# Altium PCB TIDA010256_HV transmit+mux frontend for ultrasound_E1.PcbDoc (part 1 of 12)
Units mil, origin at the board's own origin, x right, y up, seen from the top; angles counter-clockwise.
Board outline 6192.49 x 6712.23 mil, 16 copper layers (Top Layer, Layer 2 - GND, Layer 3 - SIG, Layer 4 - GND, Layer 5 - SIG, Layer 6 - SIG, Layer 7 - GND, Layer 8 - HV PWR, Layer 9 - LV PWR, Layer 10 - GND, Layer 11 - SIG, Layer 12 - SIG, Layer 13 - GND, Layer 14 - SIG, Layer 15 - GND, Bottom Layer), stack 95.905 mil thick; 806 components, 539 nets, 3343 pads, 1848 vias.

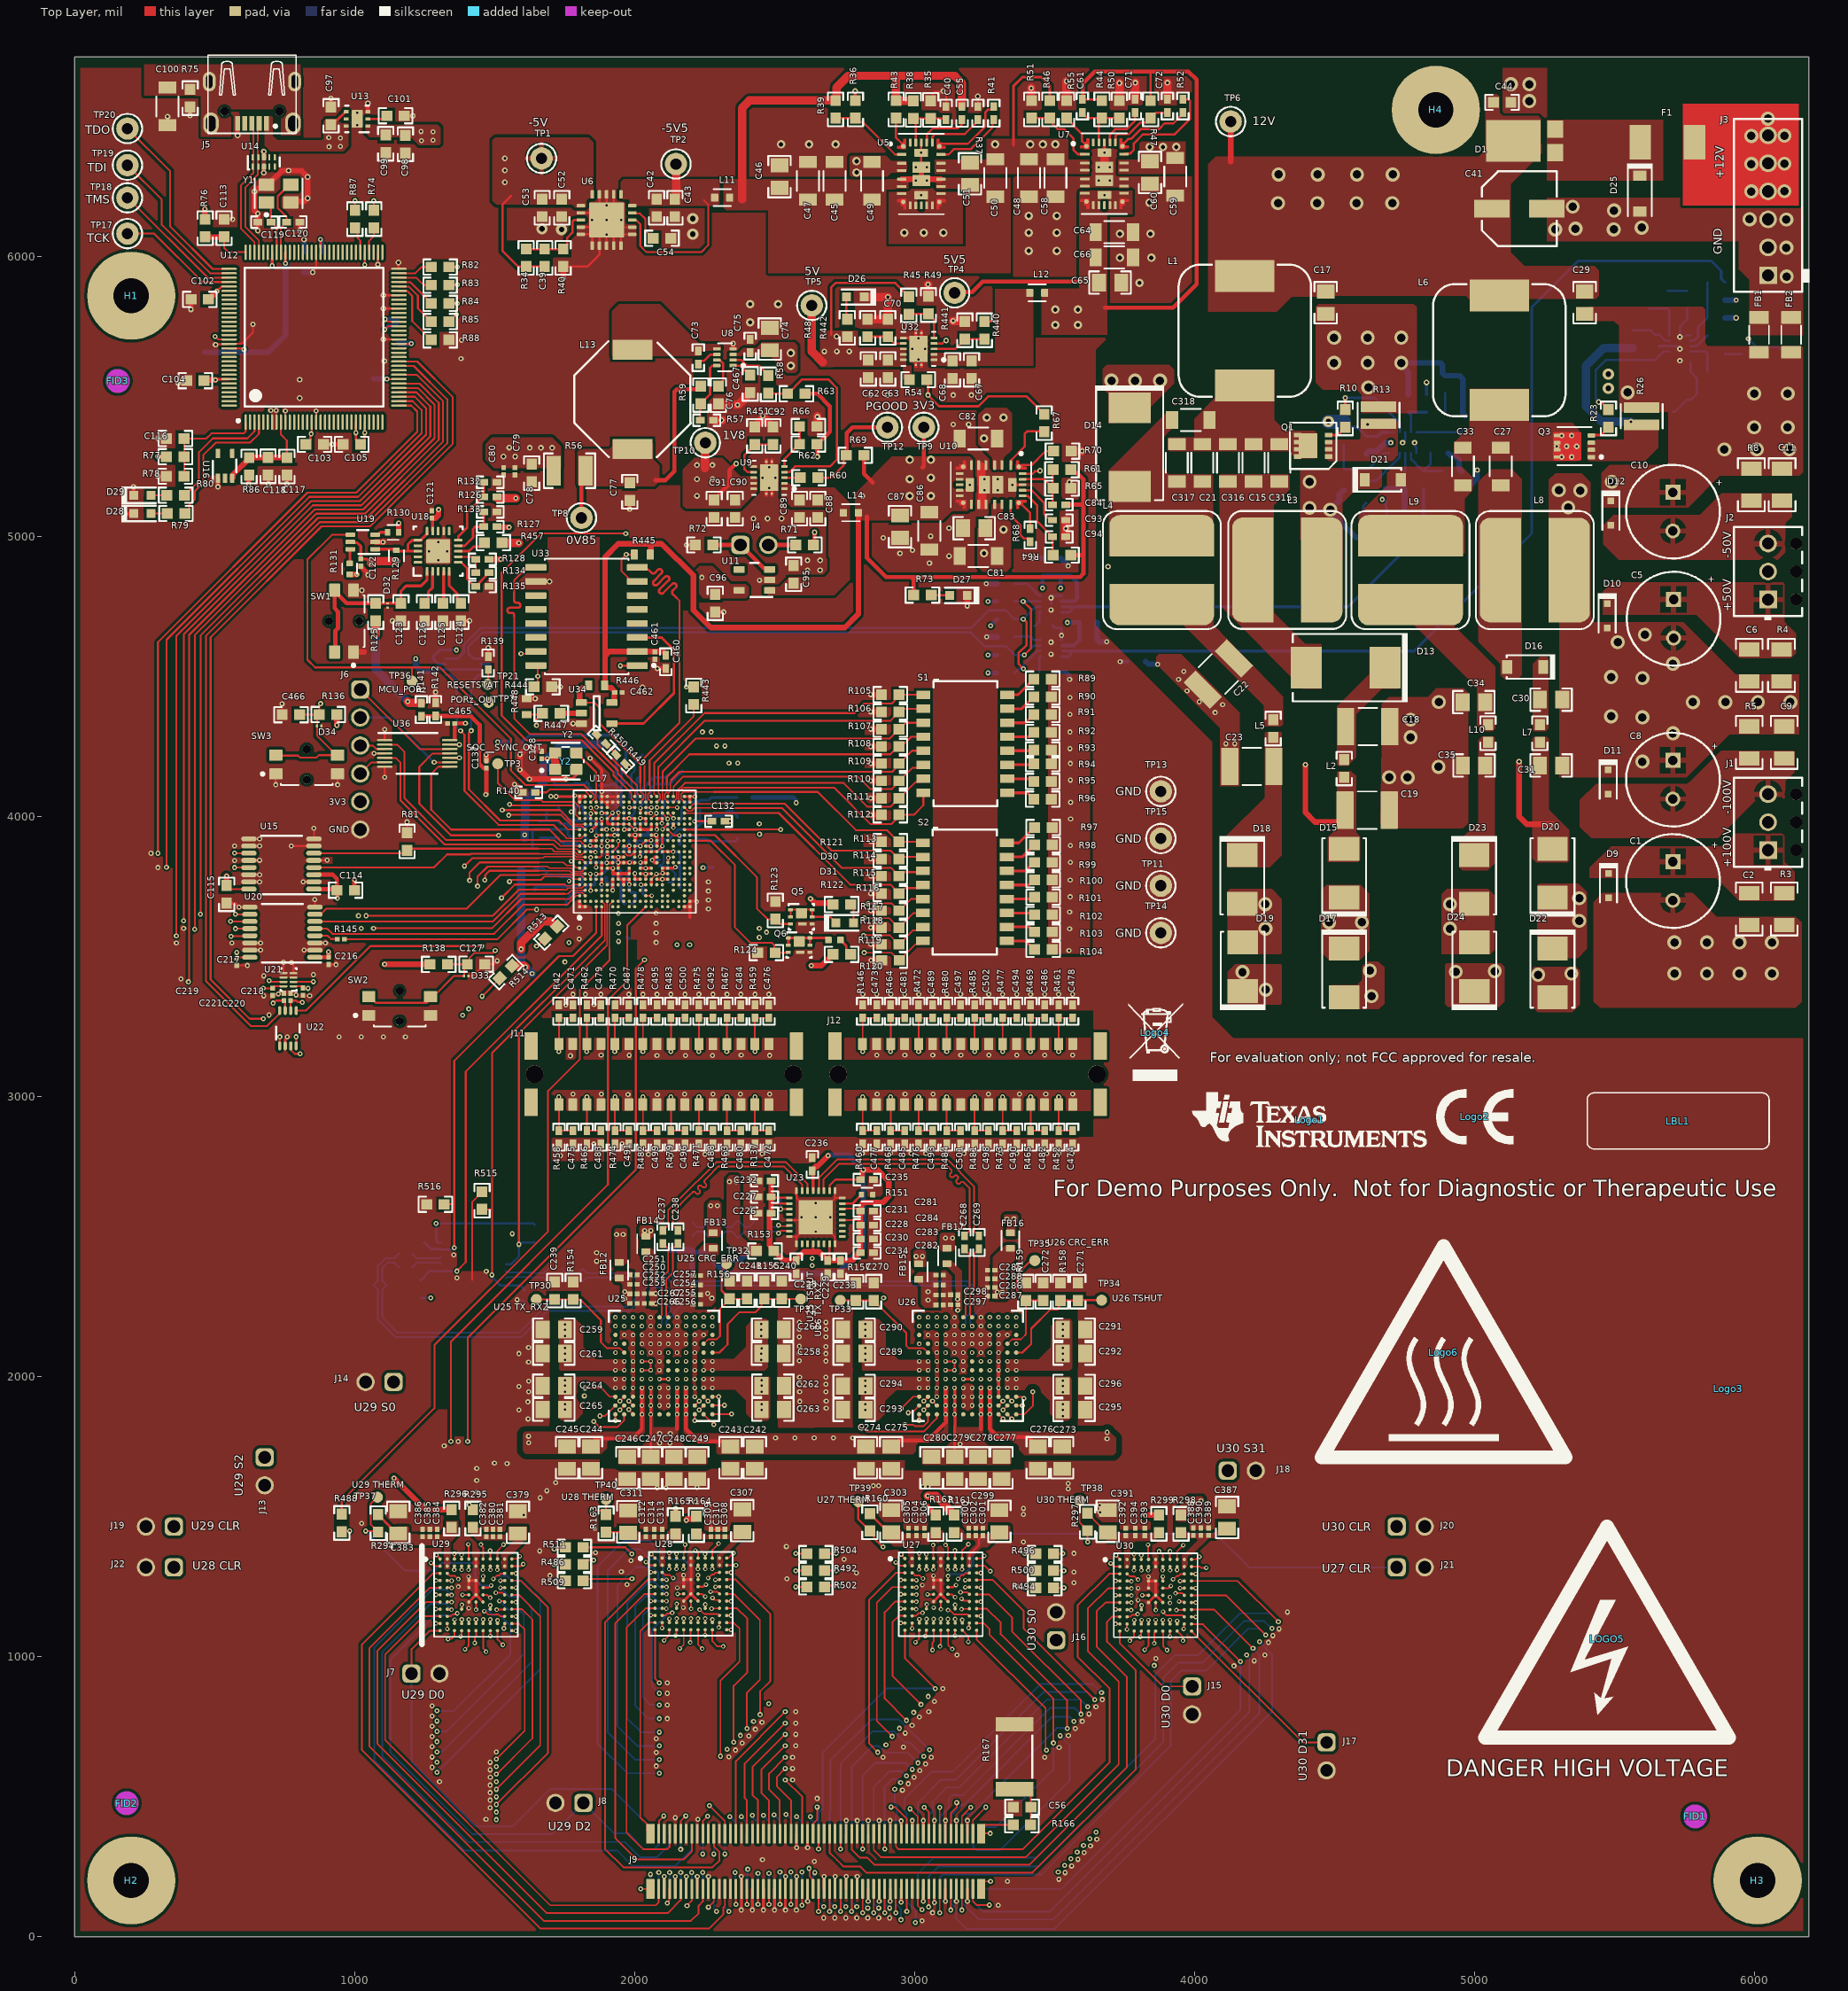
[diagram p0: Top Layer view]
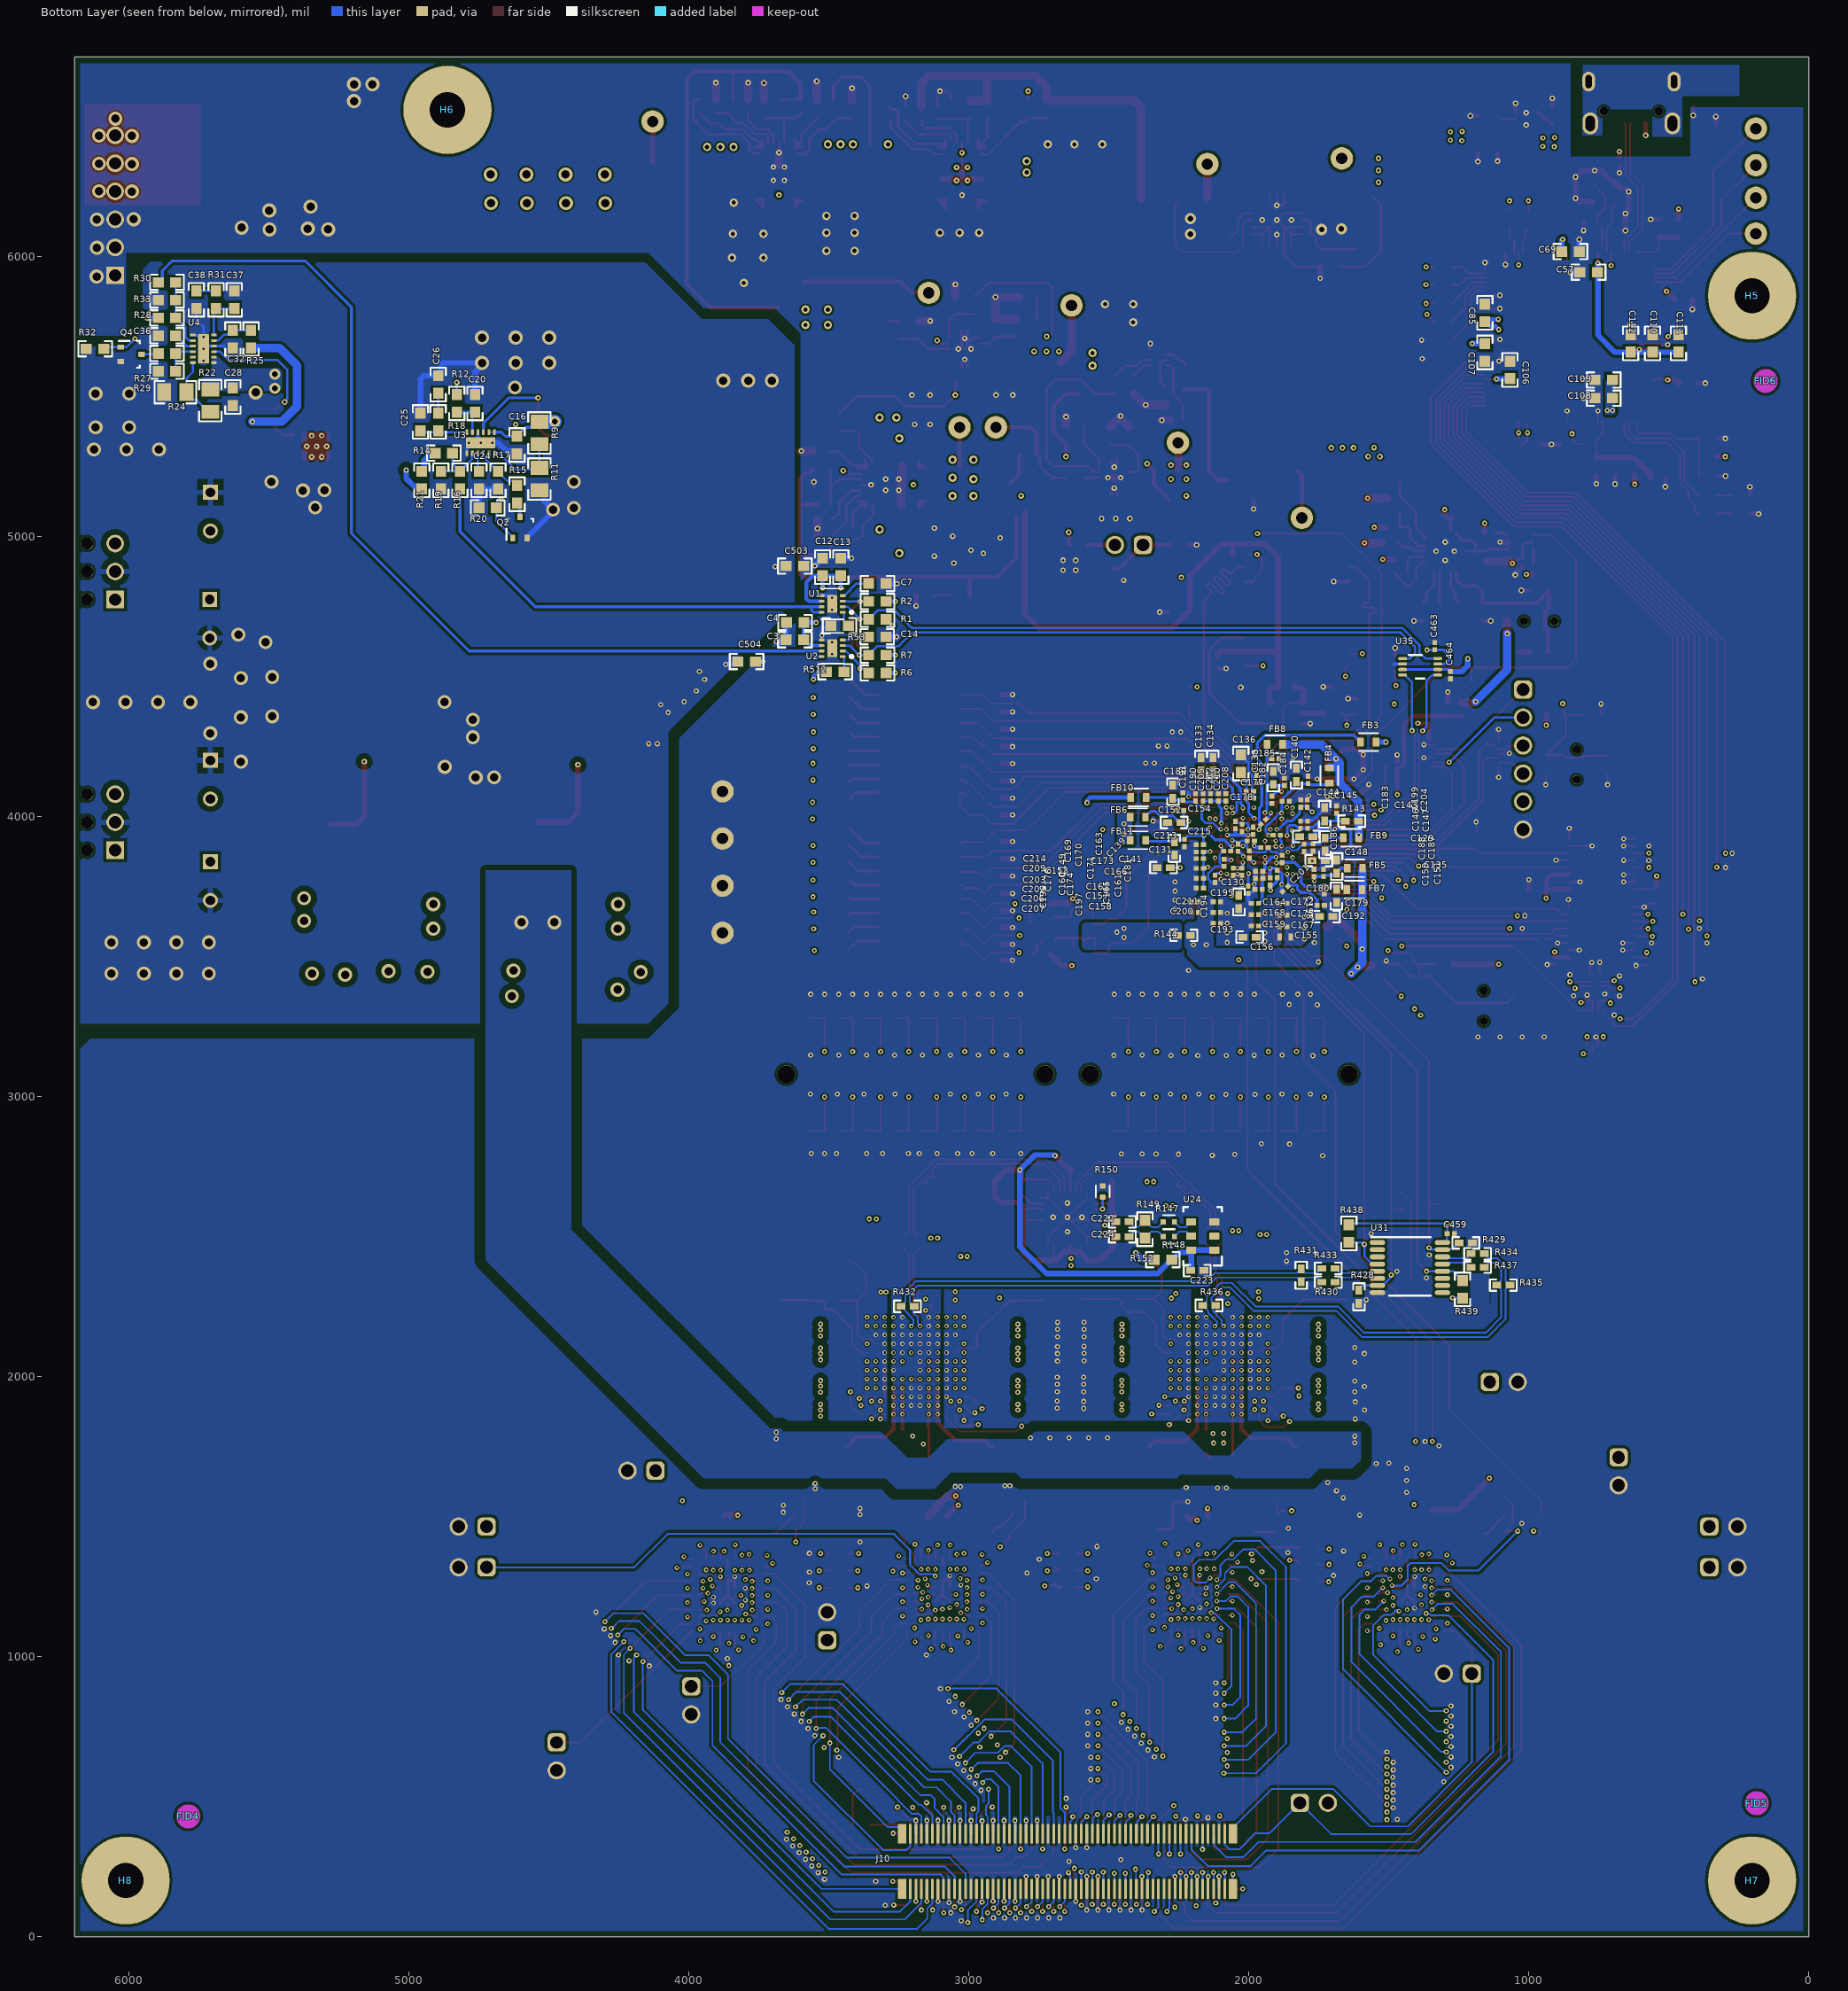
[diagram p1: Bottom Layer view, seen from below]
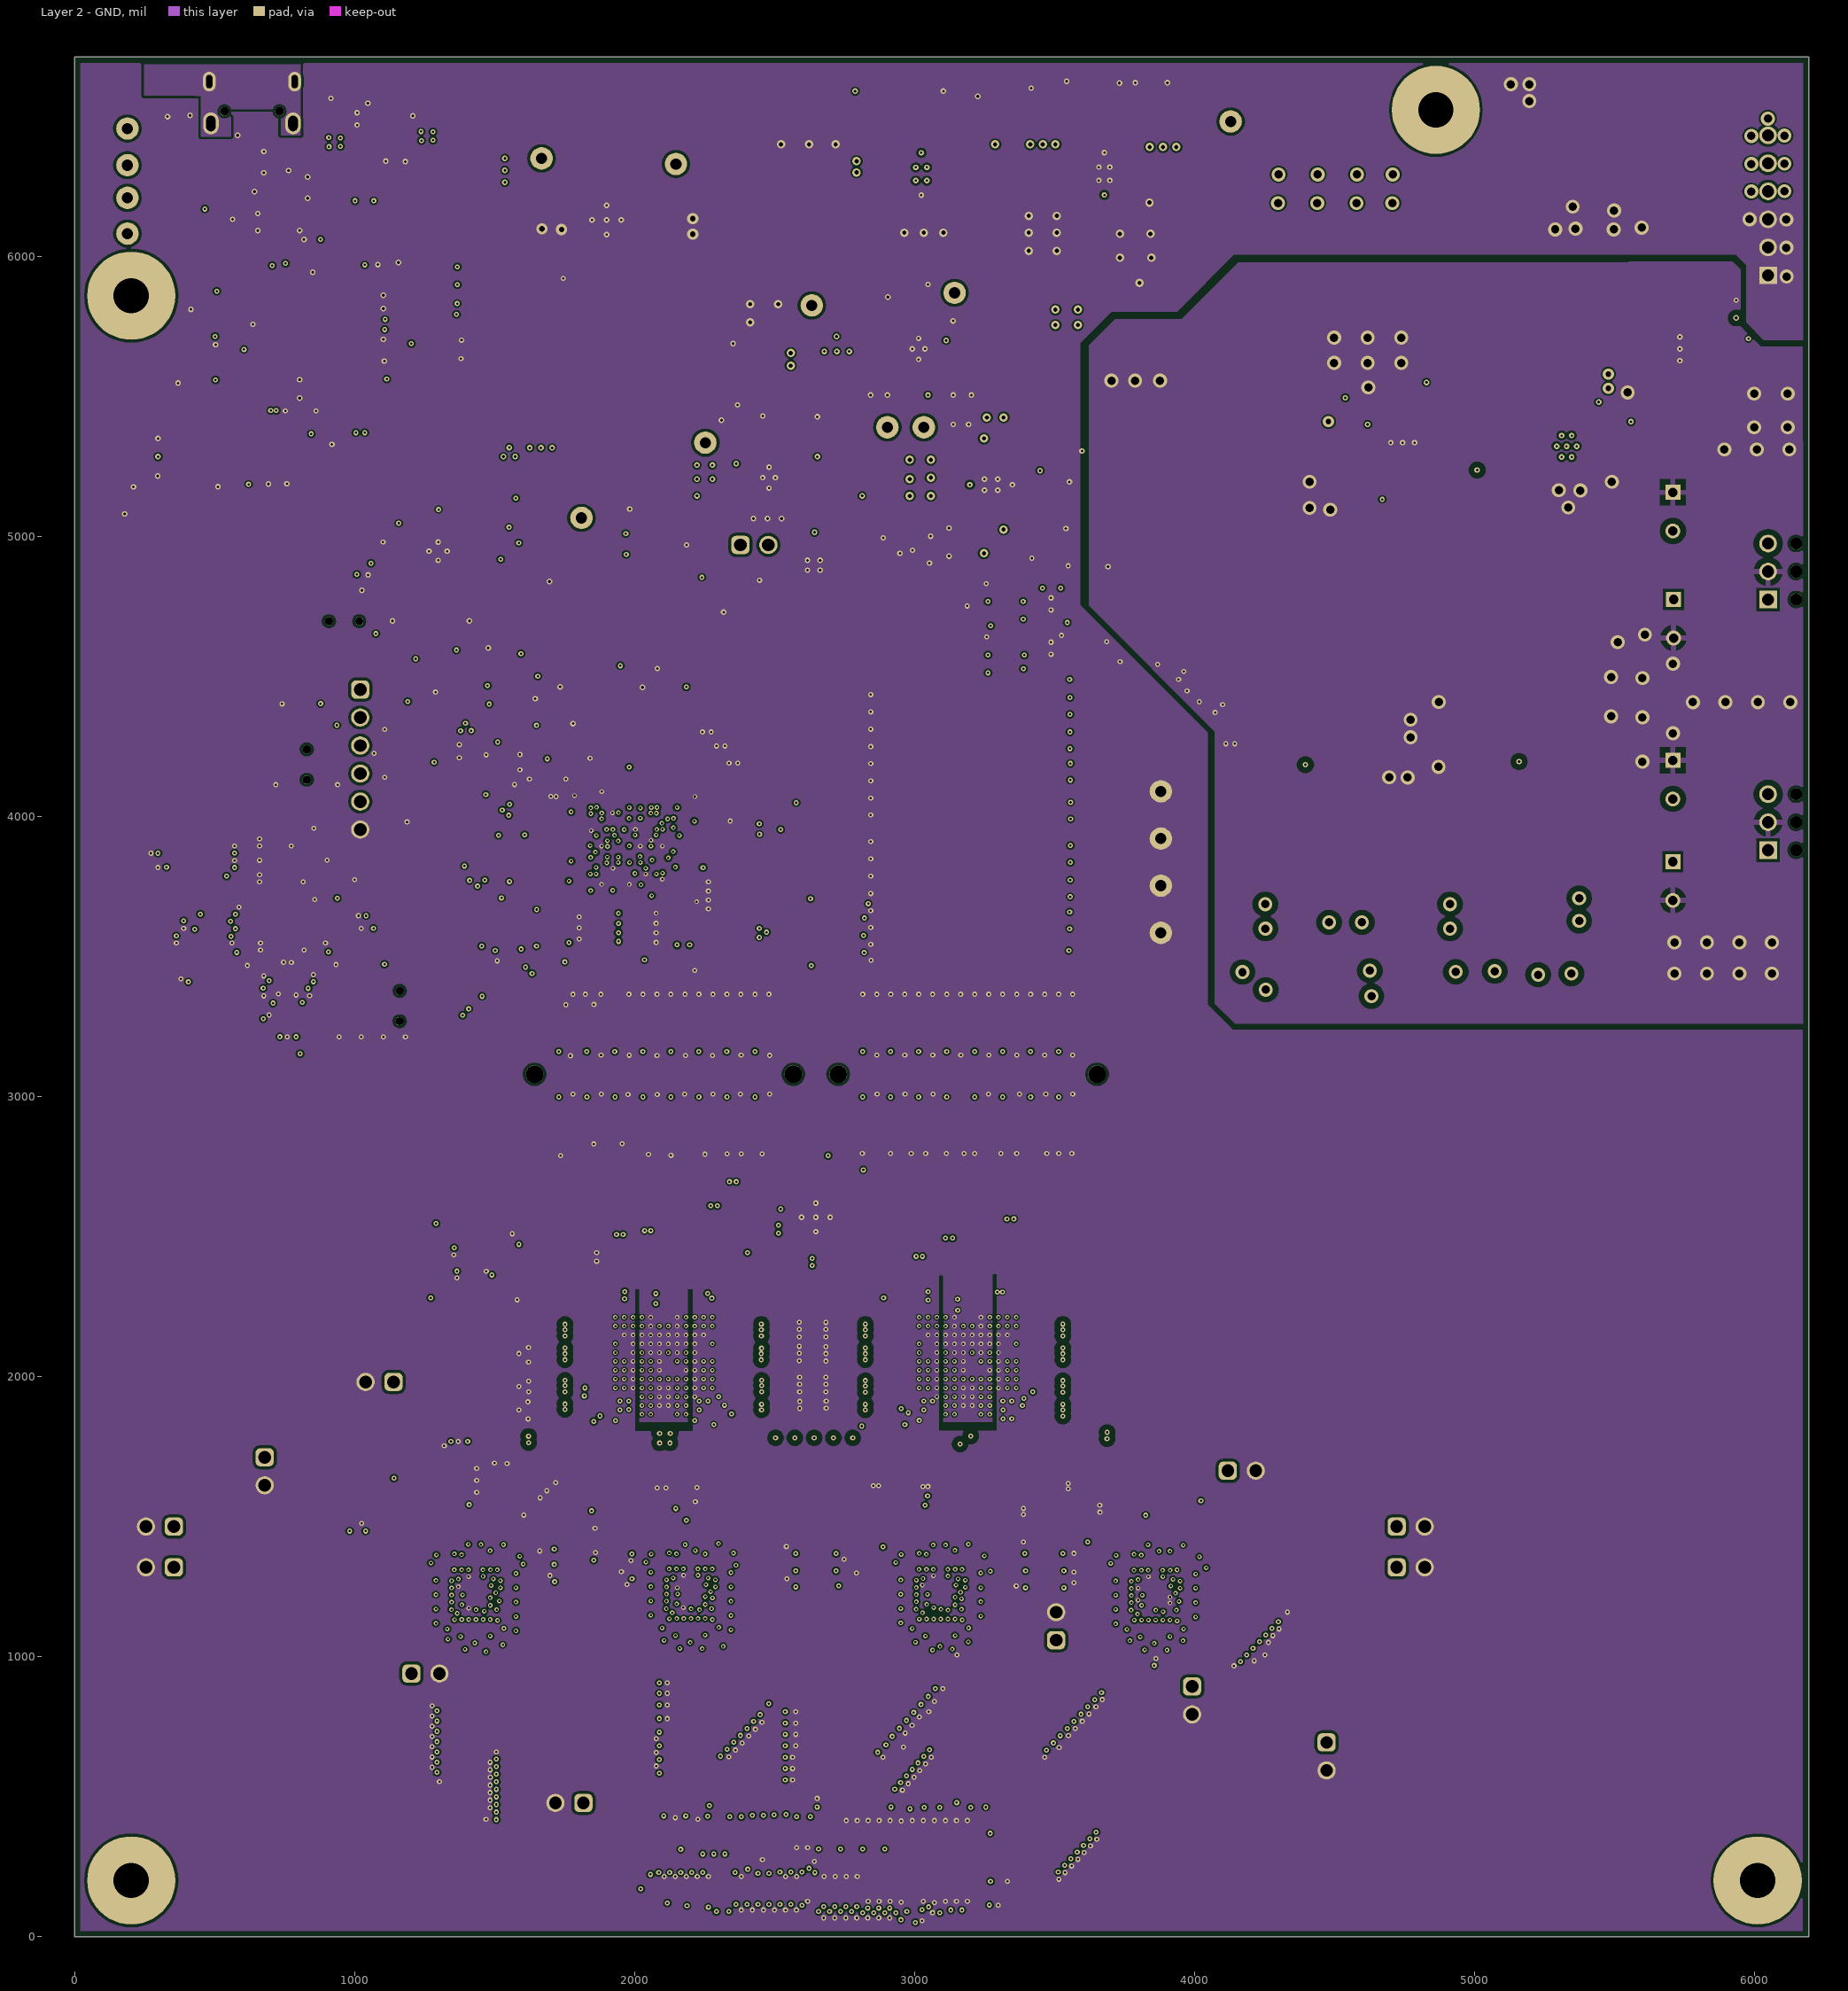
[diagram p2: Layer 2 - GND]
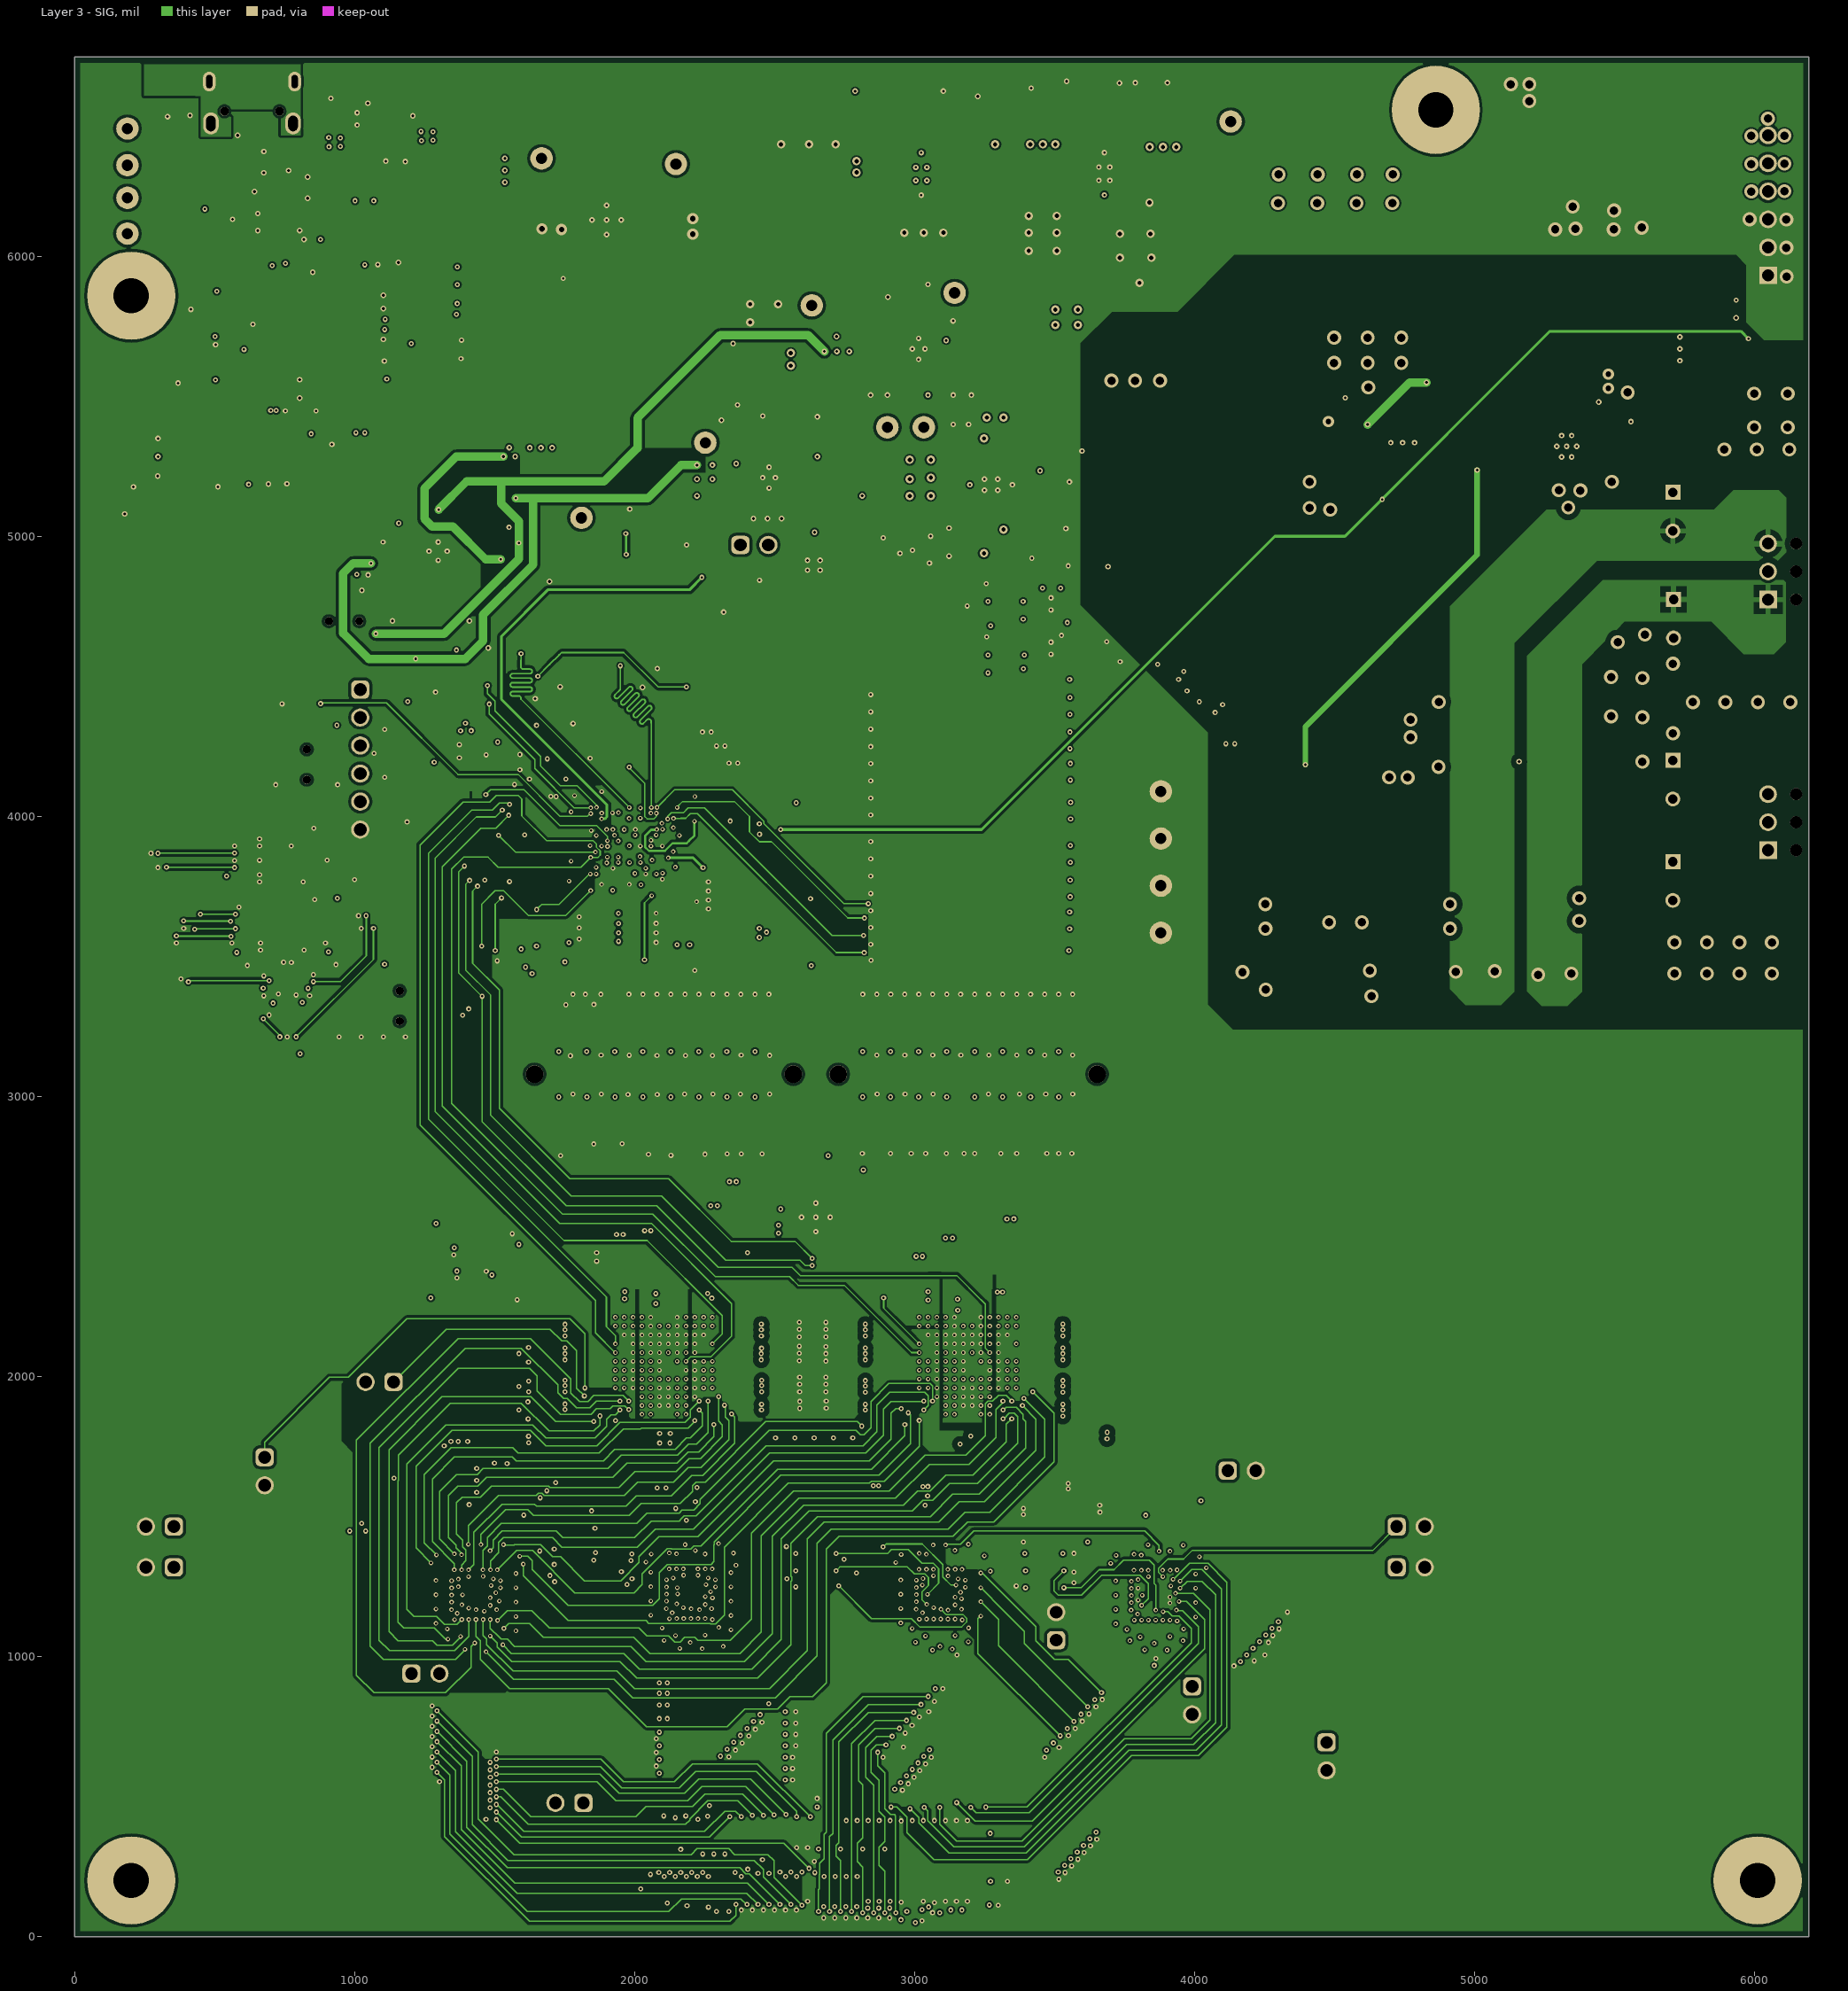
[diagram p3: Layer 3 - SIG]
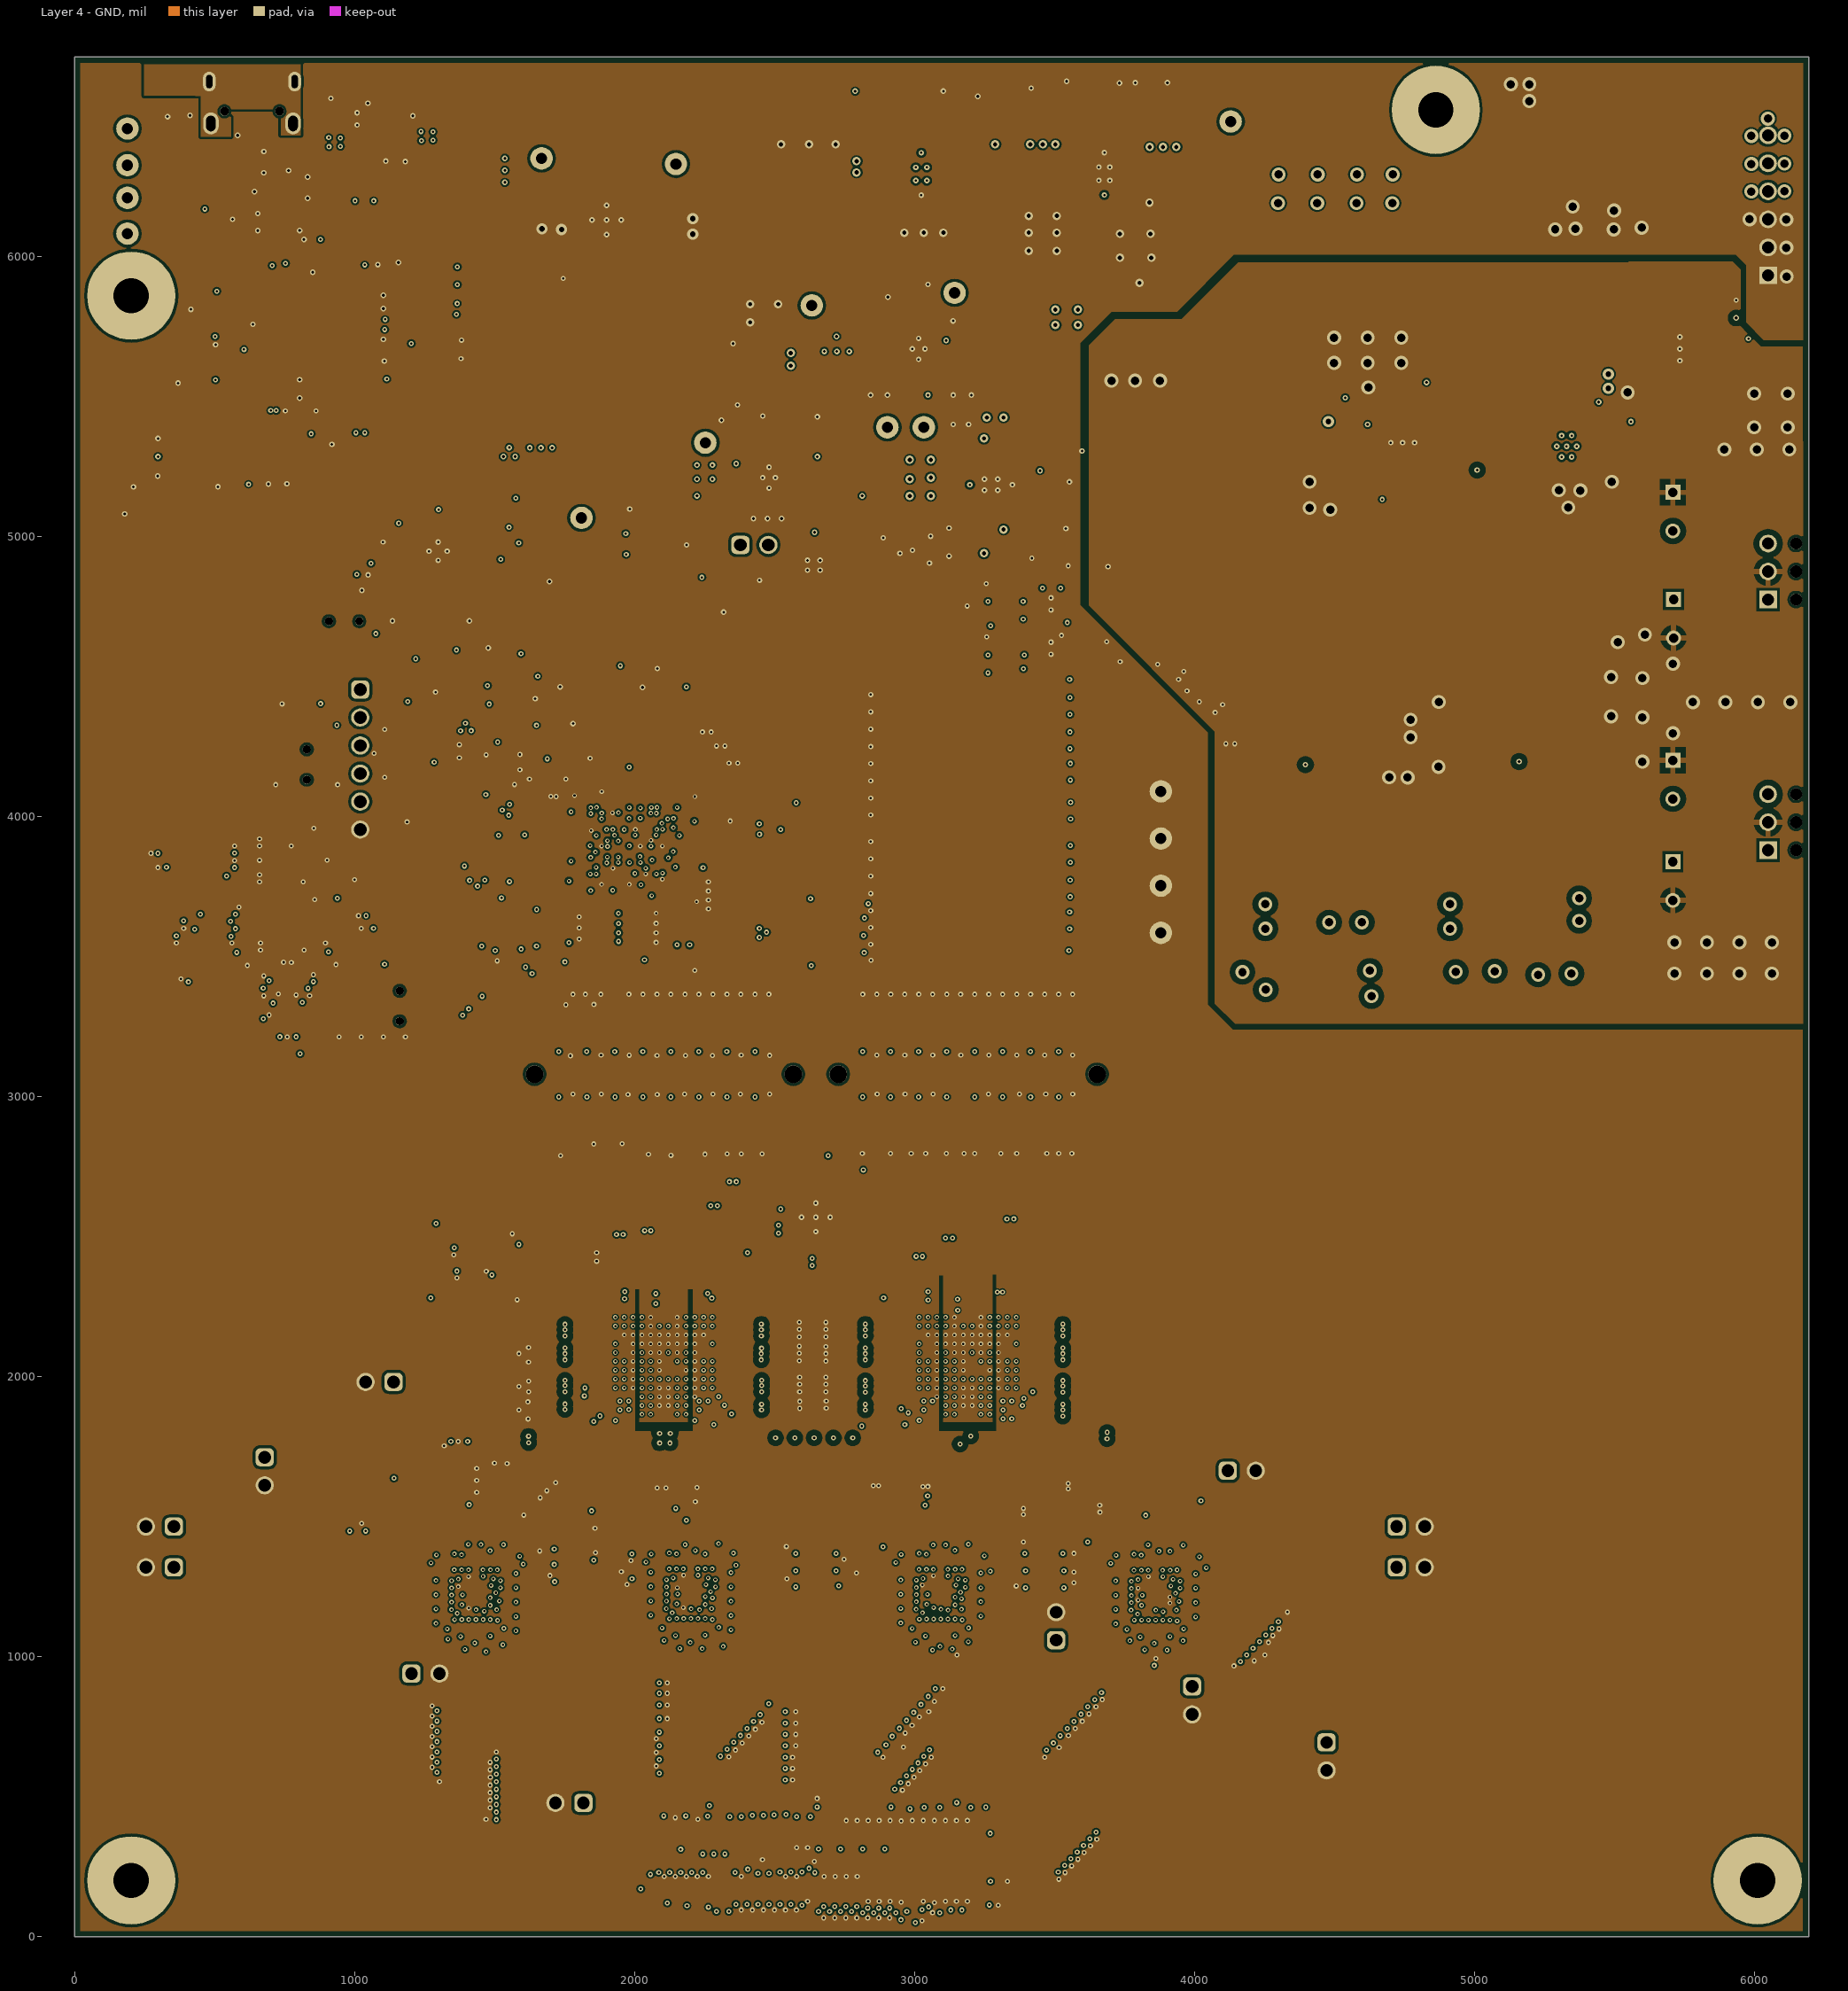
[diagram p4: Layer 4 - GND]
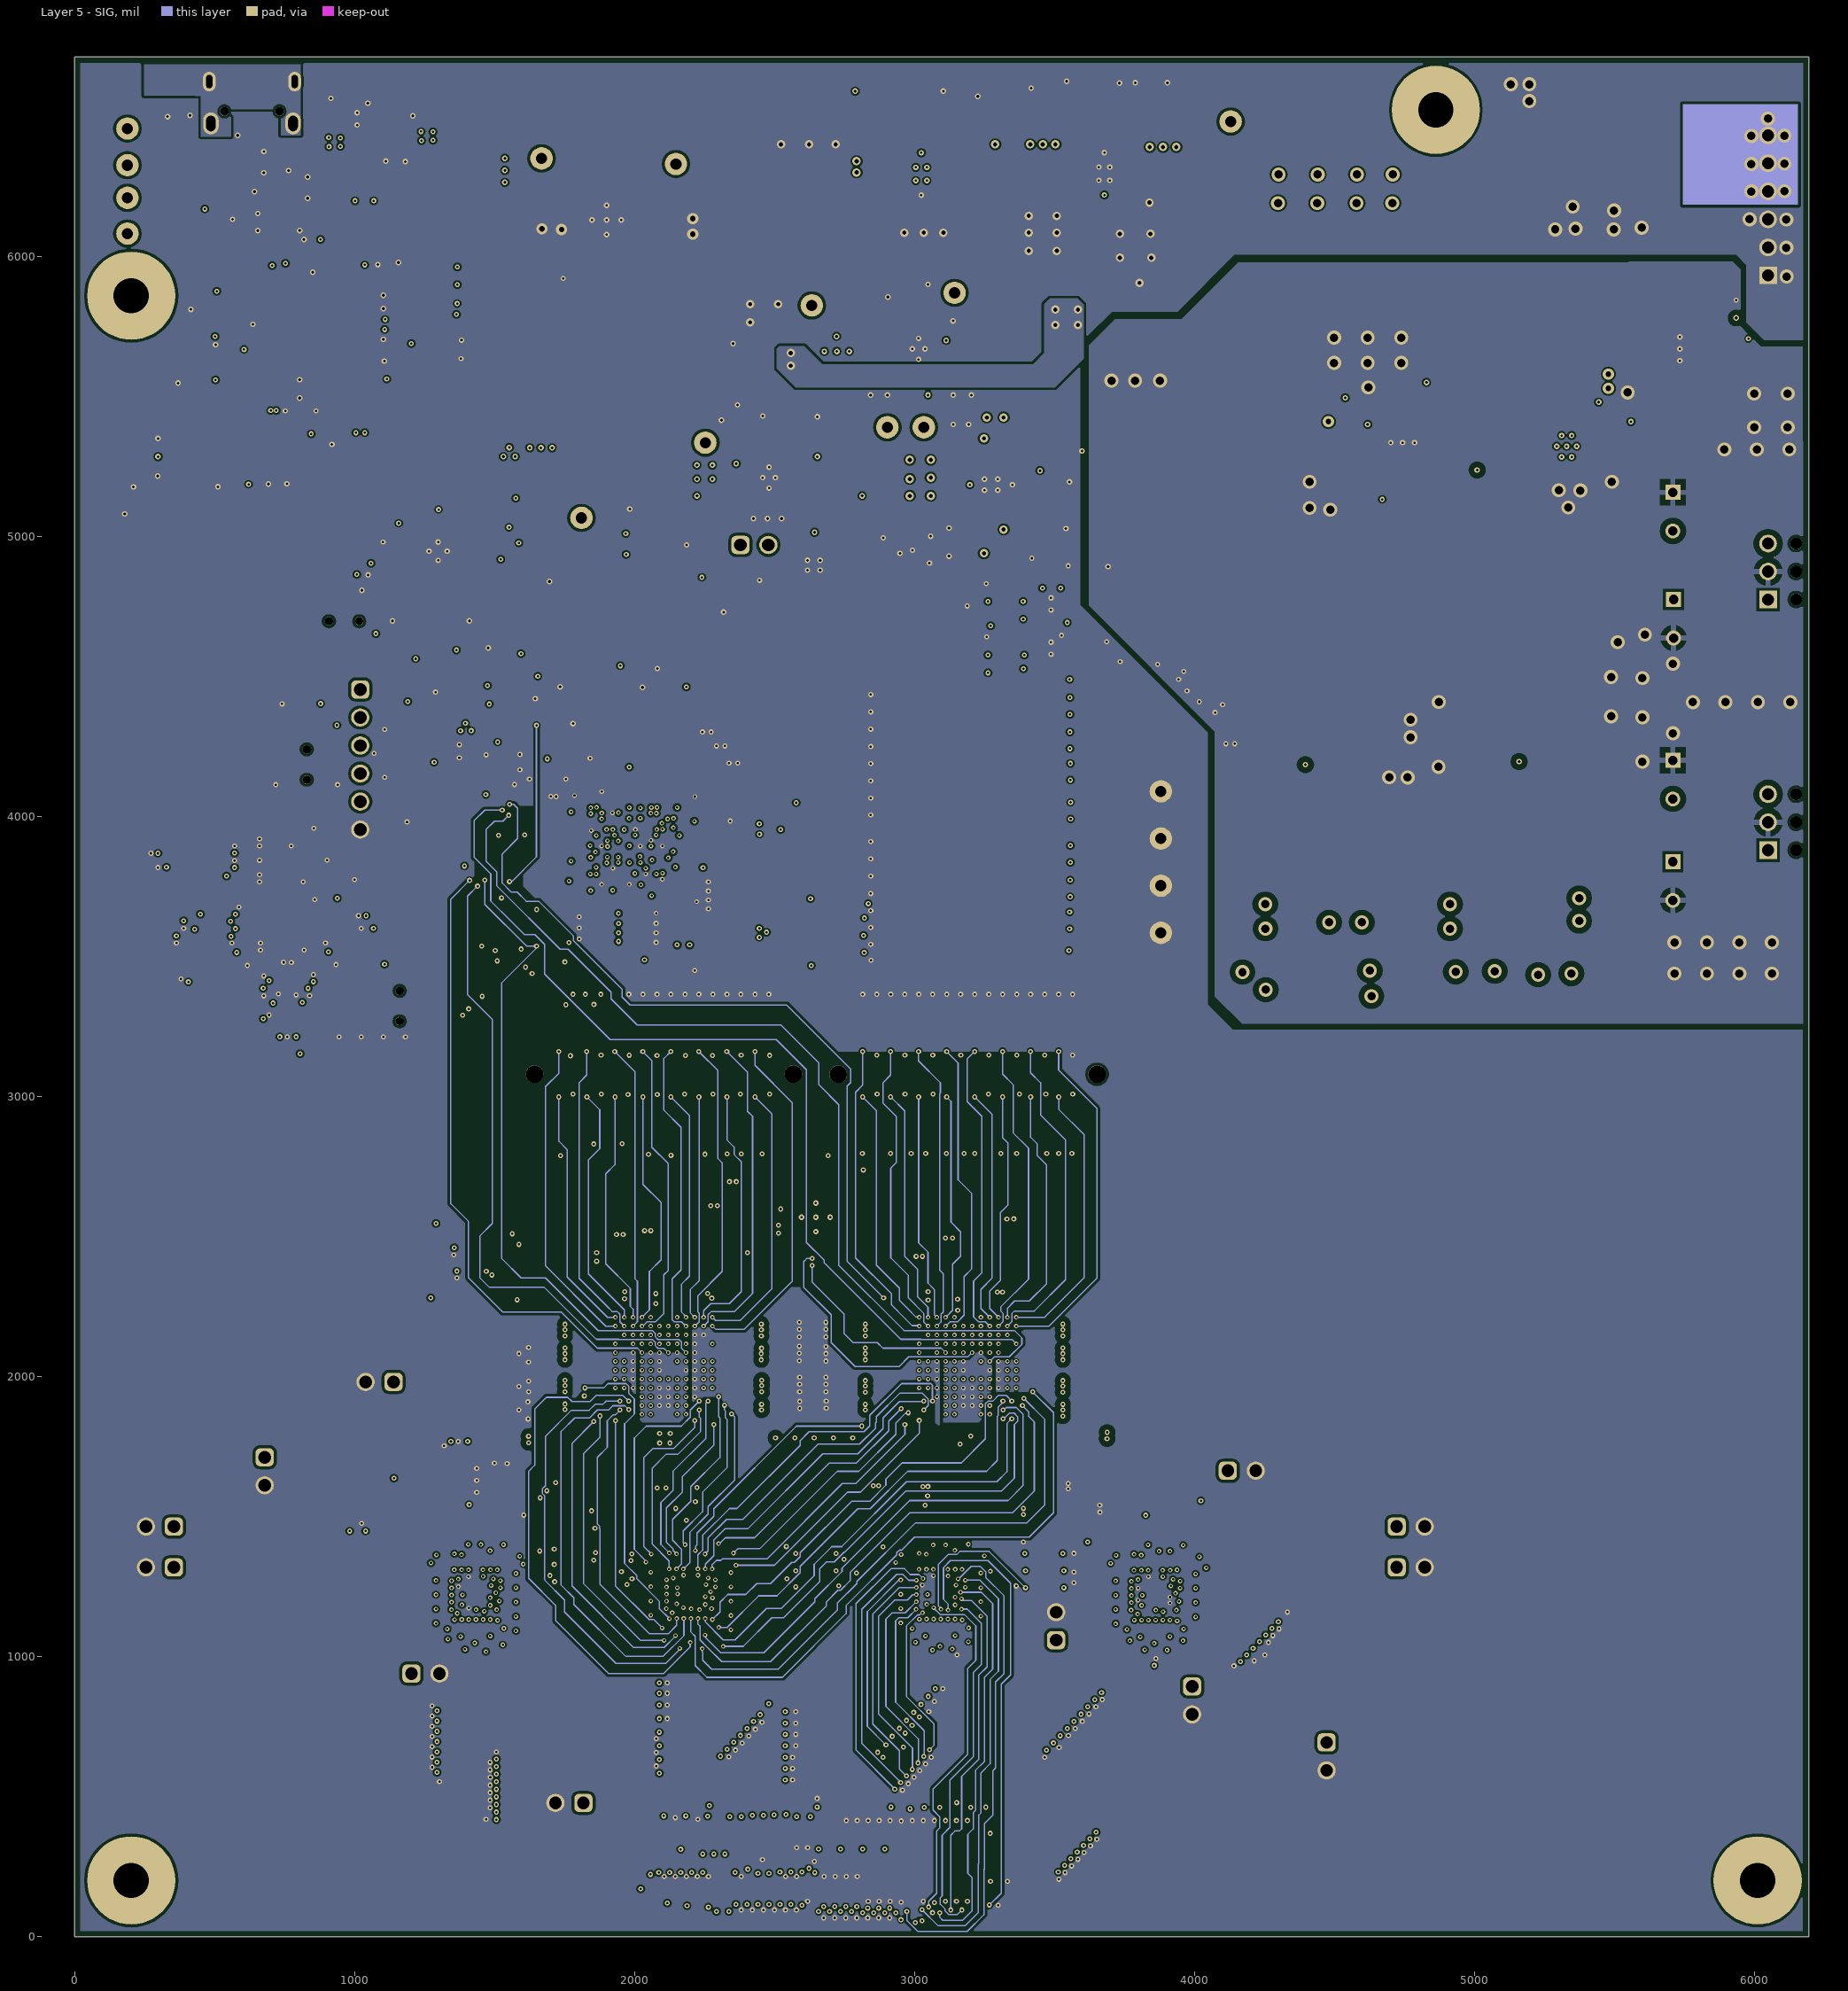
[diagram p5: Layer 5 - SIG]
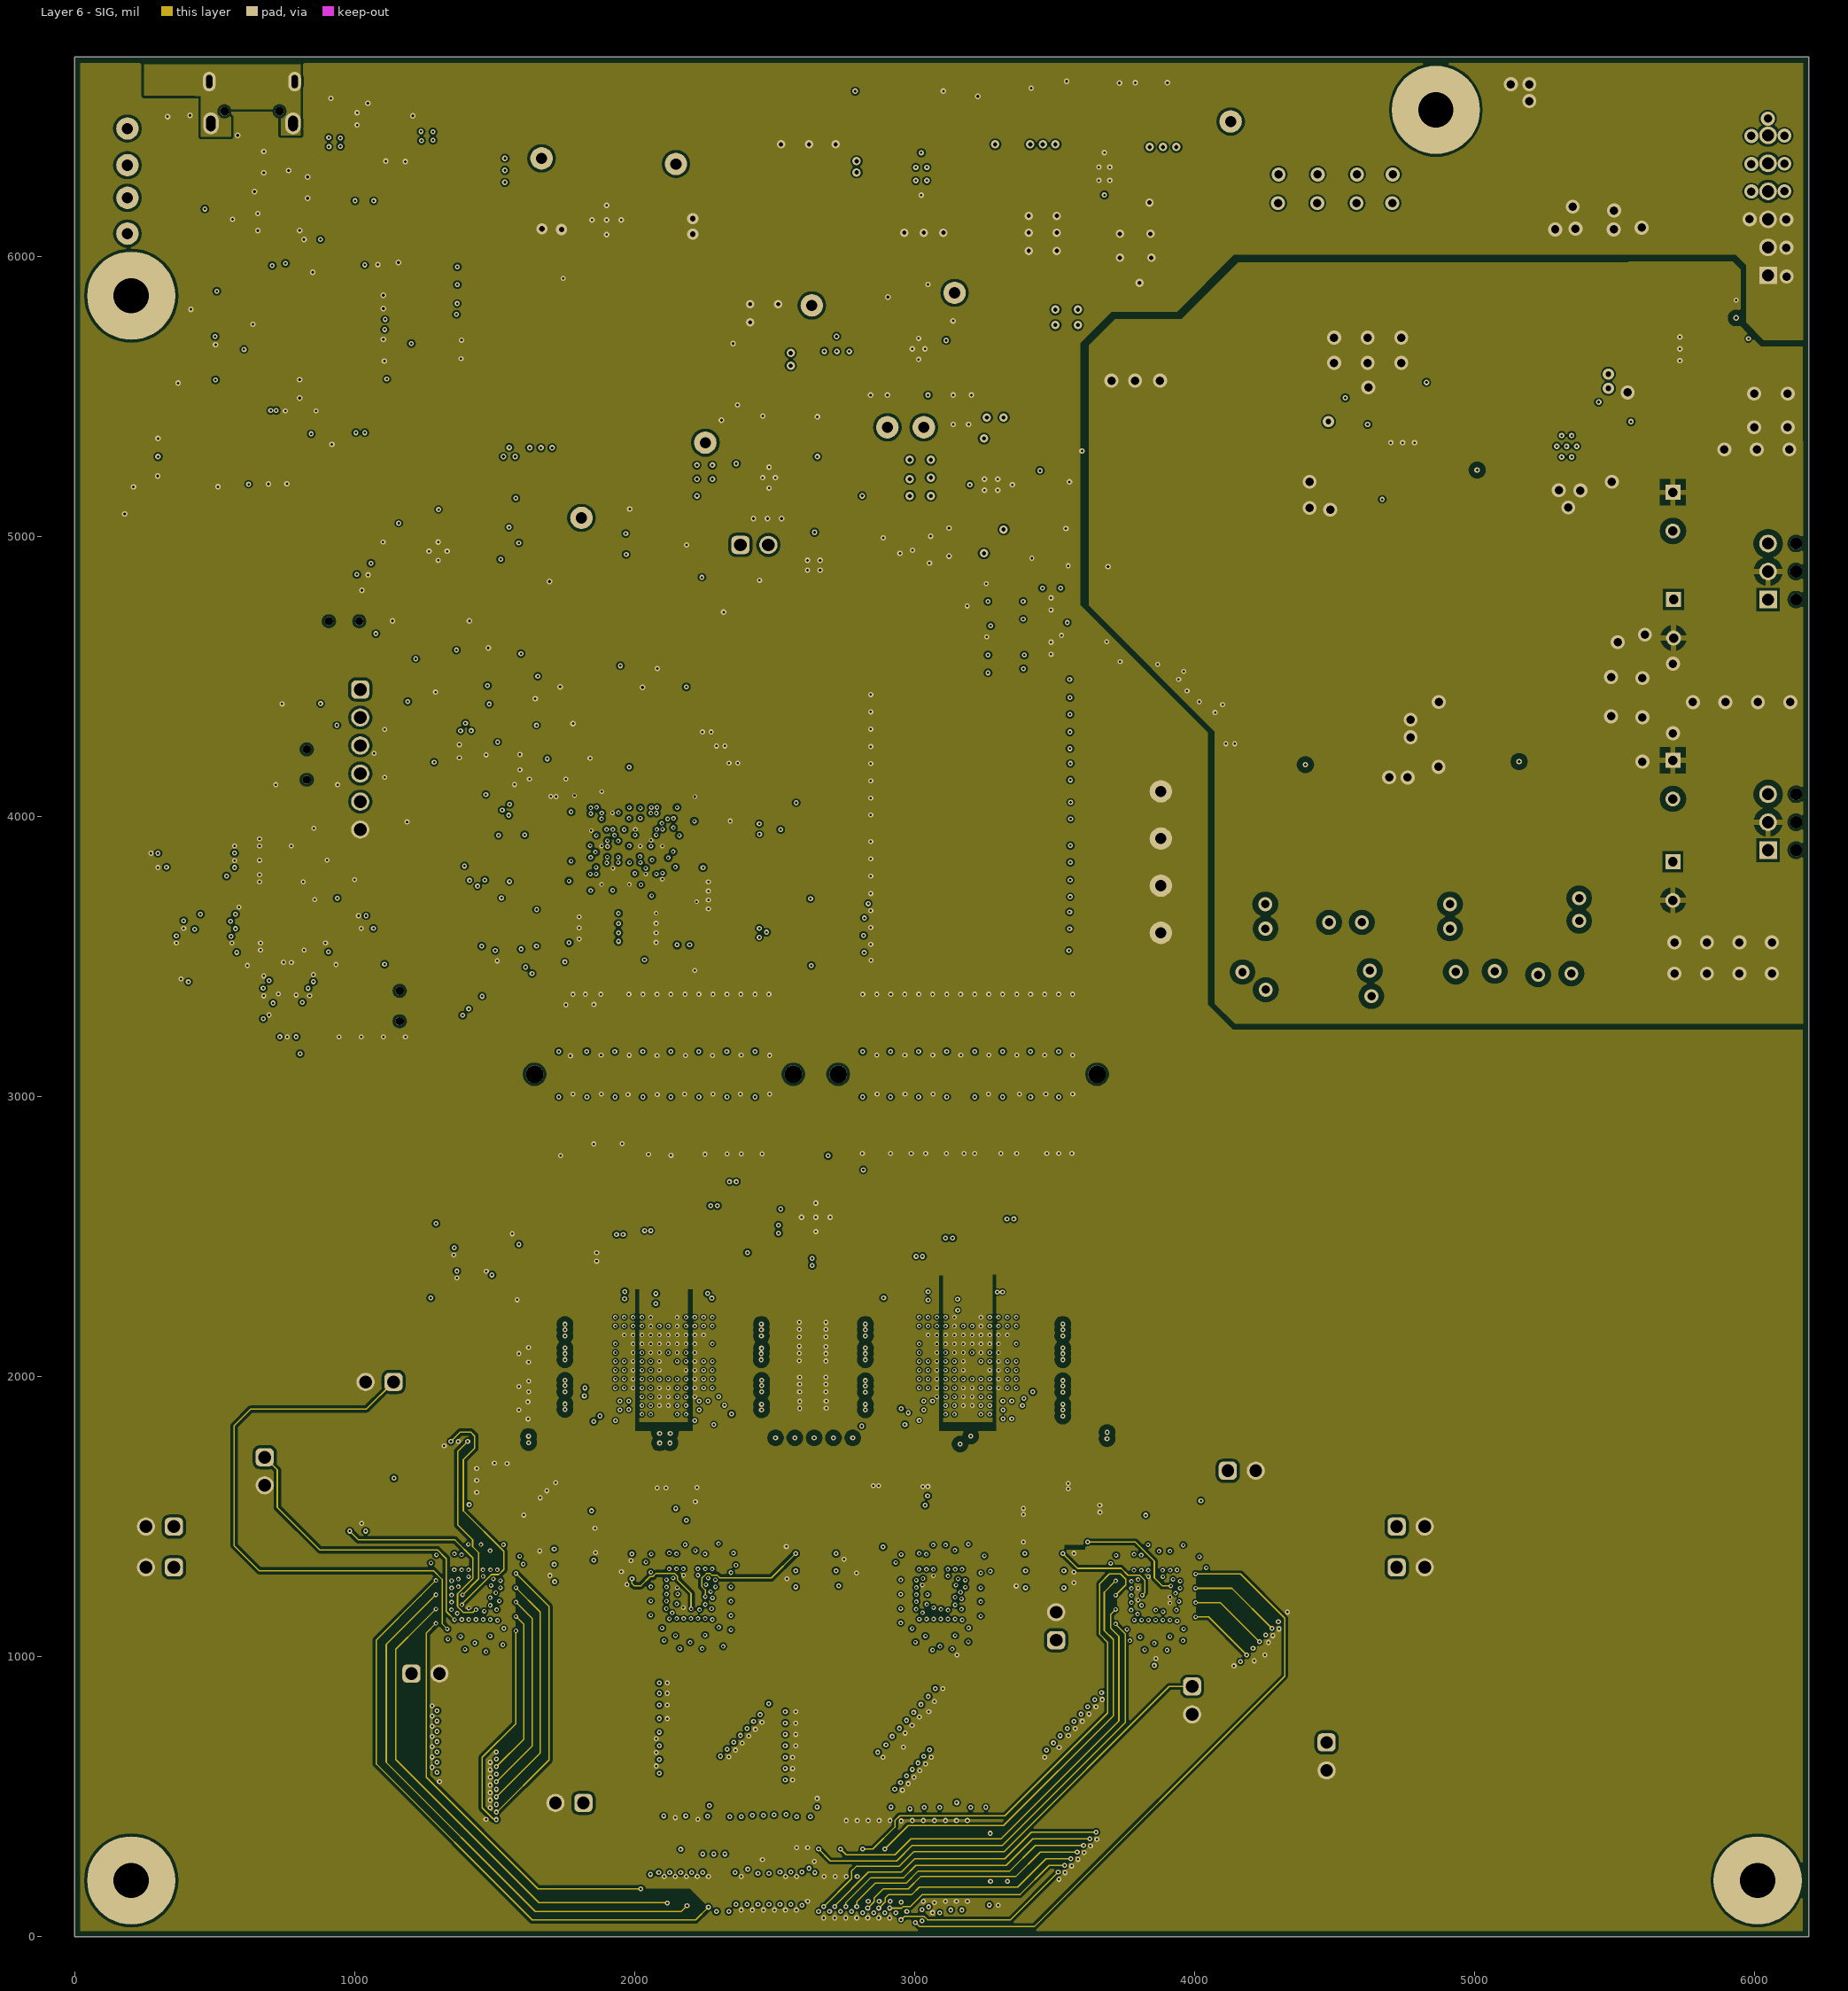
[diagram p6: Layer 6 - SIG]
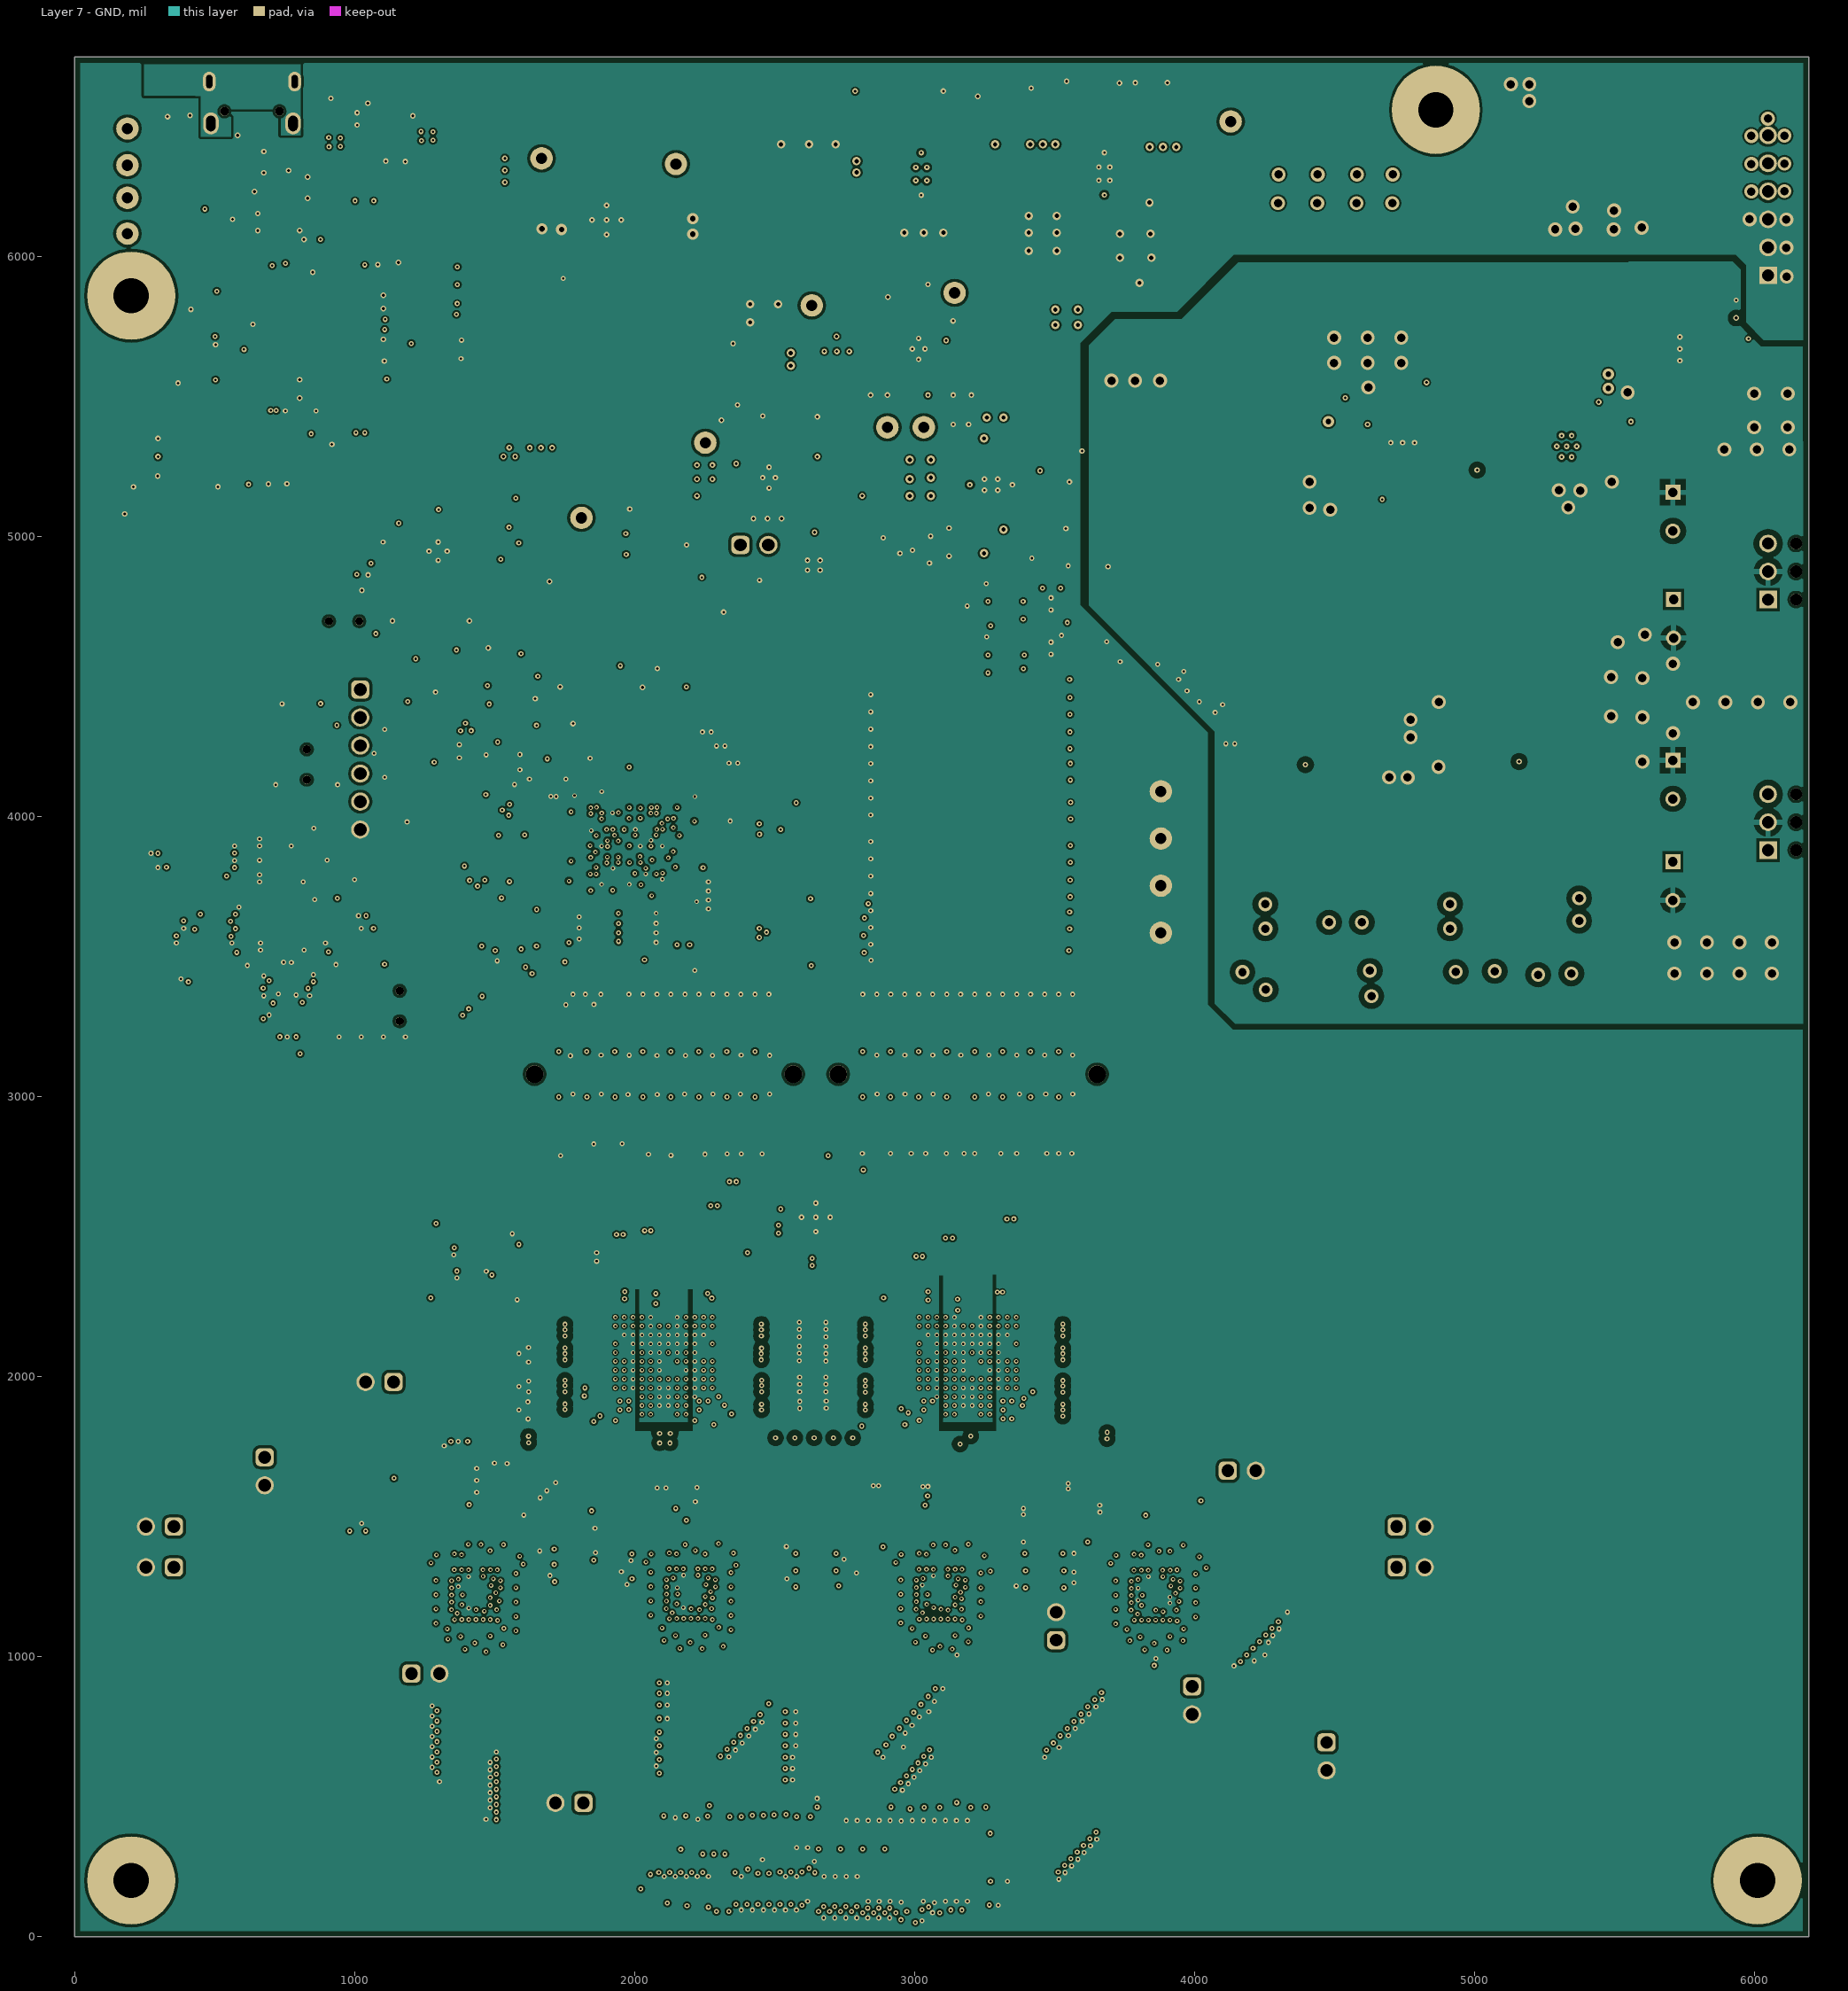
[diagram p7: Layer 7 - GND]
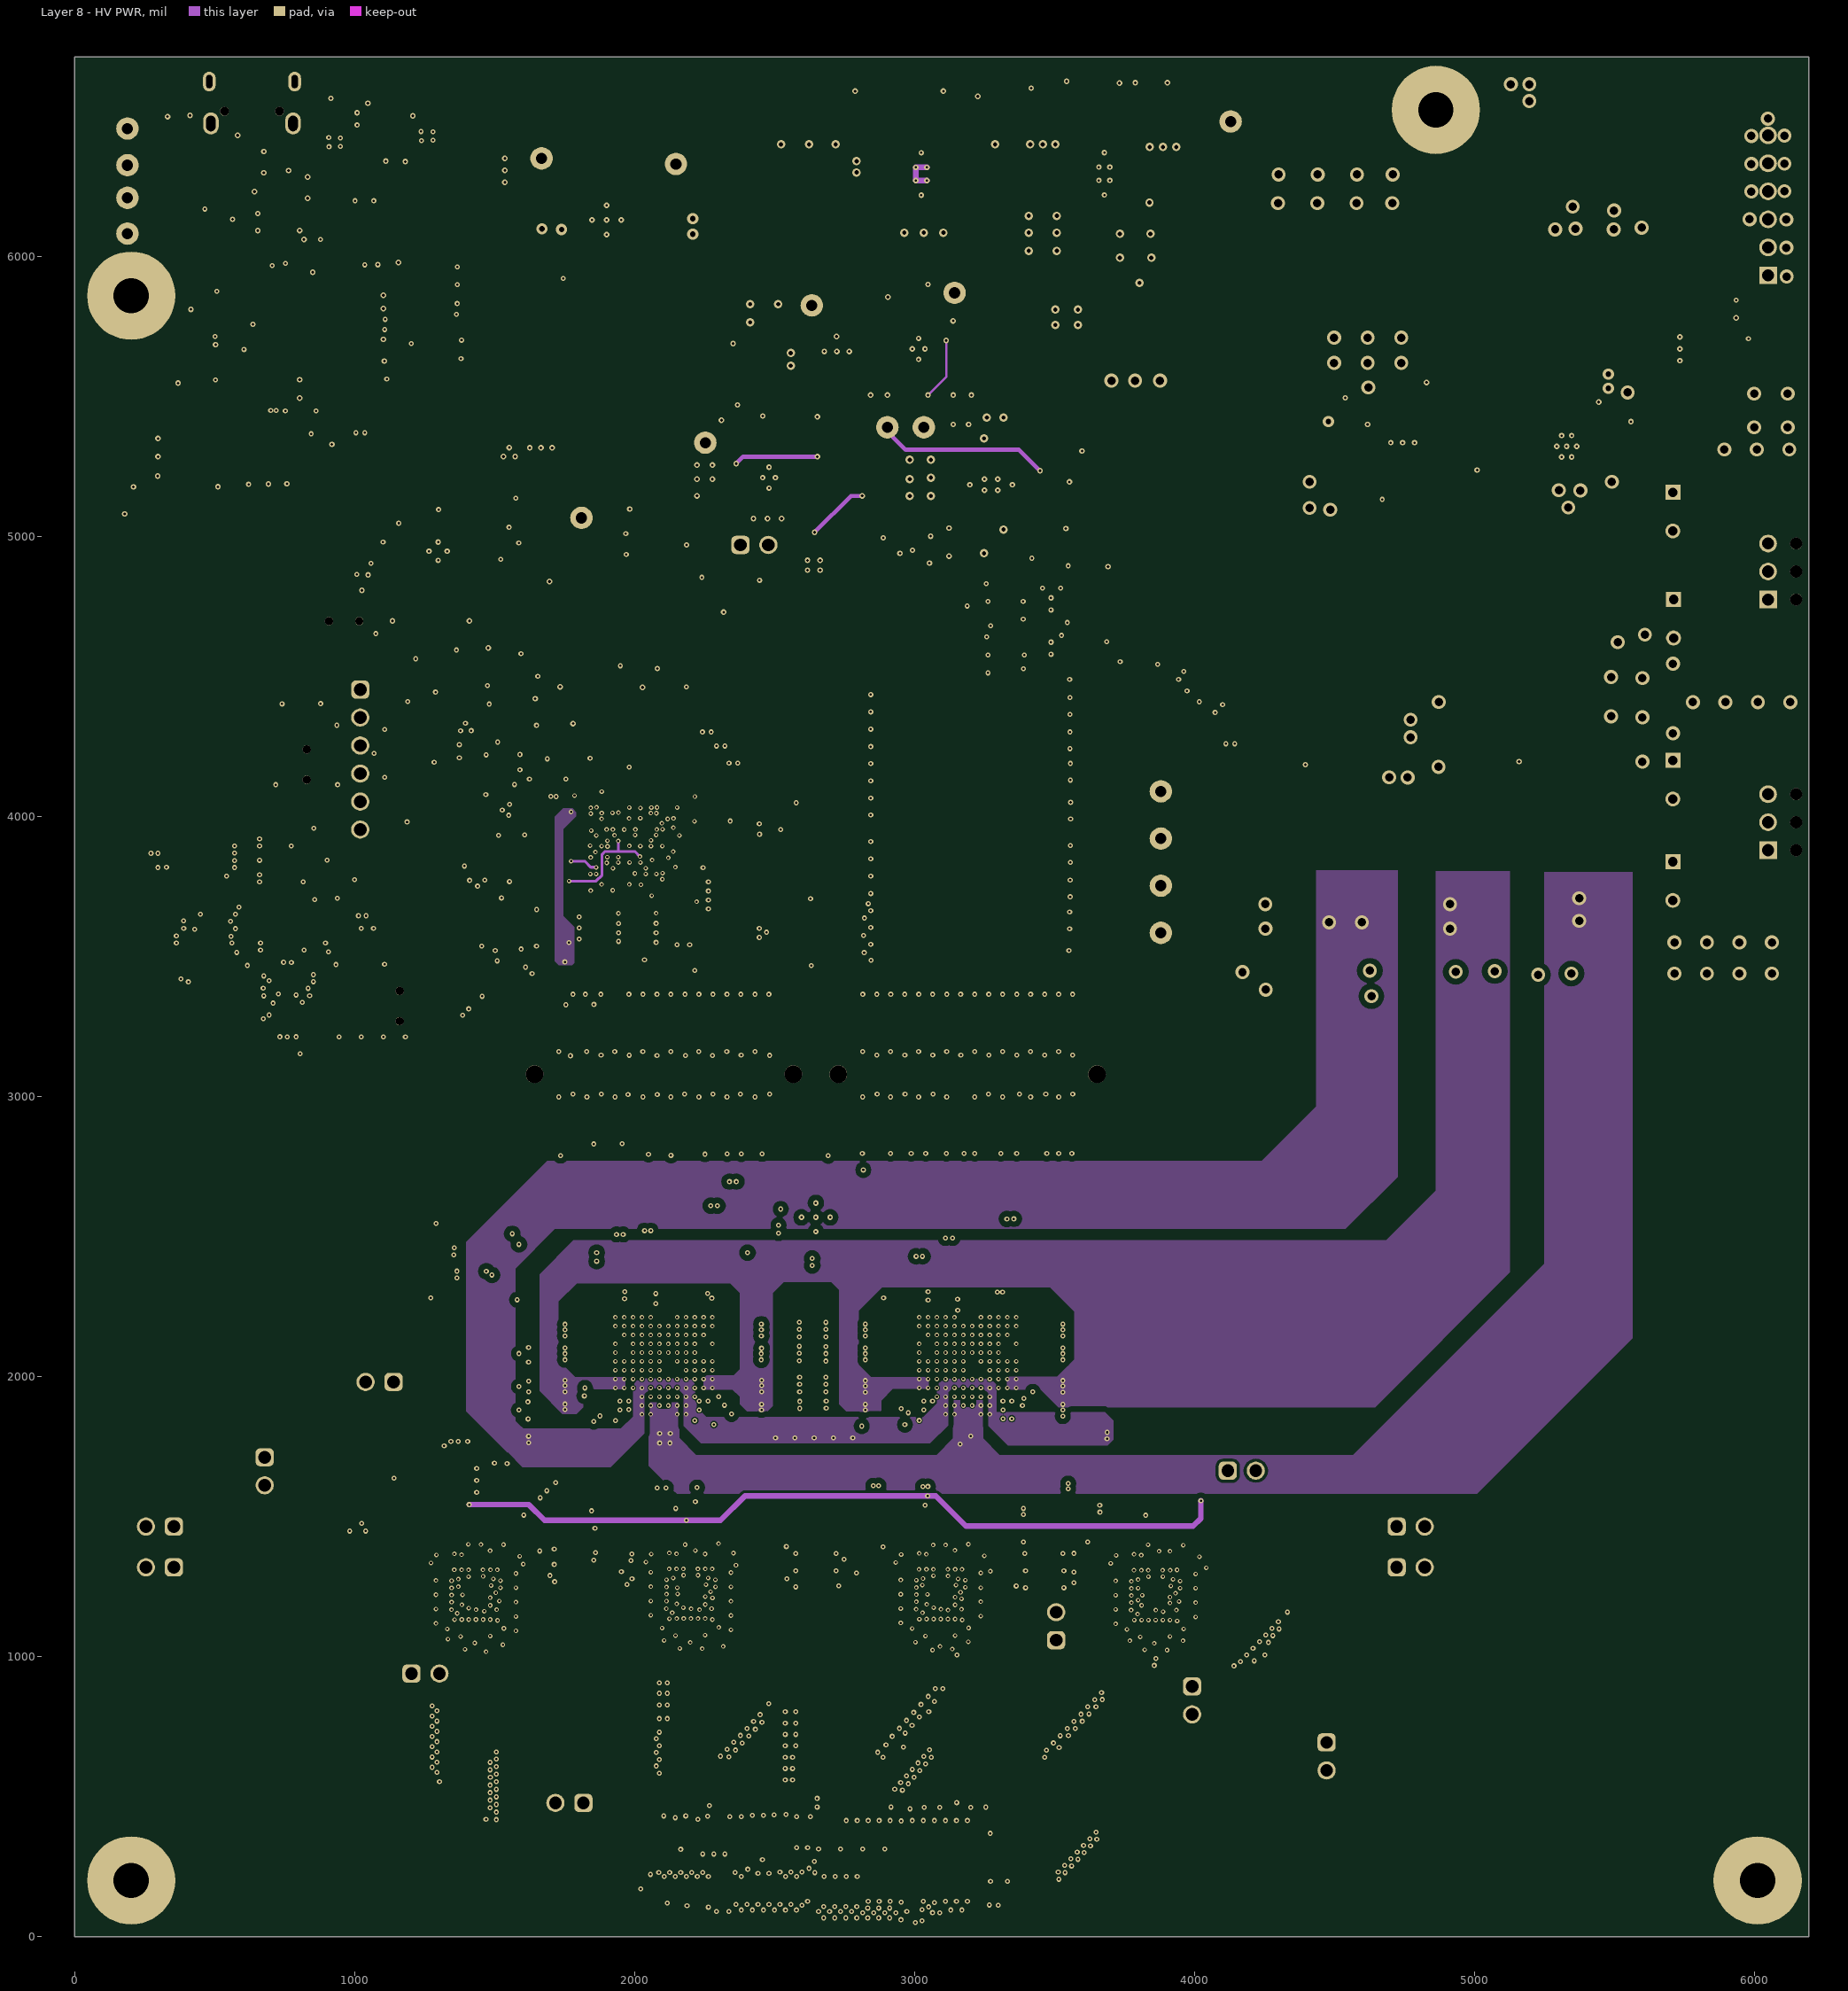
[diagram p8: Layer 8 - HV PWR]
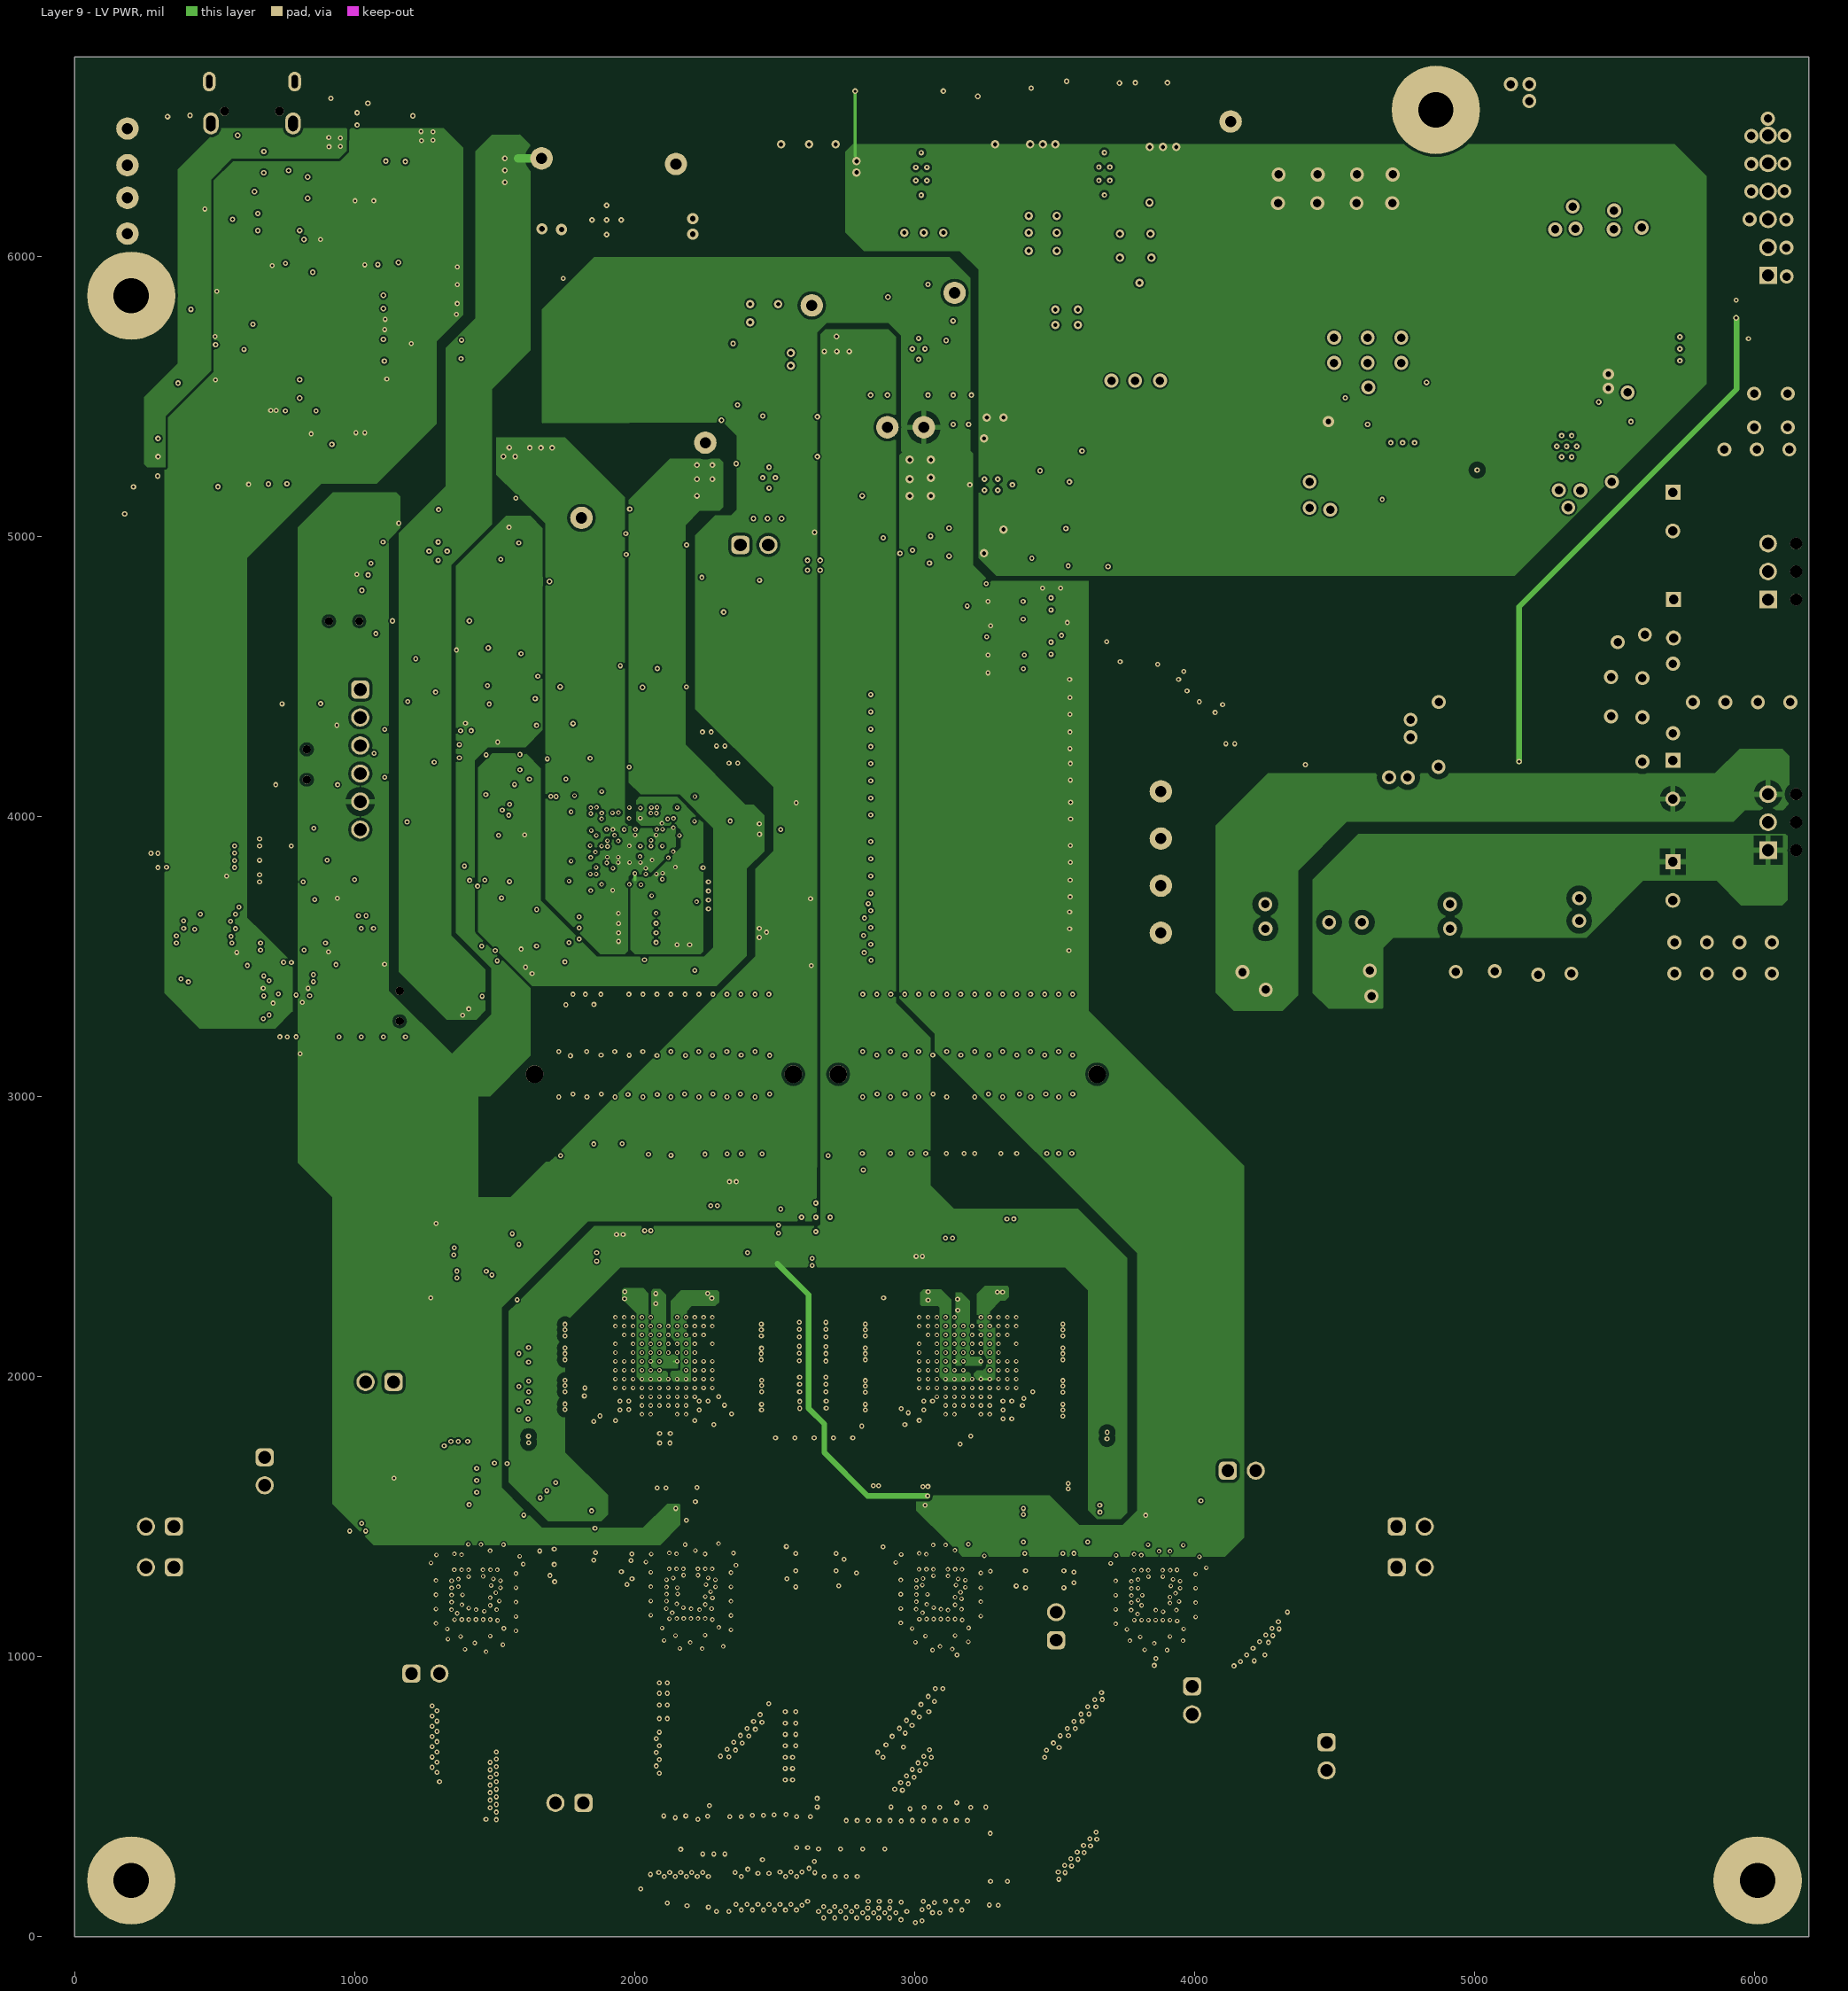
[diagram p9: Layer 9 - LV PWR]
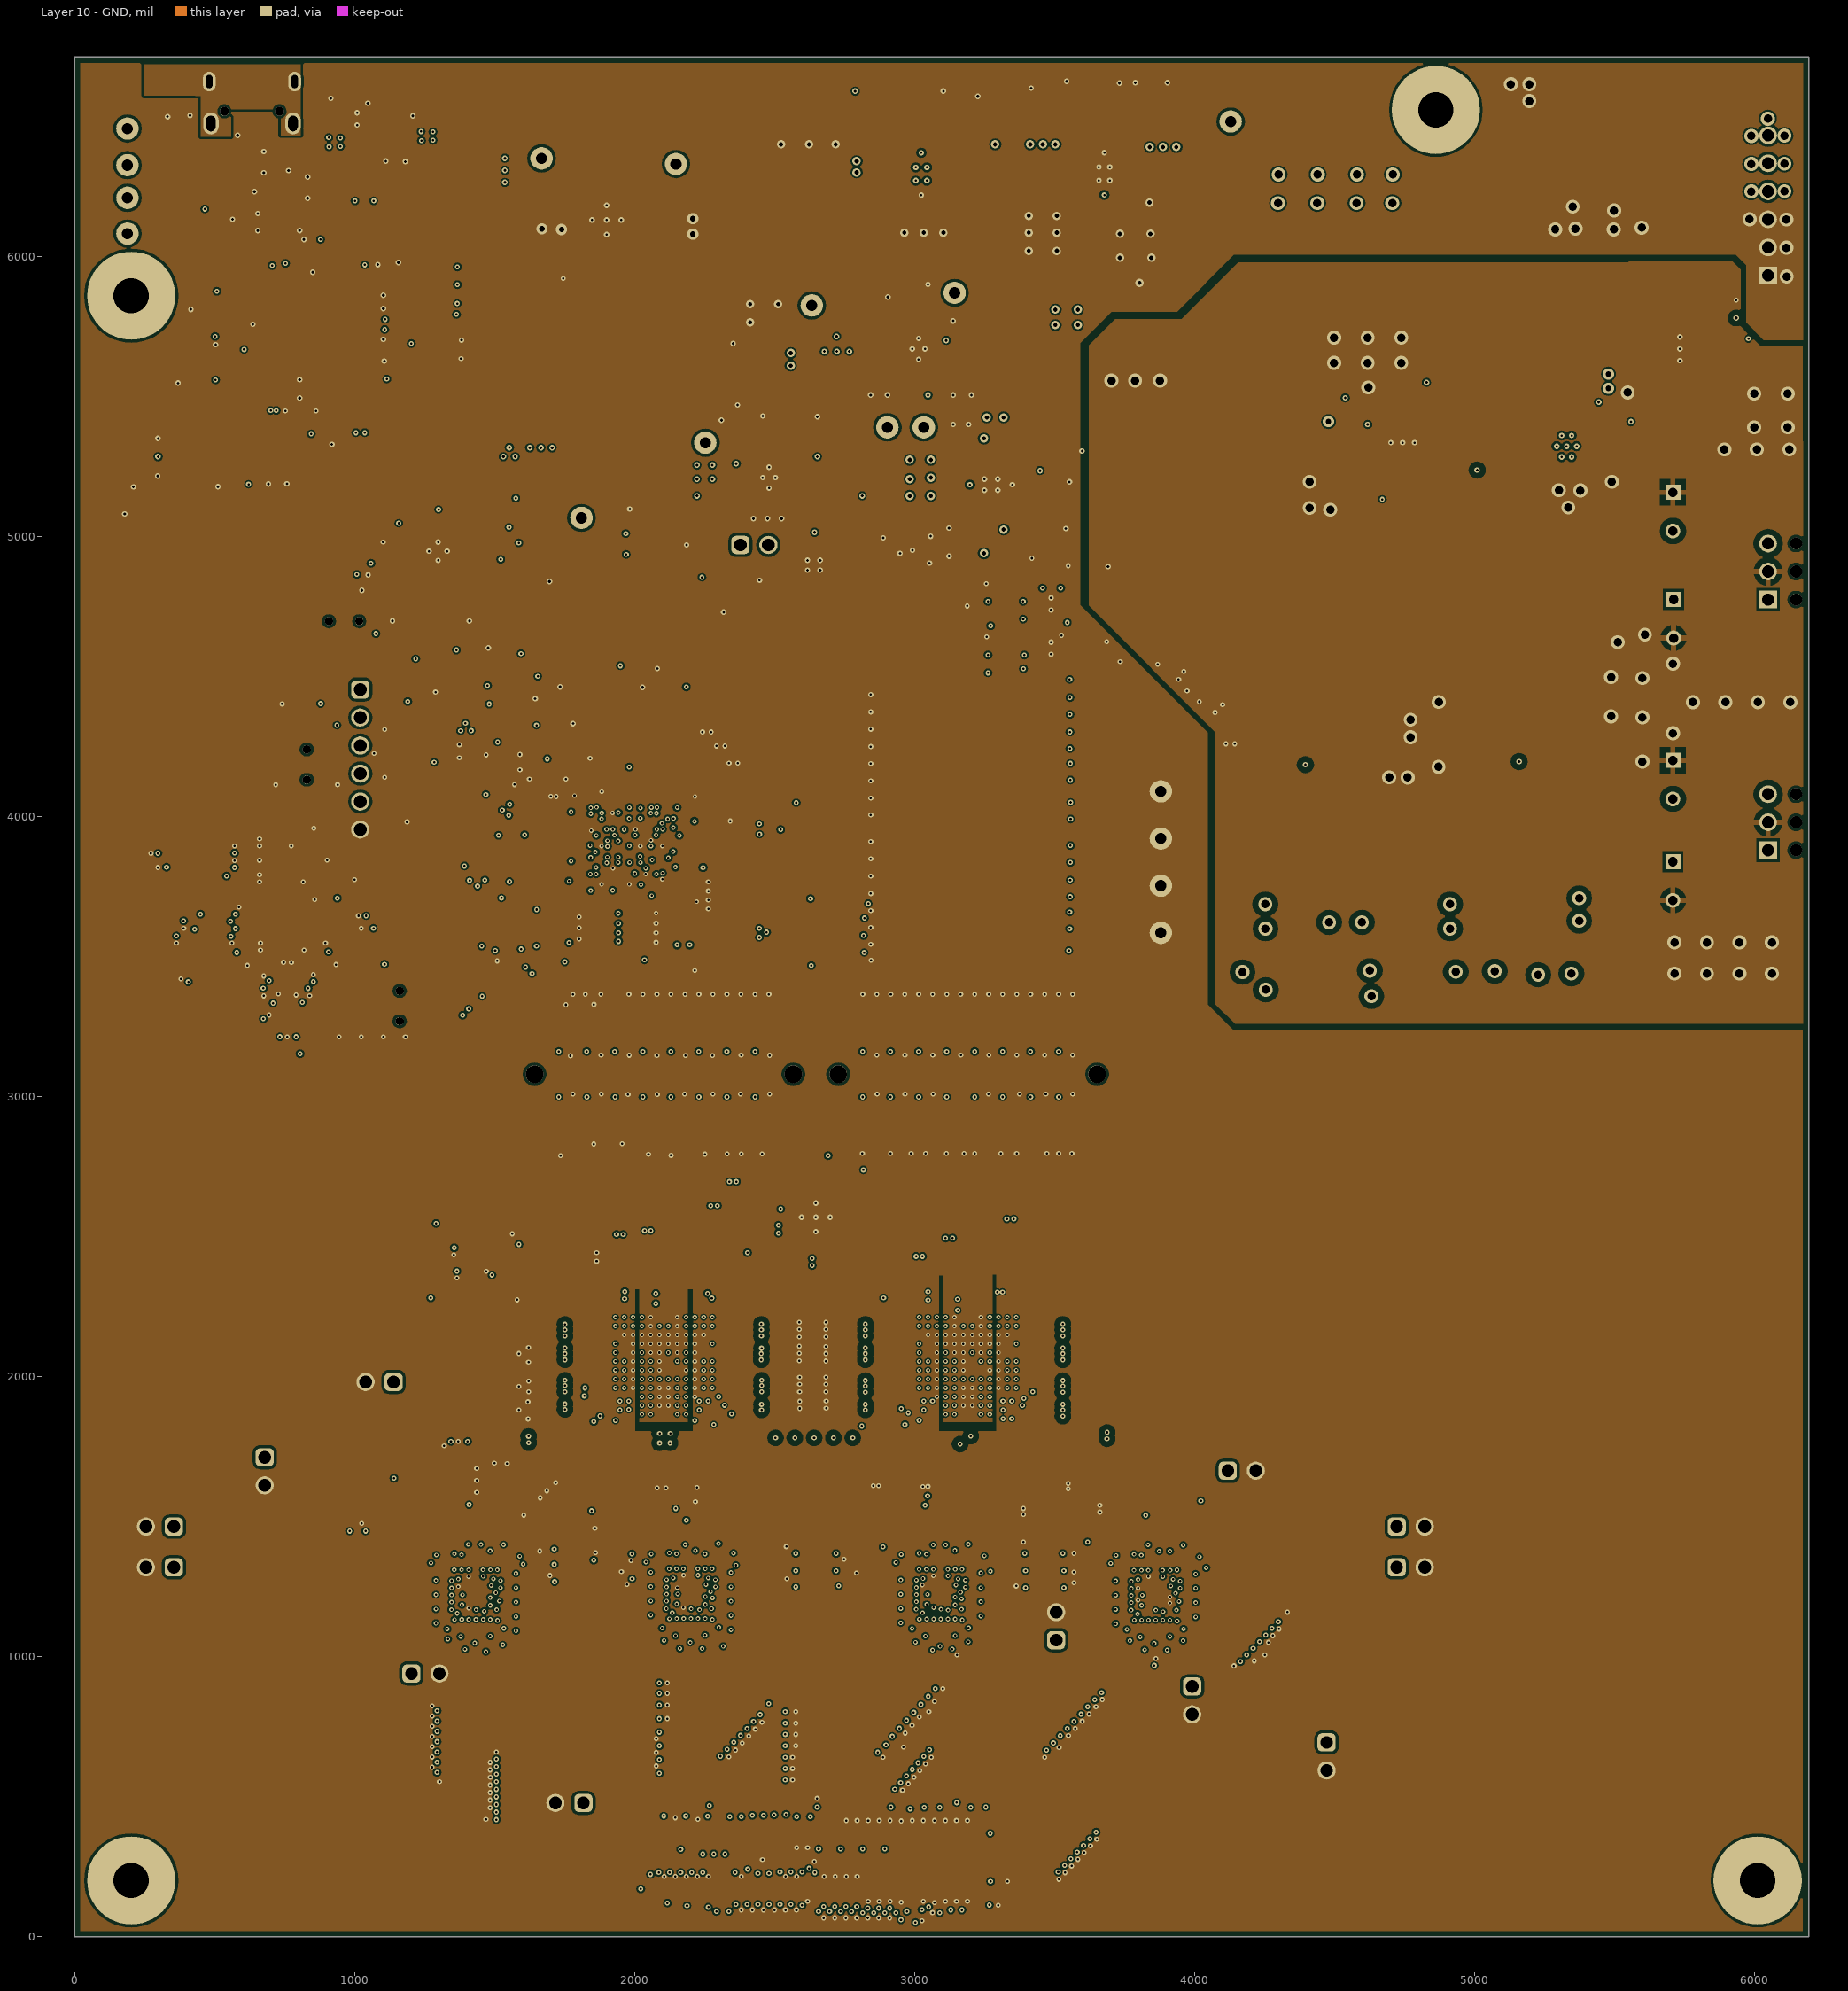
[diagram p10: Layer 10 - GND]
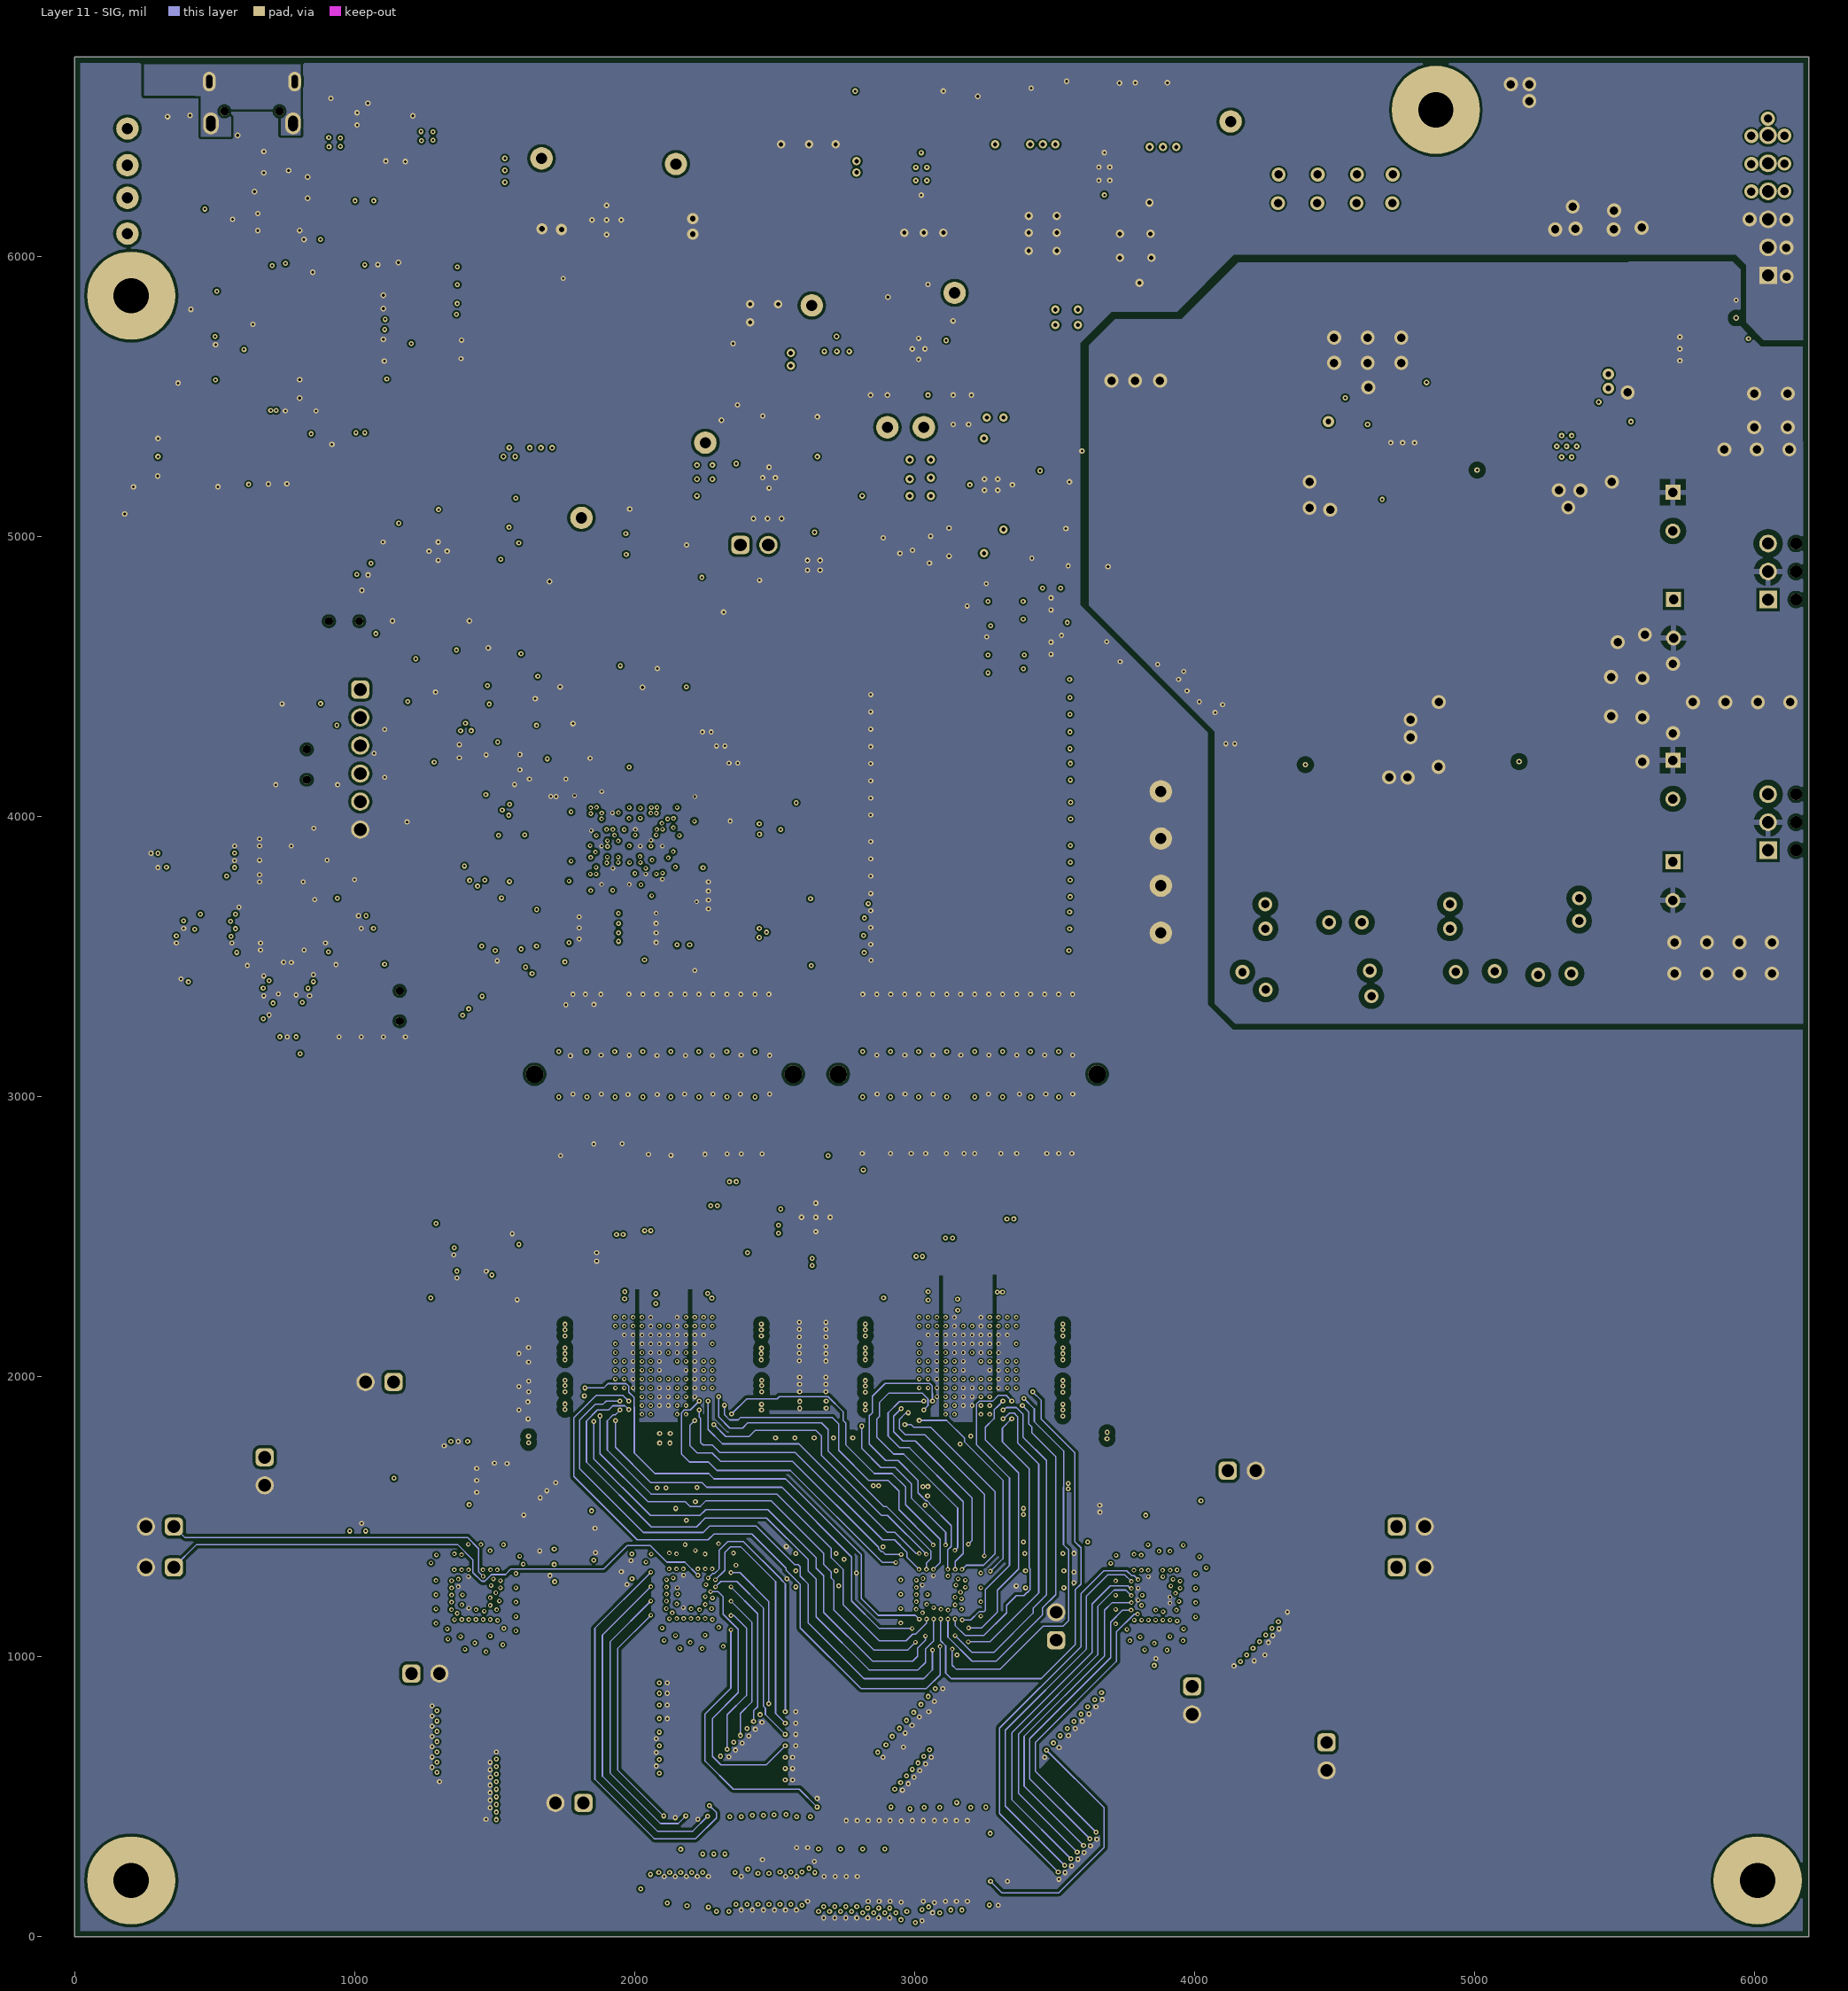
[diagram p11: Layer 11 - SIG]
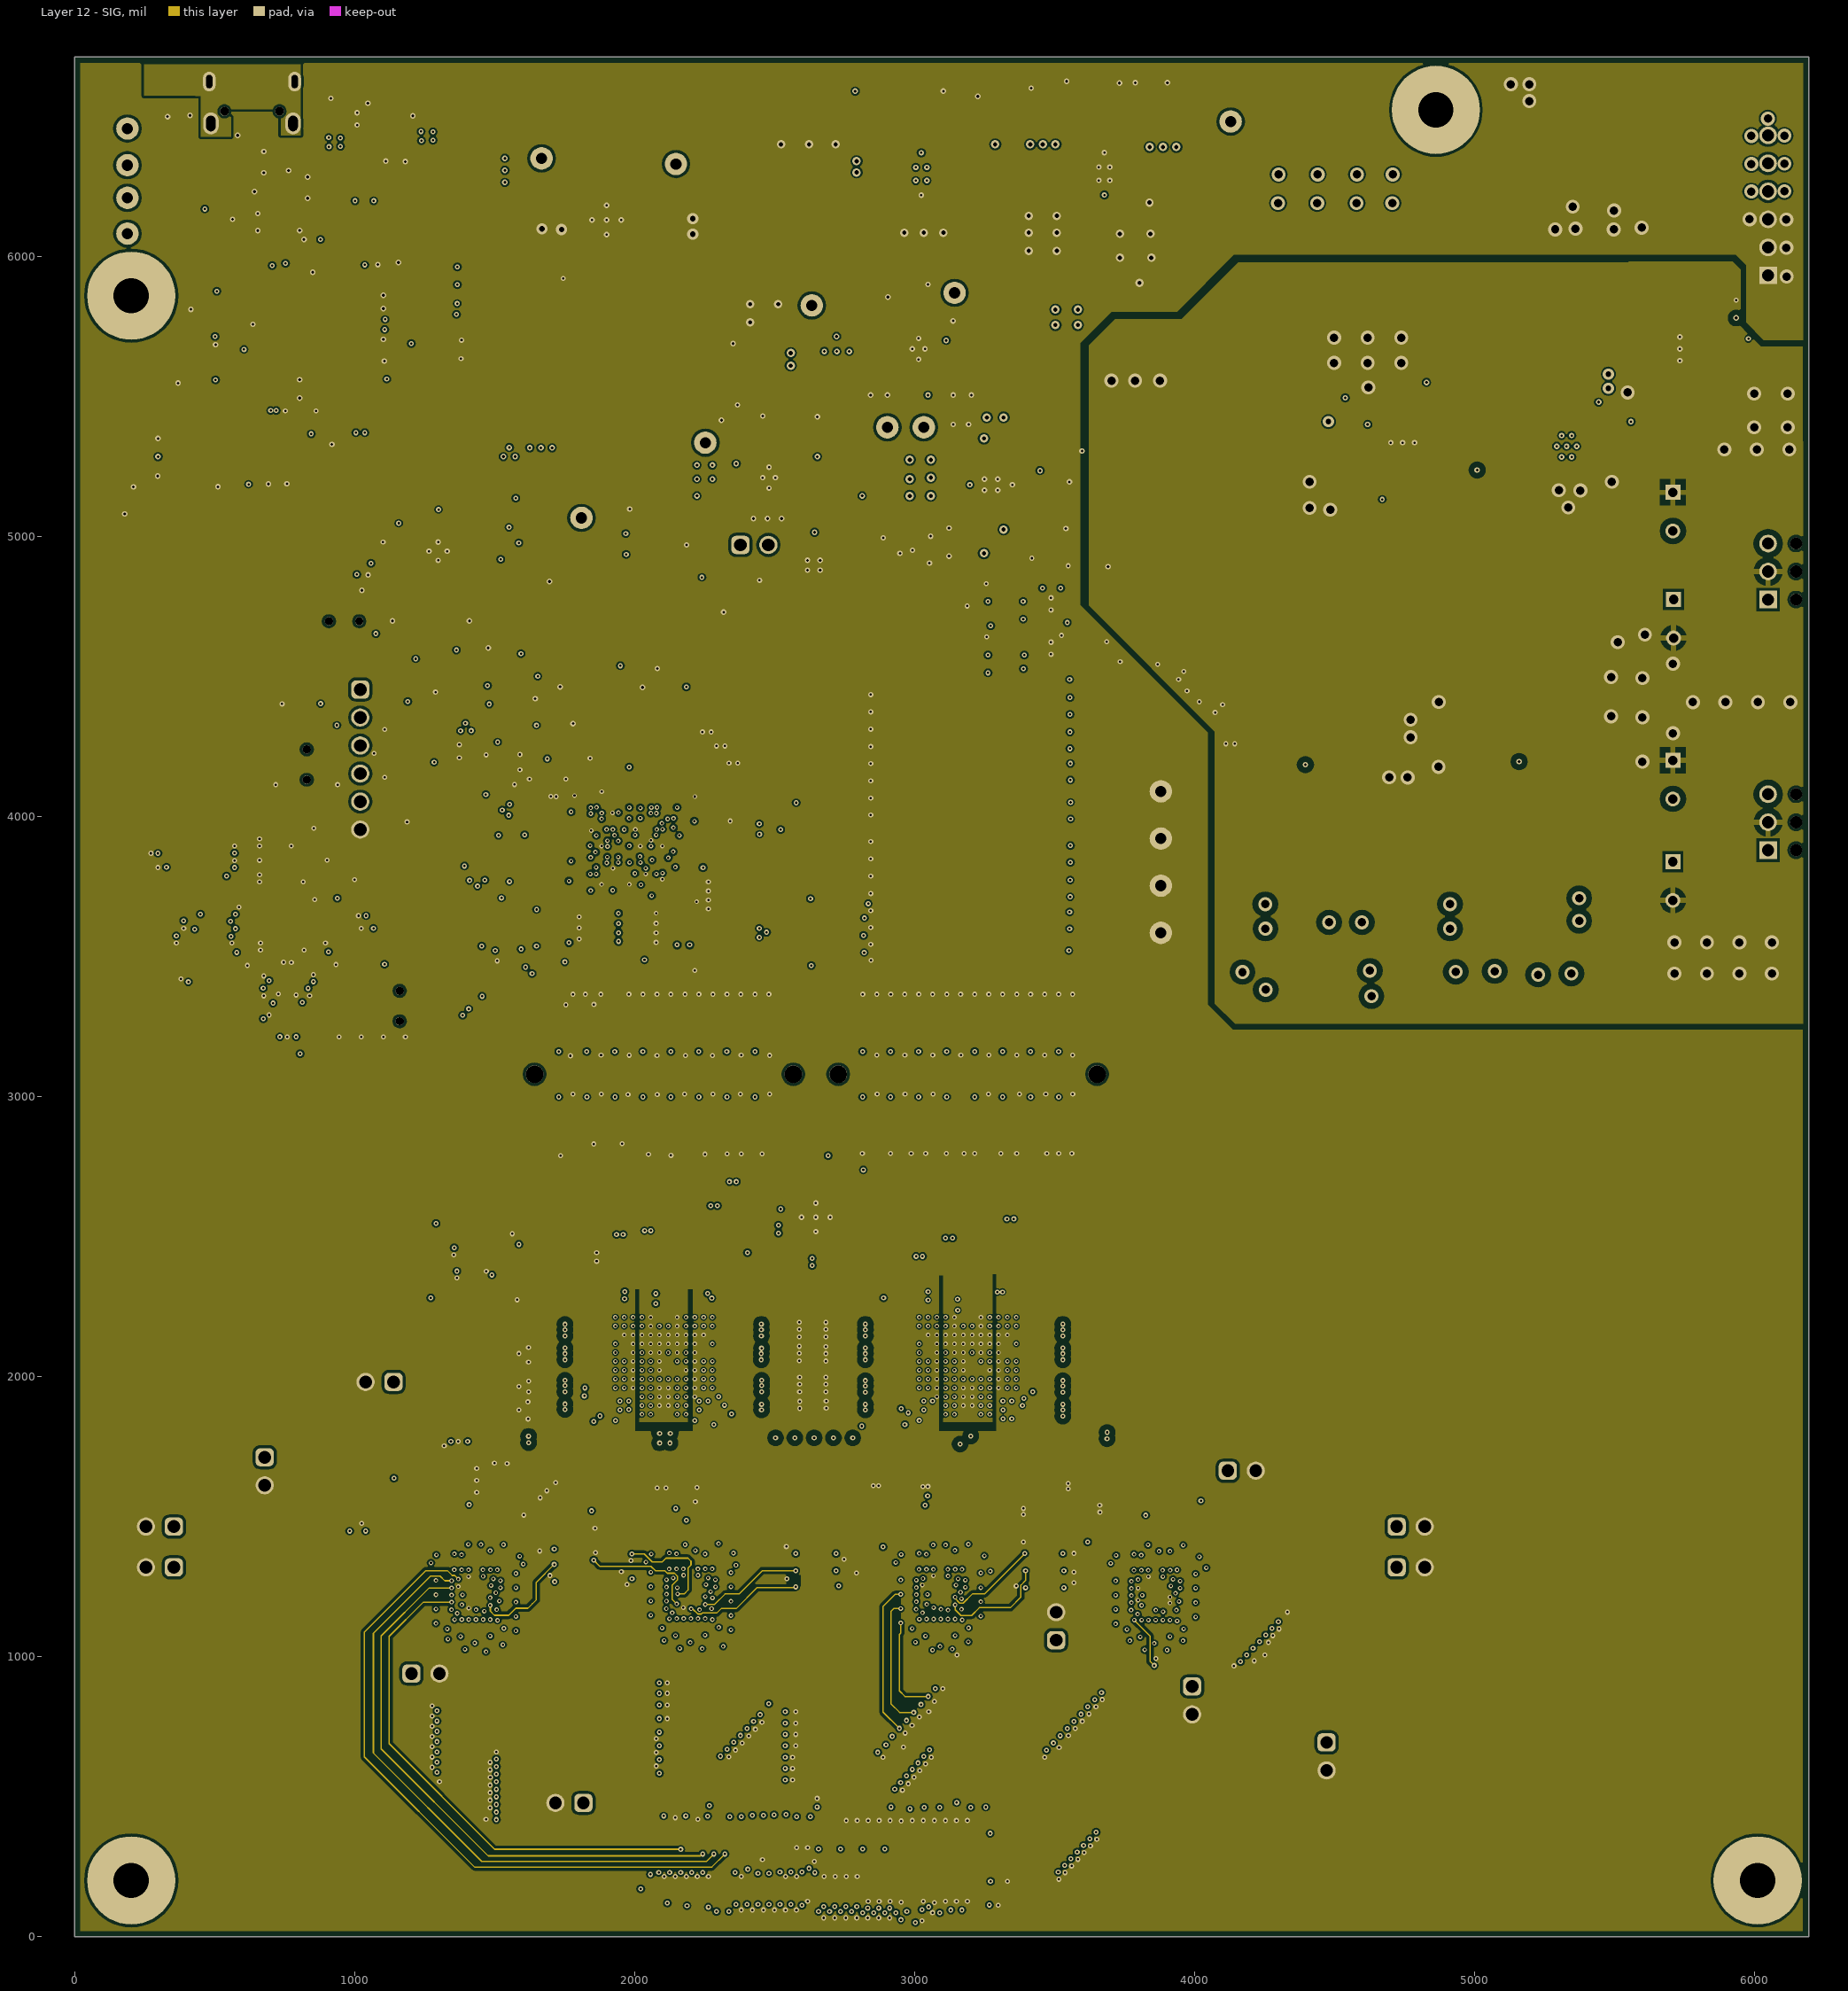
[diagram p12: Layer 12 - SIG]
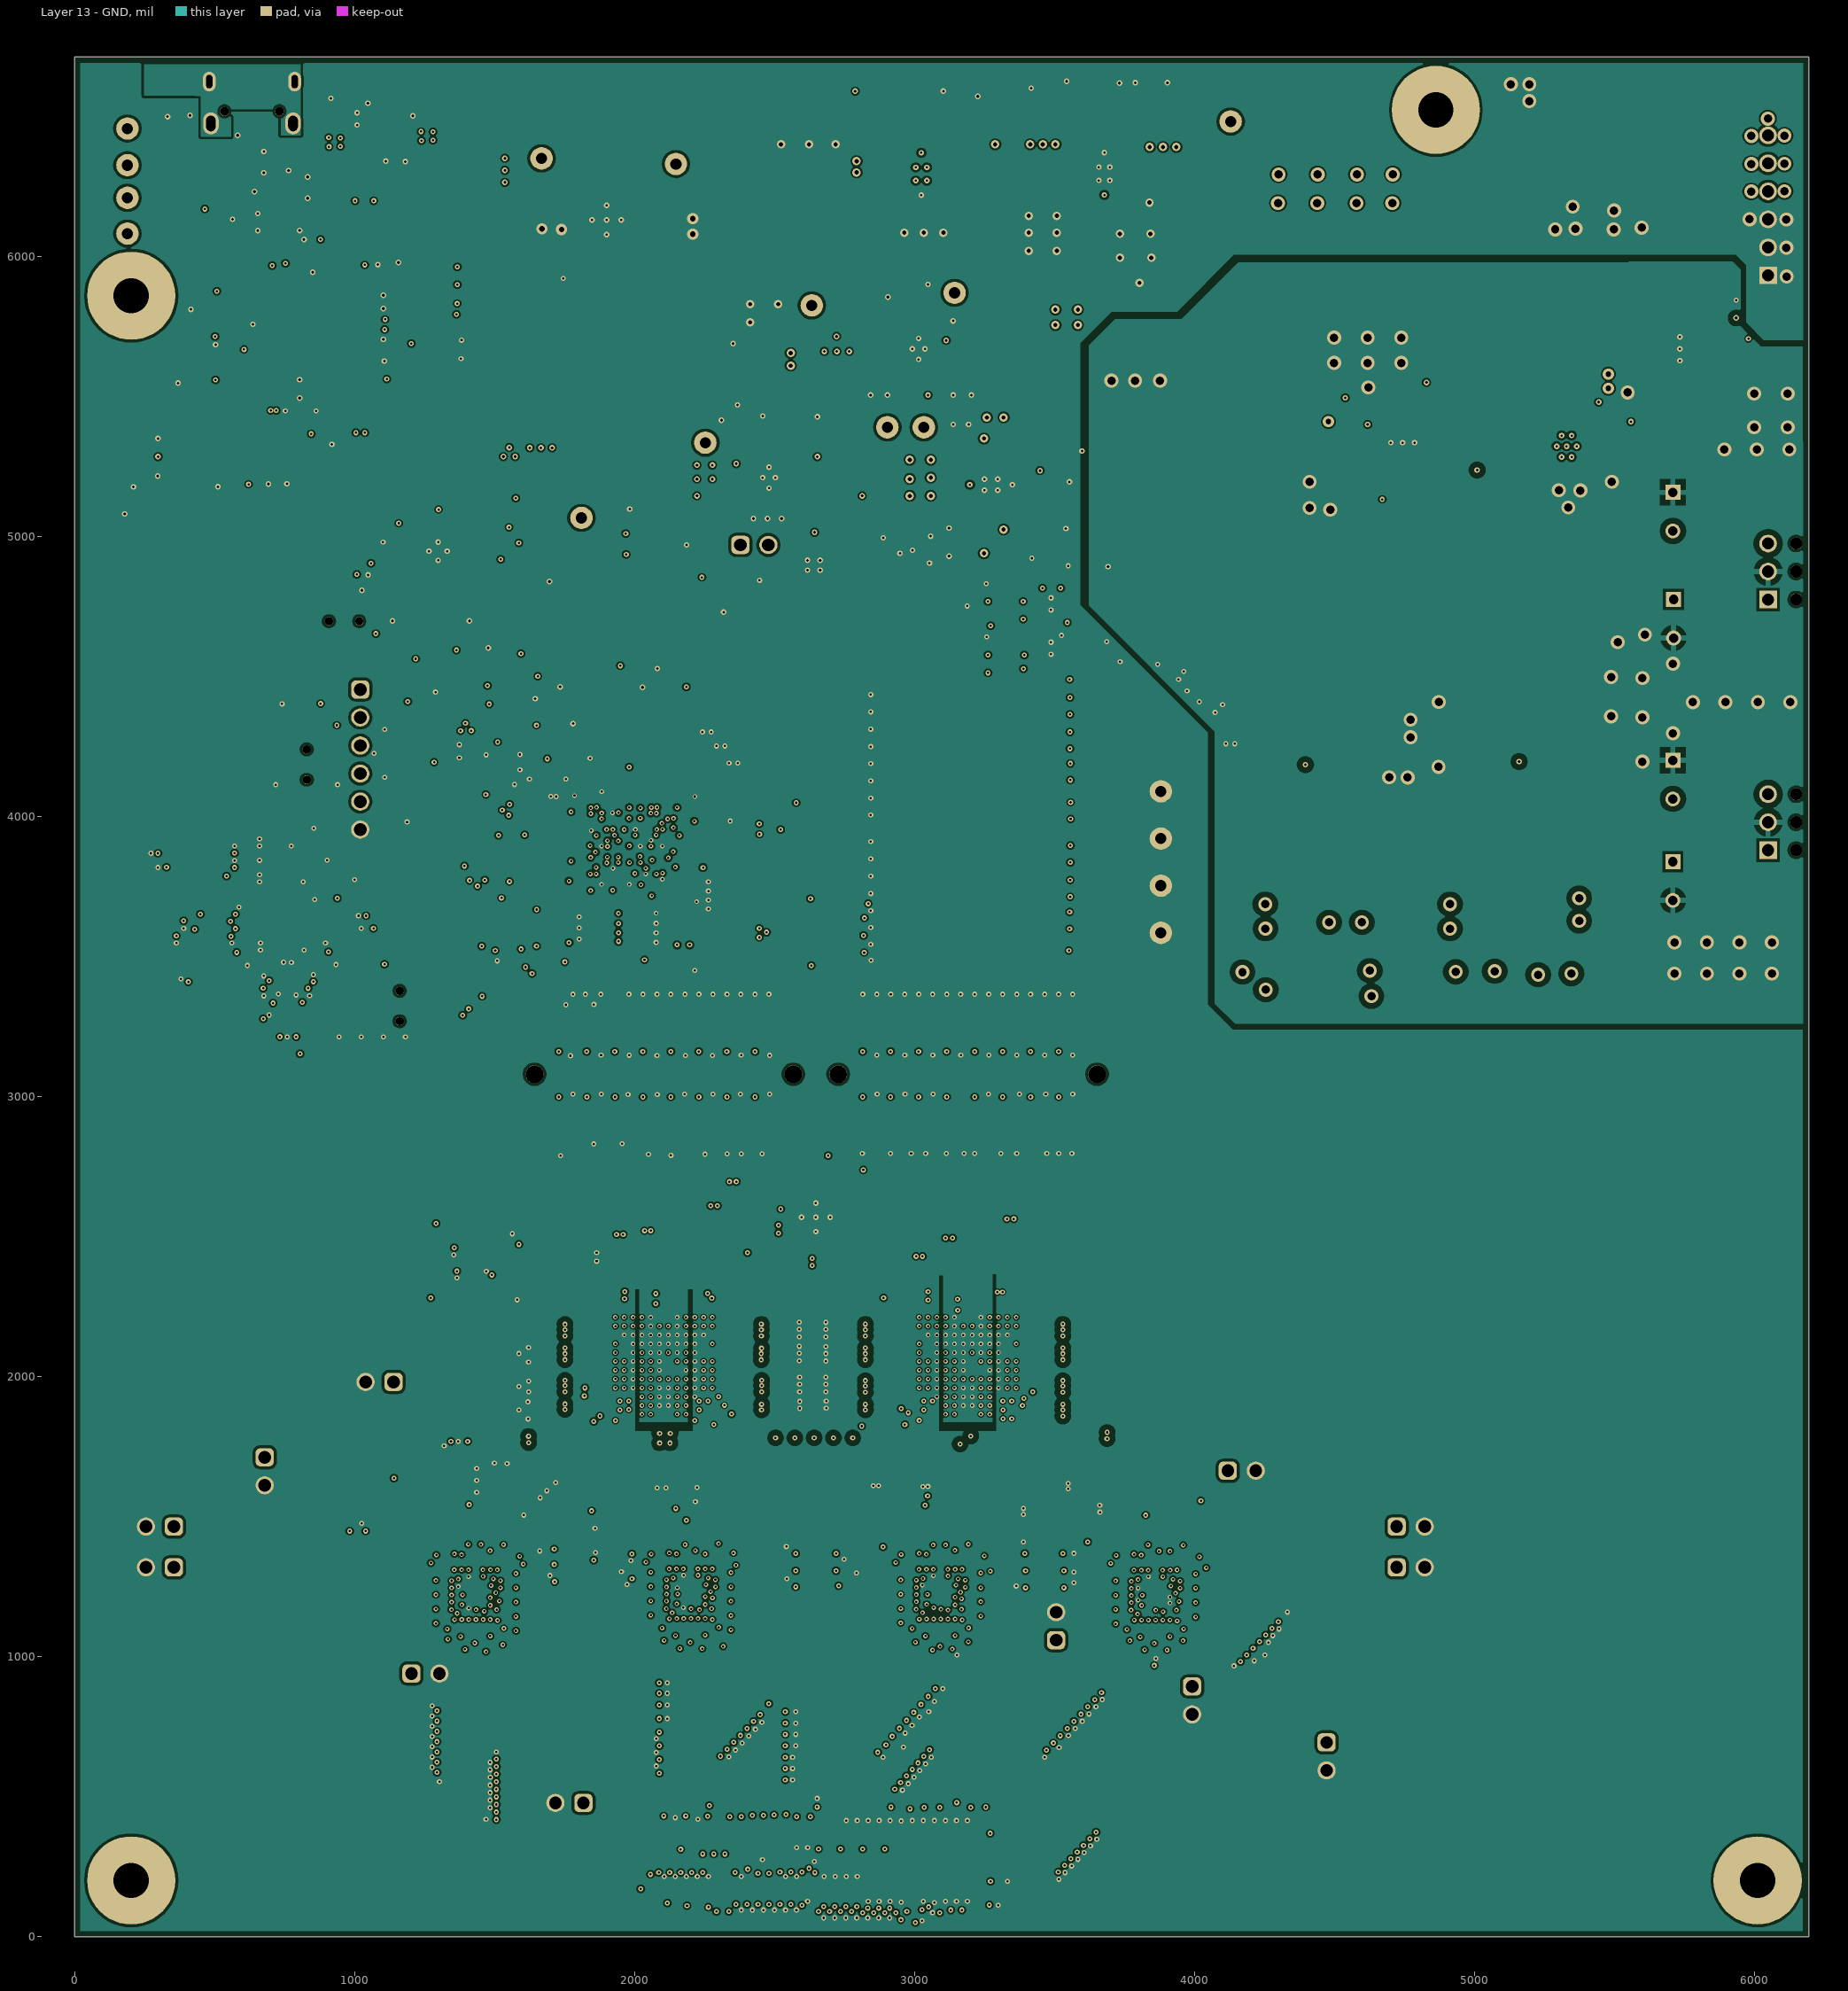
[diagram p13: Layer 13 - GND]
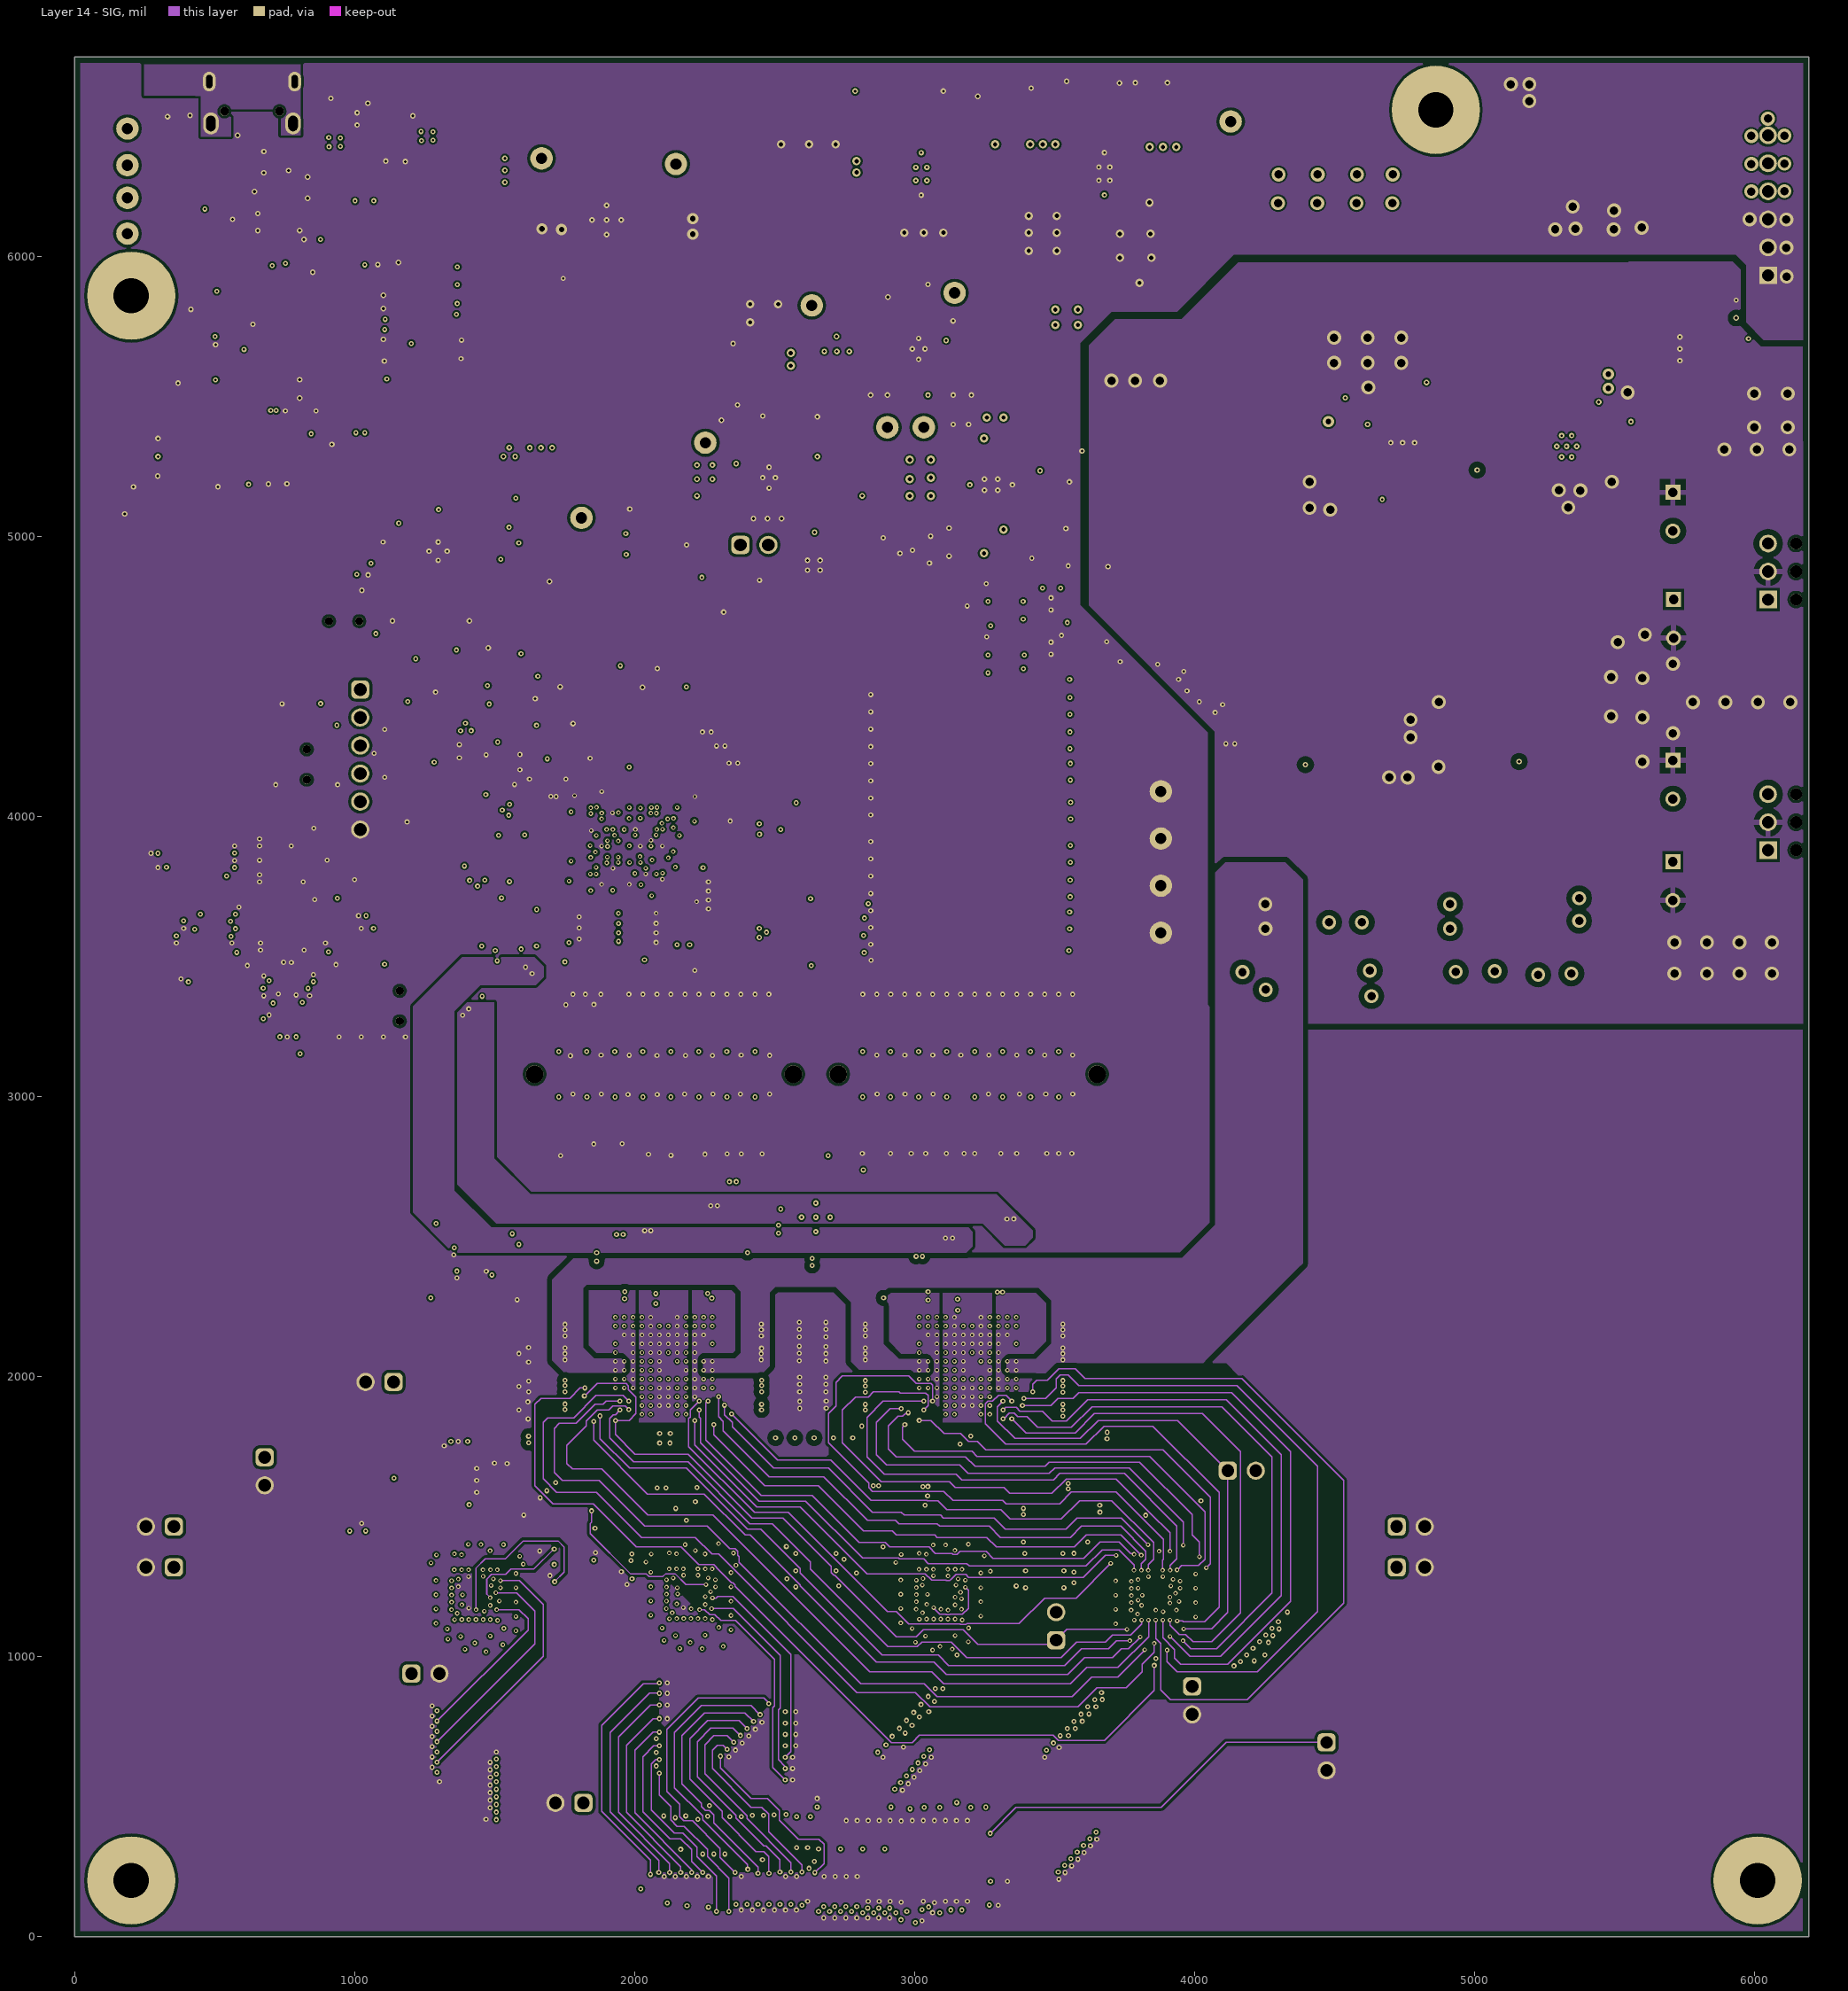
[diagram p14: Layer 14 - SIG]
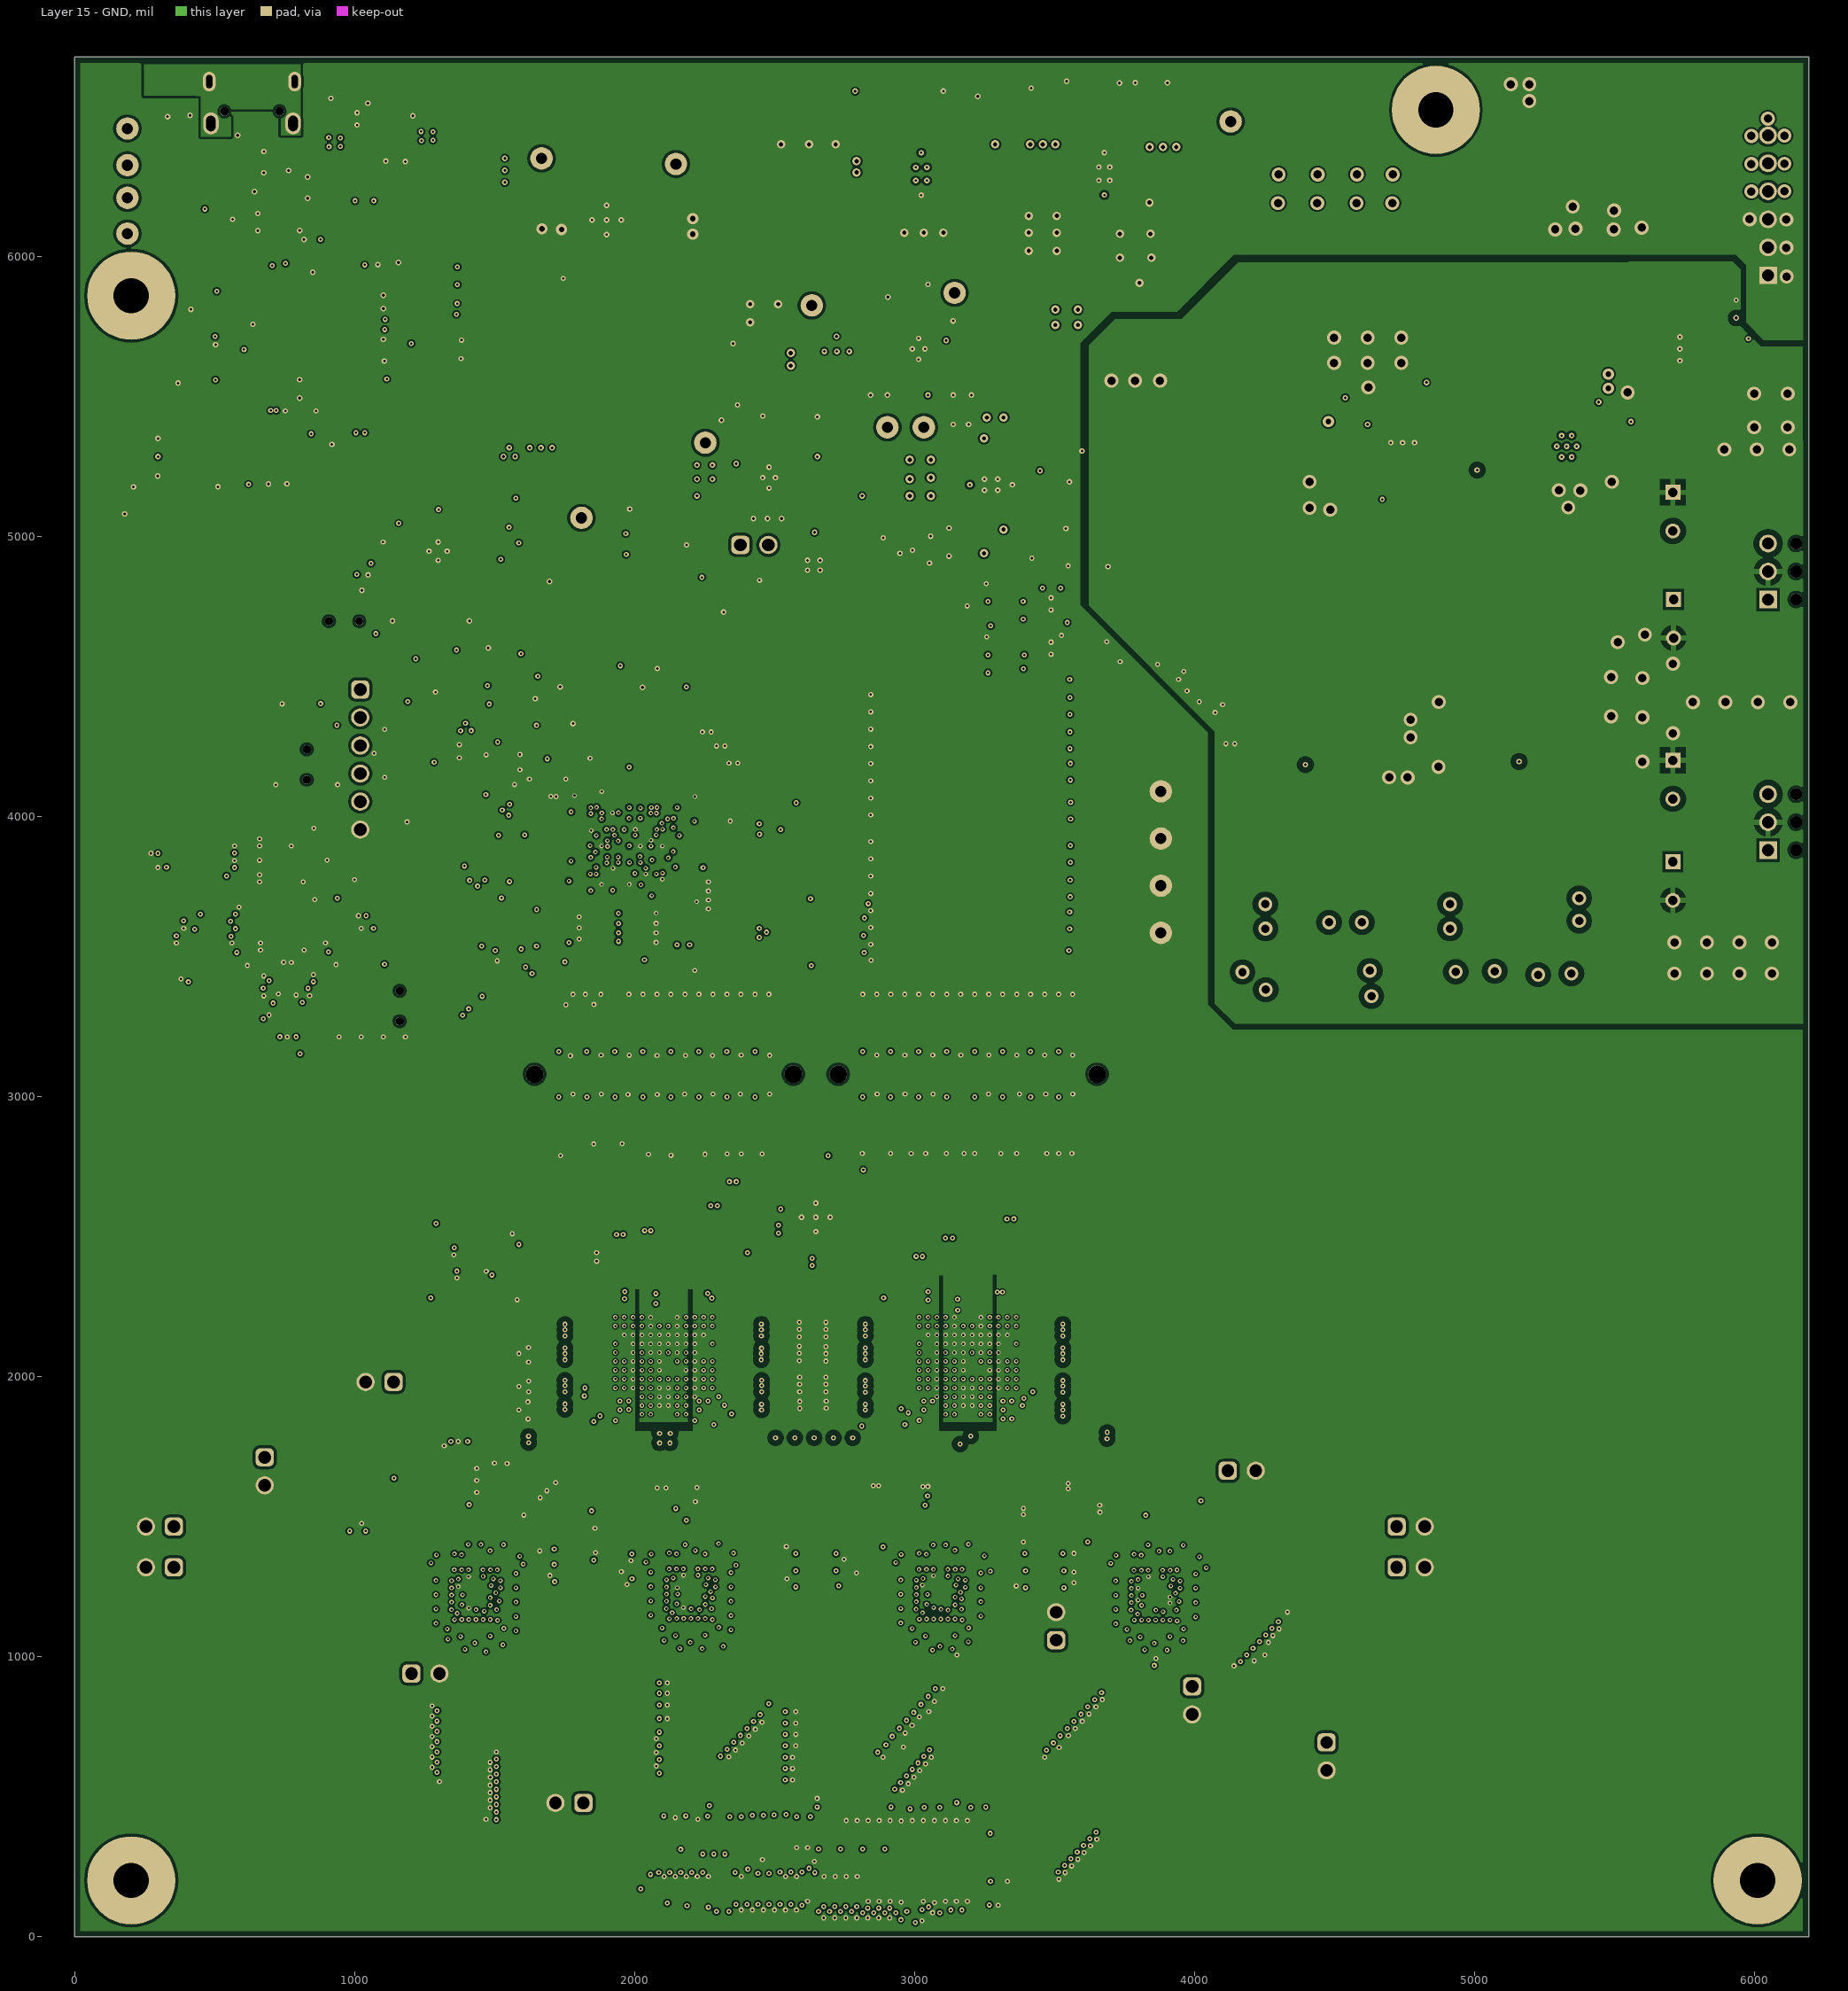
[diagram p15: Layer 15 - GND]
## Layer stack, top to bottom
Top Solder: solder mask 0.4, Solder Resist, Dk 3.5
Top Layer: signal copper 1.378
Dielectric 1: prepreg 3.504, FR-4 HIGH TG, Dk 4.1
Layer 2 - GND: signal copper 1.181
Dielectric 2: core 3.937, FR-4 HIGH TG, Dk 4.1
Layer 3 - SIG: signal copper 1.181
Dielectric 3: prepreg 7.008, FR-4 HIGH TG, Dk 4.1
Layer 4 - GND: signal copper 1.181
Dielectric 4: core 3.937, FR-4 HIGH TG, Dk 4.1
Layer 5 - SIG: signal copper 1.181
Dielectric 5: prepreg 7.008, FR-4 HIGH TG, Dk 4.1
Layer 6 - SIG: signal copper 1.181
Dielectric 6: core 3.937, FR-4 HIGH TG, Dk 4.1
Layer 7 - GND: signal copper 1.181
Dielectric 7: prepreg 7.008, FR-4 HIGH TG, Dk 4.1
Layer 8 - HV PWR: signal copper 1.181
Dielectric 8: core 3.937, FR-4 HIGH TG, Dk 4.1
Layer 9 - LV PWR: signal copper 1.181
Dielectric 9: prepreg 7.008, FR-4 HIGH TG, Dk 4.1
Layer 10 - GND: signal copper 1.181
Dielectric 10: core 3.937, FR-4 HIGH TG, Dk 4.1
Layer 11 - SIG: signal copper 1.181
Dielectric 11: prepreg 7.008, FR-4 HIGH TG, Dk 4.1
Layer 12 - SIG: signal copper 1.181
Dielectric 12: core 3.937, FR-4 HIGH TG, Dk 4.1
Layer 13 - GND: signal copper 1.181
Dielectric 13: prepreg 7.008, FR-4 HIGH TG, Dk 4.1
Layer 14 - SIG: signal copper 1.181
Dielectric 14: core 3.937, FR-4 HIGH TG, Dk 4.1
Layer 15 - GND: signal copper 1.181
Dielectric 15: prepreg 3.504, FR-4 HIGH TG, Dk 4.1
Bottom Layer: signal copper 1.378
Bottom Solder: solder mask 0.4, Solder Resist, Dk 3.5

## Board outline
0,0 0,6712.23 6192.49,6712.23 6192.49,0

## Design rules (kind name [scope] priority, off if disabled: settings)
BoardOutlineClearance "BoardOutlineClearance_Layer Text" [WithinRoom('Layer_Text')] p1: gap=10 ignorepadtopadclearanceinfootprint=FALSE except(0: Arc-SplitContinuation Track-SplitContinuation SMDPad-SplitContinuation THPad-SplitContinuation Via-SplitContinuation Fill-SplitContinuation Poly-SplitContinuation Region-SplitContinuation Text-OutlineEdge Text-CavityEdge Text-CutoutEdge Text-SplitBarrior Text-SplitContinuation; 20: Poly-OutlineEdge)
BoardOutlineClearance BoardOutlineClearance_J5 [InComponent('J5') or InComponent('J3')] p2: gap=10 ignorepadtopadclearanceinfootprint=FALSE except(0: Arc-SplitContinuation Track-OutlineEdge Track-CavityEdge Track-CutoutEdge Track-SplitBarrior Track-SplitContinuation SMDPad-SplitContinuation THPad-SplitContinuation Via-SplitContinuation Fill-OutlineEdge Fill-CavityEdge Fill-CutoutEdge Fill-SplitBarrior Fill-SplitContinuation Poly-SplitContinuation Region-SplitContinuation Text-OutlineEdge Text-CavityEdge Text-CutoutEdge Text-SplitBarrior Text-SplitContinuation; 20: Poly-OutlineEdge)
BoardOutlineClearance [All] p3: gap=10 ignorepadtopadclearanceinfootprint=FALSE except(0: Arc-SplitContinuation Track-SplitContinuation SMDPad-SplitContinuation THPad-SplitContinuation Via-SplitContinuation Fill-SplitContinuation Poly-SplitContinuation Region-SplitContinuation Text-SplitContinuation; 20: Poly-OutlineEdge)
Clearance Clearance_FID [InComponent('FID1') or InComponent('FID2') or InComponent('FID3') or InComponent('FID4') or InComponent('FID5') or InComponent('FID6') vs InComponent('FID1') or InComponent('FID2') or InComponent('FID3') or InComponent('FID4') or InComponent('FID5') or InComponent('FID6')] p1: gap=0 ignorepadtopadclearanceinfootprint=TRUE
Clearance Clearance_1 [WithinRoom('U27','U28','U29','U30')] p2: gap=10 ignorepadtopadclearanceinfootprint=FALSE except(0: Arc-Hole Track-Hole SMDPad-Hole THPad-Hole Via-Hole Fill-Hole Poly-Hole Region-Hole Text-Hole; 5: Arc-SMDPad Arc-Via Track-SMDPad Track-Via; 6: SMDPad-SMDPad SMDPad-Via Via-Via Via-Fill Via-Poly Via-Region; 8: Arc-Arc Arc-Track Track-Track)
Clearance TX7516 [WithinRoom('TX7516A')OR WithinRoom('TX7516B')] p3: gap=4 ignorepadtopadclearanceinfootprint=FALSE except(10: Arc-Fill Arc-Poly Arc-Region Track-Fill Track-Poly Track-Region SMDPad-Fill SMDPad-Poly SMDPad-Region THPad-Fill THPad-Poly THPad-Region; 15: Fill-Fill Fill-Poly Fill-Region Poly-Poly Poly-Region Region-Region)
Clearance "Small BGA" [WithinRoom('RoomDefinition_9')] p4: gap=10 ignorepadtopadclearanceinfootprint=FALSE except(0: Arc-Hole Track-Hole SMDPad-Hole THPad-Hole Via-Hole Fill-Hole Poly-Hole Region-Hole Text-Hole; 3: Arc-Arc Arc-Track Track-Track; 4: Arc-SMDPad Arc-THPad Arc-Via Track-SMDPad Track-THPad Track-Via SMDPad-SMDPad SMDPad-THPad SMDPad-Via THPad-THPad THPad-Via Via-Via; 7: Via-Fill Via-Poly Via-Region)
Clearance PHV [InNetClass('PHV')] p5: gap=10 ignorepadtopadclearanceinfootprint=FALSE except(0: Arc-Hole Track-Hole SMDPad-Hole THPad-Hole Via-Hole Fill-Hole Poly-Hole Region-Hole Text-Hole; 5: Arc-Arc Arc-Track Arc-SMDPad Track-Track Track-SMDPad; 5.5: Arc-Via Track-Via; 6: SMDPad-SMDPad SMDPad-Via Via-Via; 20: Via-Fill Via-Poly Via-Region Fill-Fill Fill-Poly Fill-Region Poly-Poly Poly-Region Region-Region)
Clearance MHV [InNetClass('MHV')] p6: gap=20 ignorepadtopadclearanceinfootprint=FALSE except(0: Arc-Hole Track-Hole SMDPad-Hole THPad-Hole Via-Hole Fill-Hole Poly-Hole Region-Hole Text-Hole; 5: Arc-Arc Arc-Track Arc-SMDPad Track-Track Track-SMDPad; 5.5: Arc-Via Track-Via; 6: SMDPad-SMDPad SMDPad-Via Via-Via; 10: Arc-THPad Arc-Text Track-THPad Track-Text SMDPad-THPad SMDPad-Text THPad-THPad THPad-Via THPad-Text Via-Text Fill-Text Poly-Text Region-Text Text-Text)
Clearance Clearance_3xwidth_INNER [(OnLayer('Layer 3 - SIG') OR OnLayer('Layer 5 - SIG') OR OnLayer('Layer 6 - SIG') OR OnLayer('Layer 11 - SIG') OR OnLayer('Layer 12 - SIG') OR OnLayer('Layer 14 - SIG'))] p7: gap=10 ignorepadtopadclearanceinfootprint=FALSE except(0: Arc-Hole Track-Hole SMDPad-Hole THPad-Hole Via-Hole Fill-Hole Poly-Hole Region-Hole Text-Hole; 5: Arc-SMDPad Arc-Via Track-SMDPad Track-Via; 6: Arc-Arc Arc-Track SMDPad-SMDPad SMDPad-Via Via-Via Via-Fill Via-Poly Via-Region; 15: Track-Track)
Clearance Clearance_3xwidth [All vs OnOutside and ( InNetClass('A_TX_OUT') and InNetClass('B_TX_OUT') and InNetClass('U27B_TX_OUT_65_96') and InNetClass('U28B_TX_OUT_33_64') and InNetClass('U29B_TX_OUT_01_32') and InNetClass('U30B_TX_OUT_97_128'))] p8: gap=10 ignorepadtopadclearanceinfootprint=FALSE except(0: Arc-Hole Track-Hole SMDPad-Hole THPad-Hole Via-Hole Fill-Hole Poly-Hole Region-Hole Text-Hole; 5: Arc-SMDPad Arc-Via Track-SMDPad Track-Via; 6: Arc-Arc Arc-Track SMDPad-SMDPad SMDPad-Via Via-Via Via-Fill Via-Poly Via-Region; 21: Track-Track)
Clearance ROOM [WithinRoom('RoomDefinition_1')OR WithinRoom('RoomDefinition_2')OR WithinRoom('RoomDefinition_3')OR WithinRoom('RoomDefinition_4')OR WithinRoom('RoomDefinition_5')OR WithinRoom('RoomDefinition_6')OR WithinRoom('RoomDefinition_7')OR WithinRoom('RoomDefinition')] p9: gap=10 ignorepadtopadclearanceinfootprint=TRUE except(0: Arc-Hole Track-Hole SMDPad-Hole THPad-Hole Via-Hole Fill-Hole Poly-Hole Region-Hole Text-Hole; 3: SMDPad-SMDPad; 5: Arc-Arc Arc-Track Arc-SMDPad Track-Track Track-SMDPad; 5.5: Track-Via; 6: Arc-Via SMDPad-Via; 8: Arc-Fill Arc-Poly Arc-Region Track-Fill Track-Poly Track-Region SMDPad-Region Via-Fill Via-Poly Via-Region)
Clearance TX_routingB [InNetClass('TX7516 B routing')] p10: gap=10 ignorepadtopadclearanceinfootprint=FALSE except(0: Arc-Hole Track-Hole SMDPad-Hole THPad-Hole Via-Hole Fill-Hole Poly-Hole Region-Hole Text-Hole; 5: Arc-SMDPad Track-SMDPad; 5.5: Arc-Via Track-Via; 6: SMDPad-SMDPad SMDPad-Via Via-Via Via-Fill Via-Poly Via-Region)
Clearance TX_routingA [InNetClass('TX7516 A routing')] p11: gap=10 ignorepadtopadclearanceinfootprint=FALSE except(0: Arc-Hole Track-Hole SMDPad-Hole THPad-Hole Via-Hole Fill-Hole Poly-Hole Region-Hole Text-Hole; 5: Arc-SMDPad Track-SMDPad; 5.5: Arc-Via Track-Via; 6: SMDPad-SMDPad SMDPad-Via Via-Via Via-Fill Via-Poly Via-Region)
Clearance PHV_OUTER [OnBottomLayer and InNet('PHV_A')] p12: gap=40 ignorepadtopadclearanceinfootprint=FALSE
Clearance +3.3V_poly [InNet('NetC3_1')] p13: gap=10 ignorepadtopadclearanceinfootprint=FALSE except(0: Arc-Hole Track-Hole SMDPad-Hole THPad-Hole Via-Hole Fill-Hole Poly-Hole Region-Hole Text-Hole; 6: SMDPad-Via; 7: Arc-Arc Arc-Track Arc-SMDPad Arc-Via Track-Track Track-SMDPad Track-Via SMDPad-SMDPad; 20: Fill-Fill Fill-Poly Fill-Region Poly-Poly Poly-Region Region-Region)
Clearance Connector [WithinRoom('RoomDefinition_8')OR WithinRoom('RoomDefinition_10') vs InNet('No Net')] p14: gap=6 ignorepadtopadclearanceinfootprint=FALSE except(10: Arc-Fill Arc-Poly Arc-Region Track-Fill Track-Poly Track-Region)
Clearance 90ohm [InDifferentialPairClass('90ohm')] p15: gap=10 ignorepadtopadclearanceinfootprint=FALSE except(0: Arc-Hole Track-Hole SMDPad-Hole THPad-Hole Via-Hole Fill-Hole Poly-Hole Region-Hole Text-Hole; 5: Arc-Arc Arc-Track Arc-SMDPad Arc-Via Track-Track Track-SMDPad Track-Via; 6: SMDPad-SMDPad SMDPad-Via Via-Via; 8: Fill-Fill Fill-Poly Fill-Region Poly-Poly Poly-Region Region-Region)
Clearance [All] p16: gap=10 ignorepadtopadclearanceinfootprint=FALSE except(0: Arc-Hole Track-Hole SMDPad-Hole THPad-Hole Via-Hole Fill-Hole Poly-Hole Region-Hole Text-Hole; 5: Arc-SMDPad Arc-Via Track-SMDPad Track-Via; 6: SMDPad-SMDPad SMDPad-Via Via-Via Via-Fill Via-Poly Via-Region; 8: Arc-Arc Arc-Track Track-Track)
ComponentClearance ComponentClearance_H [InComponent('H1') or InComponent('H2') or InComponent('H3')or InComponent('H4') vs InComponent('H5') or InComponent('H6') or InComponent('H7') or InComponent('H8')] p1: gap=0 collisioncheckmode=3 verticalgap=0 showdistances=FALSE
ComponentClearance "Probe header clearance" [InComponentClass('Probe Header') vs InComponentClass('Probe Header')] p2: gap=38 collisioncheckmode=3 verticalgap=100000 showdistances=FALSE
ComponentClearance [All] p3: gap=10 collisioncheckmode=3 verticalgap=10 showdistances=FALSE
DiffPairsRouting 90ohm_1 [InDifferentialPair('USB_90')] p1: maxlimit=40 minlimit=9.9 mostfreqgap=10 toplayer_prefgap=9.9 toplayer_minwidth=6.1 toplayer_maxwidth=6.1 toplayer_prefwidth=6.1 bottomlayer_prefgap=9.9 bottomlayer_minwidth=6.1 bottomlayer_maxwidth=6.1 bottomlayer_prefwidth=6.1 impedanceprofiledriven=TRUE impedanceprofileid={85A013A6-24DB-4B2E-BA22-DBD13952F31F} impedanceprofilevalue=100.000000 maxuncoupledlength=500
DiffPairsRouting 100ohm [InDifferentialPairClass('100OHM')] p2: maxlimit=40 minlimit=9.9 mostfreqgap=10 toplayer_prefgap=9.9 toplayer_minwidth=6.1 toplayer_maxwidth=6.1 toplayer_prefwidth=6.1 bottomlayer_prefgap=9.9 bottomlayer_minwidth=6.1 bottomlayer_maxwidth=6.1 bottomlayer_prefwidth=6.1 impedanceprofiledriven=TRUE impedanceprofileid={85A013A6-24DB-4B2E-BA22-DBD13952F31F} impedanceprofilevalue=100.000000 maxuncoupledlength=500
FanoutControl Fanout_BGA [IsBGA] p1: bgadir=Out bgaviamode=Centered fanoutstyle=UnderPads fanoutdirection=InThenOut viagrid=1 // Fanout_BGA (Default Rule)
HoleSize [All] p1: absolutevalues=TRUE maxlimit=1000 minlimit=1 maxpercent=80.000 minpercent=20.000
HoleToHoleClearance [All] p1: gap=8 allowstackedmicrovias=TRUE
MatchedLengths [InDifferentialPair ('USB_90')] p1: tolerance=1000 checknetsindiffpair=FALSE checkdiffpairvsdiffpair=TRUE checkxsignals=TRUE checkothers=TRUE
MinimumSolderMaskSliver [All] p1: minsoldermaskwidth=0
PlaneClearance PlaneClearance_PHV [InNet('PHV_A') and OnBottomLayer] p1: clearance=40
PlaneClearance PlaneClearance_1 [InNetClass('MHV')] p2: clearance=20
PlaneClearance HVGND [InNet('HV_GND')] p3: clearance=20
PlaneClearance [All] p4: clearance=8
PlaneConnect [All] p1: planeconnectstyle=Direct reliefexpansion=20 reliefentries=4 reliefconductorwidth=10 reliefairgap=10
PolygonConnect USB_SHEILD [InNet('USB_SHIELD')] p1: connectstyle=Direct reliefconductorwidth=10 reliefentries=4 polygonreliefangle="90 Angle" airgapwidth=10
PolygonConnect PADVIAL [InNetClass('padvial')] p2: connectstyle=Direct reliefconductorwidth=10 reliefentries=4 polygonreliefangle="90 Angle" airgapwidth=10
PolygonConnect GND [InNet('GND')] p3: connectstyle=Direct reliefconductorwidth=10 reliefentries=4 polygonreliefangle="90 Angle" airgapwidth=10
PolygonConnect [All] p4: thpad.connectstyle=Relief thpad.reliefconductorwidth=19.68 thpad.reliefentries=4 thpad.polygonreliefangle="90 Angle" thpad.airgapwidth=19.68 smdpad.connectstyle=Direct smdpad.reliefconductorwidth=10 smdpad.reliefentries=4 smdpad.polygonreliefangle="90 Angle" smdpad.airgapwidth=10 via.connectstyle=Direct via.reliefconductorwidth=10 via.reliefentries=4 via.polygonreliefangle="90 Angle" via.airgapwidth=10
RoomDefinition Layer_Text [False] p1: confinementstyle=ConfineIn formatcopy=TRUE lockcomponents=FALSE outline 524,-705 2183,-705 2183,-931 524,-931
RoomDefinition U30 [False] p2: confinementstyle=ConfineIn formatcopy=TRUE lockcomponents=FALSE outline 3655.96,1402.83 4036.03,1402.83 4036.03,1007.61 3655.96,1007.61
RoomDefinition U27 [False] p3: confinementstyle=ConfineIn formatcopy=TRUE lockcomponents=FALSE outline 2920.52,1384.3 3316.95,1384.3 3316.95,1013.41 2920.52,1013.41
RoomDefinition U28 [False] p4: confinementstyle=ConfineIn formatcopy=TRUE lockcomponents=FALSE outline 2038.68,1391.33 2404.67,1391.33 2404.67,1018.82 2038.68,1018.82
RoomDefinition U29 [False] p5: confinementstyle=ConfineIn formatcopy=TRUE lockcomponents=FALSE outline 1236.54,1391.22 1634.89,1391.22 1634.89,1047.99 1236.54,1047.99
RoomDefinition RoomDefinition_9 [False vs False] p6: confinementstyle=ConfineIn formatcopy=TRUE lockcomponents=FALSE outline 1657.9,4121.49 2282.9,4121.49 2282.9,3531.49 1657.9,3526.31
RoomDefinition TX7516A [False] p7: confinementstyle=ConfineIn formatcopy=TRUE lockcomponents=FALSE outline 1881.18,2250.64 2325.78,2250.64 2325.78,1820.34 1881.18,1820.34
RoomDefinition TX7516B [False] p8: confinementstyle=ConfineIn formatcopy=TRUE lockcomponents=FALSE outline 2967,2305.71 3401.9,2305.71 3401.9,1821.84 2967,1821.84
RoomDefinition [False] p9: confinementstyle=ConfineIn formatcopy=TRUE lockcomponents=FALSE outline 2375.58,5569.42 2260.58,5569.42 2260.58,5704.42 2375.58,5704.42
RoomDefinition RoomDefinition_7 [False] p10: confinementstyle=ConfineIn formatcopy=TRUE lockcomponents=FALSE outline 3131.7,5289.32 3411.7,5289.32 3411.7,5079.32 3131.7,5079.32
RoomDefinition RoomDefinition_6 [False] p11: confinementstyle=ConfineIn formatcopy=TRUE lockcomponents=FALSE outline 3575.1,6155.38 3575.1,6455.38 3785.1,6455.38 3785.1,6155.38
RoomDefinition RoomDefinition_5 [False] p12: confinementstyle=ConfineIn formatcopy=TRUE lockcomponents=FALSE outline 2901.64,6120.42 3146.64,6120.42 3146.64,6440.42 2901.64,6440.42
RoomDefinition RoomDefinition_4 [False] p13: confinementstyle=ConfineIn formatcopy=TRUE lockcomponents=FALSE outline 5272.49,5404.32 5457.49,5404.32 5457.49,5259.32 5272.49,5259.32
RoomDefinition RoomDefinition_3 [False vs False] p14: confinementstyle=ConfineIn formatcopy=TRUE lockcomponents=FALSE outline 4338.79,5407.96 4518.79,5407.96 4518.79,5257.96 4338.79,5257.96
RoomDefinition RoomDefinition_2 [False] p15: confinementstyle=ConfineIn formatcopy=TRUE lockcomponents=FALSE outline 5676.71,5730 5786.71,5730 5786.71,5600 5676.71,5600
RoomDefinition RoomDefinition_1 [False] p16: confinementstyle=ConfineIn formatcopy=TRUE lockcomponents=FALSE outline 4670,5391.82 4800,5391.82 4800,5271.82 4670,5271.82
RoutingVias [All] p1: holewidth=8 width=15.75 viastyle="Through Hole" minholewidth=4 minwidth=10 maxholewidth=30 maxwidth=50
SilkToBoardRegionClearance [Not ((IsComment or IsDesignator) And (Hide <> 'False')) and not InRegion(1000,500,4000,800)] p1:
SilkToSilkClearance [All] p1: silktosilkclearance=0
SilkToSolderMaskClearance [IsPad] p1: minsilkscreentomaskgap=0 clearancetoexposedcopper=TRUE
SolderMaskExpansion [All] p1: expansion=4 istentingtop=FALSE
ViasUnderSMD [InBGA] p1: allowed=TRUE
Width Width_1 [(InNetClass('A_RX_IN') OR InNetClass('A_TX_OUT') OR InNetClass('B_RX_IN') OR InNetClass('B_TX_OUT') OR InNetClass('U27B_TX_OUT_65_96') OR InNetClass('U29B_TX_OUT_01_32') OR InNetClass('U28B_TX_OUT_33_64') OR InNetClass('U30B_TX_OUT_97_128'))] p1: maxlimit=10 minlimit=4.5 preferedwidth=10 toplayer_minwidth=6 toplayer_maxwidth=6 toplayer_prefwidth=6 midlayer2_maxwidth=4.5 midlayer2_prefwidth=4.5 midlayer4_minwidth=5 midlayer4_maxwidth=5 midlayer4_prefwidth=5 midlayer5_minwidth=5 midlayer5_maxwidth=5 midlayer5_prefwidth=5 midlayer10_minwidth=5 midlayer10_maxwidth=5 midlayer10_prefwidth=5 midlayer11_minwidth=5 midlayer11_maxwidth=5 midlayer11_prefwidth=5 midlayer13_maxwidth=4.5 midlayer13_prefwidth=4.5 bottomlayer_minwidth=6 bottomlayer_maxwidth=6 bottomlayer_prefwidth=6 impedanceprofiledriven=TRUE impedanceprofileid={4F22306B-719A-4BD8-AA1A-60BC47F27E3B} impedanceprofilevalue=50.000000 minimp=50.000000 maximp=50.000000 favimp=50.000000
Width PWR [InNetClass('L_PWR')] p2: maxlimit=196.85 minlimit=5 preferedwidth=19.68
Width [All] p3: maxlimit=50 minlimit=4 preferedwidth=10 toplayer_maxwidth=40 toplayer_prefwidth=6.8 midlayer1_maxwidth=40 midlayer2_maxwidth=40 midlayer2_prefwidth=5 midlayer3_maxwidth=40 midlayer4_maxwidth=40 midlayer4_prefwidth=5 midlayer5_maxwidth=40 midlayer5_prefwidth=5 midlayer6_maxwidth=40 midlayer7_maxwidth=40 midlayer8_maxwidth=40 midlayer9_maxwidth=40 midlayer10_maxwidth=40 midlayer10_prefwidth=5 midlayer11_maxwidth=40 midlayer11_prefwidth=5 midlayer12_maxwidth=40 midlayer13_maxwidth=40 midlayer13_prefwidth=5 midlayer14_maxwidth=40 bottomlayer_prefwidth=6.8 minimp=50.000000 maximp=50.000000 favimp=50.000000
19 further rules are at their usual default settings.

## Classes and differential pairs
net class PHV: NetC19_2 NetC31_1 PHV_A PHV_B V_+50V_B V_+100V_A
net class MHV: MHV_A MHV_B NetC23_1 NetC35_2 V_-50V_B V_-100V_A
differential pair class 100ohm: A_SYNC A_SYNC_IC B_SYNC B_SYNC_IC CLK0_IC CLK0_R CLKIN0 TX1_CLK TX1_CLKIN TX2_CLK TX2_CLKIN
net class B_RX_IN: B_RX_IN1 B_RX_IN2 B_RX_IN3 B_RX_IN4 B_RX_IN5 B_RX_IN6 B_RX_IN7 B_RX_IN8 B_RX_IN9 B_RX_IN10 B_RX_IN11 B_RX_IN12 B_RX_IN13 B_RX_IN14 B_RX_IN15 B_RX_IN16
net class A_RX_IN: A_RX_IN1 A_RX_IN2 A_RX_IN3 A_RX_IN4 A_RX_IN5 A_RX_IN6 A_RX_IN7 A_RX_IN8 A_RX_IN9 A_RX_IN10 A_RX_IN11 A_RX_IN12 A_RX_IN13 A_RX_IN14 A_RX_IN15 A_RX_IN16
component class "Probe Header": J7 J8 J13 J14 J15 J16 J17 J18
component class Header: J4 J6 J19 J20 J21 J22
component class 25_RX_Connector: C471 C472 C473 C474 C475 C476 C477 C478 C479 C480 C481 C482 C483 C484 C485 C486 C487 C488 C489 C490 C491 C492 C493 C494 C495 C496 C497 C498 C499 C500 C501 C502 J11 J12 R42 R137 R146 R452 R458 R459 R460 R461 R462 R463 R464 R465 R466 R467 R468 R469 R470 R471 R472 R473 R474 R475 R476 R477 R478 R479 R480 R481 R482 R483 R484 R485
component class "24_TX_Connector(no load resitor)": J9 J10
component class 23_TMUX9832(65-128)_Pinout: C56 C299 C300 C301 C302 C303 C304 C305 C306 C387 C388 C389 C390 C391 C392 C393 C394 J15 J16 J17 J18 J20 J21 R160 R161 R162 R166 R167 R297 R298 R299 R494 R496 R500 R502 R504 TP38 TP39 U27 U30
component class 22_TMUX9832(0-64)_Pinout: C307 C308 C309 C310 C311 C312 C313 C314 C379 C380 C381 C382 C383 C384 C385 C386 J7 J8 J13 J14 J19 J22 R163 R164 R165 R294 R295 R296 R486 R488 R492 R509 R511 TP37 TP40 U28 U29
component class 21_TX7516_PartBPinout: C268 C269 C270 C271 C272 C273 C274 C275 C276 C277 C278 C279 C280 C281 C282 C283 C284 C285 C286 C287 C288 C289 C290 C291 C292 C293 C294 C295 C296 C297 C298 FB15 FB16 FB17 R157 R158 R159 TP33 TP34 TP35 U26
component class 20_TX7516_PartAPinout: C237 C238 C239 C240 C241 C242 C243 C244 C245 C246 C247 C248 C249 C250 C251 C252 C253 C254 C255 C256 C257 C258 C259 C260 C261 C262 C263 C264 C265 C266 C267 C459 FB12 FB13 FB14 R154 R155 R156 R430 R431 R432 R433 R434 R435 R436 R437 R438 R439 TP30 TP31 TP32 U25 U31
component class 19_Clock_Gen: C222 C223 C224 C225 C226 C227 C228 C229 C230 C231 C232 C233 C234 C235 C236 R147 R148 R149 R150 R151 R152 R153 U23 U24
component class 18_AM243x_Pinout: C216 C217 C218 C219 C220 C221 C463 C464 C465 J6 R145 R428 R429 R449 R450 R513 R514 U17 U20 U21 U22 U35 U36
component class 17_AM243x_SocPower: C129 C130 C131 C132 C133 C134 C135 C136 C137 C138 C139 C140 C141 C142 C143 C144 C145 C146 C147 C148 C149 C150 C151 C152 C153 C154 C155 C156 C157 C158 C159 C160 C161 C162 C163 C164 C165 C166 C167 C168 C169 C170 C171 C172 C173 C174 C175 C176 C177 C178 C179 C180 C181 C182 C183 C184 C185 C186 C187 C188 C189 C190 C191 C192 C193 C194 C195 C196 C197 C198 C199 C200 C201 C202 C203 C204 C205 C206 C207 C208 C209 C210 C211 C212 C213 C214 C215 FB3 FB4 FB5 FB6 FB7 FB8 FB9 FB10 FB11 R141 R142 R143 R144
component class 16_AM243x_Reset: C121 C122 C123 C124 C125 C126 C127 C128 C466 D32 D33 D34 R125 R126 R127 R128 R129 R130 R131 R132 R133 R134 R135 R136 R138 R139 R140 R448 R457 SW1 SW2 SW3 TP3 TP7 TP21 TP36 U18 U19
component class 15_AM243x_BootMode: C460 C461 C462 D30 D31 Q5 Q6 R89 R90 R91 R92 R93 R94 R95 R96 R97 R98 R99 R100 R101 R102 R103 R104 R105 R106 R107 R108 R109 R110 R111 R112 R113 R114 R115 R116 R117 R118 R119 R120 R121 R122 R123 R124 R443 R444 R445 R446 R447 S1 S2 U33 U34
component class 14_XDS110_Debugger: C97 C98 C99 C100 C101 C102 C103 C104 C105 C106 C107 C108 C109 C110 C111 C112 C113 C114 C115 C116 C117 C118 C119 C120 D28 D29 J5 R74 R75 R76 R77 R78 R79 R80 R81 R82 R83 R84 R85 R86 R87 R88 TP17 TP18 TP19 TP20 U12 U13 U14 U15 U16 Y1
component class 13_LowVoltage_PowerSupplies02: C81 C82 C83 C84 C86 C87 C88 C89 C90 C91 C92 C93 C94 C95 C96 D27 J4 L14 R60 R61 R62 R63 R64 R65 R66 R67 R68 R69 R70 R71 R72 R73 R451 TP9 TP10 TP11 TP12 TP13 TP14 TP15 U9 U10 U11
component class 12_LowVoltage_PowerSupplies01: C39 C40 C41 C42 C43 C44 C45 C46 C47 C48 C49 C50 C51 C52 C53 C54 C55 C58 C59 C60 C61 C62 C63 C64 C65 C66 C67 C68 C70 C71 C72 C73 C74 C75 C76 C77 C78 C79 C80 C467 D1 D25 D26 F1 J3 L11 L12 L13 R34 R35 R36 R37 R38 R39 R40 R41 R43 R44 R45 R46 R47 R48 R49 R50 R51 R52 R54 R55 R56 R57 R58 R59 R440 R441 R442 TP1 TP2 TP4 TP5 TP6 TP8 U5 U6 U7 U8 U32
component class 11_HighVoltage_PowerSupply: C1 C2 C3 C4 C5 C6 C7 C8 C9 C10 C11 C12 C13 C14 C15 C16 C17 C18 C19 C20 C21 C22 C23 C24 C25 C26 C27 C28 C29 C30 C31 C32 C33 C34 C35 C36 C37 C38 C503 C504 D9 D10 D11 D12 D13 D14 D15 D16 D17 D18 D19 D20 D21 D22 D23 D24 FB1 FB2 J1 J2 L1 L2 L3 L4 L5 L6 L7 L8 L9 L10 Q1 Q2 Q4 R1 R2 R3 R4 R5 R6 R7 R8 R9 R10 R11 R12 R13 R14 R15 R16 R17 R18 R19 R20 R21 R22 R23 R24 R25 R26 R27 R28 R29 R30 R31 R32 R33 R53 R512 U1 U2 U3 U4
net class U30B_TX_OUT_97_128: TX_OUT97 TX_OUT98 TX_OUT99 TX_OUT100 TX_OUT101 TX_OUT102 TX_OUT103 TX_OUT104 TX_OUT105 TX_OUT106 TX_OUT107 TX_OUT108 TX_OUT109 TX_OUT110 TX_OUT111 TX_OUT112 TX_OUT113 TX_OUT114 TX_OUT115 TX_OUT116 TX_OUT117 TX_OUT118 TX_OUT119 TX_OUT120 TX_OUT121 TX_OUT122 TX_OUT123 TX_OUT124 TX_OUT125 TX_OUT126 TX_OUT127 TX_OUT128
net class U29B_TX_OUT_01_32: TX_OUT1 TX_OUT2 TX_OUT3 TX_OUT4 TX_OUT5 TX_OUT6 TX_OUT7 TX_OUT8 TX_OUT9 TX_OUT10 TX_OUT11 TX_OUT12 TX_OUT13 TX_OUT14 TX_OUT15 TX_OUT16 TX_OUT17 TX_OUT18 TX_OUT19 TX_OUT20 TX_OUT21 TX_OUT22 TX_OUT23 TX_OUT24 TX_OUT25 TX_OUT26 TX_OUT27 TX_OUT28 TX_OUT29 TX_OUT30 TX_OUT31 TX_OUT32
net class U28B_TX_OUT_33_64: TX_OUT33 TX_OUT34 TX_OUT35 TX_OUT36 TX_OUT37 TX_OUT38 TX_OUT39 TX_OUT40 TX_OUT41 TX_OUT42 TX_OUT43 TX_OUT44 TX_OUT45 TX_OUT46 TX_OUT47 TX_OUT48 TX_OUT49 TX_OUT50 TX_OUT51 TX_OUT52 TX_OUT53 TX_OUT54 TX_OUT55 TX_OUT56 TX_OUT57 TX_OUT58 TX_OUT59 TX_OUT60 TX_OUT61 TX_OUT62 TX_OUT63 TX_OUT64
net class U27B_TX_OUT_65_96: TX_OUT65 TX_OUT66 TX_OUT67 TX_OUT68 TX_OUT69 TX_OUT70 TX_OUT71 TX_OUT72 TX_OUT73 TX_OUT74 TX_OUT75 TX_OUT76 TX_OUT77 TX_OUT78 TX_OUT79 TX_OUT80 TX_OUT81 TX_OUT82 TX_OUT83 TX_OUT84 TX_OUT85 TX_OUT86 TX_OUT87 TX_OUT88 TX_OUT89 TX_OUT90 TX_OUT91 TX_OUT92 TX_OUT93 TX_OUT94 TX_OUT95 TX_OUT96
net class B_TX_OUT: B_TX_OUT1 B_TX_OUT2 B_TX_OUT3 B_TX_OUT4 B_TX_OUT5 B_TX_OUT6 B_TX_OUT7 B_TX_OUT8 B_TX_OUT9 B_TX_OUT10 B_TX_OUT11 B_TX_OUT12 B_TX_OUT13 B_TX_OUT14 B_TX_OUT15 B_TX_OUT16
net class A_TX_OUT: A_TX_OUT1 A_TX_OUT2 A_TX_OUT3 A_TX_OUT4 A_TX_OUT5 A_TX_OUT6 A_TX_OUT7 A_TX_OUT8 A_TX_OUT9 A_TX_OUT10 A_TX_OUT11 A_TX_OUT12 A_TX_OUT13 A_TX_OUT14 A_TX_OUT15 A_TX_OUT16
component class Hardware: ZZ1 ZZ2 ZZ3 ZZ4
component class AssemblyNote: ZZ1 ZZ2 ZZ3 ZZ4
differential pair TX2_CLK: +TX2_CLK_P -TX2_CLK_N
differential pair TX2_CLKIN: +TX2_CLKIN_P -TX2_CLKIN_N
differential pair TX1_CLK: +TX1_CLK_P -TX1_CLK_N
differential pair TX1_CLKIN: +TX1_CLKIN_P -TX1_CLKIN_N
differential pair CLKIN0: +CLKIN0_P -CLKIN0_N
differential pair CLK0_R: +CLK0_R_P -CLK0_R_N
differential pair CLK0_IC: +CLK0_IC_P -CLK0_IC_N
differential pair B_SYNC: +B_SYNC_P -B_SYNC_N
differential pair B_SYNC_IC: +B_SYNC_IC_P -B_SYNC_IC_N
differential pair A_SYNC: +A_SYNC_P -A_SYNC_N
differential pair A_SYNC_IC: +A_SYNC_IC_P -A_SYNC_IC_N
differential pair USB_90: +XDS_USB_D_P -XDS_USB_D_N

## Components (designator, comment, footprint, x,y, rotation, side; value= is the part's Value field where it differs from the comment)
C1 "200LLE10MEFC8X11.5" CAPPRD350W60D800H1150 5707.49,3769.32 r270 top value=10uF
C2 "C1206C104K2RACTU" 1206 5980.09,3669.32 r270 top value=0.1uF
C3 "C0603X105J8RAC7867" 0603 3620.49,4630.32 r0 bottom value=1uF
C4 "C0603C104K8RACTU" 0603 3619.49,4692.32 r0 bottom value=0.1uF
C5 "200LLE10MEFC8X11.5" CAPPRD350W60D800H1150 5709.7,4705.82 r270 top value=10uF
C6 "C1206C104K2RACTU" 1206 5980.09,4539.32 r270 top value=0.1uF
C7 "C0603X105J8RAC7867" 0603 3325.49,4831.32 r180 bottom value=1uF
C8 "200LLE10MEFC8X11.5" CAPPRD350W60D800H1150 5707.49,4131.42 r270 top value=10uF
C9 "C1206C104K2RACTU" 1206 6104.89,4264.32 r90 top value=0.1uF
C10 "200LLE10MEFC8X11.5" CAPPRD350W60D800H1150 5707.49,5088.21 r270 top value=10uF
C11 "C1206C104K2RACTU" 1206 6097.49,5184.32 r90 top value=0.1uF
C12 "C0603X105J8RAC7867" 0603 3521.49,4890.32 r90 bottom value=1uF
C13 "C0603C104K8RACTU" 0603 3456.49,4890.32 r90 bottom value=0.1uF
C14 "C0603X105J8RAC7867" 0603 3326.49,4641.32 r180 bottom value=1uF
C15 "GRM31CR72A105KA01L" 1206_180 4210.19,5262.18 r90 top value=1uF
C16 "06033C105KAT2A" 0603 4612.49,5325.81 r270 bottom value=1uF
C17 "GRM21BZ71E106KE15L" 0805_HV 4467.49,5834.32 r270 top value=10uF
C18 "18122C105JAT2A" FP-1812Y2500105KXTWS2_1812-MFG 4617.49,4320.82 r180 top value=1µF
C19 "18122C105JAT2A" FP-1812Y2500105KXTWS2_1812-MFG 4615.76,4022.11 r180 top value=1µF
C20 "06033C101KAT2A" 0603 4762.49,5474.32 r90 bottom value=100pF
C21 "GRM31CR72A105KA01L" 1206_180 4027.29,5262.18 r90 top value=1uF
C22 "18122C105JAT2A" FP-1812Y2500105KXTWS2_1812-MFG 4084.5,4508.32 r225 top value=1µF
C23 "18122C105JAT2A" FP-1812Y2500105KXTWS2_1812-MFG 4203.8,4178.42 r180 top value=1µF
C24 "GRM188R71H224KAC4D" 0603 4748.4,5200.42 r270 bottom value=0.22uF
C25 "GRM188R72A682KA01D" 0603 4957.33,5408.41 r90 bottom value=6800pF
C26 "GRM188R72A104KA35D" 0603 4893.76,5541.91 r90 bottom value=0.1uF
C27 "GRM31CR72A105KA01L" 1206_180 5092.49,5249.32 r90 top value=1uF
C28 "06033C105KAT2A" 0603 5627.49,5497.82 r270 bottom value=1uF
C29 "GRM21BZ71E106KE15L" 0805_HV 5392.49,5834.32 r270 top value=10uF
C30 "C2012X7S2A105K125AE" 0805_HV 5272.49,4416.72 r0 top value=1uF
C31 "C2012X7S2A105K125AE" 0805_HV 5272.49,4181.72 r0 top value=1uF
C32 "06033C101KAT2A" 0603 5627.49,5704.32 r270 bottom value=100pF
C33 "GRM31CR72A105KA01L" 1206_180 4957.49,5249.32 r90 top value=1uF
C34 "C2012X7S2A105K125AE" 0805_HV 4996.9,4407.82 r0 top value=1uF
C35 "C2012X7S2A105K125AE" 0805_HV 4997.4,4182.02 r0 top value=1uF
C36 "GRM188R71H224KAC4D" 0603 5862.49,5716.32 r0 bottom value=0.22uF
C37 "885012206034" 0603 5622.49,5844.32 r90 bottom value=1000pF
C38 "885012206048" 0603 5757.49,5844.32 r270 bottom value=0.22uF
C39 "C0603C103K4RACTU" 0603 1678.61,5994.32 r90 top value=0.01uF
C40 "GRM1555C1E8R2CA01D" 0402 3112.15,6510.84 r270 top value=8.2pF
C41 "EEEFT1H470AP" Panasonic_D 5159.1,6169.42 r0 top value=47uF
C42 "CL10A226MO7JZNC" 0603 2078.51,6172.82 r270 top value=22uF
C43 "C0603C104M4RACTU" 0603 2143.51,6172.82 r270 top value=0.1uF
C44 "C1608X5R1H104K080AA" 0603 5097.49,6549.32 r0 top value=0.1uF
C45 "C3216X5R1E476M160AC" 1206_190 2713.51,6269.32 r270 top value=47uF
C46 "C0805C104M5RACTU" 0805_HV 2517.49,6284.4 r270 top value=0.1uF
C47 "C3216X5R1E476M160AC" 1206_190 2618.51,6269.32 r270 top value=47uF
C48 "UMK316BBJ106KL-T" 1206_190 3408.51,6279.32 r270 top value=10uF
C49 "C3216X7R1H475K160AC" 1206_180 2847.49,6269.32 r270 top value=4.7uF
C50 "C3216X7R1H475K160AC" 1206_180 3287.49,6279.23 r270 top value=4.7uF
C51 "C0805C104M5RACTU" 0805_HV 3197.49,6294.32 r270 top value=0.1uF
C52 "C0603C104K8RACTU" 0603 1739.66,6172.82 r270 top value=0.1uF
C53 "CL10A226MO7JZNC" 0603 1669.66,6172.82 r270 top value=22uF
C54 "GRM1885C1E102JA01D" 0603 2097.49,6064.32 r0 top value=1000pF
C55 "GRM155R61E105KA12D" 0402 3168.93,6510.84 r90 top value=1uF
C56 "Capacitor" 0603 3383.59,462.53 r0 top value=220pF
C57 "C0603C103K4RACTU" 0603 786.02,5943.04 r0 bottom value=0.01uF
C58 "C3216X7R1H475K160AC" 1206_180 3502.49,6279.32 r270 top value=4.7uF
C59 "C3216X7R1H475K160AC" 1206_180 3930.7,6283.73 r270 top value=4.7uF
C60 "C0805C104M5RACTU" 0805_HV 3840,6298.82 r270 top value=0.1uF
C61 "GRM1555C1E8R2CA01D" 0402 3598.72,6536.3 r270 top value=8.2pF
C62 "C0603C104K8RACTU" 0603 2834.06,5597.7 r270 top value=0.1uF
C63 "CL10A226MO7JZNC" 0603 2904.06,5597.7 r270 top value=22uF
C64 "C3216X5R1E476M160AC" 1206_190 3712.61,6085.89 r0 top value=47uF
C65 "C0805C104M5RACTU" 0805_HV 3697.61,5905.89 r0 top value=0.1uF
C66 "C3216X5R1E476M160AC" 1206_190 3712.61,5995.89 r0 top value=47uF
C67 "CL10A226MO7JZNC" 0603 3203.1,5594.42 r270 top value=22uF
C68 "C0603C104M4RACTU" 0603 3135,5594.42 r270 top value=0.1uF
C69 "C0603C104M4RACTU" 0603 850.6,6016.6 r180 bottom value=0.1uF
C70 "06033C105KAT2A" 0603 2904.06,5744.2 r90 top value=1uF
C71 "GRM155R61E105KA12D" 0402 3787.49,6536.3 r90 top value=1uF
C72 "GRM155R61E105KA12D" 0402 3902.49,6536.3 r90 top value=1uF
C73 "GRM155R71A104KA01D" 0402 2227.49,5637.94 r90 top value=0.1uF
C74 "C0805C106K8PACTU" 0805_HV 2482.49,5704.32 r90 top value=10uF
C75 "GRM155R71A104KA01D" 0402 2412.49,5679.32 r90 top value=0.1uF
C76 "CL10B333KO8NNNC" 0603 2299.06,5504.2 r270 top value=0.033uF
C77 "GRM188R61A106KE69D" 0603 1982.49,5159.32 r270 top value=10uF
C78 "GRM188R60J476ME15D" 0603 1632.49,5225.81 r270 top value=47uF
C79 "GRM033R61C104KE14D" 0201_033 1572.49,5232.31 r270 top value=0.1uF
C80 "GRM033R61C104KE14D" 0201_033 1532.49,5232.31 r270 top value=0.1uF
C81 "C3216X7R1H475K160AC" 1206_180 3227.41,4929.32 r180 top value=4.7uF
C82 "C3216X7R1H475K160AC" 1206_180 3227.49,5349.32 r180 top value=4.7uF
C83 "C0805C104M5RACTU" 0805_HV 3212.49,5029.32 r180 top value=0.1uF
C84 "GRM1555C1E8R2CA01D" 0402 3516.11,5112.88 r180 top value=8.2pF
C85 "C0603C104M4RACTU" 0603 1156.3,5798.02 r90 bottom value=0.1uF
C86 "C3216X5R1E476M160AC" 1206_190 3052.49,5019.32 r270 top value=47uF
C87 "C0805C104M5RACTU" 0805_HV 2947.49,5034.32 r270 top value=0.1uF
C88 "CL10A226MO7JZNC" 0603 2653.79,5098.81 r270 top value=22uF
C89 "C0603C104M4RACTU" 0603 2588.79,5098.81 r270 top value=0.1uF
C90 "C0603C104K8RACTU" 0603 2358.79,5098.81 r270 top value=0.1uF
C91 "CL10A226MO7JZNC" 0603 2283.79,5098.81 r270 top value=22uF
C92 "06033C105KAT2A" 0603 2493.79,5358.81 r90 top value=1uF
C93 "GRM155R61E105KA12D" 0402 3516.11,5057.88 r0 top value=1uF
C94 "GRM155R61E105KA12D" 0402 3516.11,4997.88 r0 top value=1uF
C95 "C1608X5R1A105K080AC" 0603 2567.49,4864.32 r90 top value=1uF
C96 "C1608X5R1A105K080AC" 0603 2287.49,4760.81 r270 top value=1uF
C97 "C1608X7R1C105K080AC" 0603 915.5,6501.61 r90 top value=1uF
C98 "C1608X7R1C105K080AC" 0603 1181.2,6399.82 r270 top value=1uF
C99 "C0603C104M4RACTU" 0603 1111.2,6401.32 r270 top value=0.1uF
C100 "202R18W102KV4E" 1206_190 331.9,6535.02 r90 top value=1000pF
C101 "C0603C103K4RACTU" 0603 1146.2,6501.32 r0 top value=0.01uF
C102 "C1608X7R1C105K080AC" 0603 447.03,5846.32 r180 top value=1uF
C103 "C0603C104M4RACTU" 0603 857.08,5328.34 r0 top value=0.1uF
C104 "C0603C104M4RACTU" 0603 431.2,5555.77 r180 top value=0.1uF
C105 "C0603C104M4RACTU" 0603 989.81,5328.34 r180 top value=0.1uF
C106 "C0603C104M4RACTU" 0603 1067,5594 r90 bottom value=0.1uF
C107 "C0603C104M4RACTU" 0603 1156.3,5656.67 r270 bottom value=0.1uF
C108 "C1608X7R1C105K080AC" 0603 731.89,5493.43 r0 bottom value=1uF
C109 "C0603C103K4RACTU" 0603 731.89,5558.43 r0 bottom value=0.01uF
C110 "C1608X7R1C105K080AC" 0603 557.53,5688.94 r90 bottom value=1uF
C111 "CC0603KRX7R7BB225" 0603 464.9,5688.94 r90 bottom value=2.2uF
C112 "C0603C103K4RACTU" 0603 635.71,5688.94 r90 bottom value=0.01uF
C113 "C0603C104M4RACTU" 0603 533.9,6100.32 r90 top value=0.1uF
C114 "C0603C104M4RACTU" 0603 968,3736.32 r0 top value=0.1uF
C115 "C0603C104M4RACTU" 0603 542.8,3721.62 r270 top value=0.1uF
C116 "C0603C104M4RACTU" 0603 359.79,5349.32 r0 top value=0.1uF
C117 "C0603C104M4RACTU" 0603 758.26,5249.43 r270 top value=0.1uF
C118 "C0603C103K4RACTU" 0603 690.56,5250.13 r270 top value=0.01uF
C119 "GRM1555C1E120JA01D" 0402 678.1,6121.72 r180 top value=12pF
C120 "GRM1555C1E120JA01D" 0402 780.2,6122.12 r0 top value=12pF
C121 "GRM033R61C104KE14D" 0201_033 1276.19,5077.73 r90 top value=0.1uF
C122 "GRM033R61C104KE14D" 0201_033 1022.1,4906.02 r270 top value=0.1uF
C123 "C0603C105K4PACTU" 0603 1165.69,4729.72 r270 top value=1uF
C124 "GRM1885C1H242JA01D" 0603 1379.69,4729.72 r270 top value=2400pF
C125 "GRM1885C1H242JA01D" 0603 1315.19,4729.72 r270 top value=2400pF
C126 "GRM1885C1H242JA01D" 0603 1249.69,4729.72 r270 top value=2400pF
C127 "C0603C105K4PACTU" 0603 1434,3472.42 r0 top value=1uF
C128 "GRM033R61C104KE14D" 0201_033 1668,4219.31 r90 top value=0.1uF
C129 "GRM155R61A105KE15D" 0402 1793.8,3928.12 r180 bottom value=1uF
C130 "GRM155R61A105KE15D" 0402 2034.9,3694.54 r270 bottom value=1uF
C131 "GRM155R61A105KE15D" 0402 2304.11,3817.32 r0 bottom value=1uF
C132 "GRM155R61A105KE15D" 0402 2299.4,3982.72 r0 top value=1uF
C133 "GRM155R61A105KE15D" 0402 2170.49,4186.32 r90 bottom value=1uF
C134 "GRM155R61A105KE15D" 0402 2127.49,4186.32 r90 bottom value=1uF
C135 "GRM155R61A105KE15D" 0402 1749.49,3842.32 r180 bottom value=1uF
C136 "C1608X7S1A335K080AC" 0603 2027.8,4188.61 r270 bottom value=3.3uF
C137 "GRM033R61C104KE84D" 0201_033 1470.1,4185.62 r90 top value=0.1uF
C138 "GRM033R61C104KE84D" 0201_033 1971.2,4133.62 r90 bottom value=0.1uF
C139 "GRM033R71E103KE14D" 0201 1947.3,3980.82 r135 bottom value=0.01uF
C140 "GRM155R61A475MEAAD" 0402 1829.49,4147.94 r90 bottom value=4.7uF
C141 "GRM033R61C104KE84D" 0201_033 1899.49,3933.32 r180 bottom value=0.1uF
C142 "GRM033R61C104KE84D" 0201_033 1787.49,4130.31 r90 bottom value=0.1uF
C143 "GRM033R71E103KE14D" 0201 1867.8,4054.52 r180 bottom value=0.01uF
C144 "GRM155R61A475MEAAD" 0402 1728.49,4007.94 r90 bottom value=4.7uF
C145 "GRM033R61C104KE84D" 0201_033 1685.99,4024.32 r90 bottom value=0.1uF
C146 "GRM033R61C104KE84D" 0201_033 1814.7,3970.41 r90 bottom value=0.1uF
C147 "GRM033R71E103KE14D" 0201 1789.3,3970.41 r90 bottom value=0.01uF
C148 "GRM155R61A475MEAAD" 0402 1685.49,3821.32 r90 bottom value=4.7uF
C149 "GRM033R61C104KE84D" 0201_033 2037.49,3888.32 r90 bottom value=0.1uF
C150 "GRM033R61C104KE84D" 0201_033 1766.49,3798.32 r90 bottom value=0.1uF
C151 "GRM033R71E103KE14D" 0201 1732.49,3798.32 r90 bottom value=0.01uF
C152 "GRM155R61A475MEAAD" 0402 2266.11,3978.32 r0 bottom value=4.7uF
C153 "GRM033R61C104KE84D" 0201_033 2076.49,3876.32 r0 bottom value=0.1uF
C154 "GRM033R71E103KE14D" 0201 2245.49,4021.32 r0 bottom value=0.01uF
C155 "GRM155R61A106ME44" 0402_070 1869.5,3569.32 r180 bottom value=10uF
C156 "GRM155R61A475MEAAD" 0402 1996.49,3569.32 r0 bottom value=4.7uF
C157 "GRM033R61C104KE84D" 0201_033 1962.49,3779.32 r0 bottom value=0.1uF
C158 "GRM033R61C104KE84D" 0201_033 1964.5,3739.32 r0 bottom value=0.1uF
C159 "GRM033R61C104KE84D" 0201_033 1977.49,3609.32 r0 bottom value=0.1uF
C160 "GRM033R61C104KE84D" 0201_033 2055.49,3802.32 r270 bottom value=0.1uF
C161 "GRM033R61C104KE84D" 0201_033 1897.49,3794.32 r90 bottom value=0.1uF
C162 "GRM033R61C104KE84D" 0201_033 1962.49,3804.32 r0 bottom value=0.1uF
C163 "GRM033R61C104KE84D" 0201_033 1984,3948.52 r90 bottom value=0.1uF
C164 "GRM033R61C104KE84D" 0201_033 1977.49,3689.32 r0 bottom value=0.1uF
C165 "GRM033R61C104KE84D" 0201_033 1923.49,3767.31 r90 bottom value=0.1uF
C166 "GRM033R61C104KE84D" 0201_033 1943.5,3889.32 r180 bottom value=0.1uF
C167 "GRM033R61C104KE84D" 0201_033 1877.05,3605.43 r180 bottom value=0.1uF
C168 "GRM033R61C104KE84D" 0201_033 1977.49,3649.32 r0 bottom value=0.1uF
C169 "GRM033R61C104KE84D" 0201_033 2047.49,3969.32 r90 bottom value=0.1uF
C170 "GRM033R61C104KE84D" 0201_033 2024,3959.11 r90 bottom value=0.1uF
C171 "GRM033R61C104KE84D" 0201_033 1997.6,3864.22 r90 bottom value=0.1uF
C172 "GRM033R61C104KE84D" 0201_033 1877.05,3689.32 r180 bottom value=0.1uF
C173 "GRM033R61C104KE84D" 0201_033 1992.5,3912.92 r0 bottom value=0.1uF
C174 "GRM033R71E103KE14D" 0201 2023.49,3802.32 r270 bottom value=0.01uF
C175 "GRM033R71E103KE14D" 0201 1877.05,3647.37 r180 bottom value=0.01uF
C176 "GRM033R71E103KE14D" 0201 2087.49,3834.32 r270 bottom value=0.01uF
C177 "GRM033R61C104KE84D" 0201_033 1995.17,4089.63 r180 bottom value=0.1uF
C178 "GRM033R61C104KE84D" 0201_033 1995,4065.02 r180 bottom value=0.1uF
C179 "GRM155R61A475MEAAD" 0402 1686.49,3715.94 r270 bottom value=4.7uF
C180 "GRM033R61C104KE84D" 0201_033 1730.49,3737.32 r270 bottom value=0.1uF
C181 "GRM033R71E103KE14D" 0201 1880.2,3848.01 r90 bottom value=0.01uF
C182 "GRM155R61A475MEAAD" 0402 1912,4138 r90 bottom value=4.7uF
C183 "GRM033R61C104KE84D" 0201_033 1916.7,4059.32 r90 bottom value=0.1uF
C184 "GRM033R61C104KE84D" 0201_033 1872.49,4123.32 r90 bottom value=0.1uF
C185 "GRM033R71E103KE14D" 0201 1904.49,4206.32 r180 bottom value=0.01uF
C186 "GRM155R61A475MEAAD" 0402 1727.49,3899.32 r270 bottom value=4.7uF
C187 "GRM033R61C104KE84D" 0201_033 1769.49,3889.31 r270 bottom value=0.1uF
C188 "GRM033R71E103KE14D" 0201 1802.49,3887.52 r270 bottom value=0.01uF
C189 "GRM155R61A475MEAAD" 0402 2270.49,4087.94 r90 bottom value=4.7uF
C190 "GRM033R61C104KE84D" 0201_033 2189.99,4067.81 r90 bottom value=0.1uF
C191 "GRM033R71E103KE14D" 0201 2234.7,4071.42 r90 bottom value=0.01uF
C192 "GRM155R61A475MEAAD" 0402 1722.87,3642.32 r180 bottom value=4.7uF
C193 "GRM033R61C104KE84D" 0201_033 2113.49,3617.32 r180 bottom value=0.1uF
C194 "GRM033R61C104KE84D" 0201_033 2113.49,3657.32 r180 bottom value=0.1uF
C195 "GRM033R61C104KE84D" 0201_033 2113.49,3695.32 r180 bottom value=0.1uF
C196 "GRM033R61C104KE84D" 0201_033 2120.49,3777.32 r270 bottom value=0.1uF
C197 "GRM033R61C104KE84D" 0201_033 2001.49,3738.32 r270 bottom value=0.1uF
C198 "GRM033R61C104KE84D" 0201_033 1742.48,3682.32 r180 bottom value=0.1uF
C199 "GRM033R61C104KE84D" 0201_033 1814.3,4046.02 r90 bottom value=0.1uF
C200 "GRM033R61C104KE84D" 0201_033 2191.49,3657.32 r0 bottom value=0.1uF
C201 "GRM033R61C104KE84D" 0201_033 1869.29,3741.32 r315 bottom value=0.1uF
C202 "GRM033R61C104KE84D" 0201_033 2174.49,3814.32 r0 bottom value=0.1uF
C203 "GRM033R61C104KE84D" 0201_033 2174.48,3849.32 r0 bottom value=0.1uF
C204 "GRM033R61C104KE84D" 0201_033 1790.69,4045.62 r90 bottom value=0.1uF
C205 "GRM033R61C104KE84D" 0201_033 2162.82,4067.81 r90 bottom value=0.1uF
C206 "GRM033R61C104KE84D" 0201_033 2174.48,3779.32 r0 bottom value=0.1uF
C207 "GRM033R61C104KE84D" 0201_033 2174.48,3744.32 r0 bottom value=0.1uF
C208 "GRM033R61C104KE84D" 0201_033 2081.32,4067.81 r90 bottom value=0.1uF
C209 "GRM033R61C104KE84D" 0201_033 2174.48,3873.32 r0 bottom value=0.1uF
C210 "GRM033R71E103KE14D" 0201 2108.49,4067.81 r90 bottom value=0.01uF
C211 "GRM033R71E103KE14D" 0201 2191.49,3695.32 r0 bottom value=0.01uF
C212 "GRM033R71E103KE14D" 0201 2135.66,4067.81 r90 bottom value=0.01uF
C213 "GRM155R61A475MEAAD" 0402 2265.4,3885.92 r270 bottom value=4.7uF
C214 "GRM033R61C104KE84D" 0201_033 2174.5,3899.32 r0 bottom value=0.1uF
C215 "GRM033R71E103KE14D" 0201 2228.9,3905.11 r270 bottom value=0.01uF
C216 "GRM033R61C104KE84D" 0201_033 907.2,3484.22 r270 top value=0.1uF
C217 "GRM033R61C104KE84D" 0201_033 578.9,3480.92 r270 top value=0.1uF
C218 "GRM033R61C104KE84D" 0201_033 815.4,3374.32 r270 top value=0.1uF
C219 "GRM033R61C104KE84D" 0201_033 707.2,3373.32 r270 top value=0.1uF
C220 "GRM033R61C104KE84D" 0201_033 771.1,3355.31 r90 top value=0.1uF
C221 "GRM033R61C104KE84D" 0201_033 747.5,3355.31 r90 top value=0.1uF
C222 "520L103KT16T" 0402_065 2450.89,2552.63 r180 bottom value=0.01uF
C223 "C0402C104K8RACTU" 0402 2183.45,2378.73 r180 bottom value=0.1uF
C224 "520L103KT16T" 0402_065 2450.89,2499.63 r180 bottom value=0.01uF
C225 "C0402C104K8RACTU" 0402 2577.05,2391.23 r270 top value=0.1uF
C226 "C0402C104K8RACTU" 0402 2463.77,2583.03 r180 top value=0.1uF
C227 "C0402C104K8RACTU" 0402 2463.77,2641.03 r180 top value=0.1uF
C228 "C0402C104K8RACTU" 0402 2829.87,2541.21 r0 top value=0.1uF
C229 "C0402C104K8RACTU" 0402 2689.15,2391.23 r270 top value=0.1uF
C230 "C0402C104K8RACTU" 0402 2829.87,2491.47 r0 top value=0.1uF
C231 "C0402C104K8RACTU" 0402 2829.87,2590.95 r0 top value=0.1uF
C232 "C0402C104K8RACTU" 0402 2463.77,2699.03 r180 top value=0.1uF
C233 "C0402C104K8RACTU" 0402 2735.05,2391.23 r270 top value=0.1uF
C234 "C0402C104K8RACTU" 0402 2829.87,2441.73 r0 top value=0.1uF
C235 "C0402C104K8RACTU" 0402 2829.87,2703.43 r0 top value=0.1uF
C236 "C0402C104K8RACTU" 0402 2634.55,2757.53 r90 top value=0.1uF
C237 "520L103KT16T" 0402_065 2101.24,2499.03 r90 top value=0.01uF
C238 "520L103KT16T" 0402_065 2154.24,2499.03 r90 top value=0.01uF
C239 "C0603C102K3GACTU" 0603 1714.24,2307.04 r90 top value=1000pF
C240 "C0603C102K3GACTU" 0603 2525.24,2309.03 r90 top value=1000pF
C241 "C0603C102K3GACTU" 0603 2401.28,2309.03 r90 top value=1000pF
C242 "C2012X7T2E104K125AA" 0805_HV 2429.25,1710.53 r270 top value=0.1uF
C243 "C2012X7T2E104K125AA" 0805_HV 2342.25,1710.53 r270 top value=0.1uF
C244 "C2012X7T2E104K125AA" 0805_HV 1843.75,1710.53 r270 top value=0.1uF
C245 "C2012X7T2E104K125AA" 0805_HV 1758.75,1710.53 r270 top value=0.1uF
C246 "C2012X7T2E104K125AA" 0805_HV 1973.75,1673.9 r270 top value=0.1uF
C247 "C2012X7T2E104K125AA" 0805_HV 2057.08,1673.9 r270 top value=0.1uF
C248 "C2012X7T2E104K125AA" 0805_HV 2140.41,1673.9 r270 top value=0.1uF
C249 "C2012X7T2E104K125AA" 0805_HV 2223.75,1673.9 r270 top value=0.1uF
C250 "C0603X6S1C104K030BC" 0201_033 1995.84,2329.64 r0 top value=0.1uF
C251 "C0603X6S1C104K030BC" 0201_033 1995.84,2363.63 r0 top value=0.1uF
C252 "C0603X6S1C104K030BC" 0201_033 1995.84,2295.63 r0 top value=0.1uF
C253 "C0603X6S1C104K030BC" 0201_033 1995.84,2261.63 r0 top value=0.1uF
C254 "C0603X6S1C104K030BC" 0201_033 2222.24,2326.7 r180 top value=0.1uF
C255 "C0603X6S1C104K030BC" 0201_033 2222.24,2292.37 r180 top value=0.1uF
C256 "C0603X6S1C104K030BC" 0201_033 2222.24,2258.03 r180 top value=0.1uF
C257 "C0603X6S1C104K030BC" 0201_033 2222.24,2361.03 r180 top value=0.1uF
C258 "C2012X7T2E104K125AA" 0805_HV 2492.34,2082.42 r0 top value=0.1uF
C259 "C2012X7T2E104K125AA" 0805_HV 1711.03,2167.42 r180 top value=0.1uF
C260 "C2012X7T2E104K125AA" 0805_HV 2492.52,2167.42 r0 top value=0.1uF
C261 "C2012X7T2E104K125AA" 0805_HV 1711.03,2082.42 r180 top value=0.1uF
C262 "C2012X7T2E104K125AA" 0805_HV 2493.12,1967.52 r0 top value=0.1uF
C263 "C2012X7T2E104K125AA" 0805_HV 2493.12,1882.52 r0 top value=0.1uF
C264 "C2012X7T2E104K125AA" 0805_HV 1711.03,1967.52 r180 top value=0.1uF
C265 "C2012X7T2E104K125AA" 0805_HV 1711.03,1882.52 r180 top value=0.1uF
C266 "C0603X6S1C104K030BC" 0201_033 2047.25,2260.93 r180 top value=0.1uF
C267 "C0603X6S1C104K030BC" 0201_033 2047.25,2296.03 r180 top value=0.1uF
C268 "520L103KT16T" 0402_065 3178.35,2478.91 r90 top value=0.01uF
C269 "520L103KT16T" 0402_065 3229.35,2478.91 r90 top value=0.01uF
C270 "C0603C102K3GACTU" 0603 2853.64,2303.34 r90 top value=1000pF
C271 "C0603C102K3GACTU" 0603 3582.88,2303.34 r90 top value=1000pF
C272 "C0603C102K3GACTU" 0603 3458.76,2303.34 r90 top value=1000pF
C273 "C2012X7T2E104K125AA" 0805_HV 3526.64,1710.53 r270 top value=0.1uF
C274 "C2012X7T2E104K125AA" 0805_HV 2825.64,1710.53 r270 top value=0.1uF
C275 "C2012X7T2E104K125AA" 0805_HV 2915.64,1710.53 r270 top value=0.1uF
C276 "C2012X7T2E104K125AA" 0805_HV 3439.64,1710.53 r270 top value=0.1uF
C277 "C2012X7T2E104K125AA" 0805_HV 3309.84,1673.9 r270 top value=0.1uF
C278 "C2012X7T2E104K125AA" 0805_HV 3226.51,1673.9 r270 top value=0.1uF
C279 "C2012X7T2E104K125AA" 0805_HV 3143.18,1673.9 r270 top value=0.1uF
C280 "C2012X7T2E104K125AA" 0805_HV 3059.84,1673.9 r270 top value=0.1uF
C281 "C0603X6S1C104K030BC" 0201_033 3088.63,2362.83 r0 top value=0.1uF
C282 "C0603X6S1C104K030BC" 0201_033 3088.63,2255.83 r0 top value=0.1uF
C283 "C0603X6S1C104K030BC" 0201_033 3088.63,2291.5 r0 top value=0.1uF
C284 "C0603X6S1C104K030BC" 0201_033 3088.63,2327.17 r0 top value=0.1uF
C285 "C0603X6S1C104K030BC" 0201_033 3273.23,2380.12 r180 top value=0.1uF
C286 "C0603X6S1C104K030BC" 0201_033 3273.23,2318.34 r180 top value=0.1uF
C287 "C0603X6S1C104K030BC" 0201_033 3273.23,2287.44 r180 top value=0.1uF
C288 "C0603X6S1C104K030BC" 0201_033 3273.23,2349.23 r180 top value=0.1uF
C289 "C2012X7T2E104K125AA" 0805_HV 2784.05,2082.42 r180 top value=0.1uF
C290 "C2012X7T2E104K125AA" 0805_HV 2784.05,2167.42 r180 top value=0.1uF
C291 "C2012X7T2E104K125AA" 0805_HV 3568.69,2167.42 r0 top value=0.1uF
C292 "C2012X7T2E104K125AA" 0805_HV 3568.69,2082.42 r0 top value=0.1uF
C293 "C2012X7T2E104K125AA" 0805_HV 2784.05,1881.26 r180 top value=0.1uF
C294 "C2012X7T2E104K125AA" 0805_HV 2784.05,1966.26 r180 top value=0.1uF
C295 "C2012X7T2E104K125AA" 0805_HV 3568.69,1881.26 r0 top value=0.1uF
C296 "C2012X7T2E104K125AA" 0805_HV 3568.69,1966.26 r0 top value=0.1uF
C297 "C0603X6S1C104K030BC" 0201_033 3141.26,2256.83 r180 top value=0.1uF
C298 "C0603X6S1C104K030BC" 0201_033 3141.26,2292.5 r180 top value=0.1uF
C299 "C0805C105K4RACAUTO" 0805_HV 3302.69,1483.7 r90 top value=1uF
C300 "C0603X6S1C104K030BC" 0201_033 3192.59,1445.77 r90 top value=0.1uF
C301 "C0603X6S1C104K030BC" 0201_033 3243.79,1445.77 r90 top value=0.1uF
C302 "C0603X6S1C104K030BC" 0201_033 3218.19,1445.77 r90 top value=0.1uF
C303 "C0805C105K4RACAUTO" 0805_HV 2916.79,1483.7 r90 top value=1uF
C304 "C0603X6S1C104K030BC" 0201_033 3006.54,1445.77 r90 top value=0.1uF
C305 "C0603X6S1C104K030BC" 0201_033 2977.89,1445.77 r90 top value=0.1uF
C306 "C0603X6S1C104K030BC" 0201_033 3035.19,1445.77 r90 top value=0.1uF
C307 "C0805C105K4RACAUTO" 0805_HV 2384.49,1485.6 r90 top value=1uF
C308 "C0603X6S1C104K030BC" 0201_033 2322.09,1441.55 r90 top value=0.1uF
C309 "C0603X6S1C104K030BC" 0201_033 2272.09,1441.55 r90 top value=0.1uF
C310 "C0603X6S1C104K030BC" 0201_033 2297.09,1441.55 r90 top value=0.1uF
C311 "C0805C105K4RACAUTO" 0805_HV 1976.89,1481.6 r90 top value=1uF
C312 "C0603X6S1C104K030BC" 0201_033 2040.29,1441.39 r90 top value=0.1uF
C313 "C0603X6S1C104K030BC" 0201_033 2098.79,1441.39 r90 top value=0.1uF
C314 "C0603X6S1C104K030BC" 0201_033 2069.54,1441.39 r90 top value=0.1uF
C315 "GRM31CR72A105KA01L" 1206_180 4301.63,5262.18 r90 top value=1uF
C316 "GRM31CR72A105KA01L" 1206_180 4118.74,5262.18 r90 top value=1uF
C317 "GRM31CR72A105KA01L" 1206_180 3935.84,5262.18 r90 top value=1uF
C318 "GRM31CR72A105KA01L" 1206_180 3985.71,5415.7 r0 top value=1uF
C379 "C0805C105K4RACAUTO" 0805_HV 1582.89,1479.6 r90 top value=1uF
C380 "C0603X6S1C104K030BC" 0201_033 1494.39,1441.67 r90 top value=0.1uF
C381 "C0603X6S1C104K030BC" 0201_033 1518.39,1441.67 r90 top value=0.1uF
C382 "C0603X6S1C104K030BC" 0201_033 1470.39,1441.67 r90 top value=0.1uF
C383 "C0805C105K4RACAUTO" 0805_HV 1156.29,1479.6 r90 top value=1uF
C384 "C0603X6S1C104K030BC" 0201_033 1295.29,1441.67 r90 top value=0.1uF
C385 "C0603X6S1C104K030BC" 0201_033 1268.8,1441.67 r90 top value=0.1uF
C386 "C0603X6S1C104K030BC" 0201_033 1242.29,1441.4 r90 top value=0.1uF
C387 "C0805C105K4RACAUTO" 0805_HV 4115.19,1496.9 r90 top value=1uF
C388 "C0603X6S1C104K030BC" 0201_033 3994.89,1446.47 r90 top value=0.1uF
C389 "C0603X6S1C104K030BC" 0201_033 4049.49,1446.47 r90 top value=0.1uF
C390 "C0603X6S1C104K030BC" 0201_033 4022.19,1446.47 r90 top value=0.1uF
C391 "C0805C105K4RACAUTO" 0805_HV 3689.59,1483.7 r90 top value=1uF
C392 "C0603X6S1C104K030BC" 0201_033 3753.69,1445.77 r90 top value=0.1uF
C393 "C0603X6S1C104K030BC" 0201_033 3821.69,1445.77 r90 top value=0.1uF
C394 "C0603X6S1C104K030BC" 0201_033 3787.69,1445.77 r90 top value=0.1uF
C459 "GRM033R61C104KE84D" 0201_033 1278.25,2510.63 r180 bottom value=0.1uF
C460 "GRM155R61A475MEAAD" 0402 2111.1,4551.8 r270 top value=4.7uF
C461 "GRM033R61C104KE14D" 0201_033 2071.99,4574.31 r270 top value=0.1uF
C462 "GRM033R61C104KE14D" 0201_033 1942.21,4442.42 r0 top value=0.1uF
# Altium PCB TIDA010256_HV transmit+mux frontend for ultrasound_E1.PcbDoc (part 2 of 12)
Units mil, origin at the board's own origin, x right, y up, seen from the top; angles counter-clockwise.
Board outline 6192.49 x 6712.23 mil, 16 copper layers (Top Layer, Layer 2 - GND, Layer 3 - SIG, Layer 4 - GND, Layer 5 - SIG, Layer 6 - SIG, Layer 7 - GND, Layer 8 - HV PWR, Layer 9 - LV PWR, Layer 10 - GND, Layer 11 - SIG, Layer 12 - SIG, Layer 13 - GND, Layer 14 - SIG, Layer 15 - GND, Bottom Layer), stack 95.905 mil thick; 806 components, 539 nets, 3343 pads, 1848 vias.

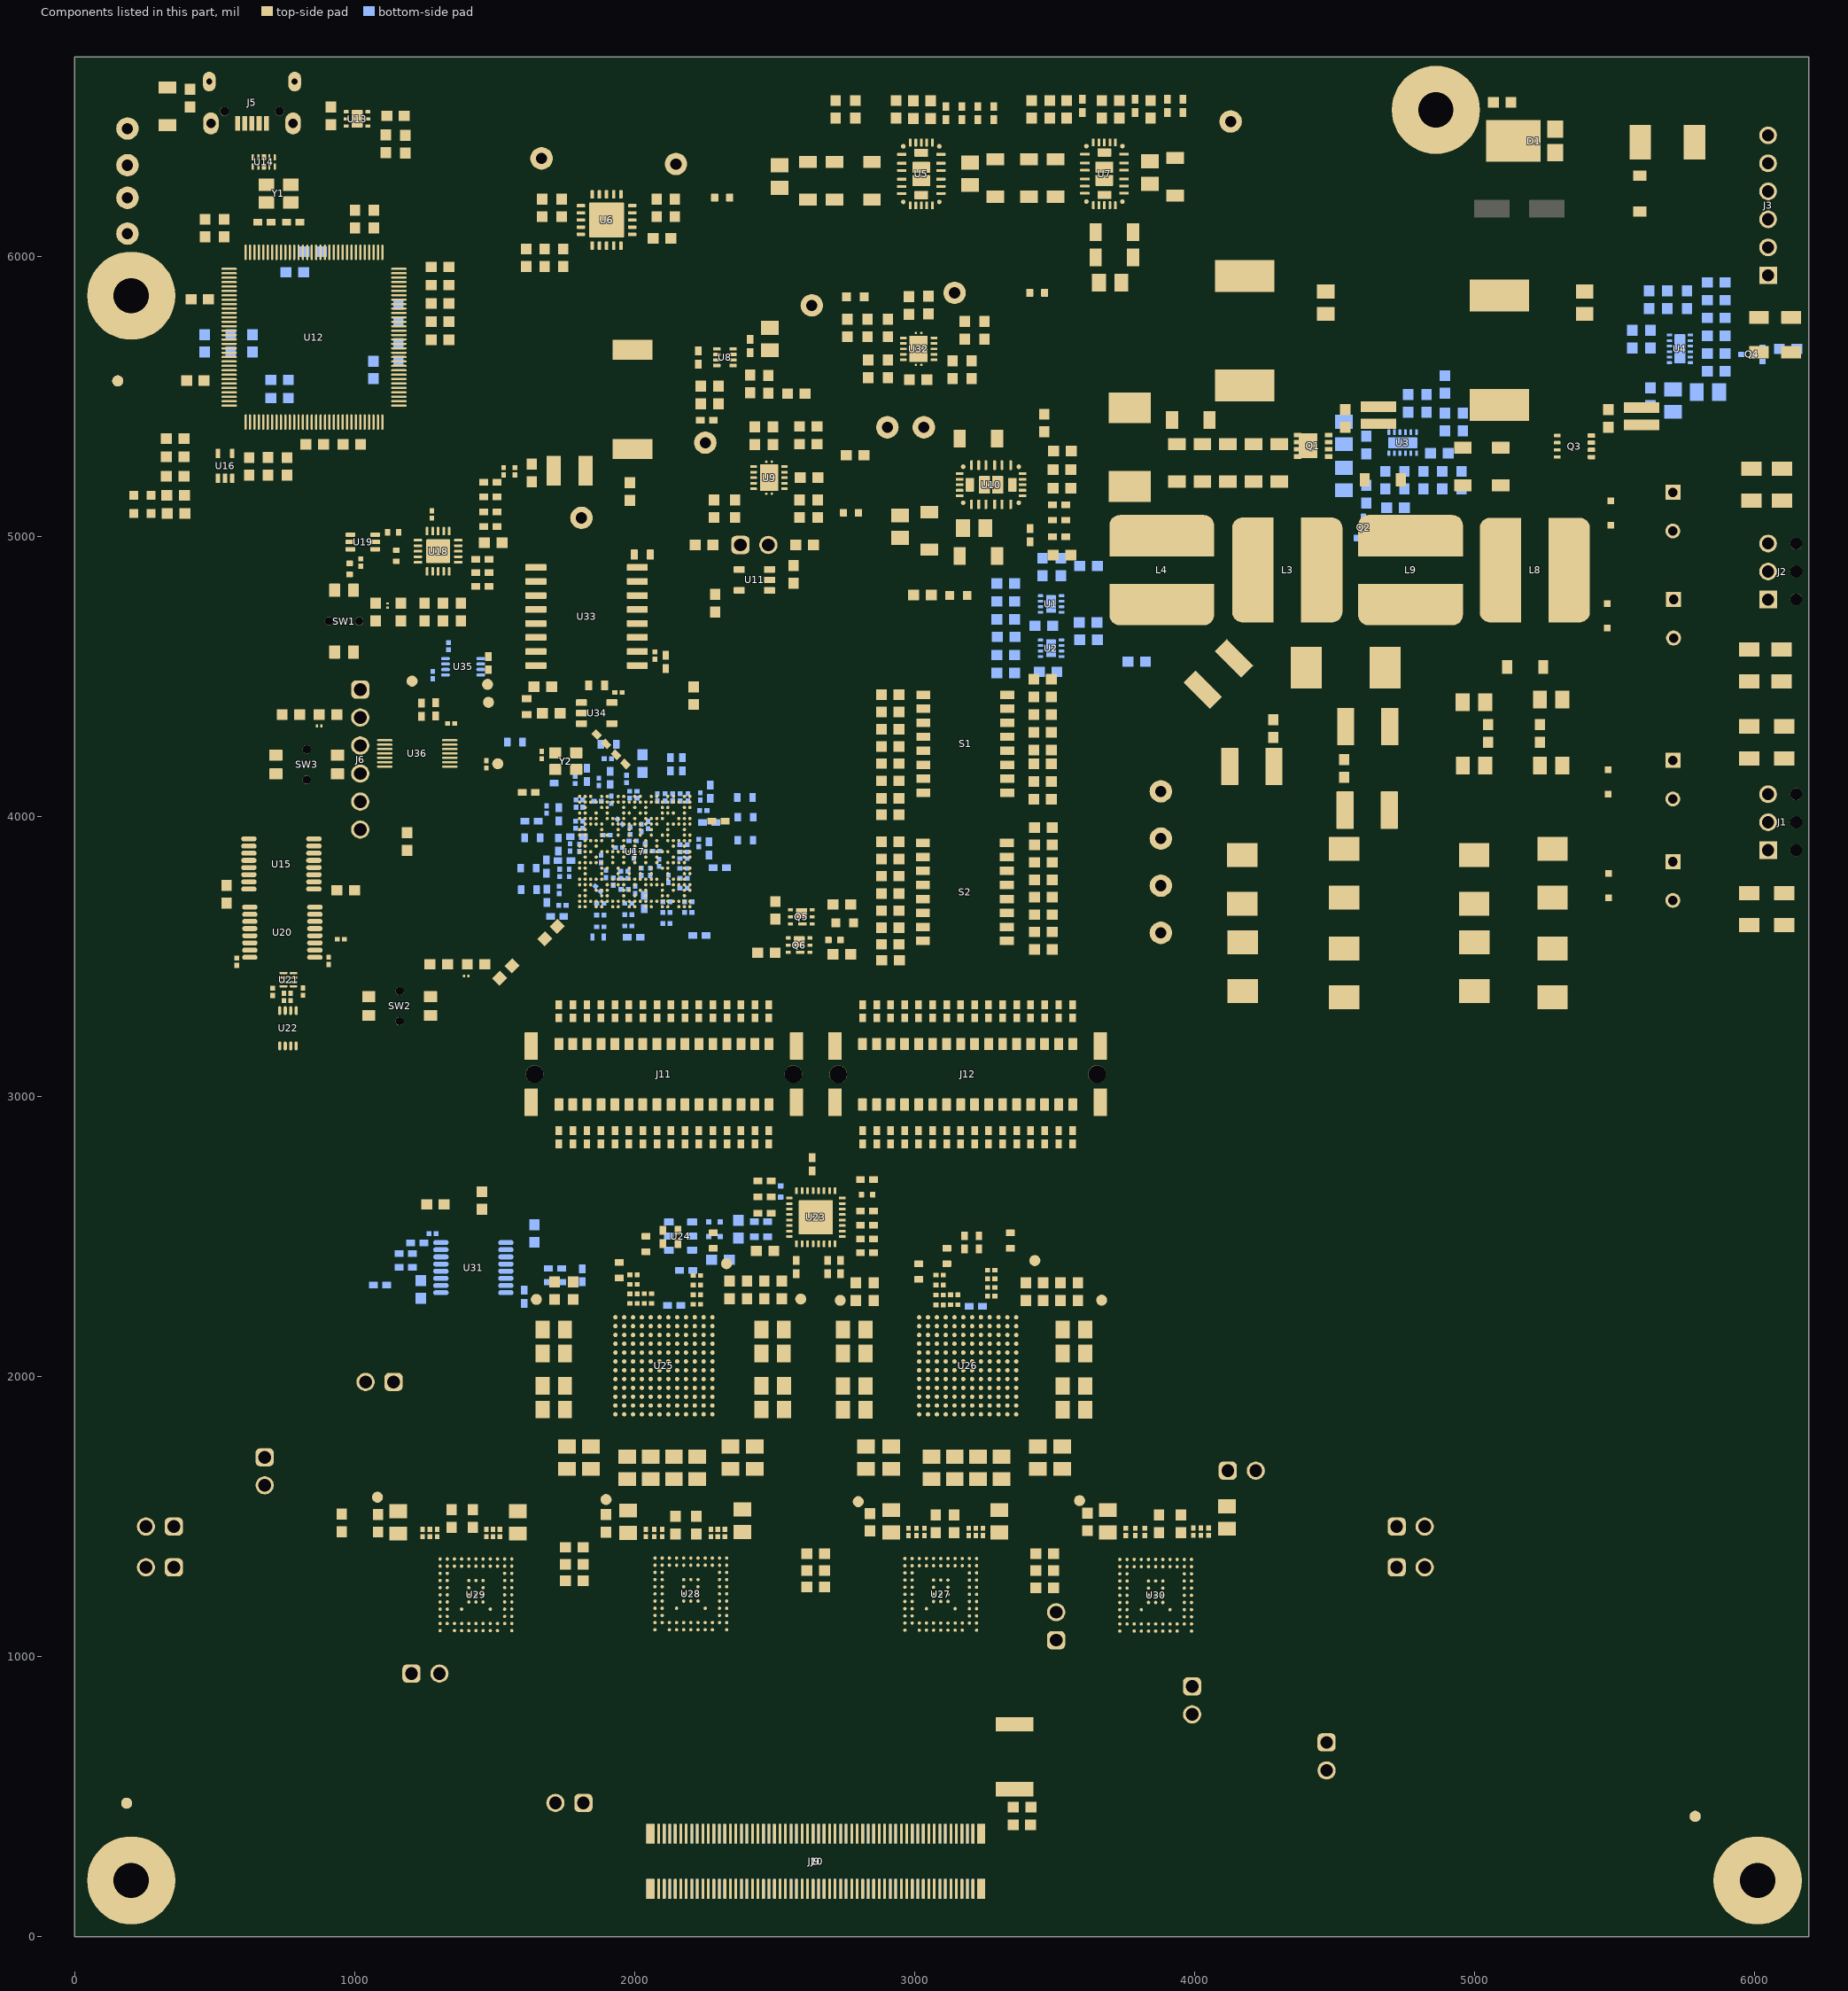
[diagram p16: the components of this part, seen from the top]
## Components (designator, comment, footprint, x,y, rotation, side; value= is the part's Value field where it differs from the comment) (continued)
C463 "GRM033R61C104KE84D" 0201_033 1335.1,4607.81 r90 bottom value=0.1uF
C464 "GRM033R61C104KE84D" 0201_033 1279.49,4504.31 r270 bottom value=0.1uF
C465 "GRM033R61C104KE84D" 0201_033 1344.7,4332.22 r180 top value=0.1uF
C466 "C0603C105K4PACTU" 0603 772.7,4363.32 r180 top value=1uF
C467 "CL10B333KO8NNNC" 0603 2412.49,5544.32 r270 top value=0.033uF
C471 "C0402C200J5GACTU" 0402 1779.5,3304.4 r90 top value=20pF
C472 "C0402C200J5GACTU" 0402 2479.5,2854.62 r270 top value=20pF
C473 "C0402C200J5GACTU" 0402 2864.03,3304.4 r90 top value=20pF
C474 "C0402C200J5GACTU" 0402 3564.03,2854.62 r270 top value=20pF
C475 "C0402C200J5GACTU" 0402 1779.5,2854.62 r270 top value=20pF
C476 "C0402C200J5GACTU" 0402 2479.5,3304.4 r90 top value=20pF
C477 "C0402C200J5GACTU" 0402 2864.03,2854.62 r270 top value=20pF
C478 "C0402C200J5GACTU" 0402 3564.03,3304.4 r90 top value=20pF
C479 "C0402C200J5GACTU" 0402 1879.5,3304.4 r90 top value=20pF
C480 "C0402C200J5GACTU" 0402 2379.5,2854.62 r270 top value=20pF
C481 "C0402C200J5GACTU" 0402 2964.03,3304.4 r90 top value=20pF
C482 "C0402C200J5GACTU" 0402 3464.03,2854.62 r270 top value=20pF
C483 "C0402C200J5GACTU" 0402 1879.5,2854.62 r270 top value=20pF
C484 "C0402C200J5GACTU" 0402 2379.5,3304.4 r90 top value=20pF
C485 "C0402C200J5GACTU" 0402 2964.03,2854.62 r270 top value=20pF
C486 "C0402C200J5GACTU" 0402 3464.03,3304.4 r90 top value=20pF
C487 "C0402C200J5GACTU" 0402 1979.5,3304.4 r90 top value=20pF
C488 "C0402C200J5GACTU" 0402 2279.5,2854.62 r270 top value=20pF
C489 "C0402C200J5GACTU" 0402 3064.03,3304.4 r90 top value=20pF
C490 "C0402C200J5GACTU" 0402 3364.03,2854.62 r270 top value=20pF
C491 "C0402C200J5GACTU" 0402 1979.5,2854.62 r270 top value=20pF
C492 "C0402C200J5GACTU" 0402 2279.49,3304.4 r90 top value=20pF
C493 "C0402C200J5GACTU" 0402 3064.03,2854.62 r270 top value=20pF
C494 "C0402C200J5GACTU" 0402 3364.03,3304.4 r90 top value=20pF
C495 "C0402C200J5GACTU" 0402 2079.5,3304.4 r90 top value=20pF
C496 "C0402C200J5GACTU" 0402 2179.5,2854.62 r270 top value=20pF
C497 "C0402C200J5GACTU" 0402 3164.03,3304.4 r90 top value=20pF
C498 "C0402C200J5GACTU" 0402 3264.03,2854.62 r270 top value=20pF
C499 "C0402C200J5GACTU" 0402 2079.5,2854.62 r270 top value=20pF
C500 "C0402C200J5GACTU" 0402 2179.5,3304.4 r90 top value=20pF
C501 "C0402C200J5GACTU" 0402 3164.03,2854.62 r270 top value=20pF
C502 "C0402C200J5GACTU" 0402 3264.03,3304.4 r90 top value=20pF
C503 "C0603C104J3RAC" 0603 3620.4,4894.1 r0 bottom value=0.1uF
C504 "C0603C104J3RAC" 0603 3792.6,4552.7 r0 bottom value=0.1uF
D1 "PMEG045V150EPDAZ" SOT1289 5177.49,6411.72 r270 top value=45V
D9 "UDZLVTE-17110" SOD-323F 5477.5,3753.22 r270 top value=110V
D10 "UDZLVTE-17110" SOD-323F 5472.49,4716.01 r270 top value=110V
D11 "UDZLVTE-17110" SOD-323F 5476.8,4122.82 r270 top value=110V
D12 "UDZLVTE-17110" SOD-323F 5485.9,5082.82 r270 top value=110V
D13 "MBRS4201T3G" SMC 4538.94,4531.23 r180 top value=200V
D14 "MBRS4201T3G" SMC 3767.48,5318.2 r270 top value=200V
D15 "MBRS1100T3G" SMB 4533.49,3796.72 r90 top value=100V
D16 "MBR2H200SFT1G" SOD-123FL 5179.9,4533.22 r180 top value=200V
D17 "MBRS1100T3G" SMB 4533.49,3441.82 r270 top value=100V
D18 "MBRS1100T3G" SMB 4169.49,3775.23 r270 top value=100V
D19 "MBRS1100T3G" SMB 4171.49,3463.32 r90 top value=100V
D20 "MBRS1100T3G" SMB 5277.49,3796.72 r90 top value=100V
D21 "MBR2H200SFT1G" SOD-123FL 4671.35,5201.72 r0 top value=200V
D22 "MBRS1100T3G" SMB 5277.49,3441.82 r270 top value=100V
D23 "MBRS1100T3G" SMB 4997.49,3775.23 r270 top value=100V
D24 "MBRS1100T3G" SMB 4998.49,3463.32 r90 top value=100V
D25 "MMSZ5243B-7-F" SOD-123 5589.5,6223.52 r270 top value=13V
D26 "150060VS75000" WL-SMCW_GREEN 2787.49,5854.32 r180 top value=Green
D27 "150060VS75000" WL-SMCW_GREEN 3155.99,4789.32 r180 top value=Green
D28 "150060VS75000" WL-SMCW_GREEN 242.19,5081.52 r0 top value=Green
D29 "150060RS75000" WL-SMCW_RED 242.19,5146.52 r0 top value=Red
D30 "150060RS75000" WL-SMCW_RED 2750.61,3620.52 r0 top value=Red
D31 "150040GS73240" WL-SMCC_0402_Green 2713.27,3558.52 r0 top value=Green
D32 "TPD1E01B04DPLR" DPL0002A 1118.19,4752.89 r90 top
D33 "TPD1E01B04DPLR" DPL0002A 1398.73,3430.42 r180 top
D34 "TPD1E01B04DPLR" DPL0002A 873.43,4323.12 r180 top
F1 "0451010.MRL" Fuse_451_453 5687.49,6406.72 r0 top
FB1 "BLM31SN500SH1L" FP-BLM31SN500SH1L_1206-MFG 6014.89,5719.32 r90 top
FB2 "BLM31SN500SH1L" FP-BLM31SN500SH1L_1206-MFG 6129.89,5719.32 r90 top
FB3 "180E" FP-MPZ1608S181ATAH0_0603-MFG 1572.46,4265.42 r0 bottom
FB4 "180E" FP-MPZ1608S181ATAH0_0603-MFG 1712.4,4146.12 r270 bottom
FB5 "180E" FP-MPZ1608S181ATAH0_0603-MFG 1620.93,3815.32 r0 bottom
FB6 "180E" FP-MPZ1608S181ATAH0_0603-MFG 2395.93,3997.32 r180 bottom
FB7 "180E" FP-MPZ1608S181ATAH0_0603-MFG 1622.49,3738.32 r0 bottom
FB8 "180E" FP-MPZ1608S181ATAH0_0603-MFG 1906.49,4257.32 r0 bottom
FB9 "180E" FP-MPZ1608S181ATAH0_0603-MFG 1634.49,3923.32 r0 bottom
FB10 "180E" FP-MPZ1608S181ATAH0_0603-MFG 2393.49,4067.32 r180 bottom
FB11 "180E" FP-MPZ1608S181ATAH0_0603-MFG 2395.1,3915.02 r180 bottom
FB12 "180E" FP-MPZ1608S181ATAH0_0603-MFG 1945.05,2379.93 r270 top
FB13 "180E" FP-MPZ1608S181ATAH0_0603-MFG 2280.75,2485.53 r270 top
FB14 "180E" FP-MPZ1608S181ATAH0_0603-MFG 2040.45,2473.63 r270 top
FB15 "180E" FP-MPZ1608S181ATAH0_0603-MFG 3014.64,2374.83 r270 top
FB16 "180E" FP-MPZ1608S181ATAH0_0603-MFG 3342.05,2485.53 r270 top
FB17 "180E" FP-MPZ1608S181ATAH0_0603-MFG 3114.75,2430.93 r270 top
FID1 "Fiducial" Fiducial10-20 5787,430 r0 top
FID2 "Fiducial" Fiducial10-20 186,477 r0 top
FID3 "Fiducial" Fiducial10-20 154.07,5554.79 r0 top
FID4 "Fiducial" Fiducial10-20 5787,430 r180 bottom
FID5 "Fiducial" Fiducial10-20 186,477 r180 bottom
FID6 "Fiducial" Fiducial10-20 154.07,5554.79 r180 bottom
H1 "NY PMS 440 0025 PH" "NY PMS 440 0025 PH"#1 202.3,5859.12 r0 top
H2 "NY PMS 440 0025 PH" "NY PMS 440 0025 PH"#2 202.3,223.45 r0 top
H3 "NY PMS 440 0025 PH" "NY PMS 440 0025 PH"#3 5965.88,201.32 r0 top
H4 "NY PMS 440 0025 PH" "NY PMS 440 0025 PH"#1 4861.1,6522.62 r0 top
H5 "1902C" Keystone_1902C 202.83,5859.12 r180 bottom
H6 "1902C" Keystone_1902C 4861.63,6522.62 r180 bottom
H7 "1902C" Keystone_1902C 202.83,201.32 r180 bottom
H8 "1902C" Keystone_1902C 6010.5,201.32 r180 bottom
J1 "1725669" Phoenix_1725669 6047.49,3979.32 r90 top locked
J2 "1725669" Phoenix_1725669 6047.49,4874.32 r90 top locked
J3 "1725698" Phoenix_1725698 6047.49,6181.72 r90 top locked
J4 "61300211121" WURTH_61300211121 2427.49,4969.32 r0 top
J5 "629105150521" FP-629105150521_CONN_USB_8MM0_6MM6-MFG 633.46,6474.01 r180 top
J6 "61300611121" WURTH_61300611121 1020.1,4203.02 r270 top
J7 "61300211121" WURTH_61300211121 1253,940 r0 top
J8 "61300211121" WURTH_61300211121 1767,478 r180 top
J9 "AXK5A2147YG" Panasonic_AXK5A2147YG 2646.89,269.51 r180 top
J10 "AXK5A2147YG" Panasonic_AXK5A2147YG 2646.89,269.51 r0 bottom
J11 "15110322601000" Harting_15110322601000 2104.49,3079.51 r90 top
J12 "15110322601000" Harting_15110322601000 3189.03,3079.51 r90 top
J13 "61300211121" WURTH_61300211121 679,1662 r270 top
J14 "61300211121" WURTH_61300211121 1089.11,1980.95 r180 top
J15 "61300211121" WURTH_61300211121 3990.55,843.96 r270 top
J16 "61300211121" WURTH_61300211121 3505,1109 r90 top
J17 "61300211121" WURTH_61300211121 4470.84,643.96 r270 top
J18 "61300211121" WURTH_61300211121 4168,1664.03 r0 top
J19 "61300211121" WURTH_61300211121 304.84,1464.6 r180 top
J20 "61300211121" WURTH_61300211121 4771,1464.6 r0 top
J21 "61300211121" WURTH_61300211121 4771,1319.03 r0 top
J22 "61300211121" WURTH_61300211121 304.84,1319.03 r180 top
L1 "7447709470" WE-PD_1210 4178.69,5733.88 r270 top value=47uH
L2 "LQM18PN2R2MFR" 0603 4533.49,4171.03 r270 top value=2.2uH
L3 "744776147" WE-PD2-XL 4330.4,4879.92 r180 top value=47uH
L4 "744776147" WE-PD2-XL 3882.49,4879.32 r90 top value=47uH
L5 "LQM18PN2R2MFR" 0603 4280.2,4313.82 r270 top value=2.2uH
L6 "7447709470" WE-PD_1210 5087.49,5664.32 r270 top value=47uH
L7 "LQM18PN2R2MFR" 0603 5232.49,4296.72 r270 top value=2.2uH
L8 "744776147" WE-PD2-XL 5214.46,4879.32 r180 top value=47uH
L9 "744776147" WE-PD2-XL 4770.47,4879.32 r90 top value=47uH
L10 "LQM18PN2R2MFR" 0603 5047.49,4296.72 r270 top value=2.2uH
L11 "BLM18SG700TN1D" FP-BLM18SG700TN1D_0603-MFG 2312.49,6209.32 r180 top
L12 "BLM18SG700TN1D" FP-BLM18SG700TN1D_0603-MFG 3437.49,5869.32 r180 top
L13 "SRU1038-2R2Y" SRU1038 1992.49,5489.32 r270 top value=2.2uH
L14 "BLM18SG700TN1D" FP-BLM18SG700TN1D_0603-MFG 2772.49,5084.32 r180 top
LBL1 "THT-14-423-10" Label_650x200 5726.28,2912.87 r0 top
Logo1 "Texas Instruments" TI_Stacked_Overlay_Small 4409.45,2917.46 r0 top
Logo2 "CE Mark" CE_Mark_5mm 5000,2927.43 r0 top
Logo3 "FCC disclaimer" FCC_disclaimer 5905.51,1957.11 r0 top
Logo4 "WEEE logo" WEEE_Minimum 3858.27,3228.35 r0 top
LOGO5 "DANGER HIGH VOLTAGE" IEC_HighVoltage_Large 5472.44,1062.99 r0 top
Logo6 "CAUTION HOT SURFACE" IEC_HotSurface_Large 4888.49,2086.61 r0 top
Q1 "FDMC86240" TRANS_Fairchild_MLP08S 4422.77,5323.33 r180 top value=150V
Q2 "2N7002W-7-F" SOT-323 4602.33,5031.91 r90 bottom value=60V
Q3 "CSD19538Q3A" DNH0008A-MFG 5355.5,5321.52 r180 top
Q4 "2N7002W-7-F" SOT-323 5990.09,5649.91 r180 bottom value=60V
Q5 "CSD16301Q2" DQK0006C 2595.29,3641.52 r0 top value=25V
Q6 "CSD16301Q2" DQK0006C 2587.29,3540.52 r0 top value=25V
R1 "RNCF0603TKY10K0" 0603 3325.49,4703.72 r180 bottom value=10.0k
R2 "RNCF0603TKY10K0" 0603 3325.49,4767.52 r180 bottom value=10.0k
R3 "TNPW1206100KBEEA" 1206 6105.09,3669.32 r90 top value=100k
R4 "TNPW1206100KBEEA" 1206 6095.09,4539.32 r90 top value=100k
R5 "TNPW1206100KBEEA" 1206 5979.89,4264.32 r270 top value=100k
R6 "RNCF0603TKY10K0" 0603 3325.49,4512.32 r180 bottom value=10.0k
R7 "RNCF0603TKY10K0" 0603 3325.49,4576.12 r180 bottom value=10.0k
R8 "TNPW1206100KBEEA" 1206 5987.49,5184.32 r270 top value=100k
R9 "CRCW0805215KFKEA" 0805_HV 4532.49,5369.32 r90 bottom value=215k
R10 "CRCW060310R0FKEA" 0603 4537.49,5420.81 r270 top value=10.0
R11 "CRCW0805215KFKEA" 0805_HV 4532.49,5204.32 r90 bottom value=215k
R12 "CRCW0603750RFKEA" 0603 4827.49,5474.32 r90 bottom value=750
R13 "ERJ-B2CFR01V" 0612 4656.59,5432.62 r270 top value=0.01
R14 "CRCW0603309KFKEA" 0603 4873.83,5296.91 r0 bottom value=309k
R15 "RG1608P-224-B-T5" 0603 4612.33,5150.42 r90 bottom value=220k
R16 "CRCW060327K0JNEA" 0603 4816.4,5200.42 r270 bottom value=27k
R17 "RT0603BRD07150KL" 0603 4680.33,5200.42 r90 bottom value=150k
R18 "CRCW06031K50JNEA" 0603 4893.83,5408.41 r270 bottom value=1.5k
R19 "CRCW060311K0JNEA" 0603 4884.33,5200.42 r90 bottom value=11k
R20 "RG1608P-912-B-T5" 0603 4717.33,5101.91 r180 bottom value=9.10k
R21 "CRCW0603309KFKEA" 0603 4952.47,5200.42 r90 bottom value=309k
R22 "CRCW0805215KFKEA" 0805_HV 5707.49,5484.32 r90 bottom value=215k
R23 "CRCW060310R0FKEA" 0603 5477.49,5420.81 r270 top value=10.0
R24 "CRCW0805215KFKEA" 0805_HV 5832.49,5514.32 r180 bottom value=215k
R25 "CRCW0603750RFKEA" 0603 5562.49,5704.32 r270 bottom value=750
R26 "ERJ-B2CFR01V" 0612 5595.7,5428.92 r270 top value=0.01
R27 "RG1608P-224-B-T5" 0603 5862.49,5652.78 r180 bottom value=220k
R28 "CRCW0603402KFKEA" 0603 5862.49,5779.78 r0 bottom value=402k
R29 "RT0603BRD07150KL" 0603 5862.49,5589.32 r180 bottom value=150k
R30 "CRCW060333K0JNEA" 0603 5862.49,5906.72 r0 bottom value=33k
R31 "RC0603FR-071KL" 0603 5687.56,5844.32 r270 bottom value=1.00k
R32 "RG1608P-912-B-T5" 0603 6118.99,5669.32 r180 bottom value=9.10k
R33 "CRCW060315K0FKEA" 0603 5862.49,5843.18 r180 bottom value=15.0k
R34 "CRCW060349K9FKEA" 0603 1612.49,5994.32 r270 top value=49.9k
R35 "CRCW060345K3FKEA" 0603 3057.14,6522.82 r90 top value=45.3k
R36 "RT0603BRD07142KL" 0603 2788.51,6524.32 r90 top value=142k
R37 "CRCW040210R0JNED" 0402 3225.71,6510.84 r270 top value=10
R38 "CRCW060349K9FKEA" 0603 2995.29,6522.82 r270 top value=49.9k
R39 "TNPW0603100KBEEA" 0603 2717.49,6524.32 r270 top value=100k
R40 "CRCW060349K9FKEA" 0603 1744.66,5994.32 r90 top value=49.9k
R41 "CRCW040210R0JNED" 0402 3282.49,6510.84 r270 top value=10
R42 "FC0402E50R0BST1" 0402 1729.5,3304.4 r270 top value=50
R43 "RT0603BRD0726K1L" 0603 2933.51,6524.32 r270 top value=26.1k
R44 "CRCW060349K9FKEA" 0603 3668.41,6524.32 r90 top value=49.9k
R45 "RC0603FR-07287KL" 0603 2979.06,5824.2 r90 top value=287k
R46 "RT0603BRD07142KL" 0603 3482.49,6524.32 r90 top value=142k
R47 "ERJ-3GEY0R00V" 0603 3842.49,6524.32 r270 top value=0
R48 "RC0603FR-071KL" 0603 2759.06,5744.2 r270 top value=1.00k
R49 "RC0603FR-0712K4L" 0603 3049.06,5825.69 r270 top value=12.4k
R50 "CRCW060349K9FKEA" 0603 3731.27,6524.32 r270 top value=49.9k
R51 "TNPW0603100KBEEA" 0603 3417.49,6524.32 r270 top value=100k
R52 "CRCW040210R0JNED" 0402 3957.49,6536.3 r90 top value=10
R53 "RNCF0603TKY10K0" 0603 3460.9,4680.62 r180 bottom value=10.0k
R54 "ERJ-3EKF4992V" 0603 3012.49,5559.32 r180 top value=49.9k
R55 "RT0603BRD0726K1L" 0603 3542.49,6524.32 r270 top value=26.1k
R56 "MCR25JZHJ000" 1210 1767.49,5234.32 r180 top value=0
R57 "CRCW040210K0FKED" 0402 2257.49,5414.32 r180 top value=10.0k
R58 "CRCW060349K9FKEA" 0603 2477.49,5542.82 r270 top value=49.9k
R59 "RC0603FR-07620RL" 0603 2236.3,5504.32 r90 top value=620
R60 "CRCW060349K9FKEA" 0603 2622.49,5209.32 r0 top value=49.9k
R61 "CRCW060349K9FKEA" 0603 3526.11,5237.88 r0 top value=49.9k
R62 "CRCW0603187KFKEA" 0603 2620.29,5329.32 r0 top value=187k
R63 "ERJ-3EKF4992V" 0603 2577.49,5509.32 r0 top value=49.9k
R64 "ERJ-3GEY0R00V" 0603 3526.11,4932.88 r180 top value=0
R65 "CRCW060349K9FKEA" 0603 3526.11,5171.7 r180 top value=49.9k
R66 "CRCW060312K4FKEA" 0603 2620.29,5392.31 r180 top value=12.4k
R67 "CRCW060349K9FKEA" 0603 3462.49,5404.32 r90 top value=49.9k
R68 "CRCW040210R0JNED" 0402 3412.49,5004.32 r270 top value=10
R69 "CRCW060349K9FKEA" 0603 2787.49,5289.32 r0 top value=49.9k
R70 "CRCW060326K1FKEA" 0603 3527.49,5304.32 r180 top value=26.1k
R71 "RC0603FR-071KL" 0603 2607.49,4969.32 r0 top value=1.00k
R72 "RC0603FR-071KL" 0603 2247.49,4969.32 r0 top value=1.00k
R73 "RC0603FR-071KL" 0603 3027.49,4790.11 r180 top value=1.00k
R74 "RCP0603W50R0GEB" 0603 1068.4,6132.82 r270 top value=50
R75 "CRCW06031M00FKEA" 0603 412.5,6564.62 r270 top value=1.00Meg
R76 "CRCW0603100RFKEA" 0603 466.3,6100.32 r90 top value=100
R77 "RC0603FR-0715KL" 0603 359.79,5284.32 r180 top value=15.0k
R78 "RC0603FR-0715KL" 0603 359.79,5214.32 r0 top value=15.0k
R79 "RC0603FR-07200RL" 0603 362.19,5081.52 r0 top value=200
R80 "RC0603FR-07200RL" 0603 360.99,5146.62 r0 top value=200
R81 "CRCW0603100KFKEA" 0603 1187.3,3910.72 r90 top value=100k
R82 "RC0603FR-071KL" 0603 1305.49,5961.72 r0 top value=1.00k
R83 "RC0603FR-071KL" 0603 1305.49,5896.72 r0 top value=1.00k
R84 "RC0603FR-071KL" 0603 1305.49,5831.72 r0 top value=1.00k
R85 "RC0603FR-071KL" 0603 1305.49,5766.72 r0 top value=1.00k
R86 "ERJ3EKF2001V" 0603 623.16,5249.42 r270 top value=2.00k
R87 "RMCF0603FT10K0" 0603 1001.2,6132.82 r90 top value=10.0k
R88 "RG1608P-4871-B-T5" 0603 1305.49,5701.12 r180 top value=4.87k
R89 "CRCW06031K00FKEA" 0603 3456.99,4490.22 r0 top value=1.00k
R90 "CRCW06031K00FKEA" 0603 3456.99,4426.88 r0 top value=1.00k
R91 "CRCW06031K00FKEA" 0603 3456.99,4363.55 r0 top value=1.00k
R92 "CRCW06031K00FKEA" 0603 3456.99,4300.22 r0 top value=1.00k
R93 "CRCW06031K00FKEA" 0603 3456.99,4237.32 r0 top value=1.00k
R94 "CRCW06031K00FKEA" 0603 3456.99,4188.38 r0 top value=1.00k
R95 "CRCW06031K00FKEA" 0603 3456.99,4125.05 r0 top value=1.00k
R96 "CRCW06031K00FKEA" 0603 3456.99,4061.72 r0 top value=1.00k
R97 "CRCW06031K00FKEA" 0603 3458.99,3960.22 r0 top value=1.00k
R98 "CRCW06031K00FKEA" 0603 3458.99,3898.07 r0 top value=1.00k
R99 "CRCW06031K00FKEA" 0603 3458.99,3835.93 r0 top value=1.00k
R100 "CRCW06031K00FKEA" 0603 3458.99,3773.79 r0 top value=1.00k
R101 "CRCW06031K00FKEA" 0603 3458.99,3711.65 r0 top value=1.00k
R102 "CRCW06031K00FKEA" 0603 3458.99,3649.5 r0 top value=1.00k
R103 "CRCW06031K00FKEA" 0603 3458.99,3587.36 r0 top value=1.00k
R104 "CRCW06031K00FKEA" 0603 3458.99,3525.22 r0 top value=1.00k
R105 "CRCW0603100KFKEA" 0603 2912.79,4434.82 r0 top value=100k
R106 "CRCW0603100KFKEA" 0603 2912.79,4373.1 r0 top value=100k
R107 "CRCW0603100KFKEA" 0603 2912.79,4311.39 r0 top value=100k
R108 "CRCW0603100KFKEA" 0603 2912.79,4249.42 r0 top value=100k
R109 "CRCW0603100KFKEA" 0603 2912.79,4188.92 r0 top value=100k
R110 "CRCW0603100KFKEA" 0603 2912.79,4127.02 r0 top value=100k
R111 "CRCW0603100KFKEA" 0603 2912.79,4065.02 r0 top value=100k
R112 "CRCW0603100KFKEA" 0603 2912.79,4005.52 r0 top value=100k
R113 "CRCW0603100KFKEA" 0603 2912.79,3909.82 r0 top value=100k
R114 "CRCW0603100KFKEA" 0603 2912.79,3848.32 r0 top value=100k
R115 "CRCW0603100KFKEA" 0603 2912.79,3786.72 r0 top value=100k
R116 "CRCW0603100KFKEA" 0603 2912.79,3724.72 r0 top value=100k
R117 "CRCW0603100KFKEA" 0603 2912.79,3663.42 r0 top value=100k
R118 "CRCW0603100KFKEA" 0603 2912.79,3603.12 r0 top value=100k
R119 "CRCW0603100KFKEA" 0603 2912.79,3543.42 r0 top value=100k
R120 "CRCW0603100KFKEA" 0603 2913.5,3486.52 r0 top value=100k
R121 "RC0603FR-07200RL" 0603 2739.29,3685.52 r180 top value=200
R122 "RC0603FR-07200RL" 0603 2739.29,3507.52 r180 top value=200
R123 "RMCF0603FT10K0" 0603 2502.29,3664.52 r270 top value=10.0k
R124 "RMCF0603FT10K0" 0603 2470.29,3513.52 r0 top value=10.0k
R125 "ERA3AEB102V" 0603 1075.19,4729.72 r90 top value=1.00k
R126 "CRCW040216K2FKED" 0402 1484.21,5140.22 r0 top value=16.2k
R127 "CRCW040216K2FKED" 0402 1484.21,5034.22 r0 top value=16.2k
R128 "CRCW040216K2FKED" 0402 1456.21,4917.72 r0 top value=16.2k
R129 "RC0402JR-0710KL" FP-RC0402JR-0710KL_0402-MFG 1149.19,4930.72 r270 top value=10k
R130 "RC0402JR-0710KL" FP-RC0402JR-0710KL_0402-MFG 1137.7,5014.22 r0 top value=10k
R131 "RC0402JR-0710KL" FP-RC0402JR-0710KL_0402-MFG 982.19,4883.72 r270 top value=10k
R132 "CRCW040216K2FKED" 0402 1484.21,5193.22 r180 top value=16.2k
R133 "CRCW040216K2FKED" 0402 1484.21,5087.22 r180 top value=16.2k
R134 "CRCW040216K2FKED" 0402 1456.69,4869.72 r180 top value=16.2k
R135 "CRCW040216K2FKED" 0402 1456.69,4820.72 r180 top value=16.2k
R136 "ERA3AEB102V" 0603 905.5,4363.72 r180 top value=1.00k
R137 "FC0402E50R0BST1" 0402 2429.5,2854.62 r90 top value=50
R138 "ERA3AEB102V" 0603 1300.41,3471.92 r0 top value=1.00k
R139 "PCF0402-12-10KBT1" 0402 1477.15,4547.57 r270 top value=10.0k
R140 "RK73Z1ETTP" 0402 1621.6,4085.82 r0 top value=0
R141 "RC0402FR-07100KL" 0402 1239,4381.02 r90 top value=100k
R142 "CRCW040211K0FKED" 0402 1288.8,4382.22 r270 top value=11.0k
R143 "RK73Z1ETTP" 0402 1631.87,3983.32 r0 bottom value=0
R144 "RK73Z1ETTP" 0402 2231.49,3575.32 r180 bottom value=0
R145 "RC0201FR-0722RL" 0201 950.8,3561.62 r180 top value=22.0
R146 "FC0402E50R0BST1" 0402 2814.03,3304.4 r270 top value=50
R147 "ERJ-2GE0R00X" FP-ERJ-2GE0R00X_0402-MFG 2284.86,2551.93 r0 bottom value=0
R148 "ERJ-2GE0R00X" FP-ERJ-2GE0R00X_0402-MFG 2284.86,2499.93 r0 bottom value=0
R149 "CRCW0603100RFKEA" 0603 2370.26,2526.13 r90 bottom value=100
R150 "ERJ-2GE0R00X" FP-ERJ-2GE0R00X_0402-MFG 2521.35,2660.93 r90 bottom value=0
R151 "ERJ-2GE0R00X" FP-ERJ-2GE0R00X_0402-MFG 2829.87,2649.69 r0 top value=0
R152 "ERJ-L03KF10CV" 0603 2306.35,2417.23 r180 bottom value=0.1
R153 "ERJ-L03KF10CV" 0603 2465.45,2448.53 r0 top value=0.1
R154 "RC0603FR-071KL" 0603 1780.24,2307.03 r270 top value=1.00k
R155 "RC0603FR-071KL" 0603 2463.19,2309.03 r270 top value=1.00k
R156 "RC0603FR-071KL" 0603 2339.24,2309.03 r270 top value=1.00k
R157 "RC0603FR-071KL" 0603 2789.64,2302.83 r270 top value=1.00k
R158 "RC0603FR-071KL" 0603 3520.75,2303.34 r270 top value=1.00k
R159 "RC0603FR-071KL" 0603 3396.64,2303.34 r270 top value=1.00k
R160 "ERJ3EKF2001V" 0603 2840.09,1479.9 r90 top value=2.00k
R161 "ERJ-L03KF10CV" 0603 3140.69,1474.4 r270 top value=0.1
R162 "ERJ-L03KF10CV" 0603 3075.39,1473.9 r270 top value=0.1
R163 "ERJ3EKF2001V" 0603 1897.97,1476.01 r270 top value=2.00k
R164 "ERJ-L03KF10CV" 0603 2220.69,1469.8 r270 top value=0.1
R165 "ERJ-L03KF10CV" 0603 2145.69,1469.68 r270 top value=0.1
R166 "ERJ-3GEY0R00V" 0603 3382.82,400 r180 top value=0
R167 "CRCW2512220RFKEG" 2512 3357.02,643.01 r270 top value=220
R294 "ERJ3EKF2001V" 0603 1083.99,1476.7 r90 top value=2.00k
R295 "ERJ-L03KF10CV" 0603 1422.29,1493.2 r270 top value=0.1
R296 "ERJ-L03KF10CV" 0603 1346.49,1493.2 r270 top value=0.1
R297 "ERJ3EKF2001V" 0603 3617.29,1481.4 r90 top value=2.00k
R298 "ERJ-L03KF10CV" 0603 3951.09,1474.4 r270 top value=0.1
R299 "ERJ-L03KF10CV" 0603 3872.19,1474.4 r270 top value=0.1
R428 "RMCF0402FT49R9" 0402 1606.35,2285.11 r90 bottom value=49.9
R429 "RMCF0402FT49R9" 0402 1224.25,2477.03 r0 bottom value=49.9
R430 "CRCW04020000Z0ED" 0402 1715.63,2337.25 r0 bottom value=0
R431 "CRCW0402169RFKED" 0402 1812.63,2361.75 r270 bottom value=169
R432 "CRCW0402100RFKED" 0402 3218.13,2250.82 r180 bottom value=100
R433 "CRCW04020000Z0ED" 0402 1715.63,2386.25 r0 bottom value=0
R434 "CRCW04020000Z0ED" 0402 1182.35,2438.55 r180 bottom value=0
R435 "CRCW0402169RFKED" 0402 1090.93,2326.63 r180 bottom value=169
R436 "CRCW0402100RFKED" 0402 2141.29,2254.2 r180 bottom value=100
R437 "CRCW04020000Z0ED" 0402 1182.35,2390.55 r180 bottom value=0
R438 "RMCF0603FT10K0" 0603 1642.25,2511.13 r270 bottom value=10.0k
R439 "RMCF0603FT10K0" 0603 1236.25,2311.53 r90 bottom value=10.0k
R440 "CRCW060330K0JNEA" 0603 3249.06,5735.69 r90 top value=30k
R441 "CRCW060310K0JNEA" 0603 3179.06,5735.69 r270 top value=10k
R442 "RC0603FR-0733K2L" 0603 2831.53,5744.2 r270 top value=33.2k
R443 "ERJ-3GEY0R00V" 0603 2210.99,4431.32 r90 top value=0
R444 "CRCW0603100KFKEA" 0603 1671.99,4462.82 r180 top value=100k
R445 "ERA3ARB103V" ERA3A 2026.9,4935.02 r0 top value=10.0k
R446 "ERA3ARB103V" ERA3A 1864.49,4467.82 r0 top value=10.0k
R447 "ERJ-3GEY0R00V" 0603 1701.99,4367.82 r0 top value=0
R448 "ERA3ARB103V" ERA3A 1614.4,4392.06 r270 top value=10.0k
R449 "RC0402JR-070RL" 0402 1950,4203.72 r135 top value=0
R450 "RC0402JR-070RL" 0402 1881.3,4275.32 r315 top value=0
R451 "CRCW060312K1FKEA" 0603 2428.79,5358.81 r270 top value=12.1k
R452 "FC0402E50R0BST1" 0402 3514.03,2854.62 r90 top value=50
R457 "RT0603DRE0710KL" 0603 1495.19,4977.42 r0 top value=10.0k
R458 "FC0402E50R0BST1" 0402 1729.5,2854.62 r90 top value=50
R459 "FC0402E50R0BST1" 0402 2429.5,3304.4 r270 top value=50
R460 "FC0402E50R0BST1" 0402 2814.03,2854.62 r90 top value=50
R461 "FC0402E50R0BST1" 0402 3514.03,3304.4 r270 top value=50
R462 "FC0402E50R0BST1" 0402 1829.5,3304.4 r270 top value=50
R463 "FC0402E50R0BST1" 0402 2329.5,2854.62 r90 top value=50
R464 "FC0402E50R0BST1" 0402 2914.03,3304.4 r270 top value=50
R465 "FC0402E50R0BST1" 0402 3414.03,2854.62 r90 top value=50
R466 "FC0402E50R0BST1" 0402 1829.5,2854.62 r90 top value=50
R467 "FC0402E50R0BST1" 0402 2329.5,3304.4 r270 top value=50
R468 "FC0402E50R0BST1" 0402 2914.03,2854.62 r90 top value=50
R469 "FC0402E50R0BST1" 0402 3414.03,3304.4 r270 top value=50
R470 "FC0402E50R0BST1" 0402 1929.5,3304.4 r270 top value=50
R471 "FC0402E50R0BST1" 0402 2229.5,2854.62 r90 top value=50
R472 "FC0402E50R0BST1" 0402 3014.03,3304.4 r270 top value=50
R473 "FC0402E50R0BST1" 0402 3314.03,2854.62 r90 top value=50
R474 "FC0402E50R0BST1" 0402 1929.5,2854.62 r90 top value=50
R475 "FC0402E50R0BST1" 0402 2229.5,3304.4 r270 top value=50
R476 "FC0402E50R0BST1" 0402 3014.03,2854.62 r90 top value=50
R477 "FC0402E50R0BST1" 0402 3314.03,3304.4 r270 top value=50
R478 "FC0402E50R0BST1" 0402 2029.5,3304.4 r270 top value=50
R479 "FC0402E50R0BST1" 0402 2129.5,2854.62 r90 top value=50
R480 "FC0402E50R0BST1" 0402 3114.03,3304.4 r270 top value=50
R481 "FC0402E50R0BST1" 0402 3214.03,2854.62 r90 top value=50
R482 "FC0402E50R0BST1" 0402 2029.5,2854.62 r90 top value=50
R483 "FC0402E50R0BST1" 0402 2129.5,3304.4 r270 top value=50
R484 "FC0402E50R0BST1" 0402 3114.03,2854.62 r90 top value=50
R485 "FC0402E50R0BST1" 0402 3214.03,3304.4 r270 top value=50
R486 "ERJ-3GEY0R00V" 0603 1784.73,1329.43 r0 top value=0
R488 "ERJ-3GEY0R00V" 0603 954,1477.74 r270 top value=0
R492 "ERJ-3GEY0R00V" 0603 2646.89,1307.07 r0 top value=0
R494 "ERJ-3GEY0R00V" 0603 3464.28,1246.14 r0 top value=0
R496 "ERJ-3GEY0R00V" 0603 3464.27,1368 r0 top value=0
R500 "ERJ-3GEY0R00V" 0603 3464.28,1307.07 r0 top value=0
R502 "ERJ-3GEY0R00V" 0603 2646.89,1249.2 r0 top value=0
R504 "ERJ-3GEY0R00V" 0603 2646.89,1368 r0 top value=0
R509 "ERJ-3GEY0R00V" 0603 1784.73,1271.56 r0 top value=0
R511 "ERJ-3GEY0R00V" 0603 1784.73,1390.36 r0 top value=0
R512 "RNCF0603TKY10K0" 0603 3476.2,4516.32 r0 bottom value=10.0k
R513 "CRCW06034K70JNEA" 0603 1701.88,3585.47 r225 top value=4.7k
R514 "CRCW06034K70JNEA" 0603 1539.6,3444 r225 top value=4.7k
R515 "RC0603FR-071KL" 0603 1455,2628.44 r90 top value=1.00k
R516 "RC0603FR-071KL" 0603 1288.6,2615.09 r180 top value=1.00k
S1 "218-8LPST" SW_218-8LP 3180.99,4259.32 r0 top
S2 "218-8LPST" SW_218-8LP 3178.99,3730.32 r0 top
SW1 "436331045822" FP-436331045822_SW_TACT-MFG 942.7,4697.02 r270 top
SW2 "436331045822" FP-436331045822_SW_TACT-MFG 1160.77,3342.6 r180 top
SW3 "436331045822" FP-436331045822_SW_TACT-MFG 828.8,4204.82 r180 top
TP1 "VOUT_-5V" Keystone5000 1667.49,6349.32 r0 top
TP2 "VOUT_-5V5" Keystone5000 2147.49,6329.32 r0 top
TP3 "SOC_SYNC_OUT" TP_SM_1MM 1511.3,4188.02 r270 top
TP4 "VOUT_5V5" Keystone5000 3142.49,5869.32 r90 top
TP5 "VSYS_5V" Keystone5000 2632.49,5824.32 r0 top
TP6 "VIN12" Keystone5000 4128.3,6480.82 r0 top
TP7 "PORz_OUT" TP_SM_1MM 1478.2,4407.42 r270 top
TP8 "CMP-0055137-2" Keystone5000 1810.1,5065.92 r0 top
TP9 "VOUT_3V3" Keystone5000 3032.49,5389.32 r0 top
TP10 "VOUT_1V8" Keystone5000 2252.49,5334.32 r0 top
TP11 "GND" Keystone5001 3878.8,3752.74 r90 top
TP12 "VPG_3V3" Keystone5000 2902.49,5389.32 r0 top
TP13 "GND" Keystone5001 3878.8,4089.4 r270 top
TP14 "GND" Keystone5001 3878.8,3584.4 r270 top
TP15 "GND" Keystone5001 3878.8,3921.07 r270 top
TP17 "TCK" Keystone5000 188.7,6080.82 r270 top
TP18 "TMS" Keystone5000 188.7,6208.52 r270 top
TP19 "TDI" Keystone5000 188.7,6325.02 r270 top
TP20 "TDO" Keystone5000 188.7,6455.82 r270 top
TP21 "RESETSTAT" TP_SM_1MM 1474.6,4471.42 r90 top
TP30 "A_TX_RXZ" TP_SM_1MM 1648.85,2275.54 r270 top
TP31 "TSHUT" TP_SM_1MM 2592.95,2276.93 r270 top
TP32 "CRC_ERR" TP_SM_1MM 2327.85,2403.23 r270 top
TP33 "B_TX_RXZ" TP_SM_1MM 2734.05,2272.43 r0 top
TP34 "TSHUT" TP_SM_1MM 3667.55,2273.03 r0 top
TP35 "CRC_ERR" TP_SM_1MM 3428.95,2414.23 r0 top
TP36 "MCU_PORz" TP_SM_1MM 1205.2,4482.92 r90 top
TP37 "A_THERM" TP_SM_1MM 1081.5,1569.36 r0 top
TP38 "B_THERM" TP_SM_1MM 3588.69,1557.3 r0 top
TP39 "C_THERM" TP_SM_1MM 2798.39,1553.5 r270 top
TP40 "D_THERM" TP_SM_1MM 1897.97,1561.23 r0 top
U1 "DAC53401DSGR" DSG0008A-MFG 3486.89,4758.47 r0 bottom
U2 "DAC53401DSGR" DSG0008A-MFG 3486.89,4600.32 r0 bottom
U3 "LM5155DSSR" DSS0012B 4742.49,5334.32 r270 bottom
U4 "LM5155DSSR" DSS0012B 5732.49,5669.32 r0 bottom
U5 "TPSM63603RDHR" RDH0030A-MFG 3023.63,6293.61 r0 top
U6 "TPS7A3301RGWR" RGW0020A 1899.66,6129.32 r0 top
U7 "TPSM63603RDHR" RDH0030A-MFG 3677.37,6294.43 r0 top
U8 "TPS62932DRLR" DRL0008A-MFG 2322.49,5639.32 r180 top
U9 "TPS7A9401DSC" DSC0010J-MFG 2479.85,5209.32 r180 top
U10 "TPSM63603V3RDHR" RDH0030A-MFG 3272.77,5184.2 r270 top
U11 "TLV75518PDBVR" DBV0005A_N 2427.49,4844.32 r180 top
U12 "TM4C1294NCPDTT3R" PDT0128A 854.9,5710.82 r90 top
U13 "TPS73533DRVR" DRV0006A 1008.7,6490.32 r180 top
U14 "TPD4E02B04DQAR" DQA0010A 675.72,6336.28 r90 top
U15 "SN74AVC4T245PWR" PW0016A_N 738.6,3830.32 r180 top
U16 "LM4040B25IDCKR" DCK0005A_N 537.6,5251.42 r90 top
U17 "AM2431BSDGHIALXR" ALX0293A-MFG 2000.4,3874.32 r90 top locked
U18 "TPS386000RGPR" RGP0020A 1298.19,4946.72 r90 top
U19 "SN74LVC1G11DCKR" DCK0006A_N 1029.19,4979.72 r180 top
U20 "SN74AVC4T245PWR" PW0016A_N 741.86,3586.6 r180 top
U21 "SN74AVC2T244DQMR" DQM0008A 764,3417.42 r180 top
U22 "TXS0102DCUR" DCU0008A_N 761.9,3243.82 r90 top
U23 "LMK00304SQ/NOPB" RTV0032A 2646.89,2568.74 r270 top
U24 "LMK62A2-200M00SIAR" SIA0006B 2163.92,2501.63 r0 bottom
U25 "TX7516ALH" ALH0144A#1 2104.5,2038.48 r180 top
U26 "TX7516ALH" ALH0144A#2 3189.28,2038.48 r180 top
U27 "TMUX9832ZEH" ZEH0083A-MFG 3093.08,1222.52 r0 top
U28 "TMUX9832ZEH" ZEH0083A-MFG 2200.69,1224.18 r0 top
U29 "TMUX9832ZEH" ZEH0083A-MFG 1433.3,1220.85 r0 top
U30 "TMUX9832ZEH" ZEH0083A-MFG 3860.47,1219.18 r0 top
U31 "DS90LV031ATMTC/NOPB" PW0016A_N 1424.09,2389.05 r180 bottom
U32 "TPS7A9401DSC" DSC0010J-MFG 3014.06,5669.2 r180 top
U33 "SYM-S25HL512TFAMHI010" FP-S25HL512TFAMHI010_SO16-MFG 1828.49,4713.82 r180 top
U34 "SN74LVC1G08DBVR" DBV0005A_N 1864.49,4368.82 r0 top
U35 "TXS0102DCUR" DCU0008A_N 1387.49,4534.32 r180 bottom
U36 "SN74CB3Q3125DGVR" DGV0014A_N 1223.65,4224.62 r0 top
Y1 "830064296" FP-830064296_SMT4_3MM4_2MM7-MFG 728.4,6223.71 r0 top
Y2 "CS00119AA-11-18ED25.000000E" FP-CS00119AA-11-18ED25.000000E_SMD4-MFG 1753.99,4197.32 r0 top
Y2 "LMK6CE02500DDLE" DLE0004A-MFG 1753.99,4197.32 r90 top
ZZ1 "This Assembly Note is for PCB labels only" AssemblyNoteLabel 381.28,7236 r0 top
ZZ2 "These assemblies are ESD sensitive, ESD precautions shall be observed." AssemblyNote 381.28,7127.11 r0 top
ZZ3 "These assemblies must be clean and free from flux and all contaminants. Use of no clean flux is not acceptable." AssemblyNote 381.28,7038.56 r0 top
ZZ4 "These assemblies must comply with workmanship standards IPC-A-610 Class 2, unless otherwise specified." AssemblyNote 381.28,6950 r0 top

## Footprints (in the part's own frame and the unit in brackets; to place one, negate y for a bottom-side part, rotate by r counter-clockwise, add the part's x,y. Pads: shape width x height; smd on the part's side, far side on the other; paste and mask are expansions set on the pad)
0201 [mm] "Data from Kemet datasheet CC101_COM dated 7/28/11"
  rect 0.46x0.42 smd mask+0.048: 1(-0.33,0) 2(0.33,0)
  body extent -0.31,-0.16 0.31,0.16, height 0.26
0201_033 [mm] "SMD, 2-Leads, Height 0.33mm"
  rect 0.46x0.42 smd mask+0.048: 1(-0.33,0) 2(0.33,0)
  body extent -0.31,-0.16 0.31,0.16, height 0.33
0402 [mm] "0402 from SM-752 data"
  rect 0.8x0.6 smd: 1(-0.6,0) 2(0.6,0)
  silkscreen extent -1.22,-0.52 1.22,0.52, body extent -0.55,-0.3 0.55,0.3, height 0.6
0402_065 [mm] "0402"
  rect 0.8x0.6 smd: 1(-0.6,0) 2(0.6,0)
  silkscreen extent -1.22,-0.52 1.22,0.52, body extent -0.55,-0.3 0.55,0.3, height 0.65
0402_070 [mil] "SMD, 2-Leads, Body 1.2x0.7mm, Height 0.7mm"
  rect 15x24 smd: 1(-20,0) 2(20,0)
  body extent -24,-14 24,14, height 28
0603 [mm] "0603 from SM-752 data"
  rect 1x0.95 smd: 1(-0.8,0) 2(0.8,0)
  silkscreen extent -1.52,-0.69 1.52,0.69, body extent -0.87,-0.47 0.87,0.47, height 1
0612 [mm] "Panasonic recommended land pattern, fb97d03ed01.pdf dated April 2008"
  rect 0.95x3.2 smd: 1(-0.775,0) 2(0.775,0)
  silkscreen extent -1.1,-1.9 1.1,1.9, body extent -0.9,-1.7 0.9,1.7, height 0.85
0805_HV [mil] "0805 with 30mil clearance between pads"
  rect 50x63 smd: 1(-40,0) 2(40,0)
  silkscreen extent -74,-40 74,40, body extent -43,-29 43,29, height 57
1206 [mm] "1206 from SM-752 data"
  rect 1.3x1.85 smd: 1(-1.45,0) 2(1.45,0)
  silkscreen extent -2.4,-1.21 2.4,1.21, body extent -1.7,-0.9 1.7,0.9, height 1.35
1206_180 [mm] "1206_180"
  rect 1.1x1.6 smd: 1(-1.7,0) 2(1.7,0)
  silkscreen extent -0.9,-1 0.9,1, body extent -1.75,-0.95 1.75,0.95, height 1.8
1206_190 [mm] "1206_190"
  rect 1.1x1.6 smd: 1(-1.7,0) 2(1.7,0)
  silkscreen extent -0.9,-1 0.9,1, body extent -1.75,-0.95 1.75,0.95, height 1.9
1210 [mm] "1210 from SM-752 data"
  rect 1.3x2.7 smd: 1(-1.45,0) 2(1.45,0)
  silkscreen extent -2.32,-1.57 2.32,1.57, body extent -1.7,-1.35 1.7,1.35, height 1.35
2512 [mm] "Chip Resistor, Body 6.3x3.2mm, IPC Medium Density"
  rect 1.3x3.4 smd: 1(-2.95,0) 2(2.95,0)
  silkscreen extent -1.9,-1.6 1.9,1.6, body extent -3.22,-1.67 3.22,1.67, height 0.71
ALH0144A#1 [mm] "FCBGA-144"
  round 0.4 smd mask+0: A1(-4.4,4.4) A2(-3.6,4.4) A3(-2.8,4.4) A4(-2,4.4) A5(-1.2,4.4) A6(-0.4,4.4) A7(0.4,4.4) A8(1.2,4.4) A9(2,4.4) A10(2.8,4.4) A11(3.6,4.4) A12(4.4,4.4) B1(-4.4,3.6) B2(-3.6,3.6) B3(-2.8,3.6) B4(-2,3.6) B5(-1.2,3.6) B6(-0.4,3.6) B7(0.4,3.6) B8(1.2,3.6) B9(2,3.6) B10(2.8,3.6) B11(3.6,3.6) B12(4.4,3.6) C1(-4.4,2.8) C2(-3.6,2.8) C3(-2.8,2.8) C4(-2,2.8) C5(-1.2,2.8) C6(-0.4,2.8) C7(0.4,2.8) C8(1.2,2.8) C9(2,2.8) C10(2.8,2.8) C11(3.6,2.8) C12(4.4,2.8) D1(-4.4,2) D2(-3.6,2) D3(-2.8,2) D4(-2,2) D5(-1.2,2) D6(-0.4,2) D7(0.4,2) D8(1.2,2) D9(2,2) D10(2.8,2) D11(3.6,2) D12(4.4,2) E1(-4.4,1.2) E2(-3.6,1.2) E3(-2.8,1.2) E4(-2,1.2) E5(-1.2,1.2) E6(-0.4,1.2) E7(0.4,1.2) E8(1.2,1.2) E9(2,1.2) E10(2.8,1.2) E11(3.6,1.2) E12(4.4,1.2) F1(-4.4,0.4) F2(-3.6,0.4) F3(-2.8,0.4) F4(-2,0.4) F5(-1.2,0.4) F6(-0.4,0.4) F7(0.4,0.4) F8(1.2,0.4) F9(2,0.4) F10(2.8,0.4) F11(3.6,0.4) F12(4.4,0.4) G1(-4.4,-0.4) G2(-3.6,-0.4) G3(-2.8,-0.4) G4(-2,-0.4) G5(-1.2,-0.4) G6(-0.4,-0.4) G7(0.4,-0.4) G8(1.2,-0.4) G9(2,-0.4) G10(2.8,-0.4) G11(3.6,-0.4) G12(4.4,-0.4) H1(-4.4,-1.2) H2(-3.6,-1.2) H3(-2.8,-1.2) H4(-2,-1.2) H5(-1.2,-1.2) H6(-0.4,-1.2) H7(0.4,-1.2) H8(1.2,-1.2) H9(2,-1.2) H10(2.8,-1.2) H11(3.6,-1.2) H12(4.4,-1.2) J1(-4.4,-2) J2(-3.6,-2) J3(-2.8,-2) J4(-2,-2) J5(-1.2,-2) J6(-0.4,-2) J7(0.4,-2) J8(1.2,-2) J9(2,-2) J10(2.8,-2) J11(3.6,-2) J12(4.4,-2) K1(-4.4,-2.8) K2(-3.6,-2.8) K3(-2.8,-2.8) K4(-2,-2.8) K5(-1.2,-2.8) K6(-0.4,-2.8) K7(0.4,-2.8) K8(1.2,-2.8) K9(2,-2.8) K10(2.8,-2.8) K11(3.6,-2.8) K12(4.4,-2.8) L1(-4.4,-3.6) L2(-3.6,-3.6) L3(-2.8,-3.6) L4(-2,-3.6) L5(-1.2,-3.6) L6(-0.4,-3.6) L7(0.4,-3.6) L8(1.2,-3.6) L9(2,-3.6) L10(2.8,-3.6) L11(3.6,-3.6) L12(4.4,-3.6) M1(-4.4,-4.4) M2(-3.6,-4.4) M3(-2.8,-4.4) M4(-2,-4.4) M5(-1.2,-4.4) M6(-0.4,-4.4) M7(0.4,-4.4) M8(1.2,-4.4) M9(2,-4.4) M10(2.8,-4.4) M11(3.6,-4.4)
  round 0.4 smd paste+0 mask+0: M12(4.4,-4.4)
  silkscreen extent -5,-5 5,5, body extent -5,-5 5,5, height 1.32
ALH0144A#2 [mm] "FCBGA-144"
  round 0.4 smd mask+0: A1(-4.4,4.4) A2(-3.6,4.4) A3(-2.8,4.4) A4(-2,4.4) A5(-1.2,4.4) A6(-0.4,4.4) A7(0.4,4.4) A8(1.2,4.4) A9(2,4.4) A10(2.8,4.4) A11(3.6,4.4) A12(4.4,4.4) B1(-4.4,3.6) B2(-3.6,3.6) B3(-2.8,3.6) B4(-2,3.6) B5(-1.2,3.6) B6(-0.4,3.6) B7(0.4,3.6) B8(1.2,3.6) B9(2,3.6) B10(2.8,3.6) B11(3.6,3.6) B12(4.4,3.6) C1(-4.4,2.8) C2(-3.6,2.8) C3(-2.8,2.8) C4(-2,2.8) C5(-1.2,2.8) C6(-0.4,2.8) C7(0.4,2.8) C8(1.2,2.8) C9(2,2.8) C10(2.8,2.8) C11(3.6,2.8) C12(4.4,2.8) D1(-4.4,2) D2(-3.6,2) D3(-2.8,2) D4(-2,2) D5(-1.2,2) D6(-0.4,2) D7(0.4,2) D8(1.2,2) D9(2,2) D10(2.8,2) D11(3.6,2) D12(4.4,2) E1(-4.4,1.2) E2(-3.6,1.2) E3(-2.8,1.2) E4(-2,1.2) E5(-1.2,1.2) E6(-0.4,1.2) E7(0.4,1.2) E8(1.2,1.2) E9(2,1.2) E10(2.8,1.2) E11(3.6,1.2) E12(4.4,1.2) F1(-4.4,0.4) F2(-3.6,0.4) F3(-2.8,0.4) F4(-2,0.4) F5(-1.2,0.4) F6(-0.4,0.4) F7(0.4,0.4) F8(1.2,0.4) F9(2,0.4) F10(2.8,0.4) F11(3.6,0.4) F12(4.4,0.4) G1(-4.4,-0.4) G2(-3.6,-0.4) G3(-2.8,-0.4) G4(-2,-0.4) G5(-1.2,-0.4) G6(-0.4,-0.4) G7(0.4,-0.4) G8(1.2,-0.4) G9(2,-0.4) G10(2.8,-0.4) G11(3.6,-0.4) G12(4.4,-0.4) H1(-4.4,-1.2) H2(-3.6,-1.2) H3(-2.8,-1.2) H4(-2,-1.2) H5(-1.2,-1.2) H6(-0.4,-1.2) H7(0.4,-1.2) H8(1.2,-1.2) H9(2,-1.2) H10(2.8,-1.2) H11(3.6,-1.2) H12(4.4,-1.2) J1(-4.4,-2) J2(-3.6,-2) J3(-2.8,-2) J4(-2,-2) J5(-1.2,-2) J6(-0.4,-2) J7(0.4,-2) J8(1.2,-2) J9(2,-2) J10(2.8,-2) J11(3.6,-2) J12(4.4,-2) K1(-4.4,-2.8) K2(-3.6,-2.8) K3(-2.8,-2.8) K4(-2,-2.8) K5(-1.2,-2.8) K6(-0.4,-2.8) K7(0.4,-2.8) K8(1.2,-2.8) K9(2,-2.8) K10(2.8,-2.8) K11(3.6,-2.8) K12(4.4,-2.8) L1(-4.4,-3.6) L2(-3.6,-3.6) L3(-2.8,-3.6) L4(-2,-3.6) L5(-1.2,-3.6) L6(-0.4,-3.6) L7(0.4,-3.6) L8(1.2,-3.6) L9(2,-3.6) L10(2.8,-3.6) L11(3.6,-3.6) L12(4.4,-3.6) M1(-4.4,-4.4) M2(-3.6,-4.4) M3(-2.8,-4.4) M4(-2,-4.4) M5(-1.2,-4.4) M6(-0.4,-4.4) M7(0.4,-4.4) M8(1.2,-4.4) M9(2,-4.4) M10(2.8,-4.4) M11(3.6,-4.4) M12(4.4,-4.4)
  silkscreen extent -5,-5 5,5, body extent -5,-5 5,5, height 1.32
ALX0293A-MFG [mm]
  round 0.3 smd paste+0 mask-1000: A1(-5,5) A2(-4.5,5) A3(-4,5) A5(-3,5) A6(-2.5,5) A8(-1.5,5) A9(-1,5) A11(0,5) A12(0.5,5) A14(1.5,5) A15(2,5) A17(3,5) A18(3.5,5) A20(4.5,5) A21(5,5) AA1(-5,-5) AA2(-4.5,-5) AA4(-3.5,-5) AA5(-3,-5) AA7(-2,-5) AA8(-1.5,-5) AA10(-0.5,-5) AA11(0,-5) AA13(1,-5) AA14(1.5,-5) AA16(2.5,-5) AA17(3,-5) AA19(4,-5) AA20(4.5,-5) AA21(5,-5) B1(-5,4.5) B2(-4.5,4.5) B3(-4,4.5) B4(-3.5,4.5) B5(-3,4.5) B6(-2.5,4.5) B7(-2,4.5) B8(-1.5,4.5) B9(-1,4.5) B10(-0.5,4.5) B11(0,4.5) B12(0.5,4.5) B13(1,4.5) B14(1.5,4.5) B15(2,4.5) B16(2.5,4.5) B17(3,4.5) B18(3.5,4.5) B19(4,4.5) B20(4.5,4.5) B21(5,4.5) C2(-4.5,4) C5(-3,4) C6(-2.5,4) C9(-1,4) C11(0,4) C13(1,4) C16(2.5,4) C17(3,4) C20(4.5,4) C21(5,4) D1(-5,3.5) D2(-4.5,3.5) D4(-3.5,3.5) D6(-2.5,3.5) D9(-1,3.5) D10(-0.5,3.5) D12(0.5,3.5) D13(1,3.5) D16(2.5,3.5) D17(3,3.5) D18(3.5,3.5) D20(4.5,3.5) E1(-5,3) E2(-4.5,3) E3(-4,3) E4(-3.5,3) E6(-2.5,3) E7(-2,3) E8(-1.5,3) E9(-1,3) E11(0,3) E13(1,3) E14(1.5,3) E15(2,3) E16(2.5,3) E19(4,3) E20(4.5,3) E21(5,3) F2(-4.5,2.5) F3(-4,2.5) F4(-3.5,2.5) F5(-3,2.5) F8(-1.5,2.5) F11(0,2.5) F14(1.5,2.5) F17(3,2.5) F18(3.5,2.5) F19(4,2.5) F20(4.5,2.5) F21(5,2.5) G1(-5,2) G2(-4.5,2) G5(-3,2) G6(-2.5,2) G9(-1,2) G10(-0.5,2) G11(0,2) G12(0.5,2) G13(1,2) G16(2.5,2) G17(3,2) G20(4.5,2) H1(-5,1.5) H2(-4.5,1.5) H5(-3,1.5) H6(-2.5,1.5) H7(-2,1.5) H8(-1.5,1.5) H11(0,1.5) H14(1.5,1.5) H15(2,1.5) H16(2.5,1.5) H17(3,1.5) H20(4.5,1.5) H21(5,1.5) J2(-4.5,1) J3(-4,1) J4(-3.5,1) J5(-3,1) J6(-2.5,1) J9(-1,1) J10(-0.5,1) J11(0,1) J12(0.5,1) J13(1,1) J16(2.5,1) J17(3,1) J18(3.5,1) J19(4,1) J20(4.5,1) J21(5,1) K1(-5,0.5) K2(-4.5,0.5) K4(-3.5,0.5) K6(-2.5,0.5) K7(-2,0.5) K8(-1.5,0.5) K11(0,0.5) K14(1.5,0.5) K15(2,0.5) K16(2.5,0.5) K18(3.5,0.5) K20(4.5,0.5) L1(-5,0) L2(-4.5,0) L3(-4,0) L5(-3,0) L6(-2.5,0) L9(-1,0) L10(-0.5,0) L11(0,0) L12(0.5,0) L13(1,0) L16(2.5,0) L17(3,0) L19(4,0) L20(4.5,0) L21(5,0) M2(-4.5,-0.5) M4(-3.5,-0.5) M6(-2.5,-0.5) M7(-2,-0.5) M8(-1.5,-0.5) M11(0,-0.5) M14(1.5,-0.5) M15(2,-0.5) M16(2.5,-0.5) M18(3.5,-0.5) M20(4.5,-0.5) M21(5,-0.5) N1(-5,-1) N2(-4.5,-1) N3(-4,-1) N4(-3.5,-1) N5(-3,-1) N6(-2.5,-1) N9(-1,-1) N10(-0.5,-1) N11(0,-1) N12(0.5,-1) N13(1,-1) N16(2.5,-1) N17(3,-1) N18(3.5,-1) N19(4,-1) N20(4.5,-1) P1(-5,-1.5) P2(-4.5,-1.5) P5(-3,-1.5) P6(-2.5,-1.5) P7(-2,-1.5) P8(-1.5,-1.5) P11(0,-1.5) P14(1.5,-1.5) P15(2,-1.5) P16(2.5,-1.5) P17(3,-1.5) P20(4.5,-1.5) P21(5,-1.5) R2(-4.5,-2) R5(-3,-2) R6(-2.5,-2) R9(-1,-2) R10(-0.5,-2) R11(0,-2) R12(0.5,-2) R13(1,-2) R16(2.5,-2) R17(3,-2) R20(4.5,-2) R21(5,-2) T1(-5,-2.5) T2(-4.5,-2.5) T3(-4,-2.5) T4(-3.5,-2.5) T5(-3,-2.5) T8(-1.5,-2.5) T11(0,-2.5) T14(1.5,-2.5) T17(3,-2.5) T18(3.5,-2.5) T19(4,-2.5) T20(4.5,-2.5) U1(-5,-3) U2(-4.5,-3) U3(-4,-3) U6(-2.5,-3) U7(-2,-3) U8(-1.5,-3) U9(-1,-3) U11(0,-3) U13(1,-3) U14(1.5,-3) U15(2,-3) U16(2.5,-3) U18(3.5,-3) U19(4,-3) U20(4.5,-3) U21(5,-3) V2(-4.5,-3.5) V4(-3.5,-3.5) V5(-3,-3.5) V6(-2.5,-3.5) V9(-1,-3.5) V10(-0.5,-3.5) V12(0.5,-3.5) V13(1,-3.5) V16(2.5,-3.5) V18(3.5,-3.5) V20(4.5,-3.5) V21(5,-3.5) W1(-5,-4) W2(-4.5,-4) W5(-3,-4) W6(-2.5,-4) W9(-1,-4) W11(0,-4) W13(1,-4) W16(2.5,-4) W17(3,-4) W20(4.5,-4) Y1(-5,-4.5) Y2(-4.5,-4.5) Y3(-4,-4.5) Y4(-3.5,-4.5) Y5(-3,-4.5) Y6(-2.5,-4.5) Y7(-2,-4.5) Y8(-1.5,-4.5) Y9(-1,-4.5) Y10(-0.5,-4.5) Y11(0,-4.5) Y12(0.5,-4.5) Y13(1,-4.5) Y14(1.5,-4.5) Y15(2,-4.5) Y16(2.5,-4.5) Y17(3,-4.5) Y18(3.5,-4.5) Y19(4,-4.5) Y20(4.5,-4.5) Y21(5,-4.5)
  silkscreen extent -6.15,-5.55 5.55,5.55, body extent -6.05,-6.05 6.05,6.05, height 0.25
AssemblyNote [mil] "Assembly Note"
AssemblyNoteLabel [mil] "Assembly Note for PCB Labels"
CAPPRD350W60D800H1150 [mm] "Based on Nichicon L8 series"
  rect 1.35x1.35 hole 0.85: 1(-1.75,0)
  round 1.35 hole 0.85: 2(1.75,0)
  silkscreen extent -4.25,-4.25 4.25,4.25, body extent -4.22,-4.24 4.24,4.24, height 13.51
CE_Mark_5mm [mil] "Minimum text height for CE Mark"
  silkscreen extent -138,-98 138,98
DBV0005A_N [mm] "SOT23, 5-Leads, Body 2.9x1.6mm, Pitch 0.95mm, Lead Span 2.8mm, IPC Medium Density"
  rrect17% 1x0.6 smd: 1(-1.375,0.95) 2(-1.375,0) 3(-1.375,-0.95) 4(1.375,-0.95) 5(1.375,0.95)
  silkscreen extent -1.62,-1.55 0.38,1.55, body extent -1.42,-1.46 1.42,1.46, height 1.09
DCK0005A_N [mm] "SOT353, 5-Leads, Body 2x1.3mm, Pitch 0.65mm, Lead Span 2.1mm, IPC Medium Density"
  rrect25% 0.85x0.4 smd: 1(-1.125,0.65) 2(-1.125,0) 3(-1.125,-0.65) 4(1.125,-0.65) 5(1.125,0.65)
  silkscreen extent -1.47,-1.02 0.55,1.1, body extent -1.14,-1 1.14,1, height 0.95
DCK0006A_N [mm] "SOT23, 6-Leads, Body 2x1.3mm, Pitch 0.65mm, Lead Span 2.1mm, IPC Medium Density"
  rrect25% 0.85x0.4 smd: 1(-1.125,0.65) 2(-1.125,0) 3(-1.125,-0.65) 4(1.125,-0.65) 5(1.125,0) 6(1.125,0.65)
  silkscreen extent -1.5,-1.09 0.51,1.09, body extent -1.14,-1 1.14,1, height 0.95
DCU0008A_N [mm] "TSSOP, 8-Leads, Body 2x2.3mm, Pitch 0.5mm, IPC Medium Density"
  oval 0.8x0.3 smd: 1(-1.6,0.75) 2(-1.6,0.25) 3(-1.6,-0.25) 4(-1.6,-0.75) 5(1.6,-0.75) 6(1.6,-0.25) 7(1.6,0.25) 8(1.6,0.75)
  silkscreen extent -1.05,-1.05 0.38,1.05, body extent -1.56,-1 1.56,1, height 0.9
DGV0014A_N [mm] "TVSOP-14, IPC Medium Density"
  oval 1.4x0.2 smd: 1(-2.95,1.2) 2(-2.95,0.8) 3(-2.95,0.4) 4(-2.95,0) 5(-2.95,-0.4) 6(-2.95,-0.8) 7(-2.95,-1.2) 8(2.95,-1.2) 9(2.95,-0.8) 10(2.95,-0.4) 11(2.95,0) 12(2.95,0.4) 13(2.95,0.8) 14(2.95,1.2)
  silkscreen extent -3.53,-1.85 1.85,1.85, body extent -3.2,-1.8 3.2,1.8, height 1.13
DLE0004A-MFG [mm]
  rrect17% 0.6x0.7 smd paste-1000 mask+0: 1(-0.8,1.05) 2(-0.8,-1.05) 3(0.8,-1.05) 4(0.8,1.05)
  silkscreen extent -1.3,-1.65 1.3,1.65, body extent -1.4,-1.75 1.4,1.75, height 0.25
DNH0008A-MFG [mm]
  rrect50% 0.7x0.4 smd paste-1000 mask-1000: 1(-1.55,0.975) 2(-1.55,0.325) 3(-1.55,-0.325) 4(-1.55,-0.975)
  rrect33% 0.6x0.3 smd paste+0 mask-1000: 5(1.55,-0.975) 6(1.55,-0.325) 7(1.55,0.325) 8(1.55,0.975)
  Top Layer region: -0.61,-1.175 -0.61,1.175 -0.597,1.225 -0.56,1.262 -0.51,1.275 -0.51,1.275 1.8,1.275 1.85,1.262 1.887,1.225 1.9,1.175 1.9,1.175 1.9,-1.175 1.887,-1.225 1.85,-1.262 1.8,-1.275 1.8,-1.275 -0.51,-1.275 -0.56,-1.262 -0.597,-1.225 -0.61,-1.175
  silkscreen extent -2.57,-1.73 1.55,1.73, body extent -2,-1.88 2,1.88, height 0.25
DPL0002A [mm] "R-PX2SON-N2"
  rect 0.18x0.25 smd: 1(-0.193,0)
  rect 0.19x0.25 smd: 2(0.193,0)
  body extent -0.32,-0.17 0.32,0.17, height 0.32
DQA0010A [mm] "SON, 10-Leads, Body 1x2.5mm, Pitch 0.5mm, TI Recommended"
  rrect50% 0.565x0.2 smd: 1(-0.417,1) 2(-0.417,0.5) 4(-0.417,-0.5) 5(-0.417,-1) 6(0.417,-1) 7(0.417,-0.5) 9(0.417,0.5) 10(0.417,1)
  rrect25% 0.565x0.4 smd paste-0.2: 3(-0.417,0) 8(0.417,0)
  rrect28% 0.565x0.36 on Top Paste: 3(-0.417,0) 8(0.417,0)
  silkscreen extent -0.68,-1.45 0.55,1.45, body extent -0.55,-1.3 0.55,1.3, height 0.56
DQK0006C [mm] "WSON"
  rrect12% 0.9x0.86 on Top Paste: 0(0,0.325)
  rrect34% 0.7x0.29 on Top Paste: 0(0.095,-0.65)
  rrect33% 0.45x0.3 smd: 1(-0.975,0.65) 2(-0.975,0) 3(-0.975,-0.65) 4(0.975,-0.65) 5(0.975,0) 6(0.975,0.65)
  rrect33% 0.75x0.3 smd paste-0.15: 7(0.095,-0.65)
  rrect11% 1x0.95 smd paste-0.5: 8(0,0.325)
  silkscreen extent -1.15,-1.15 1.15,1.15, body extent -1,-1 1,1, height 0.82
DQM0008A [mm] "TI"
  rrect50% 0.7x0.2 smd: 1(-0.45,0.6) 2(-0.45,0.2) 3(-0.45,-0.2) 4(-0.45,-0.6) 5(0.45,-0.6) 6(0.45,-0.2) 7(0.45,0.2) 8(0.45,0.6)
  silkscreen extent -0.72,-1.02 0.73,1.02, body extent -0.6,-0.9 0.6,0.9, height 0.5
DRL0008A-MFG [mm]
  rrect33% 0.67x0.3 smd paste+0 mask+0: 1(-0.74,0.75) 2(-0.74,0.25) 3(-0.74,-0.25) 4(-0.74,-0.75) 5(0.74,-0.75) 6(0.74,-0.25) 7(0.74,0.25) 8(0.74,0.75)
  silkscreen extent -1.78,-1.28 0.65,1.27, body extent -1.17,-1.35 1.17,1.35, height 0.25
DRV0006A [mm] "SON, 6-Leads, Body 2x2mm, Pitch 0.65mm, Thermal Pad 1.6x1mm, TI Recommended"
  rrect33% 0.45x0.3 smd: 1(-0.975,0.65) 2(-0.975,0) 3(-0.975,-0.65) 4(0.975,-0.65) 5(0.975,0) 6(0.975,0.65)
  rrect14% 1x0.7 on Top Paste: 7(0,0.45) 7(0,-0.45)
  rrect10% 1x1.6 smd paste-0.5: 7(0,0)
  silkscreen extent -1.05,-1.2 1.05,1.2, body extent -1.05,-1.05 1.05,1.05, height 0.81
DSC0010J-MFG [mm]
  rrect42% 0.6x0.24 smd paste+0 mask+0: 1(-1.4,1) 2(-1.4,0.5) 3(-1.4,0) 4(-1.4,-0.5) 5(-1.4,-1) 6(1.4,-1) 7(1.4,-0.5) 8(1.4,0) 9(1.4,0.5) 10(1.4,1)
  round 0.225 smd paste-1000 mask+0: 11(-0.25,1.448) 11(-0.25,-1.45) 11(0.25,1.45) 11(0.25,-1.448)
  rrect6% 1.65x2.4 smd paste-1000 mask+0: 11(0,0)
  Top Layer region: 0.125,1.2 0.125,1.65 0.129,1.669 0.14,1.685 0.156,1.696 0.175,1.7 0.175,1.7 0.325,1.7 0.344,1.696 0.36,1.685 0.371,1.669 0.375,1.65 0.375,1.65 0.375,1.2
  Top Layer region: -0.375,1.2 -0.375,1.65 -0.371,1.669 -0.36,1.685 -0.344,1.696 -0.325,1.7 -0.325,1.7 -0.175,1.7 -0.156,1.696 -0.14,1.685 -0.129,1.669 -0.125,1.65 -0.125,1.65 -0.125,1.2
  Top Layer region: -0.125,-1.2 -0.125,-1.65 -0.132,-1.675 -0.15,-1.693 -0.175,-1.7 -0.175,-1.7 -0.325,-1.7 -0.344,-1.696 -0.36,-1.685 -0.371,-1.669 -0.375,-1.65 -0.375,-1.65 -0.375,-1.2
  Top Layer region: 0.375,-1.2 0.375,-1.65 0.371,-1.669 0.36,-1.685 0.344,-1.696 0.325,-1.7 0.325,-1.7 0.175,-1.7 0.156,-1.696 0.14,-1.685 0.129,-1.669 0.125,-1.65 0.125,-1.65 0.125,-1.2
  silkscreen extent -2.4,-1.55 1.55,1.55, body extent -1.5,-1.5 1.5,1.5, height 0.8
DSG0008A-MFG [mm]
  rrect40% 0.5x0.25 smd paste+0 mask+0: 1(-0.95,0.75) 2(-0.95,0.25) 3(-0.95,-0.25) 4(-0.95,-0.75) 5(0.95,-0.75) 6(0.95,-0.25) 7(0.95,0.25) 8(0.95,0.75)
  rrect11% 0.9x1.6 smd paste-1000 mask+0: 9(0,0)
  silkscreen extent -1.87,-1.39 1,1.4, body extent -1,-1 1,1, height 0.8
DSS0012B [mm] "WSON-10"
  rrect40% 0.5x0.25 smd: 1(-0.95,1.25) 2(-0.95,0.75) 3(-0.95,0.25) 4(-0.95,-0.25) 5(-0.95,-0.75) 6(-0.95,-1.25) 7(0.95,-1.25) 8(0.95,-0.75) 9(0.95,-0.25) 10(0.95,0.25) 11(0.95,0.75) 12(0.95,1.25)
  rrect11% 1x2.65 smd paste-0.5: 13(0,0)
  body extent -1,-1.5 1,1.5, height 0.81
ERA3A [mm] "SMD, 2-Leads, Body 1.6x0.8mm"
  rrect15% 0.65x0.9 smd: 1(-0.725,0) 2(0.725,0)
  body extent -0.9,-0.5 0.9,0.5, height 0.55
FCC_disclaimer [mil]
Fiducial10-20 [mm]
  round 1 smd mask+0.5: 1(0,0)
  Top Layer keep-out circle w1.178: c0,0 r0.5
FP-1812Y2500105KXTWS2_1812-MFG [mm]
  rrect6% 1.55x3.4 smd paste+0 mask+0: 1(-2,0) 2(2,0)
  silkscreen extent -0.85,-1.7 0.85,1.7, body extent -2.88,-1.8 2.88,1.8, height 0.25
FP-830064296_SMT4_3MM4_2MM7-MFG [mm]
  rrect9% 1.4x1.15 smd paste+0 mask+0: 1(-1.1,-0.8) 2(1.1,-0.8) 3(1.1,0.8) 4(-1.1,0.8)
  silkscreen extent -2.18,-2.05 2.18,1.35, body extent -1.7,-1.35 1.7,1.35, height 0.8
FP-436331045822_SW_TACT-MFG [mm]
  rrect10% 1.2x1 smd paste+0 mask+0: 1(2.8,1.35) 2(2.8,-0.35) 3(-2.8,1.35) 4(-2.8,-0.35)
  round 0.75 hole 0.75 unplated paste-1000 mask+0: ""(0,1.875) ""(0,-0.875)
  silkscreen extent -2.35,1.23 4.12,2.35, body extent -3.5,-2.45 3.5,2.45, height 0.25
FP-629105150521_CONN_USB_8MM0_6MM6-MFG [mm]
  rect 0.45x1.3 smd: 1(-1.3,0) 2(-0.65,0) 3(0,0) 4(0.65,0) 5(1.3,0)
  oval 1.4x2 hole 0.85 slot 1.4 at 90 deg: Z1(-3.725,0) Z2(3.725,0)
  oval 1.15x1.8 hole 0.55 slot 1.2 at 90 deg: Z3(3.875,-3.8) Z4(-3.875,-3.8)
  round 0.8 hole 0.8 unplated: ""(-2.5,-1.1) ""(2.5,-1.1)
  silkscreen extent -4,-6.2 4,0.9, body extent -4,-6.25 4,0.35, height 2.67
FP-BLM18SG700TN1D_0603-MFG [mm]
  rrect15% 0.65x0.7 smd paste+0 mask+0: 1(-0.675,0) 2(0.675,0)
  silkscreen extent -0.8,-0.77 0.8,0.78, body extent -1.1,-0.58 1.1,0.58, height 0.25
FP-BLM31SN500SH1L_1206-MFG [mm]
  rrect9% 1.15x1.8 smd paste+0 mask+0: 1(-1.575,0) 2(1.575,0)
  silkscreen extent -0.82,-0.9 0.82,0.9, body extent -2.25,-1 2.25,1, height 0.25
FP-CS00119AA-11-18ED25.000000E_SMD4-MFG [mm]
  rrect10% 1.1x1 smd paste+0 mask+0: 1(-0.95,-0.75) 2(0.95,-0.75) 3(0.95,0.75) 4(-0.95,0.75)
  silkscreen extent -2.3,-1.65 1.28,1.65, body extent -1.6,-1.35 1.6,1.35, height 0.25
FP-ERJ-2GE0R00X_0402-MFG [mm]
  rrect21% 0.475x0.5 smd paste+0 mask+0: 1(-0.512,0) 2(0.513,0)
  silkscreen extent -0.53,-0.63 0.53,0.63, body extent -0.5,-0.25 0.5,0.25, height 0.4
FP-MPZ1608S181ATAH0_0603-MFG [mm]
  rrect17% 0.6x0.8 smd paste+0 mask+0: 1(-0.7,0) 2(0.7,0)
  silkscreen extent -0.88,-0.8 0.87,0.8, body extent -0.8,-0.4 0.8,0.4, height 0.75
FP-RC0402JR-0710KL_0402-MFG [mm]
  rrect20% 0.5x0.6 smd paste+0 mask+0: 1(-0.5,0) 2(0.5,0)
  silkscreen extent -0.5,-0.67 0.5,0.67, body extent -0.85,-0.4 0.85,0.4, height 0.25
FP-S25HL512TFAMHI010_SO16-MFG [mm]
  rrect17% 1.9x0.6 smd paste+0 mask+0: 1(-4.6,4.445) 2(-4.6,3.175) 3(-4.6,1.905) 4(-4.6,0.635) 5(-4.6,-0.635) 6(-4.6,-1.905) 7(-4.6,-3.175) 8(-4.6,-4.445) 9(4.6,-4.445) 10(4.6,-3.175) 11(4.6,-1.905) 12(4.6,-0.635) 13(4.6,0.635) 14(4.6,1.905) 15(4.6,3.175) 16(4.6,4.445)
  silkscreen extent -6.23,-5.25 3.8,5.25, body extent -5.65,-5.5 5.65,5.5, height 0.25
Fuse_451_453 [mm] "SMD, 2-Leads, Body 6.1x2.69mm"
  rrect5% 1.96x3.15 smd: 1(-2.455,0) 2(2.455,0)
  body extent -3.15,-1.47 3.15,1.47, height 2.94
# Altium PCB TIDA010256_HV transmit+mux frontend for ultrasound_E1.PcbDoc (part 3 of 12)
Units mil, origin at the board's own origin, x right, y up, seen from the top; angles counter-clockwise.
Board outline 6192.49 x 6712.23 mil, 16 copper layers (Top Layer, Layer 2 - GND, Layer 3 - SIG, Layer 4 - GND, Layer 5 - SIG, Layer 6 - SIG, Layer 7 - GND, Layer 8 - HV PWR, Layer 9 - LV PWR, Layer 10 - GND, Layer 11 - SIG, Layer 12 - SIG, Layer 13 - GND, Layer 14 - SIG, Layer 15 - GND, Bottom Layer), stack 95.905 mil thick; 806 components, 539 nets, 3343 pads, 1848 vias.

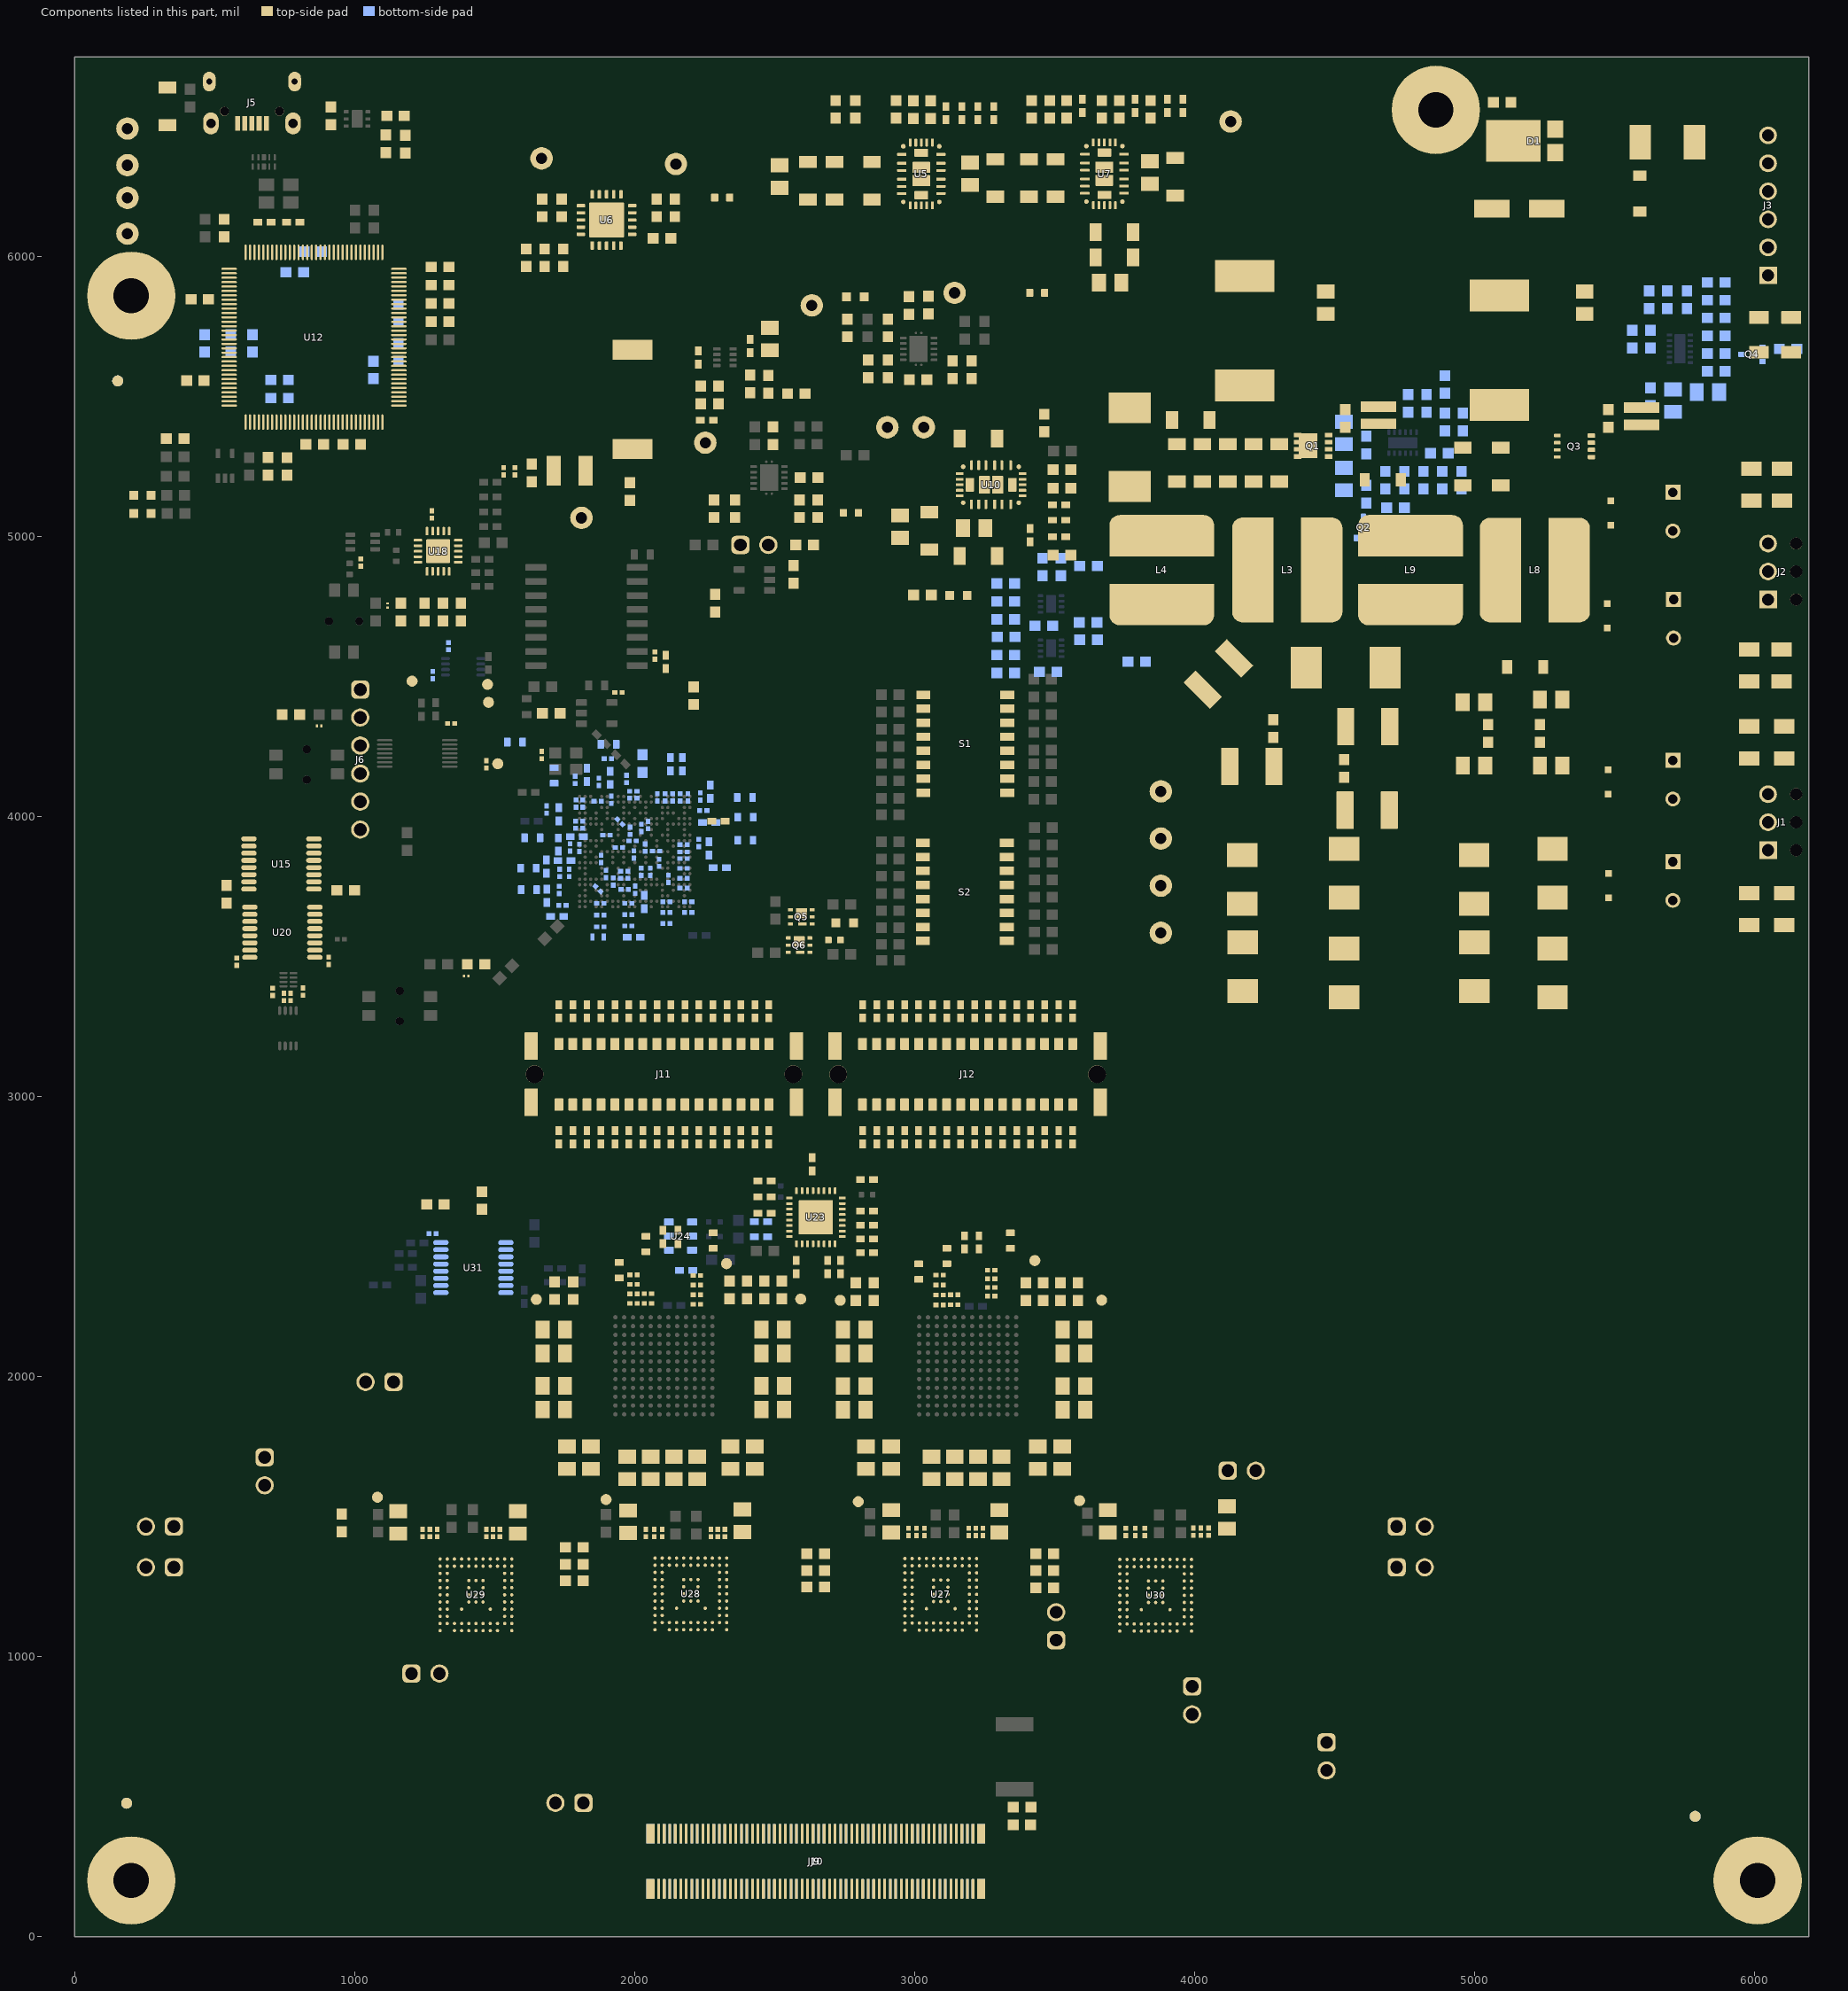
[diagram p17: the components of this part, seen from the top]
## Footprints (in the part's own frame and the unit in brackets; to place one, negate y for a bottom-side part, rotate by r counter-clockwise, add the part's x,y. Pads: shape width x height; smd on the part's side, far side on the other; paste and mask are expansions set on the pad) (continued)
Harting_15110322601000 [mm] "Header (Shrouded), 1.27mm, 16x2, SMT"
  rrect12% 1.1x0.8 smd: A1(2.75,9.525) A2(2.75,8.255) A3(2.75,6.985) A4(2.75,5.715) A5(2.75,4.445) A6(2.75,3.175) A7(2.75,1.905) A8(2.75,0.635) A9(2.75,-0.635) A10(2.75,-1.905) A11(2.75,-3.175) A12(2.75,-4.445) A13(2.75,-5.715) A14(2.75,-6.985) A15(2.75,-8.255) A16(2.75,-9.525) B1(-2.75,9.525) B2(-2.75,8.255) B3(-2.75,6.985) B4(-2.75,5.715) B5(-2.75,4.445) B6(-2.75,3.175) B7(-2.75,1.905) B8(-2.75,0.635) B9(-2.75,-0.635) B10(-2.75,-1.905) B11(-2.75,-3.175) B12(-2.75,-4.445) B13(-2.75,-5.715) B14(-2.75,-6.985) B15(-2.75,-8.255) B16(-2.75,-9.525)
  round 1.6 hole 1.6 unplated mask+0.102: MH1(0,11.735) MH2(0,-11.735)
  rrect8% 2.5x1.2 smd: MP1(2.55,12.035) MP2(2.55,-12.035) MP3(-2.55,-12.035) MP4(-2.55,12.035)
  body extent -3.7,-12.7 3.7,12.7, height 6.63
IEC_HighVoltage_Large [mil]
  silkscreen extent -435,-352 435,401
IEC_HotSurface_Large [mil]
  silkscreen extent -435,-375 435,378
Keystone5000 [mil] "For Keystone 500x miniature loop terminals"
  round 80 hole 40: 1(0,0)
  silkscreen extent -52,-52 52,52, body extent -49,-49 49,49, height 182
Keystone5001 [mil] "For Keystone 500x miniature loop terminals"
  round 80 hole 40: 1(0,0)
  silkscreen extent -52,-52 52,52, body extent -49,-49 49,49, height 182
Keystone_1902C [mil] "Hex Standoff, 4-40 threaded, nylon"
  round 1 on Mech4: 0(0,0)
  body extent -145,-126 146,126, height 501
Label_650x200 [mil] "Thermal Transfer Label"
  round 1 on Mech13: 0(0,0)
  silkscreen extent -325,-100 325,100, body extent -325,-100 325,100, height 1
"NY PMS 440 0025 PH"#1 [mm] "4-40 nylon screw and mounting hole"
  round 8 hole 3.2: 1(0,0)
  body extent -3.3,-3.3 3.3,3.3, height 2.69
"NY PMS 440 0025 PH"#2 [mm] "4-40 nylon screw and mounting hole"
  round 8 hole 3.2: 1(0,-0.562)
  body extent -3.3,-3.86 3.3,2.74, height 2.69
"NY PMS 440 0025 PH"#3 [mm] "4-40 nylon screw and mounting hole"
  round 8 hole 3.2: 1(1.12,0)
  body extent -2.18,-3.3 4.42,3.3, height 2.69
Panasonic_AXK5A2147YG [mm] "Receptacle, 0.5mm, 60x2, SMD"
  rrect13% 0.75x1.8 smd paste-1.8: 1(-15,2.5) 2(-15,-2.5) 119(15,2.5) 120(15,-2.5)
  rrect40% 0.25x1.8 smd paste-1.8: 3(-14.25,2.5) 4(-14.25,-2.5) 5(-13.75,2.5) 6(-13.75,-2.5) 7(-13.25,2.5) 8(-13.25,-2.5) 9(-12.75,2.5) 10(-12.75,-2.5) 11(-12.25,2.5) 12(-12.25,-2.5) 13(-11.75,2.5) 14(-11.75,-2.5) 15(-11.25,2.5) 16(-11.25,-2.5) 17(-10.75,2.5) 18(-10.75,-2.5) 19(-10.25,2.5) 20(-10.25,-2.5) 21(-9.75,2.5) 22(-9.75,-2.5) 23(-9.25,2.5) 24(-9.25,-2.5) 25(-8.75,2.5) 26(-8.75,-2.5) 27(-8.25,2.5) 28(-8.25,-2.5) 29(-7.75,2.5) 30(-7.75,-2.5) 31(-7.25,2.5) 32(-7.25,-2.5) 33(-6.75,2.5) 34(-6.75,-2.5) 35(-6.25,2.5) 36(-6.25,-2.5) 37(-5.75,2.5) 38(-5.75,-2.5) 39(-5.25,2.5) 40(-5.25,-2.5) 41(-4.75,2.5) 42(-4.75,-2.5) 43(-4.25,2.5) 44(-4.25,-2.5) 45(-3.75,2.5) 46(-3.75,-2.5) 47(-3.25,2.5) 48(-3.25,-2.5) 49(-2.75,2.5) 50(-2.75,-2.5) 51(-2.25,2.5) 52(-2.25,-2.5) 53(-1.75,2.5) 54(-1.75,-2.5) 55(-1.25,2.5) 56(-1.25,-2.5) 57(-0.75,2.5) 58(-0.75,-2.5) 59(-0.25,2.5) 60(-0.25,-2.5) 61(0.25,2.5) 62(0.25,-2.5) 63(0.75,2.5) 64(0.75,-2.5) 65(1.25,2.5) 66(1.25,-2.5) 67(1.75,2.5) 68(1.75,-2.5) 69(2.25,2.5) 70(2.25,-2.5) 71(2.75,2.5) 72(2.75,-2.5) 73(3.25,2.5) 74(3.25,-2.5) 75(3.75,2.5) 76(3.75,-2.5) 77(4.25,2.5) 78(4.25,-2.5) 79(4.75,2.5) 80(4.75,-2.5) 81(5.25,2.5) 82(5.25,-2.5) 83(5.75,2.5) 84(5.75,-2.5) 85(6.25,2.5) 86(6.25,-2.5) 87(6.75,2.5) 88(6.75,-2.5) 89(7.25,2.5) 90(7.25,-2.5) 91(7.75,2.5) 92(7.75,-2.5) 93(8.25,2.5) 94(8.25,-2.5) 95(8.75,2.5) 96(8.75,-2.5) 97(9.25,2.5) 98(9.25,-2.5) 99(9.75,2.5) 100(9.75,-2.5) 101(10.25,2.5) 102(10.25,-2.5) 103(10.75,2.5) 104(10.75,-2.5) 105(11.25,2.5) 106(11.25,-2.5) 107(11.75,2.5) 108(11.75,-2.5) 109(12.25,2.5) 110(12.25,-2.5) 111(12.75,2.5) 112(12.75,-2.5) 113(13.25,2.5) 114(13.25,-2.5) 115(13.75,2.5) 116(13.75,-2.5) 117(14.25,2.5) 118(14.25,-2.5)
  body extent -16.6,-2.9 16.6,2.9, height 2.35
Panasonic_D [mm] "SMD, 2-Leads, Dia 6.3mm"
  rect 3.2x1.6 smd: 1(-2.5,0) 2(2.5,0)
  silkscreen extent -3.4,-3.4 3.4,3.4, body extent -3.4,-3.4 3.4,3.4, height 6.11
PDT0128A [mm] "Thin QFP, 128-Leads, Body 14x14mm, Pitch 0.4mm"
  oval 1.4x0.2 smd: 1(-7.7,6.2) 2(-7.7,5.8) 3(-7.7,5.4) 4(-7.7,5) 5(-7.7,4.6) 6(-7.7,4.2) 7(-7.7,3.8) 8(-7.7,3.4) 9(-7.7,3) 10(-7.7,2.6) 11(-7.7,2.2) 12(-7.7,1.8) 13(-7.7,1.4) 14(-7.7,1) 15(-7.7,0.6) 16(-7.7,0.2) 17(-7.7,-0.2) 18(-7.7,-0.6) 19(-7.7,-1) 20(-7.7,-1.4) 21(-7.7,-1.8) 22(-7.7,-2.2) 23(-7.7,-2.6) 24(-7.7,-3) 25(-7.7,-3.4) 26(-7.7,-3.8) 27(-7.7,-4.2) 28(-7.7,-4.6) 29(-7.7,-5) 30(-7.7,-5.4) 31(-7.7,-5.8) 32(-7.7,-6.2) 65(7.7,-6.2) 66(7.7,-5.8) 67(7.7,-5.4) 68(7.7,-5) 69(7.7,-4.6) 70(7.7,-4.2) 71(7.7,-3.8) 72(7.7,-3.4) 73(7.7,-3) 74(7.7,-2.6) 75(7.7,-2.2) 76(7.7,-1.8) 77(7.7,-1.4) 78(7.7,-1) 79(7.7,-0.6) 80(7.7,-0.2) 81(7.7,0.2) 82(7.7,0.6) 83(7.7,1) 84(7.7,1.4) 85(7.7,1.8) 86(7.7,2.2) 87(7.7,2.6) 88(7.7,3) 89(7.7,3.4) 90(7.7,3.8) 91(7.7,4.2) 92(7.7,4.6) 93(7.7,5) 94(7.7,5.4) 95(7.7,5.8) 96(7.7,6.2)
  oval 0.2x1.4 smd: 33(-6.2,-7.7) 34(-5.8,-7.7) 35(-5.4,-7.7) 36(-5,-7.7) 37(-4.6,-7.7) 38(-4.2,-7.7) 39(-3.8,-7.7) 40(-3.4,-7.7) 41(-3,-7.7) 42(-2.6,-7.7) 43(-2.2,-7.7) 44(-1.8,-7.7) 45(-1.4,-7.7) 46(-1,-7.7) 47(-0.6,-7.7) 48(-0.2,-7.7) 49(0.2,-7.7) 50(0.6,-7.7) 51(1,-7.7) 52(1.4,-7.7) 53(1.8,-7.7) 54(2.2,-7.7) 55(2.6,-7.7) 56(3,-7.7) 57(3.4,-7.7) 58(3.8,-7.7) 59(4.2,-7.7) 60(4.6,-7.7) 61(5,-7.7) 62(5.4,-7.7) 63(5.8,-7.7) 64(6.2,-7.7) 97(6.2,7.7) 98(5.8,7.7) 99(5.4,7.7) 100(5,7.7) 101(4.6,7.7) 102(4.2,7.7) 103(3.8,7.7) 104(3.4,7.7) 105(3,7.7) 106(2.6,7.7) 107(2.2,7.7) 108(1.8,7.7) 109(1.4,7.7) 110(1,7.7) 111(0.6,7.7) 112(0.2,7.7) 113(-0.2,7.7) 114(-0.6,7.7) 115(-1,7.7) 116(-1.4,7.7) 117(-1.8,7.7) 118(-2.2,7.7) 119(-2.6,7.7) 120(-3,7.7) 121(-3.4,7.7) 122(-3.8,7.7) 123(-4.2,7.7) 124(-4.6,7.7) 125(-5,7.7) 126(-5.4,7.7) 127(-5.8,7.7) 128(-6.2,7.7)
  silkscreen extent -7.7,-6.3 6.3,6.99, body extent -8,-8 8,8, height 1.07
Phoenix_1725669 [mm] "Terminal Block, 3x1, 2.54 mm, TH"
  rect 1.6x1.6 hole 1.1: 1(-2.54,0)
  round 1.6 hole 1.1: 2(0,0) 3(2.54,0)
  round 1.1 hole 1.1 unplated mask+0: 4(-2.54,-2.54) 5(0,-2.54) 6(2.54,-2.54)
  silkscreen extent -4.4,-3.1 4.04,3.1, body extent -4.04,-3.1 4.04,3.1, height 8.5
Phoenix_1725698 [mm] "Terminal Block, 6x1, 2.54mm, TH"
  rect 1.6x1.6 hole 1.1: 1(-6.35,0)
  round 1.6 hole 1.1: 2(-3.81,0) 3(-1.27,0) 4(1.27,0) 5(3.81,0) 6(6.35,0)
  silkscreen extent -7.85,-3.75 7.85,3.1, body extent -7.85,-3.1 7.85,3.1, height 8.51
PW0016A_N [mm] "TSOP, 16-Leads, Body 5x4.4mm, Pitch 0.65mm, IPC Medium Density"
  oval 1.4x0.45 smd: 1(-2.95,2.275) 2(-2.95,1.625) 3(-2.95,0.975) 4(-2.95,0.325) 5(-2.95,-0.325) 6(-2.95,-0.975) 7(-2.95,-1.625) 8(-2.95,-2.275) 9(2.95,-2.275) 10(2.95,-1.625) 11(2.95,-0.975) 12(2.95,-0.325) 13(2.95,0.325) 14(2.95,0.975) 15(2.95,1.625) 16(2.95,2.275)
  silkscreen extent -3.5,-2.55 1.85,2.75, body extent -3.21,-2.5 3.21,2.5, height 1
RDH0030A-MFG [mm]
  round 0.419 smd paste+0 mask+0: 1(-1.633,2.508) 21(1.633,2.508)
  rrect40% 0.85x0.25 smd paste+0 mask+0: 2(-1.775,1.775) 3(-1.775,0.975) 4(-1.775,0.325) 5(-1.775,-0.475) 6(-1.775,-1.125) 7(-1.775,-1.775) 15(1.775,-1.775) 16(1.775,-1.125) 17(1.775,-0.475) 18(1.775,0.325) 19(1.775,0.975) 20(1.775,1.775)
  round 0.407 smd paste+0 mask+0: 8(-1.633,-2.53) 14(1.633,-2.53)
  rrect40% 0.25x0.7 smd paste+0 mask+0: 9(-1,-2.85) 10(-0.5,-2.85) 11(0,-2.85) 12(0.5,-2.85) 13(1,-2.85) 22(1,2.85) 23(0.5,2.85) 24(0,2.85) 25(-0.5,2.85) 26(-1,2.85)
  rrect14% 1.25x0.74 smd paste-1000 mask-1000: 27(0,1.925) 30(0,-1.925)
  rrect10% 1.6x1 smd paste-1000 mask-1000: 28(0,0.6) 29(0,-0.6)
  Top Layer region: -2.2,2.35 -2.196,2.331 -2.185,2.315 -2.169,2.304 -2.15,2.3 -2.15,2.3 -1.875,2.3 -1.871,2.281 -1.86,2.265 -1.844,2.254 -1.825,2.25 -1.825,2.25 -1.425,2.25 -1.406,2.254 -1.39,2.265 -1.379,2.281 -1.375,2.3 -1.375,2.3 -1.375,3.15 -1.379,3.169 -1.39,3.185 -1.406,3.196 -1.425,3.2 -1.425,3.2 -1.575,3.2 -1.6,3.193 -1.618,3.175 -1.625,3.15 -1.625,3.15 -1.625,2.925 -1.629,2.906 -1.64,2.89 -1.656,2.879 -1.675,2.875 -1.675,2.875 -1.8,2.875 -1.825,2.868 -1.843,2.85 -1.85,2.825 -1.85,2.825 -1.85,2.6 -1.854,2.581 -1.865,2.565 -1.881,2.554 -1.9,2.55 -1.9,2.55 -2.15,2.55 -2.175,2.543 -2.193,2.525 -2.2,2.5 -2.2,2.5
  Top Layer region: -2.2,-2.35 -2.196,-2.331 -2.185,-2.315 -2.169,-2.304 -2.15,-2.3 -2.15,-2.3 -1.875,-2.3 -1.871,-2.281 -1.86,-2.265 -1.844,-2.254 -1.825,-2.25 -1.825,-2.25 -1.425,-2.25 -1.406,-2.254 -1.39,-2.265 -1.379,-2.281 -1.375,-2.3 -1.375,-2.3 -1.375,-3.15 -1.379,-3.169 -1.39,-3.185 -1.406,-3.196 -1.425,-3.2 -1.425,-3.2 -1.575,-3.2 -1.6,-3.193 -1.618,-3.175 -1.625,-3.15 -1.625,-3.15 -1.625,-2.925 -1.629,-2.906 -1.64,-2.89 -1.656,-2.879 -1.675,-2.875 -1.675,-2.875 -1.8,-2.875 -1.825,-2.868 -1.843,-2.85 -1.85,-2.825 -1.85,-2.825 -1.85,-2.6 -1.854,-2.581 -1.865,-2.565 -1.881,-2.554 -1.9,-2.55 -1.9,-2.55 -2.15,-2.55 -2.175,-2.543 -2.193,-2.525 -2.2,-2.5 -2.2,-2.5
  Top Layer region: 2.2,-2.35 2.196,-2.331 2.185,-2.315 2.169,-2.304 2.15,-2.3 2.15,-2.3 1.875,-2.3 1.871,-2.281 1.86,-2.265 1.844,-2.254 1.825,-2.25 1.825,-2.25 1.425,-2.25 1.406,-2.254 1.39,-2.265 1.379,-2.281 1.375,-2.3 1.375,-2.3 1.375,-3.15 1.379,-3.169 1.39,-3.185 1.406,-3.196 1.425,-3.2 1.425,-3.2 1.575,-3.2 1.6,-3.193 1.618,-3.175 1.625,-3.15 1.625,-3.15 1.625,-2.925 1.629,-2.906 1.64,-2.89 1.656,-2.879 1.675,-2.875 1.675,-2.875 1.8,-2.875 1.825,-2.868 1.843,-2.85 1.85,-2.825 1.85,-2.825 1.85,-2.6 1.854,-2.581 1.865,-2.565 1.881,-2.554 1.9,-2.55 1.9,-2.55 2.15,-2.55 2.175,-2.543 2.193,-2.525 2.2,-2.5 2.2,-2.5
  Top Layer region: 2.2,2.35 2.196,2.331 2.185,2.315 2.169,2.304 2.15,2.3 2.15,2.3 1.875,2.3 1.871,2.281 1.86,2.265 1.844,2.254 1.825,2.25 1.825,2.25 1.425,2.25 1.406,2.254 1.39,2.265 1.379,2.281 1.375,2.3 1.375,2.3 1.375,3.15 1.379,3.169 1.39,3.185 1.406,3.196 1.425,3.2 1.425,3.2 1.575,3.2 1.6,3.193 1.618,3.175 1.625,3.15 1.625,3.15 1.625,2.925 1.629,2.906 1.64,2.89 1.656,2.879 1.675,2.875 1.675,2.875 1.8,2.875 1.825,2.868 1.843,2.85 1.85,2.825 1.85,2.825 1.85,2.6 1.854,2.581 1.865,2.565 1.881,2.554 1.9,2.55 1.9,2.55 2.15,2.55 2.175,2.543 2.193,2.525 2.2,2.5 2.2,2.5
  silkscreen extent -2.95,-3.65 2.05,3.65, body extent -2.3,-3.3 2.3,3.3, height 0.25
RGP0020A [mm] "QFN, 20-Leads, Body 4x4mm, Pitch 0.5mm, Thermal Pad 2.15x2.15mm, TI Recommended"
  rrect42% 0.75x0.24 smd: 1(-1.825,1) 2(-1.825,0.5) 3(-1.825,0) 4(-1.825,-0.5) 5(-1.825,-1) 11(1.825,-1) 12(1.825,-0.5) 13(1.825,0) 14(1.825,0.5) 15(1.825,1)
  rrect42% 0.24x0.75 smd: 6(-1,-1.825) 7(-0.5,-1.825) 8(0,-1.825) 9(0.5,-1.825) 10(1,-1.825) 16(1,1.825) 17(0.5,1.825) 18(0,1.825) 19(-0.5,1.825) 20(-1,1.825)
  rrect10% 0.96x0.96 on Top Paste: 21(-0.58,-0.58) 21(-0.58,0.58) 21(0.58,-0.58) 21(0.58,0.58)
  rrect5% 2.15x2.15 smd paste-1.075: 21(0,0)
  silkscreen extent -2.23,-2.22 2.23,2.22, body extent -2.07,-2.07 2.08,2.08, height 1.01
RGW0020A [mm] "VQFN-20"
  rrect32% 0.75x0.31 smd: 1(-2.325,1.3) 2(-2.325,0.65) 3(-2.325,0) 4(-2.325,-0.65) 5(-2.325,-1.3) 11(2.325,-1.3) 12(2.325,-0.65) 13(2.325,0) 14(2.325,0.65) 15(2.325,1.3)
  rrect32% 0.31x0.75 smd: 6(-1.3,-2.325) 7(-0.65,-2.325) 8(0,-2.325) 9(0.65,-2.325) 10(1.3,-2.325) 16(1.3,2.325) 17(0.65,2.325) 18(0,2.325) 19(-0.65,2.325) 20(-1.3,2.325)
  rrect3% 3.15x3.15 smd paste-1.575: 21(0,0)
  body extent -2.5,-2.5 2.5,2.5, height 1
RTV0032A [mm] "WQFN-32"
  rrect42% 0.6x0.24 smd: 1(-2.4,1.75) 2(-2.4,1.25) 3(-2.4,0.75) 4(-2.4,0.25) 5(-2.4,-0.25) 6(-2.4,-0.75) 7(-2.4,-1.25) 8(-2.4,-1.75) 17(2.4,-1.75) 18(2.4,-1.25) 19(2.4,-0.75) 20(2.4,-0.25) 21(2.4,0.25) 22(2.4,0.75) 23(2.4,1.25) 24(2.4,1.75)
  rrect42% 0.24x0.6 smd: 9(-1.75,-2.4) 10(-1.25,-2.4) 11(-0.75,-2.4) 12(-0.25,-2.4) 13(0.25,-2.4) 14(0.75,-2.4) 15(1.25,-2.4) 16(1.75,-2.4) 25(1.75,2.4) 26(1.25,2.4) 27(0.75,2.4) 28(0.25,2.4) 29(-0.25,2.4) 30(-0.75,2.4) 31(-1.25,2.4) 32(-1.75,2.4)
  rrect3% 3.1x3.1 smd paste-1.55: 33(0,0)
  body extent -2.5,-2.5 2.5,2.5, height 0.8
SIA0006B [mm] "QFM-6"
  rrect16% 0.9x0.64 smd: 1(-1.05,1.27) 2(-1.05,0) 3(-1.05,-1.27) 4(1.05,-1.27) 5(1.05,0) 6(1.05,1.27)
  silkscreen extent -1.75,-2.65 1.75,2.65, body extent -1.6,-2.5 1.6,2.5, height 1.01
SMB [mil] "Molded Diode, 2-Leads, Body 5.4x3.6mm, IPC Medium Density, based on OnSemi component dimensions"
  rect 85x107.99 smd: 1(-87.01,0) 2(87.01,0)
  silkscreen extent -155,-82 125,82, body extent -106,-71 106,71, height 91
SMC [mil] "Molded Diode, 2-Leads, Body 6.9x5.8mm, IPC Medium Density, based on OnSemi component dimensions and land patterns"
  rect 110x150 smd: 1(-140.49,0) 2(140.49,0)
  silkscreen extent -221,-124 189,123, body extent -156,-116 156,116, height 91
SOD-123 [mm] "On Semi recommended land pattern"
  rect 0.915x1.22 smd: 1(-1.637,0) 2(1.637,0)
  silkscreen extent -2.74,-1.17 2.03,1.17, body extent -1.93,-0.9 1.93,0.9, height 1.35
SOD-123FL [mm] "Copied from SOD-123"
  rect 0.915x1.22 smd: 1(-1.638,0) 2(1.638,0)
  silkscreen extent -2.74,-1.16 1.68,1.16, body extent -1.9,-0.9 1.9,0.9, height 1
SOD-323F [mm] "NXP recommended land pattern"
  rect 0.6x0.6 smd paste-0.05: 1(-1.1,0) 2(1.1,0)
  silkscreen extent -2.06,-0.86 1.52,0.86, body extent -1.35,-0.67 1.35,0.68, height 0.79
SOT1289 [mm] "CFP15, Nexperia recommended land pattern"
  rect 1.6x1.44 smd paste-0.8 mask+0.1: 1(-1.065,2.78) 2(1.065,2.78)
  rect 3.8x4.96 smd paste-2.48 mask+0.1: 3(0,-1.02)
  body extent -2.15,-3.25 2.15,3.25, height 0.79
SOT-323 [mm] "Diodes Inc recommended land pattern.  2016-02-24"
  rrect21% 0.6x0.47 smd: 1(-0.95,0.65) 2(-0.95,-0.65) 3(0.95,0)
  silkscreen extent -1.14,-1.22 0.77,1.22, body extent -1.13,-1.13 1.12,1.12, height 1.13
SRU1038 [mm] "Bourns recommended land pattern"
  rect 1.8x3.6 smd: 1(-4.5,0) 2(4.5,0)
  silkscreen extent -5.25,-5.3 5.25,5.3, body extent -5.15,-5.15 5.15,5.15, height 4.1
SW_218-8LP [mm] "SMD, 16-Leads, Body 11.33x5.8mm, Pitch 1.27mm"
  rect 1.27x0.76 smd: 1(-3.81,4.445) 2(-3.81,3.175) 3(-3.81,1.905) 4(-3.81,0.635) 5(-3.81,-0.635) 6(-3.81,-1.905) 7(-3.81,-3.175) 8(-3.81,-4.445) 9(3.81,-4.445) 10(3.81,-3.175) 11(3.81,-1.905) 12(3.81,-0.635) 13(3.81,0.635) 14(3.81,1.905) 15(3.81,3.175) 16(3.81,4.445)
  silkscreen extent -2.9,-5.67 2.9,5.9, body extent -4.22,-5.66 4.22,5.66, height 2.62
TI_Stacked_Overlay_Small [mil]
  silkscreen extent -418,-98 418,98
TP_SM_1MM [mm] "1mm Test Point, SMT"
  round 1 smd paste-0.5: 1(0,0)
TRANS_Fairchild_MLP08S [mm] "Fairchild MLP08S recommended land pattern"
  rect 0.7x0.42 smd mask+0.051: 1(-1.4,0.975) 2(-1.4,0.325) 3(-1.4,-0.325) 4(-1.4,-0.975) 5(1.4,-0.975) 6(1.4,-0.325) 7(1.4,0.325) 8(1.4,0.975)
  rect 1.7x2.27 smd mask+0.051: 9(0.45,0)
  silkscreen extent -2.1,-2.1 2.1,2.1, body extent -1.7,-1.7 1.7,1.7, height 0.81
WE-PD2-XL [mm] "Wurth Elektronik recommended land pattern"
  rrect50% 3.75x9.5 smd: 1(-3.125,0) 2(3.125,0)
  rect 1.524x1.524 smd: 1(-2.02,3.99) 1(-2.02,-3.99) 2(2.02,3.99) 2(2.02,-3.99)
  silkscreen extent -5.35,-5.35 5.35,5.35, body extent -4.92,-4.5 4.92,4.5, height 5.9
WE-PD_1210 [mm] "Wurth Elektronik recommended land pattern"
  rect 2.9x5.4 smd: 1(-4.95,0) 2(4.95,0)
  silkscreen extent -6,-6 6,6, body extent -6,-6 6,6, height 10.01
WEEE_Minimum [mil] "WEEElie bin"
  silkscreen extent -95,-172 99,104
WL-SMCC_0402_Green [mm] "SMD, 2-Leads, Body 1x0.5mm"
  rrect17% 0.6x0.6 smd: 1(-0.55,0) 2(0.55,0)
  body extent -0.5,-0.25 0.5,0.25, height 0.39
WL-SMCW_GREEN [mm] "WURTH"
  rect 0.8x0.8 smd: 1(-0.8,0) 2(0.8,0)
  silkscreen extent -1.9,-0.8 1.2,0.8, body extent -0.85,-0.45 0.85,0.45, height 0.8
WL-SMCW_RED [mm] "WURTH"
  rect 0.8x0.8 smd: 1(-0.8,0) 2(0.8,0)
  silkscreen extent -1.9,-0.8 1.2,0.8, body extent -0.85,-0.45 0.85,0.45, height 0.8
WURTH_61300211121 [mm] "Header, 2.54mm, 2x1, TH"
  rrect50% 1.65x1.65 hole 1.15: 1(-1.27,0)
  round 1.65 hole 1.15: 2(1.27,0)
  body extent -2.54,-1.27 2.54,1.27, height 8.54
WURTH_61300611121 [mm] "Header, 2.54mm, 6x1, TH"
  rrect50% 1.65x1.65 hole 1.15: 1(-6.35,0)
  round 1.65 hole 1.15: 2(-3.81,0) 3(-1.27,0) 4(1.27,0) 5(3.81,0) 6(6.35,0)
  body extent -7.62,-1.27 7.62,1.27, height 8.54
ZEH0083A-MFG [mm]
  round 0.3 smd paste+0 mask+0: A1(-3.25,3.25) A2(-2.6,3.25) A3(-1.95,3.25) A4(-1.3,3.25) A5(-0.65,3.25) A6(0,3.25) A7(0.65,3.25) A8(1.3,3.25) A9(1.95,3.25) A10(2.6,3.25) A11(3.25,3.25) B1(-3.25,2.6) B2(-2.6,2.6) B3(-1.95,2.6) B4(-1.3,2.6) B5(-0.65,2.6) B6(0,2.6) B7(0.65,2.6) B8(1.3,2.6) B9(1.95,2.6) B10(2.6,2.6) B11(3.25,2.6) C1(-3.25,1.95) C2(-2.6,1.95) C10(2.6,1.95) C11(3.25,1.95) D1(-3.25,1.3) D2(-2.6,1.3) D5(-0.65,1.3) D6(0,1.3) D7(0.65,1.3) D10(2.6,1.3) D11(3.25,1.3) E1(-3.25,0.65) E2(-2.6,0.65) E5(-0.65,0.65) E7(0.65,0.65) E10(2.6,0.65) E11(3.25,0.65) F1(-3.25,0) F2(-2.6,0) F5(-0.65,0) F6(0,0) F7(0.65,0) F10(2.6,0) F11(3.25,0) G1(-3.25,-0.65) G2(-2.6,-0.65) G5(-0.65,-0.65) G6(0,-0.65) G7(0.65,-0.65) G10(2.6,-0.65) G11(3.25,-0.65) H1(-3.25,-1.3) H2(-2.6,-1.3) H4(-1.3,-1.3) H8(1.3,-1.3) H10(2.6,-1.3) H11(3.25,-1.3) J1(-3.25,-1.95) J2(-2.6,-1.95) J10(2.6,-1.95) J11(3.25,-1.95) K1(-3.25,-2.6) K2(-2.6,-2.6) K3(-1.95,-2.6) K4(-1.3,-2.6) K5(-0.65,-2.6) K6(0,-2.6) K7(0.65,-2.6) K8(1.3,-2.6) K9(1.95,-2.6) K10(2.6,-2.6) K11(3.25,-2.6) L1(-3.25,-3.25) L3(-1.95,-3.25) L4(-1.3,-3.25) L5(-0.65,-3.25) L6(0,-3.25) L7(0.65,-3.25) L8(1.3,-3.25) L9(1.95,-3.25) L11(3.25,-3.25)
  silkscreen extent -4.7,-3.8 3.8,3.8, body extent -4.3,-4.3 4.3,4.3, height 0.25

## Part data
C1 C5 C8 C10: library part CMP-0009946-2, "CAP, AL, 10 uF, 200 V, +/- 20%, TH", Cap_Case="Radial 8x11.5mm", Manufacturer=Rubycon, Supplier Part Number 1=1189-1175-ND, Tolerance_%=20%, Value1=Unknown, Value2=200V, ValueDisplayed=10uF
C2 C6 C9 C11: library part CMP-0008585-2, "CAP, CERM, 0.1 uF, 200 V, +/- 10%, X7R, 1206", Cap_Case=1206, Manufacturer=Kemet, Supplier Part Number 1=399-8139-1-ND, TempCo=X7R, Tolerance_%=10%, Value1=Unknown, Value2=200V, ValueDisplayed=0.1uF
C3 C7 C12 C14: library part CMP-0084112-1, "CAP, CERM, 1 µF, 10 V,+/- 5%, X7R, AEC-Q200 Grade 1, 0603", Cap_Case=0603, Manufacturer=Kemet, TempCo=X7R, Tolerance_%=5%, Value2=10V, ValueDisplayed=1µF
C4 C13 C52 C62 C90: library part CMP-0006862-5, "CAP, CERM, 0.1 uF, 10 V, +/- 10%, X7R, 0603", Cap_Case=0603, Manufacturer=Kemet, Supplier Part Number 1=399-1095-1-ND, TempCo=X7R, Tolerance_%=10%, Value1=Unknown, Value2=10V, ValueDisplayed=0.1uF
C15 C21 C27 C33 C315 C316 C317 C318: library part CMP-0008970-2, "CAP, CERM, 1 uF, 100 V, +/- 10%, X7R, 1206", Cap_Case=2220, Manufacturer=MuRata, Supplier Part Number 1=490-3909-1-ND, TempCo=X7R, Tolerance_%=10%, Value1=Unknown, Value2=100V, ValueDisplayed=1uF
C16 C28 C70 C92: library part CMP-0006754-4, "CAP, CERM, 1 uF, 25 V, +/- 10%, X7R, 0603", Cap_Case=0603, Manufacturer=AVX, Supplier Part Number 1=478-10046-1-ND, TempCo=X7R, Tolerance_%=10%, Value1=Unknown, Value2=25V, ValueDisplayed=1uF
C17 C29: library part CMP-0008378-2, "CAP, CERM, 10 uF, 25 V, +/- 10%, X7R, 0805", Cap_Case=0805, Manufacturer=MuRata, Supplier Part Number 1=81-GRM21BZ71E106KE5L, TempCo=X7R, Tolerance_%=10%, Value1=Unknown, Value2=25V, ValueDisplayed=10uF
C18 C19 C22 C23: library part CMP-0094501-1, "1 µF ±10% 200V Ceramic Capacitor X7R 1812 (4532 Metric)", Digikey Part Number=1608-1812Y2500105KXTWS2CT-ND, Manufacturer="Knowles Syfer", Mouser Part Number=843-1812Y2500105KXT2, Operating Temperature Range="-55°C to +125°C", Part Number=1812Y2500105KXTWS2, TempCo=15%, Temperature Characteristic=X7R, Tolerance_%=10%, ValueDisplayed=1uF
C20 C32: library part CMP-0006751-4, "CAP, CERM, 100 pF, 25 V, +/- 10%, X7R, 0603", Cap_Case=0603, Manufacturer=AVX, Supplier Part Number 1=55J3899, TempCo=X7R, Tolerance_%=10%, Value1=Unknown, Value2=25V, ValueDisplayed=100pF
C24: library part CMP-0007445-4, "CAP, CERM, 100 nF, 50 V, +/- 10%, X7R, 0603", Cap_Case=0603, Manufacturer=MuRata, Supplier Part Number 1=490-12546-1-ND, TempCo=X7R, Tolerance_%=10%, Value1=Unknown, Value2=50V, ValueDisplayed=0.22uF
C25: library part CMP-0007487-4, "CAP, CERM, 6800 pF, 100 V, +/- 10%, X7R, 0603", Cap_Case=0603, Manufacturer=MuRata, Supplier Part Number 1=GRM188R72A682KA01D-ND, TempCo=X7R, Tolerance_%=10%, Value1=Unknown, Value2=100V, ValueDisplayed=6800pF
C26: library part CMP-0007469-4, "CAP, CERM, 0.1 uF, 100 V, +/- 10%, X7R, 0603", Cap_Case=0603, Manufacturer=MuRata, Supplier Part Number 1=490-3285-1-ND, TempCo=X7R, Tolerance_%=10%, Value1=Unknown, Value2=100V, ValueDisplayed=0.1uF
C30 C31 C34 C35: library part CMP-0750059-1, "CAP, CERM, 1 µF, 100 V,+/- 10%, X7S, 0805", Cap_Case=0805, Manufacturer=TDK, TempCo=X7S, Tolerance_%=10%, Value2=100V, ValueDisplayed=1µF
C36: library part CMP-0007445-4, "CAP, CERM, 0.22 uF, 50 V, +/- 10%, X7R, 0603", Cap_Case=0603, Manufacturer=MuRata, Supplier Part Number 1=490-12546-1-ND, TempCo=X7R, Tolerance_%=10%, Value1=Unknown, Value2=50V, ValueDisplayed=0.22uF
C37: library part CMP-0006826-4, "CAP, CERM, 22nF, 16 V, +/- 10%, X7R, 0603", Cap_Case=0603, Manufacturer="Wurth Elektronik", Supplier Part Number 1=710-885012206034, TempCo=X7R, Tolerance_%=10%, Value1=Unknown, Value2=16V, ValueDisplayed=1000pF
C38: library part CMP-0006830-4, "CAP, CERM, 0.22 uF, 16 V, +/- 10%, X7R, 0603", Cap_Case=0603, Manufacturer="Wurth Elektronik", Supplier Part Number 1=710-885012206048, TempCo=X7R, Tolerance_%=10%, Value1=Unknown, Value2=16V, ValueDisplayed=0.22uF
C39 C57 C101 C109 C112 C118: library part CMP-0006853-4, "CAP, CERM, 0.01 uF, 16 V, +/- 10%, X7R, 0603", Cap_Case=0603, Manufacturer=Kemet, Supplier Part Number 1=399-7841-1-ND, TempCo=X7R, Tolerance_%=10%, Value1=Unknown, Value2=16V, ValueDisplayed=0.01uF
C40 C61 C84: library part CMP-0006405-2, "CAP, CERM, 8.2 pF, 25 V, +/- 5%, C0G/NP0, 0402", Cap_Case=0402, Manufacturer=MuRata, Supplier Part Number 1=81-GRM1555C1E8R2CA1D, TempCo=C0G/NP0, Tolerance_%=5%, Value1=Unknown, Value2=25V, ValueDisplayed=8.2pF
C41: library part CMP-0011204-2, "CAP, AL, 47 uF, 50 V, +/- 20%, 0.68 ohm, AEC-Q200 Grade 2, SMD", Cap_Case=6.3x5.8mm, Manufacturer=Panasonic, Supplier Part Number 1=PCE5023CT-ND, Tolerance_%=20%, Value1="0.68 ohm", Value2=50V, ValueDisplayed=47uF
C42 C53 C63 C67 C88 C91: library part CMP-0081159-1, "CAP, CERM, 22 µF, 16 V,+/- 20%, X5R, 0603", Cap_Case=0603, Manufacturer=Samsung, Supplier Part Number 1=1276-7076-1-ND, TempCo=X5R, Tolerance_%=20%, Value2=16V, ValueDisplayed=22µF
C43 C68 C69 C85 C89 C99 C103 C104 C105 C106 C107 C113 C114 C115 C116 C117: library part CMP-0006864-4, "CAP, CERM, 0.1 uF, 16 V, +/- 20%, X7R, 0603", Cap_Case=0603, Manufacturer=Kemet, Supplier Part Number 1=399-1099-1-ND, TempCo=X7R, Tolerance_%=20%, Value1=Unknown, Value2=16V, ValueDisplayed=0.1uF
C44: library part CMP-0007010-5, "CAP, CERM, 0.1 uF, 50 V, +/- 10%, X5R, 0603", Cap_Case=0603, Manufacturer=TDK, Supplier Part Number 1=445-7456-1-ND, TempCo=X5R, Tolerance_%=10%, Value1="0.0296 ohm", Value2=50V, ValueDisplayed=0.1uF
C45 C47 C64 C66 C86: library part CMP-0008656-2, "CAP, CERM, 47 uF, 25 V, +/- 20%, X5R, 1206_190", Cap_Case=1206, Manufacturer=TDK, Supplier Part Number 1=445-8047-1-ND, TempCo=X5R, Tolerance_%=20%, Value1=Unknown, Value2=25V, ValueDisplayed=47uF
C46 C51 C60 C65 C83 C87: library part CMP-0007727-2, "CAP, CERM, 0.1 uF, 50 V, +/- 20%, X7R, 0805", Cap_Case=0805, Manufacturer=Kemet, Supplier Part Number 1=399-1169-1-ND, TempCo=X7R, Tolerance_%=20%, Value1="0.064 ohm", Value2=50V, ValueDisplayed=0.1uF
C48: library part CMP-0086153-1, "CAP, CERM, 10 µF, 50 V,+/- 10%, X5R, 1206", Cap_Case=1206, Manufacturer="Taiyo Yuden", TempCo=X5R, Tolerance_%=10%, Value2=50V, ValueDisplayed=10µF
C49 C50 C58 C59 C81 C82: library part CMP-0008702-2, "CAP, CERM, 4.7 uF, 50 V, +/- 10%, X7R, 1206", Cap_Case=1206_180, Manufacturer=TDK, Supplier Part Number 1=445-8032-1-ND, TempCo=X7R, Tolerance_%=10%, Value1="0.003158 ohm", Value2=50V, ValueDisplayed=4.7uF
C54: library part CMP-0007159-4, "CAP, CERM, 1000 pF, 25 V, +/- 5%, C0G/NP0, 0603", Cap_Case=0603, Manufacturer=MuRata, Supplier Part Number 1=GRM1885C1E102JA01D-ND, TempCo=C0G/NP0, Tolerance_%=5%, Value1=Unknown, Value2=25V, ValueDisplayed=1000pF
C55 C71 C93: library part CMP-0006608-2, "CAP, CERM, 1 uF, 25 V, +/- 10%, X5R, 0402", Cap_Case=0402, Manufacturer=MuRata, Supplier Part Number 1=490-10017-1-ND, TempCo=X5R, Tolerance_%=10%, Value1=Unknown, Value2=25V, ValueDisplayed=1uF
C56: library part CMP-0006996-4, "CAP, CERM, 220 pF, 250 V, +/- 5%, C0G/NP0, 0603", Cap_Case=0603, Manufacturer=TDK, PartNumber=C1608C0G2E221J080AA, Supplier Part Number 1=445-2316-1-ND, TempCo=C0G/NP0, Tolerance_%=5%, Value1=Unknown, Value2=250V, ValueDisplayed=220pF
C72 C94: library part CMP-0006608-2, "CAP, CERM, 0.1 uF, 25 V, +/- 10%, X5R, 0402", Cap_Case=0402, Manufacturer=MuRata, Supplier Part Number 1=490-10017-1-ND, TempCo=X5R, Tolerance_%=10%, Value1=Unknown, Value2=25V, ValueDisplayed=0.1uF
C73 C75: library part CMP-0006629-2, "CAP, CERM, 0.1 uF, 10 V, +/- 10%, X7R, 0402", Cap_Case=0402, Manufacturer=MuRata, Supplier Part Number 1=GRM155R71A104KA01D-ND, TempCo=X7R, Tolerance_%=10%, Value1=Unknown, Value2=10V, ValueDisplayed=0.1uF
C74: library part CMP-0007732-2, "CAP, CERM, 10 uF, 10 V, +/- 10%, X5R, 0805", Cap_Case=0805, Manufacturer=Kemet, Supplier Part Number 1=399-4925-1-ND, TempCo=X5R, Tolerance_%=10%, Value1="0.003 ohm", Value2=10V, ValueDisplayed=10uF
C76 C467: library part CMP-0086223-1, "CAP, CERM, 0.033 µF, 16 V,+/- 10%, X7R, 0603", Cap_Case=0603, Manufacturer="Samsung Electro-Mechanics", TempCo=X7R, Tolerance_%=10%, Value2=16V, ValueDisplayed=0.033µF
C77: library part CMP-0085855-1, "CAP, CERM, 10 µF, 10 V,+/- 10%, X5R, 0603", Cap_Case=0603, Manufacturer=MuRata, TempCo=X5R, Tolerance_%=10%, Value2=10V, ValueDisplayed=10µF
C78: library part CMP-0007313-5, "CAP, CERM, 47 uF, 6.3 V, +/- 20%, X5R, 0603", Cap_Case=0603, Manufacturer=MuRata, TempCo=X5R, Tolerance_%=20%, Value1=Unknown, Value2=6.3V, ValueDisplayed=47uF
C79 C80 C121 C122 C128 C461 C462: library part CMP-0086192-1, "CAP, CERM, 0.1 µF, 16 V,+/- 10%, X5R, 0201", Cap_Case=0201, Manufacturer=MuRata, TempCo=X5R, Tolerance_%=10%, Value2=16V, ValueDisplayed=0.1µF
C95 C96: library part CMP-0007002-5, "CAP, CERM, 1 uF, 10 V, +/- 10%, X5R, 0603", Cap_Case=0603, Manufacturer=TDK, Supplier Part Number 1=445-1321-1-ND, TempCo=X5R, Tolerance_%=10%, Value1=Unknown, Value2=10V, ValueDisplayed=1uF
C97 C98 C102 C108 C110: library part CMP-0007037-4, "CAP, CERM, 1 uF, 16 V, +/- 10%, X7R, 0603", Cap_Case=0603, Manufacturer=TDK, Supplier Part Number 1=445-1604-1-ND, TempCo=X7R, Tolerance_%=10%, Value1="0.0057 ohm", Value2=16V, ValueDisplayed=1uF
C100: library part CMP-0008572-2, "CAP, CERM, 1000 pF, 2000 V, +/- 10%, X7R, 1206_190", Cap_Case=1206, Manufacturer="Johanson Technology", TempCo=X7R, Tolerance_%=10%, Value1=Unknown, Value2=2000V, ValueDisplayed=1000pF
C111: library part CMP-0079605-1, "CAP, CERM, 2.2 µF, 16 V,+/- 10%, X7R, 0603", Cap_Case=0603, Manufacturer="Yageo America", Supplier Part Number 1=311-3490-1-ND, TempCo=X7R, Tolerance_%=10%, Value2=16V, ValueDisplayed=2.2µF
C119 C120: library part CMP-0006375-2, "CAP, CERM, 12 pF, 25 V, +/- 5%, C0G/NP0, 0402", Cap_Case=0402, Manufacturer=MuRata, Supplier Part Number 1=81-GRM1555C1E120JA1D, TempCo=C0G/NP0, Tolerance_%=5%, Value1=Unknown, Value2=25V, ValueDisplayed=12pF
C123 C127 C466: library part CMP-0006868-5, "CAP, CERM, 1 uF, 16 V, +/- 10%, X5R, 0603", Cap_Case=0603, Manufacturer=Kemet, Supplier Part Number 1=399-5090-1-ND, TempCo=X5R, Tolerance_%=10%, Value1=Unknown, Value2=16V, ValueDisplayed=1uF
C124 C125 C126: library part CMP-0007201-4, "CAP, CERM, 2400 pF, 50 V, +/- 5%, C0G/NP0, 0603", Cap_Case=0603, Manufacturer=MuRata, Supplier Part Number 1=490-3282-1-ND, TempCo=C0G/NP0, Tolerance_%=5%, Value1=Unknown, Value2=50V, ValueDisplayed=2400pF
C129 C130 C131 C132 C133 C134 C135: library part CMP-0006563-2, "CAP, CERM, 1 uF, 10 V, +/- 10%, X5R, 0402", Cap_Case=0402, Manufacturer=MuRata, Supplier Part Number 1=490-3890-1-ND, TempCo=X5R, Tolerance_%=10%, Value1=Unknown, Value2=10V, ValueDisplayed=1uF
C136: library part CMP-0007057-4, "CAP, CERM, 3.3 uF, 10 V, +/- 10%, X7S, 0603", Cap_Case=0603, Manufacturer=TDK, Supplier Part Number 1=445-14256-1-ND, TempCo=X7S, Tolerance_%=10%, Value1="0.004796 ohm", Value2=10V, ValueDisplayed=3.3uF
C137 C138 C141 C142 C145 C146 C149 C150 C153 C157 C158 C159 C160 C161 C162 C163 C164 C165 C166 C167 C168 C169 C170 C171 C172 C173 C177 C178 C180 C183 C184 C187 C190 C193 C194 C195 C196 C197 C198 C199 C200 C201 C202 C203 C204 C205 C206 C207 C208 C209 C214 C216 C217 C218 C219 C220 C221 C459 C463 C464 C465: library part CMP-0009717-2, "CAP, CERM, 0.1 uF, 16 V, +/- 10%, X5R, 0201", Cap_Case=0201, Manufacturer=MuRata, Supplier Part Number 1=490-9985-1-ND, TempCo=X5R, Tolerance_%=10%, Value1=Unknown, Value2=16V, ValueDisplayed=0.1uF
C139 C143 C147 C151 C154 C174 C175 C176 C181 C185 C188 C191 C210 C211 C212 C215: library part CMP-0860568-1, "CAP, CERM, 0.01 µF, 25 V,+/- 10%, X7R, 0201", Cap_Case=0201, Manufacturer=MuRata, TempCo=X7R, Tolerance_%=10%, Value2=25V, ValueDisplayed=0.01µF
C140 C144 C148 C152 C156 C179 C182 C186 C189 C192 C213 C460: library part CMP-0006582-2, "CAP, CERM, 4.7 uF, 10 V, +/- 20%, X5R, 0402", Cap_Case=0402, Manufacturer=MuRata, TempCo=X5R, Tolerance_%=20%, Value1=Unknown, Value2=10V, ValueDisplayed=4.7uF
C155: library part CMP-0074692-1, "CAP, CERM, 10 µF, 10 V,+/- 20%, X5R, 0402", Cap_Case=0402, Manufacturer=MuRata, TempCo=X5R, Tolerance_%=20%, Value2=10V, ValueDisplayed=10µF
C222 C224 C237 C238 C268 C269: library part CMP-0006210-2, "CAP, CERM, 0.01 uF, 16 V, +/- 10%, X7R, 0402", Cap_Case=0402, Manufacturer="AT Ceramics", Supplier Part Number 1=1284-1540-1-ND, TempCo=X7R, Tolerance_%=10%, Value1=Unknown, Value2=16V, ValueDisplayed=0.01uF
C223 C225 C226 C227 C228 C229 C230 C231 C232 C233 C234 C235 C236: library part CMP-0078241-1, "CAP, CERM, 0.1 µF, 10 V,+/- 10%, X7R, 0402", Cap_Case=0402, Manufacturer=Kemet, Supplier Part Number 1=399-3520-1-ND, TempCo=X7R, Tolerance_%=10%, Value2=10V, ValueDisplayed=0.1µF
C239 C240 C241 C270 C271 C272: library part CMP-0006846-4, "CAP, CERM, 1000 pF, 25 V, +/- 10%, C0G/NP0, 0603", Cap_Case=0603, Manufacturer=Kemet, Supplier Part Number 1=399-7833-1-ND, TempCo=C0G/NP0, Tolerance_%=10%, Value1="0 ohm", Value2=25V, ValueDisplayed=1000pF
C242 C243 C244 C245 C246 C247 C248 C249 C258 C259 C260 C261 C262 C263 C264 C265 C273 C274 C275 C276 C277 C278 C279 C280 C289 C290 C291 C292 C293 C294 C295 C296: library part CMP-0007897-1, "CAP, CERM, 0.1 uF, 250 V, +/- 10%, X7T, 0805", Cap_Case=0805, Manufacturer=TDK, Supplier Part Number 1=445-7749-1-ND, TempCo=X7T, Tolerance_%=10%, Value1=Unknown, Value2=250V, ValueDisplayed=0.1uF
C250 C251 C252 C253 C254 C255 C256 C257 C266 C267 C281 C282 C283 C284 C285 C286 C287 C288 C297 C298 C300 C301 C302 C304 C305 C306 C308 C309 C310 C312 C313 C314 C380 C381 C382 C384 C385 C386 C388 C389 C390 C392 C393 C394: library part CMP-0009637-3, "CAP, CERM, 0.1 uF, 16 V, +/- 10%, X6S, 0201", Cap_Case=0201, Manufacturer=TDK, Supplier Part Number 1=445-15903-1-ND, TempCo=X6S, Tolerance_%=10%, Value1=Unknown, Value2=16V, ValueDisplayed=0.1uF
C299 C303 C307 C311 C379 C383 C387 C391: library part CMP-0079630-1, "CAP, CERM, 1 µF, 16 V,+/- 10%, X7R, AEC-Q200 Grade 1, 0805", Cap_Case=0805, Manufacturer=Kemet, Supplier Part Number 1=399-6930-1-ND, TempCo=X7R, Tolerance_%=10%, Value2=16V, ValueDisplayed=1µF
C471 C472 C473 C474 C475 C476 C477 C478 C479 C480 C481 C482 C483 C484 C485 C486 C487 C488 C489 C490 C491 C492 C493 C494 C495 C496 C497 C498 C499 C500 C501 C502: library part CMP-0006241-2, "CAP, CERM, 20 pF, 50 V, +/- 5%, C0G/NP0, 0402", Cap_Case=0402, Manufacturer=Kemet, Supplier Part Number 1=399-7773-1-ND, TempCo=C0G/NP0, Tolerance_%=5%, Value1=Unknown, Value2=50V, ValueDisplayed=20pF
C503 C504: library part CMP-0006855-4, "CAP, CERM, 0.1 uF, 25 V, +/- 5%, X7R, 0603", Cap_Case=0603, Manufacturer=Kemet, Supplier Part Number 1=1650833, TempCo=X7R, Tolerance_%=5%, Value1=Unknown, Value2=25V, ValueDisplayed=0.1uF
D1: library part CMP-0077070-3, "Diode, Schottky, 45 V, 15 A, AEC-Q101, CFP15", Manufacturer=Nexperia, Value1=15A, Value2=0.49V
D9 D10 D11 D12: library part CMP-0082118-3, "Diode, Zener, 110 V, 200 mW, SOD-323F", Manufacturer=Rohm, Power_W=200mW, Value1=0.2W
D13 D14: library part CMP-0076995-2, "Diode, Schottky, 200 V, 4 A, SMC", Manufacturer="ON Semiconductor", Value1=4A, Value2=0.86V
D15 D17 D18 D19 D20 D22 D23 D24: library part CMP-0028521-2, "Diode, Schottky, 100 V, 1 A, SMB", Manufacturer="ON Semiconductor", Value1=1A, Value2=0.75V
D16 D21: library part CMP-0028776-2, "Diode, Schottky, 200 V, 2 A, SOD-123FL", Manufacturer="ON Semiconductor", Value1=2A, Value2=0.94V
D25: library part CMP-0005752-4, "Diode, Zener, 13 V, 500 mW, SOD-123", Manufacturer="Diodes Inc.", Power_W=500mW, Value1=0.5W
D26 D27 D28: library part CMP-0002894-2, "LED, Green, SMD", Color=green, Manufacturer="Wurth Elektronik", Value1=W, Value2=2V
D29 D30: library part CMP-0002947-3, "LED, Red, SMD", Color=Red, Manufacturer="Wurth Elektronik", Power_TotalModule=72mW, Value1=0.072W, Value2=2V
D31: library part CMP-0081765-2, "LED, Green, SMD", Color=Green, Manufacturer="Wurth Elektronik", Power_TotalModule=99mW, Value1=0.099W, Value2=3.2V
D32 D33 D34: library part CMP-0073601-1, "1-Channel ESD Protection Diode for USB Type-C and Thunderbolt 3, DPL0002A (X2SON-2)", Alternate Manufacturer="Texas Instruments", Alternate PartNumber=TPD1E01B04DPLT
F1: library part CMP-0082398-1, "Fuse, 10 A, 125VAC/VDC, SMD", Irating_A=10A, Manufacturer=Littelfuse, Supplier Part Number 1=F2591CT-ND
FB1 FB2: library part CMP-0093223-1, "Chip Ferrite Bead Array, 1206, 50Ω @ 100MHz, 0.0016Ω, 25%, 12A", Impedance At Frequency="50Ω @ 100MHz", Manufacturer=Murata, Operating Temperature Range="-55°C to +125℃", Test Frequency=100MHz, Tolerance_%=25%
FB3 FB4 FB5 FB6 FB7 FB8 FB9 FB10 FB11 FB12 FB13 FB14 FB15 FB16 FB17: library part CMP-0092257-1, "180 Ohms @ 100MHz 1 Power Line Ferrite Bead 0603 (1608 Metric) 2A 50mOhm", Digikey Part Number=445-5220-1-ND, Impedance At Frequency="180Ω @ 100MHz", Manufacturer="TDK Corporation", Mouser Part Number=810-MPZ1608S181ATAH0, Operating Temperature Range="-55°C to +125°C", Part Number=MPZ1608S181ATAH0, Tolerance_%=25%
FID1 FID2 FID3 FID4 FID5 FID6: library part CMP-0077181-1, "Fiducial mark.  There is nothing to buy or mount.", Manufacturer=N/A
H1 H2 H3 H4: library part CMP-0003617-1, "Machine Screw, Round, #4-40 x 1/4, Nylon, Philips panhead", Manufacturer="B&F Fastener Supply", Supplier Part Number 1=H542-ND
H5 H6 H7 H8: library part CMP-0003610-1, "Standoff, Hex, 0.5\"L #4-40 Nylon", Manufacturer=Keystone, Supplier Part Number 1=36-1902C-ND
J1 J2: library part CMP-0055500-1, "Terminal Block, 3x1, 2.54 mm, TH", Manufacturer="Phoenix Contact", Supplier Part Number 1=277-1274-ND
J3: library part CMP-0055512-1, "Terminal Block, 6x1, 2.54mm, TH", Color=Green, Current_A=6A, Manufacturer="Phoenix Contact", Supplier Part Number 1=277-1277-ND, Voltage_V=160V
J4 J7 J8 J13 J14 J15 J16 J17 J18 J19 J20 J21 J22: library part CMP-0054794-2, "Header, 2.54 mm, 2x1, Gold, TH", Color=Black, Manufacturer="Wurth Elektronik", Supplier Part Number 1=732-5315-ND
J5: library part CMP-0086695-3, "USB - micro B USB 2.0 Receptacle Connector 5 Position Surface Mount, Right Angle; Through Hole", Current_A=3A, Manufacturer="Wurth Electronics", Voltage_V=30V
J6: library part CMP-0054801-2, "Header, 2.54 mm, 6x1, Gold, TH", Color=Black, Manufacturer="Wurth Elektronik", Supplier Part Number 1=732-5319-ND
J9 J10: library part CMP-0860003-1, "Receptacle, 0.5mm, 60x2, Gold, SMD", Current_A=500mA, Manufacturer=Panasonic, Voltage_V=60V
J11 J12: library part CMP-0084279-1, "Header (Shrouded), 1.27mm, 16x2, Gold, SMT", Color=Black, Manufacturer=Harting, Voltage_V=500V
L1 L6: library part CMP-0064542-2, "Inductor, Shielded Drum Core, Ferrite, 47 uH, 3.8 A, 0.04593 ohm, SMD", Manufacturer="Wurth Elektronik", Supplier Part Number 1=732-1246-1-ND, Value1="0.04593 ohm", Value2=3.8A, ValueDisplayed=47uH
L2 L5 L7 L10: library part CMP-0058735-1, "Inductor, Multilayer, Ferrite, 2.2 uH, 0.75 A, 0.03 ohm, SMD", Manufacturer=MuRata, Supplier Part Number 1=LQM18PN2R2MFRL-ND, Value1="0.03 ohm", Value2=0.75A, ValueDisplayed=2.2uH
L3 L4 L8 L9: library part CMP-0064617-2, "Inductor, Drum Core, Ferrite, 47 uH, 1.45 A, 0.095 ohm, SMD", Manufacturer="Wurth Elektronik", Supplier Part Number 1=732-1304-1-ND, Value1="0.095 ohm", Value2=1.45A, ValueDisplayed=47uH
L11 L12 L14: library part CMP-0089431-1, "70 Ohms @ 100MHz 1 Power Line Ferrite Bead 0603 (1608 Metric) 4A 20mOhm", Digikey Part Number=490-5224-1-ND, Impedance At Frequency="70Ω @ 100MHz", Manufacturer=Murata, Mouser Part Number=81-BLM18SG700TN1D, Operating Temperature Range="-55°C to +125°C", Tolerance_%=25%
L13: library part CMP-0057236-1, "Inductor, Drum Core, Ferrite, 2.2 uH, 6.5 A, 0.0077 ohm, SMD", Manufacturer=Bourns, Supplier Part Number 1=1463508, Value1="0.0077 ohm", Value2=6.5A, ValueDisplayed=2.2uH
LBL1: library part CMP-0003625-1, "Thermal Transfer Printable Labels, 0.650\" W x 0.200\" H - 10,000 per roll", Manufacturer=Brady, Supplier Part Number 1=97C5133
Logo1: library part CMP-0074838-1, "Texas Instrument Corporate Signature"
Logo2: library part CMP-0074844-1
Logo3: library part CMP-0074847-1, "FCC_disclaimer"
Logo4: library part CMP-0074769-3, Manufacturer="Texas Instruments"
LOGO5: library part CMP-0074835-1, "IEC 61010-1 High Voltage Warning"
Logo6: library part CMP-0074837-2, "IEC 61010-1 Hot Surface Warning", Manufacturer="Texas Instruments"
Q1: library part CMP-0001055-1, "MOSFET, N-CH, 150 V, Ta-16 A, QFN-8", Alternate Manufacturer=None, Manufacturer="Fairchild Semiconductor", Supplier Part Number 1=FDMC86240CT-ND, Value2="11 nC"
Q2 Q4: library part CMP-0000776-1, "MOSFET, N-CH, 60 V, 0.115 A, SOT-323", Alternate Manufacturer=None, Manufacturer="Diodes Inc.", Supplier Part Number 1=2N7002W-FDICT-ND, Value1=7
Q3: library part CMP-0047093-1, "100-V, N channel NexFET power MOSFET, single SON 3 mm x 3 mm, 61 mOhm", Digikey Part Number=296-44352-1-ND, Drain To Source Breakdown Voltage=100V, Input Capacitace At Vds="349pF @ 50V", Manufacturer="Texas Instruments", Mouser Part Number=595-CSD19538Q3A, Operating Temperature Range="-55°C to +150°C", Power_W=2.8W, Pulse Drain Current=37A, Typ Forward Diode Voltage=0.85V
Q5 Q6: library part CMP-0000248-1, "MOSFET, N-CH, 25 V, 5 A, DQK0006C (WSON-6)", Alternate Manufacturer=None, Manufacturer="Texas Instruments", Supplier Part Number 1=296-25260-1-ND, Value1=0.02, Value2="2 nC"
R1 R2 R6 R7 R53 R512: library part CMP-0023626-3, "RES, 10.0 k, 0.01%, 0.063 W, 0603", Manufacturer="Stackpole Electronics Inc", Power_W=63mW, Supplier Part Number 1=RNCF0603TKY10K0CT-ND, TempCo="5 ppm/C", Tolerance_%=0.01%, Value2=0.063W, Value_Code=10k0, ValueDisplayed=10.0k
R3 R4 R5 R8: library part CMP-0018819-2, "RES, 100 k, 0.1%, 0.25 W, AEC-Q200 Grade 1, 1206", Manufacturer=Vishay-Dale, Power_W=250mW, Supplier Part Number 1=TNP100KACCT-ND, TempCo="25 ppm/C", Tolerance_%=0.1%, Value2=0.25W, Value_Code=100k
R9 R22: library part CMP-0021048-3, "RES, 680 k, 1%, 0.125 W, AEC-Q200 Grade 0, 0805", Manufacturer=Vishay-Dale, Power_W=125mW, Supplier Part Number 1=541-215KCCT-ND, TempCo="100 ppm/C", Tolerance_%=1%, Value2=0.125W, Value_Code=215k, ValueDisplayed=680k
R10 R23: library part CMP-0022003-4, "RES, 10.0, 1%, 0.1 W, AEC-Q200 Grade 0, 0603", Manufacturer=Vishay-Dale, Power_W=100mW, Supplier Part Number 1=541-10.0HCT-ND, TempCo="100 ppm/C", Tolerance_%=1%, Value2=0.1W, Value_Code=10R0, ValueDisplayed=10.0
R11 R24: library part CMP-0021048-3, "RES, 150k, 1%, 0.125 W, AEC-Q200 Grade 0, 0805", Manufacturer=Vishay-Dale, Power_W=125mW, Supplier Part Number 1=541-215KCCT-ND, TempCo="100 ppm/C", Tolerance_%=1%, Value2=0.125W, Value_Code=215k, ValueDisplayed=150k
R12 R25: library part CMP-0022588-5, "RES, 750, 1%, 0.1 W, AEC-Q200 Grade 0, 0603", Manufacturer=Vishay-Dale, Power_W=100mW, Supplier Part Number 1=541-750HCT-ND, TempCo="100 ppm/C", Tolerance_%=1%, Value2=0.1W, Value_Code=750R, ValueDisplayed=750
R13 R26: library part CMP-0015054-3, "RES, 0.01, 1%, 1 W, AEC-Q200 Grade 0, 0612", Manufacturer=Panasonic, Power_W=1W, Supplier Part Number 1=ERJ-B2CFR01V-ND, TempCo="300 ppm/C", Tolerance_%=1%, Value_Code=R010, ValueDisplayed=0.01
R14 R21: library part CMP-0022322-4, "RES, 309 k, 1%, 0.1 W, AEC-Q200 Grade 0, 0603", Manufacturer=Vishay-Dale, Power_W=100mW, Supplier Part Number 1=541-309KHCT-ND, TempCo="100 ppm/C", Tolerance_%=1%, Value2=0.1W, Value_Code=309k
R15 R27: library part CMP-0023475-3, "RES, 220 k, 0.1%, 0.1 W, 0603", Manufacturer="Susumu Co Ltd", Power_W=100mW, Supplier Part Number 1=RG16P220KBCT-ND, TempCo="25 ppm/C", Tolerance_%=0.1%, Value2=0.1W, Value_Code=220k
R16: library part CMP-0025766-4, "RES, 27 k, 5%, 0.1 W, AEC-Q200 Grade 0, 0603", Manufacturer=Vishay-Dale, Power_W=100mW, Supplier Part Number 1=541-27KGCT-ND, TempCo="200 ppm/C", Tolerance_%=5%, Value2=0.1W, Value_Code=27k0, ValueDisplayed=27k
R17 R29: library part CMP-0023766-3, "RES, 150 k, 0.1%, 0.1 W, 0603", Manufacturer="Yageo America", Power_W=100mW, TempCo="25 ppm/C", Tolerance_%=0.1%, Value2=0.1W, Value_Code=150k
R18: library part CMP-0025733-4, "RES, 1.5 k, 5%, 0.1 W, AEC-Q200 Grade 0, 0603", Manufacturer=Vishay-Dale, Power_W=100mW, Supplier Part Number 1=541-1.5KGCT-ND, TempCo="200 ppm/C", Tolerance_%=5%, Value2=0.1W, Value_Code=1k50, ValueDisplayed=1.5k
R19: library part CMP-0025707-4, "RES, 11 k, 5%, 0.1 W, AEC-Q200 Grade 0, 0603", Manufacturer=Vishay-Dale, Power_W=100mW, Supplier Part Number 1=541-11KGCT-ND, TempCo="200 ppm/C", Tolerance_%=5%, Value2=0.1W, Value_Code=11k0, ValueDisplayed=11k
R20 R32: library part CMP-0023619-3, "RES, 9.10 k, 0.1%, 0.1 W, 0603", Manufacturer="Susumu Co Ltd", Power_W=100mW, Supplier Part Number 1=RG16P9.1KBCT-ND, TempCo="25 ppm/C", Tolerance_%=0.1%, Value2=0.1W, Value_Code=9k10, ValueDisplayed=9.10k
R28: library part CMP-0022408-4, "RES, 402 k, 1%, 0.1 W, AEC-Q200 Grade 0, 0603", Manufacturer=Vishay-Dale, Power_W=100mW, Supplier Part Number 1=541-402KHCT-ND, TempCo="100 ppm/C", Tolerance_%=1%, Value2=0.1W, Value_Code=402k
R30: library part CMP-0025786-4, "RES, 33 k, 5%, 0.1 W, AEC-Q200 Grade 0, 0603", Manufacturer=Vishay-Dale, Power_W=100mW, Supplier Part Number 1=541-33KGCT-ND, TempCo="200 ppm/C", Tolerance_%=5%, Value2=0.1W, Value_Code=33k0, ValueDisplayed=33k
R31 R48 R71 R73 R82 R83 R84 R85 R154 R155 R156 R157 R158 R159 R515 R516: library part CMP-0022895-5, "RES, 1.00 k, 1%, 0.1 W, 0603", Manufacturer=Yageo, Power_W=100mW, Supplier Part Number 1=311-1.00KHRCT-ND, TempCo="100 ppm/C", Tolerance_%=1%, Value2=0.1W, Value_Code=1k00, ValueDisplayed=1.00k
R33: library part CMP-0022066-4, "RES, 15.0 k, 1%, 0.1 W, AEC-Q200 Grade 0, 0603", Manufacturer=Vishay-Dale, Power_W=100mW, Supplier Part Number 1=541-15.0KHCT-ND, TempCo="100 ppm/C", Tolerance_%=1%, Value2=0.1W, Value_Code=15k0, ValueDisplayed=15.0k
R34: library part CMP-0022447-4, "RES, 332k, 1%, 0.1 W, AEC-Q200 Grade 0, 0603", Manufacturer=Vishay-Dale, Power_W=100mW, Supplier Part Number 1=541-49.9KHCT-ND, TempCo="100 ppm/C", Tolerance_%=1%, Value2=0.1W, Value_Code=49k9, ValueDisplayed=332k
R35: library part CMP-0022430-4, "RES, 45.3 k, 1%, 0.1 W, AEC-Q200 Grade 0, 0603", Manufacturer=Vishay-Dale, Power_W=100mW, Supplier Part Number 1=541-45.3KHCT-ND, TempCo="100 ppm/C", Tolerance_%=1%, Value2=0.1W, Value_Code=45k3, ValueDisplayed=45.3k
R36 R46: library part CMP-0023744-2, "RES, 374 k, 0.1%, 0.1 W, 0603", Manufacturer="Yageo America", Power_W=100mW, TempCo="25 ppm/C", Tolerance_%=0.1%, Value2=0.1W, Value_Code=142k, ValueDisplayed=374k
R37 R41 R52 R68: library part CMP-0026827-3, "RES, 10, 5%, 0.063 W, AEC-Q200 Grade 0, 0402", Manufacturer=Vishay-Dale, Power_W=63mW, Supplier Part Number 1=541-10JCT-ND, TempCo="200 ppm/C", Tolerance_%=5%, Value2=0.063W, Value_Code=10R0, ValueDisplayed=10
R38 R50 R65: library part CMP-0022447-4, "RES, 10 k, 1%, 0.1 W, AEC-Q200 Grade 0, 0603", Manufacturer=Vishay-Dale, Power_W=100mW, Supplier Part Number 1=541-49.9KHCT-ND, TempCo="100 ppm/C", Tolerance_%=1%, Value2=0.1W, Value_Code=49k9, ValueDisplayed=10k
R39 R51: library part CMP-0025685-3, "RES, 100 k, 0.1%, 0.1 W, AEC-Q200 Grade 1, 0603", Manufacturer=Vishay-Dale, Power_W=100mW, Supplier Part Number 1=TNP100KAACT-ND, TempCo="25 ppm/C", Tolerance_%=0.1%, Value2=0.1W, Value_Code=100k
R40: library part CMP-0022447-4, "RES, 102k, 1%, 0.1 W, AEC-Q200 Grade 0, 0603", Manufacturer=Vishay-Dale, Power_W=100mW, Supplier Part Number 1=541-49.9KHCT-ND, TempCo="100 ppm/C", Tolerance_%=1%, Value2=0.1W, Value_Code=49k9, ValueDisplayed=102k
R42 R137 R146 R452 R458 R459 R460 R461 R462 R463 R464 R465 R466 R467 R468 R469 R470 R471 R472 R473 R474 R475 R476 R477 R478 R479 R480 R481 R482 R483 R484 R485: library part CMP-0026791-1, "RES, 50, 0.1%, 0.05 W, 0402", Manufacturer=Vishay-Dale, Power_W=50mW, Supplier Part Number 1=FC0402-50BWCT-ND, TempCo="25 ppm/C", Tolerance_%=0.1%, Value2=0.05W, Value_Code=50R0, ValueDisplayed=50
R43 R55: library part CMP-0024014-3, "RES, 26.1 k, 0.1%, 0.1 W, 0603", Manufacturer="Yageo America", Power_W=100mW, TempCo="25 ppm/C", Tolerance_%=0.1%, Value2=0.1W, Value_Code=26k1, ValueDisplayed=26.1k
R44: library part CMP-0022447-4, "RES, 45.3 k, 1%, 0.1 W, AEC-Q200 Grade 0, 0603", Manufacturer=Vishay-Dale, Power_W=100mW, Supplier Part Number 1=541-49.9KHCT-ND, TempCo="100 ppm/C", Tolerance_%=1%, Value2=0.1W, Value_Code=49k9, ValueDisplayed=45.3k
R45: library part CMP-0022971-4, "RES, 287 k, 1%, 0.1 W, 0603", Manufacturer=Yageo, Power_W=100mW, Supplier Part Number 1=311-287KHRCT-ND, TempCo="100 ppm/C", Tolerance_%=1%, Value2=0.1W, Value_Code=287k
R47 R64 R166 R443 R447 R486 R488 R492 R494 R496 R500 R502 R504 R509 R511: library part CMP-0025874-4, "RES, 0, 5%, 0.1 W, AEC-Q200 Grade 0, 0603", Manufacturer=Panasonic, Power_W=100mW, Supplier Part Number 1=P0.0GCT-ND, TempCo="600 ppm/C", Tolerance_%=5%, Value2=0.1W, Value_Code=0000, ValueDisplayed=0
R49: library part CMP-0022777-5, "RES, 12.4 k, 1%, 0.1 W, 0603", Manufacturer=Yageo, Power_W=100mW, Supplier Part Number 1=311-12.4KHRCT-ND, TempCo="100 ppm/C", Tolerance_%=1%, Value2=0.1W, Value_Code=12k4, ValueDisplayed=12.4k
R54 R63: library part CMP-0022705-3, "RES, 49.9 k, 1%, 0.1 W, AEC-Q200 Grade 0, 0603", Manufacturer=Panasonic, Power_W=100mW, Supplier Part Number 1=P49.9KHCT-ND, TempCo="100 ppm/C", Tolerance_%=1%, Value2=0.1W, Value_Code=49k9, ValueDisplayed=49.9k
R56: library part CMP-0015361-2, "RES, 0, 5%, 0.25 W, 1210", Manufacturer=Rohm, Power_W=250mW, Supplier Part Number 1=RHM0.0BECT-ND, TempCo="20 ppm/C", Tolerance_%=5%, Value2=0.25W, Value_Code=0000, ValueDisplayed=0
R57: library part CMP-0025958-3, "RES, 10.0 k, 1%, 0.063 W, AEC-Q200 Grade 0, 0402", Manufacturer=Vishay-Dale, Power_W=63mW, Supplier Part Number 1=541-10.0KLCT-ND, TempCo="100 ppm/C", Tolerance_%=1%, Value2=0.063W, Value_Code=10k0, ValueDisplayed=10.0k
R58 R67: library part CMP-0022447-4, "RES, 0, 1%, 0.1 W, AEC-Q200 Grade 0, 0603", Manufacturer=Vishay-Dale, Power_W=100mW, Supplier Part Number 1=541-49.9KHCT-ND, TempCo="100 ppm/C", Tolerance_%=1%, Value2=0.1W, Value_Code=49k9, ValueDisplayed=0
R59: library part CMP-0023219-5, "RES, 620, 1%, 0.1 W, 0603", Manufacturer=Yageo, Power_W=100mW, Supplier Part Number 1=311-620HRCT-ND, TempCo="100 ppm/C", Tolerance_%=1%, Value2=0.1W, Value_Code=620R, ValueDisplayed=620
R60: library part CMP-0022447-4, "RES, 100k, 1%, 0.1 W, AEC-Q200 Grade 0, 0603", Manufacturer=Vishay-Dale, Power_W=100mW, Supplier Part Number 1=541-49.9KHCT-ND, TempCo="100 ppm/C", Tolerance_%=1%, Value2=0.1W, Value_Code=49k9, ValueDisplayed=100k
R61: library part CMP-0022447-4, "RES, 23.2k, 1%, 0.1 W, AEC-Q200 Grade 0, 0603", Manufacturer=Vishay-Dale, Power_W=100mW, Supplier Part Number 1=541-49.9KHCT-ND, TempCo="100 ppm/C", Tolerance_%=1%, Value2=0.1W, Value_Code=49k9, ValueDisplayed=23.2k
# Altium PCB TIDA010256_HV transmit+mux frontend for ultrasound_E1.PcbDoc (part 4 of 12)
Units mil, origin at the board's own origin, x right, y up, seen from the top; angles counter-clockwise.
Board outline 6192.49 x 6712.23 mil, 16 copper layers (Top Layer, Layer 2 - GND, Layer 3 - SIG, Layer 4 - GND, Layer 5 - SIG, Layer 6 - SIG, Layer 7 - GND, Layer 8 - HV PWR, Layer 9 - LV PWR, Layer 10 - GND, Layer 11 - SIG, Layer 12 - SIG, Layer 13 - GND, Layer 14 - SIG, Layer 15 - GND, Bottom Layer), stack 95.905 mil thick; 806 components, 539 nets, 3343 pads, 1848 vias.

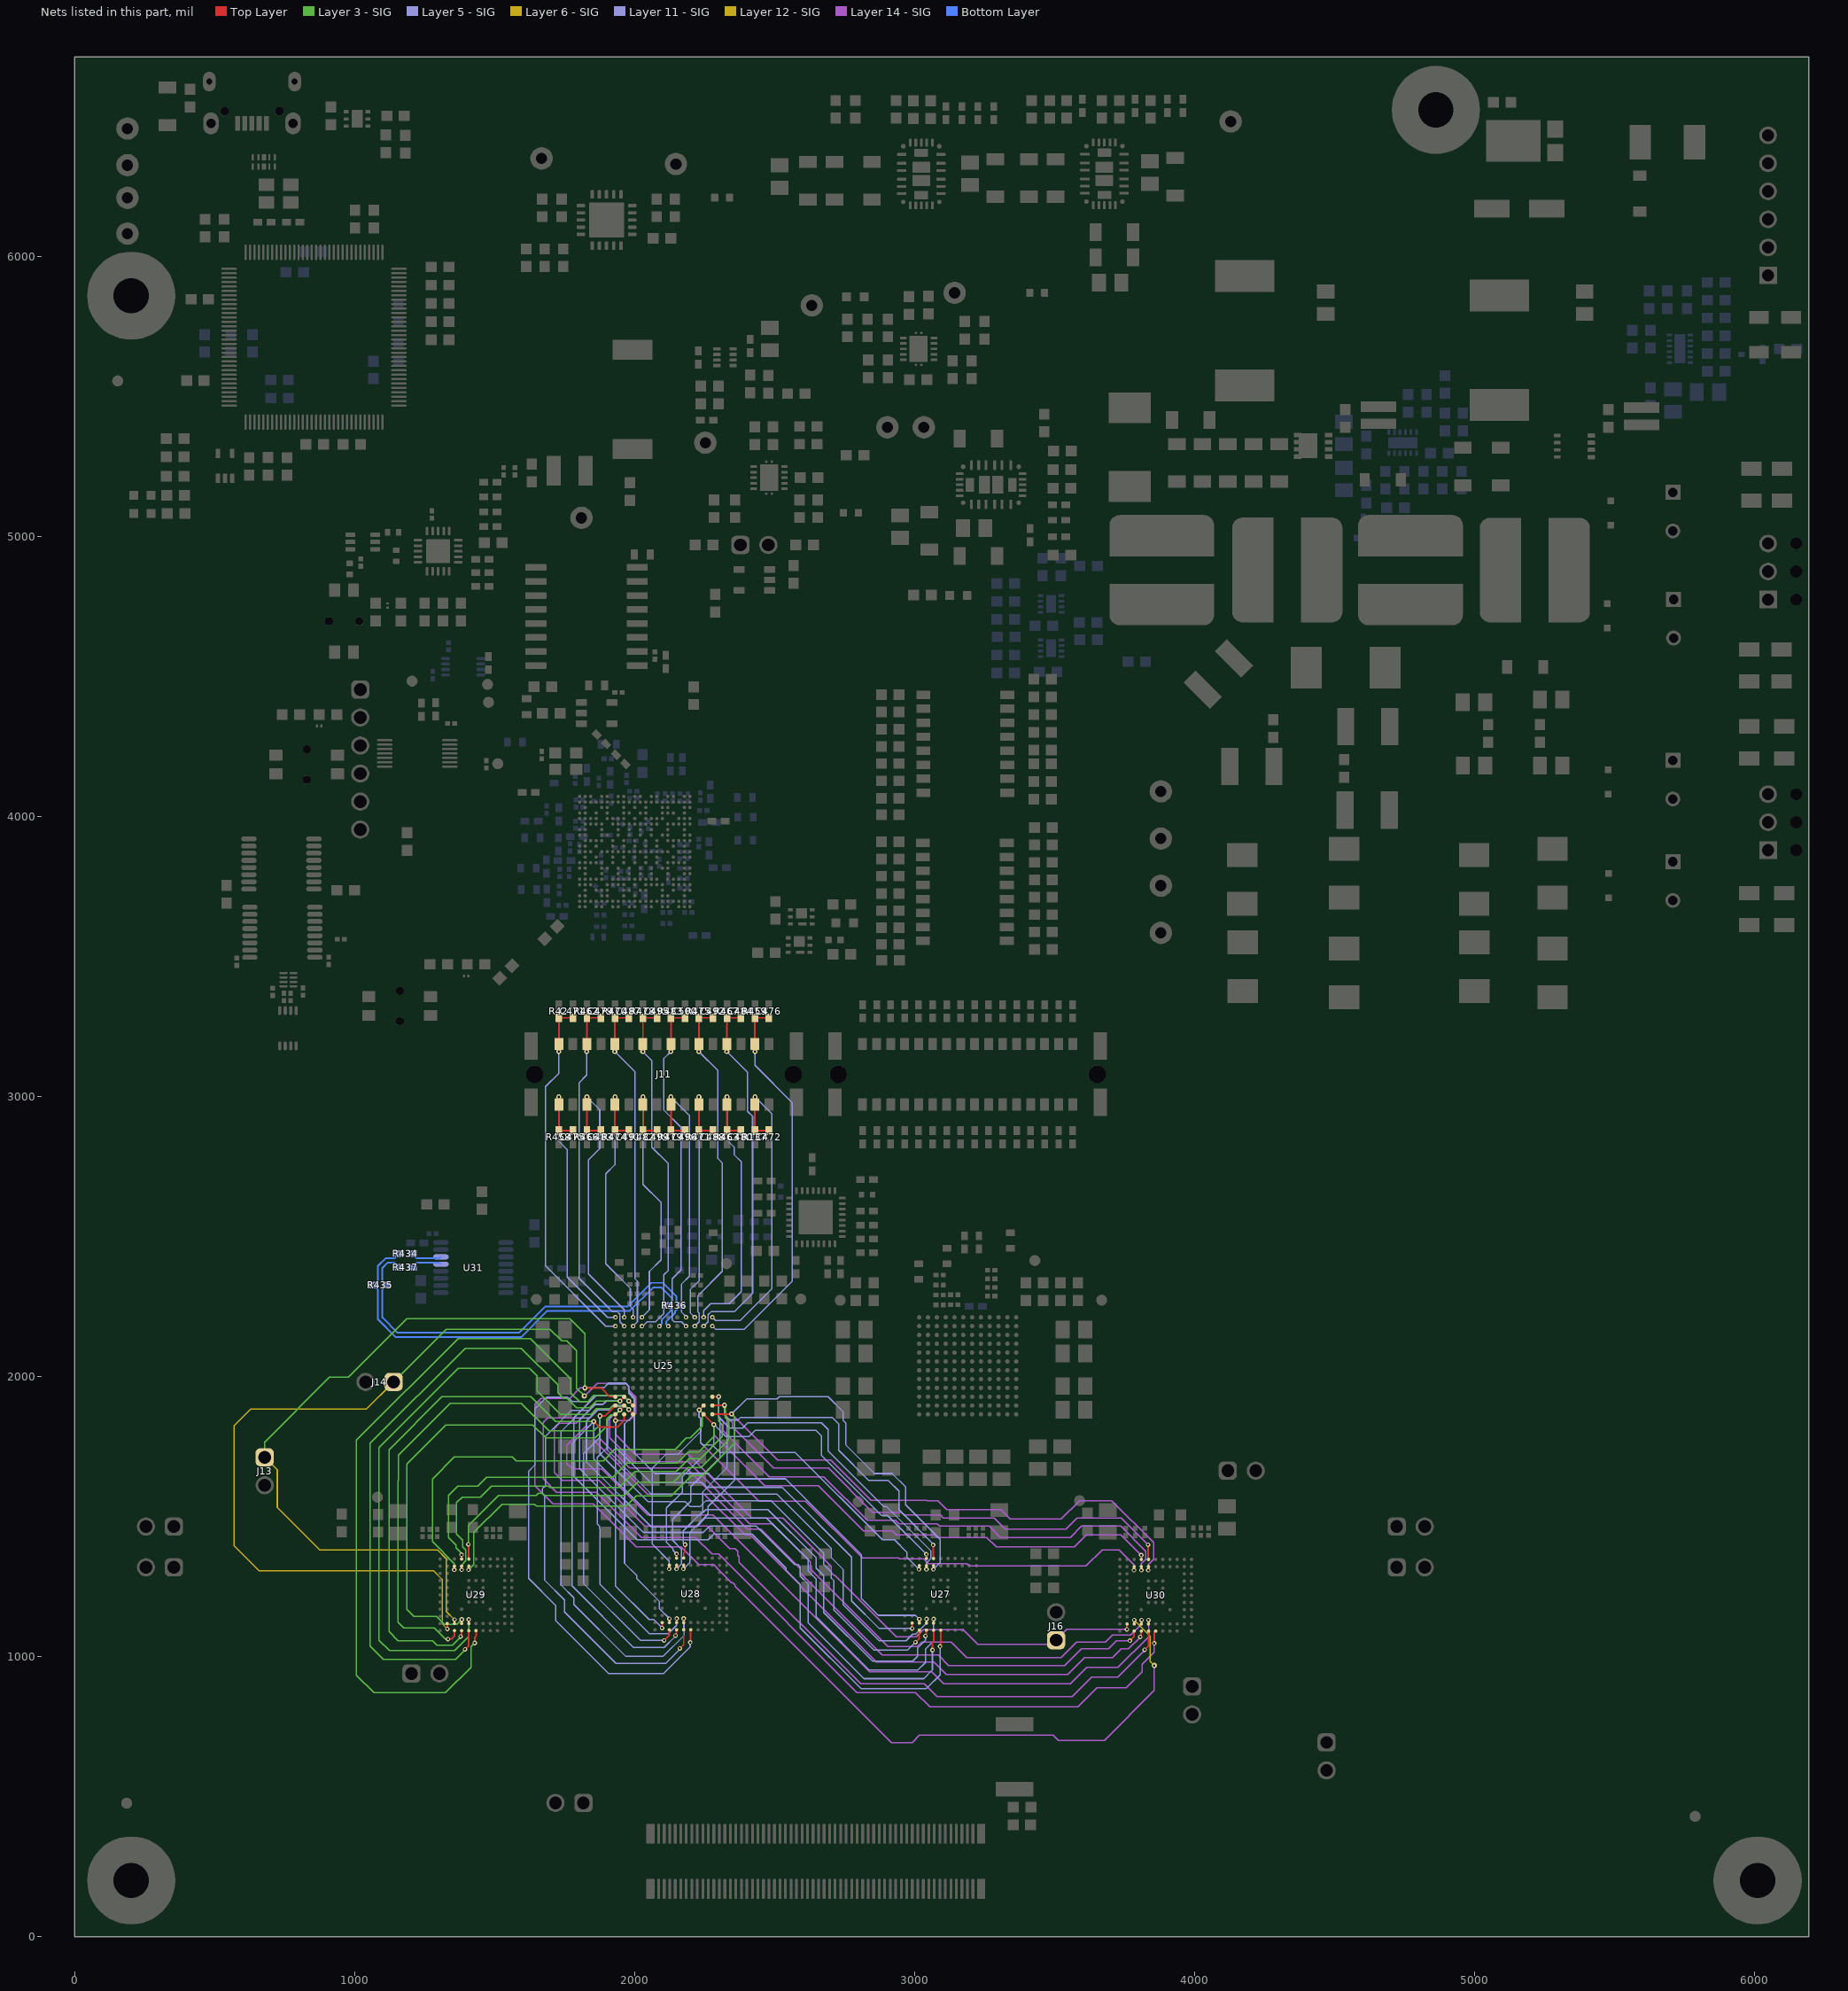
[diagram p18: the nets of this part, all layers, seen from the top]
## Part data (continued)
R62: library part CMP-0022095-4, "RES, 187 k, 1%, 0.1 W, AEC-Q200 Grade 0, 0603", Manufacturer=Vishay-Dale, Power_W=100mW, Supplier Part Number 1=541-187KHCT-ND, TempCo="100 ppm/C", Tolerance_%=1%, Value2=0.1W, Value_Code=187k
R66: library part CMP-0022031-4, "RES, 12.4 k, 1%, 0.1 W, AEC-Q200 Grade 0, 0603", Manufacturer=Vishay-Dale, Power_W=100mW, Supplier Part Number 1=541-12.4KHCT-ND, TempCo="100 ppm/C", Tolerance_%=1%, Value2=0.1W, Value_Code=12k4, ValueDisplayed=12.4k
R69: library part CMP-0022447-4, "RES, 49.9 k, 1%, 0.1 W, AEC-Q200 Grade 0, 0603", Manufacturer=Vishay-Dale, Power_W=100mW, Supplier Part Number 1=541-49.9KHCT-ND, TempCo="100 ppm/C", Tolerance_%=1%, Value2=0.1W, Value_Code=49k9, ValueDisplayed=49.9k
R70: library part CMP-0022248-4, "RES, 26.1 k, 1%, 0.1 W, AEC-Q200 Grade 0, 0603", Manufacturer=Vishay-Dale, Power_W=100mW, Supplier Part Number 1=541-26.1KHCT-ND, TempCo="100 ppm/C", Tolerance_%=1%, Value2=0.1W, Value_Code=26k1, ValueDisplayed=26.1k
R72: library part CMP-0022895-5, "RES, 10 k, 1%, 0.1 W, 0603", Manufacturer=Yageo, Power_W=100mW, Supplier Part Number 1=311-1.00KHRCT-ND, TempCo="100 ppm/C", Tolerance_%=1%, Value2=0.1W, Value_Code=1k00, ValueDisplayed=10k
R74: library part CMP-0082504-1, "RES, 50, 2%, 3.9 W, 0603", Manufacturer=Vishay-Dale, Power_W=3.9W, Supplier Part Number 1=541-2655-1-ND, TempCo="150 ppm/C", Tolerance_%=2%, Value_Code=50R0, ValueDisplayed=50
R75: library part CMP-0022138-4, "RES, 1.00 M, 1%, 0.1 W, AEC-Q200 Grade 0, 0603", Manufacturer=Vishay-Dale, Power_W=100mW, Supplier Part Number 1=541-1.00MHCT-ND, TempCo="100 ppm/C", Tolerance_%=1%, Value2=0.1W, Value_Code=1M00, ValueDisplayed=1.00M
R76 R149: library part CMP-0021991-4, "RES, 100, 1%, 0.1 W, AEC-Q200 Grade 0, 0603", Manufacturer=Vishay-Dale, Power_W=100mW, Supplier Part Number 1=541-100HCT-ND, TempCo="100 ppm/C", Tolerance_%=1%, Value2=0.1W, Value_Code=100R, ValueDisplayed=100
R77: library part CMP-0022816-5, "RES, 15.0 k, 1%, 0.1 W, 0603", Manufacturer=Yageo, Power_W=100mW, Supplier Part Number 1=311-15.0KHRCT-ND, TempCo="100 ppm/C", Tolerance_%=1%, Value2=0.1W, Value_Code=15k0, ValueDisplayed=15.0k
R78: library part CMP-0022816-5, "RES, 10k, 1%, 0.1 W, 0603", Manufacturer=Yageo, Power_W=100mW, Supplier Part Number 1=311-15.0KHRCT-ND, TempCo="100 ppm/C", Tolerance_%=1%, Value2=0.1W, Value_Code=15k0, ValueDisplayed=10k
R79 R80 R121 R122: library part CMP-0022902-5, "RES, 200, 1%, 0.1 W, 0603", Manufacturer=Yageo, Power_W=100mW, Supplier Part Number 1=311-200HRCT-ND, TempCo="100 ppm/C", Tolerance_%=1%, Value2=0.1W, Value_Code=200R, ValueDisplayed=200
R81 R105 R106 R107 R108 R109 R110 R111 R112 R113 R114 R115 R116 R117 R118 R119 R120 R444: library part CMP-0021990-4, "RES, 100 k, 1%, 0.1 W, AEC-Q200 Grade 0, 0603", Manufacturer=Vishay-Dale, Power_W=100mW, Supplier Part Number 1=541-100KHCT-ND, TempCo="100 ppm/C", Tolerance_%=1%, Value2=0.1W, Value_Code=100k
R86 R160 R163 R294 R297: library part CMP-0078663-1, "RES, 2.00 k, 1%, 0.1 W, AEC-Q200 Grade 0, 0603", Manufacturer=Panasonic, Power_W=100mW, Supplier Part Number 1=P2.00KHCT-ND, TempCo="100 ppm/C", Tolerance_%=1%, Value2=0.1W, Value_Code=2k00, ValueDisplayed=2.00k
R87 R123 R124 R438 R439: library part CMP-0023341-3, "RES, 10.0 k, 1%, 0.1 W, AEC-Q200 Grade 0, 0603", Manufacturer="Stackpole Electronics Inc", Power_W=100mW, Supplier Part Number 1=RMCF0603FT10K0CT-ND, TempCo="100 ppm/C", Tolerance_%=1%, Value2=0.1W, Value_Code=10k0, ValueDisplayed=10.0k
R88: library part CMP-0023560-3, "RES, 4.87 k, 0.1%, 0.1 W, 0603", Manufacturer="Susumu Co Ltd", Power_W=100mW, Supplier Part Number 1=RG16P4.87KBCT-ND, TempCo="25 ppm/C", Tolerance_%=0.1%, Value2=0.1W, Value_Code=4k87, ValueDisplayed=4.87k
R89 R90 R91 R92 R93 R94 R95 R96 R97 R98 R99 R100 R101 R102 R103 R104: library part CMP-0022109-5, "RES, 1.00 k, 1%, 0.1 W, AEC-Q200 Grade 0, 0603", Manufacturer=Vishay-Dale, Power_W=100mW, Supplier Part Number 1=541-1.00KHCT-ND, TempCo="100 ppm/C", Tolerance_%=1%, Value2=0.1W, Value_Code=1k00, ValueDisplayed=1.00k
R125 R136 R138: library part CMP-0078581-1, "RES, 1.00 k, 0.1%, 0.1 W, AEC-Q200 Grade 0, 0603", Manufacturer=Panasonic, Power_W=100mW, Supplier Part Number 1=P1.0KDBCT-ND, TempCo="25 ppm/C", Tolerance_%=0.1%, Value2=0.1W, Value_Code=1k00, ValueDisplayed=1.00k
R126: library part CMP-0026040-3, "RES, 16.9k, 1%, 0.063 W, AEC-Q200 Grade 0, 0402", Manufacturer=Vishay-Dale, Power_W=63mW, Supplier Part Number 1=541-16.2KLCT-ND, TempCo="100 ppm/C", Tolerance_%=1%, Value2=0.063W, Value_Code=16k2, ValueDisplayed=16.9k
R127 R128: library part CMP-0026040-3, "RES, 100k, 1%, 0.063 W, AEC-Q200 Grade 0, 0402", Manufacturer=Vishay-Dale, Power_W=63mW, Supplier Part Number 1=541-16.2KLCT-ND, TempCo="100 ppm/C", Tolerance_%=1%, Value2=0.063W, Value_Code=16k2, ValueDisplayed=100k
R129 R130 R131: library part CMP-0094798-1, "Res Thick Film 0402 10K Ohm 5% 0.063W(1/16W) ±100ppm/C Pad SMD T/R", Digikey Part Number=311-10KJRCT-ND, Manufacturer=YAGEO, Mouser Part Number=603-RC0402JR-0710KL, Operating Temperature Range="-55°C to +155°C", Power_W=63mW, TempCo=100ppm/°C, Tolerance_%=5%
R132: library part CMP-0026040-3, "RES, 5.23k, 1%, 0.063 W, AEC-Q200 Grade 0, 0402", Manufacturer=Vishay-Dale, Power_W=63mW, Supplier Part Number 1=541-16.2KLCT-ND, TempCo="100 ppm/C", Tolerance_%=1%, Value2=0.063W, Value_Code=16k2, ValueDisplayed=5.23k
R133: library part CMP-0026040-3, "RES, 14.7k, 1%, 0.063 W, AEC-Q200 Grade 0, 0402", Manufacturer=Vishay-Dale, Power_W=63mW, Supplier Part Number 1=541-16.2KLCT-ND, TempCo="100 ppm/C", Tolerance_%=1%, Value2=0.063W, Value_Code=16k2, ValueDisplayed=14.7k
R134: library part CMP-0026040-3, "RES, 12.7k, 1%, 0.063 W, AEC-Q200 Grade 0, 0402", Manufacturer=Vishay-Dale, Power_W=63mW, Supplier Part Number 1=541-16.2KLCT-ND, TempCo="100 ppm/C", Tolerance_%=1%, Value2=0.063W, Value_Code=16k2, ValueDisplayed=12.7k
R135: library part CMP-0026040-3, "RES, 88.7k, 1%, 0.063 W, AEC-Q200 Grade 0, 0402", Manufacturer=Vishay-Dale, Power_W=63mW, Supplier Part Number 1=541-16.2KLCT-ND, TempCo="100 ppm/C", Tolerance_%=1%, Value2=0.063W, Value_Code=16k2, ValueDisplayed=88.7k
R139: library part CMP-0026797-1, "RES, 10.0 k, 0.1%, 0.063 W, 0402", Manufacturer="TT Electronics/IRC", Power_W=63mW, Supplier Part Number 1=985-1366-1-ND, TempCo="10 ppm/C", Tolerance_%=0.1%, Value2=0.063W, Value_Code=10k0, ValueDisplayed=10.0k
R140 R143 R144: library part CMP-0027007-2, "RES, 0, 5%, 0.063 W, AEC-Q200 Grade 0, 0402", Manufacturer="KOA Speer", Power_W=63mW, Supplier Part Number 1=660-RK73Z1ETTP, TempCo=ppm/C, Tolerance_%=5%, Value2=0.063W, Value_Code=0000, ValueDisplayed=0
R141: library part CMP-0026721-1, "RES, 100 k, 1%, 0.0625 W, 0402", Manufacturer="Yageo America", Power_W=62.5mW, Supplier Part Number 1=311-100KLRCT-ND, TempCo="100 ppm/C", Tolerance_%=1%, Value2=0.0625W, Value_Code=100k
R142: library part CMP-0025975-3, "RES, 11.0 k, 1%, 0.063 W, AEC-Q200 Grade 0, 0402", Manufacturer=Vishay-Dale, Power_W=63mW, Supplier Part Number 1=541-11.0KLCT-ND, TempCo="100 ppm/C", Tolerance_%=1%, Value2=0.063W, Value_Code=11k0, ValueDisplayed=11.0k
R145: library part CMP-0027500-1, "RES, 22.0, 1%, 0.05 W, 0201", Manufacturer="Yageo America", Power_W=50mW, Supplier Part Number 1=YAG2518CT-ND, TempCo="200 ppm/C", Tolerance_%=1%, Value2=0.05W, Value_Code=22R0, ValueDisplayed=22.0
R147 R148 R150 R151: library part CMP-0002710-1, "0 Ohms Jumper Chip Resistor 0402 (1005 Metric) Automotive AEC-Q200 Thick Film", Digikey Part Number=P0.0JCT-ND, Manufacturer=Panasonic, Mouser Part Number=667-ERJ-2GE0R00X, Operating Temperature Range="-55°C to +155°C", Power=100mW
R152 R153 R161 R162 R164 R165 R295 R296 R298 R299: library part CMP-0022725-3, "RES, 0, 1%, 0.1 W, AEC-Q200 Grade 1, 0603", Manufacturer=Panasonic, Power_W=100mW, Supplier Part Number 1=P100LJCT-ND, TempCo="200 ppm/C", Tolerance_%=1%, Value2=0.1W, Value_Code=R100, ValueDisplayed=0
R167: library part CMP-0015538-3, "RES, 220, 1%, 1 W, AEC-Q200 Grade 0, 2512", Manufacturer=Vishay-Dale, Power_W=1W, Supplier Part Number 1=541-220AFCT-ND, TempCo="100 ppm/C", Tolerance_%=1%, Value_Code=220R, ValueDisplayed=220
R428 R429: library part CMP-0026761-1, "RES, 49.9, 1%, 0.063 W, AEC-Q200 Grade 0, 0402", Manufacturer="Stackpole Electronics Inc", Power_W=63mW, Supplier Part Number 1=RMCF0402FT49R9CT-ND, TempCo="100 ppm/C", Tolerance_%=1%, Value2=0.063W, Value_Code=49R9, ValueDisplayed=49.9
R430 R433 R434 R437: library part CMP-0026822-3, "RES, 0, 5%, 0.063 W, AEC-Q200 Grade 0, 0402", Manufacturer=Vishay-Dale, Power_W=63mW, Supplier Part Number 1=541-0.0JCT-ND, TempCo="200 ppm/C", Tolerance_%=5%, Value2=0.063W, Value_Code=0000, ValueDisplayed=0
R431 R435: library part CMP-0026039-3, "RES, 169, 1%, 0.063 W, AEC-Q200 Grade 0, 0402", Manufacturer=Vishay-Dale, Power_W=63mW, Supplier Part Number 1=541-169LCT-ND, TempCo="100 ppm/C", Tolerance_%=1%, Value2=0.063W, Value_Code=169R, ValueDisplayed=169
R432 R436: library part CMP-0025951-3, "RES, 100, 1%, 0.063 W, AEC-Q200 Grade 0, 0402", Manufacturer=Vishay-Dale, Power_W=63mW, Supplier Part Number 1=541-100LCT-ND, TempCo="100 ppm/C", Tolerance_%=1%, Value2=0.063W, Value_Code=100R, ValueDisplayed=100
R440: library part CMP-0025782-4, "RES, 30 k, 5%, 0.1 W, AEC-Q200 Grade 0, 0603", Manufacturer=Vishay-Dale, Power_W=100mW, Supplier Part Number 1=541-30KGCT-ND, TempCo="200 ppm/C", Tolerance_%=5%, Value2=0.1W, Value_Code=30k0, ValueDisplayed=30k
R441: library part CMP-0025701-4, "RES, 10 k, 5%, 0.1 W, AEC-Q200 Grade 0, 0603", Manufacturer=Vishay-Dale, Power_W=100mW, Supplier Part Number 1=541-10KGCT-ND, TempCo="200 ppm/C", Tolerance_%=5%, Value2=0.1W, Value_Code=10k0, ValueDisplayed=10k
R442: library part CMP-0023036-5, "RES, 33.2 k, 1%, 0.1 W, 0603", Manufacturer=Yageo, Power_W=100mW, Supplier Part Number 1=311-33.2KHRCT-ND, TempCo="100 ppm/C", Tolerance_%=1%, Value2=0.1W, Value_Code=33k2, ValueDisplayed=33.2k
R445 R446 R448: library part CMP-0080084-1, "RES, 10.0 k, 0.1%, 0.1 W, AEC-Q200 Grade 0, 1.6x0.8mm", Manufacturer=Panasonic, Power_W=100mW, Supplier Part Number 1=P10KBDCT-ND, TempCo="10 ppm/C", Tolerance_%=0.1%, Value2=0.1W, Value_Code=10k0, ValueDisplayed=10.0k
R449 R450: library part CMP-0027004-2, "RES, 0, 5%, 0.063 W, 0402", Manufacturer="Yageo America", Power_W=63mW, Supplier Part Number 1=311-0.0JRCT-ND, TempCo="200 ppm/C", Tolerance_%=5%, Value2=0.063W, Value_Code=0000, ValueDisplayed=0
R451: library part CMP-0022030-4, "RES, 12.1 k, 1%, 0.1 W, AEC-Q200 Grade 0, 0603", Manufacturer=Vishay-Dale, Power_W=100mW, Supplier Part Number 1=541-12.1KHCT-ND, TempCo="100 ppm/C", Tolerance_%=1%, Value2=0.1W, Value_Code=12k1, ValueDisplayed=12.1k
R457: library part CMP-0024586-3, "RES, 10.0 k, 0.5%, 0.1 W, 0603", Manufacturer="Yageo America", Power_W=100mW, Supplier Part Number 1=603-RT0603DRE0710KL, TempCo="50 ppm/C", Tolerance_%=0.5%, Value2=0.1W, Value_Code=10k0, ValueDisplayed=10.0k
R513 R514: library part CMP-0025817-4, "RES, 4.7 k, 5%, 0.1 W, AEC-Q200 Grade 0, 0603", Manufacturer=Vishay-Dale, Power_W=100mW, Supplier Part Number 1=541-4.7KGCT-ND, TempCo="200 ppm/C", Tolerance_%=5%, Value2=0.1W, Value_Code=4k70, ValueDisplayed=4.7k
S1 S2: library part CMP-0002229-1, "Switch, SPST, 8 Pos, 25mA, 24VDC, SMD", CurrentRating_mA=25A, Manufacturer="CTS Electrocomponents", Supplier Part Number 1=CT2188LPST-ND
SW1 SW2 SW3: library part CMP-0092977-1, "Tactile Switch SPST-NO Side Actuated Surface Mount, Right Angle", Coil Resistance_ohm=100mΩ, Contact Current Rating=50mA, Digikey Part Number=732-7059-1-ND, Manufacturer=Wurth, Mouser Part Number=710-436331045822, Operating Force=220gf, Operating Temperature Range="-40°C to +85°C"
TP1 TP2 TP4 TP5 TP6 TP9 TP10 TP12 TP17 TP18 TP19 TP20: library part CMP-0055137-2, "Test Point, Miniature, Red, TH", Color=Red, Manufacturer="Keystone Electronics", PartNumber=5000, Supplier Part Number 1=36-5000-ND
TP3 TP7 TP21 TP30 TP31 TP32 TP33 TP34 TP35 TP36 TP37 TP38 TP39 TP40: library part CMP-0003825-1, "1mm Test Point, SMT", Manufacturer=Any, PartNumber=TP_SM_1MM
TP8: "Test Point, Miniature, Red, TH", Color=Red, Manufacturer="Keystone Electronics", PartNumber=5000, Supplier Part Number 1=36-5000-ND
TP11 TP13 TP14 TP15: library part CMP-0055138-2, "Test Point, Miniature, Black, TH", Color=Black, Manufacturer="Keystone Electronics", PartNumber=5001, Supplier Part Number 1=36-5001-ND
U1 U2: library part CMP-0091224-1, "10-Bit and 8-Bit, Voltage-Output Digital-to-Analog Converters With Nonvolatile Memory and PMBus™ Compatible I 2C Interface in Tiny 2 × 2 WSON", Digikey Part Number=296-DAC53401DSGRCT-ND, Manufacturer="Texas Instruments", Max Supply Voltage=5.5V, Min Supply Voltage=1.71V, Mouser Part Number=595-DAC53401DSGR, Nominal Supply Current=0.5mA, Operating Temperature Range="-40°C to +125°C"
U3 U4: library part CMP-0085413-1, "2.2-MHz Wide Input Nonsynchronous Boost, Sepic, Flyback Controller, DSS0012B (WSON-12)", Alternate Manufacturer="Texas Instruments", Alternate PartNumber=LM5155DSST
U5 U7: library part CMP-0047735-1, "TPSM63603 Cruzline Power Module", Digikey Part Number=296-TPSM63603RDHRCT-ND, Manufacturer="Texas Instruments", Max Supply Voltage=36V, Min Supply Voltage=3V, Mouser Part Number=595-TPSM63603RDHR, Nominal Supply Current=4uA, Operating Temperature Range="-40°C to +125°C", Output Voltage=1-16V, Switching Frequency=200-2200kHz
U6: library part CMP-0036411-3, "Vin -3V to -36V, -1A, Ultra-Low-Noise, High-PSRR, Low-Dropout Linear Regulator, RGW0020A (VQFN-20)", Manufacturer="Texas Instruments", Operating Temperature Range="-40 to 125 C", Rating=Catalog
U8: library part CMP-0094457-2, "3.8-V to 30-V, 2-A Synchronous Buck Converter in SOT583 Package", Manufacturer="Texas Instruments", Max Supply Voltage=30V, Min Supply Voltage=3.8V, Nominal Supply Current=12uA, Operating Temperature Range="-40°C to +150°C", Output Voltage=0.8-22V, Switching Frequency=310-2100kHz
U9 U32: library part CMP-0091022-1, "1-A, Ultra-Low Noise, Ultra-High PSRR, RF Voltage Regulator", Dropout Voltage=210mV, Manufacturer="Texas Instruments", Max Supply Voltage=5.5V, Min Supply Voltage=1.7V, Nominal Supply Current=15-47mA, Operating Temperature Range="-40°C to +150°C", Output Voltage=0.4-5.3V
U10: library part CMP-0093432-1, "High-Density, 3-V to 36-V Input, 1-V to 16-V Output, 3-A Power Module B0QFN30", Manufacturer="Texas Instruments", Max Supply Voltage=36V, Min Supply Voltage=3V, Nominal Supply Current=9uA, Operating Temperature Range="-40°C to +105°C", Output Voltage=1-16V, Switching Frequency=200-2200kHz
U11: library part CMP-0080935-1, "500-mA, Low IQ, Small Size, Low Dropout Regulator, DBV0005A (SOT-23-5)", Alternate Manufacturer="Texas Instruments"
U12: library part CMP-0029865-2, "Tiva C Series Microcontroller, 1024 KB Flash, 256 KB SRAM, 12 Bit, 20 Channels, -40 to 105 degC, 128-Pin TQFP (PDT), Green (RoHS & no Sb/Br), Tape and Reel", Manufacturer="Texas Instruments", Temperature Range="-40 to 105 degC"
U13: library part CMP-0036330-5, "Single Output High PSRR LDO, 500 mA, Fixed 3.3 V Output, 2.7 to 6.5 V Input, with Low IQ, 6-pin SON (DRV), -40 to 125 degC, Green (RoHS & no Sb/Br)", Manufacturer="Texas Instruments"
U14: library part CMP-0073612-3, "4-Channel ESD Protection Diode for USB Type-C and HDMI 2.0, DQA0010A (USON-10)", Alternate Manufacturer="Texas Instruments"
U15 U20: library part CMP-0066448-2, "4-Bit Dual-Supply Bus Transceiver with Configurable Voltage-Level Shifting and 3-State Outputs, PW0016A (TSSOP-16)", Alternate Manufacturer="Texas Instruments"
U16: library part CMP-0032785-2, "Precision Micropower Shunt Voltage Reference, 0.2% accuracy, 2.5 V, 15 ppm / degC, 15 mA, -40 to 85 degC, 5-pin SC70 (DCK), Green (RoHS & no Sb/Br)", Manufacturer="Texas Instruments", Rating=Catalog, Temp Coeff(Max)(ppm/ degree C)=100, Temp Coeff(Typ)(ppm/ degree C)=15
U17: library part CMP-0035022-1, "Arm® Cortex®-R5F-based MCU with industrial communications and security up to 800 MHz 293-FCCSP -40 to 125", Digikey Part Number=296-AM2431BSDGHIALXRCT-ND, Frequency_Fixed=800MHz, Manufacturer="Texas Instruments", Max Supply Voltage=3.465V, Min Supply Voltage=810mV, Mouser Part Number=595-AM2431BSDGHIALXR, Operating Temperature Range="-40°C to +125°C"
U18: library part CMP-0079268-1, "Quad Supply Voltage Supervisors with Programmable Delay and Watchdog Timer, RGP0020A (VQFN-20)", Alternate Manufacturer="Texas Instruments", Alternate PartNumber=TPS386000RGPT
U19: library part CMP-0051216-3, "Single 3-Input Positive-AND Gate, DCK0006A (SOT-SC70-6)", F @ Nom Voltage(Max)(Mhz)=150, Generic Part Number=SN74LVC1G11, ICC @ Nom Voltage(Max)(mA)=0.01, Manufacturer="Texas Instruments", Operating Temperature Range="-40 to 125,-40 to 85 C", Rating=Catalog, tpd @ Nom Voltage(Max)(ns)=20,7.8,6.2,4.6, Voltage(Nom)(V)=1.8,2.5,3.3,5
U21: library part CMP-0050936-4, "Dual-Bit Dual-Supply Bus Transceiver, DQM0008A (X2SON-8)", F @ Nom Voltage(Max)(Mhz)=100, Generic Part Number=SN74AVC2T244, ICC @ Nom Voltage(Max)(mA)=0.0009, Manufacturer="Texas Instruments", Operating Temperature Range(C)="-40 to 85", Rating=Catalog, tpd @ Nom Voltage(Max)(ns)=20,7,3.5, Voltage(Nom)(V)=0.9,1.2,1.5,1.8,2.5,3.3
U22 U35: library part CMP-0051209-2, "2-Bit Bidirectional Voltage-Level Shifter for Open-Drain and Push-Pull Application, DCU0008A (VSSOP-8)", Manufacturer="Texas Instruments", Operating Temperature Range="-40 to 85 C", Rating=Catalog
U23: library part CMP-0065665-2, "3.1-GHz Differential Clock Buffer/Level Translator, RTV0032A (WQFN-32)", Alternate Manufacturer="Texas Instruments", Operating Temperature Range="-40 to 85 C"
U24: library part CMP-0084525-1, "High-Performance Low Jitter Standard Oscillator - 200M, SIA0006B (QFM-6)", Alternate Manufacturer="Texas Instruments", Alternate PartNumber=LMK62A2-200M00SIAT, Operating Temperature Range="-40 to 85 C", Rating=Catalog
U25 U26: library part CMP-0860806-2, "Five-Level, 16-Channel Transmitter with T/R Switch, and On-Chip Beamformer, ALH0144A (FCBGA-144)", Alternate Manufacturer="Texas Instruments"
U27 U28 U29 U30: library part CMP-0094338-1, "5V Supply, 220V High Voltage 1:1, 32-Channel Switch with Latch-Up Immunity", Manufacturer="Texas Instruments", Max Supply Voltage=5.5V, Min Supply Voltage=4.5V, Nominal Supply Current=2.8mA, On State Resistance=8Ω, Operating Temperature Range="-40°C to +150°C"
U31: library part CMP-0069809-1, "3V LVDS Quad CMOS Differential Line Driver, 16-pin TSSOP", Manufacturer="Texas Instruments", PackageTopMarking=NS2ZXYTT*DS90LV*031AT, PowerWise=N
U33: library part CMP-0097670-1, "FLASH - NOR Memory IC 512Mbit SPI - Quad I/O 166 MHz 16-SOIC", Digikey Part Number=448-S25HL512TFAMHI010-ND, Frequency_Fixed=166MHz, Manufacturer=Infineon, Max Supply Voltage=3.6V, Min Supply Voltage=2.7V, Mouser Part Number=727-S25HL512TFAMHI01, Nominal Supply Current=10-53mA, Operating Temperature Range="-40°C to +85°C", Part Number=S25HL512TFAMHI010
U34: library part CMP-0051588-2, "Single 2-Input Positive-AND Gate, DBV0005A, LARGE T&R", Alternate Manufacturer="Texas Instruments", F @ Nom Voltage(Max)(Mhz)=150, Generic Part Number=SN74LVC1G08, ICC @ Nom Voltage(Max)(mA)=0.01, Operating Temperature Range(C)="-40 to 125,-40 to 85", Rating=Catalog, tpd @ Nom Voltage(Max)(ns)=4.5,6,4,5, Voltage(Nom)(V)=1.8,2.5,3.3,5
U36: library part CMP-0066249-2, "Quadruple FET 2.5-V/3.3-V Low-Voltage High-Bandwidth Bus Switch, DGV0014A (TVSOP-14)", Alternate Manufacturer="Texas Instruments", Operating Temperature Range="-40 to 85 C", Rating=Catalog
Y1: library part CMP-0094478-1, "Crystal 16 MHz ±20ppm Crystal 8pF 70 Ohms 4-SMD, No Lead", Digikey Part Number=732-830064296CT-ND, Frequency Stability=20ppm, Frequency_Fixed=16MHz, Load Capacitance=8pF, Manufacturer=Wurth, Mouser Part Number=710-830064296, Operating Temperature Range="-10°C to +70°C"
Y2: library part CMP-0088518-1, "25MHz XO (Standard) LVCMOS Oscillator 1.8V Enable/Disable 4-SMD, No Lead"
Y2: library part CMP-0096252-1, "High-Performance BAW Oscillator, LVCMOS; <1ps, +/- 50ppm; 1.8V, -40C to 105C and DLE package", Frequency Stability=50ppm, Frequency_Fixed=25MHz, Load Capacitance=30pF, Manufacturer="Texas Instruments", Max Supply Voltage=1.89V, Min Supply Voltage=1.71V, Operating Temperature Range="-40°C to +105°C"
ZZ1: library part CMP-0003616-3
ZZ2: library part CMP-0077236-1
ZZ3: library part CMP-0077237-1
ZZ4: library part CMP-0077238-1

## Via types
v1: diameter 18, hole 8, Top Layer to Bottom Layer, tented both sides, 930 vias
v2: diameter 16, hole 8, Top Layer to Bottom Layer, tented both sides, 340 vias
v3: diameter 16, hole 8, Top Layer to Bottom Layer, tented bottom, 226 vias
v4: diameter 20, hole 10, Top Layer to Bottom Layer, tented both sides, 129 vias
v5: diameter 50, hole 30, Top Layer to Bottom Layer, tented both sides, 96 vias
v6: diameter 30, hole 15, Top Layer to Bottom Layer, tented both sides, 47 vias
v7: diameter 19.68, hole 7.87, Top Layer to Bottom Layer, 40 vias
v8: diameter 19.68, hole 7.87, Top Layer to Bottom Layer, tented both sides, 19 vias
v9: diameter 18, hole 8, Top Layer to Bottom Layer, tented bottom, 13 vias
v10: diameter 40, hole 20, Top Layer to Bottom Layer, tented both sides, 4 vias
v11: diameter 40, hole 20, Top Layer to Bottom Layer, 3 vias
v12: diameter 18, hole 8, Top Layer to Bottom Layer, 1 vias

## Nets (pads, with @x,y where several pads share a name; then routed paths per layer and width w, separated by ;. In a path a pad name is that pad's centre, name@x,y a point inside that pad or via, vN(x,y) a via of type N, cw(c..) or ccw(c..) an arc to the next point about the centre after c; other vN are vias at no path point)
A_RX_IN1: C471.1 J11.A1 R42.2 U25.L12 | length 1294.2
  Top Layer w6: v1@1729.5,3160.61 R42.2@1729.5,3280.78 C471.1@1779.5,3280.78
  Layer 5 - SIG w5: v1(1729.5,3160.73) 1729.5,3083.44 1681.47,3035.42 1681.47,2395.53 1881.18,2195.82 1896.79,2180.21 v3(1931.27,2180.21)
A_RX_IN2: C475.1 J11.B1 R458.2 U25.M12 | length 1057.1
  Top Layer w6: v1(1729.5,2998.41) R458.2@1729.5,2878.24 C475.1@1779.5,2878.24
  Layer 5 - SIG w5: v1(1729.5,2998.41) 1729.5,2839.91 1758.86,2810.54 1758.86,2355.73 1881.18,2233.42 1902.89,2211.71 v3(1931.27,2211.71)
A_RX_IN3: C479.1 J11.A3 R462.2 U25.L11 | length 1239.1
  Top Layer w6: v1@1829.5,3160.61 R462.2@1829.5,3280.78 C479.1@1879.5,3280.78
  Layer 5 - SIG w5: v1(1829.05,3160.73) 1829.05,3076.36 1801.79,3049.1 1801.79,2350.3 1901.45,2250.64 1919.55,2232.54 1937.34,2232.54 1947.14,2222.74 1947.14,2195.83 v3(1962.76,2180.21)
A_RX_IN4: C483.1 J11.B3 R466.2 U25.M11 | length 1045.6
  Top Layer w6: v1(1829.5,2998.41) R466.2@1829.5,2878.24 C483.1@1879.5,2878.24
  Layer 5 - SIG w5: v1(1829.5,2998.41) 1875.29,2952.62 1875.29,2814.24 1834.86,2773.81 1834.86,2366.58 1950.8,2250.64 1962.76,2238.68 v3(1962.76,2211.71)
A_RX_IN5: C487.1 J11.A5 R470.2 U25.L10 | length 1190.6
  Top Layer w6: v1@1929.5,3160.61 R470.2@1929.5,3280.78 C487.1@1979.5,3280.78
  Layer 5 - SIG w5: v1(1929.05,3160.73) 2000.49,3089.29 2000.49,2349.68 2009.88,2340.29 2009.88,2250.64 2009.88,2195.83 v3(1994.26,2180.21)
A_RX_IN6: C491.1 J11.B5 R474.2 U25.M10 | length 1010.8
  Top Layer w6: v1(1929.5,2998.41) R474.2@1929.5,2878.24 C491.1@1979.5,2878.24
  Layer 5 - SIG w5: v1(1929.5,2998.41) 1929.5,2756.5 1896.79,2723.79 1896.79,2402.54 1984.55,2314.78 1984.55,2250.64 1984.55,2250.52 1994.26,2240.81 v3(1994.26,2211.71)
A_RX_IN7: C495.1 J11.A7 R478.2 U25.L9 | length 1246.6
  Top Layer w6: v1@2029.5,3160.61 R478.2@2029.5,3280.78 C495.1@2079.5,3280.78
  Layer 5 - SIG w5: v3(2025.76,2180.21) 2028.66,2180.21 2044.29,2195.83 2074.67,2195.83 2104.02,2225.19 2104.02,2363.01 2119.68,2378.66 2119.68,2761.06 2061.6,2819.14 2061.6,3128.18 v1(2029.05,3160.73)
A_RX_IN8: C499.1 J11.B7 R482.2 U25.M9 | length 1012
  Top Layer w6: v1(2029.5,2998.41) R482.2@2029.5,2878.24 C499.1@2079.5,2878.24
  Layer 5 - SIG w5: v3(2025.76,2211.71) 2052.52,2238.47 2052.52,2250.64 2052.52,2375.46 2094.22,2417.16 2094.22,2621.7 2029.5,2686.43 2029.5,2854.22 v1(2029.5,2998.41)
A_RX_IN9: C500.1 J11.A9 R483.2 U25.L4 | length 1235.1
  Top Layer w6: v1@2129.5,3160.61 R483.2@2129.5,3280.78 C500.1@2179.5,3280.78
  Layer 5 - SIG w5: v1(2129.05,3160.73) 2104.5,3136.17 2104.5,2951.24 2165.9,2889.84 2165.9,2381 2134.23,2349.33 2134.23,2202.88 2141.05,2196.06 2167.38,2196.06 v3(2183.24,2180.21)
A_RX_IN10: C496.1 J11.B9 R479.2 U25.M4 | length 1002.2
  Top Layer w6: v1(2129.5,2998.41) R479.2@2129.5,2878.24 C496.1@2179.5,2878.24
  Layer 5 - SIG w5: v1(2129.5,2998.41) 2195.71,2932.2 2195.71,2358.42 2167.86,2330.57 2167.86,2250.64 2167.86,2229.99 2183.24,2214.61 v3(2183.24,2211.71)
A_RX_IN11: C492.1 J11.A11 R475.2 U25.L3 | length 1229.6
  Top Layer w6: v1@2229.5,3160.61 R475.2@2229.5,3280.78 C492.1@2279.5,3280.78
  Layer 5 - SIG w5: v3(2214.73,2180.21) 2230.36,2195.83 2230.36,2225.94 2226.23,2230.07 2226.23,2289.39 2313,2376.17 2313,2763.04 2297.5,2778.54 2297.5,3092.28 v1(2229.05,3160.73)
A_RX_IN12: C488.1 J11.B11 R471.2 U25.M3 | length 977.7
  Top Layer w6: v1(2229.5,2998.41) R471.2@2229.5,2878.24 C488.1@2279.5,2878.24
  Layer 5 - SIG w5: v3(2214.73,2211.71) 2198.41,2228.03 2198.41,2250.64 2198.41,2310.42 2230.93,2342.94 2230.93,2996.97 v1(2229.5,2998.41)
A_RX_IN13: C484.1 J11.A13 R467.2 U25.L2 | length 1309.9
  Top Layer w6: v1@2329.5,3160.61 R467.2@2329.5,3280.78 C484.1@2379.5,3280.78
  Layer 5 - SIG w5: v3(2246.23,2180.21) 2261.99,2195.97 2261.99,2220.61 2273.92,2232.54 2356.91,2232.54 2421.15,2296.78 2421.15,2929.38 2403.15,2947.38 2403.15,3086.63 v1(2329.05,3160.73)
A_RX_IN14: C480.1 J11.B13 R463.2 U25.M2 | length 1072.6
  Top Layer w6: v1(2329.5,2998.41) R463.2@2329.5,2878.24 C480.1@2379.5,2878.24
  Layer 5 - SIG w5: v3(2246.23,2211.71) 2246.23,2235.02 2271.96,2260.76 2338.44,2260.76 2380.51,2302.83 2380.51,2767.36 2355,2792.86 2355,2819.68 2329.5,2845.19 v1(2329.5,2998.41)
A_RX_IN15: C476.1 J11.A15 R459.2 U25.L1 | length 1406.3
  Top Layer w6: v1@2429.5,3160.61 v1(2429.5,3160.73) J11.A15@2429.5,3187.78 R459.2@2429.5,3280.78 C476.1@2479.5,3280.78
  Layer 5 - SIG w5: v3(2277.72,2180.21) 2288.57,2169.36 2391.84,2169.36 2562.95,2340.47 2562.95,2977.65 2429.5,3111.1 v1(2429.5,3160.73)
A_RX_IN16: C472.1 J11.B15 R137.2 U25.M1 | length 1143.2
  Top Layer w6: v1(2429.5,2998.41) J11.B15@2429.5,2971.24 R137.2@2429.5,2878.24 C472.1@2479.5,2878.24
  Layer 5 - SIG w5: v3(2277.72,2211.71) 2288.93,2200.5 2376.53,2200.5 2489.53,2313.51 2489.53,2938.37 v1(2429.5,2998.41)
A_SYNC_IC_N: R437.1 U31.13 | length 110.6
  Bottom Layer w6.1: R437.1@1205.97,2390.55 1222.06,2406.64 1303.15,2406.64 U31.13@1307.95,2401.84
A_SYNC_IC_P: R434.1 U31.14 | length 110.6
  Bottom Layer w6.1: R434.1@1205.97,2438.55 1221.88,2422.64 1303.15,2422.64 U31.14@1307.95,2427.43
A_SYNC_N: R435.1 R436.1 R437.2 U25.L6 | length 1568.1
  Bottom Layer w6.1: R437.2@1158.73,2390.55 1142.73,2406.55 1117.6,2406.55 1098.93,2387.88 1098.93,2342.26 R435.1@1114.55,2326.63 1098.93,2311.01 1098.93,2211.25 1153.59,2156.59 1587.47,2156.59 1681.42,2250.54 1975.9,2250.54 2060.26,2334.9 2100.56,2334.9 2149.29,2286.16 2149.29,2269.82 R436.1@2164.92,2254.2 2144.51,2233.79 2144.51,2228.1 2112.5,2196.08 2112.5,2187.96 v3(2120.24,2180.21)
A_SYNC_P: R434.2 R435.2 R436.2 U25.L7 | length 1590.7
  Bottom Layer w6.1: R434.2@1158.73,2438.55 1142.73,2422.55 1110.97,2422.55 1082.93,2394.51 1082.93,2342.26 R435.2@1067.31,2326.63 1082.93,2311.01 1082.93,2204.62 1146.96,2140.59 1594.1,2140.59 1688.05,2234.54 1982.53,2234.54 2066.89,2318.9 2093.93,2318.9 2133.29,2279.54 2133.29,2269.82 R436.2@2117.67,2254.2 2128.51,2243.36 2128.51,2234.73 2096.5,2202.71 2096.5,2187.96 v3(2088.75,2180.21)
A_TX_OUT1: J14.1 J16.1 U25.A12 U27.K2 U28.K2 U29.K2 U30.K2 | length 8026.9
  Top Layer w6: v2(1330.92,1099) U29.K2@1330.94,1118.49 ; v1@1931.27,1843.31 U25.A12@1931.27,1865.25 ; v2(2098.31,1102.33) U28.K2@2098.33,1121.82 ; v2(2990.7,1100.67) U27.K2@2990.71,1120.14 ; v2(3758.09,1097.33) U30.K2@3758.11,1116.82
  Layer 3 - SIG w4.5: J14.1@1139.11,1980.95 1327.29,2169.13 1697.47,2169.13 1739.38,2127.22 1758.04,2127.22 1792.31,2092.95 1792.31,1958.81 v1(1820.3,1930.82)
  Layer 5 - SIG w5: v1(1931.38,1843.2) 1931.38,1252.32 2051.34,1132.36 2068.28,1132.36 v2(2098.31,1102.33)
  Layer 6 - SIG w5: J14.1@1139.11,1980.95 1042.16,1884 629,1884 570,1825 570,1395.85 658.63,1307.22 1281.09,1307.22 1312.48,1275.82 1312.48,1117.44 v2(1330.92,1099)
  Layer 11 - SIG w5: v1(1931.38,1843.2) 1931.38,1747.64 2057.48,1621.53 2241.01,1621.53 2257.55,1605 2526,1605 2775,1356 2775,1199.04 2873.37,1100.67 v2(2990.7,1100.67)
  Layer 14 - SIG w4.5: v1(1820.3,1930.82) 1822.19,1930.82 1866.48,1975.11 1969.13,1975.11 1978.14,1966.11 1978.14,1953.97 2004.96,1927.15 2004.96,1867.82 1980.34,1843.2 v1(1931.38,1843.2) 1931.38,1793.16 2001.52,1723.01 2191.47,1723.01 2419.36,1495.12 2529.97,1495.12 2702.45,1322.64 2702.45,1300.23 2712.12,1290.57 2714.62,1290.57 2934.35,1070.83 3005.58,1070.83 3030.52,1095.78 3173.85,1095.78 3225.91,1043.73 3489.73,1043.73 J16.1@3505,1059 3543.33,1097.33 v2(3758.09,1097.33)
A_TX_OUT2: U25.B12 U27.L3 U28.L3 U29.L3 U30.L3 | length 6955.8
  Top Layer w6: v2(1333.18,1062.58) 1334.94,1064.34 1347.29,1064.34 1356.53,1073.57 U29.L3@1356.53,1092.9 ; v1(1876.4,1859.54) 1894.26,1859.54 U25.B12@1931.27,1896.55 ; v2(2105,1058) 2123.92,1076.92 U28.L3@2123.92,1095.97 ; v2(3002.84,1051.85) 3016.31,1065.32 U27.L3@3016.31,1094.3 ; v2(3768.08,1057.31) 3783.4,1072.63 3783.4,1090.67 U30.L3@3783.7,1090.97
  Layer 3 - SIG w4.5: v2(1333.18,1062.58) 1324.8,1062.58 1284.8,1102.58 1175.28,1102.58 1155.35,1122.51 1155.35,1627.79 1156.8,1629.24 1156.8,1720.23 1341.13,1904.57 1595.38,1904.57 1693.93,1806.02 1854.74,1806.02 1876.4,1827.69 v1(1876.4,1859.54)
  Layer 5 - SIG w5: v1(1876.4,1859.54) 1876.4,1783.72 1817,1724.31 1817,1261.69 2020.69,1058 v2(2105,1058)
  Layer 11 - SIG w5: v1(1876.4,1859.54) 1876.4,1724.54 2047.71,1553.23 2181,1553.23 2197.5,1536.73 2234.32,1536.73 2253.58,1556 2488.58,1556 2675,1369.58 2675,1329.43 2702.45,1301.98 2702.45,1280.32 2711.91,1270.86 2711.91,1165.88 2854.24,1023.54 2974.53,1023.54 v2(3002.84,1051.85)
  Layer 14 - SIG w4.5: v1(1876.4,1859.54) 1876.4,1778.58 1981.69,1673.29 2184.62,1673.29 2402.8,1455.12 2450.79,1455.12 2591.32,1314.58 2591.32,1299.01 2884.24,1006.08 3084.18,1006.08 3121.43,968.84 3535.35,968.84 3595.03,1028.52 3691.4,1028.52 3720.19,1057.31 v2(3768.08,1057.31)
A_TX_OUT3: J13.1 U25.C12 U27.K3 U28.K3 U29.K3 U30.K3 | length 9195
  Top Layer w6: U29.K3@1356.53,1118.49 1356.68,1118.62 1356.68,1132.05 v2(1356.82,1132.2) ; v1(1822.56,1959.48) 1880.3,1959.48 1911.54,1928.24 U25.C12@1931.27,1928.24 ; U28.K3@2123.92,1121.82 2124.07,1121.95 2124.07,1135.39 v2(2124.21,1135.53) ; U27.K3@3016.31,1120.15 3016.46,1120.28 3016.46,1133.72 v2(3016.6,1133.87) ; U30.K3@3783.7,1116.82 3783.85,1116.95 3783.85,1130.39 v2(3783.99,1130.53)
  Layer 3 - SIG w4.5: J13.1@679,1712 679,1766 910.19,1997.19 976.97,1997.19 1186.07,2206.29 1768.59,2206.29 1822.56,2152.32 v1(1822.56,1959.48)
  Layer 5 - SIG w5: v1(1822.56,1959.48) 1889.25,1959.48 1904.88,1975.11 1969.13,1975.11 1978.89,1965.36 1978.89,1940.25 1998.75,1920.38 1998.75,1866.11 1963.95,1831.31 1963.95,1333.21 2007.18,1289.99 2007.18,1278.75 2088.75,1197.18 2088.75,1171 v2(2124.21,1135.53)
  Layer 6 - SIG w5: J13.1@679,1712 723.98,1667.02 723.98,1533.02 875.26,1381.74 1295.36,1381.74 1327.48,1349.62 1327.48,1161.54 v2(1356.82,1132.2)
  Layer 11 - SIG w5: v1(1822.56,1959.48) 1889.25,1959.48 1904.88,1975.11 1969.13,1975.11 1978.89,1965.36 1978.89,1944.52 1998.59,1924.81 1998.59,1891.8 1998.75,1891.65 1998.75,1727.8 2072.55,1654 2264.37,1654 2283.37,1635 2539,1635 2809.29,1364.71 2809.29,1207.9 2869.46,1147.73 3002.75,1147.73 v2(3016.6,1133.87)
  Layer 12 - SIG w5: v2(3783.99,1130.53) 3840.13,1074.4 3840.13,984.34 v1(3855.63,968.84)
  Layer 14 - SIG w4.5: v1(1822.56,1959.48) 1805.55,1959.48 1768.17,1922.1 1665.21,1922.1 1644,1900.89 1644,1609.78 1708.44,1545.34 1851.99,1545.34 2005.6,1391.73 2166.35,1391.73 2229.14,1328.93 2283.21,1328.93 2292.29,1319.86 2292.29,1317.95 2345.42,1264.82 2350.05,1264.82 2359.13,1255.74 2359.13,1251.11 2916.48,693.76 2990.7,693.76 3017.24,720.3 3493.97,720.3 3513.02,701.25 3677.39,701.25 3855.63,879.49 v1(3855.63,968.84)
A_TX_OUT4: U25.A11 U27.L4 U28.L4 U29.L4 U30.L4 | length 7333.9
  Top Layer w6: v2(1378.42,1072.1) 1378.42,1073.72 1381.39,1076.69 U29.L4@1381.39,1091.91 ; v1(1854.1,1839.74) 1873.5,1820.34 1938.86,1820.34 1962.76,1844.25 U25.A11@1962.76,1865.25 ; v2(2145.81,1075.43) 2145.81,1077.05 2148.78,1080.02 U28.L4@2148.78,1095.24 ; v2(3038.2,1073.76) 3038.2,1075.39 3041.17,1078.35 U27.L4@3041.17,1093.57 ; v2(3805.59,1070.43) 3805.59,1072.05 3808.56,1075.02 U30.L4@3808.56,1090.24
  Layer 3 - SIG w4.5: v2(1378.42,1072.1) 1378.42,1070.06 1349.78,1041.42 1293.44,1041.42 1277.58,1057.28 1155.11,1057.28 1122.87,1089.53 1122.87,1739.3 1311.81,1928.24 1629.19,1928.24 1717.68,1839.74 v1(1854.1,1839.74)
  Layer 5 - SIG w5: v1(1854.1,1839.74) 1776.17,1761.82 1776.17,1253 1995.65,1033.52 2105.93,1033.52 2145.81,1073.4 v2(2145.81,1075.43)
  Layer 11 - SIG w5: v1(1854.1,1839.74) 1854.1,1706.47 2056.23,1504.33 2233.17,1504.33 2253.84,1525 2475.96,1525 2647.77,1353.19 2647.77,1316.48 2675,1289.25 2675,1158.36 2849.61,983.75 2992.61,983.75 3010.33,1001.47 3010.33,1030.39 3038.2,1058.26 v2(3038.2,1073.76)
  Layer 14 - SIG w4.5: v1(1854.1,1839.74) 1854.1,1772.6 2045.66,1581.03 2248.59,1581.03 2394.51,1435.12 2412.24,1435.12 2591.32,1256.04 2591.32,1252.55 2862.56,981.32 3068.9,981.32 3113.86,936.36 3546.65,936.36 3606.86,996.56 3705.78,996.56 3737.74,1028.52 3763.68,1028.52 v2@3805.19,1070.03 ; v2@3805.19,1070.83 v2@3805.19,1070.03 ; v2(3805.59,1070.43) v2@3805.19,1070.03
A_TX_OUT5: U25.B11 U27.K4 U28.K4 U29.K4 U30.K4 | length 6917.7
  Top Layer w6: U29.K4@1382.12,1118.49 1382.42,1118.77 v2@1382.42,1132.7 ; v1(1947.25,1880.43) 1947.25,1880.83 1962.76,1896.35 U25.B11@1962.76,1896.75 ; U28.K4@2149.51,1121.82 2149.81,1122.1 v2@2149.81,1136.03 ; U27.K4@3041.9,1120.15 3042.2,1120.44 v2@3042.2,1134.37 ; U30.K4@3809.29,1116.82 3809.59,1117.1 v2@3809.59,1131.03
  Layer 3 - SIG w4.5: v2(1382.72,1132.7) 1365.08,1115.06 1320.74,1115.06 1292.18,1143.62 1211.98,1143.62 1186.07,1169.54 1186.07,1687.5 1326.25,1827.69 1636.45,1827.69 1682.8,1781.33 1858.33,1781.33 1899.3,1822.3 1899.3,1848.16 1915.28,1864.13 1930.95,1864.13 v1(1947.25,1880.43)
  Layer 5 - SIG w5: v1@1944.73,1877.08 1930.85,1863.2 1923.09,1863.2 1902.31,1842.42 1902.31,1747.4 1866.35,1711.44 1866.35,1473.87 1874.55,1465.67 1874.55,1457.48 1876.4,1455.62 1876.4,1258.15 2053.01,1081.54 2119.53,1081.54 2150.11,1112.13 v2(2150.11,1136.03) ; v1@1945.57,1878.76 v1(1947.25,1880.43)
  Layer 11 - SIG w5: v1@1947.25,1877.08 1944.73,1877.08 1930.85,1863.2 1923.09,1863.2 1902.31,1842.42 1902.31,1737.52 2058.8,1581.03 2506.97,1581.03 2702.45,1385.55 2702.45,1353.26 2745,1310.71 2745,1185.06 2873.17,1056.89 2968.82,1056.89 2992.61,1080.67 3003.3,1080.67 3042.5,1119.87 v2(3042.5,1134.37)
  Layer 14 - SIG w4.5: v1@1944.73,1877.08 1930.85,1863.2 1923.09,1863.2 1911.38,1851.49 1911.38,1780.76 1996.3,1695.84 2190.36,1695.84 2411.08,1475.12 2491.04,1475.12 2627.56,1338.6 2627.56,1313.03 2904.24,1036.35 3009.26,1036.35 3025.41,1052.5 3130.07,1052.5 3186.29,996.28 3522.56,996.28 3578.13,1051.85 3680.55,1051.85 3705.78,1077.08 3770.44,1077.08 3809.89,1116.53 v2(3809.89,1131.03) ; v1@1945.57,1878.76 v1(1947.25,1880.43)
A_TX_OUT6: U25.C11 U27.L5 U28.L5 U29.L5 U30.L5 | length 9132.6
  Top Layer w6: v2(1394.03,1026.33) 1407.71,1040.01 U29.L5@1407.71,1092.64 ; v1@1947.25,1912.73 U25.C11@1962.76,1928.24 ; v2(2161.42,1029.67) 2175.1,1043.34 U28.L5@2175.1,1095.97 ; v2(3063.37,1023.54) 3063.37,1050.66 3067.49,1054.78 U27.L5@3067.49,1094.56 ; v2(3821.2,1024.67) 3834.88,1038.34 U30.L5@3834.88,1090.97
  Layer 3 - SIG w4.5: v2@1395.51,1024.85 1360.84,990.18 1102.82,990.18 1055.61,1037.39 1055.61,1762.22 1394.85,2101.46 1594.36,2101.46 1725.12,1970.69 1725.12,1943.18 1745.8,1922.5 1759.44,1922.5 1792.89,1889.05 1839.33,1889.05 1862.91,1912.64 1916.85,1912.64 1916.91,1912.57 v1(1947.25,1912.57)
  Layer 5 - SIG w5: v1(1947.25,1912.57) 1916.91,1912.57 1916.85,1912.64 1898.38,1912.64 1886.63,1900.89 1858.67,1900.89 1837.62,1879.83 1774.4,1879.83 1681.47,1786.91 1681.47,1610.59 1670.05,1599.17 1670.05,1583.07 1679.05,1574.07 1679.05,1272.95 1749.48,1202.52 1749.48,1159.96 1933.47,975.98 2110.7,975.98 v2@2162.9,1028.19
  Layer 11 - SIG w5: v1(1947.25,1912.57) 1916.91,1912.57 1916.85,1912.64 1898.38,1912.64 1886.63,1900.89 1858.67,1900.89 1803.09,1845.3 1803.09,1671.29 2030.9,1443.48 2244.89,1443.48 2268.41,1467 2432.84,1467 2570.4,1329.43 2583.31,1329.43 2591.41,1321.32 2591.41,1287.59 2620.23,1258.77 2620.23,1119.94 2818.49,921.69 3032.13,921.69 3063.37,952.93 v2(3063.37,1023.54)
  Layer 14 - SIG w4.5: v1(1947.25,1912.57) 1916.91,1912.57 1916.85,1912.64 1898.38,1912.64 1886.63,1900.89 1858.67,1900.89 1790.78,1833 1731,1833 1712.67,1814.67 1712.67,1657.93 1741.41,1629.18 1872.65,1629.18 2035.88,1465.96 2258.69,1465.96 2339.21,1385.43 2359.03,1385.43 2368.11,1376.36 2368.11,1362.64 2373.22,1357.53 2373.22,1336.92 2807.15,902.99 3034.05,902.99 3080.3,856.75 3562.1,856.75 3631.8,926.44 3725.13,926.44 v2@3822.28,1023.59
A_TX_OUT7: U25.A10 U27.K5 U28.K5 U29.K5 U30.K5 | length 8840.8
  Top Layer w6: U29.K5@1407.71,1118.49 v2(1407.73,1132.7) ; v1(1978.75,1882.44) 1978.75,1881.6 1994.26,1866.09 U25.A10@1994.26,1865.25 ; U28.K5@2175.1,1121.82 v2(2175.12,1136.03) ; U27.K5@3067.49,1120.15 v2(3067.51,1134.37) ; U30.K5@3834.88,1116.82 v2(3834.9,1131.03)
  Layer 3 - SIG w4.5: v2(1407.73,1132.7) 1408.53,1131.9 1408.53,1071.89 1358.06,1021.42 1124.61,1021.42 1087,1059.03 1087,1746.97 1369.97,2029.94 1624.24,2029.94 1652.1,2002.08 1652.1,1949.4 1735.77,1865.73 1844.29,1865.73 1864,1885.44 1911.87,1885.44 1922.37,1895.93 1965.25,1895.93 v1(1978.75,1882.44)
  Layer 5 - SIG w5: v1(1978.75,1882.44) 1965.25,1895.93 1922.37,1895.93 1907.32,1880.89 1866.96,1880.89 1838.85,1852.78 1785.63,1852.78 1737.43,1804.58 1737.43,1255.64 1783.09,1209.98 1783.09,1186.18 1967.27,1002 2102.7,1002 2175.92,1075.22 2175.92,1135.23 v2(2175.12,1136.03)
  Layer 11 - SIG w5: v1(1978.75,1882.44) 1965.25,1895.93 1922.37,1895.93 1907.32,1880.89 1866.96,1880.89 1827.81,1841.74 1827.81,1695.08 2059.39,1463.49 2220.62,1463.49 2252.12,1495 2471.16,1495 2620.23,1345.92 2620.23,1304.83 2647.77,1277.29 2647.77,1142.23 2837.07,952.93 3012.1,952.93 3038.83,979.67 3038.83,1027.29 3067.51,1055.96 v2(3067.51,1134.37)
  Layer 14 - SIG w4.5: v1(1978.75,1882.44) 1978.75,1883.36 1966.18,1895.93 1922.37,1895.93 1907.32,1880.89 1866.96,1880.89 1827.81,1841.74 1827.81,1823.96 1757.86,1754.02 1757.86,1690.14 1778,1670 1882.17,1670 2046.75,1505.43 2279.79,1505.43 2839.35,945.87 3060.92,945.87 3103.8,902.99 3555.87,902.99 3614.19,961.32 3725.99,961.32 3835.3,1070.62 3835.3,1130.63 v2(3834.9,1131.03)
A_TX_OUT8: U25.B10 U27.L6 U28.L6 U29.L6 U30.L6 | length 10182.9
  Top Layer w6: v2(1429,1049) 1429.24,1049.24 1429.24,1068.82 1433.51,1073.09 U29.L6@1433.51,1092.42 ; v1@1978.75,1912.26 U25.B10@1994.26,1896.75 ; v2(2198.15,1050.79) 2199.73,1052.37 2199.73,1095.27 U28.L6@2200.69,1096.23 ; v2(3090.64,1037) 3093.29,1039.65 U27.L6@3093.29,1094.09 ; v2(3855.63,1047.48) 3855.63,1085.71 U30.L6@3860.68,1090.76
  Layer 3 - SIG w4.5: v2(1429,1049) 1415.51,1035.51 1415.51,962.31 1324.2,871 1069,871 1006.63,933.37 1006.63,1773.16 1369.47,2136 1627.72,2136 1772.31,1991.41 1772.31,1941.81 1803.3,1910.82 1832.81,1910.82 1854.63,1932.64 1958.21,1932.64 v1(1978.59,1912.26)
  Layer 5 - SIG w5: v1(1978.59,1912.26) 1958.21,1932.64 1862.13,1932.64 1840.32,1910.82 1776.17,1910.82 1761,1925.99 1684.9,1925.99 1643,1884.09 1643,1683.69 1621.25,1661.94 1621.25,1279.63 1717.54,1183.35 1717.54,1129.5 1907.04,940 2103,940 2195.4,1032.4 ; 2196.4,1033.4 2198.15,1035.15 v2(2198.15,1050.79)
  Layer 11 - SIG w5: v1(1978.59,1912.26) 1958.21,1932.64 1862.13,1932.64 1783.09,1853.59 1783.09,1643.43 2009.44,1417.07 2262.39,1417.07 2283.32,1438 2418.79,1438 2540.25,1316.54 2540.25,1309.27 2591.32,1258.2 2591.32,1102.68 2807.51,886.49 3042.07,886.49 3090.64,935.07 v2(3090.64,1037)
  Layer 14 - SIG w4.5: v1(1978.59,1912.26) 1958.21,1932.64 1862.13,1932.64 1782.5,1853.01 1689.87,1853.01 1673,1836.13 1673,1635.26 1721.83,1586.43 1863.72,1586.43 2024.16,1426 2216.86,1426 2276.21,1366.66 2299.39,1366.66 2793.81,872.24 3003.11,872.24 3054.6,820.74 3582.95,820.74 3650.95,888.74 3755.76,888.74 3812.89,945.87 3812.89,972.7 3855.63,1015.44 v2(3855.63,1047.48)
A_TX_OUT9: U25.A1 U27.B5 U28.B5 U29.B5 U30.B5 | length 5119.5
  Top Layer w6: v2(1406.82,1310.1) 1407.27,1310.54 1407.27,1322.77 U29.B5@1407.71,1323.21 ; v2(2174.21,1313.43) 2174.66,1313.88 2174.66,1326.1 U28.B5@2175.1,1326.55 ; U25.A1@2277.72,1865.25 2277.87,1865.39 2345.29,1865.39 v1(2346.34,1866.43) ; v2(3066.6,1311.77) 3067.05,1312.21 3067.05,1324.43 U27.B5@3067.49,1324.88
  Layer 3 - SIG w4.5: v2(1406.82,1310.1) 1426,1329.28 1426,1443.9 1526.46,1544.36 1642.43,1544.36 1649.43,1537.36 1969.55,1537.36 2006.19,1574 2130.28,1574 2203.84,1647.56 2242.56,1647.56 2356.61,1761.61 2356.61,1856.16 v1(2346.34,1866.43)
  Layer 5 - SIG w5: v2(2174.21,1313.43) 2197.75,1336.97 2197.75,1444.8 2262.48,1509.53 2262.48,1536.42 2356.61,1630.55 2356.61,1856.16 v1(2346.34,1866.43)
  Layer 11 - SIG w5: v1(2346.34,1866.43) 2400.27,1920.37 2508.62,1920.37 2516.88,1928.63 2690.58,1928.63 2745.07,1874.15 2745.07,1842.66 2754.49,1833.24 2754.49,1755.45 2855.95,1654 2919.69,1654 2967.5,1606.19 2967.5,1542.45 3090.63,1419.32 3090.63,1393.95 3090.64,1335.81 v2(3066.6,1311.77)
  Layer 14 - SIG w4.5: v1(2346.34,1866.43) 2510.44,1702.33 2700,1702.33 2844.83,1557.5 3043.83,1557.5 3044.43,1556.9 3083,1556.9 3115.19,1524.72 3306.97,1524.72 3340.14,1491.56 3523.04,1491.56 3588.68,1557.2 3703.59,1557.2 3853.17,1407.62 3853.17,1348.17 3833.99,1328.99 v2(3833.99,1308.43)
A_TX_OUT10: U25.B1 U27.A5 U28.A5 U29.A5 U30.A5 | length 4936.5
  Top Layer w6: v2(1406,1401) 1406.85,1400.15 1406.85,1349.66 U29.A5@1407.71,1348.8 ; U28.A5@2175.1,1352.14 2175.1,1370.34 2180,1375.24 v2@2180,1393.45 ; v2(2180,1400) v2@2180,1393.45 ; v2@2183.39,1396.84 v2@2180,1393.45 ; U25.B1@2277.72,1896.75 2278.17,1897.19 2319.79,1897.19 v1(2320.24,1897.63) ; v2@3065.78,1402.67 3066.64,1401.81 3066.64,1351.32 U27.A5@3067.49,1350.47 ; v2(3833.17,1399.33) 3834.02,1398.48 3834.02,1347.99 U30.A5@3834.88,1347.14
  Layer 3 - SIG w4.5: v2(1406,1401) 1406,1467.7 1514.21,1575.9 1647.88,1575.9 1655.71,1583.73 1669.38,1583.73 1677.22,1575.9 1679.65,1575.9 1679.71,1575.83 1962.69,1575.83 2010.52,1623.66 2138.74,1623.66 2190.88,1675.81 2236.67,1675.81 2336.05,1775.19 2336.05,1843.2 2324.27,1854.98 2324.27,1893.6 v1(2320.24,1897.63)
  Layer 5 - SIG w5: v2@2177.75,1401.56 2173.39,1405.91 2173.39,1448.72 2242.48,1517.82 2242.48,1587.69 2330.77,1675.98 2330.77,1846.41 2324.27,1852.91 2324.27,1877.33 2320.24,1881.37 v1(2320.24,1897.63)
  Layer 11 - SIG w5: v1(2320.24,1897.63) 2320.24,1864.25 2339.18,1845.3 2369.38,1845.3 2378.72,1854.64 2704.8,1854.64 2728.41,1831.03 2728.41,1736.59 2836.05,1628.95 2906.27,1628.95 2943.45,1591.77 2943.45,1525 v2@3065.78,1402.67
  Layer 14 - SIG w4.5: v1(2320.24,1897.63) 2320.24,1864.25 2348.35,1836.13 2348.35,1820.61 2495.63,1673.32 2691.68,1673.32 2848.9,1516.1 2951.78,1516.1 2962.46,1505.43 3091.9,1505.43 3102.21,1495.12 3206.69,1495.12 3207.04,1494.77 3283.92,1494.77 3323.57,1455.12 3539.41,1455.12 3579.06,1494.77 3737.74,1494.77 v2(3833.17,1399.33)
  other v2: 3065.78,1398.67
A_TX_OUT11: U25.C1 U27.B4 U28.B4 U29.B4 U30.B4 | length 5317.6
  Top Layer w6: v2@2149.51,1311.54 U28.B4@2149.51,1326.55 ; U25.C1@2277.72,1928.24 v1@2299.66,1928.24 ; v2@3041.9,1309.87 U27.B4@3041.9,1324.88 ; v2@3809.29,1306.54 U30.B4@3809.29,1321.55
  Layer 3 - SIG w4.5: v2(1382.12,1310.1) 1382.12,1328.06 1397.42,1343.36 1397.42,1381.01 1386,1392.43 1386,1415.57 1363.45,1438.12 1363.45,1549.89 1383.49,1569.93 1449.57,1569.93 1488.47,1608.83 1693.38,1608.83 1698.22,1604 1944.37,1604 2001.37,1661 2148.5,1661 2194.06,1706.56 2234.83,1706.56 2313.49,1785.22 2313.49,1827.07 2299.77,1840.79 v1(2299.77,1928.35)
  Layer 5 - SIG w5: v2(2149.51,1313.43) 2166.69,1330.61 2166.69,1384.33 2135.48,1415.54 2135.48,1490.43 2200.45,1555.4 2200.45,1607.15 2304.27,1710.97 2304.27,1852.78 2299.77,1857.28 v1(2299.77,1928.35)
  Layer 11 - SIG w5: v1(2299.77,1928.35) 2299.77,1856.43 2339.89,1816.31 2385.55,1816.31 2403.88,1834.64 2667.04,1834.64 2690.58,1811.09 2690.58,1734.86 2888.71,1536.73 2899.02,1536.73 3057.2,1378.55 3057.2,1349.78 3041.9,1334.48 v2(3041.9,1311.77)
  Layer 14 - SIG w4.5: v1(2299.77,1928.35) 2299.77,1856.43 2316,1840.2 2316,1807.23 2480.9,1642.33 2675.32,1642.33 2830.95,1486.7 2931.56,1486.7 2943.15,1475.12 3079.72,1475.12 3088.88,1465.96 3266.78,1465.96 3306.74,1426 3555.6,1426 3595.55,1465.96 3735.69,1465.96 3825.09,1376.55 3825.09,1347.74 3809.29,1331.94 v2(3809.29,1308.43)
A_TX_OUT12: U25.A2 U27.A4 U28.A4 U29.A4 U30.A4 | length 4751.8
  Top Layer w6: v2(1381.92,1364.1) 1382.02,1364 1382.02,1348.9 U29.A4@1382.12,1348.8 ; v2@2149.36,1367.38 2149.46,1367.29 2149.46,1352.18 U28.A4@2149.51,1352.14 U28.A4@2149.56,1352.09 ; U25.A2@2246.27,1865.25 v1(2283.14,1828.43) ; v2(3041.7,1365.77) 3041.8,1365.67 3041.8,1350.57 U27.A4@3041.9,1350.47 ; v2(3809.09,1362.43) 3809.19,1362.34 U30.A4@3809.19,1347.23 ; U30.A4@3809.19,1347.23 U30.A4@3809.29,1347.14 U30.A4@3809.19,1347.23
  Layer 3 - SIG w4.5: v2@1379.82,1364.7 1379.82,1372.19 1362.34,1389.68 1362.34,1397.85 1335.48,1424.7 1335.48,1575.9 1368.41,1608.83 1438.93,1608.83 1470.64,1640.54 1921.8,1640.54 1972.59,1691.33 2151.26,1691.33 2190.9,1730.97 2228.22,1730.97 2283.14,1785.89 v1(2283.14,1828.43)
  Layer 5 - SIG w5: v2(2149.31,1367.43) 2137.47,1379.28 2137.47,1385.26 2113.78,1408.96 2113.78,1531.07 2170.21,1587.5 2170.21,1642.71 2283.14,1755.64 v1(2283.14,1828.43)
  Layer 11 - SIG w5: v1(2283.14,1828.43) 2325.54,1786.03 2408.25,1786.03 2430.95,1808.73 2646.53,1808.73 2667.04,1788.23 2667.04,1718.96 2881.67,1504.33 2903.14,1504.33 v2(3041.7,1365.77)
  Layer 14 - SIG w4.5: v1(2283.14,1828.43) 2283.14,1792.7 2465.3,1610.53 2655.83,1610.53 2816.9,1449.46 2919.54,1449.46 2933.88,1435.12 3071.18,1435.12 3080.3,1426 3257.69,1426 3291.96,1391.73 3570.05,1391.73 3613.32,1435 3736.53,1435 v2(3809.09,1362.43)
A_TX_OUT13: U25.B2 U27.B3 U28.B3 U29.B3 U30.B3 | length 5256.9
  Top Layer w6: v2@1355.82,1308.39 1356.18,1308.74 1356.18,1322.88 U29.B3@1356.53,1323.21 ; v2@2123.21,1311.73 2123.57,1312.08 2123.57,1326.21 U28.B3@2123.92,1326.55 ; v1(2230.72,1881.23) U25.B2@2246.23,1896.75 ; v2@3015.6,1310.06 3015.96,1310.41 3015.96,1324.54 U27.B3@3016.31,1324.88 ; v2@3782.99,1306.73 3783.35,1307.08 3783.35,1321.21 U30.B3@3783.7,1321.55
  Layer 3 - SIG w4.5: v2(1355.82,1310.1) 1355.82,1332.16 1277.58,1410.41 1277.58,1634.36 1356.21,1713 1563.57,1713 1577.34,1699.23 1888.23,1699.23 1928.73,1739.73 2144.5,1739.73 2185.27,1780.5 2198.92,1780.5 2241.9,1823.48 2241.9,1869.08 2230.72,1880.26 v1(2230.72,1881.23)
  Layer 5 - SIG w5: v2(2123.21,1313.43) 2123.21,1341.89 2063.46,1401.64 2063.46,1674.09 2112.62,1723.25 2155.17,1723.25 2234.73,1802.81 2234.73,1851.6 2230.72,1855.61 v1(2230.72,1881.23)
  Layer 11 - SIG w5: v1(2230.72,1881.23) 2230.72,1855.61 2234.73,1851.6 2234.73,1765.71 2244.89,1755.55 2277.19,1755.55 2303.74,1729 2573,1729 2884.93,1417.07 2927.84,1417.07 2971.78,1373.13 2971.78,1355.59 v2(3015.6,1311.77)
  Layer 14 - SIG w4.5: v1(2230.72,1881.23) 2230.72,1855.61 2234.73,1851.6 2234.73,1764.6 2444.22,1555.12 2610.45,1555.12 2813.59,1351.97 2942.74,1351.97 2945.36,1349.35 3031.95,1349.35 3048.76,1332.54 3186.29,1332.54 3195.26,1323.57 3611.82,1323.57 3669.76,1381.51 3729.4,1381.51 3782.99,1327.92 v2(3782.99,1308.43)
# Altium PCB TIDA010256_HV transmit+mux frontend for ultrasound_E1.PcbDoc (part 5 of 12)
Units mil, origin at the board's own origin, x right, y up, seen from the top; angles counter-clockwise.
Board outline 6192.49 x 6712.23 mil, 16 copper layers (Top Layer, Layer 2 - GND, Layer 3 - SIG, Layer 4 - GND, Layer 5 - SIG, Layer 6 - SIG, Layer 7 - GND, Layer 8 - HV PWR, Layer 9 - LV PWR, Layer 10 - GND, Layer 11 - SIG, Layer 12 - SIG, Layer 13 - GND, Layer 14 - SIG, Layer 15 - GND, Bottom Layer), stack 95.905 mil thick; 806 components, 539 nets, 3343 pads, 1848 vias.

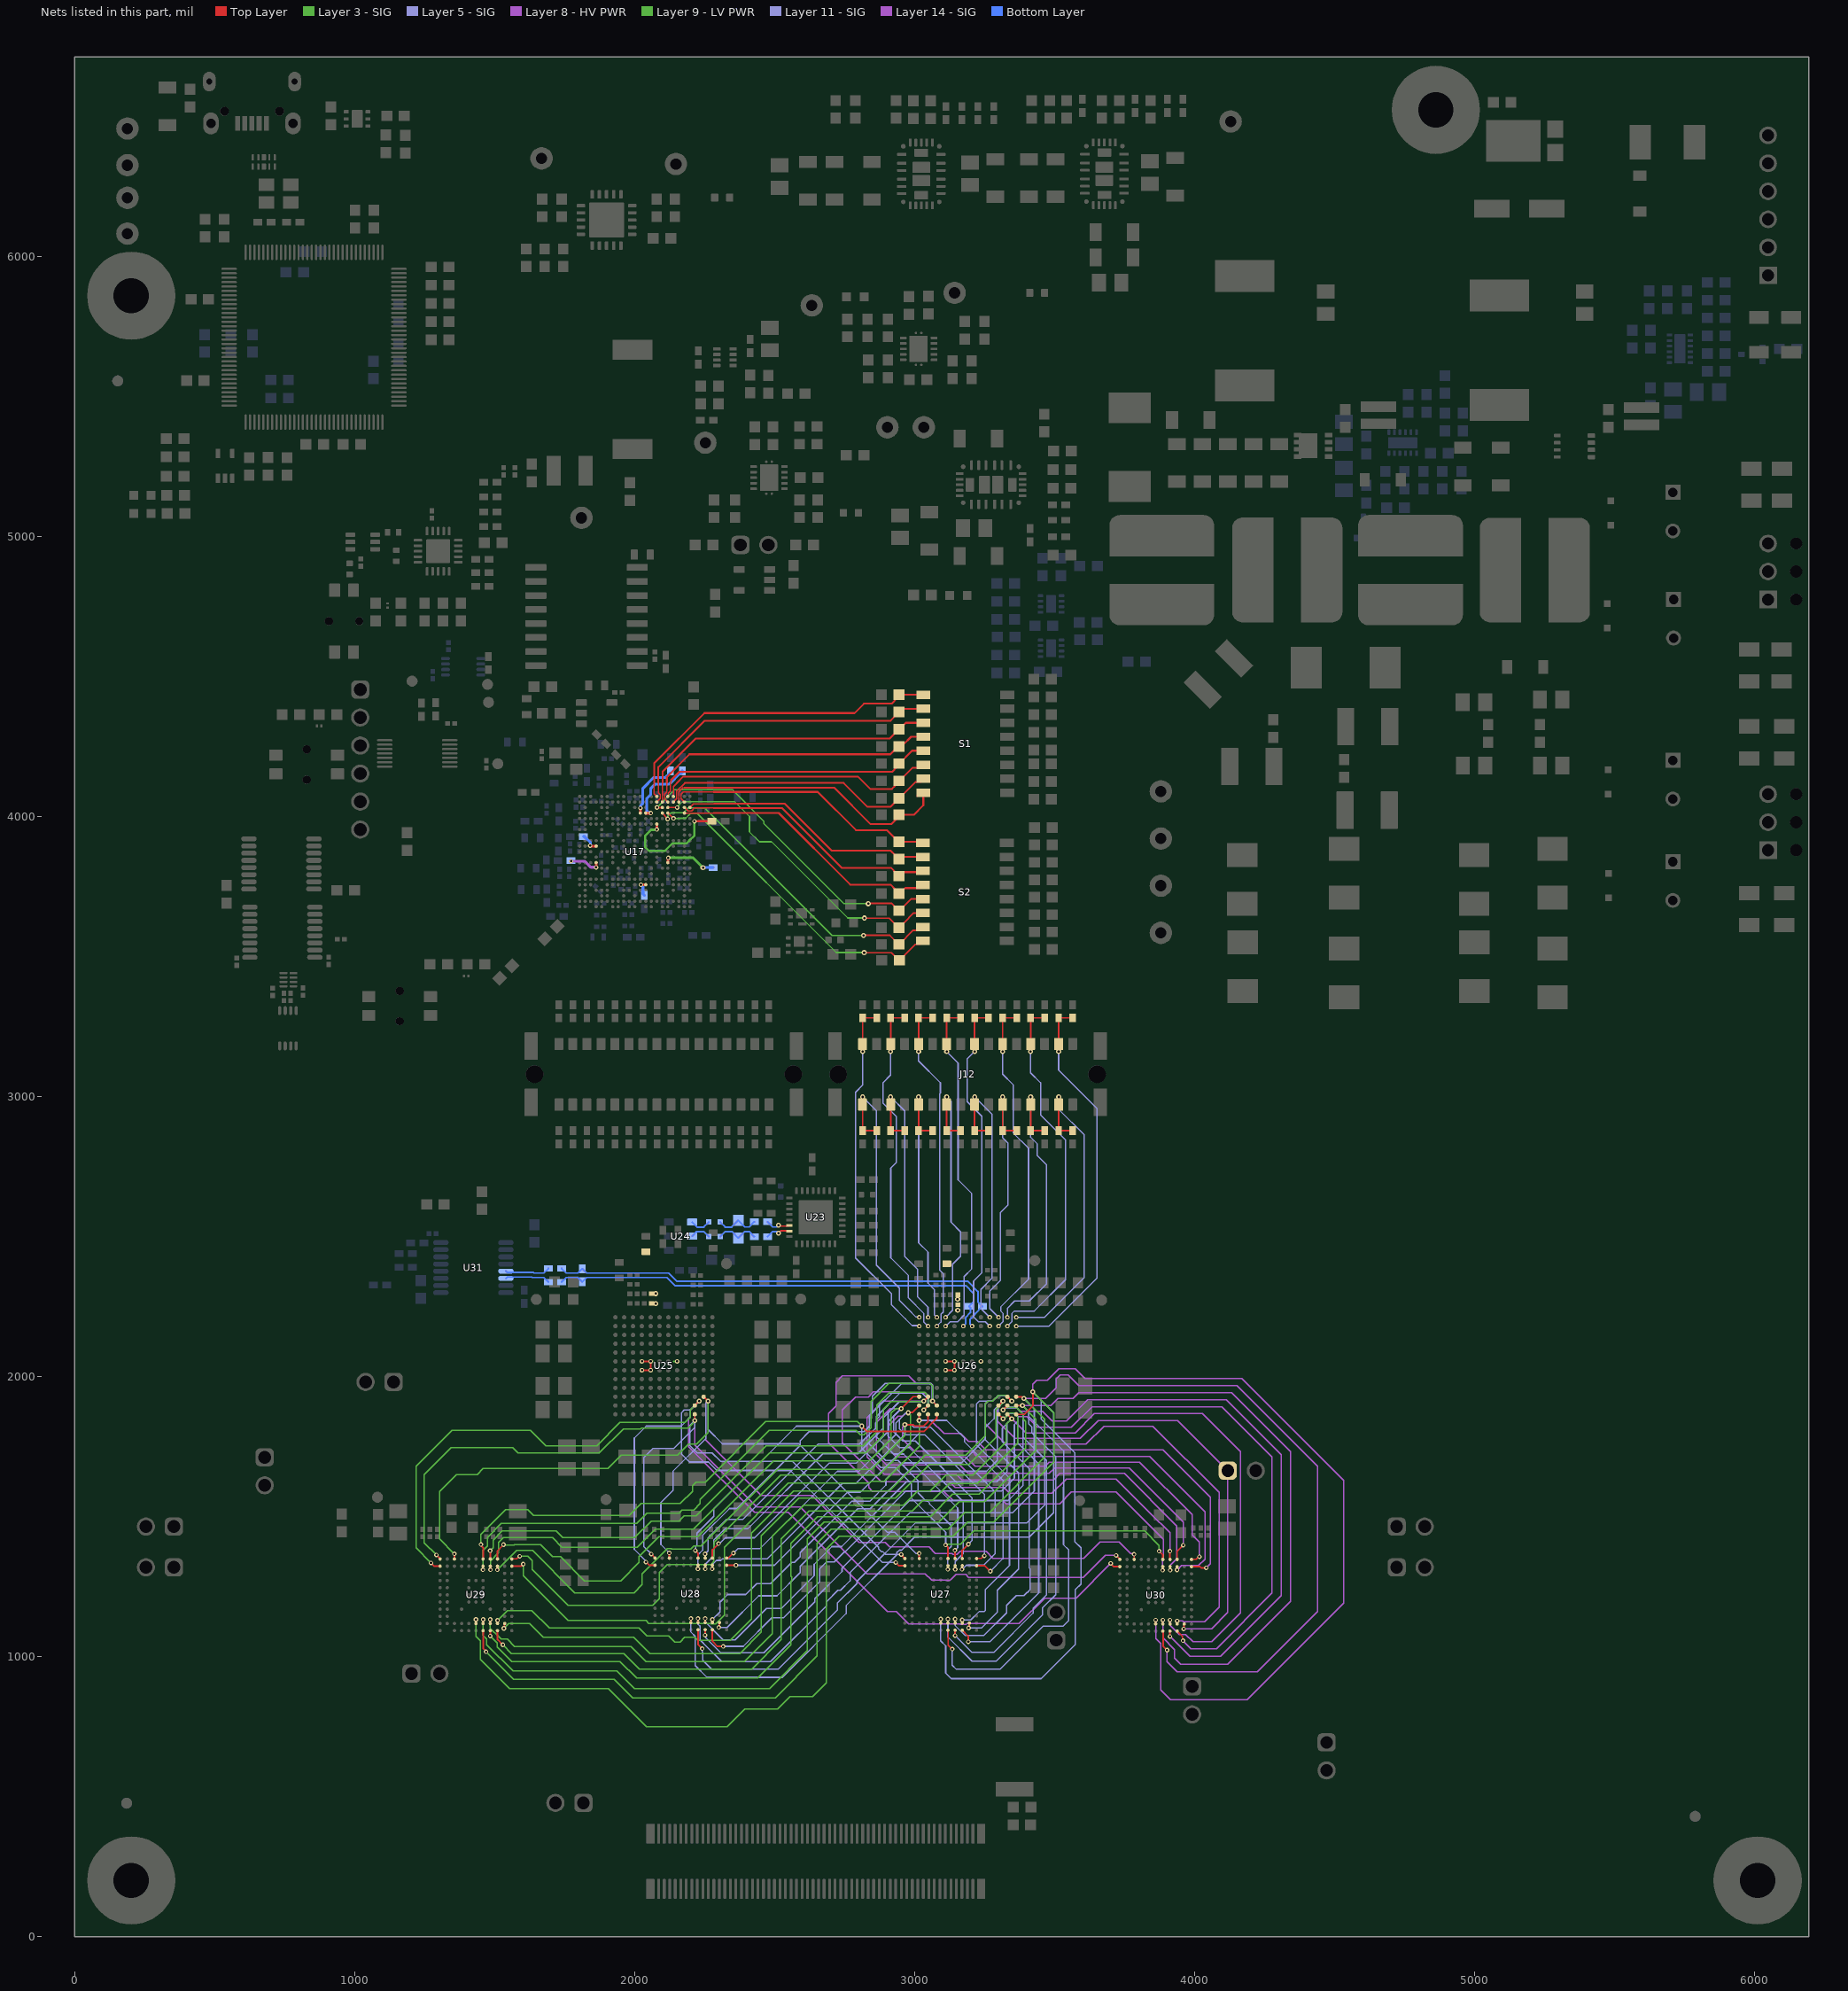
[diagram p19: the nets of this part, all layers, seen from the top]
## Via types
v1: diameter 18, hole 8, Top Layer to Bottom Layer, tented both sides, 930 vias
v2: diameter 16, hole 8, Top Layer to Bottom Layer, tented both sides, 340 vias
v3: diameter 16, hole 8, Top Layer to Bottom Layer, tented bottom, 226 vias
v4: diameter 20, hole 10, Top Layer to Bottom Layer, tented both sides, 129 vias
v5: diameter 50, hole 30, Top Layer to Bottom Layer, tented both sides, 96 vias
v6: diameter 30, hole 15, Top Layer to Bottom Layer, tented both sides, 47 vias
v7: diameter 19.68, hole 7.87, Top Layer to Bottom Layer, 40 vias
v8: diameter 19.68, hole 7.87, Top Layer to Bottom Layer, tented both sides, 19 vias
v9: diameter 18, hole 8, Top Layer to Bottom Layer, tented bottom, 13 vias
v10: diameter 40, hole 20, Top Layer to Bottom Layer, tented both sides, 4 vias
v11: diameter 40, hole 20, Top Layer to Bottom Layer, 3 vias
v12: diameter 18, hole 8, Top Layer to Bottom Layer, 1 vias

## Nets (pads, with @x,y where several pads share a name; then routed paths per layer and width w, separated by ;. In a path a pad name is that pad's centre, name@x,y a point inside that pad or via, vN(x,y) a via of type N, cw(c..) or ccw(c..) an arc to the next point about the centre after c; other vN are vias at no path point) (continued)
A_TX_OUT14: U25.C2 U27.A3 U28.A3 U29.A3 U30.A3 | length 5062.1
  Top Layer w6: v2(1356.33,1367.4) 1356.43,1367.3 1356.43,1348.9 U29.A3@1356.53,1348.8 ; v2@2123.87,1370.58 2123.87,1352.19 U28.A3@2123.92,1352.14 ; U25.C2@2246.23,1928.24 v1@2261.74,1912.73 ; v2(3016.11,1369.07) 3016.21,1368.97 3016.21,1350.57 U27.A3@3016.31,1350.47 ; v2(3783.5,1365.74) 3783.6,1365.63 3783.6,1347.24 U30.A3@3783.7,1347.14
  Layer 3 - SIG w4.5: v2(1356.33,1367.4) 1303,1420.73 1303,1589.87 1363.61,1650.48 1437.83,1650.48 1459.28,1671.93 1903.93,1671.93 1952.23,1720.23 2152.58,1720.23 2192.14,1759.8 2221.7,1759.8 2261.9,1799.99 v1(2261.9,1912.73)
  Layer 5 - SIG w5: v2@2123.51,1370.74 2123.51,1370.94 2093.78,1400.67 2093.78,1550.48 2136.66,1593.37 2136.66,1661.97 2254.73,1780.04 2254.73,1905.56 v1(2261.9,1912.73)
  Layer 11 - SIG w5: v1(2261.9,1912.73) 2261.9,1811.28 2313.18,1760 2585.98,1760 2901.94,1444.04 2929.16,1444.04 3004.13,1369.07 v2(3016.11,1369.07)
  Layer 14 - SIG w4.5: v1(2261.9,1912.73) 2254.73,1905.56 2254.73,1772.88 2451.78,1575.83 2634.15,1575.83 2801.75,1408.23 2894.04,1408.23 2910.54,1391.73 3050.73,1391.73 3073.73,1368.73 3133.26,1368.73 3137.34,1364.65 3150.92,1364.65 3162.63,1376.36 3249,1376.36 3249.59,1375.77 3255.42,1375.77 3279.69,1351.5 3399.83,1351.5 3604.11,1351.5 3662.07,1409.46 3729.73,1409.46 3770.47,1368.73 3780.5,1368.73 v2@3780.5,1362.74
  other v2: 2123.72,1370.74
A_TX_OUT15: U25.A3 U27.A1 U28.A1 U29.A1 U30.A1 | length 4929.9
  Top Layer w6: v2(1292,1363.18) 1305.35,1349.83 U29.A1@1305.35,1348.8 ; v2(2059.39,1366.51) 2072.74,1353.17 U28.A1@2072.74,1352.14 ; v1(2214.73,1843.31) U25.A3@2214.73,1865.25 ; v2(2951.78,1364.85) 2965.13,1351.5 U27.A1@2965.13,1350.47 ; v2(3719.17,1361.51) 3732.52,1348.17 U30.A1@3732.52,1347.14
  Layer 3 - SIG w4.5: v2(1292,1363.18) 1249,1406.18 1249,1650.48 1345.49,1746.97 1563.95,1746.97 1583.89,1727.03 1873.03,1727.03 1959.5,1813.5 2021.36,1813.5 2023.79,1815.93 2190.25,1815.93 2214.73,1840.41 v1(2214.73,1843.31)
  Layer 5 - SIG w5: v2(2059.39,1366.51) 2033.12,1392.79 2033.12,1710.97 2065.4,1743.25 2139.78,1743.25 2214.73,1818.21 v1(2214.73,1843.31)
  Layer 11 - SIG w5: v1(2214.73,1843.31) 2197.5,1826.08 2197.5,1753.3 2223,1727.8 2276.66,1727.8 2306.46,1698 2563,1698 2870.71,1390.29 2870.71,1384.9 2880.37,1375.23 2885.77,1375.23 2896.15,1364.85 v2(2951.78,1364.85)
  Layer 14 - SIG w4.5: v1(2214.73,1843.31) 2214.73,1756.32 2435.93,1535.12 2591.32,1535.12 2830.17,1296.27 3037.08,1296.27 3058.99,1274.36 3059.72,1274.36 3060.58,1273.5 3111.58,1273.5 3112.58,1272.5 3125.42,1272.5 3127.28,1274.36 3129.44,1274.36 3148.58,1293.5 3182.33,1293.5 3192.83,1283 3602.55,1283 3681.06,1361.51 v2(3719.17,1361.51)
A_TX_OUT16: U25.B3 U27.B1 U28.B1 U29.B1 U30.B1 | length 5657.6
  Top Layer w6: v2(1272.71,1334.8) 1284.3,1323.21 U29.B1@1305.35,1323.21 ; v2(2040.1,1338.13) 2051.69,1326.54 U28.B1@2072.74,1326.55 ; U25.B3@2214.73,1896.75 v1@2230.24,1912.26 ; v2(2932.49,1336.47) 2944.08,1324.88 U27.B1@2965.13,1324.88 ; v2(3699.88,1333.14) 3711.47,1321.55 U30.B1@3732.52,1321.55
  Layer 3 - SIG w4.5: v2(1272.71,1334.8) 1219.24,1388.27 1219.24,1679.36 1348.07,1808.19 1627.67,1808.19 1682.85,1753 1865,1753 1948.13,1836.13 2179.97,1836.13 2194.73,1850.89 2194.73,1851.6 2198.61,1855.48 2198.61,1880.78 v1(2230.24,1912.42)
  Layer 5 - SIG w5: v2(2040.1,1338.13) 2040.1,1341.88 1998.75,1383.23 1998.75,1780.52 2041.44,1823.21 2166.35,1823.21 2198.61,1855.48 2198.61,1880.78 v1(2230.24,1912.42)
  Layer 11 - SIG w5: v1(2230.24,1912.42) 2198.45,1880.62 2176.87,1880.62 2167.86,1871.62 2167.86,1722.9 2195.68,1695.08 2263.29,1695.08 2293.37,1665 2555.9,1665 2884.43,1336.47 v2(2932.49,1336.47)
  Layer 14 - SIG w4.5: v1(2230.24,1912.42) 2198.61,1880.78 2198.61,1855.48 2193.24,1850.1 2193.24,1749.53 2427.65,1515.12 2548.5,1515.12 2902.62,1161 2934.35,1161 2978.08,1117.27 3161.83,1117.27 3163.43,1115.67 3183.76,1115.67 3186.36,1118.27 3372.72,1118.27 3463.79,1209.33 3576.08,1209.33 v2(3699.88,1333.14)
AVDD_IO1: C266.1 C267.1 FB14.2 U25.F8 U25.F9 U25.G5 U25.G8 U25.G9 | length 116.9
  Top Layer w6.8: v3(2025.76,2022.73) v3(2057.25,2022.73) v3(2057.25,2054.23) v3(2025.76,2054.23)
  Layer 9 - LV PWR w6.8: v3@2057.39,2054.37 v3(2057.25,2054.23) 2067.21,2054.23 ; 2139.5,2054.37 2151.6,2054.37 v3(2151.74,2054.23)
  other v1: 2075.03,2260.76 2075.37,2296.35
AVDD_IO2: C297.1 C298.1 FB17.2 U26.F8 U26.F9 U26.G5 U26.G8 U26.G9 | length 104.1
  Top Layer w6.8: v3(3110.54,2022.73) v3(3142.03,2022.73) v3(3142.03,2054.23) v3(3110.54,2054.23)
  Layer 9 - LV PWR w6.8: v3(3142.03,2054.23) 3151.62,2054.23
  other v1: 3153.55,2236.44 3153.34,2276.73
  other v3: 3236.52,2054.23
B_RX_IN1: C473.1 J12.A1 R146.2 U26.L12 | length 1269
  Top Layer w6: v1@2814.03,3160.61 R146.2@2814.03,3280.78 C473.1@2864.03,3280.78
  Layer 5 - SIG w5: v1@2814.28,3160.73 2814.28,3040.83 2788.89,3015.44 2788.89,2423.85 2916.63,2296.11 2916.63,2256.31 2967,2205.94 2990.74,2182.2 3014.06,2182.2 v3(3016.05,2180.21)
  other v1: 2814.03,3160.73
B_RX_IN2: C477.1 J12.B1 R460.2 U26.M12 | length 1046.5
  Top Layer w6: v1(2814.03,2998.41) R460.2@2814.03,2878.24 C477.1@2864.03,2878.24
  Layer 5 - SIG w5: v1@2814.28,2998.41 2863.26,2949.43 2863.26,2398.33 2945.41,2316.18 2945.41,2272.03 2976.99,2240.44 3005.02,2212.42 3015.33,2212.42 v3(3016.05,2211.71)
B_RX_IN3: C481.1 J12.A3 R464.2 U26.L11 | length 1244.5
  Top Layer w6: v1@2914.03,3160.61 R464.2@2914.03,3280.78 C481.1@2964.03,3280.78
  Layer 5 - SIG w5: v1@2913.83,3160.73 2913.83,3076.36 2887.43,3049.96 2887.43,2975.61 2934.51,2928.53 2934.51,2764.18 2914.56,2744.23 2914.56,2423.92 2977.54,2360.94 2977.54,2280.77 3031.92,2226.38 3031.92,2195.83 v3(3047.54,2180.21)
  other v1: 2914.03,3160.73
B_RX_IN4: C485.1 J12.B3 R468.2 U26.M11 | length 1012.1
  Top Layer w6: v1(2914.05,2998.41) R468.2@2914.03,2878.24 C485.1@2964.03,2878.24
  Layer 5 - SIG w5: v1@2914.28,2998.41 2964.03,2948.65 2964.03,2429.23 3010.9,2382.36 3010.9,2284.34 3047.54,2247.7 v3(3047.54,2211.71)
B_RX_IN5: C489.1 J12.A5 R472.2 U26.L10 | length 1198.6
  Top Layer w6: v1@3014.03,3160.61 R472.2@3014.03,3280.78 C489.1@3064.03,3280.78
  Layer 5 - SIG w5: v1@3013.83,3160.73 3013.83,3127.12 3091.61,3049.34 3091.61,3011.3 3089.08,3008.76 3089.08,2379.86 3101.78,2367.16 3101.78,2230.41 3093.66,2222.29 3093.66,2194.83 v3(3079.04,2180.21)
  other v1: 3014.03,3160.73
B_RX_IN6: C493.1 J12.B5 R476.2 U26.M10 | length 983.7
  Top Layer w6: v1@3014.03,2998.41 R476.2@3014.03,2878.24 C493.1@3064.03,2878.24
  Layer 5 - SIG w5: v1@3014.28,2998.41 3014.28,2477.61 3047.37,2444.52 3047.37,2334.12 3069.97,2311.52 3069.97,2220.78 v3(3079.04,2211.71)
  other v1: 3014.06,2998.41
B_RX_IN7: C497.1 J12.A7 R480.2 U26.L9 | length 1242.4
  Top Layer w6: v1@3114.03,3160.61 R480.2@3114.03,3280.78 C497.1@3164.03,3280.78
  Layer 5 - SIG w5: v3(3110.54,2180.21) 3126.36,2196.03 3153.31,2196.03 3176.41,2219.13 3176.41,2357.15 3203.84,2384.58 3203.84,2653.75 3154.98,2702.62 3154.98,3119.58 v1@3113.83,3160.73
  other v1: 3114.03,3160.73
B_RX_IN8: C501.1 J12.B7 R484.2 U26.M9 | length 999.7
  Top Layer w6: v1@3114.03,2998.41 R484.2@3114.03,2878.24 C501.1@3164.03,2878.24
  Layer 5 - SIG w5: v3(3110.54,2211.71) 3135.33,2236.5 3135.33,2401.42 3164.03,2430.12 3164.03,2517.15 3129.81,2551.37 3129.81,2982.68 v1(3114.08,2998.41)
B_RX_IN9: C502.1 J12.A9 R485.2 U26.L4 | length 1233.7
  Top Layer w6: v1@3214.03,3160.61 R485.2@3214.03,3280.78 C502.1@3264.03,3280.78
  Layer 5 - SIG w5: v1@3213.83,3160.73 3187.47,3134.37 3187.47,2981.63 3239.61,2929.49 3239.61,2370.2 3210.46,2341.04 3210.46,2240.44 3210.46,2212.8 3227.57,2195.69 3252.54,2195.69 v3(3268.02,2180.21)
  other v1: 3214.03,3160.73
B_RX_IN10: C498.1 J12.B9 R481.2 U26.M4 | length 1011.5
  Top Layer w6: v1@3214.03,2998.41 R481.2@3214.03,2878.24 C498.1@3264.03,2878.24
  Layer 5 - SIG w5: v1@3214.28,2998.41 3275.57,2937.11 3275.57,2350.57 3236.52,2311.52 3236.52,2243.2 v3(3268.02,2211.71)
  other v1: 3214.1,2998.41
B_RX_IN11: C494.1 J12.A11 R477.2 U26.L3 | length 1240
  Top Layer w6: v1@3314.03,3160.61 R477.2@3314.03,3280.78 C494.1@3364.03,3280.78
  Layer 5 - SIG w5: v3(3299.51,2180.21) 3315.14,2195.83 3315.14,2226.17 3307.17,2234.14 3307.17,2248.49 3406.59,2347.9 3406.59,2815.42 3351.48,2870.53 3351.48,3042.5 3314.03,3079.95 v1(3314.03,3160.73)
B_RX_IN12: C490.1 J12.B11 R473.2 U26.M3 | length 1004.7
  Top Layer w6: v1@3314.03,2998.41 R473.2@3314.03,2878.24 C490.1@3364.03,2878.24
  Layer 5 - SIG w5: v3(3299.51,2211.71) 3268.02,2243.2 3268.02,2305.91 3305.98,2343.87 3305.98,2585.23 3333,2612.25 3333,2834.01 3314.11,2852.89 v1(3314.11,2998.41)
B_RX_IN13: C486.1 J12.A13 R469.2 U26.L2 | length 1330.2
  Top Layer w6: v1@3414.03,3160.61 R469.2@3414.03,3280.78 C486.1@3464.03,3280.78
  Layer 5 - SIG w5: v3(3331.01,2180.21) 3346.77,2195.97 3346.77,2225.03 3355.87,2234.14 3427.12,2234.14 3538.69,2345.7 3538.69,2845.32 3449.48,2934.53 3449.48,3049.01 3413.83,3084.66 v1@3413.83,3160.73
  other v1: 3414.03,3160.73
B_RX_IN14: C482.1 J12.B13 R465.2 U26.M2 | length 1069.2
  Top Layer w6: v1@3414.03,2998.41 R465.2@3414.03,2878.24 C482.1@3464.03,2878.24
  Layer 5 - SIG w5: v3(3331.01,2211.71) 3331.01,2244.04 3356.59,2269.62 3409.14,2269.62 3471,2331.49 3471,2755.6 3437.95,2788.65 3437.95,2830.39 3414.13,2854.22 v1(3414.13,2998.41)
B_RX_IN15: C478.1 J12.A15 R461.2 U26.L1 | length 1395.5
  Top Layer w6: v1@3514.03,3160.61 v1(3514.03,3160.73) J12.A15@3514.03,3187.78 R461.2@3514.03,3280.78 C478.1@3564.03,3280.78
  Layer 5 - SIG w5: v3(3362.5,2180.21) 3401.9,2180.21 3479.57,2180.21 3650.95,2351.58 3650.95,2956.94 3514.03,3093.86 v1(3514.03,3160.73)
B_RX_IN16: C474.1 J12.B15 R452.2 U26.M1 | length 1153.9
  Top Layer w6: v1@3514.03,2998.41 J12.B15@3514.03,2971.24 R452.2@3514.03,2878.24 C474.1@3564.03,2878.24
  Layer 5 - SIG w5: v3(3362.5,2211.71) 3401.9,2211.71 3463.65,2211.71 3604.7,2352.76 3604.7,2864.06 3514.28,2954.49 v1@3514.28,2998.41
  other v1: 3514.15,2998.41
B_SYNC_IC_N: R433.1 U31.5 | length 161.3
  Bottom Layer w6.1: U31.5@1540.23,2376.25 1545.03,2371.46 1638.57,2371.46 1640.28,2369.75 1675.51,2369.75 R433.1@1692.01,2386.25
B_SYNC_IC_P: R430.1 U31.6 | length 161.3
  Bottom Layer w6.1: U31.6@1540.23,2350.66 1545.03,2355.46 1631.94,2355.46 1633.65,2353.75 1675.51,2353.75 R430.1@1692.01,2337.25
B_SYNC_N: R431.1 R432.1 R433.2 U26.L6 | length 1685.7
  Bottom Layer w6.1: R433.2@1739.25,2386.25 1755.75,2369.75 1797.01,2369.75 R431.1@1812.63,2385.37 1828.25,2369.75 2121.57,2369.75 2150.31,2341.01 3188.97,2341.01 3226.13,2303.86 3226.13,2266.44 R432.1@3241.75,2250.82 3215.28,2224.35 3215.28,2221.96 3197.28,2203.96 3197.28,2187.96 v3(3205.02,2180.21)
B_SYNC_P: R430.2 R431.2 R432.2 U26.L7 | length 1650.2
  Bottom Layer w6.1: R430.2@1739.25,2337.25 1755.75,2353.75 1797.01,2353.75 R431.2@1812.63,2338.13 1828.25,2353.75 2114.94,2353.75 2143.68,2325.01 3182.35,2325.01 3210.13,2297.23 3210.13,2266.44 R432.2@3194.5,2250.82 3199.28,2246.04 3199.28,2228.59 3181.28,2210.59 3181.28,2187.96 v3(3173.53,2180.21)
B_TX_OUT1: U26.A12 U27.B11 U28.B11 U29.B11 U30.B11 | length 5279.2
  Top Layer w6: U29.B11@1561.25,1323.21 1594.29,1323.21 v2@1601.5,1330.43 ; U28.B11@2328.64,1326.55 v2(2361.68,1326.54) ; v1(3016.05,1843.63) U26.A12@3016.05,1865.25 ; U27.B11@3221.03,1324.88 3250.52,1324.88 v2(3270.26,1305.13) ; U30.B11@3988.42,1321.55 4018.27,1321.54 4022.45,1317.37 v2(4041.23,1317.37)
  Layer 3 - SIG w4.5: v2(1602.32,1330.43) 1602.32,1289.23 1762.05,1129.5 2040.1,1129.5 2050.66,1118.94 2104.36,1118.94 2105.46,1117.83 2270.54,1117.83 2271.04,1117.34 2289.21,1117.34 2320.24,1148.36 2320.24,1391.05 2548.42,1619.23 2838.11,1619.23 2845.71,1626.83 2863.61,1626.83 2863.81,1627.03 2891.71,1627.03 3016.05,1751.37 v1(3016.05,1843.63)
  Layer 5 - SIG w5: v2(2361.68,1326.54) 2499.42,1326.54 2760.38,1587.5 2806.38,1587.5 3016.05,1797.17 v1(3016.05,1843.63)
  Layer 11 - SIG w5: v1(3016.05,1843.63) 3114.22,1843.63 3178.5,1779.35 3178.5,1766.54 3315.02,1630.02 3315.02,1349.89 v2(3270.26,1305.13)
  Layer 14 - SIG w4.5: v1(3016.05,1843.63) 3058.42,1843.63 3104.69,1797.36 3163.85,1797.36 3192.78,1768.43 3223.9,1768.43 3253.33,1739 3886.44,1739 4056.39,1569.04 4056.39,1332.54 v2(4041.23,1317.37)
B_TX_OUT2: U26.B12 U27.A11 U28.A11 U29.A11 U30.A11 | length 5189.9
  Top Layer w6: U29.A11@1561.25,1348.8 1561.98,1349.53 1578.53,1349.53 1587.6,1358.6 v2(1589.22,1358.6) ; U28.A11@2328.64,1352.14 2334.82,1352.14 v2(2352.61,1369.93) ; v1(2977.54,1870.73) 2978.68,1871.88 2991.18,1871.88 U26.B12@3016.05,1896.75 ; U27.A11@3221.03,1350.47 3221.76,1351.2 3238.31,1351.2 3247.38,1360.27 v2(3249,1360.27) ; U30.A11@3988.42,1347.14 3989.15,1347.86 4005.7,1347.86 4014.77,1356.93 v2(4016.39,1356.93)
  Layer 3 - SIG w4.5: v2(1589.22,1358.6) 1618.38,1358.6 1633.67,1343.31 1633.67,1311.11 1761.5,1183.28 2059.39,1183.28 2059.65,1183.54 2064.18,1183.54 2088.49,1207.85 2088.49,1300.63 2116.79,1328.93 2123.87,1328.93 2124.21,1329.28 2124.56,1328.93 2272.55,1328.93 2283.14,1339.52 2283.14,1398.98 2283.89,1399.74 2283.89,1409.75 2522.14,1648 2872.96,1648 2985.13,1760.17 2985.13,1863.14 v1(2977.54,1870.73)
  Layer 5 - SIG w5: v2(2352.61,1369.93) 2367.94,1385.26 2446.68,1385.26 2723.39,1661.97 2800.47,1661.97 2932.49,1793.99 2932.49,1834.5 2967,1869.01 2975.81,1869.01 v1(2977.54,1870.73)
  Layer 11 - SIG w5: v1(2977.54,1870.73) 2975.81,1869.01 2967,1869.01 2945.13,1847.14 2945.13,1813.93 2966.05,1793 3035.33,1793 3249,1579.32 v2(3249,1360.27)
  Layer 14 - SIG w4.5: v1(2977.54,1870.73) 2975.81,1869.01 2967,1869.01 2956.06,1858.08 2941.03,1858.08 2906.16,1823.21 2906.16,1742.33 2934.69,1713.8 3181.63,1713.8 3215.17,1680.27 3466.01,1680.27 3480.17,1694.43 3802.96,1694.43 3990.55,1506.85 3990.55,1435 4016.39,1409.16 v2(4016.39,1356.93)
B_TX_OUT3: U26.C12 U27.A9 U28.A9 U29.A9 U30.A9 | length 5141.5
  Top Layer w6: U29.A9@1510.07,1348.8 1510.07,1378.07 1529,1397 v2@1529,1401 ; U28.A9@2277.46,1352.14 2277.51,1381.35 2296.44,1400.28 v2@2296.44,1404.28 ; v1(2952,1885.87) 2994.36,1928.24 U26.C12@3016.05,1928.24 ; U27.A9@3169.85,1350.47 3169.85,1379.74 3188.78,1398.67 v2@3188.78,1402.67 ; U30.A9@3937.24,1347.14 3937.24,1376.4 v2@3956.17,1395.33
  Layer 3 - SIG w4.5: v2@1534.3,1399 1570.01,1399 1570.87,1399.86 1663.55,1399.86 1706.71,1356.7 1734.68,1356.7 1820.25,1271.13 1950.41,1271.13 2015.61,1336.32 2015.61,1357.16 2087.14,1428.68 2224.98,1428.68 2495.53,1699.23 2838.12,1699.23 2915.57,1776.69 2915.57,1869.44 2932,1885.87 v1(2952,1885.87)
  Layer 5 - SIG w5: v2@2302.48,1403.45 2304.47,1405.44 2304.59,1405.44 2323.83,1424.68 2428.28,1424.68 2695.17,1691.56 2792.17,1691.56 2907.21,1806.61 2907.21,1841.08 v1(2952,1885.87)
  Layer 11 - SIG w5: v1(2952,1885.87) 2925.13,1859.01 2925.13,1803.16 2958.29,1770 3002.29,1770 3205.02,1567.26 3205.02,1414.91 3193.55,1403.43 v2@3193.55,1401.67
  Layer 14 - SIG w4.5: v1(2952,1885.87) 2912.45,1885.87 2862.56,1835.98 2862.56,1721.9 2899.45,1685 3160.8,1685 3191.37,1654.43 3480.66,1654.43 3500.66,1674.43 3765.77,1674.43 3959.17,1481.04 v2(3959.17,1398.33)
  other v2: 1532,1400 3191.78,1401.67 2299.39,1403.33
B_TX_OUT4: U26.A11 U27.B9 U28.B9 U29.B9 U30.B9 | length 5268.6
  Top Layer w6: v2@1509.4,1309.68 v2(1509.4,1310.1) 1509.4,1322.54 U29.B9@1510.07,1323.21 ; v2@2276.79,1313.01 v2(2276.79,1313.43) 2276.79,1325.87 U28.B9@2277.46,1326.55 ; v1(2965.13,1828.43) 2995,1828.43 3000.47,1822.96 3030.36,1822.96 3047.54,1840.14 U26.A11@3047.54,1865.25 ; v2@3169.18,1311.34 v2(3169.18,1311.77) 3169.18,1324.2 U27.B9@3169.85,1324.88 ; v2@3936.57,1308.01 3937,1308.44 v2(3937,1310) 3937,1320.44 3936.57,1320.87 U30.B9@3937.24,1321.55
  Layer 3 - SIG w4.5: v2(1509.4,1310.1) 1579.15,1379.86 1635.23,1379.86 1786.68,1228.41 1997.29,1228.41 2026.22,1257.33 2026.22,1295.59 2116.86,1386.24 2130.14,1386.24 2131.87,1384.5 2200.49,1384.5 2211.72,1395.73 2236.64,1395.73 2509.91,1669 2845.31,1669 2965.13,1788.81 v1(2965.13,1828.43) ; v1@2962.78,1830.79 v1@2965.13,1833.14
  Layer 5 - SIG w5: v2@2276.82,1313.46 2276.82,1328.93 2291.82,1343.93 2307.49,1343.93 2313.35,1349.8 2473.14,1349.8 2741.27,1617.93 2789.42,1617.93 2965.13,1793.64 v1(2965.13,1828.43)
  Layer 11 - SIG w5: v1(2965.13,1828.43) 2987.38,1828.43 2996.69,1819.13 3056.98,1819.13 3287,1589.11 3287,1367.88 3245.66,1326.54 3183.95,1326.54 v2(3169.18,1311.77) ; v2@3164.54,1309.73 v2@3167.19,1312.38
  Layer 14 - SIG w4.5: v1(2965.13,1828.43) 2956.06,1819.37 2956.06,1775.84 2998.6,1733.3 3204.15,1733.3 3223.02,1714.43 3839.45,1714.43 4036.39,1517.49 4036.39,1348.65 4013,1325.25 3953.39,1325.25 3938.13,1310 v2(3937,1310) ; v2@3931.93,1306.4 v2@3934.58,1309.05
B_TX_OUT5: U26.B11 U27.A8 U28.A8 U29.A8 U30.A8 | length 6057.7
  Top Layer w6: v2(1483.98,1378.48) 1484.24,1378.22 1484.24,1349.04 U29.A8@1484.48,1348.8 ; v2(2251.68,1366.92) 2251.68,1352.33 U28.A8@2251.87,1352.14 ; v1@3032.03,1881.23 U26.B11@3047.54,1896.75 ; v2(3143.76,1380.15) 3144.02,1379.89 3144.02,1350.71 U27.A8@3144.26,1350.47 ; v2(3911.15,1376.82) 3911.41,1376.56 3911.41,1347.38 U30.A8@3911.65,1347.14
  Layer 3 - SIG w4.5: v2(1483.98,1378.48) 1494.3,1388.8 1494.3,1415.57 1527.11,1448.38 1720.34,1448.38 1744.01,1424.7 1999.31,1424.7 2058.94,1484.33 2159.49,1484.33 2167.79,1492.64 2167.79,1493.54 2177.46,1503.2 2219,1503.2 2469.07,1753.27 2815.41,1753.27 2865.38,1803.24 2865.38,1898.73 2910.52,1943.86 3034.95,1943.86 3047.87,1930.94 3047.87,1896.91 v1(3032.03,1881.08)
  Layer 5 - SIG w5: v2(2251.68,1366.92) 2251.68,1367.23 2262.48,1378.03 2262.48,1424.68 2328.23,1490.43 2386.41,1490.43 2654.98,1759 2803.03,1759 2859.65,1815.62 2859.65,1834.54 2863.26,1838.14 2863.26,1857.05 2947.84,1941.63 3026.07,1941.63 3047.87,1919.84 3047.87,1896.91 v1(3032.03,1881.08)
  Layer 11 - SIG w5: v1(3032.03,1881.08) 3047.53,1896.58 3047.53,1920.17 3026.07,1941.63 2908.62,1941.63 2873.78,1906.79 2873.78,1857.52 2864.19,1847.93 2864.19,1784.4 2925.16,1723.43 2960.79,1723.43 3153.55,1530.67 3153.55,1388.58 v2@3144.44,1379.47
  Layer 14 - SIG w4.5: v1(3032.03,1881.08) 3047.53,1896.58 3047.53,1932.45 3038.35,1941.63 2947.84,1941.63 2943.84,1945.63 2852.55,1945.63 2834.07,1927.15 2788.76,1927.15 2742.1,1880.48 2742.1,1763.45 2881.22,1624.33 3124.37,1624.33 3145.2,1603.5 3318.66,1603.5 3339.22,1582.93 3489.81,1582.93 3541.31,1634.43 3718.71,1634.43 3831.45,1521.7 3831.63,1521.7 3841.29,1512.04 3841.29,1511.85 3911.15,1442 v2(3911.15,1376.82)
B_TX_OUT6: U26.C11 U27.B8 U28.B8 U29.B8 U30.B8 | length 5681.4
  Top Layer w6: U29.B8@1484.48,1323.21 1484.7,1322.99 1484.7,1310.32 v2(1484.92,1310.1) ; U28.B8@2251.87,1326.55 2252.09,1326.32 2252.09,1313.66 v2(2252.31,1313.43) ; v1@3032.03,1912.73 U26.C11@3047.54,1928.24 ; U27.B8@3144.26,1324.88 3144.48,1324.66 3144.48,1311.99 v2(3144.7,1311.77) ; U30.B8@3911.65,1321.55 3911.87,1321.32 3911.87,1308.66 v2(3912.09,1308.43)
  Layer 3 - SIG w4.5: v2(1484.92,1310.1) 1484.92,1342.28 1514.3,1371.65 1514.3,1407.28 1531.72,1424.7 1706.45,1424.7 1740.1,1391.05 2008.84,1391.05 2073.36,1455.57 2209.83,1455.57 2481.3,1727.03 2825.49,1727.03 2889.15,1790.7 2889.15,1884.46 2915.43,1910.73 v1@3026.97,1910.73
  Layer 5 - SIG w5: v2(2252.31,1313.43) 2252.31,1330.25 2282.48,1360.42 2282.48,1416.4 2323.56,1457.48 2404.92,1457.48 2671.75,1724.31 2796.63,1724.31 2887.21,1814.89 2887.21,1852.72 2945.6,1911.11 v1@3030.57,1911.11
  Layer 11 - SIG w5: v1@3030.57,1911.11 2945.6,1911.11 2905.13,1870.64 2905.13,1787.54 2946.64,1746.03 2981.26,1746.03 3173.55,1553.74 3173.55,1368.63 3144.7,1339.78 v2(3144.7,1311.77)
  Layer 14 - SIG w4.5: v1@3027.33,1912.09 2887.61,1912.09 2830.17,1854.64 2830.17,1713.8 2891.97,1652 3148.39,1652 3168.84,1631.55 3495.65,1631.55 3518.53,1654.43 3749.12,1654.43 3936.28,1467.27 3936.28,1349.44 3912.09,1325.25 v2(3912.09,1308.43)
  other v1: 3032.03,1912.57
B_TX_OUT7: U26.A10 U27.A7 U28.A7 U29.A7 U30.A7 | length 4309.3
  Top Layer w6: v2(1450.85,1400.56) 1450.85,1397.53 1458.89,1389.49 U29.A7@1458.89,1348.8 ; v2(2216.95,1379.04) 2226.28,1369.71 U28.A7@2226.28,1352.14 ; v1@2810.93,1822.96 2829.94,1803.95 3032.75,1803.95 3079.04,1850.24 U26.A10@3079.04,1865.25 ; v2(3110.63,1399.23) 3118.67,1391.16 U27.A7@3118.67,1350.47 ; v2(3110.63,1399.23) v2@3110.63,1402.23 ; v2(3872.85,1376.82) 3886.06,1363.6 U30.A7@3886.06,1347.14 U30.A7@3885.83,1347.37
  Layer 3 - SIG w4.5: v2(1450.85,1400.56) 1450.85,1436.3 1538.91,1524.36 1618.38,1524.36 1638.38,1504.36 1981.3,1504.36 2023.33,1546.4 2162.34,1546.4 2206.5,1590.56 2206.5,1610.83 2219.32,1623.66 2252.11,1623.66 2467.56,1839.1 2794.78,1839.1 v1(2810.68,1823.21) ; v2@3110.63,1402.23 3163.62,1402.23 3210.39,1449 3821,1449 3872.85,1397.15 v2(3872.85,1376.82)
  Layer 5 - SIG w5: v2(2216.95,1379.04) 2217.75,1379.84 2217.75,1394.54 2222.48,1399.28 2222.48,1441.25 2282.48,1501.25 2282.48,1528.13 2577.56,1823.21 v1(2810.68,1823.21)
  Layer 11 - SIG w5: v1(2810.68,1823.21) 2810.68,1743.99 2879.1,1675.57 2930.22,1675.57 2987.5,1618.29 2987.5,1567.17 3110.63,1444.04 v2@3110.63,1402.23
B_TX_OUT8: U26.B10 U27.B7 U28.B7 U29.B7 U30.B7 | length 6632.4
  Top Layer w6: v2@1458.66,1308.54 1458.66,1322.98 U29.B7@1458.89,1323.21 ; v2@2226.05,1311.87 2226.05,1326.31 U28.B7@2226.28,1326.55 ; v1@3063.53,1912.26 U26.B10@3079.04,1896.75 ; v2@3118.44,1311.77 3118.44,1324.64 U27.B7@3118.67,1324.88 ; v2@3885.59,1306.63 3885.83,1306.87 3885.83,1321.31 U30.B7@3886.06,1321.55
  Layer 3 - SIG w4.5: v2(1458.42,1310.1) 1458.42,1379.86 1474.3,1395.73 1474.3,1425.7 1524.16,1475.57 2006.84,1475.57 2043.82,1512.54 2158.52,1512.54 2169.18,1523.2 2210.71,1523.2 2222.72,1535.21 2222.72,1535.67 2233.45,1546.4 2233.45,1561.45 2480.15,1808.15 2789.85,1808.15 2805.64,1792.35 2818.59,1792.35 2843.53,1817.29 2843.53,1910.97 2907.67,1975.11 3053.91,1975.11 3063.37,1965.65 v1(3063.37,1912.26)
  Layer 5 - SIG w5: v2(2225.81,1313.43) 2225.81,1363.62 2242.48,1380.29 2242.48,1432.96 2338.56,1529.04 2365.31,1529.04 2590.95,1754.69 2590.95,1771.05 2623.12,1803.21 2818.96,1803.21 2839.65,1823.91 2839.65,1861.74 2953.03,1975.11 3057.78,1975.11 3063.37,1969.52 v1(3063.37,1912.26)
  Layer 11 - SIG w5: v1(3063.37,1912.26) 3063.37,1940.89 3062.92,1941.34 3062.92,1966.11 3053.16,1975.86 3009.68,1975.86 2894.64,1975.86 2848.56,1929.78 2848.56,1870.64 2838,1860.08 2838,1758.84 2896.43,1700.41 2940.64,1700.41 3012.1,1628.95 3012.1,1584.75 3029.5,1567.34 3029.5,1567.17 3039.17,1557.5 3043.83,1557.5 3053.5,1547.83 3053.5,1544.82 3130.63,1467.69 3130.63,1393.95 3118.2,1381.52 v2(3118.2,1311.77)
  Layer 14 - SIG w4.5: v1(3063.37,1912.26) 3063.37,1969.52 3057.78,1975.11 3006.15,1975.11 2978.53,2002.73 2742.1,2002.73 2718.95,1979.59 2718.95,1895.43 2691.68,1868.15 2691.68,1763.8 2836.05,1619.43 2836.05,1603.5 2849.05,1590.5 3103.62,1590.5 3136.62,1557.5 3314.55,1557.5 3326.49,1545.56 3517.31,1545.56 3559.63,1587.88 3718.78,1587.88 3888.35,1418.31 3888.35,1348.22 3885.59,1345.47 v2(3885.59,1308.43)
B_TX_OUT9: U26.A1 U27.K6 U28.K6 U29.K6 U30.K6 | length 10160.4
  Top Layer w6: U29.K6@1433.3,1118.49 v2(1433.3,1132.7) ; U28.K6@2200.69,1121.82 v2(2200.69,1136.03) ; U27.K6@3093.08,1120.15 v2(3093.08,1134.37) ; U26.A1@3362.5,1865.25 3391.34,1865.25 3421.74,1895.65 v1(3421.74,1945.32) ; U30.K6@3860.47,1116.82 v2(3860.47,1131.03)
  Layer 3 - SIG w4.5: v2(1433.3,1132.7) 1433.3,1072.99 1449,1057.28 1449,990.4 1552.91,886.49 1905.79,886.49 2041.81,750.47 2330.42,750.47 2392.95,813 2510.35,813 2554.35,857 2635,857 2684.55,906.55 2684.55,1384.23 2729.66,1429.33 3137.39,1429.33 3188.55,1480.5 3282.45,1480.5 3497.35,1695.4 3497.35,1869.71 v1(3421.74,1945.32)
  Layer 5 - SIG w5: v2@2201,1137 2201,1088 2216.4,1072.6 2216.4,968.25 2258.22,926.43 2527.76,926.43 2755.15,1153.82 2755.15,1182.48 2936.28,1363.6 2936.28,1371.27 2945.36,1380.35 2953.02,1380.35 2999.38,1426.7 3408.88,1426.7 3496,1513.82 3496,1871.06 v1(3421.74,1945.32)
  Layer 11 - SIG w5: v2@3092.68,1134.77 3092.68,1056.89 3110.64,1038.92 3110.64,941.72 3130.67,921.69 3451.4,921.69 3573.46,1043.75 3573.46,1239.5 3593.57,1259.62 3593.57,1388.58 3571.46,1410.69 3571.46,1728.54 3452.07,1847.93 3452.07,1914.99 v1(3421.74,1945.32)
  Layer 14 - SIG w4.5: v1(3421.74,1945.32) 3421.74,1972.53 3435.85,1986.65 3473.74,1986.65 3514.54,2027.44 3572.95,2027.44 3607.89,1992.5 4168.44,1992.5 4532,1628.94 4532,1303.1 4532.23,1302.87 4532.23,1191.6 4187.12,846.49 3913.44,846.49 3878.03,881.9 3878.03,1047 3860.47,1064.56 v2(3860.47,1131.03)
B_TX_OUT10: U26.B1 U27.K7 U28.K7 U29.K7 U30.K7 | length 8449.8
  Top Layer w6: U29.K7@1458.89,1118.49 v2@1458.89,1129.5 ; U28.K7@2226.28,1121.82 v2@2226.28,1132.84 ; U27.K7@3118.67,1120.15 v2@3118.67,1131.17 ; U26.B1@3362.5,1896.75 v1@3384.44,1896.75 ; U30.K7@3886.06,1116.82 v2@3886.06,1127.84
  Layer 3 - SIG w4.5: v2(1458.89,1132.7) 1458.89,1076.19 1471.97,1063.11 1471.97,1043.21 1565.57,949.61 1936.49,949.61 1999.61,886.49 2481.58,886.49 2617,1021.91 2617,1420.4 2677.1,1480.5 3085.54,1480.5 3158.28,1553.23 3249.81,1553.23 3433,1736.43 3433,1848.27 3384.55,1896.72 v1(3384.55,1896.86)
  Layer 5 - SIG w5: v2(2226.28,1136.03) 2226.28,1116.04 2233.53,1108.79 2233.53,1059.61 2261.39,1031.74 2261.39,1031.61 2310.87,982.13 2485.04,982.13 2685,1182.1 2685,1196.13 2725.82,1236.94 2735.25,1236.94 2769.32,1271.01 2769.32,1300.72 2982.42,1513.82 3349.54,1513.82 3427.12,1591.4 3427.12,1837.85 3407.12,1857.86 3407.12,1874.15 3384.55,1896.72 v1(3384.55,1896.86)
  Layer 11 - SIG w5: v2(3118.67,1134.37) 3118.67,1070.27 3205.19,983.75 3291.03,983.75 3456.72,1149.44 3456.72,1174.33 3504,1221.61 3504,1714.11 3419.03,1799.08 3419.03,1819.13 3407.12,1831.03 3407.12,1874.15 3384.55,1896.72 v1(3384.55,1896.86)
  Layer 14 - SIG w4.5: v1(3384.55,1896.86) 3401.9,1896.86 3486.64,1896.86 3511.94,1922.16 3566.24,1922.16 3586.58,1942.5 4131.07,1942.5 4341.95,1731.62 4341.95,1197.77 4116.88,972.7 3950.51,972.7 3928.19,995.02 3928.19,1025.41 3886.06,1067.54 v2(3886.06,1131.03) ; v2@3885.66,1131.03 v2@3885.66,1131.44
B_TX_OUT11: U26.C1 U27.L7 U28.L7 U29.L7 U30.L7 | length 9018.4
  Top Layer w6: U29.L7@1458.89,1092.9 1458.89,1030.49 1469,1020.38 v2(1469,1017.89) ; U28.L7@2227.01,1095.24 2227.01,1042.92 v2(2241.39,1028.54) ; U27.L7@3119.4,1093.57 3119.4,1041.25 v2(3133.78,1026.87) ; U26.C1@3362.5,1928.24 3362.76,1927.98 3382.38,1927.98 3388.52,1921.84 v1(3390.15,1921.84) ; U30.L7@3886.79,1090.24 3886.79,1037.92 v2(3901.17,1023.54)
  Layer 3 - SIG w4.5: v2(1469,1017.89) 1568.34,918.56 1927.51,918.56 1993.25,852.82 2501.82,852.82 2651.81,1002.81 2651.81,1404.81 2702.57,1455.57 3118.82,1455.57 3179.35,1516.1 3268.1,1516.1 3465,1713 3465,1846.98 v1(3390.15,1921.84)
  Layer 5 - SIG w5: v2@2238.93,1025.92 2241.39,1023.46 2241.39,1017.04 2243.34,1015.08 2243.34,987.17 2274.9,955.61 2512.86,955.61 2723.39,1166.15 2723.39,1191.39 2793.22,1261.22 2793.22,1268.45 3001.77,1477 3399.44,1477 3463.65,1541.21 3463.65,1848.34 v1(3390.15,1921.84)
  Layer 11 - SIG w5: v2(3133.78,1026.87) 3133.78,970.07 3148.85,955 3304.72,955 3459.22,1109.5 3530.82,1109.5 3549.98,1128.66 3549.98,1219.13 3549.47,1219.63 3549.47,1381.52 3531.35,1399.65 3531.35,1606.27 3531.65,1606.57 3531.65,1734.79 3427.12,1839.32 3427.12,1884.86 v1(3390.15,1921.84)
  Layer 14 - SIG w4.5: v1(3390.15,1921.84) 3468,1921.84 3506.04,1959.87 3506.04,1991.36 3520.05,2005.38 3548.15,2005.38 3586.03,1967.5 4150.44,1967.5 4438.36,1679.58 4438.36,1161.26 4222.97,945.87 3937.82,945.87 3901.17,982.52 v2(3901.17,1023.54) ; v2@3900.77,1023.54 v2@3900.77,1023.94
B_TX_OUT12: U26.A2 U27.K8 U28.K8 U29.K8 U30.K8 | length 7082.3
  Top Layer w6: U29.K8@1484.48,1118.49 v2@1484.48,1129.5 ; U28.K8@2251.87,1121.82 v2@2251.87,1132.84 ; U27.K8@3144.26,1120.15 v2@3144.26,1131.17 ; U26.A2@3331.01,1865.25 v1@3346.52,1849.74 ; U30.K8@3911.65,1116.82 v2@3911.65,1127.84
  Layer 3 - SIG w4.5: v2(1484.48,1132.7) 1484.48,1101.84 1517.27,1069.05 1517.45,1069.05 1523.92,1062.58 1545.23,1062.58 1570.81,1037 1986.9,1037 2041.32,982.58 2391.82,982.58 2492.09,1082.85 2492.09,1429.33 2603.75,1541 2960.45,1541 3010.58,1591.13 3054,1591.13 3110.87,1648 3207.98,1648 3326.49,1766.51 3326.49,1829.55 v1(3346.68,1849.74)
  Layer 5 - SIG w5: v2@2253,1137 2253,1134.91 2252,1133.91 2252,1124.54 2316.26,1060.28 2358.58,1060.28 2470.75,1172.44 2524.01,1172.44 2640.94,1289.37 2640.94,1329.74 2704.22,1393.03 2739.12,1393.03 2970.42,1624.33 3293.29,1624.33 3329.25,1660.29 3329.25,1832.31 v1(3346.68,1849.74)
  Layer 11 - SIG w5: v2(3144.26,1134.37) 3144.26,1111.65 3180.31,1075.61 3246.83,1075.61 3328.08,1156.86 3328.08,1183.11 3363.25,1218.28 3389.95,1218.28 3401.31,1229.64 3402.41,1229.64 3412.08,1239.3 3412.08,1292.77 3412.08,1313.9 3409.5,1316.48 3409.5,1670.68 3313.25,1766.93 3313.25,1816.31 v1(3346.68,1849.74)
  Layer 14 - SIG w4.5: v1(3346.68,1849.74) 3354.08,1842.33 3354.22,1842.33 3397.56,1799 3572.95,1799 3641.44,1867.5 4028.13,1867.5 4162.98,1732.64 4162.98,1155.98 4060.33,1053.33 3993.69,1053.33 3967.58,1079.43 3944.42,1079.43 3911.65,1112.2 v2(3911.65,1131.03)
  other v2: 2251.87,1136.03
B_TX_OUT13: U26.B2 U27.L8 U28.L8 U29.L8 U30.L8 | length 7967.9
  Top Layer w6: v2(1484.27,1073.94) 1484.38,1074.04 U29.L8@1484.38,1092.42 ; U29.L8@1484.48,1092.9 U29.L8@1485.21,1092.17 ; v2(2251.66,1077.27) 2251.77,1077.38 U28.L8@2251.77,1095.76 ; U28.L8@2251.87,1096.23 U28.L8@2252.6,1095.5 ; v2(3144.06,1075.61) 3144.16,1075.71 U27.L8@3144.16,1094.09 ; v1@3315.5,1880.66 U26.B2@3331.01,1896.17 ; U26.B2@3331.01,1895.6 U26.B2@3331.01,1896.17 ; U26.B2@3331.01,1896.75 U26.B2@3331.01,1896.17 ; v2(3911.44,1072.27) 3911.55,1072.38 U30.L8@3911.55,1090.76
  Layer 3 - SIG w4.5: v2(1484.27,1073.94) 1509.17,1049.05 1509.17,1034.3 1560.88,982.58 1948.1,982.58 2006.92,923.76 2439.89,923.76 2558.12,1041.99 2558.12,1268.85 2560.44,1271.17 2560.44,1284.83 2558.12,1287.15 2558.12,1405.45 2653.16,1500.5 3055.91,1500.5 3135.91,1580.5 3230.75,1580.5 3395.58,1745.33 3395.58,1840.33 3387.12,1848.79 3387.12,1865.86 3363.25,1889.74 3326.91,1889.74 3318.24,1881.08 v1@3317.62,1881.08
  Layer 5 - SIG w5: v2(2251.66,1077.27) 2253.77,1075.17 2253.77,1067.65 2307.49,1013.93 2461.74,1013.93 2643.55,1195.75 2643.55,1207.16 2740.7,1304.3 2740.7,1316.14 2982.06,1557.5 3333.5,1557.5 3387.12,1611.12 3387.12,1865.86 3363.25,1889.74 3326.91,1889.74 3318.24,1881.08 v1@3317.62,1881.08
  Layer 11 - SIG w5: v2(3144.06,1075.61) 3204.61,1015.05 3282.32,1015.05 3422.6,1155.33 3422.6,1172.6 3470.71,1220.71 3470.71,1700.41 3387.12,1783.99 3387.12,1865.86 3363.25,1889.74 3326.91,1889.74 3318.24,1881.08 v1@3317.62,1881.08
  Layer 14 - SIG w4.5: v1(3315.5,1880.5) 3324.73,1889.74 3363.39,1889.74 3376.27,1876.86 3455.64,1876.86 3491.04,1841.45 3541.15,1841.45 3617.2,1917.5 4112.31,1917.5 4309,1720.81 4309,1218.09 4092.23,1001.32 3982.4,1001.32 v2(3911.44,1072.27)
B_TX_OUT14: U26.C2 U27.K9 U28.K9 U29.K9 U30.K9 | length 6895.5
  Top Layer w6: U26.C2@3331.01,1928.24 v1@3346.52,1912.73
  Layer 3 - SIG w4.5: v2(1510.07,1129.5) 1545.23,1164.66 1633.18,1164.66 1695.26,1102.58 2015.42,1102.58 2044.06,1073.94 2121.16,1073.94 2143.25,1051.85 2161.86,1051.85 2179.06,1069.05 2214.73,1069.05 2225.78,1058 2341.75,1058 2417.85,1134.1 2417.85,1441.86 2567.11,1591.13 2909.43,1591.13 3037.54,1719.23 3182.81,1719.23 3252.14,1788.57 3252.14,1885.51 3252.64,1886 3252.64,1903.11 3261.65,1912.12 3278.26,1912.12 3299.06,1932.92 3326.49,1932.92 v1(3346.68,1912.73)
  Layer 5 - SIG w5: v2(2277.46,1132.84) 2304.47,1159.85 2304.47,1194.17 2332.48,1222.18 2396.96,1222.18 2436,1261.22 2485.36,1261.22 2561.1,1336.97 2570.59,1336.97 2591.32,1357.69 2591.32,1371.49 2775.23,1555.4 2840,1555.4 2897.24,1612.64 2897.24,1634.38 2954.82,1691.95 3166.86,1691.95 3252.64,1777.73 3252.64,1903.11 3261.65,1912.12 3278.26,1912.12 3299.06,1932.92 3326.49,1932.92 v1(3346.68,1912.73)
  Layer 11 - SIG w5: v2@3169.45,1131.57 3200.38,1131.57 3229.59,1160.79 3247.96,1160.79 3252.64,1165.47 3252.64,1239.64 3338.39,1325.39 3338.39,1638.3 3221.15,1755.55 3221.15,1903.11 3230.15,1912.12 3278.26,1912.12 3299.06,1932.92 3326.49,1932.92 v1(3346.68,1912.73)
  Layer 14 - SIG w4.5: v1(3346.68,1912.73) 3326.49,1932.92 3299.06,1932.92 3278.26,1912.12 3261.65,1912.12 3252.64,1903.11 3252.64,1831.46 3325.1,1759 3611.56,1759 3675.55,1823 3850.57,1823 4087,1586.57 4087,1176.9 4035.52,1125.41 3958.76,1125.41 3955.93,1128.24 v2@3936.84,1128.24
  other v2: 3937.24,1127.84 3169.85,1131.17
B_TX_OUT15: U26.A3 U27.L9 U28.L9 U29.L9 U30.L9 | length 7494
  Top Layer w6: U29.L9@1510.07,1092.9 1510.07,1061.04 1528.53,1042.58 v2(1529.17,1042.58) ; U28.L9@2277.46,1096.23 2277.46,1055.54 2296,1037 v2(2316,1037) ; U27.L9@3169.85,1094.56 3191.37,1073.05 v2(3191.37,1053.33) ; U26.A3@3299.51,1865.25 v1@3315.02,1849.74 ; U30.L9@3937.24,1091.23 3956.3,1072.17 3956.3,1058.84 v2(3958.06,1057.08)
  Layer 3 - SIG w4.5: v2(1529.17,1042.58) 1560.05,1011.69 1961.01,1011.69 2016.47,956.24 2418.66,956.24 2523.85,1061.44 2523.85,1420.86 2623.49,1520.5 2991.71,1520.5 3028.72,1557.5 3063.59,1557.5 3124.03,1617.93 3223.33,1617.93 3367.12,1761.73 3367.12,1857.58 3354.96,1869.74 3338.39,1869.74 3318.39,1849.74 v1(3315.18,1849.74)
  Layer 5 - SIG w5: v2@2314,1033 2316,1035 v2(2316,1037) 2387.79,1037 2489.85,1139.06 2531.94,1139.06 2660.94,1268.06 2660.94,1313.94 2685,1338 2712.99,1338 2748.02,1373.03 2750.06,1373.03 2968.17,1591.13 3310.09,1591.13 3355.87,1636.91 3355.87,1828.75 3367.12,1840 3367.12,1857.58 3354.96,1869.74 3338.39,1869.74 3318.39,1849.74 v1(3315.18,1849.74)
  Layer 11 - SIG w5: v2(3191.37,1053.33) 3268.93,1053.33 3443,1227.4 3443,1688.2 3367.12,1764.08 3367.12,1857.58 3354.96,1869.74 3338.39,1869.74 3318.39,1849.74 v1(3315.18,1849.74)
  Layer 14 - SIG w4.5: v1(3315.18,1849.74) 3318.39,1849.74 3338.39,1869.74 3355.1,1869.74 3367.98,1856.86 3401.21,1856.86 3439.07,1819 3559.45,1819 3632.95,1892.5 4097.13,1892.5 4276.05,1713.57 4276.05,1227.05 4077.52,1028.52 3986.62,1028.52 v2(3958.06,1057.08)
B_TX_OUT16: J18.1 U26.B3 U27.K10 U28.K10 U29.K10 U30.K10 | length 6741
  Top Layer w6: v2(1533,1101.1) 1533,1102.73 1534.93,1104.66 1534.93,1117.76 U29.K10@1535.66,1118.49 ; v2(2300.39,1104.43) 2300.39,1106.06 2302.32,1107.99 2302.32,1121.09 U28.K10@2303.05,1121.82 ; v2(3192.78,1102.77) 3192.78,1104.39 3194.71,1106.32 3194.71,1119.42 U27.K10@3195.44,1120.15 ; U26.B3@3299.51,1896.75 v1@3315.02,1912.26 ; v2(3960.17,1099.43) 3960.17,1101.06 3962.1,1102.99 3962.1,1116.09 U30.K10@3962.83,1116.82
  Layer 3 - SIG w4.5: v2(1533,1101.1) 1549.73,1117.83 1624.23,1117.83 1673.02,1069.05 1996.93,1069.05 2054.28,1011.69 2375.84,1011.69 2452.34,1088.19 2452.34,1431.76 2586.12,1565.54 2931.96,1565.54 3053.42,1687 3194.31,1687 3290.74,1783.43 3290.74,1883.18 3315.02,1907.47 v1(3315.02,1912.42)
  Layer 5 - SIG w5: v2(2300.39,1104.43) 2330.36,1104.43 2443.24,1217.31 2508.39,1217.31 2591.32,1300.23 2591.32,1322.82 2796.63,1528.13 2841.02,1528.13 2974.86,1661.97 3256.26,1661.97 3295.18,1700.89 3295.18,1858.02 3297.62,1860.47 3297.62,1890.07 3315.02,1907.47 v1(3315.02,1912.42)
  Layer 11 - SIG w5: v2(3192.78,1102.77) 3239.07,1102.77 3295.18,1158.88 3295.18,1237.5 3370.71,1313.03 3370.71,1656.29 3252.64,1774.36 3252.64,1819.13 3283.39,1849.88 3283.39,1880.62 3299.51,1896.75 ; 3299.43,1896.83 v1(3315.02,1912.42)
  Layer 14 - SIG w4.5: v1(3315.02,1912.42) 3295.18,1892.57 3295.18,1841.45 3357.64,1779 3591.56,1779 3655.05,1842.5 3939.53,1842.5 J18.1@4118,1664.03 4118,1157.53 4059.9,1099.43 v2(3960.17,1099.43)
BOOT_MODE0: R105.2 S1.1 U17.R21 | length 1173.7
  Top Layer w4: 2069.49,4119.32 2069.49,4080.82 U17.R21@2079.14,4071.17
  Top Layer w6.8: 2069.49,4119.32 2069.49,4189.6 2249,4369.12 2785.3,4369.12 2818.8,4402.62 2917.7,4402.62 R105.2@2937.4,4422.32 ; R105.2@2944.29,4434.82 3030.49,4434.82 S1.1@3030.99,4434.32
BOOT_MODE1: R106.2 S1.2 U17.R20 | length 1158.2
  Top Layer w4: U17.R20@2079.14,4051.48 2091.05,4063.39 2091.05,4077.51 2084.49,4084.07 2084.49,4119.32
  Top Layer w6.8: 2084.49,4119.32 2084.49,4176 2250.3,4341.82 2913.7,4341.82 R106.2@2932.6,4360.72 ; R106.2@2944.29,4373.1 2955.5,4384.32 S1.2@3011.95,4384.32 ; S1.2@3021.99,4384.32 S1.2@3011.95,4384.32 ; S1.2@3030.99,4384.32 S1.2@3011.95,4384.32
BOOT_MODE2: R117.2 S2.5 U17.T19 | length 1196.4
  Top Layer w6: v1(2834,3688.32) 2836.16,3688.32 2837.96,3690.12 2916.6,3690.12 2943.31,3663.42 R117.2@2944.29,3663.42 2945.27,3663.42 2987.17,3705.32 S2.5@3028.99,3705.32
  Top Layer w6.8: v2@2079.33,4031.8 U17.T19@2098.83,4031.8
  Layer 3 - SIG w5: v2(2080.09,4032.04) 2143.06,4095 2348.76,4095 2461.7,3982.05 2461.7,3974.71 2748.09,3688.32 v1(2834,3688.32)
BOOT_MODE3: R110.2 S1.6 U17.V21 | length 997
  Top Layer w4: U17.V21@2138.2,4071.17 2138.2,4106.71 2150.8,4119.32
  Top Layer w6.8: 2150.8,4119.32 2173.8,4142.32 2797.2,4142.32 2841.3,4098.22 2918.6,4098.22 2928.6,4108.22 2928.6,4112.32 2931.61,4115.32 R110.2@2935.7,4115.32 ; R110.2@2944.29,4127.02 2945.27,4127.02 2991.61,4173.36 3020.03,4173.36 S1.6@3030.99,4184.32 ; R110.2@2950.2,4127.02 R110.2@2951.18,4127.02 ; S1.6@3011.95,4184.32 S1.6@3021.99,4184.32
BOOT_MODE4: R109.2 S1.5 U17.U21 | length 992.2
  Top Layer w4: U17.U21@2118.51,4071.17 2120.01,4072.66 2120.01,4082.4 2128.3,4090.69 2128.3,4121.22
  Top Layer w6.8: 2129.82,4123.55 2129.82,4129.33 2160.1,4159.62 2920,4159.62 R109.2@2936.3,4175.92 ; R109.2@2944.29,4188.92 2945.27,4188.92 2990.67,4234.32 S1.5@3030.99,4234.32 ; R109.2@2947.9,4188.92 R109.2@2948.88,4188.92
BOOT_MODE5: R107.2 S1.3 U17.T20 | length 1102.7
  Top Layer w4: U17.T20@2098.83,4051.48 2098.83,4105.99 2099.49,4106.65 2099.49,4119.32
  Top Layer w6.8: 2099.49,4119.32 2099.49,4159.4 2218.3,4278.22 2910.9,4278.22 2928.6,4295.92 2928.6,4296.69 2929.37,4297.46 R107.2@2930.15,4297.46 ; R107.2@2944.29,4311.39 2945.27,4311.39 2968.2,4334.32 S1.3@3011.95,4334.32 ; S1.3@3021.99,4334.32 S1.3@3011.95,4334.32 ; S1.3@3030.99,4334.32 S1.3@3011.95,4334.32
BOOT_MODE6: R119.2 S2.7 U17.T18 | length 1177
  Top Layer w6: v1(2817.6,3575.22) 2817.67,3575.29 2911.44,3575.29 2943.31,3543.42 R119.2@2944.29,3543.42 2945.27,3543.42 2995.21,3593.36 3006.99,3593.36 S2.7@3018.95,3605.32
  Top Layer w6.8: U17.T18@2098.83,4012.11 2098.83,4011.24 v2@2117.12,3992.95
  Layer 3 - SIG w5: v2(2117.99,3990.95) 2117.99,4000.49 2130.86,4013.35 2174.22,4013.35 2191.18,4030.32 2249.87,4030.32 2704.97,3575.22 v1(2817.6,3575.22)
BOOT_MODE7: R118.2 S2.6 U17.U19 | length 1160.1
  Top Layer w4: U17.U19@2118.75,4031.56 U17.U19@2118.51,4031.8 v2(2151.49,4031.78)
  Top Layer w6: v1(2820.43,3637.39) 2825.75,3637.39 2826.42,3636.72 2909.71,3636.72 2943.31,3603.12 R118.2@2944.29,3603.12 2945.27,3603.12 2960.98,3618.82 2960.98,3619.8 2996.49,3655.32 S2.6@3018.95,3655.32
  Top Layer w6.8: S2.6@3018.95,3655.32 S2.6@3028.99,3655.32
  Layer 3 - SIG w5: v2@2151.49,4033.35 2171.38,4053.25 2356.6,4053.25 2409.97,3999.87 2409.97,3944.64 2445.23,3909.37 2488.95,3909.37 2760.94,3637.39 v1(2820.43,3637.39)
BOOT_MODE8: R120.2 S2.8 U17.U18 | length 1170.8
  Top Layer w4: U17.U18@2118.51,4012.11 U17.U18@2119.01,4012.11 ; v2@2138.21,3992.92 v2(2138.7,3992.92)
  Top Layer w6: U17.U18@2119.01,4012.11 v2@2138.21,3992.92 ; v1(2819.7,3514.02) 2820.5,3513.22 2917.31,3513.22 2944.02,3486.52 R120.2@2945,3486.52 2945.98,3486.52 3002.82,3543.36 3017.03,3543.36 S2.8@3028.99,3555.32
  Layer 3 - SIG w5: v2(2138.7,3992.92) 2163.3,3992.92 2163.74,3993.35 2182.5,3993.35 2199.07,4009.92 2224.02,4009.92 2719.92,3514.02 v1(2819.7,3514.02)
BOOT_MODE9: R108.2 S1.4 U17.U20 | length 1055.4
  Top Layer w4: 2114.8,4119.32 2114.8,4087.09 2106.61,4078.89 2106.61,4064.81 2106.83,4064.59 2106.83,4063.17 U17.U20@2118.51,4051.48
  Top Layer w6.8: 2114.8,4119.32 2114.8,4140.62 2195.9,4221.71 2913.2,4221.71 R108.2@2928.7,4237.22 ; R108.2@2943.5,4249.42 2944.48,4249.42 2959.19,4264.12 2959.19,4256.3 2987.2,4284.32 3011.95,4284.32 S1.4@3021.99,4284.32
BOOT_MODE10: R111.2 S1.7 U17.V20 | length 997.1
  Top Layer w4: U17.V20@2138.2,4051.48 2146.88,4060.17 ; 2146.88,4060.2 2150.1,4063.42 2150.1,4089.93 2179.49,4119.32
  Top Layer w6.8: 2179.49,4119.32 2746.1,4119.32 2831.5,4033.92 2913.2,4033.92 R111.2@2929.7,4050.42 ; R111.2@2944.29,4065.02 R111.2@2945.27,4065.02 ; R111.2@2945.58,4065.02 R111.2@2945.27,4065.02 ; S1.7@3017.95,4134.32 S1.7@3021.99,4134.32 ; S1.7@3030.99,4134.32 3020.03,4123.36 3003.61,4123.36 R111.2@2945.27,4065.02
BOOT_MODE11: R112.2 S1.8 U17.W20 | length 1049.4
  Top Layer w4: U17.W20@2157.88,4051.48 2157.88,4086.71 2173.89,4102.72
  Top Layer w6.8: 2177.28,4102.72 2712.5,4102.72 2842.9,3972.32 2916,3972.32 R112.2@2935.6,3991.92 ; R112.2@2944.29,4005.52 2997,4005.52 3030.99,4039.5 S1.8@3030.99,4084.32 3020.95,4084.32 S1.8@3009.99,4073.36
BOOT_MODE12: R113.2 S2.1 U17.Y20 | length 967.5
  Top Layer w4: U17.Y20@2177.57,4051.48 2164.99,4064.06 2164.99,4078.98 2173.63,4087.62 2282.9,4087.62
  Top Layer w6.8: 2282.9,4087.62 2653.6,4087.62 2790.3,3950.92 2900.5,3950.92 R113.2@2930.5,3920.92 ; R113.2@2944.29,3909.82 3024.49,3909.82 S2.1@3028.99,3905.32 S2.1@3018.95,3905.32
BOOT_MODE13: R115.2 S2.3 U17.Y19 | length 951.5
  Top Layer w4: U17.Y19@2177.57,4031.8 2179,4031.8 2190.91,4019.89 2203.6,4019.89 2213.73,4030.02 2282.49,4030.02
  Top Layer w6.8: 2282.49,4030.02 2525.7,4030.02 2739.1,3816.62 2915.1,3816.62 R115.2@2933.2,3798.52 ; R115.2@2946,3786.72 2946.98,3786.72 R115.2@2961.69,3801.42 ; R115.2@2961.69,3801.14 3024.81,3801.14 S2.3@3028.99,3805.32
BOOT_MODE14: R116.2 S2.4 U17.Y18 | length 973.5
  Top Layer w4: U17.Y18@2177.57,4012.11 2282.49,4012.11
  Top Layer w6: R116.2@2936.9,3732.53 R116.2@2945.21,3724.22
  Top Layer w6.8: 2282.49,4012.11 2514.21,4012.11 2769.7,3756.62 2913.9,3756.62 R116.2@2930.6,3739.92 ; R116.2@2945.7,3724.72 2946.68,3724.72 2966.32,3744.36 3018.03,3744.36 S2.4@3028.99,3755.32
BOOT_MODE15: R114.2 S2.2 U17.AA19 | length 905.2
  Top Layer w4: U17.AA19@2197.25,4031.8 2210.47,4045.02 2282.94,4045.02
  Top Layer w6.8: 2282.94,4045.02 2536.7,4045.02 2703.7,3878.02 2913.9,3878.02 R114.2@2932.5,3859.42 ; R114.2@2944.29,3848.32 2951.29,3855.32 S2.2@3028.99,3855.32
CAP_VDDS0: C129.1 U17.D12 | length 67
  Top Layer w10: v2@1842.28,3894.21 1842.38,3894.1 1862.51,3894.1 U17.D12@1862.61,3894
  Bottom Layer w10: C129.1@1817.43,3928.12 1821.36,3928.12 1842.32,3907.16 1842.32,3894.24 v2@1842.28,3894.21
  other v2: 1841.08,3895.81
CAP_VDDS1: C130.1 U17.N5 | length 60.7
  Top Layer w10: v2(2022.52,3756.04) 2022.69,3756.21 U17.N5@2039.77,3756.21
  Layer 8 - HV PWR w10: v2(2022.52,3756.04) v2@2022.8,3756.32
  Bottom Layer w10: v2(2022.52,3756.04) 2029.66,3748.91 2029.66,3723.41 C130.1@2034.9,3718.16
CAP_VDDS2: C131.1 U17.U9 | length 193.4
  Top Layer w10: U17.U9@2118.51,3834.95 2119.26,3835.69 v2@2119.26,3852.29
  Layer 3 - SIG w10: v2@2119.26,3852.29 v2(2119.91,3852.29) 2209.14,3852.29 v1(2244.11,3817.32)
  Bottom Layer w10: v1(2244.11,3817.32) C131.1@2280.49,3817.32
CAP_VDDS3: C132.1 U17.R16 | length 428.8
  Top Layer w6.8: v2(2213.2,3982.92) 2213.3,3982.82 2275.68,3982.82 C132.1@2275.78,3982.72
  Top Layer w10: U17.R16@2079.14,3972.74 2079.22,3972.66 v2(2079.22,3953.2)
  Layer 3 - SIG w8: v2(2079.22,3953.2) 2078.25,3952.22 2059.22,3952.22 2037.11,3930.11 2037.11,3890.99 2051.1,3877 2108,3877 2135,3904 2186,3904 2194,3912 ; 2193.5,3912.5 2213.2,3932.2 v2(2213.2,3982.92)
CAP_VDDS4: C133.1 U17.N18 | length 263
  Top Layer w10: U17.N18@2039.77,4012.11 2040.12,4011.77 v2(2057.5,4011.77)
  Bottom Layer w10: v2(2057.5,4011.77) 2056.35,4012.91 2051.01,4012.91 2042.69,4021.24 2042.69,4048.51 2042.99,4048.82 2042.99,4064.08 2057.49,4078.58 2057.49,4100.32 2071.99,4114.82 2122.61,4114.82 2127.11,4119.32 2159.74,4151.95 2163.68,4151.95 2170.49,4158.76 C133.1@2170.49,4162.69
CAP_VDDS5: C134.1 U17.M18 | length 210.6
  Top Layer w10: U17.M18@2020.49,4012.11 v2(2020.49,4030.32)
  Bottom Layer w10: v2(2020.49,4030.32) 2020.87,4030.7 2020.87,4038.58 2029.1,4046.82 2029.1,4100.02 2068.2,4139.12 2110.1,4139.12 C134.1@2125.6,4154.62
CAP_VDDS_MCU: C135.1 U17.D9 | length 115.7
  Top Layer w10: v2(1862.49,3818.32) 1862.49,3834.83 U17.D9@1862.61,3834.95
  Layer 8 - HV PWR w10: v2(1773.11,3840.32) 1821.49,3840.32 1843.49,3818.32 v2(1862.49,3818.32)
  Bottom Layer w10: v2(1773.11,3840.32) C135.1@1773.49,3839.94
CLK0_IC_N: R148.1 U24.5 | length 73.6
  Bottom Layer w6.1: U24.5@2205.26,2501.63 2221.56,2517.93 2246.69,2517.93 R148.1@2264.69,2499.93
CLK0_IC_P: R147.1 U24.4 | length 74.2
  Bottom Layer w6.1: U24.4@2205.26,2551.63 2222.96,2533.93 2246.69,2533.93 R147.1@2264.69,2551.93
CLK0_R_N: C224.2 R148.2 R149.1 | length 156.7
  Bottom Layer w6.1: R148.2@2305.04,2499.93 2323.04,2517.93 2346.96,2517.93 R149.1@2370.26,2494.63 2393.76,2518.13 2408.76,2518.13 C224.2@2427.26,2499.63
CLK0_R_P: C222.2 R147.2 R149.2 | length 156.9
  Bottom Layer w6.1: R147.2@2305.04,2551.93 2323.04,2533.93 2346.57,2533.93 R149.2@2370.26,2557.63 2393.76,2534.13 2408.76,2534.13 C222.2@2427.26,2552.63
CLKIN0_N: C224.1 U23.15 | length 92.6
  Top Layer w6.1: v1(2513.85,2512.13) 2523.08,2521.37 2550.56,2521.37 U23.15@2552.4,2519.52
  Bottom Layer w6.1: C224.1@2474.51,2499.63 2493.01,2518.13 2507.85,2518.13 v1(2513.85,2512.13)
CLKIN0_P: C222.1 U23.14 | length 90.4
  Top Layer w6.1: v1(2513.85,2540.73) 2517.22,2537.37 2550.56,2537.37 U23.14@2552.4,2539.21
  Bottom Layer w6.1: C222.1@2474.51,2552.63 2493.01,2534.13 2507.25,2534.13 v1(2513.85,2540.73)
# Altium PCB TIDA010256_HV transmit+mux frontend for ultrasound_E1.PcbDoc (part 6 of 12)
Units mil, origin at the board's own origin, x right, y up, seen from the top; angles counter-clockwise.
Board outline 6192.49 x 6712.23 mil, 16 copper layers (Top Layer, Layer 2 - GND, Layer 3 - SIG, Layer 4 - GND, Layer 5 - SIG, Layer 6 - SIG, Layer 7 - GND, Layer 8 - HV PWR, Layer 9 - LV PWR, Layer 10 - GND, Layer 11 - SIG, Layer 12 - SIG, Layer 13 - GND, Layer 14 - SIG, Layer 15 - GND, Bottom Layer), stack 95.905 mil thick; 806 components, 539 nets, 3343 pads, 1848 vias.

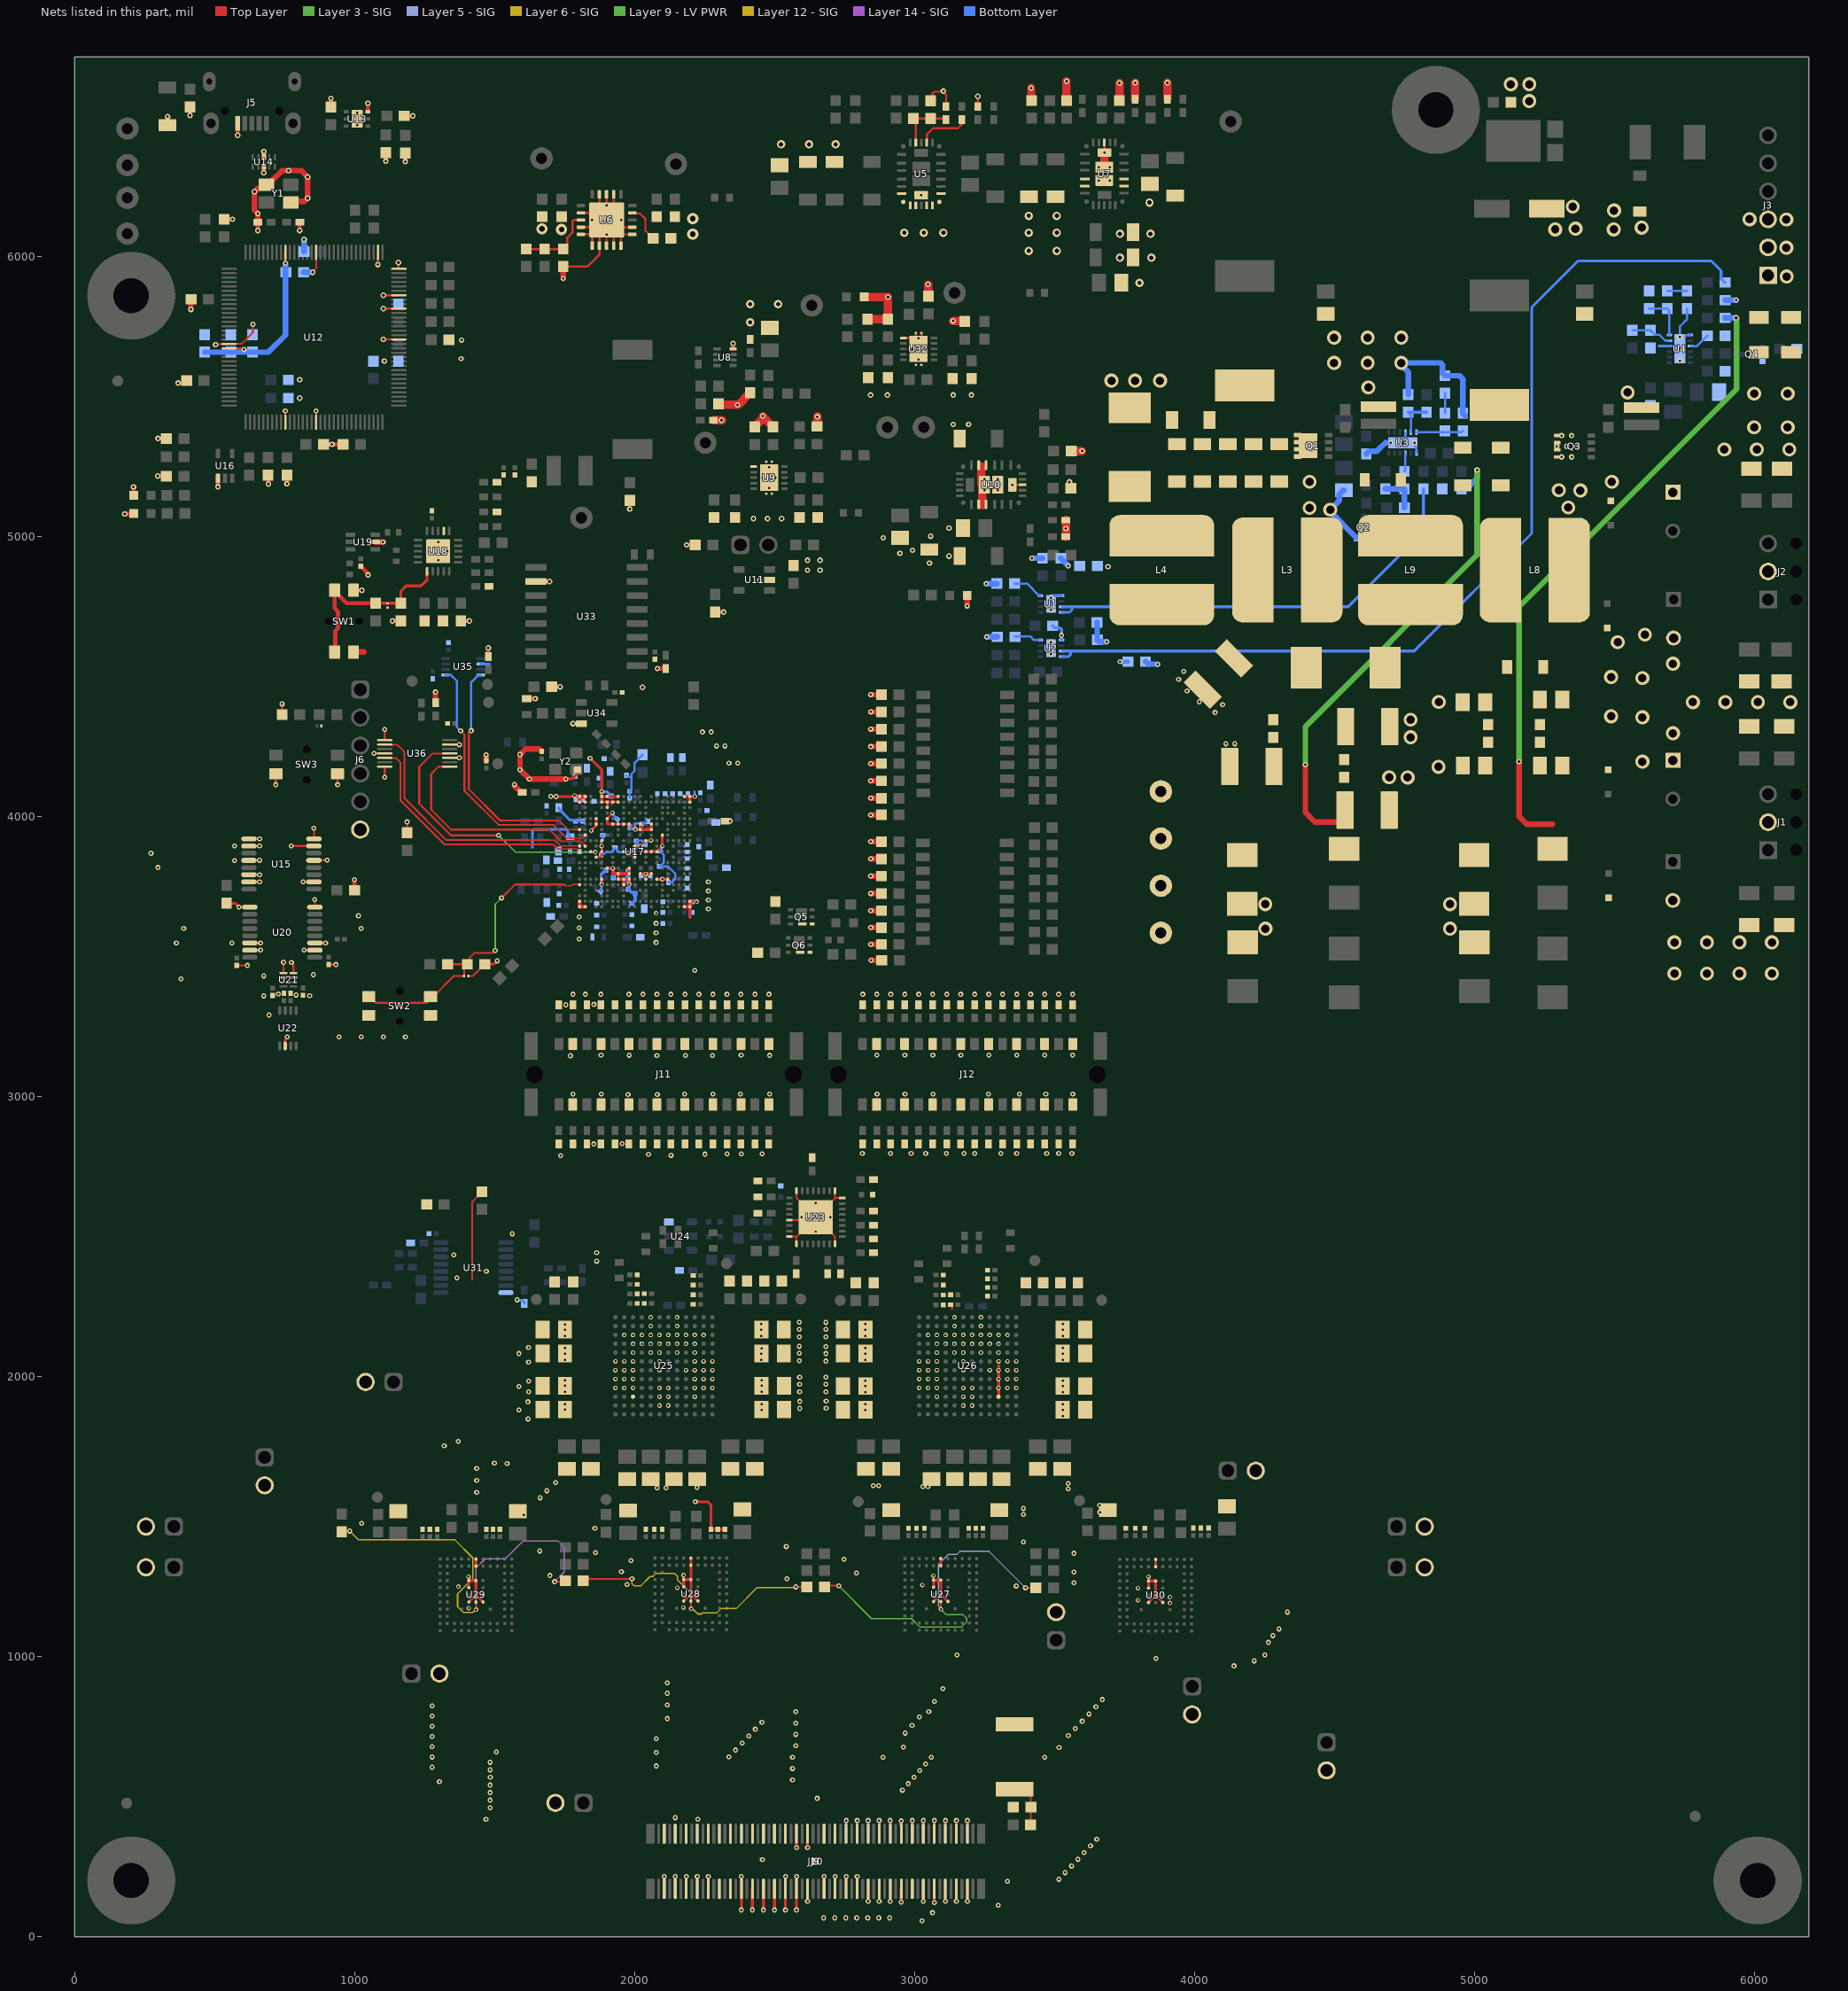
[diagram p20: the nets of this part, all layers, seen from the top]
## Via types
v1: diameter 18, hole 8, Top Layer to Bottom Layer, tented both sides, 930 vias
v2: diameter 16, hole 8, Top Layer to Bottom Layer, tented both sides, 340 vias
v3: diameter 16, hole 8, Top Layer to Bottom Layer, tented bottom, 226 vias
v4: diameter 20, hole 10, Top Layer to Bottom Layer, tented both sides, 129 vias
v5: diameter 50, hole 30, Top Layer to Bottom Layer, tented both sides, 96 vias
v6: diameter 30, hole 15, Top Layer to Bottom Layer, tented both sides, 47 vias
v7: diameter 19.68, hole 7.87, Top Layer to Bottom Layer, 40 vias
v8: diameter 19.68, hole 7.87, Top Layer to Bottom Layer, tented both sides, 19 vias
v9: diameter 18, hole 8, Top Layer to Bottom Layer, tented bottom, 13 vias
v10: diameter 40, hole 20, Top Layer to Bottom Layer, tented both sides, 4 vias
v11: diameter 40, hole 20, Top Layer to Bottom Layer, 3 vias
v12: diameter 18, hole 8, Top Layer to Bottom Layer, 1 vias

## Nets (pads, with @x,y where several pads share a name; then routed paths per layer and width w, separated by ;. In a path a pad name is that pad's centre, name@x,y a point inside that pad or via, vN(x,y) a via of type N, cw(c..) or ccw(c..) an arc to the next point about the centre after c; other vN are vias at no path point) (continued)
GND: C3.2 C4.2 C7.2 C12.2 C13.2 C14.2 C40.1 C41.2 C42.2 C43.2 C44.2 C45.1 C46.1 C47.1 C48.2 C52.2 C53.2 C54.2 C56.1 C57.2 C58.2 C59.2 C60.2 C62.2 C63.2 C64.2 C65.2 C66.2 C67.2 C68.2 C69.2 C70.2 C71.2 C72.2 C74.2 C75.2 C76.2 C77.2 C78.2 C79.2 C80.2 C81.2 C82.2 C83.2 C85.2 C86.2 C87.2 C88.2 C89.2 C90.2 C91.2 C92.2 C93.2 C94.2 C95.2 C96.2 C97.2 C98.2 C99.2 C100.1 C101.2 C102.2 C103.2 C104.2 C105.2 C106.2 C107.2 C108.2 C109.2 C110.2 C111.2 C112.2 C113.2 C114.2 C115.2 C116.1 C117.2 C118.2 C119.2 C120.2 C121.2 C122.2 C123.2 C124.2 C125.2 C126.2 C127.2 C128.2 C129.2 C130.2 C131.2 C132.2 C133.2 C134.2 C135.2 C136.1 C137.2 C138.2 C139.2 C140.2 C141.2 C142.2 C143.2 C144.2 C145.2 C146.2 C147.2 C148.2 C149.2 C150.2 C151.2 C152.2 C153.2 C154.2 C155.2 C156.2 C157.2 C158.2 C159.2 C160.2 C161.2 C162.2 C163.2 C164.2 C165.2 C166.2 C167.2 C168.2 C169.2 C170.2 C171.2 C172.2 C173.2 C174.2 C175.2 C176.2 C177.2 C178.2 C179.2 C180.2 C181.2 C182.2 C183.2 C184.2 C185.2 C186.2 C187.2 C188.2 C189.2 C190.2 C191.2 C192.2 C193.2 C194.2 C195.2 C196.2 C197.2 C198.2 C199.2 C200.2 C201.2 C202.2 C203.2 C204.2 C205.2 C206.2 C207.2 C208.2 C209.2 C210.2 C211.2 C212.2 C213.2 C214.2 C215.2 C216.2 C217.2 C218.2 C219.2 C220.2 C221.2 C223.2 C225.2 C226.2 C227.2 C228.2 C229.2 C230.2 C231.2 C232.2 C233.2 C234.2 C235.2 C236.2 C239.2 C240.2 C241.2 C242.2 C243.2 C244.2 C245.2 C246.2 C247.2 C248.2 C249.2 C250.2 C251.2 C252.2 C253.2 C254.2 C255.2 C256.2 C257.2 C258.2 C259.2 C260.2 C261.2 C262.2 C263.2 C264.2 C265.2 C266.2 C267.2 C270.2 C271.2 C272.2 C273.2 C274.2 C275.2 C276.2 C277.2 C278.2 C279.2 C280.2 C281.2 C282.2 C283.2 C284.2 C285.2 C286.2 C287.2 C288.2 C289.2 C290.2 C291.2 C292.2 C293.2 C294.2 C295.2 C296.2 C297.2 C298.2 C299.2 C300.2 C301.2 C302.2 C303.2 C304.2 C305.2 C306.2 C307.2 C308.2 C309.2 C310.2 C311.2 C312.2 C313.2 C314.2 C379.2 C380.2 C381.2 C382.2 C383.2 C384.2 C385.2 C386.2 C387.2 C388.2 C389.2 C390.2 C391.2 C392.2 C393.2 C394.2 C459.2 C460.2 C461.2 C462.2 C463.2 C464.2 C465.2 C466.2 C467.2 C471.2 C472.2 C473.2 C474.2 C475.2 C476.2 C477.2 C478.2 C479.2 C480.2 C481.2 C482.2 C483.2 C484.2 C485.2 C486.2 C487.2 C488.2 C489.2 C490.2 C491.2 C492.2 C493.2 C494.2 C495.2 C496.2 C497.2 C498.2 C499.2 C500.2 C501.2 C502.2 C503.1 C504.1 D25.2 D26.1 D27.1 D28.1 D29.1 D32.1 D33.1 D34.1 FB1.2 FB2.2 J3.1 J3.2 J3.3 J5.5 J6.6 J7.2 J8.2 J9.5 J9.6 J9.9 J9.10 J9.13 J9.14 J9.17 J9.18 J9.21 J9.22 J9.25 J9.26 J9.29 J9.30 J9.33 J9.34 J9.37 J9.38 J9.41 J9.42 J9.45 J9.46 J9.49 J9.50 J9.53 J9.54 J9.57 J9.58 J9.63 J9.64 J9.67 J9.68 J9.71 J9.72 J9.75 J9.76 J9.79 J9.80 J9.83 J9.84 J9.87 J9.88 J9.91 J9.92 J9.95 J9.96 J9.99 J9.100 J9.103 J9.104 J9.107 J9.108 J9.111 J9.112 J9.115 J9.116 J10.5 J10.6 J10.9 J10.10 J10.13 J10.14 J10.17 J10.18 J10.21 J10.22 J10.25 J10.26 J10.29 J10.30 J10.33 J10.34 J10.37 J10.38 J10.41 J10.42 J10.45 J10.46 J10.49 J10.50 J10.53 J10.54 J10.57 J10.58 J10.63 J10.64 J10.67 J10.68 J10.71 J10.72 J10.75 J10.76 J10.79 J10.80 J10.83 J10.84 J10.87 J10.88 J10.91 J10.92 J10.95 J10.96 J10.99 J10.100 J10.103 J10.104 J10.107 J10.108 J10.111 J10.112 J10.115 J10.116 J11.A2 J11.A4 J11.A6 J11.A8 J11.A10 J11.A12 J11.A14 J11.A16 J11.B2 J11.B4 J11.B6 J11.B8 J11.B10 J11.B12 J11.B14 J11.B16 J12.A2 J12.A4 J12.A6 J12.A8 J12.A10 J12.A12 J12.A14 J12.A16 J12.B2 J12.B4 J12.B6 J12.B8 J12.B10 J12.B12 J12.B14 J12.B16 J13.2 J14.2 J15.2 J16.2 J17.2 J18.2 J19.2 J20.2 J21.2 J22.2 Q5.4 Q5.7 Q6.4 Q6.7 R35.2 R37.1 R40.1 R42.1 R49.1 R50.1 R51.1 R53.1 R55.1 R57.1 R65.1 R66.1 R70.1 R72.1 R75.2 R78.1 R81.2 R88.1 R105.1 R106.1 R107.1 R108.1 R109.1 R110.1 R111.1 R112.1 R113.1 R114.1 R115.1 R116.1 R117.1 R118.1 R119.1 R120.1 R123.1 R124.1 R132.1 R133.1 R135.1 R137.1 R139.1 R140.1 R142.1 R146.1 R150.2 R151.2 R154.1 R155.1 R156.1 R157.1 R158.1 R159.1 R167.1 R428.1 R429.1 R441.1 R442.1 R444.1 R448.1 R451.1 R452.1 R458.1 R459.1 R460.1 R461.1 R462.1 R463.1 R464.1 R465.1 R466.1 R467.1 R468.1 R469.1 R470.1 R471.1 R472.1 R473.1 R474.1 R475.1 R476.1 R477.1 R478.1 R479.1 R480.1 R481.1 R482.1 R483.1 R484.1 R485.1 R515.2 R516.2 SW1.1 SW1.3 SW2.1 SW2.3 SW3.1 SW3.3 TP11.1 TP13.1 TP14.1 TP15.1 U1.5 U1.9 U2.5 U2.9 U5.7 U5.8 U5.9 U5.10 U5.12 U5.13 U5.14 U5.15 U5.30 U6.2 U6.4 U6.5 U6.6 U6.7 U6.8 U6.9 U6.10 U6.11 U6.12 U6.17 U6.18 U6.19 U6.21 U7.5 U7.6 U7.16 U7.17 U7.24 U7.27 U7.28 U7.29 U8.4 U9.6 U9.11 U10.5 U10.6 U10.16 U10.17 U10.24 U10.27 U10.28 U10.29 U11.2 U12.10 U12.17 U12.48 U12.55 U12.58 U12.64 U12.66 U12.80 U12.114 U13.3 U13.7@1008.7,6490.32 U14.3@675.72,6319.84 U14.8@675.72,6352.72 U15.2 U15.5 U15.7 U15.8 U15.9 U15.10 U15.12 U15.14 U15.15 U16.1 U17.A1 U17.A2 U17.A20 U17.A21 U17.AA1 U17.AA2 U17.AA20 U17.AA21 U17.B1 U17.B21 U17.D10 U17.D16 U17.D17 U17.E6 U17.E11 U17.E13 U17.E20 U17.E21 U17.F8 U17.F17 U17.F19 U17.F20 U17.F21 U17.G16 U17.G20 U17.H6 U17.H7 U17.H16 U17.H20 U17.H21 U17.J5 U17.J6 U17.J11 U17.J16 U17.K6 U17.K7 U17.K8 U17.K16 U17.L10 U17.L11 U17.L12 U17.M7 U17.M15 U17.M16 U17.N6 U17.N11 U17.N13 U17.P7 U17.P11 U17.P15 U17.P16 U17.R6 U17.R11 U17.T14 U17.U6 U17.Y1 U17.Y21 U18.12 U18.21@1298.19,4946.72 U19.2 U20.2 U20.3 U20.8 U20.9 U20.14 U20.15 U21.3 U21.4 U21.5 U21.6 U22.2 U23.1 U23.8 U23.13 U23.16 U23.17 U23.24 U23.32 U23.33 U24.3 U25.B6 U25.B7 U25.C3 U25.C6 U25.C7 U25.C10 U25.D3 U25.D6 U25.D7 U25.D10 U25.E3 U25.E10 U25.F3 U25.F4 U25.F7 U25.F10 U25.G3 U25.G7 U25.G10 U25.H3 U25.H5 U25.H7 U25.H8 U25.H10 U25.J3 U25.J4 U25.J5 U25.J6 U25.J7 U25.J8 U25.J9 U25.J10 U25.K2 U25.K3 U25.K4 U25.K5 U25.K6 U25.K7 U25.K8 U25.K9 U25.K10 U25.K11 U25.L5 U25.L8 U25.M5 U25.M8 U26.B6 U26.B7 U26.C3 U26.C6 U26.C7 U26.C10 U26.D3 U26.D6 U26.D7 U26.D10 U26.E3 U26.E10 U26.F3 U26.F4 U26.F7 U26.F10 U26.G3 U26.G7 U26.G10 U26.H3 U26.H5 U26.H7 U26.H8 U26.H10 U26.J3 U26.J4 U26.J5 U26.J6 U26.J7 U26.J8 U26.J9 U26.J10 U26.K2 U26.K3 U26.K4 U26.K5 U26.K6 U26.K7 U26.K8 U26.K9 U26.K10 U26.K11 U26.L5 U26.L8 U26.M5 U26.M8 U27.A6 U27.B6 U27.D5 U27.D6 U27.E5 U27.F6 U27.G5 U27.G7 U28.A6 U28.B6 U28.D5 U28.D6 U28.E5 U28.F6 U28.G5 U28.G7 U29.A6 U29.B6 U29.D5 U29.D6 U29.E5 U29.F6 U29.G5 U29.G7 U30.A6 U30.B6 U30.D5 U30.D6 U30.E5 U30.F6 U30.G5 U30.G7 U31.8 U32.6 U32.11 U33.10 U34.3 U35.2 U36.1 U36.4 U36.7 U36.10 U36.13 Y1.2 Y1.4 Y2.2@1795.33,4165.82 | length 16049.6
  Top Layer w6: v4(850.6,5943.04) 850.6,5945.56 862.78,5957.73 U12.80@862.78,6013.97 ; U17.J11@1961.03,3874.32 1974.94,3860.41 1980.72,3860.41 ; U23.16@2552.4,2499.84 2577.99,2499.84 ; U23.13@2552.4,2558.89 U23.33@2637.04,2558.89 ; U23.17@2577.99,2474.25 2577.99,2499.84 ; U23.8@2577.99,2663.22 2577.99,2637.63 v7(2646.89,2568.73) ; U23.24@2715.78,2474.25 2715.78,2499.84 v7(2646.89,2568.73) ; U23.1@2715.78,2663.22 2715.78,2637.63 ; U23.32@2741.37,2637.63 2715.78,2637.63 ; 2577.99,2499.84 U23.33@2637.04,2558.89 ; U23.33@2637.04,2558.89 v7(2646.89,2568.73) ; v7(2646.89,2568.73) 2715.78,2637.63
  Top Layer w6.5: v4(503.54,5683.95) 505.89,5686.29 U12.114@545,5686.29 ; U12.114@551.75,5687.19 596.44,5687.19 636.88,5727.63 v4(636.88,5756.94) ; 1420.27,2345.37 1420.27,2624.23 1455,2658.96 R515.2@1455,2659.94
  Top Layer w6.8: D28.1@209.3,5080.12 D28.1@210.7,5081.52 ; D29.1@210.3,5146.12 D29.1@210.7,5146.52 ; R78.1@327.4,5215.22 R78.1@328.3,5214.32 ; U16.1@509.95,5209.19 U16.1@512.01,5207.13 ; C217.2@578.9,3467.92 v1(617.09,3467.92) ; v1(587.53,3676.17) U20.9@625.72,3676.17 ; U15.15@622.46,3766.34 v1(660.65,3766.34) ; U15.14@622.46,3791.93 v1(660.65,3791.93) ; U15.12@622.46,3843.11 v1(660.65,3843.11) ; U15.10@622.46,3894.29 v1(660.65,3894.29) ; U15.9@622.46,3919.88 v1(660.65,3919.88) ; U20.15@625.72,3522.63 v1(663.91,3522.63) ; U20.14@625.72,3548.22 v1(663.91,3548.22) ; C118.2@690.56,5218.64 C118.2@691.97,5217.23 ; v1(718.57,4113.48) SW3.1@718.57,4151.67 ; C466.2@741.21,4363.32 v1(741.21,4401.51) ; U21.5@746.29,3441.04 v1(746.29,3479.23) ; U12.10@752.54,5407.67 v1(752.47,5447.82) ; v1(773.9,3894.82) 774.17,3894.55 854.48,3894.55 U15.7@854.75,3894.29 ; v1(774.4,3478.82) 774.4,3477.19 781.72,3469.88 U21.4@781.72,3441.04 ; v1(816.56,3766.34) U15.2@854.75,3766.34 ; v1(819.81,3522.63) U20.2@858,3522.63 ; U15.8@854.75,3919.88 v1(854.75,3958.07) ; v1(857.9,3703.02) 857.9,3676.27 U20.8@858,3676.17 ; U20.3@858,3548.22 v1(896.19,3548.22) ; U12.17@862.74,5407.7 v1(862.7,5447.82) ; U15.5@863.9,3843.72 v1(902.09,3843.72) ; v1(939.04,4113.48) SW3.3@939.04,4151.67 ; v1(1069.31,4224.62) U36.4@1107.5,4224.62 ; v4(1083.1,5970.02) 1083.19,5970.1 1083.19,6013.9 U12.66@1083.25,6013.97 ; v4(1102.93,5702.94) U12.48@1158.05,5702.94 ; v4(1102.93,5813.18) U12.55@1158.05,5813.18 ; v4(1102.93,5860.42) U12.58@1158.05,5860.42 ; v1(1107.5,4139.19) U36.7@1107.5,4177.38 ; U36.1@1107.5,4271.86 v1(1107.5,4310.05) ; v4(1156.3,5977.42) 1156.3,5954.97 1156.37,5954.91 U12.64@1158.05,5954.91 ; R81.2@1187.3,3942.22 v1(1187.3,3980.41) ; U36.10@1339.81,4208.85 v1(1374,4208.85) ; U36.13@1339.79,4256.12 1363.9,4256.12 1374.91,4256.11 v1@1374.95,4256.07 ; D33.1@1406.3,3430.42 1422.52,3430.42 1464.52,3472.42 C127.2@1465.5,3472.42 ; U29.D5@1407.71,1272.03 1407.77,1272.09 1407.77,1290.07 v2@1407.82,1290.13 ; U17.D10@1862.61,3854.63 1862.92,3854.32 1877.49,3854.32 1882.49,3859.32 1882.49,3874.12 U17.E11@1882.29,3874.32 v2(1882.29,3894) U17.E13@1882.29,3913.69 ; U6.8@1899.66,6037.78 v7(1899.66,6077.15) ; v7(1899.66,6129.32) U6.21@1925.25,6103.73 ; U17.F17@1902.23,3992.7 1921.2,4011.67 v2(1921.2,4012.62) ; U6.9@1925.25,6037.78 U6.21@1925.25,6103.73 ; U17.H16@1941.35,3972.74 U17.K16@1980.72,3972.74 1999.74,3953.7 v2@1999.74,3953.42 ; U6.10@1950.84,6037.78 U6.21@1950.84,6078.14 ; 1980.72,3860.41 1986.48,3860.41 U17.L11@2000.4,3874.32 ; U6.11@1991.19,6078.14 U6.21@1950.84,6078.14 ; U6.12@1991.19,6103.73 U6.21@1925.25,6103.73 ; v2@2000.02,3953.42 2000.38,3953.06 U17.M15@2020.09,3953.06 ; U17.L10@2000.4,3854.63 U17.L11@2000.4,3874.32 ; U17.M16@2019.36,3972.01 U17.M16@2020.09,3972.74 ; U17.N13@2039.77,3913.69 v2(2020.11,3894) U17.L12@2000.4,3894 U17.L11@2000.4,3874.32 ; U17.N13@2039.77,3913.69 2039.96,3913.5 2058.31,3913.5 v2@2058.49,3913.32 ; U17.R11@2079.14,3874.32 v2(2098.83,3894) ; U28.D5@2175.1,1275.36 2175.16,1275.42 2175.16,1293.4 v2@2175.21,1293.46 ; R35.2@3057.14,6554.32 3063.4,6560.58 3063.4,6581.31 3069.11,6587.02 3101.54,6587.02 3112.15,6576.41 C40.1@3112.15,6534.46 ; U27.D5@3067.49,1273.7 3067.55,1273.75 3067.55,1291.74 v2@3067.6,1291.79 ; C297.2@3128.27,2256.83 3129.05,2256.83 3133.32,2252.57 3133.32,2241.32 ; v4(3225.16,6570.56) 3225.44,6570.28 3225.44,6534.74 R37.1@3225.71,6534.46 ; U30.D5@3834.88,1270.36 3835,1270.48 v2(3835,1286) v2@3835,1288.47 ; U6.21@1925.25,6103.73 U6.21@1950.84,6078.14
  Top Layer w8: R40.1@1744.66,5962.82 1830.99,5962.82 1874.06,6005.89 U6.7@1874.06,6037.78 U6.21@1874.06,6103.73 ; U6.5@1808.12,6078.14 U6.21@1848.47,6078.14 ; U6.4@1808.12,6103.73 U6.21@1874.06,6103.73 ; U6.2@1808.12,6154.91 1874.06,6154.91 v7(1899.66,6129.32) U6.21@1874.06,6103.73 ; U6.6@1848.47,6037.78 U6.21@1848.47,6078.14 ; U6.19@1874.06,6220.85 1874.06,6187.32 1879.91,6181.48 v7(1899.66,6181.48) ; U6.18@1899.66,6220.85 v7(1899.66,6181.48) ; U6.17@1925.25,6220.85 1925.25,6187.32 1919.4,6181.48 v7(1899.66,6181.48) ; v4(2351.2,5688.22) v4@2351.41,5688.01 ; C467.2@2408.79,5508.14 2408.79,5509.12 C467.2@2412.49,5512.82 ; U32.6@2958.95,5708.57 2985.58,5708.57 U32.11@3004.22,5689.93 ; U32.11@3004.22,5726.2 U32.11@3004.22,5689.93 ; U32.11@3023.91,5726.29 3023.91,5679.04 U32.11@3014.06,5669.2 3004.22,5679.04 U32.11@3004.22,5689.93 ; v7(3348.55,5184.2) U10.24@3384.97,5184.2 ; v8(3677.37,6370.22) U7.24@3677.37,6406.64 ; U6.21@1848.47,6078.14 U6.21@1874.06,6103.73
  Top Layer w10: C115.2@542.8,3690.12 573.58,3690.12 v1(587.53,3676.17) ; U22.2@752.06,3180.82 752.41,3181.17 752.41,3204.2 759.49,3211.28 v1(759.49,3212.9) ; C216.2@907.2,3471.22 v1(933.88,3471.22) ; U29.G5@1407.71,1195.26 U29.F6@1433.3,1220.85 ; U29.E5@1407.71,1246.44 U29.D5@1407.71,1272.03 U29.D6@1433.3,1272.03 U29.F6@1433.3,1220.85 ; U29.B6@1433.3,1323.21 U29.A6@1433.3,1348.8 ; U29.G7@1458.89,1195.26 U29.F6@1433.3,1220.85 ; C127.2@1465.5,3472.42 1497.1,3472.42 v1(1508.9,3484.22) ; v1(1700.53,4071.37) 1718.63,4071.37 v1(1719.13,4070.86) 1781.55,4070.86 v2(1785.2,4074.52) 1785.97,4073.75 1800.48,4073.75 1803.06,4071.17 U17.A21@1803.55,4071.17 ; v1(1754.74,4133.32) 1756.27,4134.85 1778.29,4134.85 1795.33,4151.88 Y2.2@1795.33,4165.82 ; v1(1840.66,4207.86) 1882.47,4166.05 v2(1882.47,4088.54) ; v2(1844.64,3949.47) 1862.61,3967.43 U17.D17@1862.61,3992.43 ; v2@1882.29,4088.37 U17.E21@1882.29,4071.17 ; U17.F19@1901.98,4031.8 U17.F20@1901.98,4051.48 ; U17.F17@1902.32,3992.08 1902.32,3975.35 1903.15,3974.52 1903.15,3973.98 ; 1902.78,3973.03 1941.06,3973.03 U17.H16@1941.35,3972.74 ; U17.H20@1941.35,4051.48 U17.F20@1901.98,4051.48 ; U17.H21@1941.35,4071.17 U17.E21@1882.29,4071.17 ; U17.M7@2020.09,3795.58 2020.22,3795.45 2039.36,3795.45 v2@2039.49,3795.32 ; U17.M16@2020.09,3972.74 U17.M15@2020.09,3953.06 U17.P15@2059.46,3953.06 U17.P16@2059.46,3972.74 ; U17.N6@2039.77,3775.89 2039.63,3776.03 2039.63,3795.17 v2@2039.49,3795.32 ; U17.N11@2039.77,3874.32 U17.R11@2079.14,3874.32 ; U17.P7@2059.46,3795.58 2059.33,3795.45 2039.62,3795.45 v2@2039.49,3795.32 ; U17.R6@2079.14,3775.89 v2(2098.83,3775.89) U17.U6@2118.51,3775.89 ; v2(2098.83,3894) U17.T14@2098.83,3933.37 ; J9.115@2105.55,171.08 v1(2105.55,215.49) ; J9.111@2144.92,171.08 v1(2144.92,215.49) v1@2144.92,218.49 ; U28.G5@2175.1,1198.59 U28.F6@2200.69,1224.18 ; U28.E5@2175.1,1249.77 U28.D5@2175.1,1275.36 U28.D6@2200.69,1275.36 ; U17.Y21@2177.57,4071.17 U17.AA21@2197.25,4071.17 ; J9.107@2184.29,171.08 v1(2184.29,215.49) v1@2184.29,218.49 ; 2196.9,3638.72 2197.08,3638.89 2197.08,3677.29 U17.AA1@2197.25,3677.47 ; U17.AA2@2197.25,3697.15 2219.19,3697.15 2220.62,3695.72 v2(2221.7,3695.72) ; U17.AA20@2197.25,4051.48 U17.AA21@2197.25,4071.17 ; U28.A6@2200.69,1352.14 U28.B6@2200.69,1326.55 U28.D6@2200.69,1275.36 ; v2(2214.8,4070.82) 2214.63,4070.99 2197.43,4070.99 U17.AA21@2197.25,4071.17 ; v1(2216.95,1553.23) 2261.46,1553.23 2272.09,1542.6 C309.2@2272.09,1454.54 C308.2@2322.09,1454.54 ; J9.103@2223.66,171.08 v1(2223.66,215.49) v1@2223.66,218.49 ; U28.G7@2226.28,1198.59 U28.F6@2200.69,1224.18 ; J9.99@2263.03,171.08 v1(2263.03,215.49) ; v1(2380.85,95.73) 2381.06,95.94 2381.06,171 J9.87@2381.14,171.08 v1(2381.14,215.49) ; v1(2420.22,95.73) 2420.43,95.94 2420.43,171 J9.83@2420.51,171.08 ; v1(2459.59,95.73) 2459.8,95.94 2459.8,171 J9.79@2459.88,171.08 ; v1(2498.96,95.73) 2499.17,95.94 2499.17,171 J9.75@2499.25,171.08 ; v1(2538.33,95.73) 2538.54,95.94 2538.54,171 J9.71@2538.62,171.08 v1(2538.62,215.49) ; v1(2577.7,95.73) 2577.91,95.94 2577.91,171 J9.67@2577.99,171.08 v1(2577.99,215.49) ; v1(2577.99,317.91) J9.68@2577.99,367.93 ; v1(2617.36,126.67) J9.63@2617.36,171.08 ; v1(2617.36,317.91) J9.64@2617.36,367.93 ; J9.57@2676.41,171.08 v1(2676.41,215.49) ; J9.53@2715.78,171.08 v1(2715.78,215.49) ; J9.49@2755.15,171.08 v1(2755.15,215.49) ; J9.45@2794.52,171.08 v1(2794.52,215.49) ; v1(2833.89,126.67) J9.41@2833.89,171.08 ; v1(2873.26,126.67) J9.37@2873.26,171.08 ; v1(2912.63,126.67) J9.33@2912.63,171.08 ; J9.34@2912.63,367.93 v1(2912.63,415.34) ; J9.30@2951.92,398.37 v1(2951.92,413.69) ; v1(2952,123.67) J9.29@2952,171.08 ; J9.26@2991.37,367.93 v1(2991.37,415.34) ; v1(3030.74,126.67) J9.21@3030.74,171.08 ; J9.22@3030.74,367.93 v1(3030.74,415.34) ; U27.G5@3067.49,1196.92 U27.F6@3093.08,1222.51 ; U27.E5@3067.49,1248.11 U27.D5@3067.49,1273.7 U27.D6@3093.08,1273.7 U27.F6@3093.08,1222.51 ; v1(3070.11,122.1) J9.17@3070.11,171.08 ; J9.18@3070.11,367.93 v1(3070.11,415.34) ; U27.B6@3093.08,1324.88 U27.A6@3093.08,1350.47 ; v1(3109.48,126.67) J9.13@3109.48,171.08 ; J9.14@3109.48,367.93 v1(3109.48,415.34) ; U27.G7@3118.67,1196.92 U27.F6@3093.08,1222.51 ; v1(3148.85,126.67) J9.9@3148.85,171.08 ; J9.10@3148.85,367.93 v1(3148.85,415.34) ; v1(3188.22,126.67) J9.5@3188.22,171.08 ; J9.6@3188.22,367.93 v1(3188.22,415.34) ; 3241.27,5103.1 3241.27,5110.54 ; U26.C3@3299.51,1928.24 v3(3299.51,1959.74) v3(3299.51,1991.23) v3(3299.51,2022.73) 3299.51,2038.9 ; v4(3552.49,5194.32) 3552.49,5176.82 R65.1@3557.61,5171.7 ; U30.G5@3834.88,1193.59 U30.F6@3860.47,1219.18 ; U30.E5@3834.88,1244.77 U30.D5@3834.88,1270.36 U30.D6@3860.47,1270.36 U30.F6@3860.47,1219.18 ; U30.B6@3860.47,1321.55 U30.A6@3860.47,1347.14 ; U30.G7@3886.06,1193.59 U30.F6@3860.47,1219.18 ; U17.E21@1882.29,4071.17 U17.E20@1882.29,4051.48 U17.F20@1901.98,4051.48 ; U28.F6@2200.69,1224.18 U28.D6@2200.69,1275.36
  Top Layer w12: v2(1882.29,3757.51) U17.E6@1882.29,3775.89 ; U17.F8@1901.98,3815.26 v2(1922.49,3815.26) 1922.49,3795.58 U17.H7@1941.35,3795.58 ; U17.J5@1961.03,3756.21 U17.J6@1961.03,3775.89 ; v2(1980.72,3757.54) U17.K6@1980.72,3775.89 U17.J6@1961.03,3775.89 ; U17.K8@1980.72,3815.26 U17.K7@1980.72,3795.58 U17.H7@1941.35,3795.58 ; U17.H7@1941.35,3795.58 U17.H6@1941.35,3775.89 U17.J6@1961.03,3775.89
  Top Layer w15: v4(178.95,5080.12) D28.1@209.3,5080.12 ; D29.1@210.3,5146.12 v4(210.3,5176.46) ; v4(297.06,5215.22) R78.1@327.4,5215.22 ; v4(297.96,5349.32) C116.1@328.3,5349.32 ; C100.1@331.9,6468.09 v4(331.9,6498.43) ; v4(369.37,5547.08) C104.2@399.71,5547.08 ; v4(412.5,6502.78) R75.2@412.5,6533.12 ; v4(512.01,5176.78) U16.1@512.01,5207.13 ; C113.2@533.9,6131.81 v4(564.25,6131.81) ; v4(582.2,6431.42) 582.24,6431.46 582.24,6473.97 J5.5@582.28,6474.01 ; v4(654.48,6091.38) C119.2@654.48,6121.72 ; U14.3@675.72,6319.84 675.8,6319.76 v4(675.8,6298.12) ; U14.8@675.72,6352.72 676.09,6353.09 v4(676.09,6373.9) ; v4(691.97,5186.88) C118.2@691.97,5217.23 ; v4(758.26,5187.6) C117.2@758.26,5217.94 ; v4(803.83,6091.78) C120.2@803.83,6122.12 ; C103.2@888.57,5328.34 v4(918.92,5328.34) C105.2@958.31,5328.34 ; C97.2@915.5,6533.11 v4(915.5,6563.45) ; SW1.3@995.85,4807.25 v4(1026.2,4807.25) ; C122.2@1022.1,4894.58 1022.87,4893.81 1022.87,4891.47 1047.15,4867.19 1047.15,4863.07 v4(1048.1,4862.12) ; U13.3@1047.09,6515.91 v4(1047.09,6546.25) ; v4(1111.2,6339.48) C99.2@1111.2,6369.82 ; v4(1135.35,4698.22) C123.2@1165.69,4698.22 ; C101.2@1177.7,6501.32 v4(1208.04,6501.32) ; v4(1181.2,6337.98) C98.2@1181.2,6368.32 ; C124.2@1379.69,4698.22 v4(1410.03,4698.22) ; R139.1@1477.15,4571.19 v4(1477.15,4601.53) ; R448.1@1614.4,4420.6 v4(1644.75,4420.6) ; U33.10@1641.48,4838.82 1641.58,4838.72 1695.9,4838.72 v4(1696,4838.62) ; R444.1@1703.49,4462.82 v4(1733.83,4462.82) ; v4(1780.01,4331.41) U34.3@1810.36,4331.41 ; U17.A2@1803.55,3697.15 U17.A1@1803.55,3677.47 U17.B1@1823.24,3677.47 ; U17.A20@1803.55,4051.48 U17.A21@1803.55,4071.17 U17.B21@1823.24,4071.17 ; v4(1982.49,5097.48) C77.2@1982.49,5127.82 ; v4(2080.76,4528.17) C460.2@2111.1,4528.17 ; U17.Y1@2177.57,3677.47 U17.AA1@2197.25,3677.47 U17.AA2@2197.25,3697.15 ; v4(2185.65,4969.32) R72.1@2215.99,4969.32 ; C96.2@2287.49,4729.32 v4(2317.83,4729.32) ; v4@2351.41,5688.01 2351.41,5669.05 U8.4@2351.62,5668.84
  Top Layer w16: C114.2@999.5,3736.32 v1(999.5,3774.51)
  Top Layer w20: v4(415.54,5810.39) C102.2@415.54,5846.32 ; C119.2@654.48,6121.72 v4(654.48,6152.61) 642.53,6164.56 v4(642.53,6230.85) 654.24,6242.57 672.45,6242.57 Y1.4@685.09,6255.21 697.73,6267.85 702.65,6267.85 740.42,6305.62 v4(764.4,6305.62) 809.7,6305.62 v4(832.3,6283.02) v4(832.3,6207.22) 820.59,6195.5 774.99,6195.5 Y1.2@771.7,6192.22 ; SW1.1@995.85,4586.78 1034.04,4586.78 ; U19.2@1073.48,4979.72 1073.78,4979.42 v1(1101.8,4979.42) ; R142.1@1288.8,4405.84 v1(1288.8,4444.03) ; v1(1469.7,4219.72) 1470.1,4219.32 C137.2@1470.1,4198.61 ; v1(1570.98,4113.72) 1570.98,4108.88 1594.05,4085.82 R140.1@1597.98,4085.82 ; C128.2@1668,4232.3 1659.89,4240.42 1609.9,4240.42 v1(1590.6,4221.12) v1(1590.6,4166.72) v1(1624.1,4133.22) 1689.76,4133.22 1689.87,4133.1 1754.53,4133.1 v1(1754.74,4133.32) ; v1(1744.66,5920.67) R40.1@1744.66,5962.82 ; C132.2@2323.03,3982.72 2324.03,3983.72 v1(2341.56,3983.72) ; v1(2843.11,3543.42) R119.1@2881.3,3543.42 ; v1(2843.11,3603.12) R118.1@2881.3,3603.12 ; v1(2843.11,3663.42) R117.1@2881.3,3663.42 ; v1(2843.11,3724.72) R116.1@2881.3,3724.72 ; v1(2843.11,3786.72) R115.1@2881.3,3786.72 ; v1(2843.11,3848.32) R114.1@2881.3,3848.32 ; v1(2843.11,3909.82) R113.1@2881.3,3909.82 ; v1(2843.11,4005.52) R112.1@2881.3,4005.52 ; v1(2843.11,4065.02) R111.1@2881.3,4065.02 ; v1(2843.11,4127.02) R110.1@2881.3,4127.02 ; v1(2843.11,4188.92) R109.1@2881.3,4188.92 ; v1(2843.11,4249.42) R108.1@2881.3,4249.42 ; v1(2843.11,4311.39) R107.1@2881.3,4311.39 ; v1(2843.11,4373.1) R106.1@2881.3,4373.1 ; v1(2843.11,4434.82) R105.1@2881.3,4434.82 ; v1(2843.82,3486.52) R120.1@2882.01,3486.52 ; v1(3187.49,4751.13) D27.1@3187.49,4789.32
  Top Layer w30: R57.1@2281.11,5414.32 v4(2310.01,5414.32) v4@2312.49,5414.32 ; C76.2@2295.36,5469 C76.2@2299.06,5472.7 2302.45,5469.32 v4(2367.49,5469.32) 2369.97,5469.32 C467.2@2408.79,5508.14 ; R451.1@2428.79,5390.3 2428.79,5391.29 2457.49,5419.99 v4@2457.49,5427.59 ; v4(2457.49,5429.32) v4@2457.49,5427.59 ; U9.11@2479.85,5209.32 U9.11@2482.49,5206.68 ; C92.2@2493.79,5390.3 2490.09,5394 2490.09,5394.99 v4@2457.49,5427.59 ; R66.1@2652.49,5397.94 v4(2652.49,5426.84) v4@2652.49,5429.32 ; D26.1@2818.99,5854.32 v4(2904.06,5854.32) C70.2@2904.06,5775.69 R442.1@2831.53,5775.69 ; v4(3047.49,5899.32) 3047.49,5858.77 R49.1@3049.06,5857.19 ; v4(3137.21,5769.32) R441.1@3177.77,5769.32 ; 3237.92,5249.32 3237.92,5187.54 3241.27,5184.2 3241.27,5110.54 ; v4(3416,6600.22) 3416,6557.3 R51.1@3417.49,6555.81 ; C94.2@3539.73,4997.88 v4(3539.73,5027.88) C93.2@3539.73,5057.88 ; R55.1@3542.49,6555.81 v4(3542.49,6624.32) ; R70.1@3558.99,5304.32 v4(3597.49,5304.32) ; U7.28@3677.37,6325.93 v8(3677.37,6370.22) ; R50.1@3731.27,6555.81 v4(3731.27,6618.09) ; C71.2@3787.49,6559.92 v4(3787.49,6619.32) ; C72.2@3902.49,6560.67 v4(3902.49,6619.32)
  Bottom Layer w7: C181.2@1884.47,3866.06 1891.29,3866.06 1897.26,3872.03
  Bottom Layer w8: C181.2@1880.2,3861 1880.2,3861.79 C181.2@1884.47,3866.06 ; v2(1882.29,3894) 1881.4,3894.89 1881.4,3909.72 1886.5,3914.81 C141.2@1886.5,3933.32 ; 1897.26,3872.03 1915.44,3872.03 1929.72,3886.32 1931.29,3886.32 1935.56,3882.05 1935.56,3877.82 1941.35,3872.03 1993.22,3872.03 1997.6,3876.42 C171.2@1997.6,3877.21 1997.6,3878 2005.5,3885.89 2005.5,3908.62 v2(2020.11,3894) ; v2(1921.2,4012.62) 1922.35,4011.47 1922.35,4005.77 C139.2@1938.12,3990 ; C138.2@1971.2,4146.61 1971.2,4145.82 1975.47,4141.55 1988.47,4141.55 ; C163.2@1982,3961.51 1982,3960.72 1986.27,3956.45 1995.08,3956.45 ; C178.2@1982.01,4065.02 1982.09,4065.1 1982.09,4089.55 C177.2@1982.18,4089.63 1982.96,4089.63 1987.23,4093.9 1987.23,4097.35 1988.47,4098.59 1988.47,4141.55 ; v2@1999.74,3953.42 2000.88,3954.56 2000.88,3970.98 2004.42,3974.52 2016.59,3974.52 2019,3972.1 2019,3972.89 2023.37,3977.25 2038.22,3977.25 2042.49,3981.52 C169.2@2042.49,3982.31 ; C173.2@2005.5,3913.32 2026.27,3913.32 2037.49,3902.1 2047.56,3912.17 2057.34,3912.17 v2@2058.49,3913.32 ; C136.1@2027.8,4220.11 2027.8,4219.12 2000.1,4191.42 2000.1,4162.82 1988.47,4151.18 1988.47,4141.55 ; v2(2098.83,3894) 2098.83,3892.92 2094.54,3888.63 2094.54,3880.58 2090.27,3876.32 2103.76,3862.83 2103.76,3834.94 2095.2,3826.38 2091.76,3826.38 2087.49,3822.11 C176.2@2087.49,3821.32 2119.48,3821.32 2144.43,3796.37 2144.43,3776.26 2133.49,3765.32 2121.48,3765.32 C196.2@2120.49,3764.32
  Bottom Layer w10: U35.2@1450.48,4544.16 1482,4544.16 1482,4542.72 ; v1(1579.95,2274.14) 1581.03,2274.14 1582.93,2272.24 1599.54,2272.24 1606.35,2265.43 R428.1@1606.35,2261.49 ; 1635.17,3889.15 1635.17,3949.1 1639.79,3953.72 1755.29,3953.72 1761.15,3947.86 1761.15,3934.93 1767.96,3928.12 C129.2@1770.18,3928.12 ; C144.2@1728.49,4031.56 1728.49,4027.62 1769.04,3987.08 1789.04,3987.08 1792.3,3983.81 1792.3,3983.4 C146.2@1817.7,3983.4 ; C201.2@1878.48,3732.13 1877.92,3732.69 1877.92,3737.31 1881.91,3741.3 1881.91,3757.13 v2(1882.29,3757.51) 1882.29,3758.06 1880.22,3760.13 1880.22,3794.11 1885.49,3799.38 1890.35,3799.38 1897.49,3806.52 C161.2@1897.49,3807.31 ; v2(1882.47,4088.54) 1883.23,4087.78 1901.24,4087.78 1912.65,4076.36 1913.44,4076.36 1916.7,4073.1 C183.2@1916.7,4072.31 ; J10.5@2105.55,171.08 v1@2105.55,218.49 ; J10.9@2144.92,171.08 v1@2144.92,218.49 ; J10.13@2184.29,171.08 v1@2184.29,218.49 ; 2214.04,4088.68 2214.04,4071.58 v2(2214.8,4070.82) ; J10.17@2223.66,171.08 v1@2223.66,218.49 ; J10.72@2755.15,367.93 v1(2755.15,415.34) ; J10.76@2794.52,367.93 v1(2794.52,415.34) ; J10.80@2833.89,367.93 v1(2833.89,415.34) ; J10.84@2873.26,367.93 v1(2873.26,415.34) ; J10.88@2912.63,367.93 v1(2912.63,415.34) ; v1(2951.92,413.69) 2951.96,413.65 J10.92@2951.96,398.37 ; J10.96@2991.37,367.93 v1(2991.37,415.34) ; J10.100@3030.74,367.93 v1(3030.74,415.34) ; J10.104@3070.11,367.93 v1(3070.11,415.34) ; J10.108@3109.48,367.93 v1(3109.48,415.34) ; J10.112@3148.85,367.93 v1(3148.85,415.34) ; J10.116@3188.22,367.93 v1(3188.22,415.34) ; U1.9@3486.89,4758.47 3486.89,4788 U1.5@3524.29,4788 U1.5@3524.37,4788.08 ; R53.1@3492.4,4680.62 3499.4,4673.62 3518.44,4673.62 3524.29,4667.76 v1(3524.29,4646.32) U2.5@3524.29,4629.84
  Bottom Layer w12: C161.2@1897.49,3807.31 1897.49,3808.1 1899.76,3810.36 1900.55,3810.36 1905.44,3815.26 v2(1922.49,3815.26) 1923.49,3815.26 C165.2@1923.49,3780.3 ; v2@1975.48,3763.32 C157.2@1975.48,3779.32 C162.2@1975.48,3804.32 ; C158.2@1977.49,3739.32 1978.28,3739.32 1989.21,3728.38 1999.22,3728.38 2001.49,3726.11 C197.2@2001.49,3725.32 2001.49,3699.54 1991.27,3689.32 C164.2@1990.48,3689.32 ; C158.2@1980.34,3741.58 1980.34,3757.16 v2(1980.72,3757.54)
  Bottom Layer w15: v1(3733.8,4552.4) 3733.8,4552.7 C504.1@3761.11,4552.7
  Bottom Layer w20: C57.2@817.52,5943.04 v4(850.6,5943.04) ; C69.2@819.11,6016.6 820.09,6016.6 819.11,6017.58 v4(819.11,6059.99) ; v1(3255.8,4831.32) C7.2@3293.99,4831.32 ; v1(3256.8,4641.32) C14.2@3294.99,4641.32 ; v1(3418.3,4921.81) C13.2@3456.49,4921.81 ; C12.2@3521.49,4921.81 v1(3548.49,4894.81) ; C4.2@3650.99,4692.32 3651.49,4691.82 3651.49,4630.82 C3.2@3651.99,4630.32 3658.79,4623.52 v1(3686.1,4623.52)
  other v1: 3026.4,56.98 2674.85,67.49 2714.22,67.49 2753.59,67.49 2792.96,67.49 2832.33,67.49 2871.7,67.49 2911.07,67.49 3063.37,86.17 3298,112.58 3331.64,197.81 3514.91,205.29 3537.48,229.04 3560.05,252.78 2641.39,269.51 2456.16,275.85 3582.63,276.53 3605.2,300.28 3627.77,324.03 3650.35,347.78 1469,419 2226,419 2145.14,425.18 1483.98,460.9 1483.98,487.9 2651.81,494.24 1483.98,514.9 2956,523.18 1483.98,541.9 2976.73,546.64 1303,553.42 2563.52,559.95 1484.69,569.23 2997.45,570.09 3018.18,593.55 1483.98,595.9 2563.52,600.56 1277.06,605.28 2076.82,609.73 3038.9,617.01 1483.98,622.9 2563.52,640.47 2887.21,640.47 3059.63,640.47 3464.27,640.47 1277.06,641.89 2336.57,642.05 2076.83,658.51 1506.29,660.19 2360.14,666.8 3515.61,675.15 2960.15,677.26 1277.06,678.49 2574.82,681.76 2383.71,691.55 2076.83,707.28 1277.06,715.09 2407.29,716.3 3548.89,718.04 2574.82,722.37 2965.76,727.28 2430.86,741.05 3573.46,743.79 1277.06,751.7 2990.54,754.62 2574.82,762.97 2454.43,765.8 3598.04,769.54 2117,779.04 3016.6,784.75 1277.06,788.3 3622.61,795.28 2574.82,803.57 3050.43,803.57 3647.18,821.03 1277.06,824.33 2117,827.81 3070.11,840.18 3670,847 2117,869.41 3100.5,886.49 2117,906.62 4140.23,967.19 4212.57,985.13 3861.49,993.8 3150.92,1006.08 4250.48,1005.83 4263,1051 4278.47,1075.1 4301.04,1098.84 4331,1159 3362.5,1252.33 1972.5,1257.68 3569,1263.9 2543.94,1278 1697.44,1290.07 2791.57,1298.56 3568.69,1301.86 1952.66,1303.53 1986.75,1342.9 2747.97,1347.96 3568.69,1369.07 1859.88,1371.66 1661.09,1377.38 2541.57,1393 3388.12,1409.45 1858.05,1458.83 1024.98,1476 1603.96,1505.43 3388.12,1508.06 3661.29,1516.1 3388.12,1529.06 3660.99,1540.5 1662.55,1567.23 1435.95,1586.43 1686.55,1592.33 3547.85,1599.43 2079.96,1602.2 2111.75,1602.73 2223,1604 3029.27,1607.63 3047.37,1607.83 2852.55,1610.33 2870.65,1610.53 3548.15,1617.93 1717.54,1621.53 1435.95,1629.18 1435.95,1671.93 1544.55,1689.43 1499.15,1691.33 1320.03,1753.05 1370.22,1768.53 1619.25,1848.58 1586.59,1880.43 2589.35,1886.43 2683.75,1887.03 1619,1910 2589.35,1911.53 2683.75,1912.13 1621.25,1945.63 2588.95,1945.63 2683.35,1946.23 1586.85,1964.71 2588.95,1972.53 2683.35,1973.13 1621.25,1983.79 2588.95,1997.63 2683.35,1998.23 1620.95,2051.53 2682.95,2055.43 2587.95,2056.13 1586.85,2082.42 2682.95,2082.33 2587.95,2083.03 1620.95,2103.53 2682.95,2107.43 2587.95,2108.13 2587.55,2142.23 2682.55,2141.53 2682.55,2168.43 2587.55,2169.13 2587.55,2194.23 2682.55,2193.53 1365.2,2352.37 1470.39,2376.33 1864.3,2411.77 1354.69,2434.85 1864.3,2442.42 1562.57,2509.79 1735.75,2789.17 2129.8,2789.73 2049.41,2793.1 2250.66,2794.23 2330.48,2794.79 2380.51,2794.79 2454.71,2795.36 2813.28,2796.56 2913.9,2796.56 2987.3,2796.56 3039.33,2796.56 3112.73,2796.56 3176.41,2796.56 3214.81,2796.56 3307.17,2796.56 3364.05,2796.56 3471.47,2796.56 3514.26,2796.56 3561.41,2796.56 1854.1,2830.48 1955.16,2831.51 1976.54,3007.13 2080.87,3007.13 1779.22,3008.71 1881.11,3008.71 2178.29,3008.71 2279.22,3008.71 2377.81,3008.71 2482.07,3008.71 2865.72,3008.55 2965.47,3008.55 3065.21,3008.55 3262.97,3008.55 3373.67,3008.55 3468.22,3008.55 3564.51,3008.55 1770.73,3145.5 2079.7,3145.98 2181.58,3146.44 2277.81,3146.44 1980.17,3147.39 2481.59,3146.92 1880.17,3147.86 2380.17,3147.85 2865.15,3147.5 2964.97,3147.5 3064.8,3147.5 3164.62,3147.5 3264.45,3147.5 3364.28,3147.5 3464.1,3147.5 3563.93,3147.5 944.89,3212.92 1023.63,3212.92 1102.37,3212.92 1181.11,3212.92 694.84,3291.06 1754.78,3327.46 1854.68,3328.78 675.8,3359.25 839.3,3360.32 791.37,3362.28 1779.5,3365.31 1824.46,3365.31 1879.5,3365.31 1979.5,3365.31 2029.5,3365.31 2079.5,3365.31 2129.5,3365.31 2179.5,3365.31 2229.5,3365.31 2279.5,3365.31 2329.5,3365.31 2379.5,3365.31 2429.5,3365.31 2479.5,3365.31 2814.65,3365.31 2864.6,3365.31 2914.56,3365.31 2964.52,3365.31 3014.48,3365.31 3064.44,3365.31 3114.4,3365.31 3164.36,3365.31 3214.32,3365.31 3264.28,3365.31 3314.24,3365.31 3364.19,3365.31 3414.15,3365.31 3464.11,3365.31 3514.07,3365.31 3564.03,3365.31 728.2,3366.61 380,3420 675.8,3430.42 852.87,3434.95 2214.9,3450.28 363.3,3548.22 561.5,3548.22 2076.49,3550.32 1801.74,3562.62 2076.49,3584.32 390,3600.52 1023.63,3600.52 1801.74,3601.99 2076.49,3618.32 1013.57,3645.32 2263,3669.52 2263,3701.65 2263,3733.78 2263,3765.92 297.6,3817.52 571.58,3842.56 273,3868.42 571.02,3894.29 2337,4189.92 2367.7,4189.92 2291.7,4251.22 2322.4,4251.22 1374,4256.1 2242.2,4301.52 2272.9,4301.52 2446.1,4842.82 1380.08,5634.42 1381.9,5700.32
  other v2: 1407.6,1173.21 2174.21,1174.88 3911.15,1191.48 3797.39,1201.7 3911.15,1212.67 3797.39,1244.32 2152.14,1246.27 1370.22,1250.23 3027.33,1256.04 1407,1286 3067,1289 2175,1291 1801.74,3641.36 2076.49,3654.32 2039.49,3794.32 2058.49,3914.32 2002.74,3953.42
  other v3: 2088.75,1896.75 2120.24,1896.75 3173.53,1896.75 3205.02,1896.75 2088.75,1928.24 2120.24,1928.24 2214.73,1928.24 3079.04,1928.24 3173.53,1928.24 3205.02,1928.24 1994.26,1959.74 2088.75,1959.74 2120.24,1959.74 2214.73,1959.74 3079.04,1959.74 3173.53,1959.74 3205.02,1959.74 1994.26,1991.23 2214.73,1991.23 3079.04,1991.23 1994.26,2022.73 2088.75,2022.73 2183.24,2022.73 2214.73,2022.73 3079.04,2022.73 3173.53,2022.73 3268.02,2022.73 1994.26,2054.23 2088.75,2054.23 2214.73,2054.23 3079.04,2054.23 3173.53,2054.23 3299.51,2054.23 1994.26,2085.72 2057.25,2085.72 2088.75,2085.72 2151.74,2085.72 2214.73,2085.72 3079.04,2085.72 3142.03,2085.72 3173.53,2085.72 3236.52,2085.72 3299.51,2085.72 1994.26,2117.22 2025.76,2117.22 2057.25,2117.22 2088.75,2117.22 2120.24,2117.22 2151.74,2117.22 2183.24,2117.22 2214.73,2117.22 3079.04,2117.22 3110.54,2117.22 3142.03,2117.22 3173.53,2117.22 3205.02,2117.22 3236.52,2117.22 3268.02,2117.22 3299.51,2117.22 1962.76,2148.71 1994.26,2148.71 2025.76,2148.71 2057.25,2148.71 2088.75,2148.71 2120.24,2148.71 2151.74,2148.71 2183.24,2148.71 2214.73,2148.71 2246.23,2148.71 3047.54,2148.71 3079.04,2148.71 3110.54,2148.71 3142.03,2148.71 3173.53,2148.71 3205.02,2148.71 3236.52,2148.71 3268.02,2148.71 3299.51,2148.71 3331.01,2148.71 2057.25,2180.21 2151.74,2180.21 3142.03,2180.21 3236.52,2180.21 2057.25,2211.71 2151.74,2211.71 3142.03,2211.71 3236.52,2211.71
  other v4: 2027.9,4460.72 2617.49,4879.32 2662.49,4879.32 3052.49,4904.32 2617.49,4914.32 2662.49,4914.32 3122.49,4929.32 2947.49,4939.32 2991.86,4950.53 2887.49,4994.32 3056.86,5000.53 3122.49,5029.32 2424.1,5063.52 2474.45,5063.52 2524.8,5063.52 3137.49,5399.32 3192.49,5399.32 803.83,5493.52 2842.49,5504.32 2902.49,5504.32 3137.49,5504.32 3202.49,5504.32 803.83,5559.41 1106.15,5625.85 3102.49,6589.32
  other v5: 6113.49,5927.32 6112.49,6030.32 5287.17,6095.6 5496.19,6095.6 5359.74,6098.23 5596,6102 6112.49,6131.32 5981.49,6132.32 5497.49,6163.21 5349.88,6177.07 5194.54,6553.74 5128.99,6614.17 5194.54,6614.17
  other v6: 2412.49,5764.32 2412.49,5829.32 2512.49,5829.32 3802.7,5904.92 3732.49,5994.32 3844.9,5994.32 3407.49,6019.32 3507.49,6019.32 3732.49,6079.72 3841.7,6079.72 2962.49,6084.32 3032.49,6084.32 3102.49,6084.32 3407.49,6084.32 3507.49,6084.32 3407.49,6144.32 3507.49,6144.32 3838.3,6191.72 2522.49,6399.32 2622.49,6399.32 2717.49,6399.32
  other v7: 2646.89,2517.55 2595.7,2568.73 2698.07,2568.73 2646.89,2619.92 3486.89,4578.66 3486.89,4621.97 3486.89,4736.82 3486.89,4780.13 1298.19,4914.24 1265.71,4946.72 1330.67,4946.72 1298.19,4979.2 3249.14,5164.51 3296.39,5164.51 2479.85,5171.91 3249.14,5203.88 3296.39,5203.88 2457.21,5209.32 2502.49,5209.32 2479.85,5246.72 3014.06,5631.8 2991.43,5669.2 3036.7,5669.2 3014.06,5706.6 1847.49,6129.32 1951.82,6129.32 1008.7,6468.66 1008.7,6511.97
  other v8: 3023.63,6217.82 3657.69,6270.81 3697.06,6270.81 3657.69,6318.06 3697.06,6318.06
  other v10: 2207.49,6079.32 1739.1,6095.62 1669,6098.22 2207.49,6134.32
HV_GND: C1.2 C2.2 C5.2 C6.2 C8.1 C9.2 C10.1 C11.2 C16.2 C17.2 C18.1 C19.1 C20.2 C22.2 C23.2 C24.2 C25.2 C26.2 C28.2 C29.2 C30.2 C31.2 C32.2 C34.1 C35.1 C36.2 C37.2 C38.2 C503.2 C504.2 D9.2 D10.2 D11.1 D12.1 D14.1 D21.1 FB1.1 FB2.1 J1.2 J2.2 L3.1 L8.1 Q2.2 Q4.2 R3.1 R4.1 R5.1 R8.1 R11.1 R13.1 R17.1 R19.1 R20.1 R24.1 R26.1 R29.1 R32.1 R33.1 U3.4 U3.7 U3.13 U4.4 U4.7 U4.13 | length 1367.1
  Bottom Layer w8: v7(4742.49,5334.32) 4752.33,5344.16 U3.4@4752.33,5371.72 ; v7(4784.81,5334.32) 4784.81,5324.47 4790.94,5318.35 4790.94,5297.68 U3.7@4791.7,5296.91 ; v7(5732.49,5711.64) 5732.49,5749.32 5757.49,5774.32 C38.2@5757.49,5812.82 ; 5752.22,5714.58 5755.4,5717.77 5769.13,5717.77 U4.7@5769.89,5718.53
  Bottom Layer w10: 5657.49,5679.16 U4.4@5695.09,5679.16 5722.65,5679.16 v7(5732.49,5669.32)
  Bottom Layer w20: C504.2@3824.1,4552.7 3825.08,4552.7 3833.79,4544 3866.3,4544 v1(3867.2,4543.1) ; R11.1@4532.49,5164.32 4531.25,5164.32 4516.25,5149.32 4516.25,5127.49 v5(4483.79,5095.04) 4483.79,5088.53 4576.74,4995.58 Q2.2@4576.74,4994.51 ; C16.2@4612.49,5294.32 4612.49,5295.3 4621.19,5304 4649.79,5304 4680.1,5334.32 v7(4700.17,5334.32) ; R17.1@4680.33,5168.92 C24.2@4748.4,5168.92 4748.61,5168.71 4748.61,5102.13 R20.1@4748.83,5101.91 ; C20.2@4762.49,5505.81 4762.49,5586.2 4737.49,5611.2 v5(4737.49,5619.32) 4877.49,5619.32 4885.06,5611.74 4885.06,5582.11 C26.2@4893.76,5573.41 4945.62,5573.41 4957.33,5561.7 C25.2@4957.33,5439.91 4957.33,5438.92 C25.2@4966.03,5430.22 ; R33.1@5893.99,5843.18 v1(5933.02,5843.18)
  other v4: 3690.6,4891.5
  other v5: 5712.9,3439.19 5828.89,3439.19 5944.87,3439.19 6060.85,3439.19 5712.9,3550.32 5828.89,3550.32 5944.87,3550.32 6060.85,3550.32 4760.25,4138.91 4694.5,4139.54 4870.44,4177.23 5598.66,4195.48 4770.47,4282.32 5707.49,4296.72 4770.47,4345.31 5598.66,4353.61 5486.91,4357.55 5779.02,4407.82 5895,4407.82 6010.99,4407.82 6126.97,4407.82 4871.32,4408.67 5598.66,4494.12 5486.91,4497.55 5707.49,4544.92 5510.4,4621.92 5607.49,4649 4409.93,5101.07 5333.63,5103.08 5376.91,5163.46 5300.29,5164.35 4409.93,5194.66 5489.49,5194.66 5891.07,5309.83 6007.05,5309.83 6123.04,5309.83 5997.49,5389.32 6117.49,5389.32 5997.49,5509.32 6117.49,5509.32 5545.74,5513.44 4620.04,5531.26 3702.57,5555.81 3786.83,5555.81 3875.84,5555.81 4497.49,5619.32 4617.49,5619.32 4497.49,5709.32 4617.49,5709.32 4737.49,5709.32
  other v7: 5732.49,5626.99
  other v9: 4111.49,4259.36 4142.49,4259.36 4072.57,4371.23 4099.49,4399.32 4016.07,4409.36 3972.49,4448.48 3942.49,4488.82 3961.22,4517.7
HVA_FB: R16.2 U1.7 U1.8 | length 1604.4
  Bottom Layer w10: U1.8@3524.29,4728.95 3553.53,4728.95 3561.3,4736.72 3561.3,4748.52 ; U1.7@3527.01,4748.52 3561.3,4748.52 ; R16.2@4816.4,5168.92 4816.4,5017.22 4547.69,4748.52 3561.3,4748.52
HVB_FB: R30.2 U2.7 U2.8 | length 3511.1
  Bottom Layer w10: U2.8@3524.29,4570.79 3549.58,4570.79 3556.5,4577.72 3556.5,4590.47 ; U2.7@3529.14,4590.47 3556.5,4590.47 ; R30.2@5893.99,5906.72 5893,5906.72 5879.3,5920.42 5879.3,5948.51 5844.49,5983.32 5368.49,5983.32 5203.49,5818.32 5203.49,5010.32 4783.65,4590.47 3556.5,4590.47
I2C3_DAC_SCL: U17.B14 U35.5 | length 959.6
  Top Layer w4: 1746.02,3933.37 1757.92,3921.47 1808.49,3921.47 1817.4,3930.38 1818.13,3930.38 1821.12,3933.37 U17.B14@1823.24,3933.37
  Top Layer w6.8: v9(1378.49,4305.32) 1392,4291.8 1392,4091.52 1513.6,3969.92 1657.49,3969.92 1709.47,3969.92 1746.02,3933.37
  Bottom Layer w8: U35.5@1324.5,4504.79 1344.53,4504.79 1365.24,4484.08 1365.24,4318.57 v9(1378.49,4305.32)
I2C3_DAC_SDA: U17.A15 U35.4 | length 886
  Top Layer w4: 1755.49,3959.32 1761.75,3953.06 U17.A15@1803.55,3953.06
  Top Layer w6.8: v9(1416.49,4306.32) 1407.8,4297.63 1407.8,4096.93 1519.52,3985.22 1657.49,3985.22 1729.59,3985.22 1755.49,3959.32
  Bottom Layer w8: v9(1416.49,4306.32) 1416.49,4479.61 1441.67,4504.79 U35.4@1450.48,4504.79
LP_2: R488.2 R509.1 U29.G6 | length 1508.1
  Top Layer w6: v1(1714.24,1267.85) 1749.53,1267.85 R509.1@1753.23,1271.56
  Top Layer w6.8: R488.2@953.8,1435.24 966.94,1448.38 v1(982.54,1448.38) ; U29.G6@1433.3,1195.26 1433.61,1194.95 1433.61,1168.11 v2(1433.92,1167.8)
  Layer 6 - SIG w5: v1(982.54,1448.38) 1013.92,1417 1358.13,1417 1422.51,1352.62 1422.51,1279.41 1367.52,1224.42 1367.52,1178.68 1388.49,1157.71 1422.09,1157.71 1432.19,1167.8 v2(1433.92,1167.8)
  Layer 14 - SIG w5: v2(1433.92,1167.8) 1433.92,1316.76 1466.3,1349.13 1538.26,1349.13 1602.32,1413.19 1726.59,1413.19 1748.39,1391.38 1748.39,1302.01 v1(1714.24,1267.85)
LP_3: R502.1 R509.2 U28.G6 | length 1007
  Top Layer w6: v1(2574.82,1249.2) R502.1@2615.39,1249.2
  Top Layer w6.8: R509.2@1816.23,1271.56 1822.56,1277.9 v1(1990.68,1277.9) ; U28.G6@2200.69,1198.59 2201,1198.28 2201,1171.45 v2(2201.31,1171.13)
  Layer 6 - SIG w5: v1(1990.68,1277.9) 1990.68,1260.92 1998.15,1253.44 2022.41,1253.44 2054.88,1285.91 2064.18,1285.91 2074.91,1296.63 2143.62,1296.63 2153.11,1287.15 2153.11,1274.54 2201.31,1226.34 v2(2201.31,1171.13)
  Layer 12 - SIG w5: v2(2201.31,1171.13) 2206.89,1171.13 2225.53,1152.5 2238.37,1152.5 2241.89,1156.02 2293.31,1156.02 2309.08,1171.79 2362.42,1171.79 2437.84,1247.2 2572.82,1247.2 v1(2574.82,1249.2)
LP_4: R494.1 R502.2 U27.G6 | length 1348
  Top Layer w6: R502.2@2687.84,1253.44 v1(2728.41,1253.44)
  Top Layer w6.8: R502.2@2677.29,1239.4 2667.49,1249.2 R502.2@2678.38,1249.2 2687.84,1249.2 2687.84,1253.44 2687.84,1257.68 R502.2@2694.07,1263.9 ; U27.G6@3093.08,1196.92 3093.39,1196.61 3093.39,1169.78 v2(3093.7,1169.47) ; v1(3395.58,1246.14) R494.1@3432.78,1246.14
  Layer 3 - SIG w5: v1(2728.41,1253.44) 2845.82,1136.03 2937.65,1136.03 2937.72,1136.1 2988.02,1136.1 3017.67,1106.46 3167.9,1106.46 3185.35,1123.91 3185.35,1137.59 3172.31,1150.63 3112.58,1150.63 3111.95,1151.27 ; v2(3093.7,1169.47) 3111.9,1151.27
  Layer 5 - SIG w5: v2(3093.7,1169.47) 3093.7,1172.44 3085.14,1181.01 3085.14,1330.33 3119.46,1364.65 3150.18,1364.65 3161.3,1375.77 3265.94,1375.77 v1(3395.58,1246.14)
MAIN_UART1_CTS#: U17.C11 U36.11 | length 977.2
  Top Layer w4: U17.C11@1842.92,3874.32 U17.C11@1842.97,3874.27
  Top Layer w6.8: U36.11@1339.79,4224.62 1278.61,4224.62 1231,4177.01 1231,4045.32 1343.7,3932.62 1513.6,3932.62 v1(1513.8,3932.82) ; U17.C11@1842.97,3874.27 1856.8,3874.27 v2@1859.03,3872.03
  Layer 3 - SIG w5: v1(1513.8,3932.82) 1574.59,3872.03 v2@1859.03,3872.03
  other v2: 1860.13,3872.43
MAIN_UART1_RTS#: U17.A11 U36.5 | length 913.6
  Top Layer w4: 1709.78,3899.82 1725.88,3883.72 1794.15,3883.72 U17.A11@1803.55,3874.32
  Top Layer w6.8: U36.5@1107.5,4208.87 1147.25,4208.87 1163.2,4192.92 1163.2,4058.08 1321.46,3899.82 1657.49,3899.82 1709.78,3899.82
MAIN_UART1_RXD: U17.B12 U36.8 | length 808.3
  Top Layer w4: 1749.3,3911.32 1805.92,3911.32 U17.B12@1823.24,3894
  Top Layer w6.8: U36.8@1339.79,4177.38 1299.34,4177.38 1273.3,4151.34 1273.3,4024.23 1344.42,3953.12 1695.7,3953.12 1737.5,3911.32 1749.3,3911.32
MAIN_UART1_TXD: U17.A12 U36.2 | length 924.7
  Top Layer w4: 1695.1,3915.42 1714,3915.42 1735.42,3894 U17.A12@1803.55,3894
  Top Layer w6.8: U36.2@1125.9,4256.42 1151.5,4256.42 1178.2,4229.72 1178.2,4064.29 1327.08,3915.42 1695.1,3915.42
MCU_RESETz: C127.1 D33.2 R138.2 SW2.2 SW2.4 U17.A5 | length 1158.5
  Top Layer w4: 1749.9,3756.21 1753.62,3752.49 1774.08,3752.49 1777.79,3756.21 U17.A5@1803.55,3756.21
  Top Layer w6.8: SW2.2@1050.53,3356.38 1054.47,3356.38 1070.15,3340.69 1070.15,3339.19 1074.84,3334.5 1258.77,3334.5 SW2.4@1277.79,3353.52 ; SW2.4@1271,3356.38 1273.86,3353.52 SW2.4@1277.79,3353.52 ; R138.2@1331.9,3471.92 C127.1@1402.01,3471.92 ; v1(1502.1,3521.42) 1492.7,3512.02 1427,3512.02 1410.7,3495.72 1410.7,3480.61 C127.1@1402.51,3472.42 ; v1(1524.42,3708.68) 1572.4,3756.66 1749.9,3756.66 ; SW2.4@1277.79,3353.52 1354.69,3430.42 D33.2@1391.15,3430.42 C127.1@1391.15,3461.05 ; C127.1@1391.15,3461.05 C127.1@1402.01,3471.92 ; C127.1@1391.15,3461.05 C127.1@1402.51,3472.42 ; C127.1@1402.01,3471.92 C127.1@1402.51,3472.42
  Layer 3 - SIG w5: v1(1502.1,3521.42) 1502.1,3686.36 v1(1524.42,3708.68)
MCU_SAFETY_ERR: U17.B20
MHV_A: C258.1 C259.1 C260.1 C261.1 C289.1 C290.1 C291.1 C292.1 D18.2 D19.2 U25.F1 U25.F2 U25.F11 U25.F12 U25.G1 U25.G2 U25.G11 U25.G12 U26.F1 U26.F2 U26.F11 U26.F12 U26.G1 U26.G2 U26.G11 U26.G12
  other v1: 1751.03,2060.22 2452.34,2060.22 2824.05,2060.22 3528.69,2060.22 1751.03,2082.42 2452.34,2082.42 2824.05,2082.42 3528.69,2082.42 2452.99,2101.46 1751.03,2102.12 2824.05,2102.12 3528.69,2102.12 1751.03,2145.22 2452.52,2145.22 2824.05,2145.22 3528.69,2145.22 1751.03,2167.42 2452.52,2167.42 2824.05,2167.42 3528.69,2167.42 1751.03,2186.73 2452.52,2187.12 2824.05,2187.12 3528.69,2187.12
  other v3: 1931.27,2022.73 1962.76,2022.73 2246.23,2022.73 2277.72,2022.73 3016.05,2022.73 3047.54,2022.73 3331.01,2022.73 3362.5,2022.73 1931.27,2054.23 1962.76,2054.23 2246.23,2054.23 2277.72,2054.23 3016.05,2054.23 3047.54,2054.23 3331.01,2054.23 3362.5,2054.23
  other v5: 4252.57,3599.12 4251.97,3686.78
MHV_B: C262.1 C263.1 C264.1 C265.1 C293.1 C294.1 C295.1 C296.1 D23.2 D24.2 U25.D1 U25.D2 U25.D11 U25.D12 U25.E1 U25.E2 U25.E11 U25.E12 U26.D1 U26.D2 U26.D11 U26.D12 U26.E1 U26.E2 U26.E11 U26.E12
  other v1: 3528.69,1859.06 2452.95,1881.26 2824.05,1881.26 3528.69,1881.26 1751.03,1882.52 2452.95,1900.96 2824.05,1900.96 3528.69,1900.96 1751.03,1902.22 2824.05,1944.06 3528.69,1944.06 1751.03,1945.32 2453.12,1945.32 2824.05,1966.26 3528.69,1966.26 1751.03,1967.52 2453.12,1967.52 2824.05,1985.96 3528.69,1985.96 1751.03,1987.22 2453.12,1987.22
  other v3: 1931.27,1959.74 1962.76,1959.74 2246.23,1959.74 2277.72,1959.74 3016.05,1959.74 3047.54,1959.74 3331.01,1959.74 3362.5,1959.74 1931.27,1991.23 1962.76,1991.23 2246.23,1991.23 2277.72,1991.23 3016.05,1991.23 3047.54,1991.23 3331.01,1991.23 3362.5,1991.23
  other v5: 4911.45,3599.12 4911.45,3686.78
MR_INPUT: C123.1 D32.2 R125.2 SW1.2 SW1.4 U18.1 | length 666.8
  Top Layer w10: R125.2@1075.19,4761.22 D32.2@1118.19,4761.22 ; D32.2@1118.93,4761.22 C123.1@1165.69,4761.22 1165.69,4804.72 1183.69,4822.72 1236.69,4822.72 1258.82,4844.85 U18.1@1258.82,4874.87
  Top Layer w15: SW1.2@928.92,4586.78 931.34,4589.2 931.34,4662.66 940.52,4671.84 940.52,4731.59 928.92,4743.19 SW1.4@928.92,4803.32 ; SW1.4@928.92,4807.25 SW1.4@928.92,4803.32 ; R125.2@1075.19,4761.22 971.02,4761.22 SW1.4@928.92,4803.32
NetC7_1: C7.1 U1.4 | length 110.4
  Bottom Layer w8: C7.1@3356.99,4831.32 3401.25,4831.32 3444.57,4788 U1.4@3449.49,4788
NetC14_1: C14.1 U2.4 | length 97.9
  Bottom Layer w8: C14.1@3357.99,4641.32 3359.99,4643.32 3412.49,4643.32 3425.96,4629.84 U2.4@3449.49,4629.84
NetC15_1: C15.1 C315.1 C316.1 D13.2 L3.2
NetC15_2: C15.2 C21.2 C315.2 C316.2 C317.2 C318.2 L1.2 Q1.5 Q1.6 Q1.7 Q1.8 Q1.9
NetC18_2: C18.2 D13.1 L2.1
NetC19_2: C19.2 D15.2 L2.2 R21.1 | length 1734
  Top Layer w20: v4(4395.1,4184.72) 4395.1,4169.52 4395.1,4014.42 4429.2,3980.32 C19.2@4536.49,3980.32
  Layer 3 - SIG w20: v4(4395.1,4184.72) 4395.1,4320.52 5008.5,4933.92 v4(5008.5,5236.62)
  Bottom Layer w20: R21.1@4952.47,5168.92 4952.47,5169.91 4961.18,5178.61 4980.49,5178.61 5008.5,5206.62 v4(5008.5,5236.62)
NetC20_1: C20.1 R12.1 U3.5 | length 140
  Bottom Layer w8: C20.1@4762.49,5442.82 4772.02,5433.29 U3.5@4772.02,5371.72
  Bottom Layer w10: C20.1@4762.49,5442.82 R12.1@4827.49,5442.82
NetC21_1: C21.1 C317.1 C318.1 D14.2 L4.2
NetC22_1: C22.1 L4.1 L5.1
NetC23_1: C23.1 D18.1 L5.2
NetC24_1: C24.1 U3.9 | length 66.6
  Bottom Layer w8: C24.1@4748.4,5231.92 4752.33,5235.85 U3.9@4752.33,5296.91
NetC25_1: C25.1 R18.2 U3.6 | length 167.8
  Bottom Layer w8: U3.6@4791.7,5371.72 4952.14,5371.72 C25.1@4957.33,5376.91
NetC26_1: C26.1 R18.1 | length 70.5
  Bottom Layer w8: C26.1@4893.76,5510.42 C26.1@4893.76,5510.42 R18.1@4893.83,5439.91
NetC27_1: C27.1 D16.2 L8.2
NetC27_2: C27.2 C33.2 L6.2 Q3.5 Q3.6 Q3.7 Q3.8
  other v8: 5310.22,5283.14 5345.85,5283.14 5292.39,5321.52 5328.02,5321.52 5363.65,5321.52 5310.22,5359.91 5345.85,5359.91
NetC30_1: C30.1 D16.1 L7.1
NetC31_1: C31.1 D20.2 L7.2 R28.2 | length 2272.3
  Top Layer w20: v4(5158.3,4195.62) 5158.3,3999.82 5185.9,3972.23 5277.49,3972.23
  Layer 9 - LV PWR w20: v4(5158.3,4195.62) 5158.3,4749.12 5935,5525.82 5935,5778.05 v4(5933.27,5779.78)
  Bottom Layer w20: R28.2@5893.99,5779.78 v4(5933.27,5779.78)
NetC32_1: C32.1 R25.1 U4.5 | length 148.5
  Bottom Layer w8: R25.1@5562.49,5735.81 C32.1@5627.49,5735.81 5627.49,5734.83 5642.19,5720.13 5658.19,5720.13 5678.71,5699.61 5694.32,5699.61 U4.5@5695.09,5698.84
NetC33_1: C33.1 D21.2 L9.2
NetC34_2: C34.2 L9.1 L10.1
NetC35_2: C35.2 D23.1 L10.2
NetC36_1: C36.1 U4.9 | length 76.5
  Bottom Layer w8: U4.9@5769.89,5679.16 5792.85,5679.16 5830.01,5716.32 C36.1@5830.99,5716.32
NetC37_1: C37.1 R31.2 U4.6 | length 162.5
  Bottom Layer w8: C37.1@5622.49,5812.82 R31.2@5687.56,5812.82 5695.09,5805.29 U4.6@5695.09,5718.53
NetC38_1: C38.1 R31.1 | length 69.9
  Bottom Layer w8: R31.1@5687.56,5875.81 C38.1@5757.49,5875.81
NetC39_2: C39.2 R34.1 R40.2 U6.3 | length 277
  Top Layer w6.8: R40.2@1744.66,6025.81 R40.2@1759.36,6040.51
  Top Layer w8: R34.1@1612.49,6025.81 R40.2@1744.66,6025.81 ; R40.2@1759.36,6040.51 1759.36,6066.18 1777.49,6084.32 1777.49,6124.32 1782.49,6129.32 U6.3@1808.12,6129.32
NetC40_2: C40.2 R35.1 R38.2 U5.25 | length 207.7
  Top Layer w8: U5.25@3003.95,6405.81 3003.95,6482.67 R38.2@2995.29,6491.32 R35.1@3057.14,6491.32 3108.04,6491.32 C40.2@3112.15,6487.22
NetC54_1: C54.1 U6.14 | length 136.9
  Top Layer w6.8: U6.14@1991.19,6154.91 1993.29,6152.8 2018.43,6152.8 ; 2037.95,6133.28 2037.95,6092.36 2050.31,6080 2050.31,6079.02 2065.01,6064.32 C54.1@2065.99,6064.32
  Top Layer w8: 2018.43,6152.8 2037.95,6133.28
NetC55_1: C55.1 U5.23 | length 179.1
  Top Layer w8: U5.23@3043.32,6405.81 3043.32,6435.14 3047.49,6439.32 3064.99,6456.82 3154.28,6456.82 3168.93,6471.47 ; C55.1@3162.49,6480.78 C55.1@3168.93,6487.22
NetC56_2: C56.2 R166.1 R167.2 | length 144
  Top Layer w6.8: R167.2@3383.59,525.93 3392.73,525.93 3414.32,504.34 3414.32,462.53 R166.1@3414.32,400
NetC57_1: C57.1 C110.1 C111.1 C112.1 U12.87 U12.115 | length 664.3
  Top Layer w8: U12.115@551.75,5671.45 597.85,5671.45 602.29,5667 v1(605,5667)
  Top Layer w10: U12.87@752.54,6013.97 752.83,6013.68 752.83,5974.62 v1(753.12,5974.34)
  Bottom Layer w20: C111.1@464.9,5657.44 C112.1@635.71,5657.44 692.04,5657.44 753.12,5718.51 v1(753.12,5974.34)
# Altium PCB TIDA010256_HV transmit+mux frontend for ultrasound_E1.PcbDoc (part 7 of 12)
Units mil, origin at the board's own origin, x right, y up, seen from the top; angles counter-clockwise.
Board outline 6192.49 x 6712.23 mil, 16 copper layers (Top Layer, Layer 2 - GND, Layer 3 - SIG, Layer 4 - GND, Layer 5 - SIG, Layer 6 - SIG, Layer 7 - GND, Layer 8 - HV PWR, Layer 9 - LV PWR, Layer 10 - GND, Layer 11 - SIG, Layer 12 - SIG, Layer 13 - GND, Layer 14 - SIG, Layer 15 - GND, Bottom Layer), stack 95.905 mil thick; 806 components, 539 nets, 3343 pads, 1848 vias.

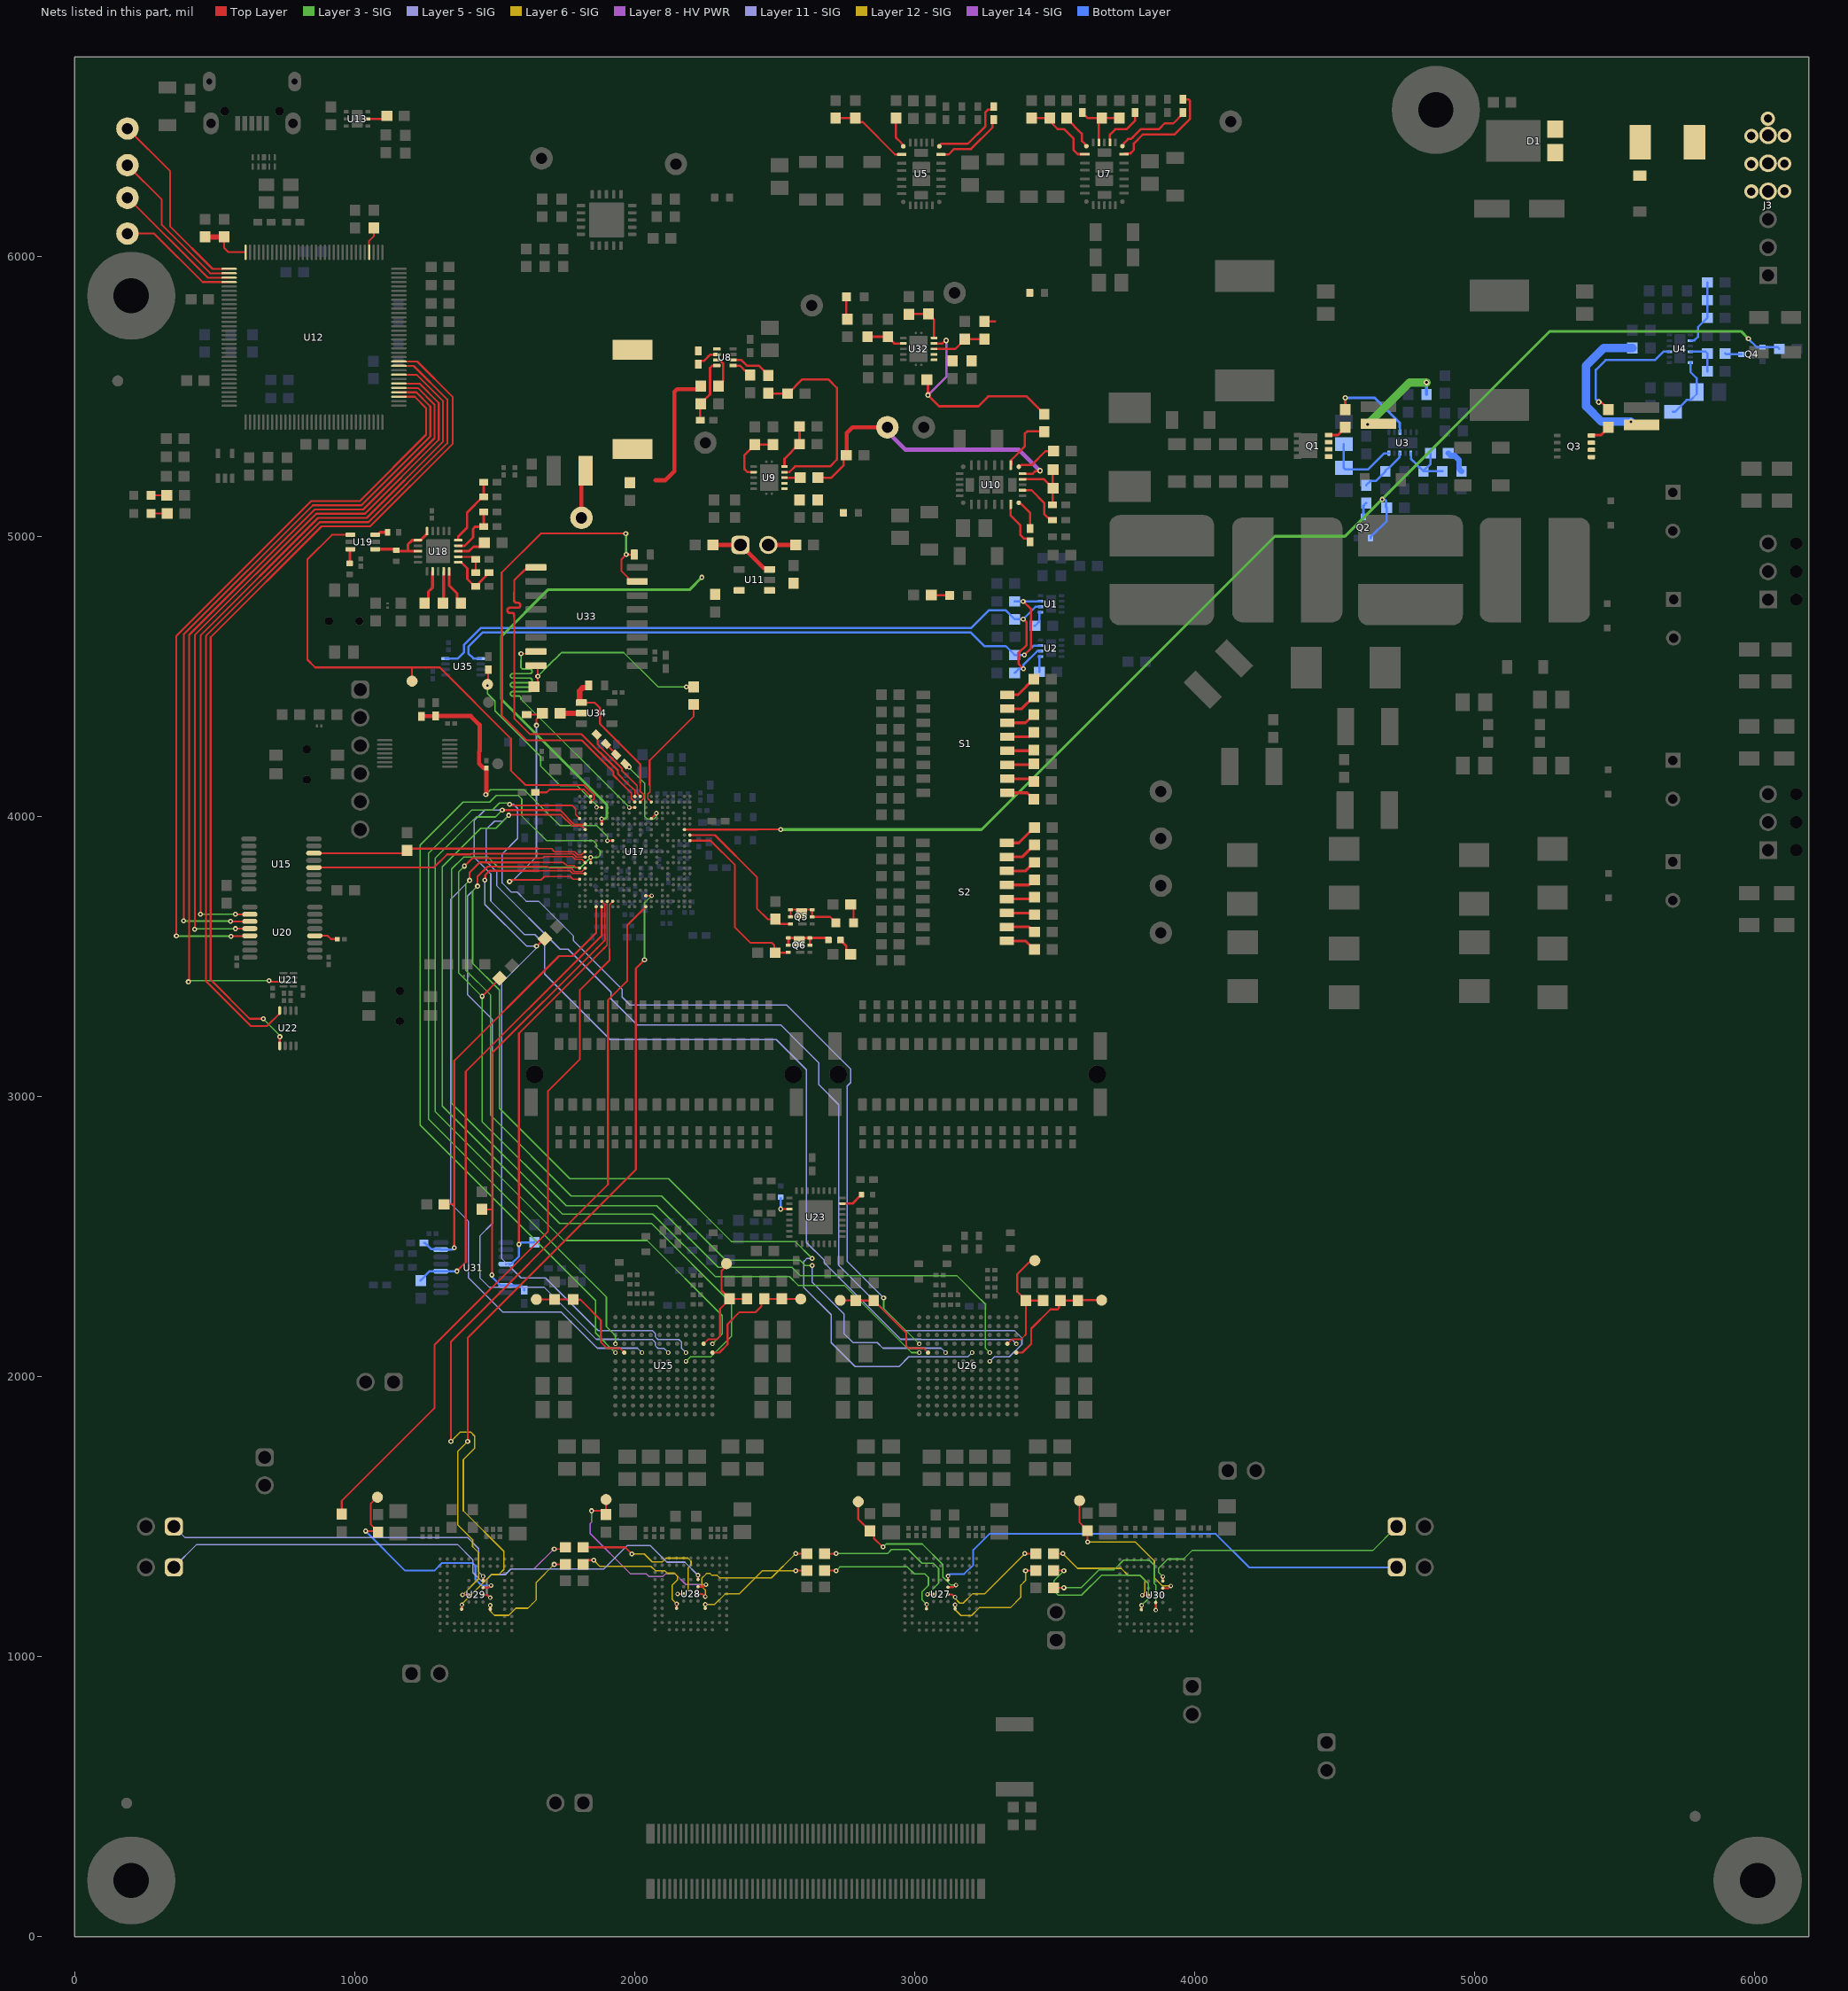
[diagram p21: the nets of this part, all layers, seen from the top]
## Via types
v1: diameter 18, hole 8, Top Layer to Bottom Layer, tented both sides, 930 vias
v2: diameter 16, hole 8, Top Layer to Bottom Layer, tented both sides, 340 vias
v3: diameter 16, hole 8, Top Layer to Bottom Layer, tented bottom, 226 vias
v4: diameter 20, hole 10, Top Layer to Bottom Layer, tented both sides, 129 vias
v5: diameter 50, hole 30, Top Layer to Bottom Layer, tented both sides, 96 vias
v6: diameter 30, hole 15, Top Layer to Bottom Layer, tented both sides, 47 vias
v7: diameter 19.68, hole 7.87, Top Layer to Bottom Layer, 40 vias
v8: diameter 19.68, hole 7.87, Top Layer to Bottom Layer, tented both sides, 19 vias
v9: diameter 18, hole 8, Top Layer to Bottom Layer, tented bottom, 13 vias
v10: diameter 40, hole 20, Top Layer to Bottom Layer, tented both sides, 4 vias
v11: diameter 40, hole 20, Top Layer to Bottom Layer, 3 vias
v12: diameter 18, hole 8, Top Layer to Bottom Layer, 1 vias

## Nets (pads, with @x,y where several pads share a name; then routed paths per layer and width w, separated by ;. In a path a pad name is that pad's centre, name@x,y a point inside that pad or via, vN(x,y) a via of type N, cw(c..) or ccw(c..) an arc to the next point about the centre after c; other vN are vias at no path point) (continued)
NetC61_2: C61.2 R44.1 R50.2 U7.25 | length 233.7
  Top Layer w8: C61.2@3598.72,6512.68 3598.72,6508.74 3606.53,6500.93 3610.46,6500.93 3618.57,6492.82 R44.1@3668.41,6492.82 ; U7.25@3657.69,6406.64 3657.69,6482.1 R44.1@3668.41,6492.82 ; R50.2@3731.27,6492.82 R44.1@3668.41,6492.82
NetC67_1: C67.1 C68.1 L12.2 R440.2 U32.1 U32.2 | length 38.4
  Top Layer w8: R440.2@3249.06,5767.19 3287.49,5767.19
NetC70_1: C70.1 R442.2 U32.7 | length 137.9
  Top Layer w8: R442.2@2831.53,5712.7 C70.1@2904.06,5712.7 2904.06,5711.72 2926.9,5688.88 U32.7@2958.95,5688.88
NetC71_1: C71.1 U7.23 | length 167.2
  Top Layer w8: U7.23@3697.06,6406.64 3697.11,6406.69 3697.11,6434.39 3714.71,6451.99 3717.03,6454.32 3757.49,6454.32 3787.49,6484.32 C71.1@3787.49,6512.68
NetC73_1: C73.1 U8.6 | length 86.5
  Top Layer w8: C73.1@2227.49,5610.38 C73.1@2227.49,5614.32 2227.49,5618.25 2235.3,5626.06 2246.85,5626.06 2262.49,5641.7 2269.95,5649.16 U8.6@2293.36,5649.16
NetC73_2: C73.2 L13.1 U8.5
NetC76_1: C76.1 U8.7 | length 116.2
  Top Layer w8: U8.7@2293.36,5629.47 2295.26,5627.57 2306.26,5627.57 2315.55,5618.28 2315.55,5569.32 2315.55,5556.07 2313.76,5554.29 2313.76,5550.39 C76.1@2299.06,5535.69
NetC77_1: C77.1 L13.2 R56.1 R59.2 TP8.1 | length 635.5
  Top Layer w15: TP8.1@1810.1,5065.92 1810.1,5219.84 R56.1@1824.58,5234.32 ; 2073.49,5200.32 2110.49,5200.32 2142.3,5232.13 2142.3,5516.43 2151.09,5525.22 R59.2@2233.5,5525.22
NetC84_2: C84.2 R61.1 R65.2 U10.25 | length 247.7
  Top Layer w8: U10.25@3384.97,5203.88 3407.49,5203.88 3461.45,5203.88 R65.2@3492.49,5172.85 ; C84.2@3492.49,5112.88 R65.2@3492.49,5171.7 ; R65.2@3494.62,5171.7 3493.63,5171.7 R65.2@3492.49,5172.85 ; R61.1@3494.62,5237.88 3492.49,5235.75 R65.2@3492.49,5172.85
NetC88_1: C88.1 C89.1 C95.1 L14.2 U9.1 U9.2 U11.1
NetC92_1: C92.1 R451.2 U9.7 | length 204.5
  Top Layer w8: U9.7@2424.73,5229 2402.81,5229 2392.49,5239.32 2392.49,5290.03 2428.79,5326.33 R451.2@2428.79,5327.31 C92.1@2493.79,5327.31
NetC93_1: C93.1 U10.23 | length 174.8
  Top Layer w8: U10.23@3384.97,5164.51 3417.29,5164.51 3462.49,5119.32 3462.49,5079.81 3476.61,5065.69 3484.68,5065.69 C93.1@3492.49,5057.88
NetC96_1: C96.1 U11.5 U17.E16 | length 1644.6
  Top Layer w10: U17.E16@1882.29,3972.74 v2@1882.29,3991.34
  Layer 3 - SIG w10: v2(1882.04,3991.6) 1882.42,3991.98 1894.87,3991.98 1900.86,3997.97 1900.86,4041.96 1524.2,4418.62 1524.2,4643.22 1690,4809.02 2195.6,4809.02 v1(2240.3,4853.72)
NetC101_1: C101.1 U13.2 | length 72.2
  Top Layer w6.8: U13.2@1047.09,6490.32 1103.71,6490.32 C101.1@1114.71,6501.32
NetC113_1: C113.1 R76.1 U12.96 | length 190
  Top Layer w6.8: C113.1@533.9,6068.82 533.9,6030.22 549.8,6014.32 610.75,6014.32 610.81,6014.25 U12.96@610.81,6013.97
  Top Layer w20: R76.1@466.3,6068.82 C113.1@533.9,6068.82
NetC124_1: C124.1 U18.5 | length 131.1
  Top Layer w10: U18.5@1337.56,4874.87 1337.56,4824.35 1365.99,4795.92 1365.99,4774.92 C124.1@1379.69,4761.22
NetC125_1: C125.1 U18.4 | length 114.8
  Top Layer w10: C125.1@1315.19,4761.22 1317.88,4763.9 U18.4@1317.88,4874.87
NetC126_1: C126.1 U18.2 | length 125.6
  Top Layer w10: C126.1@1249.69,4761.22 1263.39,4774.92 1263.39,4801.92 1278.51,4817.03 U18.2@1278.51,4874.87
NetC137_1: C137.1 R141.1 R142.2 U17.G13 | length 1042.6
  Top Layer w4: v2(1902.91,3913.06) v2@1903.23,3913.37 ; U17.G13@1921.35,3913.37 U17.G13@1921.66,3913.69
  Top Layer w6.8: v2@1903.23,3913.37 U17.G13@1921.35,3913.37
  Top Layer w15: R141.1@1239,4357.39 1239.6,4357.99 1288.2,4357.99 R142.2@1288.8,4358.6 1414.93,4358.6 1446.52,4327 1446.52,4232.59 1444.2,4230.28 1444.2,4188.45 1459.54,4173.11 1469.62,4173.11 C137.1@1470.1,4172.62 1470.1,4079.72 v1(1468.8,4078.42)
  Layer 3 - SIG w5: 1476.32,4085.22 1469.52,4078.42 v1(1468.8,4078.42) 1485.39,4095 1604.9,4095 1732.85,3967.05 1864.43,3967.05 1902.91,3928.56 v2(1902.91,3913.06)
NetC239_1: C239.1 R154.2 TP30.1 U25.H11 | length 438.2
  Top Layer w5.5: 1900.54,2102.34 1901.54,2101.35 1947.14,2101.35 U25.H11@1962.76,2085.72
  Top Layer w6: 1879.55,2123.33 1900.54,2102.34
  Top Layer w6.8: TP30.1@1648.85,2275.54 C239.1@1714.24,2275.54 R154.2@1780.24,2275.54 1781.14,2274.63 1806.25,2274.63 1879.55,2201.33 1879.55,2123.33
NetC240_1: C240.1 R155.2 TP31.1 U25.H1 | length 446.9
  Top Layer w6.8: U25.H1@2277.72,2085.72 2302.24,2085.72 2331.55,2115.03 2331.55,2187.23 2374.55,2230.23 2432.35,2230.23 2452.65,2250.54 2452.65,2267 R155.2@2463.19,2277.54 2463.79,2276.93 TP31.1@2592.95,2276.93
NetC241_1: C241.1 R156.2 TP32.1 U25.J2 | length 423.5
  Top Layer w5.5: U25.J2@2246.23,2117.22 2261.85,2132.84 2292.26,2132.84 2304.65,2145.23
  Top Layer w6.8: 2304.65,2145.23 2304.65,2241.97 2339.24,2276.55 R156.2@2339.24,2277.54 ; TP32.1@2327.85,2403.23 2327.85,2394.75 2310.45,2377.35 2310.45,2307.31 2339.24,2278.52 R156.2@2339.24,2277.54 ; C241.1@2401.28,2277.54 R156.2@2339.24,2277.54
NetC270_1: C270.1 R157.2 TP33.1 U26.H11 | length 418.6
  Top Layer w5.5: 2970.25,2109.53 2978.44,2101.35 3031.92,2101.35 U26.H11@3047.54,2085.72
  Top Layer w6.8: TP33.1@2734.05,2272.43 2788.54,2272.43 R157.2@2789.64,2271.34 2790.14,2271.84 C270.1@2853.64,2271.84 2853.64,2270.86 2868.34,2256.16 2869.32,2256.16 2970.25,2155.23 2970.25,2109.53
NetC271_1: C271.1 R158.2 TP34.1 U26.H1 | length 426.9
  Top Layer w6.8: U26.H1@3362.5,2085.72 3384.54,2085.72 3415.85,2117.03 3415.85,2171.03 3484.75,2239.93 3510.36,2239.93 3515.05,2244.62 3515.05,2266.14 R158.2@3520.75,2271.84 C271.1@3582.88,2271.84 3584.07,2273.03 TP34.1@3667.55,2273.03
NetC272_1: C272.1 R159.2 TP35.1 U26.J2 | length 452.5
  Top Layer w5.5: U26.J2@3331.01,2117.22 3346.88,2133.09 3379.41,2133.09 3393.85,2147.53
  Top Layer w6.8: 3393.85,2147.53 3396.64,2150.32 R159.2@3396.64,2271.84 ; TP35.1@3428.95,2414.23 3422.95,2408.23 3408.65,2408.23 3366.05,2365.63 3366.05,2303.41 3396.64,2272.82 R159.2@3396.64,2271.84 ; C272.1@3458.76,2271.84 R159.2@3396.64,2271.84
NetC467_1: C467.1 U8.1 | length 75.5
  Top Layer w8: U8.1@2351.62,5609.79 2375.58,5609.79 2377.49,5607.88 2393.87,5591.5 2397.79,5591.5 2412.49,5576.8 C467.1@2412.49,5575.81
NetD1_1: D1.1 D1.2 D25.1 F1.1
NetD26_2: D26.2 R48.1 | length 79.9
  Top Layer w8: D26.2@2755.99,5854.32 2755.99,5778.77 R48.1@2759.06,5775.69
NetD27_2: D27.2 R73.1 | length 65.8
  Top Layer w6.8: R73.1@3058.99,4790.11 R73.1@3059.78,4789.32
  Top Layer w8: R73.1@3059.78,4789.32 D27.2@3124.5,4789.32
NetD28_2: D28.2 R79.1 | length 57
  Top Layer w6.8: D28.2@273.69,5081.52 R79.1@330.7,5081.52
NetD29_2: D29.2 R80.1 | length 55.8
  Top Layer w6.8: D29.2@273.69,5146.52 329.39,5146.52 R80.1@329.49,5146.62
NetD30_1: D30.1 Q5.1 Q5.2 Q5.5 Q5.6 Q5.8 | length 232.7
  Top Layer w6.8: Q5.2@2556.9,3641.52 Q5.1@2556.9,3667.11 2556.98,3667.03 2582.57,3667.03 Q5.8@2595.29,3654.31 2608.01,3667.03 2633.6,3667.03 Q5.6@2633.68,3667.11 Q5.5@2633.68,3641.52 2698.11,3641.52 D30.1@2719.11,3620.52
NetD30_2: D30.2 R121.1 | length 69.7
  Top Layer w6.8: R121.1@2770.79,3685.52 2782.11,3674.2 D30.2@2782.11,3620.52
NetD31_1: D31.1 Q6.1 Q6.2 Q6.5 Q6.6 Q6.8 | length 207.6
  Top Layer w9: Q6.2@2548.9,3540.52 Q6.1@2548.9,3566.11 2549.23,3565.78 2574.82,3565.78 Q6.8@2587.29,3553.31 2599.76,3565.78 2625.35,3565.78 Q6.6@2625.68,3566.11 ; Q6.5@2625.68,3540.52 Q6.6@2625.68,3566.11 ; D31.1@2691.62,3558.52 2684.03,3566.11 Q6.6@2625.68,3566.11
NetD31_2: D31.2 R122.1 | length 66.4
  Top Layer w9: D31.2@2734.93,3558.52 2755.6,3537.84 2755.6,3521.72 2769.8,3507.52 R122.1@2770.79,3507.52
NetF1_2: F1.2 J3.4 J3.5 J3.6
  other v5: 5987.49,6231.32 6105.49,6232.32 5987.49,6329.32 6105.49,6330.32 5987.49,6429.32 6105.49,6430.32 6046.49,6491.32
NetJ4_1: J4.1 R72.2 U11.3 | length 238.9
  Top Layer w15: R72.2@2278.99,4969.32 J4.1@2377.49,4969.32 2460.78,4886.03 2477.31,4886.03 U11.3@2481.62,4881.72
NetJ4_2: J4.2 R71.1 | length 98.5
  Top Layer w15: J4.2@2477.49,4969.32 R71.1@2575.99,4969.32
NetJ19_1: J19.1 U29.D7 | length 1243.8
  Top Layer w6.8: U29.D7@1458.89,1272.03 1459.22,1272.36 v2@1459.22,1289.2
  Layer 11 - SIG w5: J19.1@354.84,1464.6 393.44,1426 1402.92,1426 1442.92,1386 1442.92,1303.08 v2(1459,1287) ; v2@1459,1289.2 v2@1459.22,1289.2
NetJ20_1: J20.1 U30.D7 | length 964.3
  Top Layer w6.8: v2(3886,1286) 3886,1271.09 3886.39,1270.7 U30.D7@3886.06,1270.36
  Layer 3 - SIG w5: v2(3886,1286) 3870.09,1301.91 3870.09,1314.86 3903.89,1348.65 3960.12,1348.65 3990.4,1378.92 4635.33,1378.92 J20.1@4721,1464.6
NetJ21_1: J21.1 U27.D7 | length 1759.4
  Top Layer w6.8: U27.D7@3118.67,1273.7 3119,1274.03 v2(3119,1288)
  Bottom Layer w6.8: v2(3119,1288) 3126.37,1295.37 3176.85,1295.37 3209.3,1327.82 3209.3,1380.98 3266.85,1438.53 4074.78,1438.53 4194.27,1319.03 J21.1@4721,1319.03
NetJ22_1: J22.1 U28.D7 | length 2097.9
  Top Layer w6.8: v2(2226,1291) 2226,1276.31 2226.61,1275.7 U28.D7@2226.28,1275.36
  Layer 11 - SIG w5: J22.1@354.84,1319.03 436.31,1400.5 1367.44,1400.5 1422.5,1345.45 1422.5,1300.83 1453.83,1269.5 1465.1,1269.5 1488.9,1293.3 1538.45,1293.3 1557.82,1312.67 1634.89,1312.67 1889.47,1312.67 1973.64,1396.84 2055.59,1396.84 2114.72,1337.71 2179.29,1337.71 v2(2226,1291)
NetQ1_1: Q1.1 Q1.2 Q1.3 R12.2 R13.2 | length 315.6
  Layer 3 - SIG w30: v4(4617.49,5399.32) 4767.49,5549.32 v4(4827.49,5549.32)
  Bottom Layer w10: R12.2@4827.49,5505.81 v4(4827.49,5549.32)
NetQ1_4: Q1.4 R10.2 | length 65.7
  Top Layer w10: Q1.4@4483.79,5361.72 4510.88,5361.72 4537.49,5388.33 R10.2@4537.49,5389.32
NetQ2_1: Q2.1 Q4.1 R20.2 R32.2 U17.Y15 | length 4847.1
  Top Layer w6.8: U17.Y15@2177.57,3953.06 2438.14,3953.06 2438.9,3953.82 2520.28,3953.82 v1(2521.04,3953.06)
  Layer 3 - SIG w10: v1(2521.04,3953.06) 3238.84,3953.06 4285.79,5000 4536.09,5000 5268.07,5731.98 5950.24,5731.98 v1(5976.9,5705.32)
  Bottom Layer w8: Q2.1@4627.92,4994.51 4627.92,4997.07 4685.84,5054.99 R20.2@4685.84,5101.91 4683,5104.75 4683,5127.43 4678.32,5132.12 v1(4669.3,5132.12) ; v1(5976.9,5705.32) 6006.72,5675.5 Q4.1@6027.49,5675.5 6081.31,5675.5 R32.2@6087.49,5669.32
NetQ2_3: Q2.3 R15.1 | length 53.7
  Bottom Layer w8: Q2.3@4602.33,5069.32 4602.33,5108.92 R15.1@4612.33,5118.92
NetQ3_1: Q3.1 Q3.2 Q3.3 R25.2 R26.2 | length 519.1
  Bottom Layer w30: v4(5557.49,5409.32) 5452.49,5409.32 5397.49,5464.32 5397.49,5609.32 5460.99,5672.82 R25.2@5562.49,5672.82
NetQ3_4: Q3.4 R23.2 | length 78.5
  Top Layer w10: Q3.4@5410.97,5361.72 5450.88,5361.72 5477.49,5388.33 R23.2@5477.49,5389.32
NetQ4_3: Q4.3 R27.1 | length 59.9
  Bottom Layer w8: R27.1@5893.99,5652.78 5896.86,5649.91 Q4.3@5952.69,5649.91
NetQ5_3: Q5.3 R123.2 U17.AA14 | length 557.5
  Top Layer w6.8: U17.AA14@2197.25,3933.37 2286.55,3933.37 2437.3,3782.62 2437.3,3670.32 2474.6,3633.02 R123.2@2502.29,3633.02 2502.29,3632.04 2516.99,3617.34 2517.98,3617.34 2519.38,3615.93 Q5.3@2556.9,3615.93
NetQ6_3: Q6.3 R124.2 U17.AA13 | length 662.4
  Top Layer w6.8: U17.AA13@2197.25,3913.69 2271.03,3913.69 2358.3,3826.42 2358.3,3603.82 2413.7,3548.42 2490.8,3548.42 2498.2,3541.02 2498.2,3517.1 R124.2@2501.79,3513.52
  Top Layer w9: R124.2@2501.79,3513.52 2544.54,3513.52 2545.95,3514.93 Q6.3@2548.9,3514.93
NetR1_1: R1.1 R6.1 U1.2 U2.2 U35.8 | length 2579.1
  Top Layer w8: v1(3387.49,4704.32) 3399.54,4692.27 3399.54,4611.79 3370.49,4582.74 3370.49,4544.72 v1(3388.19,4527.02)
  Bottom Layer w8: U35.8@1324.5,4563.84 1369,4563.84 1390.21,4585.05 1390.21,4612.29 1450.23,4672.32 3201.49,4672.32 3265.49,4736.32 3324.39,4736.32 R1.1@3356.99,4703.72 3386.89,4703.72 v1(3387.49,4704.32) 3431.81,4748.63 U1.2@3449.49,4748.63 ; R6.1@3356.99,4512.32 3371.69,4527.02 v1(3388.19,4527.02) 3388.19,4540.71 3437.95,4590.47 U2.2@3449.49,4590.47
NetR2_1: R2.1 R7.1 U1.3 U2.3 U35.1 | length 2493.2
  Top Layer w8: v1(3387.29,4767.52) 3415.54,4739.27 3415.54,4600.37 v1(3391.29,4576.12)
  Bottom Layer w8: U35.1@1450.48,4563.84 1424.06,4563.84 1406.21,4581.7 1406.21,4605.66 1456.86,4656.32 3200.49,4656.32 3248.79,4608.02 3325.09,4608.02 R7.1@3356.99,4576.12 v1(3391.29,4576.12) 3425.33,4610.16 U2.3@3449.49,4610.16 ; R2.1@3356.99,4767.52 v1(3387.29,4767.52) 3448.69,4767.52 U1.3@3449.49,4768.32
NetR9_1: R9.1 R11.2 U3.12 | length 271.7
  Bottom Layer w8: R9.1@4532.49,5329.32 R11.2@4532.49,5244.32 4537.49,5239.32 4619.05,5239.32 4676.36,5296.63 4692.99,5296.63 U3.12@4693.28,5296.91
NetR10_1: R10.1 U3.3 | length 307
  Top Layer w10: R10.1@4537.49,5452.31 v4(4537.49,5494.32)
  Bottom Layer w5: 4732.49,5389.32 4732.65,5389.16
  Bottom Layer w8: U3.3@4732.65,5371.72 4732.65,5389.16
  Bottom Layer w10: v4(4537.49,5494.32) 4642.49,5494.32 4732.49,5404.32 4732.49,5389.32
NetR14_1: R14.1 R16.1 R19.2 U3.8 | length 226.5
  Bottom Layer w8: U3.8@4772.02,5296.91 4772.78,5296.15 4772.78,5275.51 4775.27,5273.01 4778.97,5269.32 4800.69,5247.6 4801.7,5247.6 4816.11,5233.19 R16.1@4816.11,5231.92 ; R16.1@4816.4,5231.92 R19.2@4884.33,5231.91 ; R16.1@4816.4,5232.9 4842.33,5258.83 R14.1@4842.33,5296.91
NetR14_2: R14.2 R21.2 | length 92.8
  Bottom Layer w20: R14.2@4905.32,5296.91 4914.02,5288.21 4928.21,5288.21 4943.77,5272.65 4943.77,5240.61 R21.2@4952.47,5231.91
NetR15_2: R15.2 R17.2 U3.10 | length 177.7
  Bottom Layer w8: R15.2@4612.33,5181.91 4612.33,5182.9 4627.03,5197.6 4647,5197.6 4680.33,5230.93 R17.2@4680.33,5231.91 4680.33,5232.9 4695.03,5247.6 4697.06,5247.6 4731.88,5282.43 4731.88,5296.15 U3.10@4732.65,5296.91
NetR22_1: R22.1 R24.2 U4.12 | length 233
  Bottom Layer w8: R22.1@5707.49,5444.32 5713.99,5444.32 5756.49,5486.82 5771.49,5486.82 5792.49,5507.82 R24.2@5792.49,5514.32 5792.49,5564.32 5769.89,5586.91 U4.12@5769.89,5620.1
NetR23_1: R23.1 U4.3 | length 455.5
  Top Layer w6.8: v4(5442.49,5479.32) 5444.79,5477.02 5453.76,5477.02 5477.49,5453.29 R23.1@5477.49,5452.31
  Bottom Layer w8: v4(5442.49,5479.32) 5432.49,5489.32 5432.49,5594.32 5467.49,5629.32 5643.09,5629.32 5673.25,5659.47 U4.3@5695.09,5659.47
NetR27_2: R27.2 R29.2 U4.10 | length 127.3
  Bottom Layer w8: U4.10@5769.89,5659.47 5824.3,5659.47 R27.2@5830.99,5652.78 R29.2@5830.99,5589.32
NetR28_1: R28.1 R30.1 R33.2 U4.8 | length 241.8
  Bottom Layer w8: U4.8@5769.89,5698.84 5770.66,5699.61 5784.38,5699.61 5797.31,5712.54 5797.31,5747.08 5830.01,5779.78 R28.1@5830.99,5779.78 R30.1@5830.99,5906.72
NetR36_1: R36.1 R39.2 U5.2 | length 289.8
  Top Layer w8: R39.2@2717.49,6492.82 R36.1@2788.51,6492.82 2802.2,6479.14 2814.19,6479.14 2929.66,6363.66 2953.58,6363.66 U5.2@2953.75,6363.49
NetR41_1: R41.1 U5.21 | length 275.5
  Top Layer w8: 3093.95,6400.89 3189.06,6400.89 3252.49,6464.32 3252.49,6514.32 3260.89,6522.71 3274.68,6522.71 3282.49,6530.52 R41.1@3282.49,6534.46
NetR41_2: R41.2 U5.20 | length 253.6
  Top Layer w8: U5.20@3093.51,6363.49 3121.66,6363.49 3141.06,6382.89 3147.49,6382.89 3201.06,6382.89 3277.64,6459.47 3277.64,6482.37 R41.2@3282.49,6487.22
NetR43_2: R43.2 U5.1 | length 100.1
  Top Layer w8: R43.2@2933.51,6492.82 2933.51,6423.07 2953.32,6403.27 2953.32,6400.89
NetR45_1: R45.1 R49.2 U32.5 | length 164.6
  Top Layer w8: R45.1@2979.06,5792.7 2980.56,5794.2 R49.2@3049.06,5794.2 3049.06,5793.21 3069.18,5773.1 U32.5@3069.18,5708.57
NetR46_1: R46.1 R51.2 U7.2 | length 267.4
  Top Layer w8: R51.2@3417.49,6492.82 3472.49,6492.82 3472.49,6491.84 3510.01,6454.32 3532.49,6454.32 3567.49,6419.32 3567.49,6379 3572.18,6374.32 3572.49,6374.32 3582.49,6364.32 U7.2@3607.49,6364.32
NetR52_1: R52.1 U7.21 | length 259.4
  Top Layer w8: 3747.69,6401.72 3747.69,6404.01 3761.99,6418.32 3772.4,6418.32 3778.24,6424.15 3808.4,6454.32 3872.49,6454.32 3892.49,6474.32 3923.07,6474.32 3957.49,6508.74 R52.1@3957.49,6512.68
NetR52_2: R52.2 U7.20 | length 393.3
  Top Layer w8: U7.20@3747.25,6364.32 3750.14,6367.21 3770.38,6367.21 3782.49,6379.32 3782.49,6402.95 3813.86,6434.32 3926.49,6434.32 3983.3,6491.13 3983.3,6553.51 3976.89,6559.92 R52.2@3957.49,6559.92
NetR53_2: R53.2 U1.1 | length 61.3
  Bottom Layer w8: R53.2@3427.39,4680.62 3429.87,4680.62 3444.57,4695.32 3444.57,4728.02 3445.49,4728.95 U1.1@3449.49,4728.95
NetR54_1: R54.1 R67.2 U32.4 | length 799
  Top Layer w6.8: R54.1@3043.99,5559.32 R54.1@3047.49,5555.81 ; R67.2@3462.49,5435.81 R67.2@3462.49,5436.8
  Top Layer w8: R54.1@3047.49,5555.81 v4(3047.49,5504.32) 3087.49,5464.32 3227.49,5464.32 3262.49,5499.32 3399.97,5499.32 R67.2@3462.49,5436.8 ; U32.4@3069.18,5688.88 3098.81,5688.88 3109.24,5699.32 v4(3112.49,5699.32)
  Layer 8 - HV PWR w8: v4(3047.49,5504.32) 3112.49,5569.32 v4(3112.49,5699.32)
NetR55_2: R55.2 U7.1 | length 117.8
  Top Layer w8: R55.2@3542.49,6492.82 3542.49,6491.84 3596.78,6437.55 3596.78,6412 3607.06,6401.72
NetR57_2: R57.2 R59.1 U8.8 | length 228.2
  Top Layer w8: R57.2@2233.87,5414.32 2234.06,5414.51 R59.1@2234.06,5472.7 ; R59.1@2236.3,5472.82 2236.3,5473.8 2269.2,5506.71 2269.2,5601.22 2276.87,5608.88 2292.45,5608.88 U8.8@2293.36,5609.79
NetR58_1: R58.1 U8.2 | length 149.3
  Top Layer w8: U8.2@2351.62,5629.47 2381.35,5629.47 2401.09,5609.74 2443.05,5609.74 2477.49,5575.3 R58.1@2477.49,5574.32
NetR58_2: R58.2 R63.1 U9.4 | length 740.3
  Top Layer w6.8: 2722.31,5313.82 2722.49,5314
  Top Layer w8: R58.2@2477.49,5511.32 2479.5,5509.32 2546.98,5509.32 2596.98,5559.32 2692.49,5559.32 2722.49,5529.32 2722.49,5314 ; U9.4@2534.97,5229 2535.69,5229.73 2553.22,5229.73 2572.81,5249.32 2697.49,5249.32 2722.31,5274.14 2722.31,5313.82
NetR60_1: R60.1 U9.3 | length 57
  Top Layer w8: U9.3@2535.69,5210.04 U9.3@2534.97,5209.32 R60.1@2590.99,5209.32
NetR60_2: R60.2 R69.1 TP12.1 U10.26 | length 1091.7
  Top Layer w8: R60.2@2653.99,5209.32 2702.49,5209.32 2745.99,5252.82 R69.1@2745.99,5289.32 ; U10.26@3384.97,5223.57 3421.49,5223.57 3429.94,5232.02 3445.19,5232.02 v4(3447.49,5234.32)
  Top Layer w15: R69.1@2755.99,5289.32 2757.49,5290.81 2757.49,5369.32 2777.49,5389.32 TP12.1@2902.49,5389.32
  Layer 8 - HV PWR w8: v4@3446.8,5234.32 v4(3447.49,5234.32)
  Layer 8 - HV PWR w15: TP12.1@2873.79,5403.02 2967.49,5309.32 3372.49,5309.32 v4(3447.49,5234.32)
NetR62_1: R62.1 R66.2 U9.5 | length 166.5
  Top Layer w8: U9.5@2534.97,5248.69 2534.97,5276.48 2587.8,5329.32 R62.1@2588.79,5329.32 R66.2@2588.79,5392.31
NetR67_1: R67.1 U10.2 | length 206.5
  Top Layer w8: U10.2@3342.65,5254.08 3345.54,5256.97 3345.54,5273.59 3392.49,5320.54 3392.49,5365.72 3401.09,5374.32 3460.99,5374.32 R67.1@3462.49,5372.82
NetR68_1: R68.1 U10.21 | length 100.8
  Top Layer w8: 3380.05,5113.88 3382.41,5113.88 3412.49,5083.8 R68.1@3412.49,5027.94
NetR68_2: R68.2 U10.20 | length 171.5
  Top Layer w8: U10.20@3342.65,5114.32 3342.65,5074.16 3377.49,5039.32 3377.49,5004.32 3389.36,4992.44 3404.68,4992.44 3412.49,4984.63 R68.2@3412.49,4980.69
NetR70_2: R70.2 U10.1 | length 136.6
  Top Layer w8: 3380.05,5254.51 3407.49,5254.51 3417.69,5254.51 3467.49,5304.32 R70.2@3495.99,5304.32
NetR74_2: R74.2 U12.68 | length 94.3
  Top Layer w6.8: U12.68@1051.75,6013.97 1051.75,6054.77 1068.4,6071.42 R74.2@1068.4,6101.32
NetR81_1: R81.1 U15.6 U17.B11 | length 989.4
  Top Layer w4: 1657.49,3884.82 1703.3,3884.82 1713.5,3874.62 1785.37,3874.62 1797.57,3862.41 1810.3,3862.41 1822.21,3874.32 U17.B11@1823.24,3874.32
  Top Layer w6.8: U15.6@854.75,3868.7 1176.78,3868.7 1192.9,3884.82 1657.49,3884.82
NetR89_1: R89.1 S1.16 | length 126.7
  Top Layer w10: S1.16@3321.99,4434.32 3368.61,4434.32 3424.51,4490.22 R89.1@3425.49,4490.22
NetR90_1: R90.1 S1.15 | length 121.1
  Top Layer w10: S1.15@3321.99,4384.32 3381.94,4384.32 3424.51,4426.88 R90.1@3425.49,4426.88
NetR91_1: R91.1 S1.14 | length 115.6
  Top Layer w10: S1.14@3321.99,4334.32 3395.27,4334.32 3424.51,4363.55 R91.1@3425.49,4363.55
NetR92_1: R92.1 S1.13 | length 110.1
  Top Layer w10: S1.13@3321.99,4284.32 3408.61,4284.32 3424.51,4300.22 R92.1@3425.49,4300.22
NetR93_1: R93.1 S1.12 | length 104.7
  Top Layer w10: S1.12@3321.99,4234.32 3422.49,4234.32 R93.1@3425.49,4237.32
NetR94_1: R94.1 S1.11 | length 105.2
  Top Layer w10: S1.11@3321.99,4184.32 3421.43,4184.32 R94.1@3425.49,4188.38
NetR95_1: R95.1 S1.10 | length 107.3
  Top Layer w10: S1.10@3321.99,4134.32 3416.23,4134.32 R95.1@3425.49,4125.05
NetR96_1: R96.1 S1.9 | length 112.9
  Top Layer w10: S1.9@3321.99,4084.32 3401.91,4084.32 3424.51,4061.72 R96.1@3425.49,4061.72
NetR97_1: R97.1 S2.16 | length 128.2
  Top Layer w10: S2.16@3321.99,3905.32 3371.61,3905.32 3426.51,3960.22 R97.1@3427.49,3960.22
NetR98_1: R98.1 S2.15 | length 123.2
  Top Layer w10: S2.15@3321.99,3855.32 3383.75,3855.32 3426.51,3898.07 R98.1@3427.49,3898.07
NetR99_1: R99.1 S2.14 | length 118.2
  Top Layer w10: S2.14@3321.99,3805.32 3395.89,3805.32 3426.51,3835.93 R99.1@3427.49,3835.93
NetR100_1: R100.1 S2.13 | length 113.2
  Top Layer w10: S2.13@3321.99,3755.32 3408.04,3755.32 3426.51,3773.79 R100.1@3427.49,3773.79
NetR101_1: R101.1 S2.12 | length 108.1
  Top Layer w10: S2.12@3321.99,3705.32 3421.16,3705.32 R101.1@3427.49,3711.65
NetR102_1: R102.1 S2.11 | length 107.9
  Top Layer w10: S2.11@3321.99,3655.32 3421.68,3655.32 R102.1@3427.49,3649.5
NetR103_1: R103.1 S2.10 | length 112.9
  Top Layer w10: S2.10@3321.99,3605.32 3408.55,3605.32 3426.51,3587.36 R103.1@3427.49,3587.36
NetR104_1: R104.1 S2.9 | length 118
  Top Layer w10: S2.9@3321.99,3555.32 3396.41,3555.32 3426.51,3525.22 R104.1@3427.49,3525.22
NetR126_1: R126.1 R132.2 U18.10 | length 246.9
  Top Layer w9: U18.10@1370.04,4986.09 1370.04,4999.32 1401.69,5030.97 1401.69,5085.26 1456.65,5140.22 R126.1@1460.59,5140.22 R132.2@1460.59,5193.22
NetR127_1: R127.1 R133.2 U18.9 | length 189.8
  Top Layer w9: U18.9@1370.04,4966.4 1393.38,4966.4 1422.69,4995.72 1422.69,5026.72 1430.19,5034.22 R127.1@1460.59,5034.22 R133.2@1460.59,5087.22
NetR128_1: R128.1 R134.2 U18.7 | length 114.6
  Top Layer w6.8: U18.7@1370.04,4927.03 1419.33,4927.03 1428.65,4917.72 R128.1@1432.59,4917.72 1432.59,4870.2 R134.2@1433.07,4869.72
NetR129_1: R129.1 U18.15 U18.16 U18.18 U19.1 | length 273.8
  Top Layer w10: U19.1@1073.48,4954.13 1147.33,4954.13 1154.74,4946.72 1190.54,4946.72 ; U18.18@1226.34,4946.72 1190.54,4946.72 ; U18.15@1258.82,5018.57 1258.82,5009.08 1236.1,4986.36 1235.83,4986.09 U18.16@1226.34,4986.09 1226.06,4985.81 1205.28,4985.81 1190.54,4971.07 1190.54,4946.72
NetR130_1: R130.1 U19.3 | length 48.5
  Top Layer w10: U19.3@1073.09,5005.7 1082.74,5005.7 1091.25,5014.22 R130.1@1118.02,5014.22
NetR131_1: R131.1 U19.6 | length 51.8
  Top Layer w10: R131.1@982.19,4903.4 983.54,4904.76 983.54,4952.77 U19.6@984.9,4954.13
NetR134_1: R134.1 R135.2 U18.6 | length 194.1
  Top Layer w9: U18.6@1370.04,4907.35 1380.08,4907.35 1402,4885.42 1402,4847.84 1429.13,4820.72 1437,4820.72 1444.32,4828.03 1444.32,4833.72 1469.06,4858.47 1469.06,4862.4 1476.37,4869.72 R134.1@1480.31,4869.72
NetR139_2: R139.2 TP21.1 U17.E19 | length 707.8
  Top Layer w4: U17.E19@1881.91,4032.18 U17.E19@1882.29,4031.8
  Top Layer w6: v2@1863.88,4032.18 U17.E19@1881.91,4032.18
  Top Layer w6.8: v1(1474.3,4467.02) 1477.15,4469.87 R139.2@1477.15,4523.94
  Layer 3 - SIG w5: v1(1474.3,4467.02) 1474.3,4438.66 1501.6,4411.36 1501.6,4376.92 1664.55,4213.97 1664.55,4179.65 1734.57,4109.63 1794.39,4109.63 1864.4,4039.61 v2@1864.4,4032.56
  other v2: 1863.88,4032.56
NetR140_2: R140.2 U17.C21 | length 212.5
  Top Layer w6.8: R140.2@1645.23,4085.82 1657.9,4085.82 1685.82,4085.82 1695.82,4095.82 1819.09,4095.82 1842.92,4071.99 U17.C21@1842.92,4071.17
NetR145_2: R145.2 U20.4 | length 84.8
  Top Layer w6.8: U20.4@858,3573.81 904.31,3573.81 915.9,3562.22 933.88,3562.22 934.48,3561.62 R145.2@937.8,3561.62
NetR150_1: R150.1 U23.11 | length 69.8
  Top Layer w6.8: v1(2521.82,2598.26) U23.11@2552.4,2598.26
  Bottom Layer w8: R150.1@2521.35,2637.31 2521.59,2637.08 2521.59,2598.5 v1(2521.82,2598.26)
NetR151_1: R151.1 U23.31 | length 88
  Top Layer w9: U23.31@2735.14,2617.95 2735.36,2618.17 2778.17,2618.17 2804.35,2644.35 2804.84,2644.35 2809.69,2649.2 R151.1@2809.69,2649.69
NetR160_1: R160.1 TP39.1 U27.E7 | length 582.5
  Top Layer w6.8: TP39.1@2798.39,1553.5 2798.39,1491.09 2854.18,1435.3 2854.18,1423.13 2885.58,1391.73 v1(2887.21,1391.73) ; U27.E7@3118.67,1248.11 3138.12,1248.11 3145.68,1255.67 v2(3147.3,1255.67)
  Layer 3 - SIG w5: v1(2887.21,1391.73) 2897.89,1402.41 3026.98,1402.41 3100.47,1328.92 3100.47,1284.61 3129.41,1255.67 v2(3147.3,1255.67)
NetR163_1: R163.1 TP40.1 U28.E7 | length 718
  Top Layer w6: v1(1846.45,1520.86) 1847.19,1521.6 1883.87,1521.6 R163.1@1897.97,1507.5 1897.97,1551.77 TP40.1@1900.39,1554.2
  Top Layer w6.8: U28.E7@2226.28,1249.77 2245.73,1249.77 2253.29,1257.33 v2(2254.91,1257.33)
  Layer 14 - SIG w5: v1(1846.45,1520.86) 1846.45,1480.01 1841.55,1475.12 1841.55,1439.47 1984.75,1296.27 2040.97,1296.27 2051.34,1285.91 2100.36,1285.91 2110.72,1296.27 2143.99,1296.27 2182.92,1257.33 v2(2254.91,1257.33)
NetR294_1: R294.1 TP37.1 U29.E7 | length 803.4
  Top Layer w6: TP37.1@1081.5,1569.36 1057.29,1545.15 1057.29,1472.89 1083.99,1446.19 R294.1@1083.99,1445.21
  Top Layer w6.8: v1(1039.11,1448.38) 1079.61,1448.38 1083.39,1444.6 R294.1@1083.99,1445.21 ; U29.E7@1458.89,1246.44 1478.34,1246.44 1485.9,1254 v2(1487.52,1254)
  Bottom Layer w6.8: v1(1039.11,1448.38) 1180.27,1307.22 1284.49,1307.22 1312.08,1334.8 1421.02,1334.8 1431.79,1324.03 1431.79,1276.39 1454.18,1254 v2(1487.52,1254)
NetR297_1: R297.1 TP38.1 U30.E7 | length 589.1
  Top Layer w6: TP38.1@3588.69,1557.3 3588.69,1479.49 3617.29,1450.89 R297.1@3617.29,1449.91
  Top Layer w6.8: v1(3617.29,1409.46) R297.1@3617.29,1449.91 ; U30.E7@3886.06,1244.77 3905.51,1244.77 3913.07,1252.33 v2(3914.69,1252.33)
  Layer 6 - SIG w5: v1(3617.29,1409.46) 3787.97,1409.46 3855.63,1341.8 3855.63,1281.72 3885.01,1252.33 v2(3914.69,1252.33)
NetR428_2: R428.2 R515.1 U17.E2 U31.7 | length 1700.4
  Top Layer w4: 1865.17,3529.32 1894.2,3558.34 1894.2,3685.25 U17.E2@1882.29,3697.15
  Top Layer w6.8: R515.1@1445.82,2596.95 R515.1@1455.61,2587.15 ; R515.1@1455,2596.95 1490.66,2596.95 ; v1(1490.66,2362.73) 1490.66,2596.95 ; 1865.17,3529.32 1490.66,3154.8 1490.66,2596.95
  Bottom Layer w8: v1(1490.66,2362.73) 1491.81,2361.58 1491.81,2354.8 1521.53,2325.07 1593.95,2325.07 1606.35,2312.67 R428.2@1606.35,2308.73
NetR429_2: R429.2 R516.1 U17.D1 U31.15 | length 1613.3
  Top Layer w6.8: R516.1@1320.09,2615.09 1356,2615.09 ; v1(1356,2460.06) 1356,2615.09 ; U17.D1@1862.61,3677.47 1862.61,3584.57 1779.41,3501.37 1729.66,3501.37 1356,3127.71 1356,2615.09
  Bottom Layer w8: R429.2@1247.87,2477.03 1251.81,2477.03 1273.96,2454.88 1306.09,2454.88 U31.15@1307.95,2453.02 1348.96,2453.02 v1(1356,2460.06)
NetR438_2: R438.2 U17.F2 U31.4 | length 1514.7
  Top Layer w4: 1890.5,3529.32 1901.36,3540.17 1901.36,3696.53 U17.F2@1901.98,3697.15
  Top Layer w6.8: v1(1586.85,2471.94) 1586.85,3225.66 1890.5,3529.32
  Bottom Layer w8: U31.4@1540.23,2401.84 1558.93,2401.84 1586.85,2429.76 v1(1586.85,2471.94) 1588.47,2471.94 1594.77,2478.23 1640.85,2478.23 R438.2@1642.25,2479.63
NetR439_2: R439.2 U17.E1 U31.12 | length 1658.7
  Top Layer w6.8: v1@1365.15,2376.33 v1(1364.85,2376.63) 1397.01,2408.79 1397.01,3089.07 1837.25,3529.32 1882.29,3574.36 U17.E1@1882.29,3677.47
  Bottom Layer w8: R439.2@1236.25,2343.03 1236.25,2344.02 1268.49,2376.25 U31.12@1307.95,2376.25 1308.14,2376.44 1364.66,2376.44 v1(1364.85,2376.63)
NetR440_1: R440.1 R441.2 U32.3 | length 195
  Top Layer w8: U32.3@3069.18,5669.2 3145.05,5669.2 3179.06,5703.21 R441.2@3179.06,5704.2 R440.1@3249.06,5704.2
NetR443_1: R443.1 U17.P20 | length 421.5
  Top Layer w4: 2054.8,4111.93 2054.8,4087.13 2047.55,4079.88 2047.55,4063.39 U17.P20@2059.46,4051.48
  Top Layer w6.8: 2053.5,4111.93 2053.5,4200.02 2210.99,4357.5 R443.1@2210.99,4399.82
NetR443_2: R443.2 R444.2 U33.16 | length 729.1
  Top Layer w6.8: R444.2@1640.49,4462.82 1653.99,4476.31 v1(1653.99,4500.32) 1653.99,4531.01 1646.18,4538.82 U33.16@1641.48,4538.82 ; v1(2184.3,4462.02) 2210.19,4462.02 R443.2@2210.99,4462.82
  Layer 3 - SIG w5: v1(1653.99,4500.32) 1696.24,4542.57 ; 1730.24,4576.57 1738.49,4584.82 1960.99,4584.82 2082.99,4462.82 v1@2180.99,4462.82
  Layer 3 - SIG w6: 1696.24,4542.57 1730.24,4576.57
NetR445_1: R445.1 U17.L20 U33.7 | length 1884.4
  Top Layer w4: 1951.83,4119.32 1987.9,4083.25 1987.9,4063.98 U17.L20@2000.4,4051.48
  Top Layer w6.8: 1951.83,4119.32 1924.55,4146.6 1924.55,4158.73 1811.36,4271.92 1613.2,4271.92 1524.97,4360.15 1524.97,4870.18 1664.8,5010.02 v1(1968.4,5010.02) ; v1@1970,4935.02 R445.1@1998.36,4935.02 ; v1(1970,4935.22) 1953.3,4918.52 1953.3,4875.42 1976.19,4852.53 1976.19,4846.63 1984,4838.82 U33.7@2009.59,4838.82 U33.7@2015.5,4838.82
  Layer 3 - SIG w8: v1(1968.4,5010.02) 1969.2,5009.22 1969.2,4936.02 v1(1970,4935.22)
NetR446_1: R446.1 U17.M20 U34.1 | length 570.7
  Top Layer w4: U17.M20@2020.09,4051.48 2020.09,4052.91 2031.99,4064.82 2031.99,4077.51 2020.09,4089.42 2020.09,4119.32
  Top Layer w6.8: U34.1@1810.36,4406.22 1856.9,4406.22 1876,4387.12 1876,4330.32 2020.09,4186.23 2020.09,4119.32
  Top Layer w20: U34.1@1810.36,4406.22 1805.02,4406.22 1803.2,4408.03 1803.2,4448.38 1814.92,4460.1 1833.15,4460.1 1835.95,4462.89 R446.1@1835.95,4467.82
NetR447_1: R447.1 R448.2 U17.A6 | length 967.1
  Top Layer w4: 1677.25,3784.78 1770.2,3784.78 1779.08,3775.89 U17.A6@1803.55,3775.89
  Top Layer w6.8: v1(1552.87,3767.26) 1559.18,3773.56 1666.03,3773.56 1677.25,3784.78 ; R448.2@1614.4,4363.52 R447.1@1665.21,4363.52 ; v1(1649.3,4325.42) 1649.3,4346.63 1654.81,4352.13 1654.81,4353.12 R447.1@1665.21,4363.52 ; R447.1@1670.49,4367.82 1666.19,4363.52 R447.1@1665.21,4363.52
  Layer 5 - SIG w5: v1(1552.87,3767.26) 1561.15,3767.26 1649.3,3855.42 v1(1649.3,4325.42)
NetR447_2: R447.2 U34.2 | length 77.3
  Top Layer w20: R447.2@1733.49,4367.82 1733.99,4368.32 1809.86,4368.32 U34.2@1810.36,4368.82
NetR449_1: R449.1 U17.P17 | length 305.6
  Top Layer w6: R449.1@1962.71,4191.61 R449.1@1967.31,4187.01 ; R449.1@1966.71,4187.01 R449.1@1967.31,4187.01 ; v1@1978.34,4175.98 R449.1@1967.31,4187.01 ; U17.P17@2059.46,3992.43 v2@2077.55,4010.52
  Layer 3 - SIG w5: v1@1980.34,4173.98 2035.99,4118.33 2035.99,3999.83 2044.37,3991.45 2068.98,3991.45 2077.6,4000.07 v2(2077.6,4011.52)
  other v1: 1980.34,4175.98
NetR449_2: R449.2 R450.2 | length 46.6
  Top Layer w6.8: R450.2@1898,4258.62 1898,4257.47 1929.3,4226.17 R449.2@1929.3,4225.02
NetR450_1: R450.1 U17.M21 | length 273.6
  Top Layer w4: 1962,4156.42 2009.3,4109.12 2009.3,4081.95 U17.M21@2020.09,4071.17
  Top Layer w6.8: R450.1@1867.1,4281.42 1867.1,4258.03 1954.83,4170.31 1954.83,4163.59 1962,4156.42
NetR457_1: R457.1 U18.8 | length 106.4
  Top Layer w9: U18.8@1370.04,4946.72 1408.19,4946.72 1424.69,4963.22 1449.49,4963.22 R457.1@1463.69,4977.42
NetR486_1: R486.1 U29.H8 | length 407.4
  Top Layer w6: v1(1712.66,1329.43) R486.1@1753.23,1329.43
  Layer 12 - SIG w5: v2(1484.6,1183.28) 1484.6,1162.41 1499.15,1147.86 1549.96,1147.86 1575.31,1173.21 1619,1173.21 1634.89,1189.1 1648.85,1203.06 1648.85,1265.62 v1(1712.66,1329.43)
NetR486_2: R486.2 U28.H4 | length 496.3
  Top Layer w6.8: R486.2@1816.23,1329.43 1831.53,1344.73 v1(1853.62,1344.73) ; U28.H4@2149.51,1173 2149.96,1173.45 2149.96,1187.98 v2(2150.41,1188.43)
  Layer 12 - SIG w5: v1(1853.62,1344.73) 1875.72,1322.63 2058.45,1322.63 2073.87,1307.22 2107.51,1307.22 2116.79,1297.93 2142.32,1297.93 2153.11,1287.15 2153.11,1274.3 2134,1255.19 2134,1204.85 v2(2150.41,1188.43)
NetR488_1: R488.1 U17.G2 | length 2588.7
  Top Layer w4: 1909.76,3526.31 1909.76,3584.07 1909.76,3684.21 1921.66,3696.12 U17.G2@1921.66,3697.15
  Top Layer w6.8: R488.1@954,1509.24 954,1556.42 1284.99,1887.42 1284.99,2112.79 1690.64,2518.43 1690.64,3019.55 1804.75,3133.66 1804.75,3380.72 1909.76,3485.74 1909.76,3526.31
NetR492_1: R492.1 U28.H8 | length 427
  Top Layer w6: v1(2574.82,1307.07) R492.1@2615.39,1307.07
  Top Layer w6.8: U28.H8@2251.87,1173 2251.99,1173.12 v2(2251.99,1186.61)
  Layer 12 - SIG w5: v2(2251.99,1186.61) 2252.4,1187.02 2286.09,1187.02 2323.11,1224.03 2372.82,1224.03 2455.85,1307.07 v1(2574.82,1307.07)
NetR492_2: R492.2 U27.H4 | length 543.4
  Top Layer w6: R492.2@2678.38,1307.07 v1(2718.95,1307.07)
  Top Layer w6.8: R492.2@2674.82,1305.3 R492.2@2691.28,1321.77 ; U27.H4@3041.9,1171.33 3042.35,1171.79 3042.35,1186.32 v2(3042.8,1186.77)
  Layer 3 - SIG w5: v1(2718.95,1307.07) 2732.38,1320.5 2974.05,1320.5 2998.83,1295.72 3036.57,1295.72 3049.02,1283.27 3049.02,1254.43 3026.43,1231.85 3026.43,1203.14 v2(3042.8,1186.77)
NetR494_2: R494.2 U30.G6 | length 598.7
  Top Layer w6.8: R494.2@3495.77,1246.14 v1(3532.97,1246.14) ; U30.G6@3860.47,1193.59 3860.78,1193.28 3860.78,1166.45 v2(3861.09,1166.13)
  Layer 3 - SIG w5: v1(3532.97,1246.14) 3594.14,1246.14 3658.6,1310.59 3712.13,1310.59 3746.18,1344.64 3837.73,1344.64 3855.09,1327.28 3855.09,1261.43 3861.09,1255.43 v2(3861.09,1166.13)
NetR496_1: R496.1 U27.F7 | length 403
  Top Layer w6.8: U27.F7@3118.67,1222.51 3119.4,1221.79 3133.66,1221.79 3142.78,1212.67 v2(3144.4,1212.67) ; v1(3393,1368) R496.1@3432.78,1368
  Layer 12 - SIG w5: v2(3144.4,1212.67) 3144.4,1207.68 3160.58,1191.5 3173.42,1191.5 3205.95,1224.03 3249.03,1224.03 3316.95,1291.95 v1(3393,1368)
NetR496_2: R496.2 U30.F5 | length 444.7
  Top Layer w6.8: R496.2@3495.77,1368 v1(3528.69,1368) ; v2(3812.89,1219.03) 3812.97,1219.11 3834.81,1219.11 U30.F5@3834.88,1219.18
  Layer 6 - SIG w5: v1(3528.69,1368) 3581.19,1315.5 3737.13,1315.5 3761.41,1291.23 3803.81,1291.23 3821.2,1273.84 3821.2,1227.46 3812.89,1219.16 v2(3812.89,1219.03)
NetR500_1: R500.1 U27.H8 | length 440.1
  Top Layer w6.8: U27.H8@3144.26,1171.33 3144.26,1184.83 v2(3144.38,1184.95) ; v1(3395.58,1307.07) R500.1@3432.78,1307.07
  Layer 12 - SIG w5: v2(3144.38,1184.95) 3144.38,1167.62 3165.04,1146.96 3202.96,1146.96 3230.88,1174.88 3316.95,1174.88 3341.61,1174.88 3379.08,1212.34 3379.08,1252.97 3379.41,1253.3 3379.41,1255.4 3395.58,1271.57 v1(3395.58,1307.07)
NetR500_2: R500.2 U30.H4 | length 612.9
  Top Layer w6.8: R500.2@3495.77,1307.07 v1(3532.97,1307.07) ; U30.H4@3809.29,1168 3809.74,1168.45 3809.74,1182.98 v2(3810.19,1183.43)
  Layer 3 - SIG w5: v1(3532.97,1307.07) 3497.35,1271.45 3497.35,1234.53 3512.25,1219.63 3595.93,1219.63 3667.52,1291.23 3804.04,1291.23 3833.99,1261.27 3833.99,1207.23 v2(3810.19,1183.43)
NetR504_1: R504.1 U28.F7 | length 525.8
  Top Layer w6: v1(2574.82,1368) R504.1@2615.39,1368
  Top Layer w6.8: U28.F7@2226.28,1224.18 2227.01,1223.45 2241.27,1223.45 2250.39,1214.33 v2(2252.01,1214.33)
  Layer 6 - SIG w5: v2(2252.01,1214.33) 2252.01,1238.31 2239.41,1250.91 2239.41,1279.75 2256.29,1296.63 2269.13,1296.63 2275.33,1290.43 2294.67,1290.43 2303.97,1281.13 2487.95,1281.13 v1(2574.82,1368)
NetR504_2: R504.2 U27.F5 | length 572.1
  Top Layer w6: R504.2@2678.38,1368 v1(2718.95,1368)
  Top Layer w6.8: v2(3045.5,1222.37) 3045.58,1222.44 3067.42,1222.44 U27.F5@3067.49,1222.51
  Layer 3 - SIG w5: v1(2718.95,1368) 2902.43,1368 2916.84,1382.41 2977.2,1382.41 3025.85,1333.76 3066.53,1333.76 3085.47,1314.82 3085.47,1262.33 v2(3045.5,1222.37)
NetR511_1: R511.1 U29.F7 | length 428.1
  Top Layer w6: v1(1712.67,1384.13) 1747.01,1384.13 R511.1@1753.23,1390.36
  Top Layer w6.8: U29.F7@1458.89,1220.85 1459.62,1220.12 1473.88,1220.12 1483,1211 v2(1484.62,1211)
  Layer 14 - SIG w5: v2(1484.62,1211) 1472.02,1223.6 1472.02,1276.77 1489.01,1293.75 1539.34,1293.75 1558.25,1312.67 1639.91,1312.67 1710.68,1383.44 v1@1711.97,1383.44
NetR511_2: R511.2 U28.F5 | length 589.5
  Top Layer w6.8: R511.2@1816.23,1390.36 1966.52,1390.36 v1(1990.22,1366.66) ; v2(2153.11,1224.03) 2153.19,1224.11 2175.03,1224.11 U28.F5@2175.1,1224.18
  Layer 12 - SIG w5: v1(1990.22,1366.66) 2034.31,1366.66 2038.68,1362.29 2062.84,1338.13 2098.31,1338.13 2112.11,1351.93 2190.07,1351.93 2201.31,1340.69 2201.31,1327.17 2190.5,1316.35 2190.5,1237.88 2176.65,1224.03 v2(2153.11,1224.03)
NetR512_1: R512.1 U2.1 | length 58.7
  Bottom Layer w8: R512.1@3444.57,4516.46 3444.57,4569.87 3445.49,4570.79 U2.1@3449.49,4570.79
NetR513_2: R513.2 U17.B7 U25.H4 | length 2744
  Top Layer w4: 1657.49,3806.03 1768.75,3806.03 1778.42,3796.36 1822.46,3796.36 U17.B7@1823.24,3795.58
  Top Layer w6.8: v1(1465.3,3772.42) 1466.45,3773.56 1466.45,3791.06 1481.42,3806.03 1657.49,3806.03 ; v1@1649.9,3536.4 1676.7,3563.2 R513.2@1679.6,3563.2
  Layer 5 - SIG w5: v1(1465.3,3772.42) 1465.3,3685.67 1614.08,3536.9 v1(1649.4,3536.9) 1647.68,3535.18 1647.68,3528.46 1524.42,3405.19 1524.42,2422.46 1594.64,2352.24 1682.04,2352.24 1870.18,2164.09 1881.18,2164.09 2063.62,2164.09 2073.37,2154.33 2073.37,2142.35 2083.13,2132.59 2158.11,2132.59 2167.86,2122.84 2167.86,2101.1 v3(2183.24,2085.72)
NetR514_2: R514.2 U17.B9 U26.H4 | length 3745.8
  Top Layer w4: 1657.9,3851.32 1672.2,3851.32 1678.04,3857.16 1778.61,3857.16 1788.13,3847.63 1810.55,3847.63 U17.B9@1823.24,3834.95
  Top Layer w6.8: v1(1392.5,3822.62) 1421.2,3851.32 1657.9,3851.32 ; v1(1455,3357.71) 1517.33,3420.05 R514.2@1517.33,3421.73
  Layer 3 - SIG w5: v1(1392.5,3822.62) 1371.49,3801.6 1371.49,3441.22 v1(1455,3357.71) 1455,2911 1755.67,2610.33 2078.55,2610.33 2298.3,2390.58 2561.76,2390.58 2591.5,2360.83 3149.95,2360.83 3236.55,2274.23
  Layer 3 - SIG w5.5: 3236.55,2274.23 3252.14,2258.64 3252.14,2101.59 v3(3268.02,2085.72)
NetTP17_1: TP17.1 U12.100 | length 434.8
  Top Layer w6.8: TP17.1@188.7,6080.82 284,6080.82 457,5907.82 551.6,5907.82 U12.100@551.75,5907.67
NetTP18_1: TP18.1 U12.99 | length 481.1
  Top Layer w6.8: TP18.1@188.7,6208.52 190.4,6208.52 475.51,5923.41 U12.99@551.75,5923.41
NetTP19_1: TP19.1 U12.98 | length 575.7
  Top Layer w6.8: TP19.1@188.7,6325.02 311.4,6202.32 311.4,6112.22 484.46,5939.16 U12.98@551.75,5939.16
NetTP20_1: TP20.1 U12.97 | length 686.3
  Top Layer w6.8: TP20.1@188.7,6455.82 189.4,6455.82 341.4,6303.82 341.4,6106.22 492.71,5954.91 U12.97@551.75,5954.91
NetTP36_1: TP36.1 U17.C20 U19.4 | length 1918.1
  Top Layer w4: 1833.22,4097.71 1854.83,4076.1 1854.83,4063.39 U17.C20@1842.92,4051.48
  Top Layer w6.8: U19.4@984.9,5005.31 918.99,5005.31 831.3,4917.62 831.3,4559.42 859,4531.72 1205.2,4531.72 1208.1,4531.72 ; TP36.1@1205.2,4482.92 1205.2,4528.82 1208.1,4531.72 ; 1833.22,4097.71 1819.21,4111.72 1657.49,4111.72 1610.62,4111.72 1558.45,4163.88 1558.45,4277.77 1304.5,4531.72 1208.1,4531.72
NetU12_35: U12.35 U20.13 | length 2733.6
  Top Layer w6.8: v1(363.3,3573.32) 363.3,4644.58 844.64,5125.92 1018.42,5125.92 1255.46,5362.95 1255.46,5457.75 1214.99,5498.22 U12.35@1158.05,5498.22 ; v1(558.4,3572.02) 559.3,3572.91 624.83,3572.91 U20.13@625.72,3573.81
  Layer 3 - SIG w5: v1(363.3,3573.32) 363.95,3572.67 557.75,3572.67 v1(558.4,3572.02)
NetU12_36: U12.36 U20.11 | length 2673.2
  Top Layer w6.8: v1(389.7,3627.59) 390,3627.89 390,4650.07 850.85,5110.92 1024.64,5110.92 1270.46,5356.74 1270.46,5463.96 1220.45,5513.97 U12.36@1158.05,5513.97 ; v1(556.9,3625.32) 557.07,3625.15 625.56,3625.15 U20.11@625.72,3624.99
  Layer 3 - SIG w5: v1(389.7,3627.59) 390.84,3626.45 555.77,3626.45 v1(556.9,3625.32)
NetU12_37: U12.37 U21.7 | length 3022.3
  Top Layer w6.8: v1(406.2,3409.54) 408.35,3411.69 408.35,3418.16 409.32,3419.13 409.32,4648.17 857.06,5095.92 1030.85,5095.92 1285.57,5350.63 1285.57,5470.22 1226.07,5529.71 U12.37@1158.05,5529.71 ; v1(694.84,3413.54) 697.87,3413.54 701.87,3409.54 717.39,3409.54 U21.7@746.29,3409.54
  Layer 3 - SIG w5: v1(406.2,3409.54) 409.45,3409.54 413.45,3413.54 v1(694.84,3413.54)
NetU12_38: U12.38 U20.12 | length 2710.5
  Top Layer w6.8: v1(429.2,3597.32) 429.3,3597.42 429.3,4646.94 863.28,5080.92 1037.06,5080.92 1300.64,5344.49 1300.64,5476.46 1231.64,5545.46 U12.38@1158.05,5545.46 ; v1(574.28,3599.4) U20.12@625.72,3599.4
  Layer 3 - SIG w5: v1(429.2,3597.32) 430.25,3598.36 573.24,3598.36 v1(574.28,3599.4)
NetU12_40: U12.40 U20.10 | length 2665.3
  Top Layer w6.8: v1(449.7,3650.62) 449.7,4646.13 869.49,5065.92 1043.28,5065.92 1315.72,5338.35 1315.72,5482.71 1221.46,5576.96 1202.05,5576.96 U12.40@1158.05,5576.96 ; v1(574.28,3650.58) U20.10@625.72,3650.58
  Layer 3 - SIG w5: v1(449.7,3650.62) v1(574.28,3650.58)
NetU12_42: U12.42 U22.8 | length 3116.4
  Top Layer w6.8: U22.8@731.97,3307.21 U22.8@732.38,3306.81 732.38,3296.97 687.13,3251.72 630.1,3251.72 468.8,3413.02 468.8,4644.02 875.7,5050.92 1049.49,5050.92 1330.72,5332.14 1330.72,5488.92 1211.18,5608.45 U12.42@1158.05,5608.45
NetU12_43: U12.43 U22.1 | length 3152.6
  Top Layer w6.8: v1(673.6,3277.52) 625.52,3277.52 485.6,3417.43 485.6,4639.6 881.92,5035.92 1055.7,5035.92 1350.58,5330.79 1350.58,5497.15 1223.52,5624.2 U12.43@1158.05,5624.2 ; U22.1@732.38,3180.82 732.79,3181.24 732.79,3212.9 v1(733.2,3213.32)
  Layer 3 - SIG w5: v1(673.6,3277.52) 732.06,3219.06 v1@732.06,3214.46
  Layer 3 - SIG w8: v1@732.06,3214.46 v1(733.2,3213.32)
NetU15_4: U15.4 U17.B10 | length 993.5
  Top Layer w4: 1657.9,3866.32 1781.19,3866.32 1792.87,3854.63 U17.B10@1823.24,3854.63
  Top Layer w6.8: U15.4@854.75,3817.52 1283.51,3817.52 1330.21,3864.22 1412.9,3864.22 1414.99,3866.32 1657.49,3866.32 1657.9,3866.32
NetU17_A8: U17.A8 U25.H9 U26.H9 | length 5580.7
  Top Layer w4: 1657.9,3836.03 1745.2,3836.03 1757.02,3824.21 1782.48,3824.21 1790.18,3816.52 1802.3,3816.52 U17.A8@1803.55,3815.26
  Top Layer w6.8: v1(1410.5,3771.72) 1410.5,3800.02 1446.52,3836.03 1657.49,3836.03 1657.9,3836.03
  Layer 3 - SIG w5: v1(1410.5,3771.72) 1396.49,3757.7 1396.49,3451.58 1486,3362.07 1486,2932.56 1773.56,2645 2095.92,2645 2325.34,2415.58 2590.12,2415.58 2608.96,2396.73 v1(2634.15,2396.73)
  Layer 5 - SIG w5: v1(1410.5,3771.72) 1343.64,3704.85 1343.64,2616.93 1406.82,2553.75 1406.82,2352.24 1528.67,2230.39 1737.43,2230.39 1866.35,2101.47 2010.01,2101.47 v3(2025.76,2085.72) ; v1(2634.15,2396.73) 2634.15,2337.31 2747.27,2224.19 2747.27,2154.2 2779.79,2121.69 2866.18,2121.69 2886.27,2101.59 3094.66,2101.59 v3(3110.54,2085.72)
NetU17_A17: U17.A17 U25.J12 U26.J12 | length 5641.3
  Top Layer w4: 1777.6,4039.12 1789.9,4026.82 1789.9,4006.08 U17.A17@1803.55,3992.43
  Top Layer w6.8: v1(1553.5,4043.12) 1557.5,4039.12 1777.6,4039.12
  Layer 3 - SIG w5: v1@1551.07,4039.12 v1@1553.5,4039.12 ; v1(1553.5,4043.12) 1549,4047.62 1516.85,4047.62 1492.21,4022.97 1418.56,4022.97 1263.4,3867.82 1263.4,2919.82 1899.19,2284.03 1899.19,2178.16 1931.27,2146.08 v3(1931.27,2117.22) ; v1(2889.15,2280.7) 2889.15,2244.11 v3(3016.05,2117.22)
  Layer 5 - SIG w5: v1(1553.5,4043.12) 1567.53,4043.12 1582.07,4028.58 1582.07,3921 1527.15,3866.08 1527.15,3762.04 1559.36,3729.83 1580.26,3729.83 1612.88,3697.21 1657.15,3697.21 1781.69,3572.67 1781.69,3556.3 1955.16,3382.84 1955.16,3354.97 1983.41,3326.73 2542.74,3326.73 2771.52,3097.94 2771.52,3049.96 2758.52,3036.96 2758.52,2411.33 v1(2889.15,2280.7)
NetU17_B8: U17.B8 U25.H6 U26.H6 | length 5808.8
  Top Layer w4: 1657.49,3821.03 1658.88,3822.42 1688.52,3822.42 1696.2,3814.74 1773.72,3814.74 1785.11,3803.36 1811.33,3803.36 U17.B8@1823.24,3815.26
  Top Layer w6.8: v1(1439,3751.22) 1439,3784.83 1475.2,3821.03 1657.49,3821.03
  Layer 3 - SIG w5: v1(1439,3751.22) 1421.49,3733.7 1421.49,3475.44 1516.85,3380.07 1516.85,2958.22 1768.59,2706.48 2121.14,2706.48 2345.13,2482.49 2573,2482.49 2633.75,2421.73 v1@2634.05,2421.73
  Layer 5 - SIG w5: v1(1439,3751.22) 1403.3,3715.52 1403.3,3363.59 1492.04,3274.85 1492.04,2547.04 1447,2502 1447,2353 1481.41,2318.59 1677.51,2318.59 1863.01,2133.09 1943.99,2133.09 2063.62,2132.59 2073.37,2122.84 2073.37,2110.85 2083.13,2101.1 2104.87,2101.1 v3(2120.24,2085.72) ; v1(2634.05,2421.43) 2613.97,2421.43 2603.7,2411.16 2603.7,2318.59 2701.57,2220.71 2701.57,2121.69 2787.26,2036 2944.38,2036 2978.71,2070.33 3189.63,2070.33 v3(3205.02,2085.72)
NetU17_B15: U17.B15 U25.G4 U26.G4 | length 6525.2
  Top Layer w4: v1(1550.5,4004.12) v1@1551.9,4005.52 ; 1737.6,4005.52 1777.38,3965.74 1810.55,3965.74 U17.B15@1823.24,3953.06
  Top Layer w6.8: v1@1551.9,4005.52 1737.6,4005.52
  Layer 3 - SIG w5: v1(1550.5,4004.12) 1504.2,3957.82 1450.88,3957.82 1313.4,3820.34 1313.4,2965.6 1732.57,2546.43 2060.08,2546.43 2346.26,2260.25 2346.26,2144.06 2272.55,2070.35 2199.36,2070.35 v3(2183.24,2054.23)
  Layer 5 - SIG w5: v1(1550.5,4004.12) 1529.71,3983.32 1499.55,3983.32 1469.7,3953.47 1469.7,3839.82 1507.15,3802.37 1507.15,3752.56 1733.4,3526.31 1762.16,3526.31 1915.78,3372.69 1915.78,3348.38 2009.07,3255.1 2522.46,3255.1 2657.98,3119.58 2657.98,3041.98 2729,2970.96 2729,2397.55 2961.96,2164.59 3355.87,2164.59 3382.75,2137.71 3382.75,2115.37 3337.73,2070.35 3324.33,2070.35 3324.08,2070.1 3283.89,2070.1 v3(3268.02,2054.23)
NetU17_B16: U17.B16 U25.J1 U26.J1 | length 6361.8
  Top Layer w4: 1733.38,4022.62 1783.25,3972.74 U17.B16@1823.24,3972.74
  Top Layer w6.8: v1(1527.2,4022.62) 1733.38,4022.62
  Layer 3 - SIG w5: v1(1527.2,4022.62) 1502.56,3997.97 1434.26,3997.97 1288.4,3852.12 1288.4,2945.09 1747.49,2486 2044.82,2486 2312.98,2217.84 2312.98,2152.48 v3(2277.72,2117.22)
  Layer 5 - SIG w5: v1(1527.2,4022.62) 1464.6,4022.62 1426.39,3984.41 1426.39,3854.85 1486.36,3794.88 1486.36,3697.7 1557.87,3626.19 1558.32,3626.19 1606.13,3578.38 1643.43,3578.38 1678.55,3543.25 1678.55,3437.53 1912.58,3203.51 2505.43,3203.51 2613.55,3095.39 2613.55,2478.69 2676.23,2416.01 2676.23,2406.64 2949.79,2133.09 3022.62,2133.09 3022.87,2132.84 3072.57,2132.84 3305.98,2132.84 3346.88,2132.84 v3(3362.5,2117.22)
NetU17_C9: U17.C9 U25.H12 U26.H12 | length 6429.8
  Top Layer w4: v2(1843.02,3853.72) v2(1843.02,3853.72)
  Top Layer w6.8: U17.C9@1842.97,3835 v2(1843.02,3853.72)
  Layer 3 - SIG w5: v2@1843.22,3853.91 v2(1843.02,3853.72) 1807.97,3818.67 1512.7,3818.67 1477.05,3854.32 1388.85,3854.32 1346.49,3811.96 1346.49,2975.73 1742.22,2580 2064.77,2580 2287.9,2356.88 2552.75,2356.88 2583.63,2326 2748.33,2326 2988.6,2085.72 v3(3016.05,2085.72) ; v2@1845,3854 1845.28,3853.72 1868.99,3853.72 1877,3861.72 1877,3876.79 1863,3890.79 1863,3902 1850.97,3914.03 1684.52,3914.03 1597.03,4001.52 1597.03,4061.97 1584,4075 1506,4075 1482,4051 1387,4051 1233.68,3897.68 1233.68,2897.97 1860,2271.65 1860,2155.82 1930.1,2085.72 v3(1931.27,2085.72)
NetU17_L19: U17.L19 U33.15 | length 1198
  Top Layer w6: v1(1593.99,4580.82) 1633.48,4580.82 U33.15@1641.48,4588.82 ; v2(1980.99,4031.82) U17.L19@2000.4,4031.8
  Layer 3 - SIG w5: 1593.99,4418.82 v2(1980.99,4031.82) ; 1593.99,4557.83 v1(1593.99,4580.82)
  Layer 3 - SIG w6: 1593.99,4418.82 1593.99,4421.82 ccw(c1585.99,4421.82) 1585.99,4429.82 1564.32,4429.82 cw(c1564.32,4437.82) 1564.32,4445.82 1626.07,4445.82 ccw(c1626.07,4453.82) 1626.07,4461.82 1564.32,4461.82 cw(c1564.32,4469.82) 1564.32,4477.82 1626.07,4477.82 ccw(c1626.07,4485.82) 1626.07,4493.82 1564.32,4493.82 cw(c1564.32,4501.82) 1564.32,4509.82 1626.07,4509.82 ccw(c1626.07,4517.82) 1626.07,4525.82 1601.99,4525.82 cw(c1601.99,4533.82) 1593.99,4533.82 1593.99,4557.83
NetU17_L21: U17.L21 U33.9 | length 1219.3
  Top Layer w4: 1973.05,4119.32 2000.4,4091.96 U17.L21@2000.4,4071.17
  Top Layer w6: U33.9@1615.89,4888.82 U33.9@1641.48,4888.82
  Top Layer w6.8: 1569.7,4713.72 1569.7,4350.32 1626.6,4293.42 1810.79,4293.42 1940.03,4164.18 1940.03,4152.34 1973.05,4119.32 ; 1569.7,4798.42 1569.7,4842.63 U33.9@1615.89,4888.82
  Top Layer w8: 1569.7,4713.72 1569.7,4717.72 ccw(c1560.7,4717.72) 1560.7,4726.72 1554,4726.72 cw(c1554,4735.72) 1554,4744.72 1582.9,4744.72 ccw(c1582.9,4753.72) 1582.9,4762.72 1578.7,4762.72 cw(c1578.7,4771.72) 1569.7,4771.72 1569.7,4798.42
NetU17_N1: U17.N1 U29.H4 | length 3074.6
  Top Layer w6.8: v1(1343.95,1768.53) 1343.95,2124.86 1904.75,2685.66 1904.75,3343.56 1973.05,3411.86 1973.05,3610.74 U17.N1@2039.77,3677.47 ; U29.H4@1382.12,1169.67 1382.57,1170.12 1382.57,1184.65 v2(1383.02,1185.1)
  Layer 6 - SIG w5: v1(1343.95,1768.53) 1377.9,1802.48 1414.3,1802.48 1428.8,1787.98 1428.8,1744 1388.32,1703.52 1388.32,1520.87 1533,1376.19 1533,1311.78 1514.52,1293.3 1488.9,1293.3 1383.02,1187.42 v2(1383.02,1185.1)
NetU17_N3: U17.N3 U29.F5 | length 2881.3
  Top Layer w6.8: v2(1385.72,1220.7) 1385.8,1220.78 1407.64,1220.78 U29.F5@1407.71,1220.85 ; v1(1403.89,1768.53) 1403.89,2138.86 2004.24,2739.21 2004.24,3457.07 v1(2035.15,3487.97) ; U17.N3@2039.77,3716.84 v2(2060.69,3716.84)
  Layer 3 - SIG w5: v1(2035.15,3487.97) 2035.15,3691.3 v2(2060.69,3716.84)
  Layer 6 - SIG w5: v2(1385.72,1220.7) 1442.92,1277.9 1442.92,1369.54 1443.92,1370.54 1421.5,1392.96 1421.5,1417.59 1368.32,1470.77 1368.32,1732.96 v1(1403.89,1768.53)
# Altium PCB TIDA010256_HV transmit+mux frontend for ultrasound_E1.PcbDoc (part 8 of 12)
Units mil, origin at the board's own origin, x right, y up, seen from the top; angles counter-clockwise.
Board outline 6192.49 x 6712.23 mil, 16 copper layers (Top Layer, Layer 2 - GND, Layer 3 - SIG, Layer 4 - GND, Layer 5 - SIG, Layer 6 - SIG, Layer 7 - GND, Layer 8 - HV PWR, Layer 9 - LV PWR, Layer 10 - GND, Layer 11 - SIG, Layer 12 - SIG, Layer 13 - GND, Layer 14 - SIG, Layer 15 - GND, Bottom Layer), stack 95.905 mil thick; 806 components, 539 nets, 3343 pads, 1848 vias.

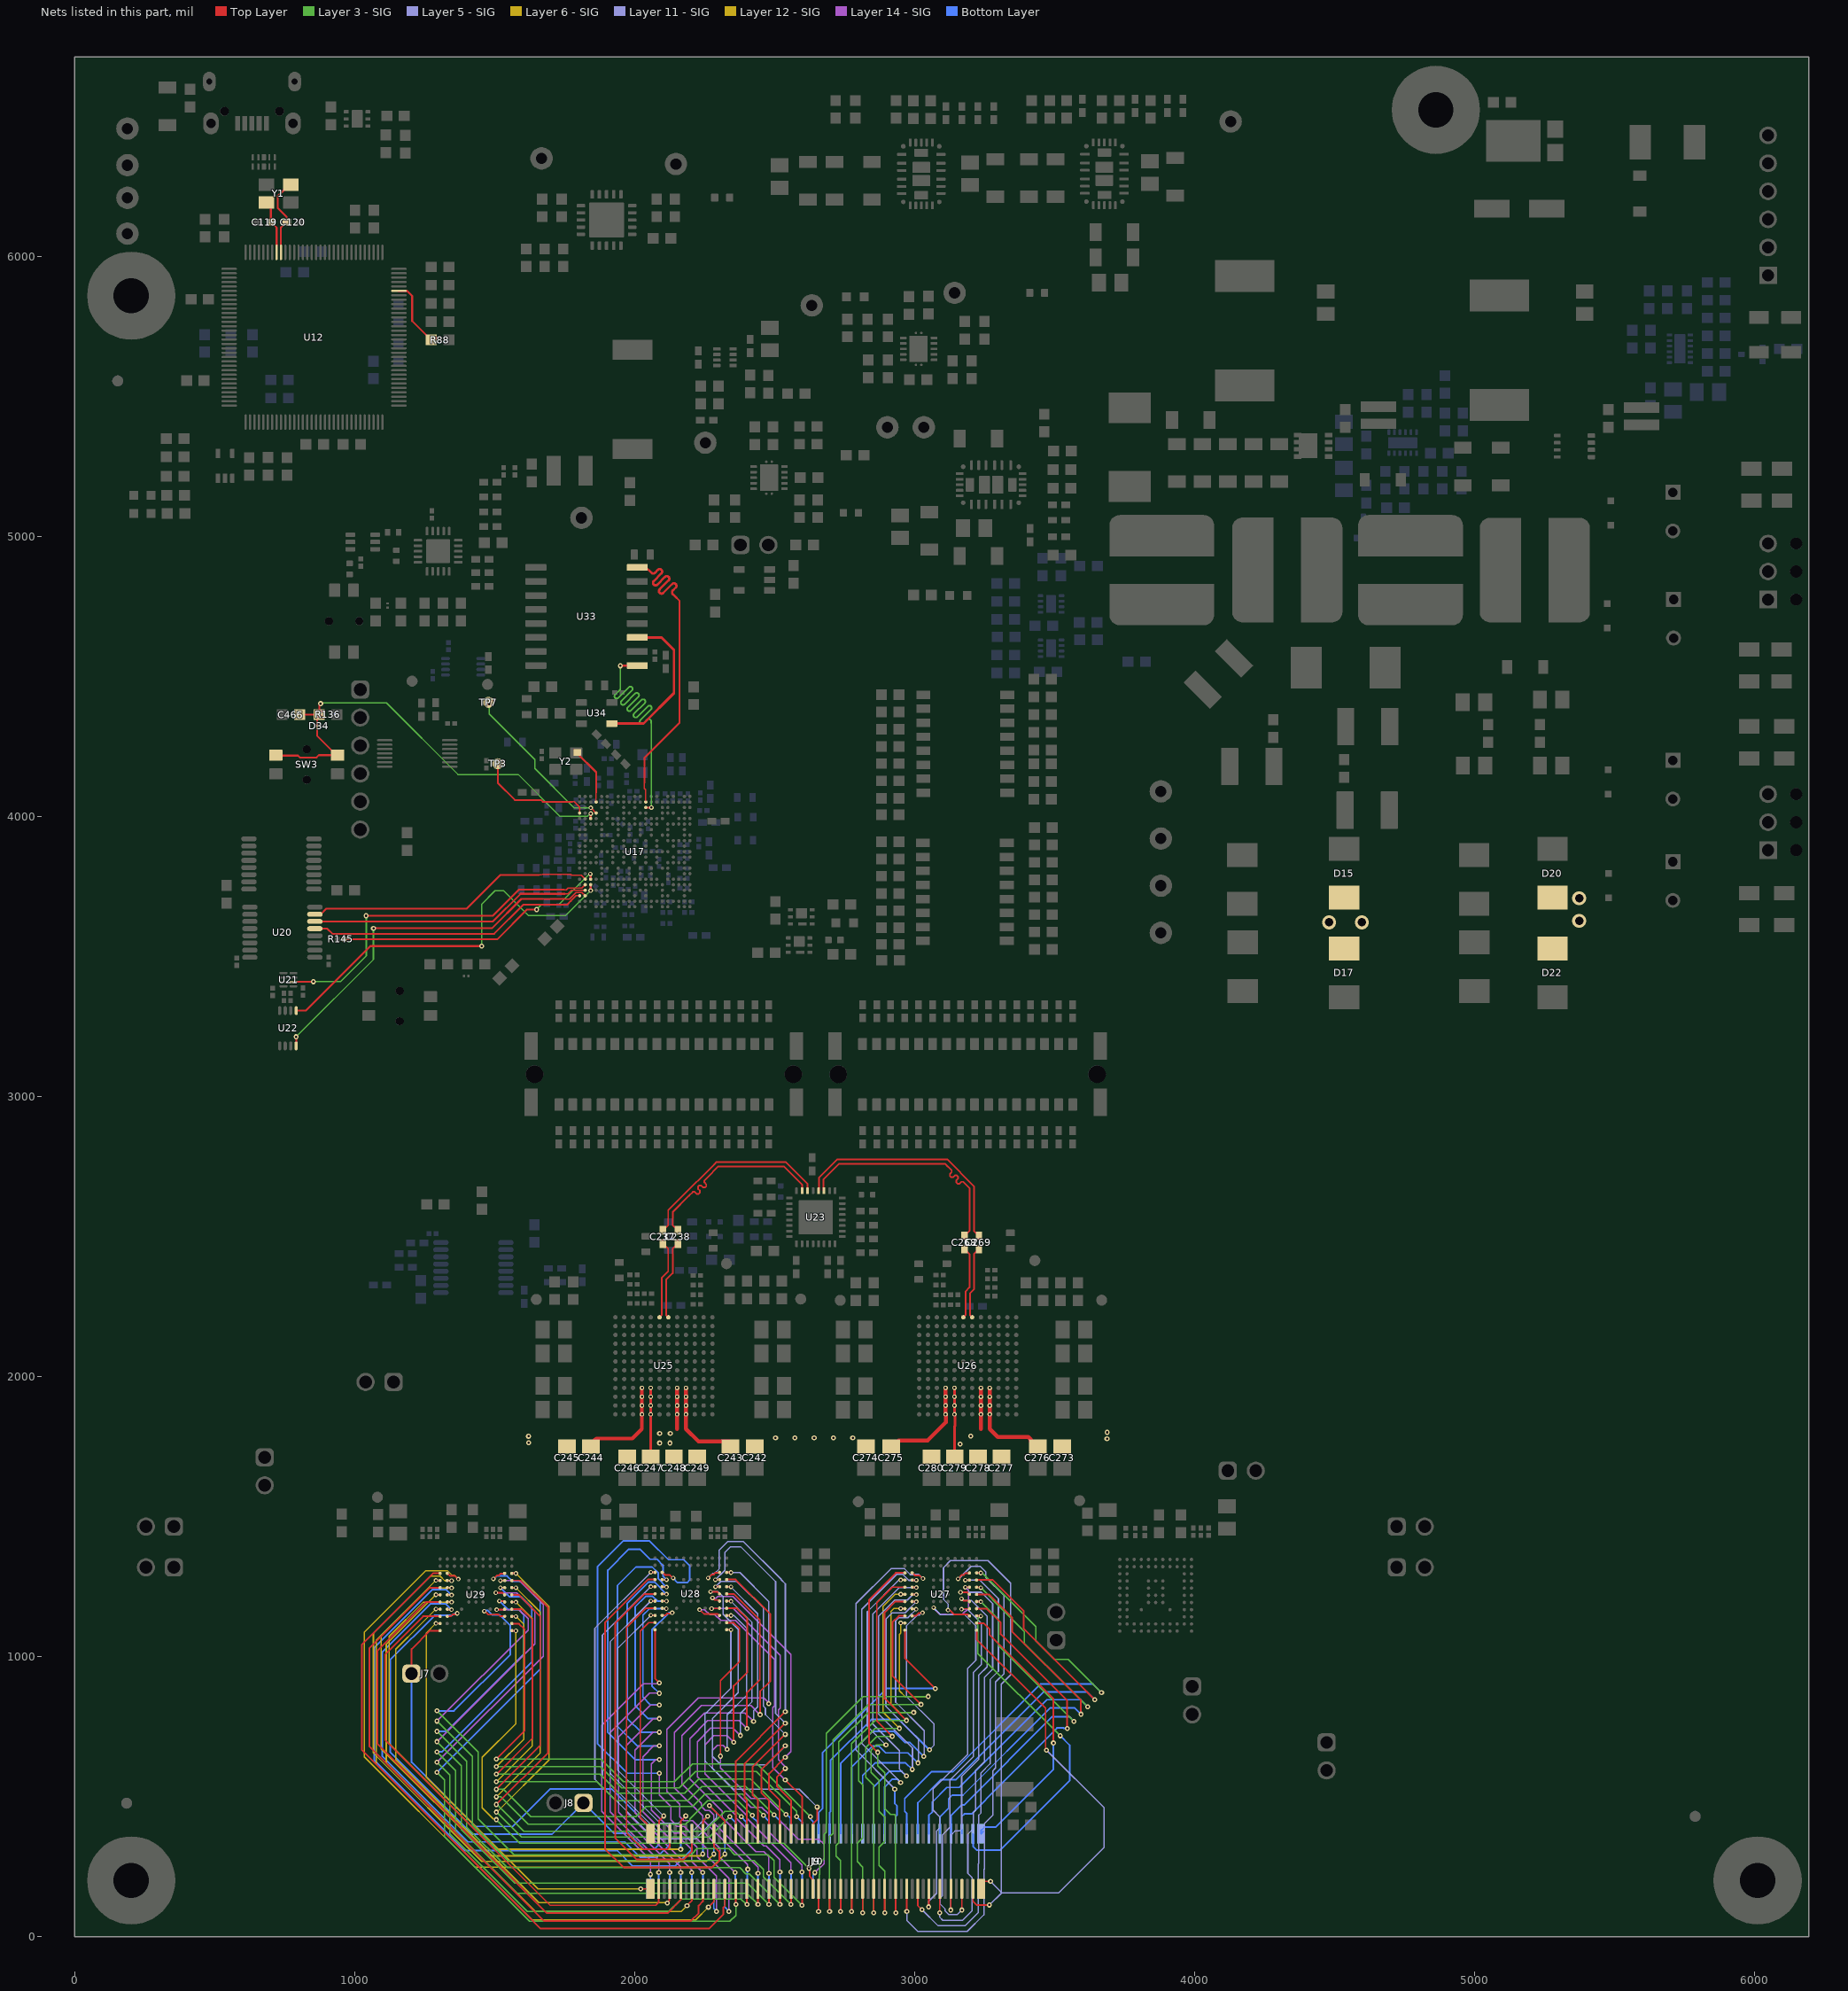
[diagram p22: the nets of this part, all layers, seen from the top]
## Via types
v1: diameter 18, hole 8, Top Layer to Bottom Layer, tented both sides, 930 vias
v2: diameter 16, hole 8, Top Layer to Bottom Layer, tented both sides, 340 vias
v3: diameter 16, hole 8, Top Layer to Bottom Layer, tented bottom, 226 vias
v4: diameter 20, hole 10, Top Layer to Bottom Layer, tented both sides, 129 vias
v5: diameter 50, hole 30, Top Layer to Bottom Layer, tented both sides, 96 vias
v6: diameter 30, hole 15, Top Layer to Bottom Layer, tented both sides, 47 vias
v7: diameter 19.68, hole 7.87, Top Layer to Bottom Layer, 40 vias
v8: diameter 19.68, hole 7.87, Top Layer to Bottom Layer, tented both sides, 19 vias
v9: diameter 18, hole 8, Top Layer to Bottom Layer, tented bottom, 13 vias
v10: diameter 40, hole 20, Top Layer to Bottom Layer, tented both sides, 4 vias
v11: diameter 40, hole 20, Top Layer to Bottom Layer, 3 vias
v12: diameter 18, hole 8, Top Layer to Bottom Layer, 1 vias

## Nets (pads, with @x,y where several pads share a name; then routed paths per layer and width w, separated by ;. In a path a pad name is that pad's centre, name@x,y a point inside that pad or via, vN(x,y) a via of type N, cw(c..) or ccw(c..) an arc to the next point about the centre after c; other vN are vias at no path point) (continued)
NetU17_N19: U17.N19 U33.1 | length 1196.1
  Top Layer w6: U33.1@2014.5,4537.82 U33.1@2015.5,4538.82
  Top Layer w6.8: v1(1948.9,4537.72) 1949.45,4538.27 2014.05,4538.27 U33.1@2014.5,4537.82 ; U17.N19@2039.77,4031.8 v2@2059.18,4031.79
  Layer 3 - SIG w5: 1948.99,4486.32 v1@1948.99,4537.82 ; v2@2059.19,4031.78 2059.19,4333.12
  Layer 3 - SIG w6: 1948.99,4486.32 1948.99,4456.76 cw(c1940.99,4456.76) 1946.65,4451.1 1930.17,4434.62 ccw(c1935.82,4428.96) 1930.17,4423.31 ccw(c1935.82,4428.96) 1941.48,4423.31 1979.27,4461.09 cw(c1984.93,4455.44) 1990.58,4461.09 cw(c1984.93,4455.44) 1990.58,4449.78 1952.8,4411.99 ccw(c1958.45,4406.34) 1952.8,4400.68 ccw(c1958.45,4406.34) 1964.11,4400.68 2001.9,4438.47 cw(c2007.55,4432.81) 2013.21,4438.47 cw(c2007.55,4432.81) 2013.21,4427.15 1975.42,4389.37 ccw(c1981.08,4383.71) 1975.42,4378.05 ccw(c1981.08,4383.71) 1986.74,4378.05 2024.52,4415.84 cw(c2030.18,4410.18) 2035.84,4415.84 cw(c2030.18,4410.18) 2035.84,4404.53 1998.05,4366.74 ccw(c2003.71,4361.08) 1998.05,4355.42 ccw(c2003.71,4361.08) 2009.36,4355.42 2047.15,4393.21 cw(c2052.81,4387.56) 2058.47,4393.21 cw(c2052.81,4387.56) 2058.47,4381.9 2020.68,4344.11 ccw(c2026.33,4338.45) 2020.68,4332.8 ccw(c2026.33,4338.45) 2031.99,4332.8 2044.34,4345.15 cw(c2050,4339.49) 2055.66,4345.15 2059.19,4341.62 2059.19,4333.12
  other v2: 2059.69,4031.78
NetU17_N20: U17.N20 U33.8 | length 1224.4
  Top Layer w4: 2035.09,4119.32 2035.09,4100.03 2039.77,4095.35 U17.N20@2039.77,4051.48
  Top Layer w6.8: U33.8@2015.5,4888.82 2041.09,4888.82 2057.05,4872.86 ; 2035.09,4119.32 2035.09,4209.7 2160.4,4335.02 2160.4,4769.5 2149.35,4780.56
  Top Layer w8: 2057.05,4872.86 2059.88,4870.03 ccw(c2066.24,4876.39) 2072.6,4870.03 2083.01,4880.43 cw(c2089.37,4874.07) 2095.73,4880.43 cw(c2089.37,4874.07) 2095.73,4867.7 2068.26,4840.23 ccw(c2074.63,4833.87) 2068.26,4827.51 ccw(c2074.63,4833.87) 2080.99,4827.51 2108.46,4854.98 cw(c2114.83,4848.61) 2121.19,4854.98 cw(c2114.83,4848.61) 2121.19,4842.25 2089.57,4810.63 ccw(c2095.94,4804.27) 2089.57,4797.91 ccw(c2095.94,4804.27) 2102.3,4797.9 2133.92,4829.52 cw(c2140.28,4823.16) 2146.65,4829.52 cw(c2140.28,4823.16) 2146.65,4816.79 2136.24,4806.39 ccw(c2142.61,4800.03) 2136.24,4793.66 2149.35,4780.56
NetU33_3: U33.3 U34.4 | length 564.4
  Top Layer w9: U34.4@1918.62,4331.41 2031.59,4331.41 2140.49,4440.32 2140.49,4576.41 2140.5,4594.22 2095.9,4638.82 U33.3@2015.5,4638.82
OSC0: C120.1 U12.88 Y1.3 | length 255.9
  Top Layer w6.8: U12.88@736.86,6037.53 736.86,6102.75 756.12,6122.02 C120.1@760.06,6122.02 ; C120.1@756.58,6125.5 756.58,6141.14 747.8,6149.92 725.7,6172.02 725.7,6214.13 Y1.3@766.78,6255.21
OSC1: C119.1 U12.89 Y1.1 | length 193.1
  Top Layer w6.8: Y1.1@685.09,6192.22 700.83,6176.48 C119.1@700.83,6121.62 ; C119.1@701.73,6121.72 721.3,6102.14 721.3,6037.72 721.05,6037.46 U12.89@721.05,6013.97
PHV_A: C242.1 C243.1 C244.1 C245.1 C273.1 C274.1 C275.1 C276.1 D15.1 D17.1 U25.A4 U25.A9 U25.B4 U25.B9 U25.C4 U25.C9 U25.D4 U25.D9 U26.A4 U26.A9 U26.B4 U26.B9 U26.C4 U26.C9 U26.D4 U26.D9 | length 1416.3
  Top Layer w14: C244.1@1830.86,1750.53 1837.36,1750.53 1857.36,1770.53 1857.36,1772.98 1863.22,1778.84 1991.54,1778.84 2025.76,1813.06 v3(2025.76,1865.25) v3(2025.76,1896.75) v3(2025.76,1928.24) v3(2025.76,1959.74) ; 2183.24,1813.06 v3(2183.24,1865.25) v3(2183.24,1896.75) v3(2183.24,1928.24) v3(2183.24,1959.74) ; 2183.24,1813.3 2228,1768.53 2336.86,1768.53 C243.1@2354.86,1750.53 ; C275.1@2915.64,1750.53 2922.14,1750.53 2942.14,1770.53 2942.14,1771.95 3046,1771.95 3111.04,1836.98 3111.04,1864.75 v3(3110.54,1865.25) v3(3110.54,1896.75) v3(3110.54,1928.24) v3(3110.54,1959.74) ; 3268.02,1813.06 v3(3268.02,1865.25) v3(3268.02,1896.75) v3(3268.02,1928.24) v3(3268.02,1959.74) ; 3268.02,1813.3 3296.97,1784.34 3405.84,1784.34 3415.14,1775.03 3415.14,1768.53 3433.14,1750.53 C276.1@3439.64,1750.53
  other v1: 1621.25,1763.93 3686.7,1778 2503.24,1781.33 2572.09,1781.33 2640.94,1781.33 2709.79,1781.33 2778.64,1781.33 1620.95,1786.93 3687,1801
  other v5: 4479.49,3621.68 4596.99,3621.68
PHV_B: C246.1 C247.1 C248.1 C249.1 C277.1 C278.1 C279.1 C280.1 D20.1 D22.1 U25.A5 U25.A8 U25.B5 U25.B8 U25.C5 U25.C8 U25.D5 U25.D8 U26.A5 U26.A8 U26.B5 U26.B8 U26.C5 U26.C8 U26.D5 U26.D8 | length 803.3
  Top Layer w10: C247.1@2057.08,1713.9 2057.25,1714.07 v3(2057.25,1865.25) v3(2057.25,1896.75) v3(2057.25,1928.24) v3(2057.25,1959.74) ; v3(3142.03,1959.74) v3(3142.03,1928.24) v3(3142.03,1896.75) v3(3142.03,1865.25) 3144.04,1863.24 3144.04,1823.31 3142.03,1821.31 3142.03,1715.05 C279.1@3143.18,1713.9
  Top Layer w14: C248.1@2140.41,1713.9 C248.1@2151.74,1725.23 ; 2151.74,1813.06 v3(2151.74,1865.25) v3(2151.74,1896.75) v3(2151.74,1928.24) v3(2151.74,1959.74) ; 3236.52,1813.06 v3(3236.52,1865.25) v3(3236.52,1896.75) v3(3236.52,1928.24) v3(3236.52,1959.74)
  other v1: 3162,1759 2089,1763 2126,1763 3200,1788 2089,1797 2127,1797
  other v5: 5372.89,3627.01 5372.89,3708.08
PORz_OUT: TP7.1 U17.D18 | length 582.3
  Top Layer w6: v2@1843.8,4030.92 U17.D18@1862.61,4012.11
  Layer 3 - SIG w5: v1(1480.5,4401.22) 1480.5,4366.23 1643.55,4203.19 1643.55,4170.95 1783.58,4030.92 v2(1843.4,4030.92)
RBIAS: R88.2 U12.59 | length 240.8
  Top Layer w6.8: U12.59@1158.05,5876.17 1187.35,5876.17 1205.3,5858.22 1205.3,5768.82 1273.01,5701.12 R88.2@1274,5701.12
SOC_CLKIN: U17.D20 Y2.3@1795.33,4228.81 | length 206
  Top Layer w4: U17.D20@1862.61,4051.48 1862.61,4085.4
  Top Layer w6.8: Y2.3@1791.39,4226.84 1793.36,4226.84 1862.61,4157.6 1862.61,4085.4
SOC_EMU0: U17.C5 U22.5 | length 1410.3
  Top Layer w6.8: U22.5@791.43,3306.81 825.89,3306.81 1056,3536.92 v1(1453.6,3536.92) ; v2(1842.92,3735.29) U17.C5@1842.92,3756.21
  Layer 3 - SIG w5: v1(1453.6,3536.92) 1453.6,3686.52 1501.6,3734.52 1532.5,3734.52 1620.3,3646.72 1754.35,3646.72 v2(1842.92,3735.29)
SOC_EMU1: U17.B3 U22.4 | length 1348
  Top Layer w4: 1750.82,3705.32 1766.59,3705.32 1790.02,3728.74 1811.33,3728.74 U17.B3@1823.24,3716.84
  Top Layer w6.8: U22.4@791.43,3180.82 v1(791.43,3213.32) ; v1(1067.2,3600.52) 1490.64,3600.52 1595.44,3705.32 1750.82,3705.32
  Layer 3 - SIG w5: v1(791.43,3213.32) 1067.2,3489.09 v1(1067.2,3600.52)
SoC_RESET_REQz: C466.1 D34.2 R136.2 SW3.2 SW3.4 U17.C17 | length 1661.4
  Top Layer w4: U17.C17@1842.92,3992.43 U17.C17@1843.11,3992.62
  Top Layer w6.8: SW3.2@718.57,4218.6 719.86,4217.3 797.75,4217.3 804.55,4210.5 864.11,4210.5 872.2,4218.6 SW3.4@935.1,4218.6 ; C466.1@804.2,4363.32 R136.2@873.61,4363.32 ; v1(878.7,4402.82) 878.7,4401.19 874.01,4396.5 R136.2@874.01,4363.72 R136.2@873.61,4363.32 ; SW3.4@939.04,4218.6 SW3.4@935.1,4218.6 ; U17.C17@1843.11,3992.62 v2@1843.11,4010.73 ; R136.2@873.61,4363.32 865.85,4355.56 D34.2@865.85,4323.12 865.85,4287.85 SW3.4@935.1,4218.6
  Layer 3 - SIG w5: v1@886.4,4405.12 1113.9,4405.12 1369.3,4149.72 1570.98,4149.72 1584.27,4149.72 1733.3,4000.69 1831.1,4000.69 1840.33,4009.92 v2(1843.3,4009.92)
SOC_SYNC_OUT: TP3.1 U17.A18 | length 417.7
  Top Layer w4: 1777.1,4052.32 1785.04,4052.32 1803.55,4033.8 U17.A18@1803.55,4012.11
  Top Layer w6.8: TP3.1@1511.3,4188.02 1511.3,4119.98 1572.57,4058.72 1657.49,4058.72 1665.2,4058.72 1671.6,4052.32 1777.1,4052.32
SOC_TCK: R145.1 U17.C6 | length 994.8
  Top Layer w6.8: R145.1@963.79,3561.12 1508.9,3561.12 1615.31,3667.53 v1(1649.61,3667.53) ; U17.C6@1842.96,3775.93 v2@1842.96,3794.68
  Layer 3 - SIG w5: v1(1649.61,3667.53) 1657.9,3675.81 1668.1,3686.02 1729.51,3686.02 1834.64,3791.14 1836.44,3791.14 1840.01,3794.72 v2@1842.99,3794.72
  other v2: 1841.99,3794.72
SOC_TDI: U17.A3 U20.5 | length 1009.6
  Top Layer w4: 1771.92,3697.92 1790.84,3716.84 U17.A3@1803.55,3716.84
  Top Layer w6.8: U20.5@858,3599.4 901.92,3599.4 920.5,3580.82 1498.4,3580.82 1602.51,3684.93 1758.93,3684.93 1771.92,3697.92
SOC_TDO: U17.B5 U21.2 | length 1271
  Top Layer w4: 1747.8,3737.82 1755.8,3737.82 1762.29,3744.3 1811.33,3744.3 U17.B5@1823.24,3756.21
  Top Layer w6: U21.2@781.72,3409.54 781.86,3409.68 852.87,3409.68 v1(853,3409.82)
  Top Layer w6.8: v1(1040.7,3645.32) 1493.02,3645.32 1586.52,3738.82 1747.8,3738.82
  Layer 3 - SIG w5: v1(853,3409.82) 949.5,3409.82 1041.9,3502.22 1041.9,3644.12 v1(1040.7,3645.32)
SOC_TMS: U17.B4 U20.6 | length 1011.4
  Top Layer w4: 1750.8,3723.82 1761.69,3723.82 1774.4,3736.52 U17.B4@1823.24,3736.52
  Top Layer w6.8: U20.6@858,3624.99 1493.9,3624.99 1592.73,3723.82 1750.8,3723.82
SOC_TRST#: U17.B6 U20.7 | length 1032
  Top Layer w4: 1657.9,3791.03 1667.02,3791.03 1669.81,3793.83 1771.05,3793.83 1775.52,3789.36 1809.77,3789.36 U17.B6@1823.24,3775.89
  Top Layer w6.8: U20.7@858,3650.58 879.21,3650.58 899.15,3670.52 1400,3670.52 1520.52,3791.03 1657.9,3791.03
TX1_CLK_N: C238.2 U23.7 | length 706.4
  Top Layer w6.1: C238.2@2154.23,2522.66 2135.73,2541.16 2135.73,2587.15 2194.36,2645.78 2207.9,2659.32 2214.73,2659.32 2221.73,2652.32 2228.56,2652.32 2233.12,2656.88 2233.12,2663.71 2226.12,2670.71 2226.12,2677.54 2230.67,2682.09 2237.5,2682.09 2244.5,2675.09 2251.33,2675.09 2255.89,2679.65 2255.89,2686.48 2248.89,2693.48 2248.89,2700.31 2258.36,2709.78 2298.99,2750.41 2532.64,2750.41 2597.67,2685.38 U23.7@2597.67,2663.22
TX1_CLK_P: C237.2 U23.6 | length 705.4
  Top Layer w6.1: C237.2@2101.23,2522.66 2119.73,2541.16 2119.73,2593.78 2160.64,2634.68 2285.51,2759.56 2292.36,2766.41 2539.27,2766.41 2617.36,2688.32 U23.6@2617.36,2663.22
TX1_CLKIN_N: C238.1 U25.M6 | length 284.2
  Top Layer w6.1: U25.M6@2120.24,2211.71 2112.5,2219.45 2112.5,2345.87 2135.73,2369.11 2135.73,2456.91 C238.1@2154.23,2475.41
TX1_CLKIN_P: C237.1 U25.M7 | length 284.2
  Top Layer w6.1: U25.M7@2088.75,2211.71 2096.5,2219.45 2096.5,2352.5 2119.73,2375.74 2119.73,2456.91 C237.1@2101.23,2475.41
TX2_CLK_N: C269.2 U23.4 | length 852.5
  Top Layer w6.1: U23.4@2656.73,2663.22 2657.67,2664.17 2657.67,2709.86 2723.47,2775.66 3115.61,2775.66 3211.85,2679.42 3211.85,2520.03 C269.2@3229.35,2502.53
TX2_CLK_P: C268.2 U23.3 | length 852.7
  Top Layer w6.1: U23.3@2676.41,2663.22 2673.67,2665.96 2673.67,2703.23 2730.1,2759.66 3108.98,2759.66 3118.64,2750 3120.79,2747.85 3132.18,2736.46 3132.18,2729.63 3125.73,2723.18 3125.73,2716.35 3130.28,2711.8 3137.11,2711.8 3143.56,2718.25 3150.39,2718.25 3154.95,2713.69 3154.95,2706.86 3148.5,2700.41 3148.5,2693.58 3153.05,2689.03 3159.88,2689.03 3166.33,2695.48 3173.16,2695.48 3193.96,2674.68 3195.85,2672.79 3195.85,2672.25 3195.85,2520.03 C268.2@3178.35,2502.53
TX2_CLKIN_N: C269.1 U26.M6 | length 260.1
  Top Layer w6.1: U26.M6@3205.02,2211.71 3197.28,2219.45 3197.28,2297.23 3211.85,2311.81 3211.85,2437.79 C269.1@3229.35,2455.29
TX2_CLKIN_P: C268.1 U26.M7 | length 260.1
  Top Layer w6.1: U26.M7@3173.53,2211.71 3181.28,2219.45 3181.28,2303.86 3195.85,2318.43 3195.85,2437.79 C268.1@3178.35,2455.29
TX_OUT1: J7.1 J10.2 U29.L1 | length 1615.3
  Top Layer w6: J7.1@1203.18,940 1203.18,1027.36 1268.72,1092.9 U29.L1@1305.35,1092.9
  Bottom Layer w6: J7.1@1203.18,940 1203.18,622.82 1431.79,394.21 1565.01,394.21 1698.58,527.77 1739.97,527.77 1917.16,527.77 2056.33,388.6 J10.2@2056.33,367.93
TX_OUT2: J9.119 U29.K1 | length 1548.3
  Top Layer w6: v2@1290.82,1118.49 U29.K1@1305.35,1118.49 ; v1(2021.67,171.08) J9.119@2056.33,171.08
  Layer 6 - SIG w5: v2(1290.37,1118.94) 1256,1084.57 1256,1047.99 1256,570 1654.92,171.08 v1@2026.67,171.08
TX_OUT3: J8.1 J10.4 U29.J2 | length 1913.1
  Top Layer w6: U29.J2@1330.94,1144.08 1331.67,1144.81 1343.37,1144.81 1349.37,1150.8 v2@1363.22,1150.8
  Bottom Layer w6: v2(1366.32,1154.9) 1364.56,1153.14 1354.29,1153.14 1348.39,1147.24 1285.71,1147.24 1126.8,988.34 1126.8,659.89 1420.28,366.41 1705.41,366.41 J8.1@1817,478 1925.07,369.93 1977.07,369.93 2034.5,312.5 2069.18,312.5 2085.86,329.18 J10.4@2085.86,367.93
TX_OUT4: J9.117 U29.J1 | length 1832.2
  Top Layer w6: U29.J1@1305.35,1144.08 1244.51,1144.08 1109,1008.57 1109,701.83 1698.24,112.58 2074.81,112.58 2085.86,123.63 J9.117@2085.86,171.08
TX_OUT5: J10.8 U29.H2 | length 1945.3
  Top Layer w6: U29.H2@1331.39,1169.22 1331.67,1168.94 1344.82,1168.94 v2(1345.58,1168.19)
  Bottom Layer w6: v2(1345.58,1168.19) 1325.45,1188.32 1270.7,1188.32 1099,1016.62 1099,644.24 1404.63,338.61 1964.62,338.61 2018.53,284.7 2080.69,284.7 2123.71,327.72 2123.71,366.41 J10.8@2125.23,367.93
TX_OUT6: J9.113 U29.H1 | length 1845.1
  Top Layer w6: v2@1290.82,1169.67 U29.H1@1305.35,1169.67 ; v1(2117,120) 2117,122.71 2124.31,130.02 2124.31,170.16 J9.113@2125.23,171.08
  Layer 6 - SIG w5: v2(1290.37,1170.12) 1236.54,1116.29 1147.16,1026.91 1147.16,632.84 1658,122 v1@2115,122
TX_OUT7: J10.12 U29.G2 | length 1926.2
  Top Layer w6: U29.G2@1331.39,1194.81 1331.76,1195.18 v2@1346.94,1195.18
  Layer 12 - SIG w5: v2(1346.37,1195.1) 1245.67,1195.1 1122.87,1072.3 1122.87,689.58 1499.95,312.5 v1(2164.6,312.5)
  Bottom Layer w6: v1(2164.6,312.5) J10.12@2164.6,367.93
TX_OUT8: J9.109 U29.G1 | length 2020.1
  Top Layer w6: U29.G1@1305.35,1195.26 1256.38,1195.26 1081.2,1020.08 1081.2,690.31 1686.73,84.78 2118.32,84.78 2164.6,131.07 2164.6,170.65 2164.82,170.87 J9.109@2164.6,171.08
TX_OUT9: J10.16 U29.F2 | length 2156.8
  Top Layer w6: U29.F2@1331.39,1220.4 v2@1345.92,1220.4
  Bottom Layer w6: v2(1346.37,1219.94) 1326.81,1239.5 1277.24,1239.5 1070,1032.26 1070,631.58 1394.03,307.55 1938.64,307.55 1993.69,252.5 2143.92,252.5 2203.97,312.55 J10.16@2203.97,367.93
TX_OUT10: J9.105 U29.F1 | length 2056.3
  Top Layer w6: v2@1290.82,1220.85 U29.F1@1305.35,1220.85 ; v1(2187,111) 2187,112 2203.97,128.97 J9.105@2203.97,171.08
  Layer 6 - SIG w5: v2(1290.37,1221.3) 1236.54,1167.47 1113.1,1044.04 1113.1,622.9 1645.39,90.61 2166.61,90.61 v1(2187,111)
TX_OUT11: J10.20 U29.E2 | length 2121.5
  Top Layer w6: U29.E2@1331.39,1245.99 v2@1345.92,1245.99
  Layer 12 - SIG w5: v2(1346.37,1245.54) 1266.12,1245.54 1095,1074.42 1095,671 1477,289 2235.37,289 v1@2242.6,296.24
  Bottom Layer w6: v1(2243.34,295.5) J10.20@2243.34,367.93
TX_OUT12: J9.101 U29.E1 | length 2230.5
  Top Layer w6: U29.E1@1305.35,1246.44 1268.24,1246.44 1053.4,1031.6 1053.4,678.8 1675.21,56.98 2200.86,56.98 2228.58,84.7 2228.58,111.58 2243.34,126.34 J9.101@2243.34,171.08
TX_OUT13: J10.24 U29.D2 | length 2272.7
  Top Layer w6: U29.D2@1331.39,1271.58 v2@1345.92,1271.58
  Layer 12 - SIG w5: v2(1346.37,1271.13) 1322.1,1271.13 1305.24,1287.98 1271.22,1287.98 1067,1083.76 1067,656 1454,269 2256.21,269 v1(2282.71,295.5)
  Bottom Layer w6: v1(2282.71,295.5) J10.24@2282.71,367.93
TX_OUT14: J9.97 U29.D1 | length 2266.8
  Top Layer w6: v2@1290.82,1272.03 U29.D1@1305.35,1272.03 ; v1(2263.03,105.61) 2282.71,125.29 J9.97@2282.71,171.08
  Layer 6 - SIG w5: v2(1290.37,1272.48) 1236.54,1218.66 1078,1060.12 1078,616 1634,60 2217.42,60 v1(2263.03,105.61)
TX_OUT15: J10.28 U29.C2 | length 2475.5
  Top Layer w6: U29.C2@1330.94,1297.62 1331.97,1297.62 1340.69,1288.9 1357.09,1288.9 1368.6,1277.39 v2(1370.22,1277.39)
  Layer 12 - SIG w5: v2(1370.22,1277.39) 1357.41,1290.2 1348.51,1290.2 1331.49,1307.22 1254.66,1307.22 1035,1087.56 1035,642 1428,249 2275.58,249 v1(2322.08,295.5)
  Bottom Layer w6: v2@1368.06,1277.39 v2(1370.22,1277.39) ; v1(2322.08,295.5) J10.28@2322.08,367.93
TX_OUT16: J9.93 U29.C1 | length 2430.1
  Top Layer w6: U29.C1@1305.35,1297.62 1280.11,1297.62 1025.6,1043.11 1025.6,667.28 1663.7,29.18 2264.75,29.18 2317.16,81.6 2317.16,105.31 2322.08,110.23 J9.93@2322.08,171.08
TX_OUT17: J10.32 U29.C11 | length 1964.2
  Top Layer w6: U29.C11@1561.25,1297.62 v2@1575.78,1297.62
  Layer 3 - SIG w4.5: v1(1506.29,445.42) 1507.57,445.42 1596.99,356 2267.45,356 v1(2339.94,428.49)
  Layer 6 - SIG w5: v1(1506.29,445.42) 1508.22,445.42 1694.03,631.23 1694.03,1179.37 v2(1576.23,1297.17)
  Bottom Layer w6: v1(2339.94,428.49) 2361.01,407.42 2361.01,368.37 J10.32@2361.45,367.93
TX_OUT18: J9.89 U29.C10 | length 2533.8
  Top Layer w6: v2(1495.32,1277.8) 1496.95,1277.8 1509.41,1290.26 1515.74,1290.26 1522.37,1296.89 1534.93,1296.89 U29.C10@1535.66,1297.62 ; v1(2361.45,115.44) J9.89@2361.45,171.08
  Layer 3 - SIG w4.5: v1(1294.43,586.98) 1320.66,560.75 1320.66,358.37 1623.89,55.15 2339.69,55.15 2361.45,76.91 v1(2361.45,115.44)
  Bottom Layer w6: v1(1294.43,586.98) 1662.55,955.1 1662.55,1204.84 1597.48,1269.91 1562.67,1269.91 1544.58,1288 1508.01,1288 1497.81,1277.8 v2(1495.32,1277.8)
TX_OUT19: J10.36 U29.D11 | length 1969.4
  Top Layer w6: v1(1506.29,472.42) 1690.54,656.67 1690.54,1174.83 1593.34,1272.03 U29.D11@1561.25,1272.03
  Layer 3 - SIG w4.5: v1(1506.29,472.42) 1508.72,472.42 1515.72,465.42 1515.86,465.42 1604.68,376.6 2249.87,376.6 2321.76,448.49 2360.85,448.49 v1(2380.85,428.49)
  Bottom Layer w6: v1(2380.85,428.49) 2398.9,410.43 2398.9,369.85 J10.36@2400.82,367.93
TX_OUT20: J9.85 U29.D10 | length 2455.6
  Top Layer w6: v2(1520.86,1271.6) 1521.08,1271.82 1535.33,1271.82 U29.D10@1535.39,1271.76 ; v1(2400.82,115.44) J9.85@2400.82,171.08
  Layer 3 - SIG w4.5: v1(1294.43,623.59) 1340.66,577.35 1340.66,366.66 1617.08,90.24 2121.87,90.24 2167.07,135.44 2379.64,135.44 2399.64,115.44 v1(2400.82,115.44)
  Layer 14 - SIG w4.5: v1(1294.43,623.59) 1673,1002.15 1673,1187.28 1588.68,1271.6 v2(1520.86,1271.6)
TX_OUT21: J10.40 U29.E11 | length 1952.5
  Top Layer w6: U29.E11@1561.25,1246.44 v2@1575.78,1246.44
  Layer 3 - SIG w4.5: v1(1506.29,499.42) 1522.47,499.42 1620.44,401.45 2181.4,401.45 2196.72,416.77 2196.72,421.53 2260.46,485.28 2368.56,485.28 v1(2420.35,433.49) ; v1@2417.85,430.99 v1@2420.35,428.49
  Layer 6 - SIG w5: v1(1506.29,499.42) 1662.55,655.68 1662.55,1159.67 v2(1576.23,1245.99)
  Bottom Layer w6: v1(2420.35,433.49) 2420.35,427.75 2438.67,409.43 2438.67,369.45 J10.40@2440.19,367.93
TX_OUT22: J9.81 U29.E10 | length 2378.3
  Top Layer w6: v2@1521.41,1246.72 U29.E10@1535.94,1246.72 ; v1(2440.19,115.44) J9.81@2440.19,171.08
  Layer 3 - SIG w4.5: v1(1294.43,660.19) 1360.66,593.96 1360.66,374.94 1581.02,154.58 2157.93,154.58 2158.79,155.44 2400.19,155.44 v1(2440.19,115.44)
  Bottom Layer w6: v1(1294.43,660.19) 1311.89,660.19 1632.62,980.92 1632.62,1177.45 1595.32,1214.75 1552.48,1214.75 v2(1520.96,1246.27)
TX_OUT23: J10.44 U29.F11 | length 1949.4
  Top Layer w6: v1(1506.29,526.42) 1662.74,682.87 1662.74,1144.13 1586.02,1220.85 U29.F11@1561.25,1220.85
  Layer 3 - SIG w4.5: v1(1506.29,526.42) 1530.93,526.42 1628.95,428.39 2004.05,428.39 2040.41,464.76 2206.52,464.76 2251.25,509.49 2384.96,509.49 2459.59,434.86 v1(2459.59,433.49)
  Bottom Layer w6: v1(2459.59,433.49) 2479.51,413.57 2479.51,367.98 J10.44@2479.56,367.93
TX_OUT24: J9.77 U29.F10 | length 2428
  Top Layer w6: v2(1503.93,1228.41) 1504.13,1228.2 1528.31,1228.2 U29.F10@1535.66,1220.85 ; v1(2479.56,115.44) J9.77@2479.56,171.08
  Layer 3 - SIG w4.5: v1(1294.43,696.79) 1380.66,610.56 1380.66,383.23 1571.89,192 2403,192 v1(2479.56,115.44)
  Layer 14 - SIG w4.5: v1(1294.43,696.79) 1644,1046.36 1644,1163.39 1578.98,1228.41 v2(1503.93,1228.41)
TX_OUT25: J10.48 U29.G11 | length 1891.9
  Top Layer w6: U29.G11@1561.25,1195.26 v2@1575.78,1195.26
  Layer 3 - SIG w4.5: v1(1506.29,553.42) 1864.67,553.42 1932.81,485.28 2188.86,485.28 2240.07,536.49 2396.91,536.49 v1(2498.19,435.21)
  Layer 6 - SIG w5: v1(1506.29,553.42) 1634,681.13 1634,1137.04 v2(1576.23,1194.81)
  Bottom Layer w6: v1(2498.19,435.21) 2518.93,414.46 J10.48@2518.93,367.93
TX_OUT26: J9.73 U29.G10 | length 2366.7
  Top Layer w6: v2(1516.93,1198.88) 1531.01,1198.88 1534.63,1195.26 U29.G10@1535.66,1195.26 ; v1(2518.93,115.44) J9.73@2518.93,171.08
  Layer 3 - SIG w4.5: v1(1294.43,733.4) 1400.66,627.17 1400.66,391.51 1545.95,246.22 2375.54,246.22 2396.94,224.82 2409.55,224.82 v1(2518.93,115.44)
  Bottom Layer w6: v1(1294.43,733.4) 1328.32,733.4 1603.96,1009.03 1603.96,1150.6 1586.03,1168.52 1547.28,1168.52 v2(1516.93,1198.88)
TX_OUT27: J10.52 U29.H11 | length 1909.1
  Top Layer w6: v1@1506.29,579.62 1634.94,708.27 1634.94,1132.61 1597.88,1169.67 U29.H11@1561.25,1169.67
  Layer 3 - SIG w4.5: v1(1506.29,580.42) 1876.76,580.42 1944.9,512.28 2177.67,512.28 2228.88,563.49 2413.85,563.49 v1(2540.25,437.1)
  Bottom Layer w6: v1(2540.25,437.1) 2542.64,437.1 2556.31,423.43 2556.31,369.93 J10.52@2558.3,367.93
TX_OUT28: J9.69 U29.H10 | length 2403.6
  Top Layer w6: v2(1507.43,1168.19) 1508.18,1168.94 1534.93,1168.94 U29.H10@1535.66,1169.67 ; v1(2558.3,115.44) J9.69@2558.3,171.08
  Layer 3 - SIG w4.5: v1(1294.43,770) 1420.66,643.77 1420.66,399.8 1547.46,273 2427.26,273 2459.61,240.65 2459.61,214.13 v1(2558.3,115.44)
  Layer 14 - SIG w4.5: v1(1294.43,770) 1619.25,1094.82 1619.25,1136.03 1587.1,1168.19 v2(1507.43,1168.19)
TX_OUT29: J10.56 U29.J11 | length 1876.4
  Top Layer w6: U29.J11@1561.25,1144.08 v2@1575.78,1144.08
  Layer 3 - SIG w4.5: v1(1506.29,607.42) 1878.04,607.42 1953.19,532.28 2159.49,532.28 2217.7,590.49 2434.8,590.49 2577.99,447.3 v1(2577.99,429.05)
  Layer 6 - SIG w5: v1(1506.29,607.42) 1603.96,705.09 1603.96,1115.9 v2(1576.23,1143.62)
  Bottom Layer w6: v1(2577.99,429.05) 2597.67,409.37 J10.56@2597.67,367.93
TX_OUT30: J9.65 U29.J10 | length 2483.9
  Top Layer w6: v2@1462,1163 1465.27,1163 1478.17,1150.1 1503,1150.1 ; v2@1466.14,1163 v2@1466.14,1163.41 ; 1503,1150.34 1513.84,1150.34 1519.56,1144.63 1535.11,1144.63 U29.J10@1535.66,1144.08 ; v1(2597.67,112.58) J9.65@2597.67,171.08
  Layer 3 - SIG w4.5: v1(1294.43,806.6) 1440.66,660.38 1440.66,421.53 1569.2,293 2201.31,293 2222.55,314.24 2336.28,314.24 2357.51,293 2476.28,293 2497.4,271.87 2497.4,212.85 v1(2597.67,112.58)
  Bottom Layer w6: v1(1294.43,806.6) 1354.88,806.6 1556,1007.72 1556,1111.28 1518.08,1149.2 1492.02,1149.2 1476.12,1165.1 v2@1466.14,1165.1
  other v2: 1463.14,1162.1
TX_OUT31: J10.60 U29.K11 | length 1883.6
  Top Layer w6: v1(1506.29,634.42) 1607.14,735.27 1607.14,1097.61 1587.22,1117.53 1562.21,1117.53 U29.K11@1561.25,1118.49
  Layer 3 - SIG w4.5: v1(1506.29,634.42) 1879.33,634.42 1960.33,553.42 2142.45,553.42 2206.52,617.49 2438.46,617.49 v1(2627.56,428.39)
  Bottom Layer w6: v1(2627.56,428.39) 2629.09,426.86 2629.09,419.51 2637.04,411.56 J10.60@2637.04,367.93
TX_OUT32: J9.61 U29.L11 | length 2032.3
  Top Layer w6: U29.L11@1561.25,1092.9 v2@1575.78,1092.9 ; v1@2625.29,241.32 2625.29,215.39 2636.12,204.55 2636.12,172 J9.61@2637.04,171.08
  Layer 3 - SIG w4.5: v1(1506.29,418.42) 1590.47,334.24 2532.37,334.24 v1(2622.29,244.32) v1@2625.29,241.32
  Layer 6 - SIG w5: v1(1506.29,418.42) 1504.07,420.64 1495.17,420.64 1455.44,460.37 1455.44,640.44 1576.23,761.23 v2(1576.23,1092.44)
TX_OUT33: J10.1 U28.L1 | length 1124.2
  Top Layer w6: U28.L1@2072.74,1096.23 2072.74,921.89 v1(2088,906.62)
  Layer 14 - SIG w4.5: v1(2056.33,222.72) 2056.33,274.04 1882.09,448.29 1882.09,755.21 2031.01,904.13 2082,904.13 2087.47,909.61 v1@2087.47,912.28
  Bottom Layer w6: J10.1@2056.33,171.08 v1(2056.33,222.72)
TX_OUT34: J9.120 U28.K1 | length 805
  Top Layer w6: J9.120@2056.33,367.93 2044.97,379.3 2044.97,401.49 2020.19,426.27 2020.19,1091.44 2050.56,1121.82 U28.K1@2072.74,1121.82 U28.K1@2071.78,1120.86
TX_OUT35: J10.3 U28.J2 | length 1238
  Top Layer w6: U28.J2@2098.33,1147.41 2099.06,1148.14 2110.76,1148.14 2116.76,1154.13 2131.13,1154.13 v2(2134,1157)
  Layer 14 - SIG w4.5: v1@2085.86,222.72 v1(2085.86,229.72) 2085.86,272.8 1913.15,445.51 1913.15,729.87 2052.69,869.41 v1(2088,869.41)
  Bottom Layer w6: J10.3@2085.86,171.08 v1@2085.86,222.72 ; v1(2088,869.41) 2061.41,896.01 2061.41,1095.92 2122.49,1157 v2(2134,1157)
TX_OUT36: J9.118 U28.J1 | length 919.2
  Top Layer w6: v2@2058.21,1147.41 U28.J1@2072.74,1147.41 ; J9.118@2085.86,367.93 2087.38,369.45 2087.38,415.22 v1(2103.51,431.34)
  Layer 11 - SIG w5: v2(2057.76,1147.86) 1938.9,1029 1938.9,595.95 v1(2103.51,431.34)
TX_OUT37: J10.7 U28.H2 | length 1286.4
  Top Layer w6: U28.H2@2098.78,1172.55 2099.06,1172.27 2112.22,1172.27 v2(2112.97,1171.52)
  Layer 14 - SIG w4.5: v1(2088,827.81) 2056.45,827.81 1941.84,713.2 1941.84,445.11 2125.23,261.71 v1@2125.23,222.72 ; v1@2123.7,224.25 2124.26,223.69 2124.26,220.72 2124.47,220.51
  Bottom Layer w6: v1(2088,827.81) 2057.11,827.81 2029.45,855.47 2029.45,1148.39 2052.58,1171.52 v2(2112.97,1171.52) ; J10.7@2125.23,171.08 v1@2125.23,222.72
  other v1: 2125.23,229.72
TX_OUT38: J9.114 U28.H1 | length 1091.4
  Top Layer w6: U28.H1@2072.74,1173 2040.08,1173 2038.68,1171.6 1971,1103.92 1971,372.69 2031.37,312.32 2116.57,312.32 2125.23,320.97 J9.114@2125.23,367.93
TX_OUT39: J10.11 U28.G2 | length 1358.6
  Top Layer w6: U28.G2@2098.78,1198.14 2099.15,1198.51 v2@2114.34,1198.51
  Layer 14 - SIG w4.5: v1(2088,779.04) 2065.77,779.04 1970.33,683.6 1970.33,444.9 2164.6,250.63 v1@2164.6,222.72
  Bottom Layer w6: v1(2088,779.04) 2048.04,779.04 2001.65,825.43 2001.65,1177.85 2039.25,1215.44 2064.55,1215.44 2081.56,1198.43 v2(2113.76,1198.43) ; J10.11@2164.6,171.08 v1@2164.6,222.72
  other v1: 2164.6,229.72
TX_OUT40: J9.110 U28.G1 | length 1116.5
  Top Layer w6: v2@2058.21,1198.59 U28.G1@2072.74,1198.59 ; J9.110@2164.6,367.93 2164.68,368.01 2164.68,413.57 v1(2182.46,431.34)
  Layer 11 - SIG w5: v2(2057.76,1199.04) 1911.9,1053.18 1911.9,584.77 2092.32,404.34 2155.46,404.34 v1(2182.46,431.34)
TX_OUT41: J10.15 U28.F2 | length 1443.1
  Top Layer w6: U28.F2@2098.78,1223.73 v2@2113.31,1223.73
  Layer 14 - SIG w4.5: v1(2088,730.27) 2065.3,730.27 2001.13,666.1 2001.13,442.39 2203.97,239.54 v1@2203.97,222.72 ; v1@2203.33,223.44 v1@2203.78,223
  Bottom Layer w6: v1(2088,730.27) 2022.62,730.27 1973.85,779.04 1973.85,1190.89 2049.58,1266.63 2070.41,1266.63 v2(2113.76,1223.28) ; J10.15@2203.97,171.08 v1@2203.97,222.72
  other v1: 2203.97,229.72
TX_OUT42: J9.106 U28.F1 | length 1332.5
  Top Layer w6: U28.F1@2072.74,1224.18 2035.3,1224.18 1931,1119.89 1931,351.98 2007.13,275.85 2175.14,275.85 2203.97,304.69 J9.106@2203.97,367.93
TX_OUT43: J10.19 U28.E2 | length 1596.3
  Top Layer w6: U28.E2@2098.78,1249.32 v2@2113.31,1249.32
  Layer 14 - SIG w4.5: v1(2088,681.5) 2068.14,681.5 2029.62,642.98 2029.62,446.83 2126.72,349.74 2164.6,349.74 2203.2,311.14 2203.2,269.86 v1(2243.34,229.72) v1@2243.34,222.72
  Bottom Layer w6: v1(2088,681.5) 2008.99,681.5 1938.64,751.85 1938.64,1254.26 2004.57,1320.2 2062.78,1320.2 2084.4,1298.57 2084.4,1278.23 v2(2113.76,1248.87) ; J10.19@2243.34,171.08 v1@2243.34,222.72
TX_OUT44: J9.102 U28.E1 | length 1312.3
  Top Layer w6: v2@2058.21,1249.77 U28.E1@2072.74,1249.77 ; J9.102@2243.34,367.93 2243.4,367.99 2243.4,413.76 v1(2260.53,430.88)
  Layer 11 - SIG w5: v2(2057.76,1250.23) 1884.9,1077.36 1884.9,573.59 2081.14,377.34 2207.68,377.34 2260.53,430.19 v1(2260.53,430.88)
TX_OUT45: J10.23 U28.D2 | length 1887.5
  Top Layer w6: U28.D2@2098.78,1274.91 v2@2113.31,1274.91
  Layer 14 - SIG w4.5: v1(2088,632.72) 2087.81,632.53 2074.86,632.53 2059.04,616.71 2059.04,452.48 2141.51,370 2172.63,370 2223.2,319.43 2223.2,286.23 2291.93,217.5 v1(2291.93,90.61)
  Bottom Layer w6: v1(2088,632.72) 2001.12,632.72 1904,729.85 1904,1308.81 1979.25,1384.06 2018.52,1384.06 2054.58,1348 2079.5,1348 2101.2,1326.29 2101.2,1287.64 2113.76,1275.08 v2(2113.76,1274.46) ; J10.23@2282.26,170.63 2282.71,170.18 2282.71,101.77 2291.93,92.56 v1(2291.93,90.61)
TX_OUT46: J9.98 U28.D1 | length 1600.1
  Top Layer w6: U28.D1@2072.74,1275.36 2047.16,1275.36 2038.68,1266.88 1894,1122.2 1894,314 1959.95,248.05 2277.99,248.05 2302.78,272.84 2302.78,302.51 2282.99,322.3 2282.99,367.65 J9.98@2282.71,367.93
TX_OUT47: J10.27 U28.C2 | length 2165.1
  Top Layer w6: U28.C2@2098.33,1300.95 2099.36,1300.95 2108.08,1292.23 2124.48,1292.23 2135.99,1280.73 v2(2137.61,1280.73)
  Layer 14 - SIG w4.5: v1(2088.49,583.95) 2088.49,505.72 2128.64,465.57 2128.64,418.35 2152.14,394.84 2176.07,394.84 2259.84,311.07 2259.84,286.5 2336.85,209.49 v1(2336.85,90.84)
  Bottom Layer w6: v1(2088.49,583.95) 1973.66,583.95 1867,690.61 1867,1321.55 1958.88,1413.43 2053.39,1413.43 2120.55,1346.26 2175.65,1346.26 2196.08,1325.83 2196.08,1273.52 2187.29,1264.73 2153.61,1264.73 v2(2137.61,1280.73) ; J10.27@2322.08,171.08 2322.08,105.6 v1(2336.85,90.84)
TX_OUT48: J9.94 U28.C1 | length 1567.2
  Top Layer w6: v2@2058.21,1300.95 U28.C1@2072.74,1300.95 ; v1(2267.15,468.63) 2322.08,413.7 J9.94@2322.08,367.93
  Layer 11 - SIG w5: v2(2057.76,1301.41) 1857.9,1101.54 1857.9,562.4 2069.95,350.34 2218.17,350.34 2292.15,424.32 2292.15,443.63 v1(2267.15,468.63)
TX_OUT49: J10.31 U28.C11 | length 1667.4
  Top Layer w6: U28.C11@2328.64,1300.95 v2@2343.17,1300.95
  Layer 11 - SIG w5: v2(2343.63,1300.5) 2375.88,1300.5 2479.22,1197.16 v1(2479.22,832.34)
  Layer 14 - SIG w4.5: v1(2358.5,229.72) 2305.58,282.59 2305.58,315.53 2206.27,414.84 2175.62,414.84 2161.64,428.83 2161.64,472.67 2115.49,518.82 2115.49,609.37 2115.49,741.01 2227.29,852.82 2461.08,852.82 2479.22,834.68 v1(2479.22,832.34)
  Bottom Layer w6: v1(2358.5,229.72) 2359.98,228.24 2359.98,172.56 J10.31@2361.45,171.08
TX_OUT50: J9.90 U28.C10 | length 1446.1
  Top Layer w6: v2(2262.71,1281.13) 2264.34,1281.13 2276.8,1293.6 2283.13,1293.6 2289.76,1300.22 2302.32,1300.22 U28.C10@2303.05,1300.95 ; J9.90@2361.45,367.93 2361.45,626.96 v1(2538.07,803.57)
  Layer 11 - SIG w5: v2(2262.71,1281.13) 2279.39,1297.81 2285.82,1297.81 2302.2,1314.19 2302.2,1381.23 2332.53,1411.56 2388.03,1411.56 2523.24,1276.36 2523.24,1274.79 2538.07,1259.96 v1(2538.07,803.57)
TX_OUT51: J10.35 U28.D11 | length 1607.4
  Top Layer w6: U28.D11@2328.64,1275.36 2360.73,1275.36 2484.48,1151.61 2484.48,913.36 2447.97,876.84 v1(2447.97,793.25)
  Layer 14 - SIG w4.5: v1(2403.77,241.32) 2403.07,242.03 2403.07,257.82 2242.5,418.39 2242.5,431.98 2142.49,531.99 2142.49,729.64 2238.66,825.82 2415.41,825.82 v1(2447.97,793.25)
  Bottom Layer w6: J10.35@2400.82,171.08 2402.3,172.56 2402.3,239.85 v1(2403.77,241.32)
TX_OUT52: J9.86 U28.D10 | length 1344.3
  Top Layer w6: v2(2288.25,1274.93) 2288.47,1275.15 2302.72,1275.15 U28.D10@2302.78,1275.09 ; J9.86@2400.82,367.93 2400.82,487.07 2393.21,494.68 2393.21,618.11 v1(2538.07,762.97)
  Layer 11 - SIG w5: v2(2288.25,1274.93) 2321.89,1308.57 2321.89,1372.64 2340.81,1391.56 2379.75,1391.56 2503.24,1268.07 2503.24,797.8 v1(2538.07,762.97)
TX_OUT53: J10.39 U28.E11 | length 1510.1
  Top Layer w6: U28.E11@2328.64,1249.77 v2@2343.17,1249.77
  Layer 11 - SIG w5: v2(2343.63,1249.32) 2343.63,1248.92 2439.22,1153.33 2439.22,821.52 2424.4,806.7 v1(2424.4,768.5)
  Layer 14 - SIG w4.5: v1(2424.4,768.5) 2394.08,798.82 2249.85,798.82 2169.49,718.46 2169.49,587.01 2169.49,545.26 2238,476.74 2238,465 2252.72,450.28 2267.64,450.28 2282.71,435.21 2282.71,406.46 2440.19,248.98 v1(2440.19,226.72)
  Bottom Layer w6: J10.39@2440.19,171.08 v1(2440.19,226.72)
TX_OUT54: J9.82 U28.E10 | length 1128.1
  Top Layer w6: v2@2288.8,1250.05 U28.E10@2303.33,1250.05 ; J9.82@2440.19,367.93 2440.19,487.01 2421.01,506.2 2421.01,605.31 v1(2538.07,722.37)
  Layer 11 - SIG w5: v2(2288.35,1249.6) 2307.67,1268.92 2364.63,1268.92 2459.22,1174.33 2459.22,824.05 2467,816.27 2467,793.43 v1(2538.07,722.37)
TX_OUT55: J10.43 U28.F11 | length 1475.6
  Top Layer w6: U28.F11@2328.64,1224.18 2353.41,1224.18 2447.09,1130.5 2447.09,917.28 2400.82,871.01 v1(2400.82,743.76)
  Layer 14 - SIG w4.5: v1(2400.82,743.76) 2372.76,771.82 2261.03,771.82 2196.49,707.28 2196.49,563.21 2312.4,447.29 2312.4,425.42 2433.69,304.13 2461.59,304.13 2479.56,286.15 v1(2479.56,226.72)
  Bottom Layer w6: J10.43@2479.56,171.08 v1(2479.56,226.72)
TX_OUT56: J9.78 U28.F10 | length 1379.3
  Top Layer w6: v2(2271.32,1231.74) 2271.52,1231.53 2295.7,1231.53 U28.F10@2303.05,1224.18 ; J9.78@2479.56,367.93 2479.56,486.96 2452.16,514.36 2452.16,595.86 v1(2538.07,681.76)
  Layer 11 - SIG w5: v2(2271.32,1231.74) 2298.82,1231.74 2316,1214.57 2316,1151.69 2369.71,1097.98 2369.71,871.5 2277.72,779.51 2277.72,644.13 2308.13,613.72 2470.03,613.72 v1(2538.07,681.76)
TX_OUT57: J10.47 U28.G11 | length 1379.1
  Top Layer w6: U28.G11@2328.64,1198.59 v2@2343.17,1198.59
  Layer 11 - SIG w5: v2(2343.63,1198.14) 2419.22,1122.55 2419.22,839 2377.25,797.04 v1(2377.25,719.01)
  Layer 14 - SIG w4.5: v1(2377.25,719.01) 2351.44,744.82 2272.21,744.82 2223.49,696.09 2223.49,571.69 2361.45,433.73 2361.45,424.55 2461.87,324.13 2469.87,324.13 2518.93,275.07 v1(2518.93,231.02)
  Bottom Layer w6: J10.47@2518.93,171.08 v1(2518.93,231.02)
TX_OUT58: J9.74 U28.G10 | length 1090.7
  Top Layer w6: v2(2278,1210) 2285.79,1202.21 2298.4,1202.21 2302.02,1198.59 U28.G10@2303.05,1198.59 ; J9.74@2518.93,367.93 2517.66,369.2 2517.66,488.17 2479.96,525.87 2479.96,583.06 v1(2538.07,641.16)
  Layer 14 - SIG w4.5: v2(2278,1210) 2279.73,1208.27 2290.38,1208.27 2296.44,1214.33 2351.44,1214.33 2558.3,1007.47 2558.3,661.4 v1(2538.07,641.16) ; v1@2533.07,641.16 v1@2535.57,643.66
TX_OUT59: J10.51 U28.H11 | length 1318.8
  Top Layer w6: U28.H11@2328.64,1173 2365.27,1173 2402.33,1135.95 2402.33,944.56 2353.68,895.9 v1(2353.68,694.26)
  Layer 14 - SIG w4.5: v1(2353.68,694.26) 2330.12,717.82 2283.4,717.82 2250.49,684.91 2250.49,582.87 2400.82,432.54 2400.82,422.24 2558.3,264.76 v1(2558.3,231.02)
  Bottom Layer w6: J10.51@2558.3,171.08 v1(2558.3,231.02)
TX_OUT60: J9.70 U28.H10 | length 1025.5
  Top Layer w6: v2(2274.82,1171.52) 2275.58,1172.27 2302.32,1172.27 U28.H10@2303.05,1173 ; v1(2538.06,600.56) 2507.76,570.25 2507.76,537.39 2558.3,486.85 J9.70@2558.3,367.93
  Layer 14 - SIG w4.5: v2(2274.82,1171.52) 2352.43,1171.52 2519.22,1004.73 2519.22,815.77 2513.07,809.62 2513.07,632.87 2538.06,607.88 v1(2538.06,600.56)
TX_OUT61: J10.55 U28.J11 | length 1266.5
  Top Layer w6: U28.J11@2328.64,1147.41 v2@2343.17,1147.41
  Layer 11 - SIG w5: v1(2330.1,669.51) 2330.1,792.33 2399.22,861.45 2399.22,1102.67 2354.93,1146.96 v2(2343.63,1146.96)
  Layer 14 - SIG w4.5: v1(2330.1,669.51) 2315.52,684.1 2295.53,684.1 2277.49,666.05 2277.49,601 2415.87,462.62 2454.27,462.62 2479.02,437.86 2479.02,375.16 2597.67,256.51 v1(2597.67,231.02)
  Bottom Layer w6: J10.55@2597.67,171.08 v1(2597.67,231.02)
TX_OUT62: J9.66 U28.J10 | length 1089.5
  Top Layer w6: v2(2231.95,1168) 2232.27,1168 2247.73,1152.53 2296.9,1152.53 2302.02,1147.41 U28.J10@2303.05,1147.41 ; v1(2538.06,559.95) 2598.71,499.31 2598.71,368.96 J9.66@2597.67,367.93
  Layer 14 - SIG w4.5: v2(2231.95,1168) 2250.21,1168 2267.67,1150.53 2285.68,1150.53 2307.4,1128.81 2360.54,1128.81 2499.22,990.13 2499.22,824.05 2493.07,817.9 2493.07,604.95 v1(2538.06,559.95)
TX_OUT63: J10.59 U28.K11 | length 1259.6
  Top Layer w6: v1(2306.53,644.76) 2306.53,914.53 2374.53,982.53 2374.53,1100.94 2354.61,1120.86 2329.6,1120.86 U28.K11@2328.64,1121.82
  Layer 14 - SIG w4.5: v1(2306.53,644.76) 2306.53,603.2 2415.49,494.24 2473.86,494.24 2516.32,451.77 2516.32,416.26 2584.38,348.21 2658.26,348.21 2676.41,330.05 2676.41,261.9 v1(2643.55,229.04)
  Bottom Layer w6: J10.59@2637.04,171.08 2637.04,220.36 2643.55,226.87 v1(2643.55,229.04)
TX_OUT64: J9.62 U28.L11 | length 1090.4
  Top Layer w6: U28.L11@2328.64,1096.23 v2@2343.17,1096.23 ; J9.62@2637.04,367.93 2637.96,368.85 2637.96,404.68 2651.81,418.52 v1(2651.81,463.1)
  Layer 11 - SIG w5: v2(2343.63,1095.78) 2343.63,887.95 2251.66,795.99 2251.66,627.47 2351.95,527.18 2587.73,527.18 v1(2651.81,463.1)
TX_OUT65: J10.62 U27.L1 | length 1046.5
  Top Layer w6: U27.L1@2965.13,1094.56 2965.13,995.25 v1(3073.89,886.49)
  Bottom Layer w6: J10.62@2656.73,367.93 2656.73,443.63 2658.8,445.7 2659.01,445.7 2671.49,458.18 2671.49,658.07 2899.91,886.49 v1(3073.89,886.49)
TX_OUT66: J9.59 U27.K1 | length 1516
  Top Layer w6: v1(2656.73,90.61) J9.59@2656.73,171.08 ; v2@2950.6,1120.15 U27.K1@2965.13,1120.15
  Layer 3 - SIG w4.5: v1(2656.73,90.61) 2656.73,167.76 2659.91,170.94 2659.91,222.06 ; 2660.05,222.46 2660.05,262.75 2660,262.8 2676.1,278.9 2676.1,365.38 2684.55,373.83 2684.55,726.66 2815.93,858.03 v1(3048.16,858.03)
  Layer 12 - SIG w5: v2(2950.15,1120.6) 2950.15,1084.15 2945.26,1079.26 2945.26,877.9 2965.13,858.03 v1(3048.16,858.03)
TX_OUT67: J10.66 U27.J2 | length 1400
  Top Layer w6: U27.J2@2990.72,1145.74 2991.68,1146.7 3005.68,1146.7 3012.03,1153.05 3012.32,1153.05 3014.5,1155.24 3026.24,1155.24 v2(3028,1157)
  Layer 5 - SIG w5: v2(3028,1157) 3025.02,1157 3017.39,1149.37 3010.18,1149.37 2970.27,1109.45 2970.27,858.41 3069.38,759.29 3069.38,684.14 3053.63,668.39 v1@3053.63,667.93
  Bottom Layer w6: J10.66@2696.1,367.93 2696.1,443.47 2699.29,446.66 2699.29,629.63 2845.44,775.77 2943.27,775.77 3051.11,667.93 v1(3053.17,667.93) 3004.09,717
TX_OUT68: J9.55 U27.J1 | length 1454.5
  Top Layer w6: v1(2696.1,90.61) J9.55@2696.1,171.08 ; U27.J1@2965.13,1145.74 2943.09,1145.74 2920.52,1123.17 2920.52,931.49 v1(3022.44,829.58)
  Layer 3 - SIG w4.5: v1(2696.1,90.61) 2696.1,135.44 2696.1,357.1 2707.52,368.52 2707.52,702.72 2834.38,829.58 v1(3022.44,829.58)
TX_OUT69: J10.70 U27.H2 | length 1264
  Top Layer w6: U27.H2@2991.17,1170.88 2991.45,1170.61 3004.61,1170.61 v2(3005.36,1169.85)
  Layer 5 - SIG w5: v2@3006.54,1169.85 2975.75,1139.06 2943.18,1139.06 2932.06,1127.94 2932.06,837.46 3033.63,735.89 v1@3033.63,644.47
  Bottom Layer w6: J10.70@2735.47,367.93 2735.47,618.97 2849.64,733.14 2926.74,733.14 2966.13,693.76 2983.15,693.76 v1(3032.44,644.47)
TX_OUT70: J9.51 U27.H1 | length 1485.6
  Top Layer w6: v1(2735.47,90.61) J9.51@2735.47,171.08 ; v2@2950.6,1171.33 U27.H1@2965.13,1171.33
  Layer 3 - SIG w4.5: v1(2735.47,90.61) 2735.47,271.89 2718.95,288.41 2718.95,326.02 2728.95,336.02 2728.95,695.86 2834.21,801.12 v1(2996.71,801.12)
  Layer 12 - SIG w5: v2(2950.15,1171.79) 2925.19,1171.79 2915.59,1162.19 2915.59,831.41 2945.88,801.12 v1(2996.71,801.12)
TX_OUT71: J10.74 U27.G2 | length 1244.2
  Top Layer w6: U27.G2@2991.17,1196.47 2991.54,1196.85 v2@3006.73,1196.85
  Layer 5 - SIG w5: v2(3006.15,1196.77) 2965.67,1156.29 2919.42,1156.29 2897.24,1134.11 2897.24,822.43 3012.9,706.77 v1@3012.9,621.01 ; v2@3006.74,1196.17 v2@3007.34,1196.77
  Bottom Layer w6: J10.74@2774.84,367.93 2774.84,606.46 2850.14,681.76 2870.65,681.76 2895.72,656.69 2976.03,656.69 v1(3011.72,621.01)
TX_OUT72: J9.47 U27.G1 | length 1416.4
  Top Layer w6: v1(2774.84,90.61) J9.47@2774.84,171.08 ; U27.G1@2965.13,1196.92 2931.12,1196.92 2892.72,1158.52 2892.72,850.93 v1(2970.99,772.66)
  Layer 3 - SIG w4.5: v1(2774.84,90.61) 2774.84,689.23 2858.27,772.66 v1(2970.99,772.66)
TX_OUT73: J10.78 U27.F2 | length 1193.6
  Top Layer w6: U27.F2@2991.17,1222.06 v2@3005.7,1222.06
  Layer 5 - SIG w5: v1@2992.18,597.55 2992.18,673.95 2870.65,795.48 2870.65,1144.16 2928.69,1202.21 2973.59,1202.21 2992.84,1221.45 3007.18,1221.45 v2@3007.34,1221.61
  Bottom Layer w6: J10.78@2814.21,367.93 2814.21,576.17 2859.05,621.01 2967.53,621.01 v1(2990.99,597.55)
  other v2: 3006.15,1221.61
TX_OUT74: J9.43 U27.F1 | length 1422.2
  Top Layer w6: v1@2814.21,90.61 J9.43@2814.21,171.08 ; v2@2950.6,1222.51 U27.F1@2965.13,1222.51
  Layer 3 - SIG w4.5: v1@2814.21,90.61 2814.21,249.04 2794.84,268.41 2794.84,334.24 2814.21,353.61 2814.21,543.03 2799.77,557.47 2799.77,685.88 2858.1,744.2 v1(2945.26,744.2)
  Layer 12 - SIG w5: v1(2945.26,744.2) 2887.21,802.26 2887.21,1179.42 2930.75,1222.97 v2(2950.15,1222.97)
  other v1: 2814.21,85.61
TX_OUT75: J10.82 U27.E2 | length 1152.4
  Top Layer w6: U27.E2@2991.17,1247.65 v2@3005.7,1247.65
  Layer 5 - SIG w5: v1(2970.27,574.09) 2945.26,599.1 2945.26,664.94 2850.65,759.55 2850.65,1152.45 2945.4,1247.2 v2(3006.15,1247.2) v2@3007.34,1247.2
  Bottom Layer w6: J10.82@2853.58,367.93 2853.58,535.29 2909.14,590.85 2953.51,590.85 v1(2970.27,574.09)
TX_OUT76: J9.39 U27.E1 | length 1448.4
  Top Layer w6: v1@2853.58,90.61 J9.39@2853.58,171.08 ; v1(2919.54,715.74) 2864.92,770.36 2864.92,1192.51 2920.52,1248.11 U27.E1@2965.13,1248.11 2928.02,1248.11
  Layer 3 - SIG w4.5: v1@2853.58,90.61 2852.95,91.24 2852.95,541.64 2824.96,569.63 2824.96,675.92 2864.78,715.74 v1(2919.54,715.74)
  other v1: 2853.58,85.61
TX_OUT77: J10.86 U27.D2 | length 1188.6
  Top Layer w6: U27.D2@2991.17,1273.24 v2@3005.7,1273.24
  Layer 5 - SIG w5: v1@2950.73,550.64 2810.65,690.72 2810.65,1169.02 2935.78,1294.15 2957.45,1294.15 2978.81,1272.79 v2(3006.15,1272.79) ; v2@3006.74,1273.39 v2@3007.34,1272.79
  Bottom Layer w6: J10.86@2892.95,367.93 2892.95,535.34 2920.65,563.05 2937.13,563.05 v1(2949.54,550.64)
TX_OUT78: J9.35 U27.D1 | length 1437.1
  Top Layer w6: v1@2892.95,90.61 J9.35@2892.95,171.08 ; v2@2950.6,1273.7 U27.D1@2965.13,1273.7
  Layer 3 - SIG w4.5: v1@2892.95,90.61 2892.95,235.08 2872.95,255.08 2872.95,319.84 2892.95,339.84 2892.95,427.25 2872.95,447.25 2872.95,558.67 2844.96,586.66 2844.96,666.25 2863.38,684.68 v1(2897.24,684.68)
  Layer 5 - SIG w5: v1(2897.24,684.68) 2830.65,751.27 2830.65,1160.73 2944.07,1274.15 v2(2950.15,1274.15)
  other v1: 2892.95,85.61
TX_OUT79: J10.90 U27.C2 | length 1239.3
  Top Layer w6: U27.C2@2990.72,1299.29 2991.75,1299.29 3000.47,1290.57 3016.87,1290.57 3028.38,1279.06 v2(3030,1279.06)
  Layer 5 - SIG w5: v1@2930,527.18 2790.62,666.57 2790.62,1189.65 2915.11,1314.15 2963.5,1314.15 2984.26,1293.39 3015.68,1293.39 v2(3030,1279.06) v2@3031.19,1279.06
  Bottom Layer w6: v1(2928.82,527.18) 2928.82,475.77 2937.24,467.35 2937.24,435.36 2932.32,430.44 J10.90@2932.32,367.93
TX_OUT80: J9.31 U27.C1 | length 1408.7
  Top Layer w6: v1(2868.09,658.83) 2837.12,689.8 2837.12,1204.02 2932.38,1299.29 U27.C1@2965.13,1299.29 ; v1@2932.32,90.61 J9.31@2932.32,171.08
  Layer 3 - SIG w4.5: v1(2868.09,658.83) 2868.09,610.59 2892.95,585.73 2892.95,457.45 2914.03,436.38 2927.53,436.38 2931.27,432.64 2931.27,91.66 v1@2932.32,90.61
  other v1: 2932.32,85.61
TX_OUT81: J10.94 U27.C11 | length 1665.1
  Top Layer w6: U27.C11@3221.03,1299.29 v2@3235.56,1299.29
  Layer 3 - SIG w4.5: v2(3236.02,1298.83) 3238.99,1298.83 3242.61,1295.22 3244.32,1295.22 3432.05,1107.49 3432.05,1057.17 3498.45,990.77 3548.77,990.77 v1(3667.29,872.24)
  Bottom Layer w6: J10.94@2971.69,367.93 2971.69,439.99 2964.4,447.28 2964.4,493.54 3059.86,589 3136.03,589 3449.12,902.09 3637.44,902.09 v1(3667.29,872.24)
TX_OUT82: J9.27 U27.C10 | length 1884.9
  Top Layer w6: v1(2971.71,90.61) 2971.41,90.91 2971.41,170.8 J9.27@2971.69,171.08 ; v2(3155,1278) 3155.26,1278 3169.19,1291.93 3175.52,1291.93 3182.15,1298.56 3194.71,1298.56 U27.C10@3195.44,1299.29
  Layer 5 - SIG w5: v1(2971.71,90.61) 2971.71,58.8 3011.37,19.14 3187.69,19.14 3246.92,78.37 3246.92,240.36 3249.08,242.52 3249.08,404.51 3278.82,434.25 3278.82,592.49 3289.08,602.75 3289.08,909.86 3319.31,940.1 3319.31,1217.31 3254.23,1282.4 3254.23,1302.55 3234.45,1322.32 3201.65,1322.32 3157.33,1278 v2(3155,1278)
TX_OUT83: J10.98 U27.D11 | length 1553.5
  Top Layer w6: U27.D11@3221.03,1273.7 3278.95,1273.7 3389.42,1163.22 3389.42,1099.79 v1(3642.72,846.49)
  Bottom Layer w6: J10.98@3011.06,367.93 3011.06,478.58 3093.68,561.2 3147.55,561.2 3460.64,874.29 3614.92,874.29 v1(3642.72,846.49)
TX_OUT84: J9.23 U27.D10 | length 1634.7
  Top Layer w6: J9.23@3011.06,171.08 3011.06,111.54 v1(3025.82,96.77) ; v2(3180.64,1273.27) 3180.86,1273.48 3195.11,1273.48 U27.D10@3195.17,1273.43
  Layer 5 - SIG w5: v1(3025.82,96.77) 3083.46,39.14 3179.41,39.14 3226.92,86.65 3226.92,259.6 3229.08,261.75 3229.08,434.7 3237,442.62 3237,585.61 3269.08,617.69 3269.08,918.15 3299.06,948.13 3299.06,1207.06 3232.85,1273.27 v2@3181.83,1273.27
TX_OUT85: J10.102 U27.E11 | length 1433.9
  Top Layer w6: U27.E11@3221.03,1248.11 v2@3235.56,1248.11
  Layer 3 - SIG w4.5: v2(3236,1246) 3316.95,1165.05 3391.97,1090.03 3391.97,1046.92 v1(3618.15,820.74)
  Bottom Layer w6: J10.102@3050.43,367.93 3050.43,433.49 3063.37,446.43 3063.37,481.87 3114.9,533.4 3159.06,533.4 3472.15,846.49 3592.4,846.49 v1(3618.15,820.74)
TX_OUT86: J9.19 U27.E10 | length 1563.2
  Top Layer w6: v1@3050.15,111.79 J9.19@3050.15,170.8 ; v2@3181.19,1248.38 U27.E10@3195.72,1248.38
  Layer 5 - SIG w5: v1@3050.15,111.79 3050.15,127.15 3078,155 3078,377.63 3088.9,388.54 3088.9,429.16 3065.78,452.28 3065.78,527.53 3189.08,650.82 3189.08,957.99 3218.26,987.17 3218.26,1109.79 3177.41,1150.63 3090.62,1150.63 3067.38,1173.87 v2(3067.38,1174.88)
  Layer 14 - SIG w4.5: v2(3067.38,1174.88) 3067.38,1173.87 3089.98,1151.27 3111.95,1151.27 3112.58,1150.63 3125.42,1150.63 3126.05,1151.27 3170.55,1151.27 3192.21,1172.93 3192.21,1236.46 v2(3180.74,1247.93)
  other v1: 3050.15,106.79
TX_OUT87: J10.106 U27.F11 | length 1361.4
  Top Layer w6: U27.F11@3221.03,1222.51 3265.5,1222.51 3347.71,1140.31 3347.71,1090.39 3593.57,844.52 v1(3593.57,794.99)
  Bottom Layer w6: J10.106@3089.8,367.93 3089.8,427.6 3121.13,458.93 3121.13,492.64 3134.09,505.6 3172.41,505.6 3483.74,816.93 3571.64,816.93 v1(3593.57,794.99)
TX_OUT88: J9.15 U27.F10 | length 1539.9
  Top Layer w6: v1(3088.9,85.73) 3089.35,86.17 3089.35,170.63 J9.15@3089.8,171.08 ; v2(3163.71,1230.08) 3163.91,1229.87 3188.09,1229.87 U27.F10@3195.44,1222.51
  Layer 5 - SIG w5: v1(3088.9,85.73) 3088.9,70.91 3100.68,59.14 3171.12,59.14 3204.72,92.74 3204.72,211.03 3189.73,226.03 3189.73,366.09 3209.08,385.44 3209.08,442.98 3217,450.9 3217,593.89 3249.08,625.97 3249.08,926.43 3278.26,955.61 3278.26,1189.55 3237.74,1230.08 v2@3164.89,1230.08
TX_OUT89: J10.110 U27.G11 | length 1236.6
  Top Layer w6: U27.G11@3221.03,1196.92 v2@3235.56,1196.92
  Layer 3 - SIG w4.5: v2(3236.02,1196.47) 3299.51,1132.98 3299.51,1038.73 3316.95,1021.29 v1(3569,769.25)
  Bottom Layer w6: J10.110@3129.17,367.93 3129.17,431.48 3169.06,471.37 3177.5,471.37 3491.82,785.7 3552.55,785.7 v1(3569,769.25)
TX_OUT90: J9.11 U27.G10 | length 1334.1
  Top Layer w6: v1(3128.89,95.73) J9.11@3128.89,170.8 ; v2(3167,1207) 3173.46,1200.54 3190.79,1200.54 3194.41,1196.92 U27.G10@3195.44,1196.92
  Layer 5 - SIG w5: v1@3130.43,99.14 3128.89,100.68 3128.89,362.47 3144.06,377.63 3160.02,377.63 3167.73,385.34 3167.73,572.91 3229.08,634.26 3229.08,934.72 3258.26,963.9 3258.26,1144.97 3202.68,1200.54 3173.46,1200.54 v2(3167,1207)
TX_OUT91: J10.114 U27.H11 | length 1153.5
  Top Layer w6: U27.H11@3221.03,1171.33 3257.66,1171.33 3307.39,1121.61 3307.39,1079.88 3544.43,842.83 v1(3544.43,743.5)
  Bottom Layer w6: J10.114@3168.54,367.93 3168.54,430.21 3177.45,439.12 3202.93,439.12 3306.12,542.31 3306.12,543.33 3508.34,745.55 3531.37,745.55 3532.04,744.87 3543.05,744.87 v1(3544.43,743.5)
TX_OUT92: J9.7 U27.H10 | length 1361.7
  Top Layer w6: v2(3167.21,1169.85) 3167.97,1170.61 3194.71,1170.61 U27.H10@3195.44,1171.33 ; J9.7@3168.26,170.8 3168.54,170.53 v1(3168.54,95.73)
  Layer 5 - SIG w5: v2@3168.4,1169.85 3187.58,1169.85 3238.26,1119.17 3238.26,972.18 3209.08,943 3209.08,642.54 3125.98,559.45 3125.98,390.59 3098,362.61 3098,145.65 3091.5,139.15 3091.5,116.41 3108.9,99.01 3108.9,92.38 3122.15,79.14 3151.95,79.14 v1(3168.54,95.73)
TX_OUT93: J10.118 U27.J11 | length 1240.5
  Top Layer w6: U27.J11@3221.03,1145.74 v2@3235.56,1145.74
  Layer 3 - SIG w4.5: v2(3236.02,1145.29) 3225.91,1135.18 3225.91,1011.69 v1(3519.85,717.75)
  Bottom Layer w6: J10.118@3207.91,367.93 3208.7,367.14 3208.7,322.3 3221.14,309.86 3305.86,309.86 3553.26,557.26 3553.26,684.34 v1(3519.85,717.75)
TX_OUT94: J9.3 U27.J10 | length 1816.3
  Top Layer w6: v2(3119,1166.13) 3125.69,1166.13 3140.96,1150.87 3189.29,1150.87 3194.41,1145.74 U27.J10@3195.44,1145.74 ; J9.3@3207.91,171.08 3207.91,126.56 3221.03,113.43 v1(3266.92,113.43)
  Layer 5 - SIG w5: v2(3119,1166.13) 3119,1188.77 3102.7,1205.06 3102.7,1318.19 3127.6,1343.08 3261.85,1343.08 3342.29,1262.64 3342.29,934.79 3309.08,901.58 3309.08,155.59 v1(3266.92,113.43)
TX_OUT95: J10.120 U27.K11 | length 1020.8
  Top Layer w6: U27.K11@3221.03,1120.15 3221.99,1119.19 3247,1119.19 3266.92,1099.28 3266.92,1078.35 3495.28,849.99 v1(3495.28,692)
  Bottom Layer w6: J10.120@3244.79,375.29 J10.120@3237.44,367.93 3237.44,380.24 3248.8,391.61 3288.36,391.61 3495.28,598.53 v1(3495.28,692)
TX_OUT96: J9.1 U27.L11 | length 1507
  Top Layer w6: U27.L11@3221.03,1094.56 3221.03,1062.14 3467.48,815.7 3467.48,671.42 3470.71,668.2 v1(3470.71,666.25) ; J9.1@3237.44,171.08 3237.44,187.05 3248.2,197.81 v1(3270.75,197.81)
  Layer 11 - SIG w5: v1(3270.75,197.81) 3311.56,157 3514,157 3676,319 3676,460.96 v1(3470.71,666.25)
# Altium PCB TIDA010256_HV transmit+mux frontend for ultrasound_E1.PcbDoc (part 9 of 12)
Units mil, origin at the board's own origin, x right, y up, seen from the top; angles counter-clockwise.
Board outline 6192.49 x 6712.23 mil, 16 copper layers (Top Layer, Layer 2 - GND, Layer 3 - SIG, Layer 4 - GND, Layer 5 - SIG, Layer 6 - SIG, Layer 7 - GND, Layer 8 - HV PWR, Layer 9 - LV PWR, Layer 10 - GND, Layer 11 - SIG, Layer 12 - SIG, Layer 13 - GND, Layer 14 - SIG, Layer 15 - GND, Bottom Layer), stack 95.905 mil thick; 806 components, 539 nets, 3343 pads, 1848 vias.

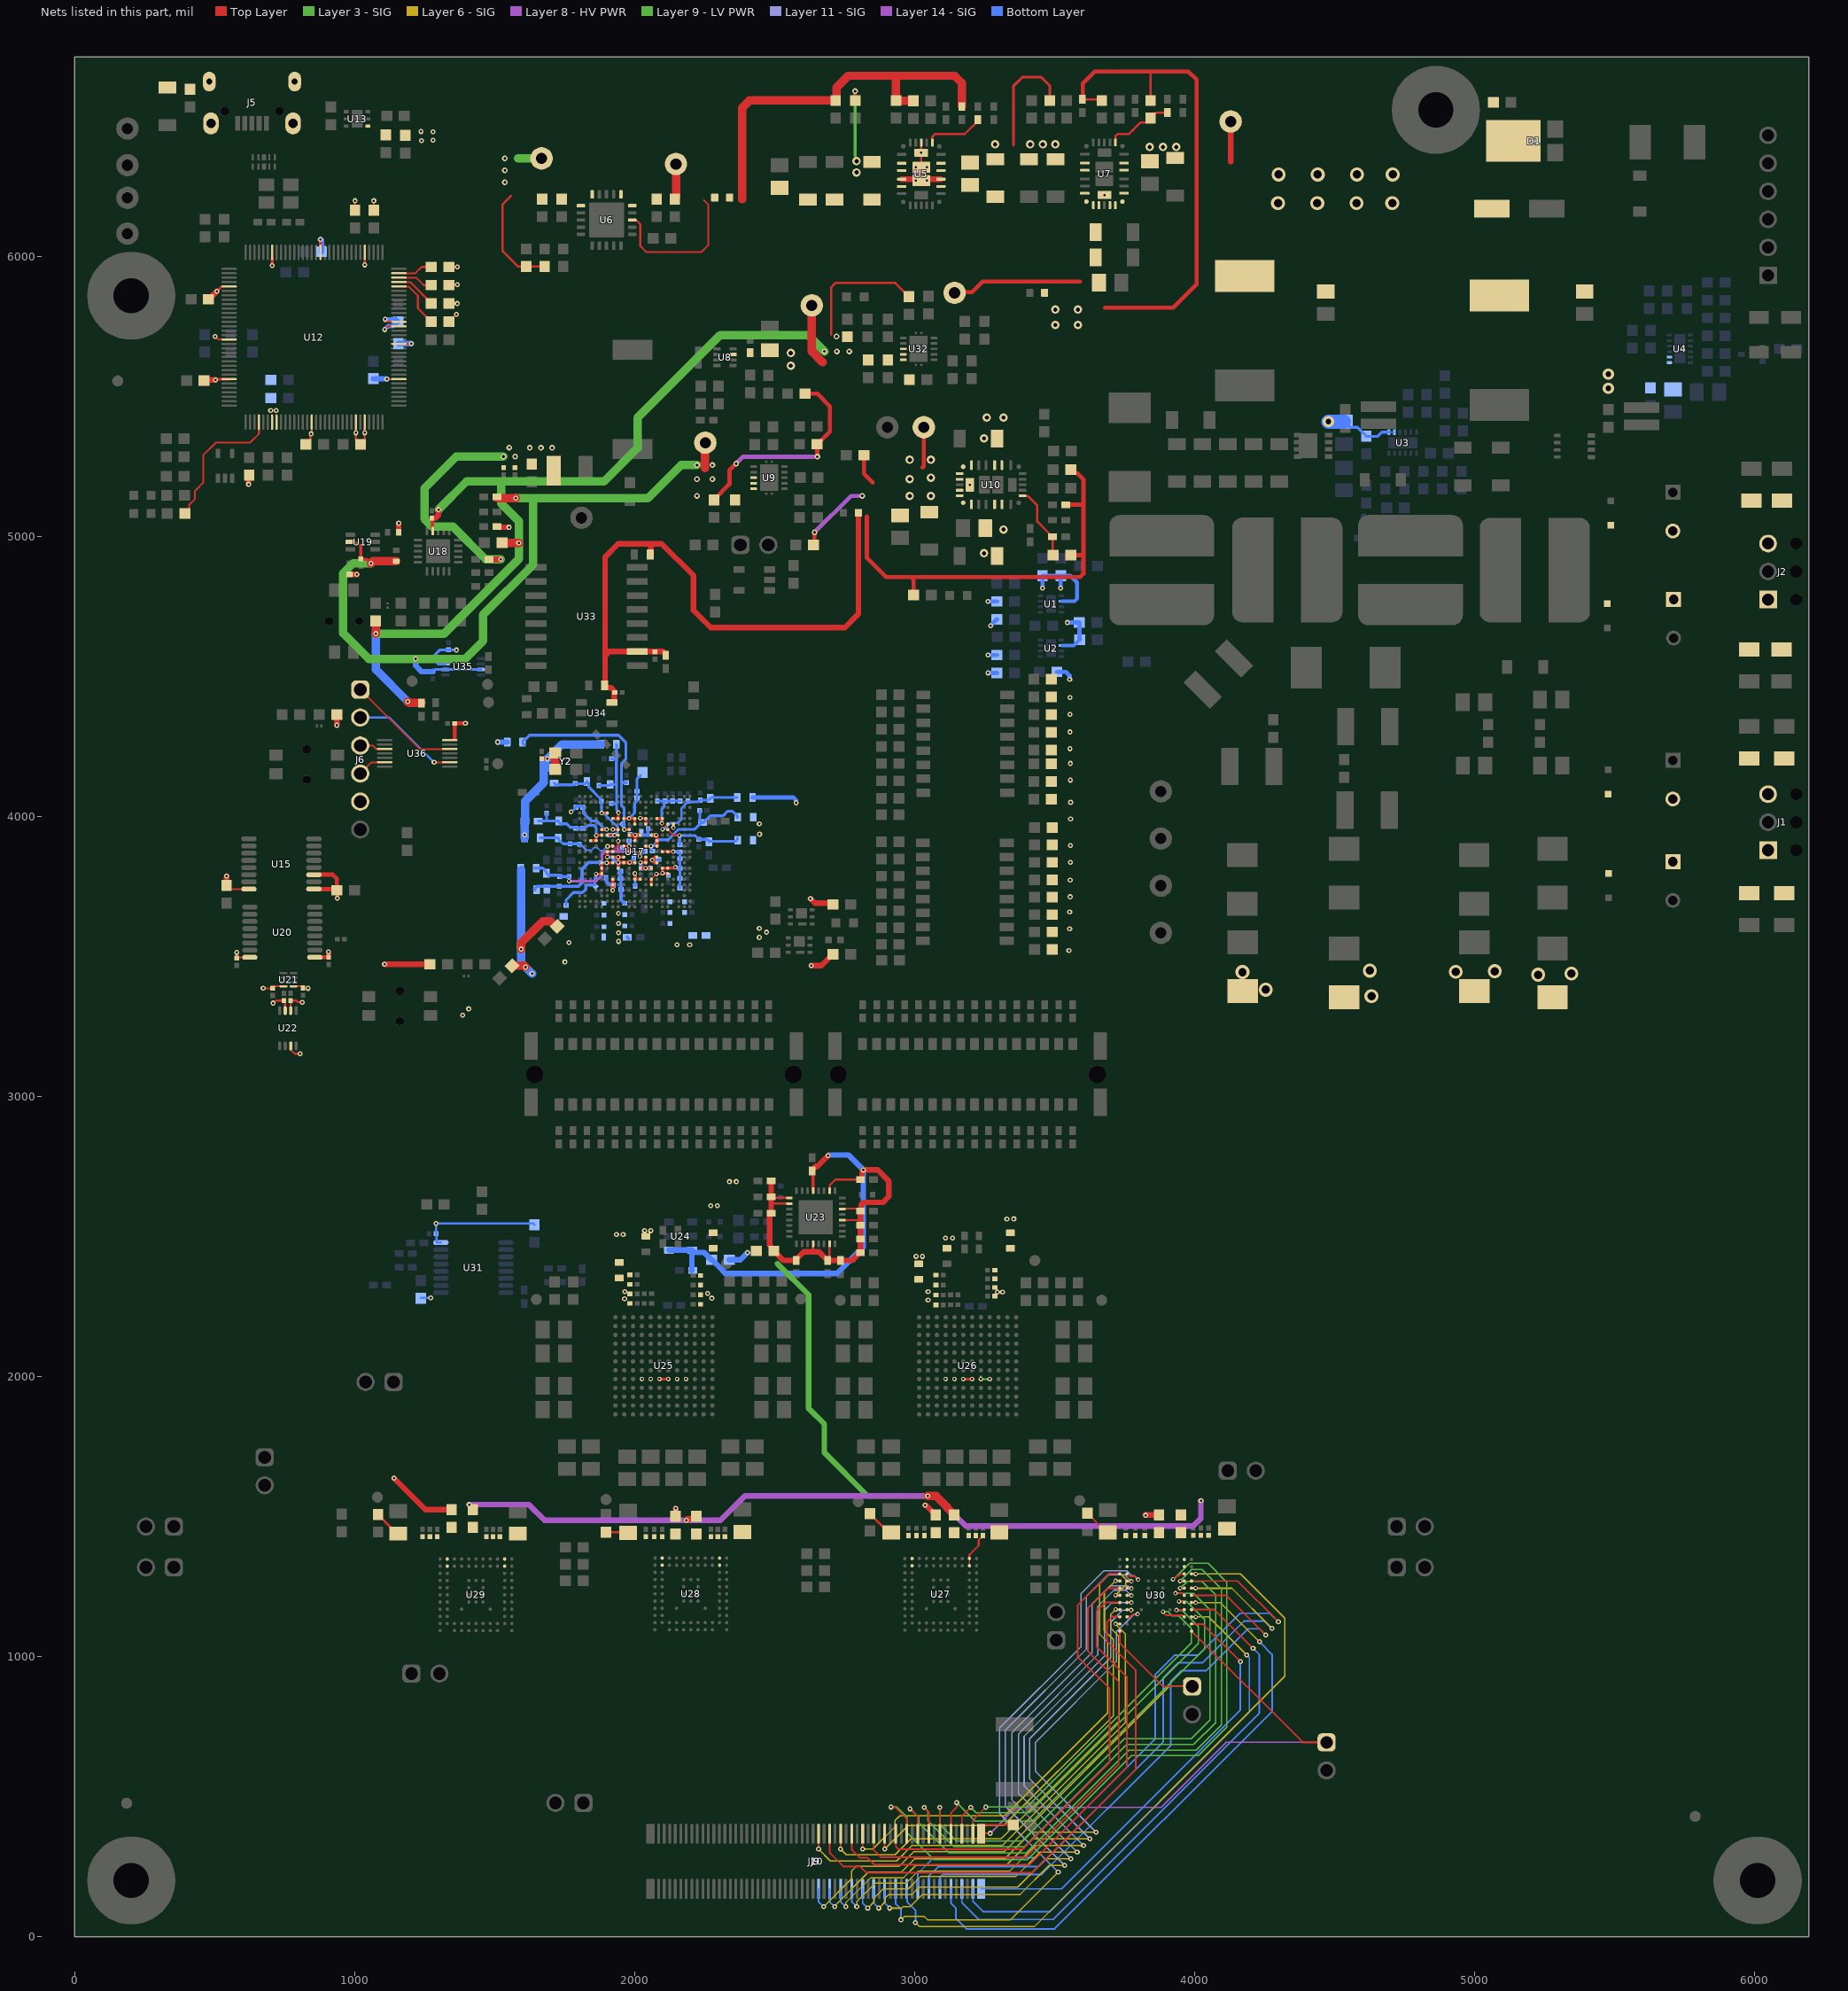
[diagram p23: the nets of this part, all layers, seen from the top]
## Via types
v1: diameter 18, hole 8, Top Layer to Bottom Layer, tented both sides, 930 vias
v2: diameter 16, hole 8, Top Layer to Bottom Layer, tented both sides, 340 vias
v3: diameter 16, hole 8, Top Layer to Bottom Layer, tented bottom, 226 vias
v4: diameter 20, hole 10, Top Layer to Bottom Layer, tented both sides, 129 vias
v5: diameter 50, hole 30, Top Layer to Bottom Layer, tented both sides, 96 vias
v6: diameter 30, hole 15, Top Layer to Bottom Layer, tented both sides, 47 vias
v7: diameter 19.68, hole 7.87, Top Layer to Bottom Layer, 40 vias
v8: diameter 19.68, hole 7.87, Top Layer to Bottom Layer, tented both sides, 19 vias
v9: diameter 18, hole 8, Top Layer to Bottom Layer, tented bottom, 13 vias
v10: diameter 40, hole 20, Top Layer to Bottom Layer, tented both sides, 4 vias
v11: diameter 40, hole 20, Top Layer to Bottom Layer, 3 vias
v12: diameter 18, hole 8, Top Layer to Bottom Layer, 1 vias

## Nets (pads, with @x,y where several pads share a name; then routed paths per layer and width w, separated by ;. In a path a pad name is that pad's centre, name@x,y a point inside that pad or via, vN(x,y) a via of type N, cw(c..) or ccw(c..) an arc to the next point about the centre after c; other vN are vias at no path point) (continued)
TX_OUT97: J10.61 J15.1 U30.L1 | length 2094.3
  Top Layer w6: U30.L1@3732.52,1091.23 3732.52,1047.3 3885.85,893.96 J15.1@3990.55,893.96
  Layer 6 - SIG w5: v1(2674.85,107.33) 2774.84,207.32 2774.84,234.77 2791.15,251.08 2943.96,251.08 2997.01,304.13 3319.28,304.13 3909.11,893.96 J15.1@3990.55,893.96
  Bottom Layer w6: J10.61@2656.73,171.08 2656.73,125.45 v1(2674.85,107.33)
TX_OUT98: J9.60 U30.K1 | length 1755.3
  Top Layer w6: v1(2656.73,313.2) J9.60@2656.73,367.93 ; v2@3717.54,1116.82 U30.K1@3732.52,1116.82 U30.K1@3731.56,1115.86
  Layer 6 - SIG w5: v1(2656.73,313.2) 2698.85,271.08 2935.68,271.08 2990.61,326.02 3312.88,326.02 3752.58,765.71 3752.58,1080.93 3717.54,1115.97 v2(3717.54,1117.27)
TX_OUT99: J10.65 U30.J2 | length 2186
  Top Layer w6: U30.J2@3758.11,1142.41 3758.84,1143.14 3770.54,1143.14 3776.54,1149.13 3793.13,1149.13 v2(3796,1152)
  Layer 6 - SIG w5: v1(2714.22,107.33) 2714.22,110.5 2834.8,231.08 2952.25,231.08 2999.68,278.52 3321.95,278.52 3416.94,373.51 v1(3647.93,373.51)
  Layer 11 - SIG w5: v1(3647.93,373.51) 3430.71,590.74 3430.71,693.81 3719.88,982.98 3719.88,1088.34 3783.54,1152 v2(3796,1152)
  Bottom Layer w6: J10.65@2696.1,171.08 2696.1,125.45 v1(2714.22,107.33)
TX_OUT100: J9.56 U30.J1 | length 1965.4
  Top Layer w6: J9.56@2696.1,367.93 2696.1,300.24 2723.27,273.07 2745.25,251.08 2805.08,251.08 2827.06,229.1 3420.21,229.1 3789.6,598.49 3789.6,950.57 3686.95,1053.23 3686.95,1124.87 3704.49,1142.41 U30.J1@3732.52,1142.41
TX_OUT101: J10.69 U30.H2 | length 2139.6
  Top Layer w6: U30.H2@3758.56,1167.55 3758.84,1167.27 3771.99,1167.27 v2(3772.75,1166.52)
  Layer 6 - SIG w5: v1(2753.59,107.33) 2753.59,121.59 2843.08,211.08 2960.53,211.08 3004.22,254.77 3326.48,254.77 3421.48,349.76 v1(3625.36,349.76)
  Layer 11 - SIG w5: v1(3625.36,349.76) 3410.71,564.42 3410.71,707.33 3699.88,996.5 3699.88,1123.58 3742.83,1166.52 v2(3772.75,1166.52)
  Bottom Layer w6: J10.69@2735.47,171.08 2735.47,125.45 v1(2753.59,107.33)
TX_OUT102: J9.52 U30.H1 | length 1686.9
  Top Layer w6: v1(2735.47,313.2) J9.52@2735.47,367.93 ; v2(3717.54,1168.45) 3717.76,1168.23 3732.29,1168.23 U30.H1@3732.52,1168
  Layer 6 - SIG w5: v1(2735.47,313.2) 2755.47,293.2 2929.52,293.2 2986.31,350 3308.58,350 3729.1,770.52 3729.1,1072.81 3699.88,1102.03 3699.88,1150.8 v2(3717.54,1168.45)
TX_OUT103: J10.73 U30.G2 | length 2151.7
  Top Layer w6: U30.G2@3758.56,1193.14 3758.93,1193.51 v2@3774.11,1193.51
  Layer 6 - SIG w5: v1(2792.96,107.33) 2792.96,125.44 2858.6,191.08 2968.82,191.08 3012.5,234.77 3339.78,234.77 3431.03,326.02 v1(3602.78,326.02)
  Layer 11 - SIG w5: v1(3602.78,326.02) 3390.71,538.09 3390.71,715.61 3677.72,1002.63 3677.72,1165.77 3705.38,1193.43 v2(3773.54,1193.43)
  Bottom Layer w6: J10.73@2774.84,171.08 2774.84,125.45 v1(2792.96,107.33)
TX_OUT104: J9.48 U30.G1 | length 1917.9
  Top Layer w6: J9.48@2774.84,367.93 2774.84,312.32 2805.09,282.06 2830.94,282.06 2856.11,256.9 3408.7,256.9 3758.11,606.31 3758.11,927.15 3649.49,1035.76 3649.49,1162.09 3680.99,1193.59 U30.G1@3732.52,1193.59 3717.99,1193.59
TX_OUT105: J10.77 U30.F2 | length 2163.5
  Top Layer w6: U30.F2@3758.56,1218.73 v2@3773.09,1218.73
  Layer 6 - SIG w5: v1(2832.33,102.33) 2832.89,102.33 2855.35,124.79 2855.35,139 2887.43,171.08 2977.1,171.08 3020.79,214.77 3360.63,214.77 3448.13,302.27 v1(3580.21,302.27)
  Layer 11 - SIG w5: v1(3580.21,302.27) 3370.71,511.77 3370.71,723.9 3653.57,1006.76 3653.57,1179.65 3711.97,1238.05 3753.77,1238.05 v2(3773.54,1218.28)
  Bottom Layer w6: J10.77@2814.21,171.08 2814.21,120.45 v1(2832.33,102.33)
TX_OUT106: J9.44 U30.F1 | length 1820
  Top Layer w6: v1(2814.21,313.2) J9.44@2814.21,367.93 ; v2(3717.54,1219.63) 3717.76,1219.41 3732.29,1219.41 U30.F1@3732.52,1219.18
  Layer 6 - SIG w5: v1(2814.21,313.2) 2850.75,313.2 2929.13,391.58 2929.13,414.23 2946.75,431.84 3321.83,431.84 3689,799.02 3689,1051.58 3660.99,1079.59 3660.99,1261.12 3695.37,1295.5 3735.08,1295.5 3754,1276.58 3754,1256.1 v2(3717.54,1219.63)
TX_OUT107: J10.81 U30.E2 | length 2144.2
  Top Layer w6: U30.E2@3758.56,1244.32 v2@3773.09,1244.32
  Layer 6 - SIG w5: v1(2871.7,102.33) 2872.26,102.33 2895,125.07 2895,139 2907.08,151.08 2990.15,151.08 3016.6,177.53 3367.71,177.53 3468.69,278.52 v1(3557.64,278.52)
  Layer 11 - SIG w5: v1(3557.64,278.52) 3346.68,489.48 3346.68,728.15 3633.57,1015.05 3633.57,1187.93 3698.69,1253.05 3761.39,1253.05 3770.56,1243.87 v2(3773.54,1243.87)
  Bottom Layer w6: J10.81@2853.58,171.08 2853.58,120.45 v1(2871.7,102.33)
TX_OUT108: J9.40 U30.E1 | length 1826.4
  Top Layer w6: J9.40@2853.58,367.93 2853.58,310.13 2879.01,284.7 3397.18,284.7 3728.34,615.86 3728.34,910.66 3618.15,1020.85 3618.15,1171.64 3691.28,1244.77 U30.E1@3732.52,1244.77
TX_OUT109: J10.85 U30.D2 | length 2148.4
  Top Layer w6: U30.D2@3758.56,1269.91 v2@3773.09,1269.91
  Layer 6 - SIG w5: v1(2911.07,102.33) 2954,102.33 2959,107.33 2983.78,107.33 3027.53,151.08 3376.36,151.08 3480.05,254.77 v1(3535.06,254.77)
  Layer 11 - SIG w5: v1(3535.06,254.77) 3323.2,466.63 3323.2,736.92 3613.57,1027.29 3613.57,1216.64 3689,1292.07 3750.93,1292.07 v2(3773.54,1269.46)
  Bottom Layer w6: J10.85@2892.95,171.08 2892.95,120.45 v1(2911.07,102.33)
TX_OUT110: J9.36 U30.D1 | length 1595
  Top Layer w6: v1(2892.95,313.2) J9.36@2892.95,367.93 ; v2(3717.54,1270.82) 3717.99,1270.36 U30.D1@3732.52,1270.36
  Layer 6 - SIG w5: v1(2892.95,313.2) 2976.75,397 3317.27,397 3709,788.73 3709,1061.31 3677,1093.31 3677,1230.28 v2(3717.54,1270.82)
TX_OUT111: J10.89 U30.C2 | length 2259.4
  Top Layer w6: U30.C2@3758.11,1295.95 3759.14,1295.95 3767.86,1287.23 3784.26,1287.23 3795.77,1275.73 v2(3797.39,1275.73)
  Layer 6 - SIG w5: v1(2950.99,61) 2952.32,61 2964.8,73.48 3033.23,73.48 3034.22,72.49 3034.41,72.49 3045.9,61 3342.47,61 v1(3512.49,231.02)
  Layer 11 - SIG w5: v1(3512.49,231.02) 3303.2,440.31 3303.2,745.2 3593.57,1035.57 3593.57,1224.92 3675.72,1307.07 3757.14,1307.07 3775.21,1289 3784.12,1289 v2(3797.39,1275.73)
  Bottom Layer w6: J10.89@2932.32,171.08 2932.32,116.54 2950.99,97.87 v1(2950.99,61)
TX_OUT112: J9.32 U30.C1 | length 1760.5
  Top Layer w6: J9.32@2932.32,367.93 2932.87,367.38 2932.87,322.3 2942.67,312.5 3385.67,312.5 3695.43,622.26 3695.43,886.92 3581.84,1000.51 3581.84,1182.81 3694.98,1295.95 U30.C1@3732.52,1295.95 3717.99,1295.95
TX_OUT113: J10.93 U30.C11 | length 2424.5
  Top Layer w6: U30.C11@3988.42,1295.95 v2@4002.95,1295.95
  Layer 6 - SIG w5: v1(3002.84,51) 3017.84,36 3427,36 4321.2,930.2 4321.2,1137.8 4163.5,1295.5 v2(4003.4,1295.5)
  Bottom Layer w6: J10.93@2971.69,171.08 2972.62,170.15 2972.62,125.45 3003,95.07 v1@3003,59.75
TX_OUT114: J9.28 U30.C10 | length 2436.9
  Top Layer w6: v1@2919.94,463.1 2929.92,463.1 2971.69,421.33 J9.28@2971.69,367.93 ; v2(3922.49,1276.13) 3924.12,1276.13 3936.58,1288.6 3942.91,1288.6 3949.54,1295.22 3962.1,1295.22 U30.C10@3962.83,1295.95
  Layer 3 - SIG w4.5: v1(2915.59,463.1) 2936.15,463.1 2972,427.25 2972,372.01 3068.16,275.85 3402.87,275.85 3773.51,646.49 4012.96,646.49 4114.83,748.36 4114.83,1265.68 4047.65,1332.87 3981.79,1332.87 3925.06,1276.13 v2(3922.49,1276.13)
TX_OUT115: J10.97 U30.D11 | length 2245
  Top Layer w6: U30.D11@3988.42,1270.36 4152.84,1270.36 v1(4298.63,1124.58)
  Bottom Layer w6: J10.97@3011.06,171.08 3011.06,225.65 3067.98,282.57 3084.88,282.57 3085.38,282.06 3317.38,282.06 3317.88,282.57 3434.9,282.57 3859.09,706.76 3859.09,936.01 3928.92,1005.83 4012.83,1005.83 4162.03,1155.03 4268.15,1155.03 v1(4298.63,1124.58)
TX_OUT116: J9.24 U30.D10 | length 2169
  Top Layer w6: v1(2983.78,456.64) 3011.06,429.36 J9.24@3011.06,367.93 ; v2(3948.03,1269.93) 3948.25,1270.15 3962.5,1270.15 U30.D10@3962.56,1270.09
  Layer 3 - SIG w4.5: v1(2983.78,456.64) 3014.24,426.18 3014.24,407.23 3122.47,299 3397.73,299 3765.22,666.49 4004.67,666.49 4094.83,756.65 4094.83,1241.26 4025.1,1311 3989.1,1311 v2(3948.03,1269.93)
TX_OUT117: J10.101 U30.E11 | length 2140.6
  Top Layer w6: U30.E11@3988.42,1244.77 v2@4002.95,1244.77
  Layer 6 - SIG w5: v2(4003.4,1244.32) 4132.56,1244.32 v1(4276.05,1100.83)
  Bottom Layer w6: J10.101@3050.43,171.08 3050.43,217.29 3083.94,250.8 3442.45,250.8 3886.89,695.25 3886.89,924.49 3940.43,978.03 4027.03,978.03 4176.23,1127.23 4247.7,1127.23 4274.1,1100.83 v1(4276.05,1100.83)
TX_OUT118: J9.20 U30.E10 | length 2032.1
  Top Layer w6: v1(3033.89,462.53) 3050.43,445.98 J9.20@3050.43,367.93 ; v2@3948.58,1245.05 U30.E10@3963.11,1245.05
  Layer 3 - SIG w4.5: v1(3033.89,462.53) 3047.24,449.17 3047.24,414.88 3140.59,321.53 3391.97,321.53 3756.94,686.49 3996.39,686.49 4074.83,764.93 4074.83,1220.73 4026.1,1269.46 3972.99,1269.46 v2(3948.13,1244.6)
TX_OUT119: J10.105 U30.F11 | length 2039.7
  Top Layer w6: U30.F11@3988.42,1219.18 4111.38,1219.18 v1(4253.48,1077.08)
  Bottom Layer w6: J10.105@3089.8,171.08 3089.8,212.11 3100.69,223 3453.96,223 3914.69,683.73 3914.69,912.98 3951.26,949.54 4040.45,949.54 4190.35,1099.43 4231.13,1099.43 v1(4253.48,1077.08)
TX_OUT120: J9.16 U30.F10 | length 1903.3
  Top Layer w6: v1(3088.9,462.53) 3089.35,462.08 3089.35,368.38 J9.16@3089.8,367.93 ; v2(3931.1,1226.74) 3931.3,1226.53 3955.48,1226.53 U30.F10@3962.83,1219.18
  Layer 3 - SIG w4.5: v1(3088.9,462.53) 3088.9,401.5 3148.88,341.53 3383.69,341.53 3748.65,706.49 3988.11,706.49 4054.83,773.22 4054.83,1167.96 3996.05,1226.74 v2(3931.1,1226.74)
TX_OUT121: J10.109 U30.G11 | length 2146.7
  Top Layer w6: U30.G11@3988.42,1193.59 v2@4002.95,1193.59
  Layer 6 - SIG w5: v2(4003.4,1193.14) 4091.1,1193.14 v1(4230.91,1053.33)
  Bottom Layer w6: J10.109@3129.17,171.08 3129.17,120.56 3147.55,102.18 3147.55,64.92 3184.47,28 3499.64,28 4276.05,804.41 4276.05,1008.18 v1(4230.91,1053.33)
TX_OUT122: J9.12 U30.G10 | length 1528.3
  Top Layer w6: J9.12@3129.17,367.93 3129.17,441.53 3150,462.36 v1(3150,479) ; v2(3944.1,1197.21) 3958.18,1197.21 3961.8,1193.59 U30.G10@3962.83,1193.59
  Layer 3 - SIG w4.5: v1(3150,479) 3215.31,413.69 3420.6,413.69 4034.83,1027.92 4034.83,1132.45 3970.07,1197.21 v2(3944.1,1197.21)
TX_OUT123: J10.113 U30.H11 | length 1959.1
  Top Layer w6: U30.H11@3988.42,1168 4069.91,1168 v1(4208.33,1029.58)
  Bottom Layer w6: J10.113@3168.54,171.08 3168.54,121.75 3228.21,62.07 3494.4,62.07 4230.91,798.58 4230.91,1007.01 v1(4208.33,1029.58)
TX_OUT124: J9.8 U30.H10 | length 1371.8
  Top Layer w6: J9.8@3168.54,367.93 3168.54,431.03 v1(3199.6,462.09) ; v2(3934.6,1166.52) 3935.35,1167.27 3962.1,1167.27 U30.H10@3962.83,1168
  Layer 3 - SIG w4.5: v1(3199.6,462.09) 3218.81,442.89 3409.66,442.89 4013.52,1046.74 4013.52,1107.16 3955.88,1164.8 3936.32,1164.8 v2(3934.6,1166.52)
TX_OUT125: J10.117 U30.J11 | length 1802.4
  Top Layer w6: U30.J11@3988.42,1142.41 v2@4002.95,1142.41
  Layer 6 - SIG w5: v2(4003.4,1141.96) 4049.64,1141.96 v1(4185.76,1005.83)
  Bottom Layer w6: J10.117@3207.91,171.08 3207.91,127.07 3245.11,89.87 3482.88,89.87 4195.03,802.02 4195.03,996.25 4185.76,1005.52 v1(4185.76,1005.83)
TX_OUT126: J9.4 U30.J10 | length 1352.9
  Top Layer w6: J9.4@3207.91,367.93 3207.91,416.73 v1(3254.07,462.89) ; v2(3887,1161) 3887,1160 3899.47,1147.53 3956.67,1147.53 3961.8,1142.41 U30.J10@3962.83,1142.41
  Layer 3 - SIG w4.5: v1(3254.07,462.89) 3401.38,462.89 3988.1,1049.61 3988.1,1101.54 3944.11,1145.53 3919.07,1145.53 3903.61,1161 v2(3887,1161)
TX_OUT127: J10.119 U30.K11 | length 1593.4
  Top Layer w6: U30.K11@3988.42,1116.82 3989.38,1115.86 4029.41,1115.86 v1(4163.19,982.09)
  Bottom Layer w6: J10.119@3237.44,171.08 3524.78,171.08 4163.19,809.49 v1(4163.19,982.09)
TX_OUT128: J9.2 J17.1 R166.2 U30.L11 | length 2154.7
  Top Layer w6: v1(3269.2,369.44) 3238.95,369.44 J9.2@3237.44,367.93 3237.44,388.6 3248.83,400 R166.2@3351.33,400 ; U30.L11@3988.42,1091.23 4385.69,693.96 J17.1@4470.84,693.96
  Layer 14 - SIG w4.5: v1(3269.2,369.44) 3361.85,462.09 3881,462.09 4112.87,693.96 J17.1@4470.84,693.96
UART1_HDR_CTS#: J6.4 U36.6 | length 104
  Top Layer w6.8: J6.4@1020.1,4153.02 1060.21,4193.12 U36.6@1107.5,4193.12
UART1_HDR_RTS#: J6.1 U36.12 | length 407.8
  Top Layer w6.8: J6.1@1020.1,4453.02 1232.75,4240.37 U36.12@1339.79,4240.37
UART1_HDR_RXD: J6.3 U36.3 | length 92.6
  Top Layer w6.8: J6.3@1020.1,4253.02 1064.58,4253.02 1077.17,4240.43 1107.44,4240.43 U36.3@1107.5,4240.37
UART1_HDR_TXD: J6.2 U36.9 | length 385.9
  Top Layer w6.8: v1(1283.9,4193.12) U36.9@1339.79,4193.12
  Bottom Layer w8: J6.2@1020.1,4353.02 1124,4353.02 v1(1283.9,4193.12)
USB_SHIELD: C100.2 J5.Z1 J5.Z2 J5.Z3 J5.Z4 R75.1
V1_+5V: C250.1 C251.1 C252.1 C253.1 FB12.2 U25.E6 U25.E7 U25.E8 U25.E9 | length 31.5
  Top Layer w10: v3(2088.75,1991.23) v3(2120.24,1991.23)
  other v1: 1963.95,2278.03 1964.95,2303.03
  other v3: 2025.76,1991.23 2057.25,1991.23
V1_-5V: C254.1 C255.1 C256.1 C257.1 FB13.2 U25.E4 U25.E5
  other v1: 2275.55,2280.03 2260.25,2297.13
  other v3: 2151.74,1991.23 2183.24,1991.23
V2_+5V: C281.1 C282.1 C283.1 C284.1 FB15.2 U26.E6 U26.E7 U26.E8 U26.E9 | length 31.5
  Top Layer w10: v3(3173.53,1991.23) v3(3205.02,1991.23)
  other v1: 3047.54,2273.23 3047.54,2303.58
  other v3: 3110.54,1991.23 3142.03,1991.23
V2_-5V: C285.1 C286.1 C287.1 C288.1 FB16.2 U26.E4 U26.E5 | length 40.9
  Layer 9 - LV PWR w6.8: 3236.52,2000.66 v3(3236.52,1991.23) v3(3268.02,1991.23)
  other v1: 3295.35,2301.73 3313.25,2302.13
V_+5.5V: C61.1 C64.1 C65.1 C66.1 C74.1 C75.1 L12.1 R44.2 R47.1 TP4.1 U7.7 U7.8 U7.9 U7.10 U7.12 U7.13 U7.14 U7.15 U7.30 U8.3 | length 2225.5
  Top Layer w8: C61.1@3598.72,6559.92 3664.3,6559.92 R44.2@3668.41,6555.81 ; R47.1@3842.49,6555.81 3842.49,6659.32
  Top Layer w15: TP4.1@3142.49,5869.32 3144.99,5871.82 3204.99,5871.82 3242.49,5909.32 3590.3,5909.32 ; C61.1@3598.72,6559.92 3600.59,6561.8 3600.59,6617.42 3642.49,6659.32 3842.49,6659.32 3977.49,6659.32 4006.6,6630.2 4006.6,5899.79 3923.13,5816.32 3679.1,5816.32
  other v6: 2557.49,5609.32 2557.49,5654.32 3502.49,5754.32 3582.49,5754.32 3502.49,5809.32 3582.49,5809.32
  other v8: 3677.37,6218.65
V_+12V: C16.1 C17.1 C28.1 C29.1 C41.1 C44.1 C48.1 C49.1 C50.1 C51.1 C58.1 C59.1 C60.1 C81.1 C82.1 C83.1 D1.3 L1.1 L6.1 R9.2 R22.2 R36.2 R46.2 TP6.1 U3.1 U3.2 U4.1 U4.2 U5.3 U5.4 U5.18 U5.19 U7.3 U7.4 U7.18 U7.19 U10.3 U10.4 U10.18 U10.19 | length 1093.3
  Top Layer w10: v4(2787.49,6589.32) 2787.49,6556.84 R36.2@2788.51,6555.81 ; 3352.5,6396.98 3352.5,6607.62 3384.2,6639.32 3452.49,6639.32 3482.49,6609.32 R46.2@3482.49,6555.81
  Top Layer w20: 4128.3,6337.26 TP6.1@4128.3,6480.82
  Layer 9 - LV PWR w10: v4(2787.49,6589.32) 2787.49,6358.03 2788.4,6357.12
  Bottom Layer w5: U3.1@4693.28,5371.72 U3.2@4712.96,5371.72
  Bottom Layer w10: R9.2@4532.49,5409.32 4552.49,5389.32 4581.47,5389.32 4612.49,5358.29 C16.1@4612.49,5357.31 4653.85,5357.31 4668.26,5371.72 U3.1@4693.28,5371.72
  Bottom Layer w50: v11(4477.49,5409.32) R9.2@4532.49,5409.32
  other v5: 4297.49,6189.32 4437.49,6189.32 4577.49,6189.32 4705.49,6189.32 4299.09,6291.82 4439.09,6291.82 4579.09,6291.82 4707.09,6291.82
  other v6: 3247.49,4939.32 3317.49,5024.32 3247.49,5349.32 3257.49,5424.32 3317.49,5424.32 2792.49,6299.32 2792.49,6339.32 3839.42,6389.82 3886.81,6389.82 3934.2,6389.82 3287.49,6399.32 3412.49,6399.32 3457.49,6399.32 3502.49,6399.32
  other v11: 5477.2,5528.02 5477.2,5579.32
V_+50V_B: C5.1 C6.1 D10.1 D22.2 J2.1 R4.2
  other v5: 5226.23,3434.8 5344.74,3439.19
V_+100V_A: C1.1 C2.1 D9.1 D17.2 J1.1 R3.2
  other v5: 4630.83,3358.1 4625.21,3449.52
V_-5.5V: C45.2 C46.2 C47.2 C49.2 C50.2 C51.2 C55.2 L11.1 R38.1 R39.1 R43.1 U5.5 U5.6 U5.16 U5.17 U5.24 U5.27 U5.28 U5.29 | length 1846
  Top Layer w8: U5.28@3022.49,6317.23 U5.27@3022.49,6369.4 ; v8(3023.63,6369.4) U5.24@3023.63,6405.81
  Top Layer w20: U5.5@2953.75,6274.91 U5.29@3023.63,6274.91 ; v8(3003.95,6317.23) 3013.95,6317.23 3023.63,6307.54 U5.29@3023.63,6274.91 ; U5.29@3023.63,6269.99 U5.29@3023.63,6274.91 ; U5.17@3093.51,6274.91 U5.29@3023.63,6274.91
  Top Layer w30: 2384.2,6203.02 2384.2,6530.22 2409.8,6555.81 R39.1@2717.49,6555.81 2721.19,6559.51 2721.19,6603.02 2762.49,6644.32 2932.49,6644.32 ; R38.1@2995.29,6554.32 2994.55,6555.06 2934.26,6555.06 R43.1@2933.51,6555.81 2933.51,6643.29 2932.49,6644.32 ; C55.2@3168.93,6534.46 3168.93,6617.88 3157.48,6629.33 3142.49,6644.32 2932.49,6644.32
  Layer 8 - HV PWR w20: v8(3043.32,6269.99) v8(3003.95,6269.99) v8(3003.95,6317.23) v8(3043.32,6317.23)
V_-5.5V_filt: C42.1 C43.1 L11.2 TP2.1 U6.13 U6.15 U6.16 | length 667.6
  Top Layer w6.8: U6.13@1991.19,6129.32 1993.29,6127.21 2007.22,6127.21 2019.95,6114.48 2019.95,6036.85 2042.49,6014.32 2237.49,6014.32 2262.49,6039.32 2262.49,6184.32 2247.49,6199.32 ; C43.1@2143.51,6204.32 2143.51,6205.3 C43.1@2147.49,6209.28
  Top Layer w30: C43.1@2147.49,6209.28 TP2.1@2147.49,6329.32
V_-5V: C39.1 C52.1 C53.1 FB13.1 FB16.1 R34.2 TP1.1 U6.1 U6.20 | length 468.1
  Top Layer w8: 1557.49,6214.32 1527.49,6184.32 1527.49,6019.32 1583.99,5962.82 R34.2@1612.49,5962.82 C39.1@1678.61,5962.82
  Top Layer w30: TP1.1@1667.49,6349.32 TP1.1@1668.57,6348.23
  Layer 9 - LV PWR w30: 1582.85,6349.32 TP1.1@1667.49,6349.32
  other v1: 3329.25,2563.13 3354.15,2563.23 2271.75,2610.33 2295.45,2610.33 1386.03,3289.88 1407.33,3313.08
  other v4: 1536.6,6263.82 1536.6,6306.62 1536.6,6349.42
V_-50V_B: C10.2 C11.1 D12.2 D24.1 J2.3 R8.2
  other v5: 4932.15,3445.46 5071.35,3447.34
V_-100V_A: C8.2 C9.1 D11.2 D19.1 J1.3 R5.2
  other v5: 4253.49,3381.32 4170.49,3444.32
V_LMK3.3: C223.1 C225.1 C226.1 C227.1 C228.1 C229.1 C230.1 C231.1 C232.1 C233.1 C234.1 C235.1 C236.1 R152.2 R153.2 U23.2 U23.5 U23.9 U23.10 U23.20 U23.23 U23.28 U23.30 U24.1 U24.6 | length 3006.1
  Top Layer w6: U23.30@2735.14,2598.26 2733.97,2599.43 C231.1@2795.85,2599.43
  Top Layer w6.8: 2487.39,2620.33 2489.78,2617.95 U23.10@2552.4,2617.95 ; C227.1@2490.07,2638.36 2545.44,2638.36 U23.9@2546.16,2637.63 ; 2637.04,2445.58 U23.20@2637.04,2474.25 ; C229.1@2689.15,2414.86 2695.37,2421.08 2695.37,2473.52 U23.23@2696.1,2474.25 ; U23.2@2696.1,2663.22 2696.1,2682.47 2717.06,2703.43 C235.1@2805.56,2703.43 ; U23.28@2735.14,2558.89 2735.48,2559.23 2806.25,2559.23
  Top Layer w10: C236.1@2634.55,2733.91 2636.77,2731.7 2636.77,2663.5 U23.5@2637.04,2663.22
  Top Layer w20: C232.1@2487.39,2699.03 C227.1@2487.39,2641.03 2487.39,2620.33 C226.1@2487.39,2583.03 2483.46,2583.03 2481.65,2581.22 2481.65,2468.95 2487.26,2463.34 2487.26,2457.24 2495.96,2448.53 R153.2@2496.95,2448.53 2497.93,2448.53 2531.61,2414.86 C225.1@2577.05,2414.86 2578.86,2416.67 2578.86,2420.6 2603.84,2445.58 2637.04,2445.58 2658.42,2445.58 2683.4,2420.6 2687.34,2420.6 2689.15,2418.79 C229.1@2689.15,2414.86 C233.1@2735.05,2414.86 2776.86,2414.86 2788.58,2426.57 2788.58,2428 2802.31,2441.73 C234.1@2806.25,2441.73 C230.1@2806.25,2491.47 C228.1@2806.25,2541.21 2806.25,2559.23 C231.1@2806.25,2590.95 2806.84,2590.95 2808.65,2592.77 2808.65,2612.33 2818.15,2621.83 2886.45,2621.83 2907.75,2643.13 2907.75,2697.95 2867.98,2737.72 v1(2816.49,2737.72) 2812,2733.23 2812,2705.24 2810.19,2703.43 C235.1@2806.25,2703.43 C235.1@2805.56,2703.43 ; C236.1@2634.55,2733.91 2634.55,2737.85 2647.11,2750.41 2653.01,2750.41 v1(2691.25,2788.65)
  Bottom Layer w20: U24.1@2122.59,2451.63 U24.6@2205.26,2451.63 ; C223.1@2203.47,2378.73 2204.37,2379.63 2204.37,2441.74 U24.6@2205.26,2442.63 ; U24.6@2205.86,2443.23 2247.87,2443.23 2273.87,2417.23 R152.2@2274.85,2417.23 2275.84,2417.23 2301.16,2391.91 2301.16,2391.49 2324.42,2368.23 2722.05,2368.23 2816.49,2462.68 v1(2816.49,2737.72) 2762.98,2791.23 2693.84,2791.23 v1(2691.25,2788.65)
VCC3P3_XDS: C69.1 C85.1 C98.1 C99.1 C102.1 C103.1 C104.1 C105.1 C106.1 C107.1 C108.1 C109.1 C115.1 C217.1 C219.1 C221.1 R74.1 R82.2 R83.2 R84.2 R85.2 R86.2 R87.2 U12.7 U12.8 U12.16 U12.26 U12.28 U12.39 U12.47 U12.51 U12.52 U12.69 U12.79 U12.90 U12.101 U12.113 U12.122 U13.1 U15.16 U20.16 U21.8 U22.7 | length 1683.7
  Top Layer w6.8: v1(501.71,5713.76) 512.53,5702.94 U12.113@551.75,5702.94 ; C115.1@542.8,3753.11 555.17,3740.75 U15.16@622.46,3740.75 ; U12.101@551.75,5891.92 U12.101@551.75,5891.92 ; v1(578.7,3514.32) 578.8,3514.22 578.8,3497.14 578.9,3497.04 U20.16@625.72,3497.04 U20.16@624.16,3495.47 ; v1(673.51,3386.31) C219.1@707.2,3386.31 707.2,3387.1 713.9,3393.79 U21.8@746.29,3393.79 ; U12.90@705.3,6013.97 705.5,6013.76 U12.90@705.5,5991.41 ; v1(708.5,3333.52) 710.13,3333.52 718.93,3342.32 C221.1@747.5,3342.32 751.33,3338.49 751.33,3307.54 U22.7@752.06,3306.81 ; C103.1@809.3,5328.34 809.46,5328.5 809.46,5330.19 828.41,5330.19 841.87,5343.64 841.87,5359.56 845.27,5362.96 v1(845.27,5365.99) ; C103.1@809.46,5328.34 C103.1@825.58,5328.34 ; v1@847.03,5368.12 U12.16@847.03,5407.67 ; R87.2@1001.2,6164.31 v1(1001.2,6198.01) ; U12.26@1004.45,5407.6 1004.51,5407.54 v1(1004.51,5369.73) 1004.51,5345.13 1005.02,5344.62 1005.02,5343.64 1020.32,5328.34 C105.1@1021.3,5328.34 ; C105.1@1019.21,5328.34 1020.2,5328.34 1035.5,5343.64 1035.5,5344.62 1036.01,5345.13 v1(1036.01,5369.73) ; C105.1@1028.21,5320.55 C105.1@1028.65,5320.99 ; U12.28@1036.01,5407.67 v1(1036.01,5369.73) ; U12.69@1036.01,6013.97 1036.07,6013.9 U12.69@1036.07,5988.05 ; U12.28@1036.07,5407.6 1036.01,5407.54 v1(1036.01,5369.73) ; v1(1036.1,5969.02) U12.69@1036.1,5988.02 ; R74.1@1068.4,6164.31 v1(1068.4,6198.01) ; v1(1107.3,5738.22) 1119.27,5750.19 U12.51@1158.05,5750.19 ; v1(1108.6,5774.42) 1110.01,5774.42 1118.49,5765.93 U12.52@1158.05,5765.93 ; v1(1114.71,5561.21) U12.39@1158.05,5561.21 ; R85.2@1336.99,5766.72 1337.97,5766.72 v1(1363.42,5792.17) ; R84.2@1336.99,5831.72 1337.59,5831.12 v1(1366.2,5831.12) ; R83.2@1336.99,5896.72 1338.49,5898.22 v1(1367.1,5898.22) ; R82.2@1336.99,5961.72 v1(1366.6,5961.72) ; U12.79@878.53,6013.97 U12.79@878.57,6013.93
  Top Layer w8: U12.47@1158.05,5687.19 1158.12,5687.26 1201.28,5687.26 v1(1202.19,5688.17)
  Top Layer w9: v1@503.64,5561.21 U12.122@551.75,5561.21 ; v1(508.14,5875.18) U12.101@524.88,5891.92
  Top Layer w10: U12.90@705.5,5991.41 705.5,5966.82 v1(705.7,5966.62) ; U12.79@878.28,6031.71 v1@878.55,6059.97
  Top Layer w20: C104.1@462.7,5547.08 462.7,5548.74 472.39,5558.43 v1(503.64,5558.43) ; C102.1@478.53,5846.32 479.51,5846.32 502.51,5869.31 502.51,5869.55 v1(508.14,5875.18) ; C115.1@542.8,3753.11 v1(542.8,3786.81) ; v1(621.18,5185.87) 621.18,5215.93 R86.2@623.16,5217.92
  Bottom Layer w16: v1@1107.69,5738.6 1119.33,5750.24 1136.23,5750.24 1140.83,5754.84 1145.6,5754.84 1156.3,5765.54 C85.1@1156.3,5766.52 C85.1@1145.95,5776.87 ; v1(1108.6,5774.42) C85.1@1145.95,5774.42
  Bottom Layer w20: v1(878.57,6059.99) 882.1,6056.45 C69.1@882.1,6016.6 ; C106.1@1067,5562.5 1113.42,5562.5 v1(1114.71,5561.21) ; C107.1@1156.3,5688.17 v1(1202.19,5688.17)
  other v1: 700.27,5448.98 719.93,5448.98 1238.8,6412.52 1279.8,6413.92 1279.6,6443.82 1237.6,6445.12
VCORE_0.85V: C78.1 C79.1 C80.1 C155.1 C156.1 C157.1 C158.1 C159.1 C160.1 C161.1 C162.1 C163.1 C164.1 C165.1 C166.1 C167.1 C168.1 C169.1 C170.1 C171.1 C172.1 C173.1 C174.1 C175.1 C176.1 R56.2 R128.2 U17.F11 U17.G5 U17.G6 U17.G10 U17.H8 U17.H15 U17.J9 U17.J10 U17.J12 U17.K11 U17.K14 U17.L9 U17.L13 U17.M8 U17.M14 U17.N9 U17.N10 U17.P8 U17.P14 U17.R9 U17.R10 U17.R12 U17.R13 U17.V16 | length 1866.6
  Top Layer w10: U17.J12@1961.03,3894 v2@1979.89,3894 ; U17.K11@1980.72,3874.32 v2@1980.72,3894
  Top Layer w12: U17.F11@1901.98,3874.32 1901.98,3855.1 v2(1902.25,3854.83) ; v2(1921.49,3736.32) 1921.66,3736.49 U17.G5@1921.66,3756.21 U17.G6@1921.66,3775.89 ; v2@1921.49,3953.58 1922.02,3953.06 U17.H15@1941.35,3953.06 ; U17.G10@1921.66,3854.63 v2(1941.35,3854.63) ; U17.H8@1941.35,3815.26 v2(1941.35,3854.63) ; v2@1941.86,3834.95 U17.J9@1961.03,3834.95 1961.4,3835.32 v2(1981.49,3835.32) 2000.03,3835.32 U17.L9@2000.4,3834.95 ; U17.J10@1961.03,3854.63 v2(1941.35,3854.63) ; U17.K14@1980.72,3933.37 v2(2001.55,3933.37) ; U17.L13@2000.4,3913.69 2001.55,3914.83 v2(2001.55,3933.37) ; U17.M8@2020.09,3815.26 v2(2039.77,3815.26) U17.P8@2059.46,3815.26 ; U17.M14@2020.09,3933.37 v2(2001.55,3933.37) ; v2(2020.49,3835.32) 2039.4,3835.32 U17.N9@2039.77,3834.95 U17.N10@2039.77,3854.63 ; U17.P14@2059.46,3933.37 v2(2076.34,3933.37) 2079.14,3933.37 U17.R13@2079.14,3913.69 U17.R12@2079.14,3894 ; U17.R9@2079.14,3834.95 2071.46,3834.95 v2(2062.2,3844.2) 2072.63,3854.63 U17.R10@2079.14,3854.63 ; U17.V16@2138.2,3972.74 2138.2,3960.48 2138.38,3960.3 v2(2138.38,3959.56)
  Top Layer w20: R128.2@1479.83,4917.72 v1(1521.5,4917.72)
  Layer 3 - SIG w30: v1(1521.5,4917.72) 1468.2,4917.72 1351.3,5034.62 1277.3,5034.62 1249.2,5062.72 1249.2,5171.02 1362.9,5284.72 v4(1531.3,5284.72)
  Bottom Layer w10: C173.1@1980.3,3913.32 1979.51,3913.32 1980.11,3912.71 1980.11,3895.43 v2(1980.72,3894.83) ; v2(1981.49,3835.32) 1981.87,3835.7 1982.87,3835.7 1997.6,3850.44 C171.1@1997.6,3851.22
  Bottom Layer w12: C161.1@1897.49,3780.54 C161.1@1897.49,3781.32 1899.29,3779.52 1899.29,3767.5 1910.86,3755.93 1921.88,3755.93 C165.1@1923.49,3754.32 1923.49,3738.32 v2(1921.49,3736.32) ; v2(1902.25,3854.83) 1916.51,3854.83 1936.02,3835.32 v2(1941.49,3835.32) 1941.49,3812.32 1946.44,3807.37 1946.44,3806.58 1948.71,3804.32 C162.1@1949.5,3804.32 C157.1@1949.5,3779.32 1950.43,3778.39 1950.43,3750.3 1951.51,3750.3 C158.1@1951.51,3739.32 1951.51,3701.52 1963.71,3689.32 C164.1@1964.5,3689.32 ; 1965.55,3889.32 1959.49,3889.32 1958.73,3888.55 1973.9,3888.55 1980.18,3894.83 v2(1980.72,3894.83) ; C156.1@1972.87,3569.32 C156.1@1977.87,3564.32 ; C163.1@1982,3935.52 1983.77,3933.75 2001.16,3933.75 v2(2001.55,3933.37) 2038.94,3933.37 2047.22,3933.37 ; v2(2020.49,3835.32) 2021.22,3834.58 2021.22,3817.58 C174.1@2023.49,3815.31 C160.1@2055.49,3815.31 ; C169.1@2047.49,3956.32 2047.22,3956.06 2047.22,3933.37 ; v2(2062.2,3844.2) 2063.25,3845.25 C176.1@2087.49,3845.25 ; v2(2076.34,3933.37) 2047.22,3933.37
  other v1: 1942.3,3553.82 1942.3,3584.92 1942.3,3617.62
  other v2: 1942.3,3654.12 1921.99,3953.58
  other v4: 1573.3,5284.72 1625.5,5316.12 1665.3,5316.12 1705.1,5316.12 1552.4,5316.92
VDDA_1.8_USB0: C213.1 C214.1 C215.1 FB11.2 U17.U15 | length 306.7
  Top Layer w6.8: U17.U15@2118.51,3953.06 2139.01,3932.56 2156.36,3932.56 v2@2157.5,3931.42
  Bottom Layer w10: C214.1@2161.51,3899.32 2160.72,3899.32 2160.72,3931.89 2215.11,3931.89 2224.85,3922.16 2225.64,3922.16 2228.9,3918.89 C215.1@2228.9,3918.1 2258.59,3918.1 C213.1@2265.4,3911.29 ; C213.1@2265.4,3909.54 C213.1@2265.4,3911.29 ; FB11.2@2366.93,3923.38 2366.93,3917.49 2360.73,3911.29 C213.1@2265.4,3911.29
  other v2: 2159.48,3931.89
VDDA_1.8V: C140.1 C141.1 C142.1 C143.1 FB4.2 U17.F14 U17.F18 U17.H14 | length 443.7
  Top Layer w10: v2(1882.5,4011.92) 1882.6,4012.01 1901.88,4012.01 U17.F18@1901.98,4012.11 ; U17.F14@1901.98,3933.37 1902.21,3933.14 1927.98,3933.14 v2(1928.2,3932.92) 1928.43,3933.14 1941.12,3933.14 U17.H14@1941.35,3933.37
  Bottom Layer w8: v2(1882.5,4011.92) 1883.65,4010.77 1890.05,4010.77 1907.08,3993.74 1939.7,3961.12 1939.7,3946.04 1928.2,3934.54 v2(1928.2,3932.92)
  Bottom Layer w10: FB4.2@1712.4,4118.56 1718.1,4112.86 1778.36,4112.86 1778.76,4113.26 1784.22,4113.26 1787.49,4116.53 C142.1@1787.49,4117.32 ; C142.1@1787.49,4116.32 1822.68,4116.32 1829.49,4123.13 C140.1@1829.49,4124.32 1836.3,4117.51 1836.3,4104.92 1876.74,4064.48 1876.74,4054.25 1881.74,4049.25 1881.74,4012.68 v2(1882.5,4011.92) ; C141.1@1915.49,3932.38 1916.22,3933.12 1928,3933.12 v2(1928.2,3932.92)
VDDA_3.3V: C138.1 C139.1 FB3.2 U17.K15 | length 768.5
  Top Layer w10: v2(1962.74,3952.92) 1980.58,3952.92 U17.K15@1980.72,3953.06
  Bottom Layer w10: FB3.2@1606.83,4254.67 1600.02,4261.48 FB3.2@1600.02,4265.42 1600.02,4269.35 1606.84,4276.16 1610.77,4276.16 1624.42,4289.82 1942.07,4289.82 1969.2,4262.69 1969.2,4205.18 1952.94,4188.92 1952.94,4133.05 ; 1953.3,4133.05 1953.3,4120.62 ; C139.1@1956.49,3971.63 C139.1@1960.54,3975.68 ; v2(1962.74,3952.92) 1962.35,3953.3 1962.35,4028.94 1953.3,4037.99 1953.3,4120.62 ; C138.1@1971.2,4120.62 1953.3,4120.62
VDDA_3.3V_USB0: C189.1 C190.1 C191.1 FB10.2 U17.U16 | length 367.5
  Top Layer w6.8: v2(2099.4,3954.22) 2099.7,3954.22 2118.22,3972.74 U17.U16@2118.51,3972.74
  Bottom Layer w8: v2(2099.4,3954.22) 2105.42,3954.22 2127.26,3976.06 2152.86,3976.06 2167.5,3990.69 2167.5,4029.44 C190.1@2186.72,4048.66
  Bottom Layer w10: C190.1@2186.72,4048.66 2186.72,4051.55 C190.1@2189.99,4054.82 2192.93,4051.87 2225.58,4051.87 2228.07,4054.37 2231.44,4054.37 2234.7,4057.64 C191.1@2234.7,4058.42 2264.4,4058.42 2264.5,4058.32 C189.1@2270.49,4064.32 2273.49,4067.32 FB10.2@2365.93,4067.32
VDDA_ADC: C182.1 C183.1 C184.1 C185.1 FB8.2 U17.G17 U17.H17 | length 391.2
  Top Layer w10: U17.G17@1921.66,3992.43 U17.H17@1941.35,3992.43 1941.69,3992.77 1941.69,4012.92 v2@1941.54,4013.07
  Bottom Layer w10: C184.1@1872.49,4110.32 1909.12,4110.32 1913.49,4114.69 1914.56,4113.62 1935.3,4113.62 ; C183.1@1916.7,4045.54 C183.1@1916.7,4046.32 1917.61,4045.42 1935.3,4045.42 ; C185.1@1917.48,4206.32 1918.28,4205.52 1935.3,4205.52 ; FB8.2@1934.05,4257.32 1935.3,4256.06 1935.3,4205.52 ; v2@1941.54,4013.07 1940.77,4013.84 1940.77,4017.65 1935.3,4023.13 1935.3,4045.42 ; 1935.3,4045.42 1935.3,4113.62 ; 1935.3,4113.62 1934.94,4113.99 1934.94,4205.15 1935.3,4205.52
  other v2: 1942.04,4013.57
VDDA_PLL0: C152.1 C153.1 C154.1 FB6.2 U17.N12 | length 456.1
  Top Layer w10: U17.N12@2039.77,3894 2039.85,3894.08 v2(2058.06,3894.08)
  Bottom Layer w10: C153.1@2063.5,3876.32 2062.71,3876.32 2059.44,3879.58 2059.44,3892.16 2058.06,3893.54 v2(2058.06,3894.08) 2058.45,3894.46 2065.64,3894.46 2087.99,3916.82 2119.68,3916.82 2157.08,3954.22 2214.45,3954.22 2231.74,3971.51 2234.26,3971.51 2241.07,3978.32 2239.31,3978.32 2232.5,3985.13 C154.1@2232.5,4021.32 ; C152.1@2242.49,3978.32 2246.43,3978.32 2270.17,4002.06 2315.5,4002.06 2332.26,4018.81 2348.81,4018.81 2359.56,4008.06 2366.37,4001.25 FB6.2@2366.37,3997.32
VDDA_PLL1: C179.1 C180.1 C181.1 FB7.2 U17.G9 | length 351.3
  Top Layer w12: v2@1899.49,3834.32 v2(1900.49,3834.32) 1921.03,3834.32 U17.G9@1921.66,3834.95
  Bottom Layer w10: 1836.19,3836.2 1879.02,3836.2 C181.1@1880.2,3835.02
  Bottom Layer w12: FB7.2@1643.05,3738.32 1643.05,3742.25 1651.1,3750.31 C180.1@1730.49,3750.31 1799.38,3750.31 1812.2,3763.13 1812.2,3812.22 1836.19,3836.2 ; C181.1@1880.2,3835.02 1880.9,3834.32 v2@1899.49,3834.32
VDDA_PLL2: C186.1 C187.1 C188.1 FB9.2 U17.G12 | length 292.2
  Top Layer w10: v2(1902.99,3892.82) 1903.53,3892.82 1904.37,3893.66 1921.32,3893.66 U17.G12@1921.66,3894
  Bottom Layer w5.5: 1826.94,3879.58 1845.76,3879.58 ; 1845.86,3879.48 1854.59,3888.22 ; 1854.49,3888.32 1866.61,3888.32 1876.87,3878.05 1887.24,3877.95 v2@1902.01,3892.72
  Bottom Layer w6: 1825.94,3880.58 1826.94,3879.58
  Bottom Layer w8: C188.1@1804.12,3898.09 1808.43,3898.09 1825.94,3880.58 ; v2@1901.91,3892.82 v2(1902.99,3892.82)
  Bottom Layer w10: FB9.2@1662.05,3923.32 1727.49,3923.32 C186.1@1727.49,3922.94 1727.49,3919 1744.19,3902.3 C187.1@1769.49,3902.3 C188.1@1802.49,3902.3 ; C188.1@1802.49,3900.51 C188.1@1802.49,3901.3
VDDA_TEMP: C148.1 C149.1 C150.1 C151.1 FB5.2 U17.G11 U17.M11 | length 627.9
  Top Layer w6: U17.G11@1921.66,3874.32 1941.49,3894.14 v2(1941.49,3912.32)
  Top Layer w10: v2(2018.89,3856.84) 2019.74,3857.7 2019.74,3873.97 U17.M11@2020.09,3874.32
  Layer 8 - HV PWR w10: v2(1765.7,3769.21) 1862.17,3769.21 1883.49,3790.52 1883.49,3864.83 1893.49,3874.83 1941.49,3874.83 ; v2(1941.49,3912.32) 1941.49,3874.83 ; v2(2018.89,3856.84) 2000.91,3874.83 1941.49,3874.83
  Bottom Layer w10: FB5.2@1642.49,3815.32 1671.81,3815.32 1685.49,3801.63 C148.1@1685.49,3797.69 1685.49,3796.92 1692.3,3790.11 C151.1@1731.49,3790.11 ; C151.1@1732.49,3785.32 1765.7,3785.32 1766.2,3784.82 1766.2,3769.71 v2(1765.7,3769.21) ; v2(2018.89,3856.84) 2018.89,3859.72 2034.49,3875.32 C149.1@2035.49,3874.32
VDDSHV_1.8V: C144.1 C145.1 C146.1 C147.1 R143.2 U17.C13 U17.D13 U17.E14 | length 335.2
  Top Layer w10: U17.C13@1842.92,3913.69 U17.D13@1862.61,3913.69 1862.8,3913.88 1862.8,3932.13 v2(1862.99,3932.32) 1863.53,3932.32 1864.24,3933.03 1881.95,3933.03 U17.E14@1882.29,3933.37
  Bottom Layer w10: R143.2@1655.49,3983.32 1691.49,3983.32 1727.49,3983.32 C144.1@1728.49,3984.32 1728.49,3980.38 1735.3,3973.57 1757.35,3973.57 1769.9,3961.02 1789.41,3961.02 1792.66,3957.77 C146.1@1817.35,3957.77 ; 1685.99,3988.82 C145.1@1685.99,4011.32 ; C146.1@1817.7,3961.2 1817.97,3961.47 1825.84,3961.47 1832.51,3968.14 1854.39,3968.14 1862.22,3960.3 1862.22,3933.08 v2(1862.99,3932.32)
VDDSHV_3.3V: C192.1 C193.1 C194.1 C195.1 C196.1 C197.1 C198.1 C199.1 C200.1 C201.1 C202.1 C203.1 C204.1 C205.1 C206.1 C207.1 C208.1 C209.1 C210.1 C211.1 C212.1 R144.2 U17.E7 U17.E8 U17.E9 U17.E15 U17.L6 U17.M6 U17.N16 U17.N17 U17.P5 U17.P6 U17.R17 U17.T8 U17.T11 U17.T17 U17.U7 U17.U8 U17.U11 | length 1194.7
  Top Layer w6: U17.P5@2059.46,3754.63 U17.P5@2059.46,3756.21 ; U17.P6@2059.46,3775.89 v2(2077.69,3794.12) 2093.74,3794.12 2097.14,3797.52 v2(2099.3,3797.52)
  Top Layer w10: v2(1862.35,3794.42) 1880.65,3794.42 1881.8,3795.58 U17.E7@1882.29,3795.58 U17.E8@1882.29,3815.26 U17.E9@1882.29,3834.95 ; U17.E15@1882.29,3953.06 U17.E15@1882.78,3953.54 ; v2(2000.49,3796.32) 2000.45,3796.27 U17.L6@2000.4,3775.89 U17.L6@2000.4,3775.89 U17.M6@2020.09,3775.89 ; v2(2020.16,3993.82) 2020.54,3993.43 2038.28,3993.43 2039.28,3992.43 U17.N17@2039.77,3992.43 U17.N16@2039.77,3972.74 ; U17.P5@2059.46,3756.21 U17.P6@2059.46,3775.89 ; U17.R17@2079.14,3992.43 U17.T17@2098.83,3992.43 2098.83,3975.94 2097.3,3974.41 v2@2097.3,3973.32 ; U17.T11@2098.83,3874.32 U17.U11@2118.51,3874.32 2118.61,3874.22 2137.6,3874.22 v2(2137.7,3874.12) ; U17.U7@2118.51,3795.58 2118.17,3795.92 2101.98,3795.92 2100.39,3797.52 v2(2099.3,3797.52) 2099.17,3797.65 2099.17,3814.92 U17.T8@2098.83,3815.26 U17.U8@2118.51,3815.26 ; U17.U8@2119,3815.26 2141.17,3815.26 2144.57,3818.67 v2(2145.65,3818.67)
  Top Layer w12: U17.E15@1882.29,3953.06 1899.4,3953.06 v2(1899.88,3953.54)
  Layer 9 - LV PWR w10: v2(2000.49,3796.32) 2001.26,3795.55 2001.26,3774.47
  Bottom Layer w10: C198.1@1755.47,3682.32 1755.47,3702.4 1781.49,3728.42 1813.89,3728.42 1825.49,3740.02 1825.49,3751.54 1829.25,3755.31 1857.49,3755.31 1857.49,3779.36 1861.97,3783.84 1861.97,3794.04 v2(1862.35,3794.42) ; v2(1772.88,4016.19) 1773.64,4016.95 1775.81,4016.95 1790.69,4031.84 C204.1@1790.69,4032.62 1790.69,4036.62 1790.89,4036.82 1814.1,4036.82 1814.3,4037.02 1817.57,4033.76 1817.57,4011.22 1844.48,3984.32 1863.35,3984.32 1893.99,3953.67 1902.25,3953.67 v2@1902.38,3953.54 ; v2(2000.49,3796.32) 2000.49,3795.78 2001.49,3794.78 C197.1@2001.49,3751.31 ; C208.1@2081.32,4054.82 C210.1@2105.22,4054.82 ; v2@2097.3,3973.32 v2(2097.3,3975.32) 2097.3,4027.53 2105.3,4035.54 2105.3,4045.02 2105.22,4045.1 C210.1@2105.22,4051.55 ; v2(2099.3,3797.52) 2100.07,3796.75 2114.05,3796.75 2116.43,3794.36 2117.22,3794.36 2120.49,3791.1 C196.1@2120.49,3790.31 ; C210.1@2108.49,4054.82 C212.1@2135.66,4054.82 C205.1@2162.82,4054.82 ; v2(2137.7,3874.12) 2158.69,3874.12 2161.49,3871.32 C203.1@2161.49,3849.32 C202.1@2161.5,3814.32 ; v2(2145.65,3818.67) 2147.44,3816.88 2157.44,3816.88 2160,3814.32 C202.1@2161.5,3814.32 ; C207.1@2161.49,3744.32 C206.1@2161.49,3779.32 C202.1@2161.5,3814.32
  other v1: 2151.49,3541.32 2196.49,3541.32 1765.6,3549.42
  other v12: 1750.53,3480.61
VDDSHV_SDIO: C136.2 C177.1 C178.1 U17.J17 U17.L16 U17.L17 | length 230.3
  Top Layer w10: U17.J17@1961.03,3992.43 1961.21,3992.6 v2@1979.71,3992.6 ; v2@1979.53,3992.77 v2@1979.71,3992.6 ; v2(1979.99,3992.77) v2@1979.82,3992.6 ; U17.L16@2000.4,3972.74 U17.L17@2000.4,3992.43 2000.23,3992.6 v2@1979.82,3992.6 ; v2@1979.71,3992.6 v2@1979.82,3992.6
  Bottom Layer w10: v2(1979.99,3992.77) 1999.53,4012.31 1999.53,4045.04 2008,4053.51 C178.1@2008,4065.02 2008,4089.63 2008,4133.21 C136.2@2021.1,4146.32
VLDOIN1: R37.2 U5.22 | length 197.1
  Top Layer w8: 3063,6419.59 3063,6426.58 3072.74,6436.32 3178.75,6436.32 3225.71,6483.28 R37.2@3225.71,6487.22
VLDOIN2: C72.1 R47.2 U7.22 | length 243.7
  Top Layer w8: U7.22@3716.74,6406.64 3716.74,6428.57 3724.49,6436.32 3764.95,6436.32 3778.24,6449.61 3805.76,6477.14 3827.79,6477.14 3842.49,6491.84 R47.2@3842.49,6492.82 3842.49,6493.8 3861.36,6512.68 C72.1@3902.49,6512.68
VLDOIN3: C94.1 R64.2 U10.22 | length 270.1
  Top Layer w8: U10.22@3384.97,5144.83 3385.61,5144.19 3403.33,5144.19 3437.49,5110.03 3437.49,5052.88 3480.74,5009.63 3480.74,5005.69 3488.55,4997.88 C94.1@3492.49,4997.88 3492.49,4935.01 R64.2@3494.62,4932.88
VMUX1_+3.3V: C383.1 C384.1 C385.1 C386.1 R294.2 R296.2 U29.A2 U29.B2 | length 102.4
  Top Layer w9: R294.2@1083.99,1508.2 1083.99,1507.21 1129.29,1461.91 1129.29,1460.1 1149.79,1439.6 C383.1@1156.29,1439.6
VMUX1_+5V: C379.1 C380.1 C381.1 C382.1 R295.2 U29.A10 U29.B10
VMUX2_+3.3V: C311.1 C312.1 C313.1 C314.1 R163.2 R165.2 U28.A2 U28.B2 | length 76
  Top Layer w9: R163.2@1903.09,1444.51 1973.99,1444.51 C311.1@1976.89,1441.6 ; R163.2@1903.09,1446.03 R163.2@1903.09,1447.01
VMUX2_+5V: C307.1 C308.1 C309.1 C310.1 R164.2 U28.A10 U28.B10
VMUX3_+3.3V: C303.1 C304.1 C305.1 C306.1 R160.2 R162.2 U27.A2 U27.B2 | length 105.3
  Top Layer w9: R160.2@2840.09,1511.39 2840.09,1510.41 2886.3,1464.2 2896.29,1464.2 C303.1@2916.79,1443.7
VMUX3_+5V: C299.1 C300.1 C301.1 C302.1 R161.2 U27.A10 U27.B10 | length 127.9
  Top Layer w5: U27.B10@3195.44,1324.88 U27.A10@3195.44,1350.47
  Top Layer w6.8: U27.A10@3195.44,1350.47 3195.44,1364.16 3228.61,1397.32 3228.61,1416.8 3243.79,1431.99 C301.1@3243.79,1432.78
VMUX4_+3.3V: C391.1 C392.1 C393.1 C394.1 R297.2 R299.2 U30.A2 U30.B2 | length 103
  Top Layer w6: R297.2@3617.29,1512.9 3617.29,1511.91 3661.09,1468.11 3661.09,1465.7 3683.09,1443.7 C391.1@3689.59,1443.7
VMUX4_+5V: C387.1 C388.1 C389.1 C390.1 R298.2 U30.A10 U30.B10
VSYS_1.8V: C90.1 C91.1 C122.1 C128.1 C464.1 FB4.1 FB5.1 FB6.1 FB7.1 FB8.1 FB9.1 FB11.1 FB14.1 FB17.1 R62.2 R63.2 R126.2 R129.2 R143.1 R513.1 R514.1 TP10.1 U9.8 U9.9 U9.10 U19.5 U35.3 U35.6 Y2.1 Y2.4 | length 4899.9
  Top Layer w10: U19.5@984.64,4979.46 U19.5@984.9,4979.72 987.77,4976.84 1010.06,4976.84 1022.1,4964.8 C122.1@1022.1,4919.01 1042.9,4919.01 v9(1058.19,4903.72) ; C128.1@1668,4206.32 1686.86,4206.32 1687.66,4205.52 v9(1688.2,4205.52) 1688.59,4205.9 1693.67,4205.9 1714.62,4226.84 Y2.4@1716.59,4226.84
  Top Layer w15: R126.2@1507.83,5140.22 R126.2@1508.83,5139.22 ; C91.1@2283.79,5130.3 2283.79,5131.29 2338.49,5185.99 2338.49,5235.32 v4(2362.49,5259.32) ; R63.2@2608.99,5509.32 2652.49,5509.32 2697.49,5464.32 2697.49,5374.04 2652.77,5329.32 R62.2@2651.78,5329.32 2652.14,5328.96 2652.14,5284.67 v4(2652.49,5284.32)
  Top Layer w30: v9(1058.19,4903.72) 1065.51,4911.03 R129.2@1149.19,4911.03 ; R126.2@1507.83,5137.78 1508.58,5137.03 1511.02,5137.03 1511.83,5136.22 v1(1575.19,5136.22) ; R514.1@1561.88,3466.27 1562.57,3466.97 1605.65,3466.97 v1(1610.72,3461.9) ; v1(1594.8,3526.52) 1594.8,3548.4 1657.49,3611.09 1672.2,3625.8 1699.46,3625.8 1718.22,3607.05 1723.45,3607.05 R513.1@1724.15,3607.74 ; Y2.1@1716.59,4167.79 Y2.4@1716.59,4226.84 ; 2250.49,5244.32 2250.49,5334.32 TP10.1@2252.49,5334.32 TP10.1@2253.19,5334.32
  Layer 3 - SIG w30: v9(1058.19,4903.72) 994.4,4903.72 958.6,4867.92 958.6,4654.42 1050.3,4562.72 v1(1217.9,4562.72) 1395.1,4562.72 1459.2,4626.82 1459.2,4720.52 1637.2,4898.52 1637.2,5136.22 ; v1(1575.19,5136.22) 1637.2,5136.22 ; v4(2222.49,5254.32) 2165.6,5254.32 2047.5,5136.22 1637.2,5136.22
  Layer 8 - HV PWR w15: v4(2362.49,5259.32) 2387.49,5284.32 v4(2652.49,5284.32)
  Bottom Layer w10: C464.1@1279.49,4517.3 1279.49,4518.09 1282.76,4521.36 1283.55,4521.36 1286.66,4524.47 U35.6@1324.5,4524.47 U35.3@1450.48,4524.47
  Bottom Layer w20: v1(1217.9,4562.72) 1217.9,4537.82 1239,4516.72 1278.91,4516.72 C464.1@1279.49,4517.3
  Bottom Layer w30: FB7.1@1594.59,3747.1 FB5.1@1594.59,3809.02 ; FB7.1@1594.93,3738.32 1594.8,3738.19 v1(1594.8,3526.52) 1594.8,3477.82 v1(1633.5,3439.12) ; FB9.1@1606.93,3923.32 1606.93,3934.22 R143.1@1606.93,3982 ; R143.1@1608.25,3983.32 1608.25,4053.66 1674.6,4120.02 1674.6,4173.82 ; FB4.1@1712.4,4173.68 1712.26,4173.82 1674.6,4173.82 ; FB8.1@1878.93,4257.32 1740,4257.32 v9(1688.2,4205.52) 1674.6,4191.92 1674.6,4173.82
  other v1: 3110.4,2494.69 3135.38,2494.93 2035.21,2520.82 2057.35,2520.93 1607,3934.22 2446.1,3936.42 2445,3973.32
  other v4: 2222.49,5144.32 2222.49,5204.32 2277.49,5204.32 2277.49,5254.32
VSYS_3.3V: C3.1 C4.1 C12.1 C13.1 C84.1 C86.1 C87.1 C114.1 C216.1 C218.1 C220.1 C459.1 C460.1 C461.1 C462.1 C463.1 C465.1 FB3.1 FB10.1 J6.5 L14.1 R1.2 R2.2 R6.2 R7.2 R61.2 R64.1 R69.2 R71.2 R73.2 R89.2 R90.2 R91.2 R92.2 R93.2 R94.2 R95.2 R96.2 R97.2 R98.2 R99.2 R100.2 R101.2 R102.2 R103.2 R104.2 R121.2 R122.2 R127.2 R130.2 R131.2 R136.1 R138.1 R144.1 R152.1 R153.1 R162.1 R165.1 R296.1 R299.1 R438.1 R439.1 R445.2 R446.2 R512.2 TP9.1 U1.6 U2.6 U10.7 U10.8 U10.9 U10.10 U10.12 U10.13 U10.14 U10.15 U10.30 U15.1 U15.3 U20.1 U21.1 U22.3 U22.6 U31.16 U33.2 U34.5 U35.7 U36.14 | length 7459.3
  Top Layer w6.8: U22.3@771.75,3180.82 772.48,3180.1 772.48,3166.03 785.93,3152.57 v1(805.15,3152.57) ; U22.6@771.75,3306.81 771.43,3307.13 771.43,3342 C220.1@771.1,3342.32 791.37,3342.32 795.98,3337.71 812.21,3337.71 v1(813.36,3336.56) v1@811.73,3336.56 ; U21.1@781.72,3393.79 808.71,3393.79 815.4,3387.1 815.4,3386.31 834.01,3386.31 v1(834.2,3386.12) ; U36.14@1339.79,4271.86 U36.14@1339.85,4271.8
  Top Layer w15: U15.1@854.75,3740.75 855.27,3740.23 932.59,3740.23 C114.1@936.51,3736.32 ; U15.3@854.75,3791.93 855.23,3792.42 921.7,3792.42 936.51,3777.61 C114.1@936.51,3736.32 ; U20.1@858,3497.04 858.09,3497.12 907.12,3497.12 C216.1@907.2,3497.21 907,3497.41 v1(907,3516.92) ; v1(937.9,3708.12) 937.9,3734.92 C114.1@936.51,3736.32 ; 1356.99,4275.8 1356.99,4295.71 ; 1356.99,4296.41 1356.99,4331.51 C465.1@1357.7,4332.22 v1(1395.89,4332.22) ; R71.2@2638.99,4969.32 2641.53,4971.86 2641.53,5013.36 v4(2642.49,5014.32) ; R69.2@2818.99,5289.32 2818.99,5223.32 2850.79,5191.52 ; 2829.49,5070.12 2829.49,4922.32 2897.49,4854.32 2987.49,4854.32 ; R73.2@2995.99,4784.32 R73.2@2995.99,4790.11 2995.99,4845.81 2987.49,4854.32 ; 3028.39,5246.32 3032.49,5250.42 TP9.1@3032.49,5389.32 ; C84.1@3539.73,5112.88 3601.05,5112.88 3602.49,5114.32 ; R64.1@3557.61,4932.88 3601.05,4932.88 3602.49,4934.32 ; R61.2@3557.61,5237.88 3568.81,5226.68 3580.13,5226.68 3602.49,5204.32 3602.49,5114.32 ; 2987.49,4854.32 2986.99,4854.82 3590.49,4854.82 3602.49,4866.82 3602.49,4934.32 ; 3602.49,4934.32 3602.49,5114.32
  Top Layer w20: v1(937,4325.52) R136.1@937,4363.72 ; R131.2@986.38,4863.72 v9(1008.19,4863.72) ; v1(1106.9,3471.92) R138.1@1268.91,3471.92 ; v1(1140.3,1637.52) 1253.12,1524.69 R296.1@1346.49,1524.69 ; R130.2@1157.39,5014.22 v1(1157.39,5046.73) ; R127.2@1507.83,5034.22 1509.64,5032.41 v1(1551.32,5032.41) ; U34.5@1918.62,4406.22 1925.18,4406.22 1926.99,4408.03 1926.99,4448.38 1915.27,4460.1 1895.83,4460.1 1893.03,4462.89 R446.2@1893.03,4467.82 1894.49,4469.27 1894.49,4573.82 ; R445.2@2055.45,4935.02 2058.24,4937.81 2058.24,4972.96 2058.6,4973.32 ; C460.1@2111.1,4575.42 2111.1,4579.35 2101.64,4588.82 U33.2@2009.59,4588.82 1909.49,4588.82 1894.49,4573.82 ; R165.1@2145.69,1501.18 2146.89,1502.37 v1(2146.89,1529.04) ; v1(2628,3706.32) 2644.31,3690.01 2703.3,3690.01 R121.2@2707.79,3685.52 ; v1(2631.1,3467.82) 2667.11,3467.82 2706.81,3507.52 R122.2@2707.79,3507.52 ; L14.1@2799.06,5084.32 2799.06,4722.73 2750.75,4674.42 2271.39,4674.42 2209.49,4736.32 2209.49,4860.32 2096.49,4973.32 2058.6,4973.32 ; v1(3037,1541) 3039.79,1541 R162.1@3075.39,1505.39 3077.11,1503.67 R162.1@3077.11,1502.69 ; v1@3822.39,1505.9 R299.1@3872.19,1505.9 ; 1894.49,4573.82 1894.49,4926.32 1941.49,4973.32 2058.6,4973.32
  Layer 8 - HV PWR w15: v4(2642.49,5014.32) 2772.49,5144.32 v4(2812.49,5144.32)
  Bottom Layer w8: R439.1@1236.96,2280.74 v1(1272.05,2280.74) ; C459.1@1290.54,2511.34 v1(1290.54,2546.43) 1638.45,2546.43 R438.1@1642.25,2542.63 ; C459.1@1291.24,2510.63 1292.25,2509.63 1292.25,2483.1 1296.73,2478.61 U31.16@1307.95,2478.61
  Bottom Layer w10: U35.7@1324.5,4544.16 1298.36,4544.16 1281.5,4561.02 1281.5,4571.42 1304.9,4594.82 C463.1@1335.1,4594.82 1335.76,4594.16 v1(1363.36,4594.16)
  Bottom Layer w13: U1.6@3524.29,4768.32 3570.72,4768.32 3579.5,4777.1 ; U2.6@3526.64,4609.97 3567.67,4609.97 C3.1@3588.01,4630.32
  Bottom Layer w15: FB3.1@1544.9,4265.42 FB3.1@1545.4,4265.92 ; FB10.1@2421.05,4067.32 2567.4,4067.32 2577,4057.72 v1(2577,4048.72) ; v1(3261.49,4767.32) 3293.8,4767.32 R2.2@3293.99,4767.52 ; v1(3261.69,4512.32) R6.2@3293.99,4512.32 ; v1(3261.69,4576.12) R7.2@3293.99,4576.12 ; v1(3271.15,4680.87) R1.2@3293.99,4703.72 ; v1(3456.49,4815) C13.1@3456.49,4858.82 C12.1@3521.49,4858.82 ; R512.2@3507.7,4516.32 3508.1,4515.92 3539.9,4515.92 3553.49,4502.33 v1(3553.49,4488.82) ; v1(3521.49,4815) C12.1@3521.49,4858.82 ; v1(3544.6,4692.32) C4.1@3587.99,4692.32 3588.49,4691.82 C3.1@3588.49,4630.82 ; 3579.5,4777.1 3579.5,4835.3 3555.99,4858.82 C12.1@3521.49,4858.82 ; C3.1@3588.01,4630.32 C3.1@3588.99,4630.32
  Bottom Layer w20: v1(1510.3,4265.42) FB3.1@1544.9,4265.42 ; R152.1@2337.85,2417.23 2377.95,2417.23 v1(2403.15,2442.43)
  other v1: 3824.79,1505.2 2338.75,2696.13 2362.85,2696.13 3550.5,3520.82 2445,3567.82 2470.7,3586.62 3553.4,3599.12 2445,3600.52 3553.4,3658.82 3555.2,3713.22 3555.2,3772.92 3555.9,3836.02 3555.9,3895.72 3556.8,3990.62 3556.8,4050.32 3555.8,4129.52 3555.8,4189.22 3554.49,4241.83 3554.4,4301.62 3554.8,4364.22 3554.8,4423.92
  other v6: 2982.49,5144.32 3057.49,5144.32 2982.49,5204.32 3057.49,5209.32 2982.49,5273.32 3057.49,5273.32
  other v7: 3196.98,5184.2
VSYS_5V: C62.1 C63.1 C121.1 FB12.1 FB15.1 R45.2 R48.2 R54.2 R125.1 R141.2 R161.1 R164.1 R295.1 R298.1 R457.2 TP5.1 U18.14 U32.8 U32.9 U32.10 | length 8022.6
  Top Layer w8: 2702.49,5719.32 2702.49,5889.32 2717.49,5904.32 2930.44,5904.32 2963.38,5871.38 2964.36,5871.38 2979.06,5856.68 R45.2@2979.06,5855.69
  Top Layer w10: C121.1@1278.23,5064.73 1278.23,5018.84 U18.14@1278.51,5018.57
  Top Layer w20: C121.1@1276.19,5064.73 1278.23,5064.73 1288.74,5064.73 1299.7,5075.69 v1(1299.7,5095.72) ; v1(2184.29,1486.7) 2184.29,1489.58 2186.32,1491.61 2211.99,1491.61 2220.69,1500.31 R164.1@2220.69,1501.3
  Top Layer w30: R125.1@1075.19,4698.22 1076.2,4697.21 v1(1076.2,4652.62) ; v1(1189.9,4410.12) 1194.63,4405.39 1238.26,4405.39 R141.2@1239,4404.64 ; R457.2@1526.69,4977.42 1527.39,4976.72 v1(1586.19,4976.72) ; TP5.1@2632.49,5824.32 2632.49,5660.23 2671.3,5621.42 ; v1(3046,1574) 3076.29,1574 3116.09,1534.19 3116.09,1531.48 3140.69,1506.88 R161.1@3140.69,1505.9 3142.41,1504.18 R161.1@3142.41,1503.19
  Layer 3 - SIG w30: v1(1076.2,4652.62) 1320.04,4652.62 1586.19,4918.76 v1(1586.19,4976.72) 1586.19,5054.53 1524.2,5116.52 1524.2,5196.12 ; v1(1299.7,5095.72) 1400.1,5196.12 1524.2,5196.12 ; v4(2677.49,5660.12) 2618.79,5718.82 2305.9,5718.82 2010,5422.92 2010,5315.32 1890.8,5196.12 1524.2,5196.12
  Layer 8 - HV PWR w20: v1(1408.82,1543) 1622.35,1543 1678.65,1486.7 v1(2184.29,1486.7) 2306.88,1486.7 2394.18,1574 v1(3046,1574) 3075.26,1574 3183.26,1466 3994,1466 4021.87,1493.87 v1(4021.87,1556.9)
  Layer 9 - LV PWR w20: 2509.45,2403.63 2621.25,2291.83 2621.25,1886.63 2677.55,1830.33 2677.55,1728.13 2831.68,1574 v1(3046,1574)
  Bottom Layer w30: v1(1076.2,4652.62) 1076.2,4523.82 v1(1189.9,4410.12)
  other v1: 3004.85,2429.23 3028.15,2429.23 1935.35,2507.73 1958.95,2507.73
  other v4: 2721.95,5660.12 2766.4,5660.12 2720.9,5713.52
XDS110_DEBUG_ID4: R82.1 U12.63 | length 125.3
  Top Layer w6.8: U12.63@1158.05,5939.16 1216.85,5939.16 1239.4,5961.72 R82.1@1274,5961.72
XDS110_DEBUG_ID5: R83.1 U12.62 | length 127
  Top Layer w6.8: U12.62@1158.05,5923.41 1219.91,5923.41 1246.6,5896.72 R83.1@1274,5896.72
XDS110_DEBUG_ID6: R84.1 U12.61 | length 148.1
  Top Layer w6.8: U12.61@1158.05,5907.67 1198.28,5907.67 1240.94,5865.01 1240.94,5864.78 1258.31,5847.4 1258.31,5846.42 1273.01,5831.72 R84.1@1274,5831.72
XDS110_DEBUG_ID7: R85.1 U12.60 | length 194.2
  Top Layer w6.8: U12.60@1158.05,5891.92 U12.60@1158.05,5891.92 1192.88,5891.86 1225.94,5858.8 1225.94,5813.79 1273.01,5766.72 R85.1@1274,5766.72
XDS110_PROG_STAE1: R79.2 U12.4 | length 508
  Top Layer w6.8: R79.2@393.69,5081.52 394.67,5081.52 409.37,5096.22 409.37,5112.39 430.2,5133.22 430.2,5162.14 459.2,5191.14 459.2,5289.72 504.3,5334.82 626.88,5334.82 658.05,5365.99 U12.4@658.05,5407.67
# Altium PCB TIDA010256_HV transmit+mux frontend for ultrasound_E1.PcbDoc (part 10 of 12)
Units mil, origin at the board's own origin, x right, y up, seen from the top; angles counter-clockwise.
Board outline 6192.49 x 6712.23 mil, 16 copper layers (Top Layer, Layer 2 - GND, Layer 3 - SIG, Layer 4 - GND, Layer 5 - SIG, Layer 6 - SIG, Layer 7 - GND, Layer 8 - HV PWR, Layer 9 - LV PWR, Layer 10 - GND, Layer 11 - SIG, Layer 12 - SIG, Layer 13 - GND, Layer 14 - SIG, Layer 15 - GND, Bottom Layer), stack 95.905 mil thick; 806 components, 539 nets, 3343 pads, 1848 vias.

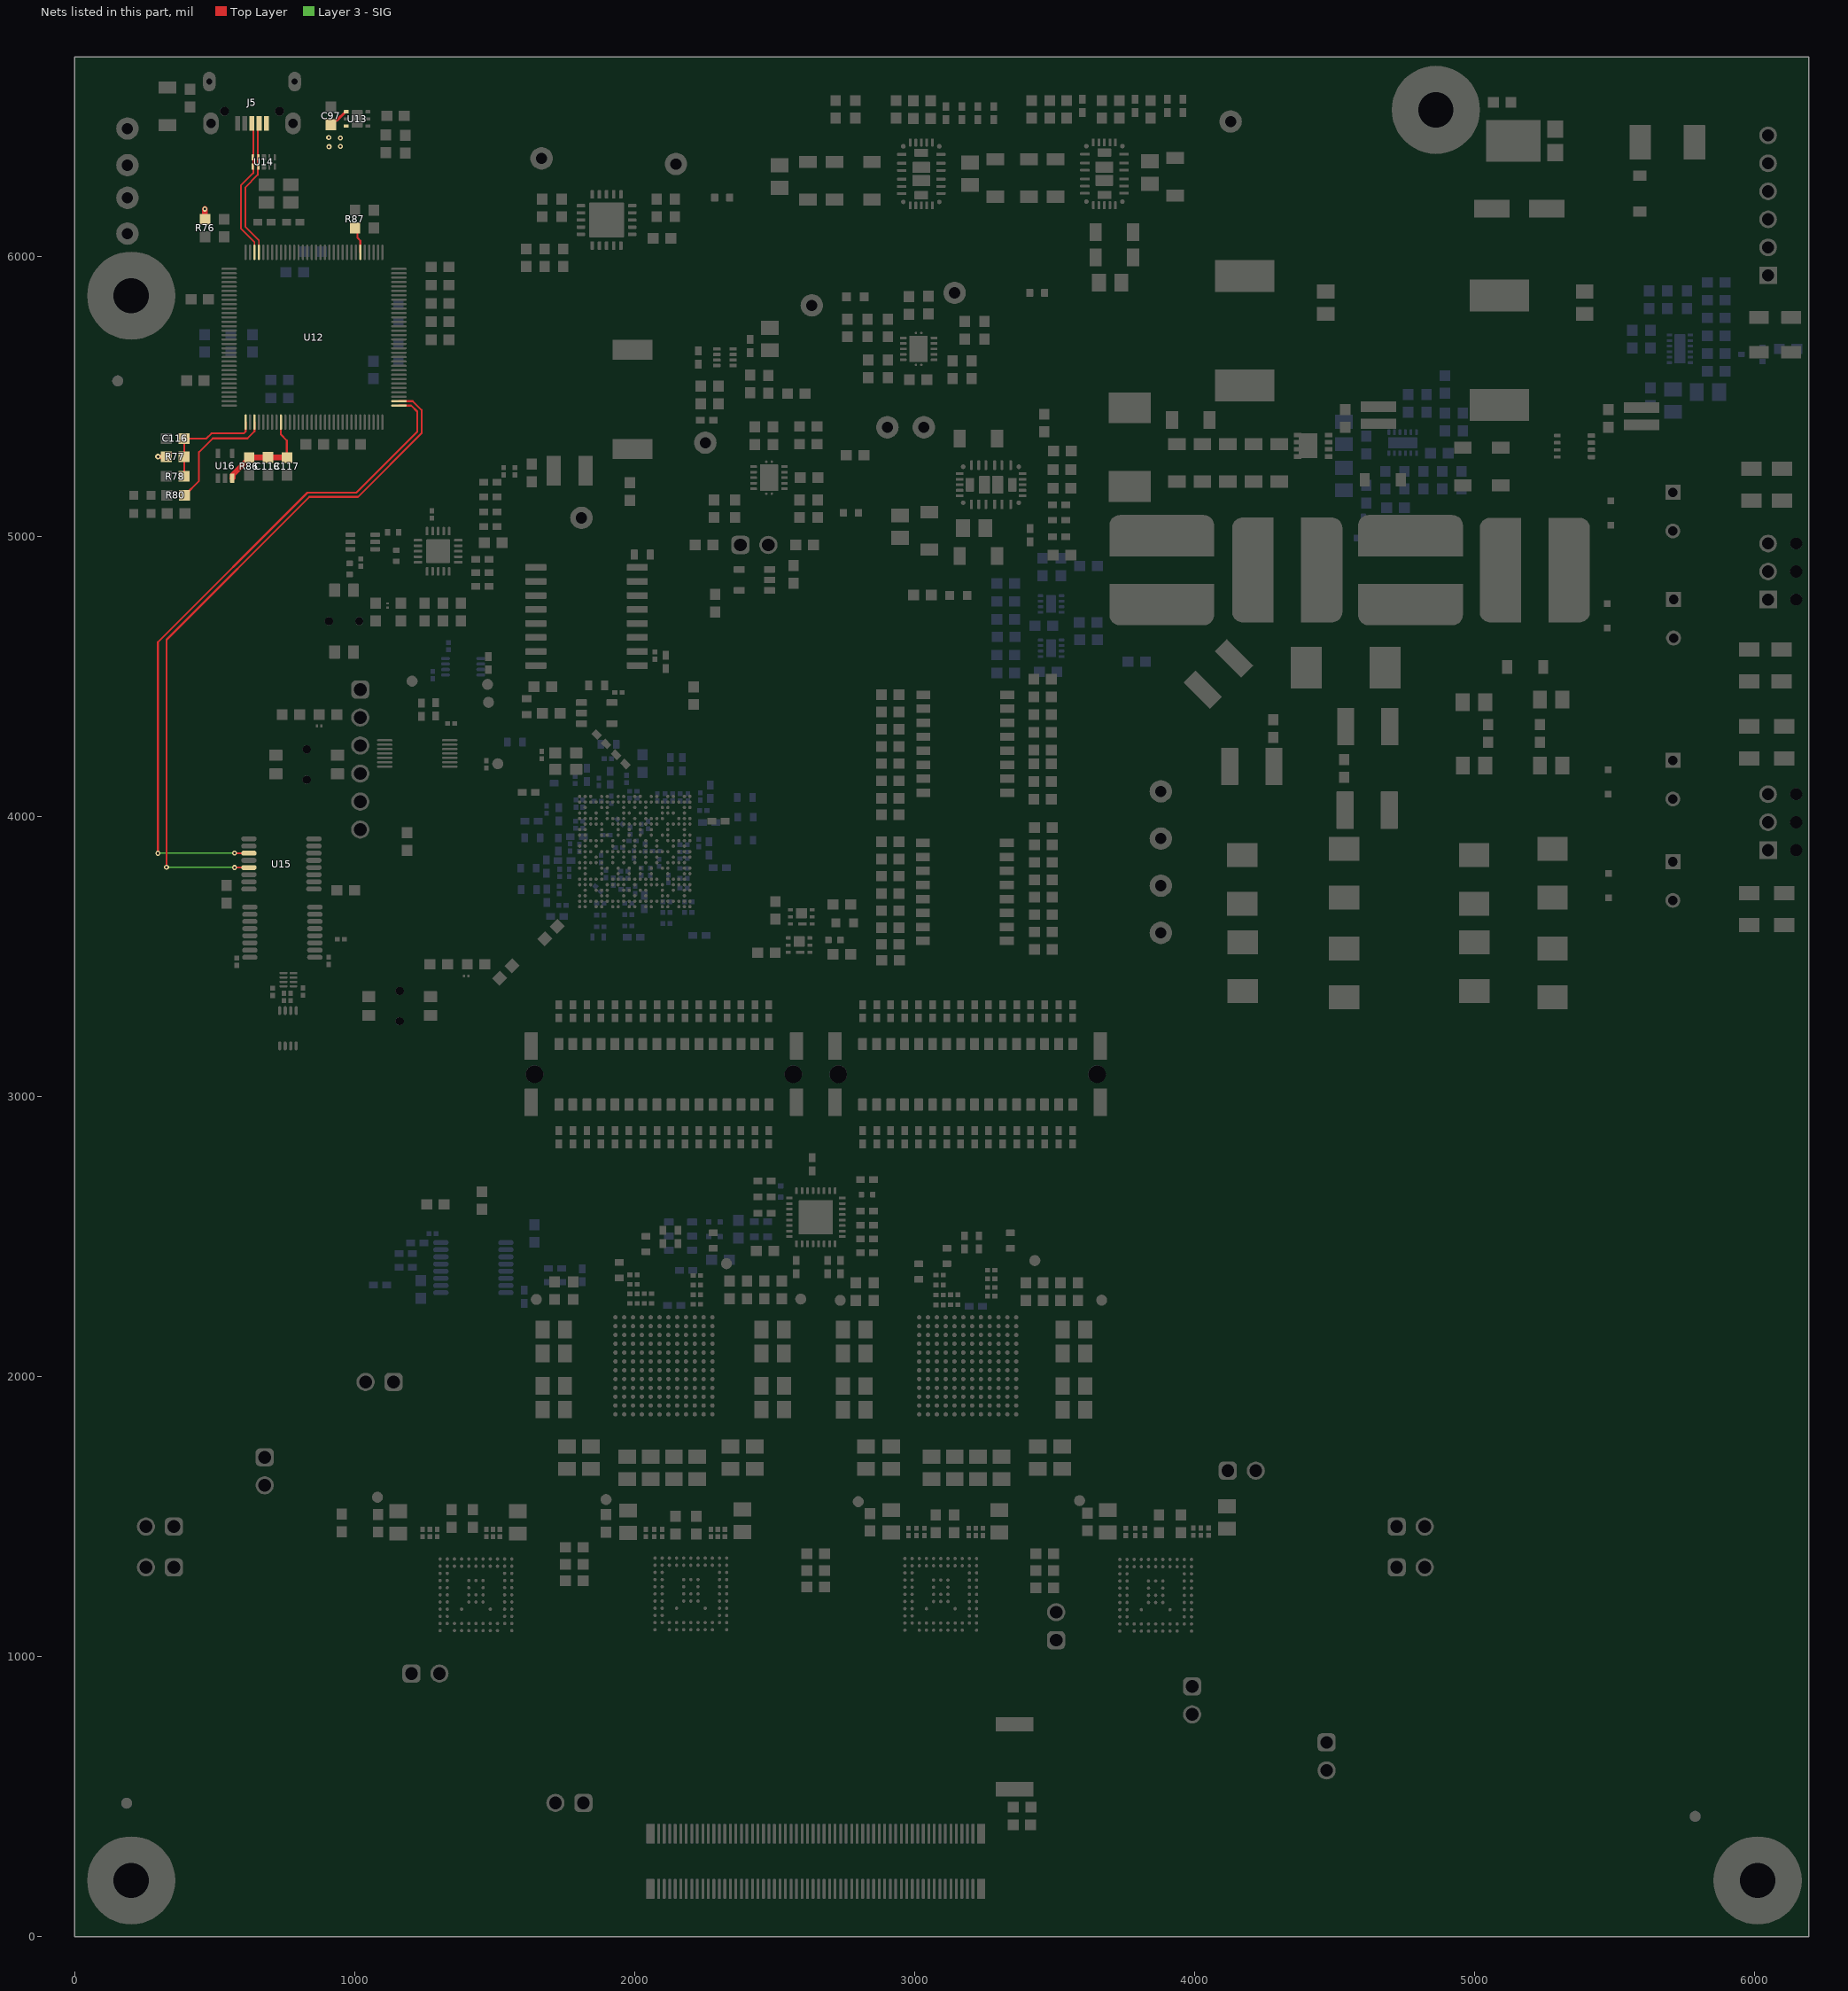
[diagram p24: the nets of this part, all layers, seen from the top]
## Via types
v1: diameter 18, hole 8, Top Layer to Bottom Layer, tented both sides, 930 vias
v2: diameter 16, hole 8, Top Layer to Bottom Layer, tented both sides, 340 vias
v3: diameter 16, hole 8, Top Layer to Bottom Layer, tented bottom, 226 vias
v4: diameter 20, hole 10, Top Layer to Bottom Layer, tented both sides, 129 vias
v5: diameter 50, hole 30, Top Layer to Bottom Layer, tented both sides, 96 vias
v6: diameter 30, hole 15, Top Layer to Bottom Layer, tented both sides, 47 vias
v7: diameter 19.68, hole 7.87, Top Layer to Bottom Layer, 40 vias
v8: diameter 19.68, hole 7.87, Top Layer to Bottom Layer, tented both sides, 19 vias
v9: diameter 18, hole 8, Top Layer to Bottom Layer, tented bottom, 13 vias
v10: diameter 40, hole 20, Top Layer to Bottom Layer, tented both sides, 4 vias
v11: diameter 40, hole 20, Top Layer to Bottom Layer, 3 vias
v12: diameter 18, hole 8, Top Layer to Bottom Layer, 1 vias

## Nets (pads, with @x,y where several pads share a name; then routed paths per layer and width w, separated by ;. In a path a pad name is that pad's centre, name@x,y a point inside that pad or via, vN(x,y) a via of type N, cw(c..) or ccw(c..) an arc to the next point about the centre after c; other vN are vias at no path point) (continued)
XDS110_PROG_STAE2: R80.2 U12.3 | length 437.5
  Top Layer w6.8: R80.2@392.49,5146.62 393.47,5146.62 444.2,5197.35 444.2,5300.72 493.3,5349.82 616.9,5349.82 642.24,5375.16 642.24,5407.6 U12.3@642.31,5407.67
XDS110_UART1_RXD: U12.33 U15.11 | length 2462
  Top Layer w6.8: v1(297.6,3868.42) 297.6,4622.02 831.5,5155.92 1006,5155.92 1223.6,5373.52 1223.6,5445.12 1202,5466.72 U12.33@1158.05,5466.72 ; v1(571.02,3868.7) U15.11@622.46,3868.7
  Layer 3 - SIG w5: v1(297.6,3868.42) 297.75,3868.56 570.88,3868.56 v1(571.02,3868.7)
XDS110_UART1_TXD: U12.34 U15.13 | length 2500.3
  Top Layer w6.8: v1(328.2,3818.32) 328.2,4630.7 838.42,5140.92 1012.21,5140.92 1239,5367.71 1239,5450.93 1207.46,5482.47 U12.34@1158.05,5482.47 ; v1(571.02,3817.52) U15.13@622.46,3817.52
  Layer 3 - SIG w5: v1(328.2,3818.32) 328.6,3817.92 570.62,3817.92 v1(571.02,3817.52)
XDS110_VBUS_DET: C116.2 R77.1 R78.2 U12.1 | length 398.3
  Top Layer w6.8: R78.2@391.29,5214.32 R77.1@391.29,5284.32 C116.2@391.29,5349.32 470.7,5349.32 488.9,5367.52 604.1,5367.52 610.81,5374.22 U12.1@610.81,5407.67
XDS_RESET: R87.1 U12.70 | length 95.2
  Top Layer w6.8: R87.1@1001.2,6101.32 1010.5,6092.02 1010.5,6065.22 1020.26,6055.46 U12.70@1020.26,6013.97
XDS_USB_D_N: J5.2 U12.93 U14.2 U14.9 | length 501.6
  Top Layer w6.1: U14.2@654.19,6321.15 654.19,6350.87 U14.9@656.03,6352.72 654.26,6354.49 654.26,6469.21 J5.2@659.05,6474.01 ; U14.2@656.03,6319.84 654.19,6318 654.19,6290.1 609.6,6245.51 609.6,6105.52 658.31,6056.81 U12.93@658.31,6013.97
XDS_USB_D_P: J5.3 U12.94 U14.1 U14.10 | length 501.7
  Top Layer w6.1: J5.3@633.46,6474.01 638.26,6469.21 638.26,6354.63 U14.10@636.35,6352.72 638.19,6350.87 U14.1@638.19,6321.15 ; U14.1@636.35,6319.84 638.19,6318 638.19,6296.73 593.6,6252.14 593.6,6098.89 642.31,6050.18 U12.94@642.31,6013.97
XDS_USB_VBUS: C97.1 J5.1 R76.2 R77.2 U13.4 U13.6 | length 145.1
  Top Layer w6: U13.6@967.37,6464.73 U13.6@970.32,6464.73
  Top Layer w10: C97.1@915.5,6470.12 915.5,6471.1 929.2,6484.8 936.26,6484.8 967.37,6515.91 U13.4@970.32,6515.91
  Top Layer w15: v4(297.96,5284.32) R77.2@328.3,5284.32
  Top Layer w20: R77.2@328.2,5284.42 R77.2@328.3,5284.32 ; v1(464.9,6168.52) 464.9,6133.22 R76.2@466.3,6131.81
  other v1: 908.68,6390.96 949.68,6392.36 949.48,6422.26 907.48,6423.56
XDS_VREF: C117.1 C118.1 R86.1 U12.9 U16.3 | length 366.8
  Top Layer w6.8: U12.9@736.79,5407.67 736.79,5363.02 757.91,5341.91 C117.1@757.91,5281.28
  Top Layer w20: U16.3@563.19,5207.13 565.31,5209.25 565.31,5219.67 627.27,5281.63 C118.1@690.56,5281.63 ; C118.1@690.56,5281.28 C117.1@757.91,5281.28
pads on no net: FID1.1 FID2.1 FID3.1 FID4.1 FID5.1 FID6.1 H1.1 H2.1 H3.1 H4.1 H5.0 H6.0 H7.0 H8.0 J1.4 J1.5 J1.6 J2.4 J2.5 J2.6 J5. J5.4 J11.MH1 J11.MH2 J11.MP1 J11.MP2 J11.MP3 J11.MP4 J12.MH1 J12.MH2 J12.MP1 J12.MP2 J12.MP3 J12.MP4 LBL1.0 Q5.0 Q6.0 SW1. SW2. SW3. U3.11 U4.11 U5.11 U5.26 U7.11 U7.26 U10.11 U11.4 U12.2 U12.5 U12.6 U12.11 U12.12 U12.13 U12.14 U12.15 U12.18 U12.19 U12.20 U12.21 U12.22 U12.23 U12.24 U12.25 U12.27 U12.29 U12.30 U12.31 U12.32 U12.41 U12.44 U12.45 U12.46 U12.49 U12.50 U12.53 U12.54 U12.56 U12.57 U12.65 U12.67 U12.71 U12.72 U12.73 U12.74 U12.75 U12.76 U12.77 U12.78 U12.81 U12.82 U12.83 U12.84 U12.85 U12.86 U12.91 U12.92 U12.95 U12.102 U12.103 U12.104 U12.105 U12.106 U12.107 U12.108 U12.109 U12.110 U12.111 U12.112 U12.116 U12.117 U12.118 U12.119 U12.120 U12.121 U12.123 U12.124 U12.125 U12.126 U12.127 U12.128 U13.5 U13.7@1008.7,6472.6 U13.7@1008.7,6508.03 U14.3@675.72,6319.84 U14.4 U14.5 U14.6 U14.7 U14.8@675.72,6352.72 U16.2 U16.4 U16.5 U17.A9 U17.A14 U17.AA4 U17.AA5 U17.AA7 U17.AA8 U17.AA10 U17.AA11 U17.AA16 U17.AA17 U17.B2 U17.B13 U17.B17 U17.B18 U17.B19 U17.C2 U17.C16 U17.D2 U17.D4 U17.D6 U17.E3 U17.E4 U17.F3 U17.F4 U17.F5 U17.G1 U17.H1 U17.H2 U17.H5 U17.H11 U17.J2 U17.J3 U17.J4 U17.J13 U17.J18 U17.J19 U17.J20 U17.J21 U17.K1 U17.K2 U17.K4 U17.K18 U17.K20 U17.L1 U17.L2 U17.L3 U17.L5 U17.M2 U17.M4 U17.N2 U17.N4 U17.P1 U17.P2 U17.P21 U17.R2 U17.R5 U17.T1 U17.T2 U17.T3 U17.T4 U17.T5 U17.U1 U17.U2 U17.U3 U17.U13 U17.U14 U17.V2 U17.V4 U17.V5 U17.V6 U17.V9 U17.V10 U17.V12 U17.V13 U17.V18 U17.W1 U17.W2 U17.W5 U17.W6 U17.W9 U17.W11 U17.W13 U17.W16 U17.W17 U17.Y2 U17.Y3 U17.Y4 U17.Y5 U17.Y6 U17.Y7 U17.Y8 U17.Y9 U17.Y10 U17.Y11 U17.Y12 U17.Y13 U17.Y14 U17.Y16 U17.Y17 U18.3 U18.11 U18.13 U18.17 U18.19 U18.20 U18.21@1275.36,4923.88 U18.21@1275.36,4969.55 U18.21@1321.02,4923.88 U18.21@1321.02,4969.55 U23.12 U23.18 U23.19 U23.21 U23.22 U23.25 U23.26 U23.27 U23.29 U24.2 U25.A6 U25.A7 U25.F5 U25.F6 U25.G6 U25.H2 U25.J11 U25.K1 U25.K12 U26.A6 U26.A7 U26.F5 U26.F6 U26.G6 U26.H2 U26.J11 U26.K1 U26.K12 U30.F7 U30.H8 U31.1 U31.2 U31.3 U31.9 U31.10 U31.11 U33.4 U33.5 U33.6 U33.11 U33.12 U33.13 U33.14 Y2.2@1791.39,4167.79 Y2.3@1791.39,4226.84

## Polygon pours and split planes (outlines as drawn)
NetQ1_1 on Top Layer "TOP_LAYER_NETQ1_1_P2367" (solid, remove dead copper, pour order 2367): 4472.49,5344.32 4467.49,5339.32 4467.49,5279.32 4477.49,5269.32 4705.76,5269.32 4725.57,5289.13 4725.57,5406.58 4712.84,5419.32 4597.49,5419.32 4592.49,5414.32 4592.49,5349.32 4587.49,5344.32
HV_GND on Top Layer "TOP_LAYER_HV_GND_P2443" (solid, remove dead copper, pour order 2443): 21 vertices, not listed, extent 5362.49,5216.22 6182.49,5819.32
HV_GND on Top Layer "TOP_LAYER_HV_GND_P2444" (solid, remove dead copper, pour order 2444): 5302.49,4736.44 5414.08,4736.44 5416.29,4692.95 5745.52,4692.95 5931.65,4506.82 6158.1,4506.82 6158.1,4293.82 5910.02,4293.82 5755.11,4138.91 5302.49,4138.91 5302.49,4429.32
NetC15_1 on Top Layer "NONET_L-01_P-001" (solid, pour order 2549): 4088.43,5219.19 4088.43,4754.2 4386.4,4456.23 4452.82,4456.23 4452.82,4612.36 4448.92,4616.27 4394.26,4616.27 4282.33,4728.2 4282.33,5111.32 4338.55,5167.54 4338.55,5215.58 4332.63,5221.49 4091.83,5221.49 4087.24,5216.9
HV_GND on Top Layer "NONET_L-01_P-001" (solid, pour order 2548): 3692.48,5403.69 3692.48,5507.93 3671.77,5528.64 3671.77,5598.76 3685.31,5612.3 3908.4,5612.3 3925.93,5594.77 3925.93,5545.38 3841.48,5460.92 3841.48,5412.32
NetC21_1 on Top Layer "NONET_L-01_P-001" (solid, pour order 2547): 18 vertices, not listed, extent 3693.47,4927.3 4065.69,5446.31
NetC15_2 on Top Layer "NONET_L-01_P-001" (solid, pour order 2546): 4013.63,5352.25 3906.96,5352.25 3903.85,5349.14 3903.85,5310.51 3911.27,5303.08 4018.82,5303.08
NetC15_2 on Top Layer "NONET_L-01_P-001" (solid, pour order 2545): 19 vertices, not listed, extent 3998.36,5278.02 4435.33,5595.86
VSYS_3.3V on Top Layer "TOP_LAYER_VSYS_3.3V_P2439" (solid, remove dead copper, pour order 2439): 3476.49,4508.92 3476.49,3509.59 3624.99,3509.59 3624.99,4508.92
NetC33_1 on Top Layer "NONET_L-01_P-001" (solid, pour order 2544): 4751.99,5248.03 4707.87,5248.03 4686.62,5226.78 4686.62,5181.02 4585.43,5079.84 4585.43,4934.8 4590.37,4929.87 4950.85,4929.87 4963.16,4942.17 4963.16,5134.72 4992.83,5164.4 4992.83,5209.94 4953.68,5249.09 4752.51,5249.09
V_-100V_A on Top Layer "TOP_LAYER_V_-100V_A_P2438" (solid, remove dead copper, pour order 2438): 5877.18,4234.32 5758.57,4115.7 5432.88,4115.7 5375.49,4058.32 5375.49,3962.32 5415.49,3922.32 5868.49,3922.32 6008.81,4062.63 6109.49,4062.63 6109.49,4126.32 6141.4,4158.23 6141.4,4234.32
HV_GND on Top Layer "NONET_L-01_P-001" (solid, pour order 2543): 5263.99,4692.23 5263.99,5202.18 5287.22,5225.42 5381.08,5225.42 5413.55,5192.95 5413.55,4720.38
V_+50V_B on Top Layer "NONET_L-01_P-001" (solid, pour order 2542): 5205.48,3320.31 5205.48,3455.11 5212.84,3462.48 5362.67,3462.48 5374.64,3450.51 5374.64,3353.34 5374.64,3328.44 5347.83,3301.64 5225.29,3301.64 5204.23,3322.7
V_-50V_B on Top Layer "NONET_L-01_P-001" (solid, pour order 2541): 4894.04,3332.27 4894.04,3470.13 4899.3,3475.4 5093.17,3475.4 5105.62,3462.95 5105.62,3338.5 5087.43,3320.31 4903.61,3320.31 4893.08,3330.84
V_+100V_A on Top Layer "NONET_L-01_P-001" (solid, pour order 2540): 4479.49,3397.32 4578.93,3397.32 4599.09,3417.48 4598.66,3417.91 4598.66,3465.59 4615.13,3482.06 4655.44,3482.06 4676.68,3460.82 4676.68,3332.09 4657.17,3312.59 4579.59,3312.59
PHV_B on Top Layer "NONET_L-01_P-001" (solid, pour order 2539): 5223.49,3752.98 5229.92,3759.41 5370.77,3759.41 5400.98,3729.2 5400.98,3527.43 5368.62,3495.07 5223.92,3495.07 5223.49,3494.64
MHV_B on Top Layer "NONET_L-01_P-001" (solid, pour order 2538): 4881.89,3721.97 4900.27,3740.36 5047.53,3740.36 5071.35,3716.54 5071.35,3524.39 5054.79,3507.82 4883.79,3507.82 4881.89,3509.73
PHV_A on Top Layer "NONET_L-01_P-001" (solid, pour order 2537): 4480.64,3487.27 4451.85,3516.05 4451.85,3737.57 4470,3755.72 4592.02,3755.72 4623.94,3723.81 4623.94,3520.35 4592.73,3489.14 4478.76,3489.14
NetC31_1 on Top Layer "NONET_L-01_P-001" (solid, pour order 2534): 5213.79,4284.91 5205.48,4276.6 5205.48,3850.58 5220.1,3835.96 5331.45,3835.96 5337.41,3841.92 5337.41,3951.48 5264.16,4024.73 5264.16,4277.39 5256.65,4284.91
NetC35_2 on Top Layer "NONET_L-01_P-001" (solid, pour order 2532): 5025.16,4284.91 5012.13,4271.88 5012.13,3980.25 4945,3913.11 4945,3819.23 4956.22,3808.01 5045.92,3808.01 5071.35,3833.44 5071.35,4279.75 5066.19,4284.91
NetC19_2 on Top Layer "NONET_L-01_P-001" (solid, pour order 2531): 4548.26,4163.16 4556.16,4163.16 4575.47,4143.85 4575.47,3943.68 4591,3928.15 4591,3845.5 4581.58,3836.08 4579.49,3838.17 4474.86,3838.17 4474.86,3924.21 4508.34,3957.68 4508.34,4163.16
V_-100V_A on Top Layer "NONET_L-01_P-001" (solid, pour order 2530): 4117.5,3340.59 4117.5,3445.15 4145.09,3472.75 4307.58,3472.75 4311.08,3469.26 4311.08,3332.81 4306.41,3328.15 4117.88,3328.15 4115.94,3330.09
MHV_A on Top Layer "NONET_L-01_P-001" (solid, pour order 2529): 4275.66,3740.36 4310.7,3705.32 4310.7,3511.63 4306.89,3507.82 4117.49,3507.82 4117.49,3728.72 4115.49,3730.72 4125.13,3740.36
NetC23_1 on Top Layer "NONET_L-01_P-001" (solid, pour order 2528): 4256.5,4305.05 4249.64,4298.18 4249.64,4067.41 4114.89,3932.67 4114.89,3821.72 4118.66,3817.94 4268.11,3817.94 4311.13,3860.96 4311.13,4302.56 4307.65,4306.04 4257.48,4306.04 4256.23,4304.8
GND on Top Layer "TOP_LAYER_GND_P2447" (solid, remove dead copper, pour order 2447): 20 vertices, not listed, extent 19.73,-37.13 6196.83,6671.46
HV_GND on Top Layer "NONET_L-01_P-001" (solid, pour order 2527): 4668.36,4256.91 4668.36,4400.99 4693.91,4426.54 4832.31,4426.54 4862.83,4457.06 4960.07,4457.06 4976.39,4440.73 4976.39,3975.85 4957.56,3957.01 4681.47,3957.01 4663.99,3974.5
NetC18_2 on Top Layer "NONET_L-01_P-001" (solid, pour order 2526): 4624.43,4597.92 4624.43,4508.4 4508.62,4392.59 4508.62,4187.35 4514.68,4181.29 4546.72,4181.29 4576.17,4210.73 4576.17,4364.88 4667.97,4456.68 4731.18,4456.68
NetC22_1 on Top Layer "TOP_LAYER_NETC22_1_P2401" (solid, remove dead copper, pour order 2401): 3908.63,4734.32 4247.49,4395.46 4247.49,4325.73 4252.4,4320.82 4306.89,4320.82 4314.51,4328.44 4314.51,4427.03 4067.49,4684.2 4067.49,4734.32
HV_GND on Top Layer "TOP_LAYER_HV_GND_P2417" (solid, remove dead copper, pour order 2417): 4667.49,5234.32 4657.49,5244.32 4387.49,5244.32 4377.49,5234.32 4377.49,4989.32 4477.49,4889.32 4504.32,4889.32 4527.25,4912.25 4527.25,5119.08 4577.49,5169.32 4657.49,5169.32 4667.49,5179.32
V_+5.5V on Top Layer "TOP_LAYER_V_+5.5V_P2423" (solid, remove dead copper, pour order 2423): 3587.49,5883.52 3452.49,5883.52 3452.49,5719.32 3687.49,5719.32 3687.49,6149.32 3777.49,6149.32 3777.49,6234.32 3587.49,6234.32 3587.49,6224.32
GND on Top Layer "TOP_LAYER_GND_P2398" (solid, remove dead copper, pour order 2398): 2927.49,6229.32 2927.49,6059.32 3152.49,6059.32 3152.49,6229.32 3102.49,6229.32
NetQ3_1 on Top Layer "TOP_LAYER_NETQ3_1_P2374" (solid, remove dead copper, pour order 2374): 5407.49,5344.32 5402.49,5339.32 5402.49,5274.32 5407.49,5269.32 5607.49,5269.32 5654.81,5316.64 5654.81,5409.32 5532.71,5409.32 5532.71,5344.32
NetC27_2 on Top Layer "TOP_LAYER_NETC27_2_P2427" (solid, remove dead copper, pour order 2427): 4981.19,5389.22 4926.29,5334.32 4926.29,5285.52 4942.49,5269.32 5362.49,5269.32 5372.49,5279.32 5372.49,5379.32 5347.49,5404.32 5197.49,5404.32 5193.79,5408.02 5193.79,5526.52 4981.19,5526.52
V_-5.5V on Top Layer "TOP_LAYER_V_-5.5V_P2441" (solid, remove dead copper, pour order 2441): 17 vertices, not listed, extent 2477.49,5939.32 3342.49,6279.32
VSYS_3.3V on Top Layer "TOP_LAYER_VSYS_3.3V_P2424" (solid, remove dead copper, pour order 2424): 3207.49,5274.32 3196.69,5285.12 2919.1,5285.12 2786.69,5152.7 2786.69,5076.72 2805.99,5057.42 3099.8,5057.42 3131.7,5089.32 3187.49,5089.32 3207.49,5109.32
GND on Top Layer "y" (solid, remove dead copper, pour order 2421): 26 vertices, not listed, extent 2851.6,4879.62 3263.8,5427.52
VCC3P3_XDS on Top Layer "TOP_LAYER_VCC3P3_XDS_P2329" (solid, remove dead copper, pour order 2329): 689.46,5457.75 730.75,5457.75 730.75,5379.54 689.46,5379.54
V_+5.5V on Top Layer "TOP_LAYER_V_+5.5V_P2351" (solid, remove dead copper, pour order 2351): 18 vertices, not listed, extent 2342.1,5583.12 2582.3,5692.82
VMUX2_+5V on Top Layer "TOP_LAYER_VMUX2_+5V_P2344" (solid, remove dead copper, pour order 2344): 23 vertices, not listed, extent 2214.1,1315.18 2417,1468.9
GND on Top Layer "TOP_LAYER_GND_P2445" (solid, remove dead copper, pour order 2445): 79 vertices, not listed, extent 1428.44,1443.34 3749.89,1716.55
VMUX4_+5V on Top Layer "TOP_LAYER_VMUX4_+5V_P2341" (solid, remove dead copper, pour order 2341): 27 vertices, not listed, extent 3942.09,1311.68 4144.99,1467.06
VMUX4_+3.3V on Top Layer "TOP_LAYER_VMUX4_+3.3V_P2342" (solid, remove dead copper, pour order 2342): 18 vertices, not listed, extent 3677.7,1314.9 3866,1444.6
VMUX3_+5V on Top Layer "TOP_LAYER_VMUX3_+5V_P2346" (solid, remove dead copper, pour order 2346): 25 vertices, not listed, extent 3148,1318.34 3341.28,1466.74
VMUX1_+5V on Top Layer "TOP_LAYER_VMUX1_+5V_P2347" (solid, remove dead copper, pour order 2347): 26 vertices, not listed, extent 1412.49,1311.75 1615.39,1471.6
NetD1_1 on Top Layer "TOP_LAYER_NETD1_1_P2434" (solid, remove dead copper, pour order 2434): 5672.49,6486.52 5257.6,6486.52 5257.6,6269.97 5672.49,6269.97 5672.49,6289.32
V_+12V on Top Layer "TOP_LAYER_V_+12V_P2408" (solid, remove dead copper, pour order 2408): 5082.49,5964.32 5427.49,5964.32 5442.49,5949.32 5442.49,5859.32 5431.69,5848.52 4978.29,5848.52 4967.49,5859.32
NetC34_2 on Top Layer "TOP_LAYER_NETC34_2_P2405" (solid, remove dead copper, pour order 2405): 4727.49,4739.32 4947.49,4519.32 5007.49,4459.32 5007.49,4324.32 5027.49,4304.32 5062.49,4304.32 5072.49,4314.32 5072.49,4534.32 4897.49,4709.32 4897.49,4739.32
NetC27_1 on Top Layer "TOP_LAYER_NETC27_1_P2432" (solid, remove dead copper, pour order 2432): 5013.5,5194.66 5058.16,5239.32 5132.49,5239.32 5167.49,5204.32 5167.49,4559.32 5167.49,4504.32 5152.49,4489.32 5107.49,4489.32 5092,4504.8 5092,4544.92 5013.5,4623.42
NetC30_1 on Top Layer "TOP_LAYER_NETC30_1_P2356" (solid, remove dead copper, pour order 2356): 5232.49,4569.32 5207.49,4544.32 5207.49,4309.32 5212.49,4304.32 5252.49,4304.32 5262.49,4314.32 5262.49,4564.32 5257.49,4569.32
HV_GND on Top Layer "TOP_LAYER_HV_GND_P2436" (solid, remove dead copper, pour order 2436): 4432.49,5549.32 4457.49,5524.32 4577.49,5524.32 4597.49,5504.32 4597.49,5439.32 4677.49,5439.32 4792.49,5439.32 4792.49,5819.32 4782.49,5829.32 4442.49,5829.32 4432.49,5819.32 4432.49,5764.32
GND on Top Layer "TOP_LAYER_GND_P2399" (solid, remove dead copper, pour order 2399): 2492.49,6449.32 2507.49,6464.32 2722.49,6464.32 2747.49,6439.32 2747.49,6319.32 2737.49,6309.32 2507.49,6309.32 2492.49,6324.32 2492.49,6339.32
GND on Top Layer "TOP_LAYER_GND_P2365" (solid, remove dead copper, pour order 2365): 2237.49,6159.32 2247.49,6149.32 2247.49,6049.32 2232.49,6034.32 2117.49,6034.32 2112.49,6039.32 2112.49,6094.32 2097.49,6109.32 2057.49,6109.32 2052.49,6114.32 2052.49,6154.32 2057.49,6159.32
V_+12V on Top Layer "TOP_LAYER_V_+12V_P2352" (solid, remove dead copper, pour order 2352): 2967.49,6339.32 2917.49,6339.32 2897.49,6359.32 2772.49,6359.32 2767.49,6354.32 2767.49,6289.32 2772.49,6284.32 2902.49,6284.32 2917.49,6299.32 2967.49,6299.32 2972.49,6304.32 2972.49,6334.32
GND on Top Layer "TOP_LAYER_GND_P2357" (solid, remove dead copper, pour order 2357): 3112.49,5589.32 3097.49,5574.32 3097.49,5499.32 3117.49,5479.32 3212.49,5479.32 3237.49,5504.32 3237.49,5574.32 3222.49,5589.32
GND on Top Layer "TOP_LAYER_GND_P2358" (solid, remove dead copper, pour order 2358): 2812.49,5589.32 2797.49,5574.32 2797.49,5499.32 2817.49,5479.32 2912.49,5479.32 2937.49,5504.32 2937.49,5574.32 2922.49,5589.32
V_+12V on Top Layer "TOP_LAYER_V_+12V_P2379" (solid, remove dead copper, pour order 2379): 3278.65,5116.82 3273.65,5111.82 3273.65,5076.82 3223.65,5026.82 3223.65,4893.15 3242.49,4874.32 3327.49,4874.32 3343.65,4890.48 3343.65,5046.82 3313.65,5076.82 3313.65,5111.82 3308.65,5116.82
V_+12V on Top Layer "TOP_LAYER_V_+12V_P2368" (solid, remove dead copper, pour order 2368): 3282.49,5239.32 3277.49,5244.32 3277.49,5279.32 3227.49,5329.32 3227.49,5434.32 3252.49,5459.32 3327.49,5459.32 3347.49,5439.32 3347.49,5309.32 3317.49,5279.32 3317.49,5244.32 3312.49,5239.32
GND on Top Layer "TOP_LAYER_GND_P2350" (solid, remove dead copper, pour order 2350): 2507.49,4854.32 2532.49,4879.32 2532.49,4924.32 2542.49,4934.32 2672.49,4934.32 2687.49,4919.32 2687.49,4879.32 2672.49,4864.32 2547.49,4864.32 2517.49,4834.32 2457.49,4834.32 2477.49,4854.32
GND on Top Layer "TOP_LAYER_GND_P2420" (solid, remove dead copper, pour order 2420): 3362.49,6274.32 3362.49,5940.32 3572.49,5940.32 3572.49,6274.32
GND on Top Layer "TOP_LAYER_GND_P2422" (solid, remove dead copper, pour order 2422): 3967.49,6274.32 3967.49,6192.02 3877.49,6192.02 3877.49,5844.32 3712.49,5844.32 3712.49,6129.32 3797.49,6129.32 3797.49,6249.32 3557.49,6249.32 3557.49,6274.32
V_-5V on Top Layer "TOP_LAYER_V_-5V_P2426" (solid, remove dead copper, pour order 2426): 18 vertices, not listed, extent 1492.49,6174.32 1852.49,6424.32
V_+12V on Top Layer "TOP_LAYER_V_+12V_P2376" (solid, remove dead copper, pour order 2376): 3727.49,6344.32 3802.49,6344.32 3802.49,6409.32 3967,6409.32 3967,6294.32 3727.49,6294.32 3727.49,6332.82
V_-5.5V_filt on Top Layer "TOP_LAYER_V_-5.5V_FILT_P2390" (solid, remove dead copper, pour order 2390): 1952.49,6239.32 1952.49,6209.32 1957.49,6204.32 1977.49,6204.32 1982.49,6199.32 1982.49,6184.32 1986.31,6180.5 2293.67,6180.5 2302.49,6189.32 2302.49,6268.43 2296.6,6274.32 1959.5,6274.32 1950.84,6265.65 1950.84,6220.85
NetC96_1 on Top Layer "TOP_LAYER_NETC96_1_P2360" (solid, remove dead copper, pour order 2360): 2397.49,4779.32 2244.49,4779.32 2208.49,4815.32 2208.49,4870.32 2232.49,4894.32 2277.49,4894.32 2342,4829.81 2397,4829.81 2407.49,4819.32 2407.49,4789.32
VCORE_0.85V on Top Layer "TOP_LAYER_VCORE_0.85V_P2380" (solid, remove dead copper, pour order 2380): 1497.49,5244.32 1467.49,5274.32 1467.49,5329.8 1490.7,5353.02 1705.6,5353.02 1737.49,5321.13 1737.49,5244.32
GND on Top Layer "TOP_LAYER_GND_P2383" (solid, remove dead copper, pour order 2383): 17 vertices, not listed, extent 2172.49,5039.32 2677.49,5171.91
V_+100V_A on Top Layer "TOP_LAYER_V_+100V_A_P2431" (solid, remove dead copper, pour order 2431): 6097.49,3939.32 5930.49,3939.32 5884.49,3893.32 5487.49,3893.32 5410.49,3816.32 5410.49,3780.22 5862.1,3780.22 5944.2,3698.12 6137.7,3698.12 6142.6,3703.02 6142.6,3802.2 6118.49,3826.32 6106.49,3838.32 6106.49,3930.32
V_+50V_B on Top Layer "TOP_LAYER_V_+50V_B_P2433" (solid, remove dead copper, pour order 2433): 5489.49,4835.32 5456.49,4802.32 5456.49,4719.37 5791.43,4719.37 5945.49,4565.32 6128.49,4565.32 6146.49,4583.32 6146.49,4654.32 6106.49,4694.32 6106.49,4829.93 6101.1,4835.32
PHV_A on Top Layer "TOP_LAYER_PHV_A_P2397" (solid, remove dead copper, pour order 2397): 18 vertices, not listed, extent 3261.63,1719.64 3718.63,1967.14
PHV_A on Top Layer "TOP_LAYER_PHV_A_P2393" (solid, remove dead copper, pour order 2393): 3104.53,1962.34 3104.53,1813.55 3087.83,1796.84 2643.83,1796.84 2643.83,1723.34 2993.63,1723.34 3004.23,1733.94 3004.23,1755.14 3015.43,1766.34 3098.63,1766.34 3120.12,1787.84 3120.13,1965.64 3107.63,1965.64 3103.83,1961.84 3103.83,1960.95
PHV_A on Top Layer "TOP_LAYER_PHV_A_P2389" (solid, remove dead copper, pour order 2389): 2190.13,1964.45 2190.13,1815.64 2209.43,1796.34 2643.83,1796.34 2643.83,1723.14 2296.43,1723.14 2291.43,1728.14 2291.43,1757.34 2275.52,1773.24 2201.23,1773.24 2174.53,1799.94 2174.53,1967.74 2187.03,1967.74 2190.83,1963.95 2190.83,1963.05
MHV_B on Top Layer "TOP_LAYER_MHV_B_P2371" (solid, remove dead copper, pour order 2371): 2238.23,1993.95 2244.35,2000.07 2479.03,2001.55 2483.83,1996.74 2483.83,1853.64 2473.53,1843.34 2422.73,1843.34 2398.53,1867.55 2398.53,1913.34 2358.33,1953.55 2244.16,1953.55 2238.23,1959.48
MHV_B on Top Layer "TOP_LAYER_MHV_B_P2369" (solid, remove dead copper, pour order 2369): 1968.44,2000.11 1733.79,2001.58 1728.99,1996.78 1728.99,1853.68 1739.29,1843.38 1790.09,1843.38 1814.29,1867.58 1814.29,1913.38 1854.49,1953.58 1968.44,1953.58
MHV_A on Top Layer "TOP_LAYER_MHV_A_P2377" (solid, remove dead copper, pour order 2377): 1967.04,2018.69 1967.04,2061.59 1859.88,2061.6 1815.48,2106 1815.48,2179.4 1788.98,2205.9 1735.08,2205.9 1730.88,2201.7 1730.88,2024.4 1736.58,2018.7
MHV_A on Top Layer "TOP_LAYER_MHV_A_P2378" (solid, remove dead copper, pour order 2378): 3056.28,2019.57 3056.28,2055.47 3051.38,2060.37 2941.48,2060.37 2897.08,2104.77 2897.08,2178.17 2870.58,2204.67 2816.68,2204.67 2812.48,2200.47 2812.48,2023.17 2818.18,2017.47 3054.18,2017.47
MHV_B on Top Layer "TOP_LAYER_MHV_B_P2370" (solid, remove dead copper, pour order 2370): 3054.13,1993.25 3048,1999.37 2813.33,2000.85 2808.53,1996.05 2808.53,1852.95 2818.83,1842.65 2869.63,1842.65 2893.83,1866.85 2893.83,1912.65 2934.03,1952.85 3048.19,1952.85 3054.13,1958.78
MHV_A on Top Layer "r" (solid, remove dead copper, pour order 2373): 3326.63,2021.05 3326.63,2056.95 3331.53,2061.84 3441.43,2061.84 3485.83,2106.24 3485.83,2179.64 3512.33,2206.14 3554.23,2206.14 3562.33,2198.04 3562.33,2030.34 3550.93,2018.95 3328.73,2018.95
MHV_B on Top Layer "TOP_LAYER_MHV_B_P2366" (solid, remove dead copper, pour order 2366): 3322.43,1993.1 3328.55,1999.22 3553.04,2000.63 3561.33,1992.34 3561.33,1855.55 3548.28,1842.5 3506.93,1842.5 3482.73,1866.7 3482.73,1912.5 3442.53,1952.7 3328.36,1952.7 3322.43,1958.63
PHV_B on Top Layer "TOP_LAYER_PHV_B_P2396" (solid, remove dead copper, pour order 2396): 25 vertices, not listed, extent 1941.13,1684.14 2261.03,1969.55
VCC3P3_XDS on Top Layer "TOP_LAYER_VCC3P3_XDS_P2355" (solid, remove dead copper, pour order 2355): 1039.1,6469.52 1296.2,6469.52 1306.8,6458.92 1306.8,6402.52 1301.5,6397.22 1229.8,6397.22 1201.3,6425.72 1054.4,6425.72 1039.3,6440.82 1039.3,6469.56
VSYS_5V on Top Layer "TOP_LAYER_VSYS_5V_P2388" (solid, remove dead copper, pour order 2388): 2969.1,5609.32 2987.49,5609.32 2987.49,5559.32 2957.49,5559.32 2957.49,5604.32 2707.49,5604.32 2707.49,5604.57 2662.8,5604.57 2662.8,5734.32 2797.49,5734.32 2797.49,5674.32 2972.49,5674.32 2797.49,5674.32 2969.1,5674.32
V_-5V on Top Layer "TOP_LAYER_V_-5V_P2339" (solid, remove dead copper, pour order 2339): 2258.34,2497.24 2258.34,2616.55 2270.24,2628.44 2300.54,2628.44 2310.34,2618.64 2310.34,2509.79 2297.79,2497.24 2262.89,2497.24
V1_-5V on Top Layer "TOP_LAYER_V1_-5V_P2354" (solid, remove dead copper, pour order 2354): 2249.24,2475.95 2228.64,2455.34 2228.64,2254.34 2232.54,2250.45 2272.44,2250.45 2289.64,2267.64 2289.64,2426.14 2300.74,2437.24 2300.74,2469.05 2293.84,2475.95 2276.14,2475.95
VSYS_5V on Top Layer "TOP_LAYER_VSYS_5V_P2331" (solid, remove dead copper, pour order 2331): 2996.54,2398.53 2996.54,2445.54 3004.14,2453.14 3033.54,2453.14 3041.04,2445.64 3041.04,2395.55 3037.24,2391.74 3002.54,2391.74 3000.44,2393.84
V2_+5V on Top Layer "TOP_LAYER_V2_+5V_P2345" (solid, remove dead copper, pour order 2345): 3002.34,2361.24 3013.54,2372.45 3081.94,2372.45 3088.74,2365.64 3088.74,2251.05 3084.74,2247.05 3059.04,2247.05 3058.64,2246.64 3034.64,2246.64 3022.84,2258.45 3022.84,2322.44 3011.84,2333.45 3002.34,2342.95 3002.34,2361.64
V2_-5V on Top Layer "TOP_LAYER_V2_-5V_P2348" (solid, remove dead copper, pour order 2348): 3279.1,2425.83 3279.1,2285.23 3287.6,2276.73 3324.3,2276.73 3331.5,2283.93 3331.5,2389.63 3360.2,2418.33 3360.2,2463.93 3355.3,2468.83 3355,2468.53 3321.8,2468.53
VSYS_5V on Top Layer "TOP_LAYER_VSYS_5V_P2338" (solid, remove dead copper, pour order 2338): 3934.71,1487.06 3934.71,1526.86 3980.31,1572.46 4026.31,1572.46 4032.51,1566.26 4032.51,1519.46 4020.71,1507.66 3976.31,1507.66 3968.21,1499.56 3968.21,1482.66 3936.01,1482.66 3934.31,1484.36
VSYS_1.8V on Top Layer "TOP_LAYER_VSYS_1.8V_P2333" (solid, remove dead copper, pour order 2333): 3096.54,2447.64 3089.64,2454.55 3089.64,2506.64 3097.24,2514.24 3138.24,2514.24 3142.64,2509.84 3142.64,2455.84 3134.54,2447.74 3096.24,2447.74
VSYS_5V on Top Layer "TOP_LAYER_VSYS_5V_P2337" (solid, remove dead copper, pour order 2337): 1928.04,2397.64 1928.04,2489.45 1928.04,2524.74 1932.94,2529.64 1968.94,2529.64 1972.94,2525.64 1972.94,2491.45 1972.94,2408.05 1963.34,2398.45 1928.44,2398.45
V1_+5V on Top Layer "TOP_LAYER_V1_+5V_P2335" (solid, remove dead copper, pour order 2335): 1928.74,2342.14 1928.74,2369.84 1934.14,2375.24 1990.54,2375.24 1994.64,2371.14 1994.64,2255.84 1992.64,2253.84 1972.24,2253.84 1957.14,2268.95 1957.14,2328.05 1947.24,2337.95 1932.94,2337.95
VSYS_3.3V on Top Layer "TOP_LAYER_VSYS_3.3V_P2361" (solid, remove dead copper, pour order 2361): 2377.44,2431.45 2328.94,2479.95 2328.94,2707.35 2340.34,2718.74 2364.84,2718.74 2376.24,2707.35 2376.24,2506.24 2407.04,2475.45 2446.84,2475.45 2455.84,2466.44 2455.84,2436.24 2451.04,2431.45
NetC67_1 on Top Layer "TOP_LAYER_NETC67_1_P2407" (solid, remove dead copper, pour order 2407): 3422.49,5882.12 3422.49,5609.32 3057.49,5609.32 3057.49,5654.32 3287.49,5654.32 3287.49,5882.12
V_+12V on Top Layer "TOP_LAYER_V_+12V_P2410" (solid, remove dead copper, pour order 2410): 3622.49,6344.32 3547.49,6344.32 3547.49,6419.32 3257.49,6419.32 3257.49,6344.32 3072.49,6344.32 3072.49,6294.32 3622.49,6294.32 3622.49,6299.32
V_-5.5V on Top Layer "TOP_LAYER_V_-5.5V_P2363" (solid, remove dead copper, pour order 2363): 2317.49,6269.9 2322,6274.42 2477.49,6274.42 2477.49,6164.32 2327.49,6164.32 2317.49,6174.32 2317.49,6184.32
GND on Top Layer "TOP_LAYER_GND_P2362" (solid, remove dead copper, pour order 2362): 1757.49,6159.32 1562.3,6159.32 1547.4,6144.42 1547.4,6084.72 1555,6077.12 1757.49,6077.12
V_+12V on Top Layer "TOP_LAYER_V_+12V_P2446" (solid, remove dead copper, pour order 2446): 30 vertices, not listed, extent 4048.4,5802.1 5440.4,6579.22
GND on Top Layer "TOP_LAYER_GND_P2381" (solid, remove dead copper, pour order 2381): 2542.49,5719.32 2427.49,5719.32 2427.49,5689.32 2387.49,5689.32 2387.49,5894.32 2542.49,5894.32 2542.49,5814.32
NetC73_2 on Top Layer "TOP_LAYER_NETC73_2_P2411" (solid, remove dead copper, pour order 2411): 1918.38,5644.12 1918.38,5803.7 1944.2,5829.52 2090.3,5829.52 2232.8,5687.02 2299.7,5687.02 2308.6,5678.12 2308.6,5665.42 2306,5662.82 2242.9,5662.82 2238.9,5658.82 2238.9,5650.72 2232.3,5644.12
NetC77_1 on Top Layer "TOP_LAYER_NETC77_1_P2402" (solid, remove dead copper, pour order 2402): 1920.79,5344.43 1920.79,5322.2 1909.8,5311.22 1805.6,5311.22 1795.1,5300.72 1795.6,5300.22 1795.6,5187.12 1804.5,5178.22 2070.9,5178.22 2088.6,5195.92 2088.6,5252.52 2065.9,5275.22 2065.9,5331.12 2052.6,5344.42 1924.1,5344.42
USB_SHIELD on Top Layer "TOP_LAYER_USB_SHIELD_P2429" (solid, remove dead copper, pour order 2429): 806.7,6453.62 806.7,6684.32 247.8,6684.32 247.8,6573.62 432.2,6573.62 432.2,6572.42 451.6,6572.42 451.6,6427.32 557.9,6427.32 557.9,6524.92 736.7,6524.92 736.7,6432.32 807.3,6432.32 807.3,6458.02
NetC88_1 on Top Layer "TOP_LAYER_NETC88_1_P2412" (solid, remove dead copper, pour order 2412): 19 vertices, not listed, extent 2472.49,4789.32 2767.49,5189.63
GND on Top Layer "TOP_LAYER_GND_P2409" (solid, remove dead copper, pour order 2409): 1586.74,2212.05 1569.74,2195.05 1569.74,1839.74 1583.94,1825.55 1685.84,1825.55 1697.44,1837.14 1697.44,2200.45 1685.84,2212.05
VMUX3_+3.3V on Top Layer "TOP_LAYER_VMUX3_+3.3V_P2349" (solid, remove dead copper, pour order 2349): 22 vertices, not listed, extent 2898.7,1318.7 3100.5,1454.3
VSYS_1.8V on Top Layer "TOP_LAYER_VSYS_1.8V_P2400" (solid, remove dead copper, pour order 2400): 2437.49,5209.32 2432.49,5214.32 2377.49,5214.32 2312.49,5279.32 2212.49,5279.32 2172.49,5239.32 2172.49,5109.32 2182.49,5099.32 2377.49,5099.32 2437.49,5159.32 2437.49,5199.32
MHV_A on Top Layer "TOP_LAYER_MHV_A_P2372" (solid, remove dead copper, pour order 2372): 2244.24,2019.24 2244.24,2062.14 2353.43,2062.14 2397.83,2106.55 2397.83,2179.95 2424.33,2206.45 2468.64,2206.45 2475.24,2199.84 2475.24,2032.04 2462.44,2019.24
GND on Top Layer "TOP_LAYER_GND_P2430" (solid, remove dead copper, pour order 2430): 2507.64,2202.55 2507.64,1851.74 2518.74,1840.64 2759.94,1840.64 2771.64,1852.34 2771.64,2201.34 2760.54,2212.45 2517.54,2212.45 2507.04,2201.95
PHV_A on Top Layer "TOP_LAYER_PHV_A_P2382" (solid, remove dead copper, pour order 2382): 18 vertices, not listed, extent 1600.54,1724.84 2035.43,1965.84
V_-5V on Top Layer "TOP_LAYER_V_-5V_P2332" (solid, remove dead copper, pour order 2332): 3327.44,2504.05 3327.44,2546.64 3318.24,2555.84 3318.24,2575.15 3322.24,2579.15 3364.14,2579.15 3369.44,2573.85 3369.44,2554.84 3360.04,2545.45 3360.04,2500.45 3328.74,2500.45 3326.94,2502.24
XDS_USB_VBUS on Top Layer "TOP_LAYER_XDS_USB_VBUS_P2364" (solid, remove dead copper, pour order 2364): 19 vertices, not listed, extent 679.4,6375.32 978.3,6499.42
AVDD_IO2 on Top Layer "TOP_LAYER_AVDD_IO2_P2334" (solid, remove dead copper, pour order 2334): 3100.43,2416.04 3130.83,2416.04 3169.03,2377.84 3169.03,2237.54 3167.73,2236.24 3158.13,2236.24 3144.33,2250.04 3144.33,2363.24 3114.23,2393.34 3100.03,2393.34 3098.73,2394.64 3098.73,2414.34
VMUX2_+3.3V on Top Layer "TOP_LAYER_VMUX2_+3.3V_P2343" (solid, remove dead copper, pour order 2343): 18 vertices, not listed, extent 1966.9,1321.26 2167.3,1463.9
HV_GND on Top Layer "TOP_LAYER_HV_GND_P2442" (solid, remove dead copper, pour order 2442): 5455,3726.72 5424.44,3694.16 5424.44,3339.59 5447.31,3316.72 6146,3316.72 6167,3337.72 6167,3622.72 6146,3641.12 6123.41,3641.12 5863.6,3641.12 5778,3726.72 5687,3726.72
HV_GND on Top Layer "TOP_LAYER_HV_GND_P2413" (solid, remove dead copper, pour order 2413): 5453,5102.82 5453,5226.72 5480.6,5254.32 5907.49,5254.32 5942.49,5219.32 5878.61,5219.32 5762.11,5102.82
VMUX1_+3.3V on Top Layer "TOP_LAYER_VMUX1_+3.3V_P2359" (solid, remove dead copper, pour order 2359): 21 vertices, not listed, extent 1120.97,1309.16 1370.48,1483.22
GND on Top Layer "TOP_LAYER_GND_P2336" (solid, remove dead copper, pour order 2336): 23 vertices, not listed, extent 2683.14,2613.15 2871.04,2711.94
PHV_B on Top Layer "TOP_LAYER_PHV_B_P2395" (solid, remove dead copper, pour order 2395): 25 vertices, not listed, extent 3025.91,1684.14 3345.81,1969.55
HV_GND on Top Layer "TOP_LAYER_HV_GND_P2404" (solid, remove dead copper, pour order 2404): 3871.49,4579.32 3951.4,4579.32 4159.49,4371.23 4159.49,4108.32 4091.1,4108.32 4091.1,4315.7 3862.49,4544.32 3862.49,4569.32 3871.49,4578.32
V_-50V_B on Top Layer "TOP_LAYER_V_-50V_B_P2435" (solid, remove dead copper, pour order 2435): 6132.49,5153.32 5881.49,5153.32 5804.34,5076.17 5495.45,5076.17 5459.49,5040.2 5459.49,4971.32 5514.49,4916.32 6082.49,4916.32 6109.49,4943.32 6109.49,5047.32 6132.49,5070.32
AVDD_IO1 on Top Layer "TOP_LAYER_AVDD_IO1_P2340" (solid, remove dead copper, pour order 2340): 2029.44,2455.64 2029.44,2421.05 2054.44,2396.05 2054.44,2255.05 2060.14,2249.34 2086.64,2249.34 2091.44,2254.14 2091.44,2295.64 2077.34,2309.74 2077.34,2441.74 2060.24,2458.84 2031.74,2458.84 2029.44,2456.55
VSYS_1.8V on Top Layer "TOP_LAYER_VSYS_1.8V_P2330" (solid, remove dead copper, pour order 2330): 2030.04,2489.65 2016.34,2503.34 2016.34,2533.05 2021.94,2538.64 2063.14,2538.64 2069.34,2532.45 2069.34,2502.55 2056.44,2489.65
V_+12V on Layer 9 - LV PWR "LAYER_9_-_LV_PWR_V_+12V_P2487" (solid, remove dead copper, pour order 2487): 2778.7,6400.32 2751.8,6373.42 2751.8,6085.72 2818.2,6019.32 3160.49,6019.32 3228,5951.8 3228,4922.42 3291.1,4859.32 5142.49,4859.32 5827.49,5544.32 5827.49,6286.33 5713.5,6400.32
VSYS_3.3V on Layer 9 - LV PWR "Layer 9 - LV PWR-VSYS_3.3V" (solid, remove dead copper, pour order 2488): 94 vertices, not listed, extent 796.7,1358.09 4175.3,5996.02
V_+100V_A on Layer 9 - LV PWR "LAYER_9_-_LV_PWR_V_+100V_A_P2482" (solid, remove dead copper, pour order 2482): 18 vertices, not listed, extent 4421.49,3313.42 6116.39,3937.32
V_-100V_A on Layer 9 - LV PWR "LAYER_9_-_LV_PWR_V_-100V_A_P2481" (solid, remove dead copper, pour order 2481): 19 vertices, not listed, extent 4074.49,3306.02 6133.99,4240.82
V1_+5V on Layer 9 - LV PWR "LAYER_9_-_LV_PWR_V1_+5V_P2475" (solid, remove dead copper, pour order 2475): 1955.84,2309.84 1955.84,2278.24 2007.94,2226.14 2007.94,2000.05 2025.11,1982.87 2117.91,1982.87 2117.91,2014.17 2110.14,2021.94 2049.41,2021.94 2049.41,2296.78 2030.64,2315.55 1961.54,2315.54
AVDD_IO1 on Layer 9 - LV PWR "LAYER_9_-_LV_PWR_AVDD_IO1_P2473" (solid, remove dead copper, pour order 2473): 2059.39,2305.36 2066.18,2312.14 2091.34,2312.14 2112.04,2291.44 2112.04,2079.05 2146.84,2079.05 2155.42,2070.47 2155.42,2029.74 2067.24,2029.74 2059.39,2037.59
VCORE_0.85V on Layer 9 - LV PWR "LAYER_9_-_LV_PWR_VCORE_0.85V_P2480" (solid, remove dead copper, pour order 2480): 18 vertices, not listed, extent 1506.21,3509.32 2146.6,5352.82
XDS_USB_VBUS on Layer 9 - LV PWR "LAYER_9_-_LV_PWR_XDS_USB_VBUS_P2479" (solid, remove dead copper, pour order 2479): 971.06,6375.63 944.09,6348.66 561.64,6348.66 486.81,6273.83 486.81,5591.29 323.74,5428.22 323.74,5246.96 259.42,5246.96 249.04,5257.34 249.04,5496.29 369.37,5616.62 369.37,6309.22 516.69,6456.55 973.14,6456.55
VSYS_1.8V on Layer 9 - LV PWR "LAYER_9_-_LV_PWR_VSYS_1.8V_P2483" (solid, remove dead copper, pour order 2483): 32 vertices, not listed, extent 1440.49,3394.32 2462.49,5277.32
VDDSHV_3.3V on Layer 9 - LV PWR "LAYER_9_-_LV_PWR_VDDSHV_3.3V_P2478" (solid, remove dead copper, pour order 2478): 18 vertices, not listed, extent 1985.49,3509.32 2244.1,4069.32
VSYS_5V on Layer 9 - LV PWR "L_PWR-NetC62_1" (solid, remove dead copper, pour order 2485): 31 vertices, not listed, extent 1550.8,1484.09 3758.9,5739.22
V1_-5V on Layer 9 - LV PWR "LAYER_9_-_LV_PWR_V1_-5V_P2477" (solid, remove dead copper, pour order 2477): 23 vertices, not listed, extent 2124.84,1982.87 2301.74,2307.45
V2_-5V on Layer 9 - LV PWR "LAYER_9_-_LV_PWR_V2_-5V_P2474" (solid, remove dead copper, pour order 2474): 21 vertices, not listed, extent 3211.04,1987.05 3336.34,2324.05
AVDD_IO2 on Layer 9 - LV PWR "LAYER_9_-_LV_PWR_AVDD_IO2_P2472" (solid, remove dead copper, pour order 2472): 3146.44,2299.84 3146.44,2038.5 3239.96,2038.5 3239.96,2065.53 3235.54,2069.94 3197.04,2069.94 3197.04,2269.84 3167.04,2299.84
V2_+5V on Layer 9 - LV PWR "LAYER_9_-_LV_PWR_V2_+5V_P2476" (solid, remove dead copper, pour order 2476): 18 vertices, not listed, extent 3019.44,1982.87 3202.54,2310.82
V_-5V on Layer 9 - LV PWR "LAYER_9_-_LV_PWR_V_-5V_P2484" (solid, remove dead copper, pour order 2484): 21 vertices, not listed, extent 1158.4,3274.52 1628.5,6434.42
VCC3P3_XDS on Layer 9 - LV PWR "LAYER_9_-_LV_PWR_VCC3P3_XDS_P2486" (solid, remove dead copper, pour order 2486): 21 vertices, not listed, extent 320.69,3243.53 1387.8,6456.52
HV_GND on Bottom Layer "BOTTOM_LAYER_HV_GND_P2522" (solid, remove dead copper, pour order 2522): 18 vertices, not listed, extent 3622,3259.72 6173,5980.72
V_+12V on Bottom Layer "BOTTOM_LAYER_V_+12V_P2515" (solid, remove dead copper, pour order 2515): 5692.49,5499.32 5732.49,5499.32 5737.49,5504.32 5737.49,5564.32 5702.49,5599.32 5702.49,5632.39 5695.09,5639.79 5694.62,5639.32 5677.49,5639.32 5637.49,5599.32 5462.49,5599.32 5452.49,5589.32 5452.49,5529.32 5462.49,5519.32 5872.49,5519.32
GND on Bottom Layer "y" (solid, remove dead copper, pour order 2523): 22 vertices, not listed, extent 4.4,-193.28 6192.49,6688.3
PHV_A on Bottom Layer "BOTTOM_LAYER_PHV_A_P2521" (solid, remove dead copper, pour order 2521): 36 vertices, not listed, extent 1599.24,1599.43 4724.56,3806.92
VCC3P3_XDS on Bottom Layer "BOTTOM_LAYER_VCC3P3_XDS_P2510" (solid, remove dead copper, pour order 2510): 690.41,5568.71 690.41,5438.86 694.42,5434.85 725.79,5434.85 725.79,5552.2 709.4,5568.59
VSYS_3.3V on Bottom Layer "BOTTOM_LAYER_VSYS_3.3V_P2518" (solid, remove dead copper, pour order 2518): 2585.84,3621.34 2595.84,3611.34 2595.84,3534.34 2585.84,3524.34 2246.84,3524.34 2238.84,3532.34 2238.84,3614.34 2245.84,3621.34 2501.84,3621.34
VSYS_1.8V on Bottom Layer "BOTTOM_LAYER_VSYS_1.8V_P2511" (solid, remove dead copper, pour order 2511): 2419.1,4013.32 2463.2,4013.32 2468.49,4008.03 2468.49,3904.3 2464.5,3900.32 2423.49,3900.32 2416.49,3907.32 2416.49,4013.32 2416.49,3907.32 2416.49,4010.7
GND on Bottom Layer "r" (solid, remove dead copper, pour order 2513): 1863.74,3714.04 1794.54,3714.04 1784.84,3704.34 1784.84,3563.34 1800.84,3547.34 1847.84,3547.34 1864.84,3564.34 1864.84,3712.94
VCORE_0.85V on Bottom Layer "BOTTOM_LAYER_VCORE_0.85V_P2512" (solid, remove dead copper, pour order 2512): 1889.84,3700.34 1884.84,3695.34 1884.84,3545.34 1889.84,3540.34 1954.84,3540.34 1959.84,3545.34 1959.84,3695.34 1954.84,3700.34
USB_SHIELD on Bottom Layer "BOTTOM_LAYER_USB_SHIELD_P2520" (solid, remove dead copper, pour order 2520): 806.9,6453.07 806.9,6683.77 248,6683.77 248,6573.07 432.4,6573.07 432.4,6571.87 451.8,6571.87 451.8,6426.77 558.1,6426.77 558.1,6524.37 736.9,6524.37 736.9,6431.77 807.5,6431.77 807.5,6457.47
VDDSHV_3.3V on Bottom Layer "r" (solid, remove dead copper, pour order 2517): 2124.84,3536.34 2116.84,3528.34 1804.84,3528.34 1775.84,3557.34 1775.84,3689.34 1770.84,3694.34 1749.84,3694.34 1744.84,3689.34 1744.84,3472.47 1755.4,3461.9 2176.4,3461.9 2219.06,3504.57 2219.06,3532.81
GND on Bottom Layer "BOTTOM_LAYER_GND_P2519" (solid, remove dead copper, pour order 2519): 17 vertices, not listed, extent 2182.2,3640.82 2365.1,3913.42
VDDSHV_3.3V on Bottom Layer "y" (solid, remove dead copper, pour order 2514): 2123.83,3696.34 2123.83,3711.34 2130.84,3718.34 2174.84,3718.34 2182.84,3710.34 2182.84,3632.34 2192.84,3622.34 2218.84,3622.34 2228.84,3612.34 2228.84,3534.34 2218.84,3524.34 2136.84,3524.34 2124.84,3536.34 2124.84,3714.34
PHV_B on Layer 8 - HV PWR "LAYER_8_-_HV_PWR_PHV_B_P2469" (solid, remove dead copper, pour order 2469): 20 vertices, not listed, extent 2050.95,1581.37 5562.93,3800.95
MHV_B on Layer 8 - HV PWR "LAYER_8_-_HV_PWR_MHV_B_P2471" (solid, remove dead copper, pour order 2471): 65 vertices, not listed, extent 1660.55,1867.41 5125.29,3804.14
PHV_A on Layer 8 - HV PWR "HV_PWR-PHV_A" (solid, remove dead copper, pour order 2470): 56 vertices, not listed, extent 1398.64,1677.64 4724.56,3806.92
VDDSHV_3.3V on Layer 8 - HV PWR "r" (solid, remove dead copper, pour order 2468): 1714.3,3483.64 1728.63,3469.32 1776.9,3469.32 1784.7,3477.12 1784.7,3605.1 1744.49,3645.32 1744.49,3954.32 1787.49,3997.32 1790.49,4000.32 1790.49,4015.32 1777.49,4028.32 1744.49,4028.32 1714.3,3998.13
HV_GND on Layer 11 - SIG "LAYER_11_-_SIG_HV_GND_P2493" (solid, remove dead copper, pour order 2493): 18 vertices, not listed, extent 3622,3259.72 6173,5980.72
GND on Layer 11 - SIG "L11 GND" (solid, remove dead copper, pour order 2494): 20 vertices, not listed, extent 11,-0.48 6172,6688.72
USB_SHIELD on Layer 11 - SIG "LAYER_11_-_SIG_USB_SHIELD_P2492" (solid, remove dead copper, pour order 2492): 806.7,6453.62 806.7,6684.32 247.8,6684.32 247.8,6573.62 432.2,6573.62 432.2,6572.42 451.6,6572.42 451.6,6427.32 557.9,6427.32 557.9,6524.92 736.7,6524.92 736.7,6432.32 807.3,6432.32 807.3,6458.02
V_+50V_B on Layer 3 - SIG "LAYER_3_-_SIG_V_+50V_B_P2452" (solid, remove dead copper, pour order 2452): 18 vertices, not listed, extent 5186.49,3323.32 6110.13,4842.82
GND on Layer 3 - SIG "LAYER_3_-_SIG_GND_P2454" (solid, remove dead copper, pour order 2454): 20 vertices, not listed, extent 12,-193.28 6173,6688.72
V_-50V_B on Layer 3 - SIG "LAYER_3_-_SIG_V_-50V_B_P2453" (solid, remove dead copper, pour order 2453): 6085.39,5164.42 5923.09,5164.42 5853.99,5095.32 5256.59,5095.32 4910.89,4749.62 4910.89,3383.82 4967.59,3327.12 5093.29,3327.12 5140.99,3374.82 5140.99,4618.12 5436.19,4913.32 6081.73,4913.32 6111.49,4943.08 6111.49,5138.32
USB_SHIELD on Layer 3 - SIG "LAYER_3_-_SIG_USB_SHIELD_P2451" (solid, remove dead copper, pour order 2451): 806.7,6453.62 806.7,6684.32 247.8,6684.32 247.8,6573.62 432.2,6573.62 432.2,6572.42 451.6,6572.42 451.6,6427.32 557.9,6427.32 557.9,6524.92 736.7,6524.92 736.7,6432.32 807.3,6432.32 807.3,6458.02
HV_GND on Layer 5 - SIG "LAYER_5_-_SIG_HV_GND_P2460" (solid, remove dead copper, pour order 2460): 18 vertices, not listed, extent 3622,3259.72 6173,5980.72
GND on Layer 5 - SIG "LAYER_5_-_SIG_GND_P2461" (solid, remove dead copper, pour order 2461): 20 vertices, not listed, extent 12,-0.48 6173,6688.72
USB_SHIELD on Layer 5 - SIG "LAYER_5_-_SIG_USB_SHIELD_P2458" (solid, remove dead copper, pour order 2458): 806.7,6453.62 806.7,6684.32 247.8,6684.32 247.8,6573.62 432.2,6573.62 432.2,6572.42 451.6,6572.42 451.6,6427.32 557.9,6427.32 557.9,6524.92 736.7,6524.92 736.7,6432.32 807.3,6432.32 807.3,6458.02
V_+5.5V on Layer 5 - SIG "LAYER_5_-_SIG_V_+5.5V_P2459" (solid, remove dead copper, pour order 2459): 3482.49,5849.32 3462.49,5829.32 3462.49,5654.32 3422.49,5614.32 2670.9,5614.32 2605.9,5679.32 2517.49,5679.32 2507.49,5669.32 2507.49,5599.51 2575,5532 3501.18,5532 3603,5633.83 3603,5827.72 3581.4,5849.32
HV_GND on Layer 6 - SIG "LAYER_6_-_SIG_HV_GND_P2463" (solid, remove dead copper, pour order 2463): 18 vertices, not listed, extent 3622,3259.72 6173,5980.72
GND on Layer 6 - SIG "L6 GND" (solid, remove dead copper, pour order 2464): 20 vertices, not listed, extent 11,-0.48 6172,6688.72
USB_SHIELD on Layer 6 - SIG "LAYER_6_-_SIG_USB_SHIELD_P2462" (solid, remove dead copper, pour order 2462): 806.7,6453.62 806.7,6684.32 247.8,6684.32 247.8,6573.62 432.2,6573.62 432.2,6572.42 451.6,6572.42 451.6,6427.32 557.9,6427.32 557.9,6524.92 736.7,6524.92 736.7,6432.32 807.3,6432.32 807.3,6458.02
GND on Layer 14 - SIG "LAYER_14_-_SIG_GND_P2506" (solid, remove dead copper, pour order 2506): 20 vertices, not listed, extent 11,-0.48 6172,6688.72
HV_GND on Layer 14 - SIG "LAYER_14_-_SIG_HV_GND_P2505" (solid, remove dead copper, pour order 2505): 18 vertices, not listed, extent 3622,3259.72 6173,5980.72
VSYS_1.8V on Layer 14 - SIG "LAYER_14_-_SIG_VSYS_1.8V_P2503" (solid, remove dead copper, pour order 2503): 17 vertices, not listed, extent 1208.07,2442.03 3207.04,3497.8
USB_SHIELD on Layer 14 - SIG "LAYER_14_-_SIG_USB_SHIELD_P2501" (solid, remove dead copper, pour order 2501): 806.7,6453.62 806.7,6684.32 247.8,6684.32 247.8,6573.62 432.2,6573.62 432.2,6572.42 451.6,6572.42 451.6,6427.32 557.9,6427.32 557.9,6524.92 736.7,6524.92 736.7,6432.32 807.3,6432.32 807.3,6458.02
MHV_A on Layer 14 - SIG "LAYER_14_-_SIG_MHV_A_P2504" (solid, remove dead copper, pour order 2504): 55 vertices, not listed, extent 1706.06,2011.89 4385.65,3835.9
V_-5V on Layer 14 - SIG "LAYER_14_-_SIG_V_-5V_P2502" (solid, remove dead copper, pour order 2502): 1451.54,2601.35 1366.77,2686.12 1366.77,3299.88 1366.83,3299.88 1402.39,3335.44 1498.9,3335.44 1498.9,2779.39 1627.24,2651.04 3292.44,2651.05 3421.74,2521.74 3421.74,2495.64 3394.24,2468.14 3321.74,2468.14 3243.14,2546.74 1506.14,2546.74
HV_GND on Layer 12 - SIG "LAYER_12_-_SIG_HV_GND_P2496" (solid, remove dead copper, pour order 2496): 18 vertices, not listed, extent 3622,3259.72 6173,5980.72
GND on Layer 12 - SIG "L12 GND" (solid, remove dead copper, pour order 2497): 20 vertices, not listed, extent 11,-0.48 6172,6688.72
USB_SHIELD on Layer 12 - SIG "LAYER_12_-_SIG_USB_SHIELD_P2495" (solid, remove dead copper, pour order 2495): 806.7,6453.62 806.7,6684.32 247.8,6684.32 247.8,6573.62 432.2,6573.62 432.2,6572.42 451.6,6572.42 451.6,6427.32 557.9,6427.32 557.9,6524.92 736.7,6524.92 736.7,6432.32 807.3,6432.32 807.3,6458.02
HV_GND on Layer 10 - GND "LAYER_10_-_GND_HV_GND_P2490" (solid, remove dead copper, pour order 2490): 18 vertices, not listed, extent 3622,3259.72 6173,5980.72
GND on Layer 10 - GND "L15 GND" (solid, remove dead copper, pour order 2491): 20 vertices, not listed, extent 11,-0.48 6172,6688.72
USB_SHIELD on Layer 10 - GND "LAYER_10_-_GND_USB_SHIELD_P2489" (solid, remove dead copper, pour order 2489): 806.7,6453.62 806.7,6684.32 247.8,6684.32 247.8,6573.62 432.2,6573.62 432.2,6572.42 451.6,6572.42 451.6,6427.32 557.9,6427.32 557.9,6524.92 736.7,6524.92 736.7,6432.32 807.3,6432.32 807.3,6458.02
HV_GND on Layer 7 - GND "LAYER_7_-_GND_HV_GND_P2466" (solid, remove dead copper, pour order 2466): 18 vertices, not listed, extent 3622,3259.72 6173,5980.72
GND on Layer 7 - GND "L13 GND" (solid, remove dead copper, pour order 2467): 20 vertices, not listed, extent 11,-0.48 6172,6688.72
USB_SHIELD on Layer 7 - GND "LAYER_7_-_GND_USB_SHIELD_P2465" (solid, remove dead copper, pour order 2465): 806.7,6453.62 806.7,6684.32 247.8,6684.32 247.8,6573.62 432.2,6573.62 432.2,6572.42 451.6,6572.42 451.6,6427.32 557.9,6427.32 557.9,6524.92 736.7,6524.92 736.7,6432.32 807.3,6432.32 807.3,6458.02
HV_GND on Layer 15 - GND "LAYER_15_-_GND_HV_GND_P2508" (solid, remove dead copper, pour order 2508): 18 vertices, not listed, extent 3622,3259.72 6173,5980.72
GND on Layer 15 - GND "L10 GND" (solid, remove dead copper, pour order 2509): 20 vertices, not listed, extent 11,-0.48 6172,6688.72
USB_SHIELD on Layer 15 - GND "LAYER_15_-_GND_USB_SHIELD_P2507" (solid, remove dead copper, pour order 2507): 806.7,6453.62 806.7,6684.32 247.8,6684.32 247.8,6573.62 432.2,6573.62 432.2,6572.42 451.6,6572.42 451.6,6427.32 557.9,6427.32 557.9,6524.92 736.7,6524.92 736.7,6432.32 807.3,6432.32 807.3,6458.02
HV_GND on Layer 13 - GND "LAYER_13_-_GND_HV_GND_P2499" (solid, remove dead copper, pour order 2499): 18 vertices, not listed, extent 3622,3259.72 6173,5980.72
GND on Layer 13 - GND "LAYER_13_-_GND_GND_P2500" (solid, remove dead copper, pour order 2500): 20 vertices, not listed, extent 11,-0.48 6172,6688.72
USB_SHIELD on Layer 13 - GND "LAYER_13_-_GND_USB_SHIELD_P2498" (solid, remove dead copper, pour order 2498): 806.7,6453.62 806.7,6684.32 247.8,6684.32 247.8,6573.62 432.2,6573.62 432.2,6572.42 451.6,6572.42 451.6,6427.32 557.9,6427.32 557.9,6524.92 736.7,6524.92 736.7,6432.32 807.3,6432.32 807.3,6458.02
HV_GND on Layer 4 - GND "LAYER_4_-_GND_HV_GND_P2456" (solid, remove dead copper, pour order 2456): 18 vertices, not listed, extent 3622,3259.72 6173,5980.72
GND on Layer 4 - GND "L4 GND" (solid, remove dead copper, pour order 2457): 20 vertices, not listed, extent 11,-0.48 6172,6688.72
USB_SHIELD on Layer 4 - GND "LAYER_4_-_GND_USB_SHIELD_P2455" (solid, remove dead copper, pour order 2455): 806.7,6453.62 806.7,6684.32 247.8,6684.32 247.8,6573.62 432.2,6573.62 432.2,6572.42 451.6,6572.42 451.6,6427.32 557.9,6427.32 557.9,6524.92 736.7,6524.92 736.7,6432.32 807.3,6432.32 807.3,6458.02
HV_GND on Layer 2 - GND "LAYER_2_-_GND_HV_GND_P2449" (solid, remove dead copper, pour order 2449): 18 vertices, not listed, extent 3622,3259.72 6173,5980.72
GND on Layer 2 - GND "L2 GND" (solid, remove dead copper, pour order 2450): 20 vertices, not listed, extent 11,-0.48 6172,6688.72
USB_SHIELD on Layer 2 - GND "LAYER_2_-_GND_USB_SHIELD_P2448" (solid, remove dead copper, pour order 2448): 806.7,6453.62 806.7,6684.32 247.8,6684.32 247.8,6573.62 432.2,6573.62 432.2,6572.42 451.6,6572.42 451.6,6427.32 557.9,6427.32 557.9,6524.92 736.7,6524.92 736.7,6432.32 807.3,6432.32 807.3,6458.02

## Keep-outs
Keep-Out Layer:
  text ".Layer_Name" at 577,-858.49 h60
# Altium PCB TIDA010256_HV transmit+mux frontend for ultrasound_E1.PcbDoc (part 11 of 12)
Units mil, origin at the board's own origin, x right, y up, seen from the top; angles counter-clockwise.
Board outline 6192.49 x 6712.23 mil, 16 copper layers (Top Layer, Layer 2 - GND, Layer 3 - SIG, Layer 4 - GND, Layer 5 - SIG, Layer 6 - SIG, Layer 7 - GND, Layer 8 - HV PWR, Layer 9 - LV PWR, Layer 10 - GND, Layer 11 - SIG, Layer 12 - SIG, Layer 13 - GND, Layer 14 - SIG, Layer 15 - GND, Bottom Layer), stack 95.905 mil thick; 806 components, 539 nets, 3343 pads, 1848 vias.

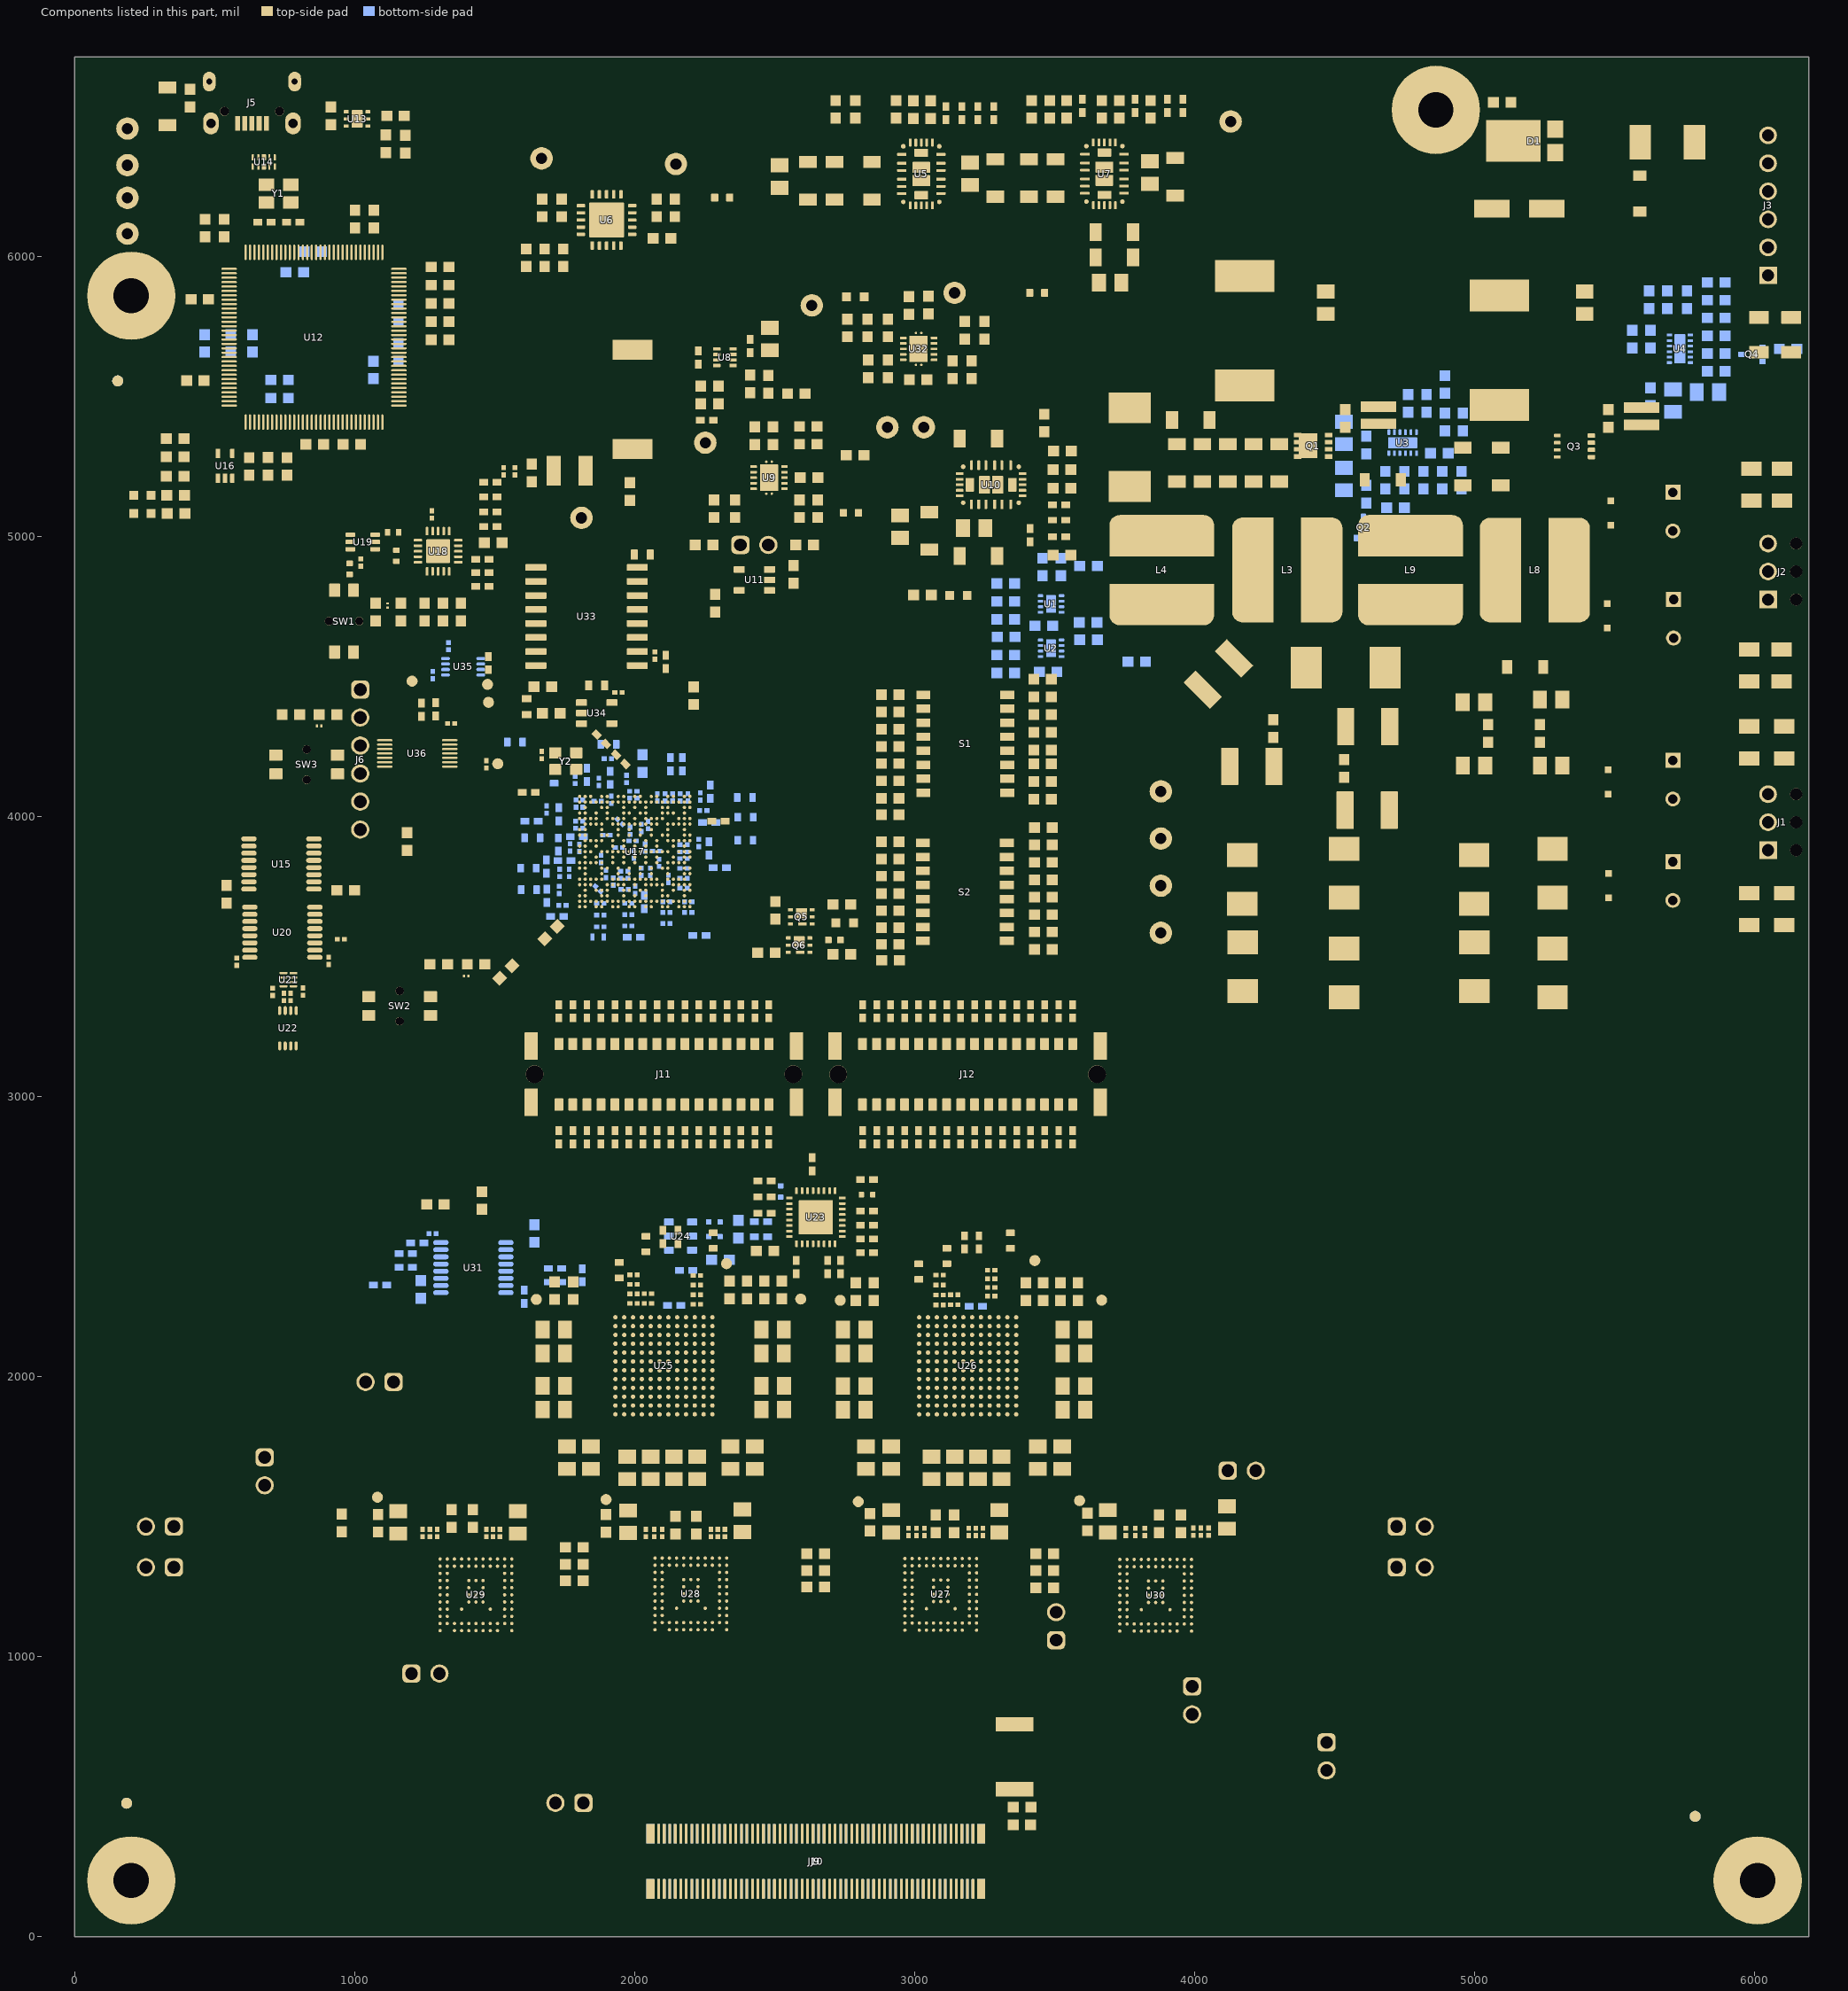
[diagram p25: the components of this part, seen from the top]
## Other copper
Top Layer:
  rectangle net NetF1_2: 5742.49,6181.32 6156.49,6544.32
  pour cut-out: 1913.07,3823.27 1898.51,3823.27 1890.46,3815.23 1890.46,3791.1 1881.88,3782.52 1874.82,3782.52 1874.82,3750.35 1876.12,3749.05 1886.99,3749.05 1886.99,3749.37 1906.77,3769.15 1906.77,3781.43 1912.96,3787.63 1925.78,3787.63 1933.72,3779.69 1933.72,3773.39 1957.84,3749.27 1957.84,3748.18 1984.36,3748.18 1989.9,3753.72 1989.9,3818.92 1987.29,3821.53 1975.88,3821.53
  pour cut-out: 5099.3,6567.11 5099.3,6671.46 4941.67,6671.46 4941.67,6567.11
  pour cut-out: 5672.49,6492.12 5257.8,6492.12 5257.8,6680.1 5672.49,6680.1
  pour cut-out: 5254.99,6207.9 5738.59,6207.9 5738.59,6263.21 5254.99,6263.21
  pour cut-out: 5258,6054 5942.49,6054 5942.49,5958.96 5257.6,5958.96 5257.6,5987.82
  pour cut-out: 5257.6,6254.12 5193.79,6254.12 5193.79,5974.51 5257.6,5974.51
  pour cut-out: 1764.2,4140.64 1764.2,4122.89 1768.75,4122.89 1768.75,4140.71 1764.12,4140.71
  pour cut-out: 1746.01,4142.95 1766.36,4142.95 1766.36,4145.88 1746.09,4145.88 1746.09,4143.03
  pour cut-out: 2760.93,2243.85 2760.93,2252.34 2737.96,2252.34 2737.96,2243.85 2737.96,2252.34 2737.96,2243.85
  pour cut-out: 2828.16,4056.41 2794.04,4056.41 2794.04,4099.37 2828.16,4099.37
  pour cut-out: 3437.87,5336.24 3490.28,5336.24 3490.28,5346.94 3437.73,5346.94
  pour cut-out: 1261.69,5729.09 1363.56,5729.09 1363.56,5739.79 1261.54,5739.79
  pour cut-out: 1313.31,5860.51 1365.72,5860.51 1365.72,5871.21 1313.17,5871.21
  pour cut-out: 1313.89,5927.47 1366.3,5927.47 1366.3,5938.17 1313.75,5938.17
  pour cut-out: 485.68,6093.16 593.6,6093.16 593.6,6103.86 485.53,6103.86
  pour cut-out: 822.1,5310.47 769.69,5310.47 769.69,5299.77 822.25,5299.77
  pour cut-out: 257.94,5086.18 257.94,5138.59 247.24,5138.59 247.24,5086.04
  pour cut-out: 371.61,5175.4 371.61,5356.82 360.91,5356.82 360.91,5175.25
  pour cut-out: 557.23,5185.38 600.88,5185.38 600.88,5196.08 557.08,5196.08
  pour cut-out: 466.9,5219.03 519.31,5219.03 519.31,5229.73 466.75,5229.73
  pour cut-out: 642,5251.24 794.55,5251.24 794.55,5256.96 794.55,5261.94 641.85,5261.94
  pour cut-out: 2258.59,5372.5 2224.46,5372.5 2224.46,5443.61 2258.59,5443.61
  pour cut-out: 1194.39,4731.53 1408.39,4731.53 1408.39,4798.23 1409.07,4798.9 1409.07,4830.27 1200.45,4830.27 1192.9,4822.72
  pour cut-out: 1167.46,4263.57 1133.33,4263.57 1133.33,4323.12 1167.46,4323.12
  pour cut-out: 1330.26,1882.12 1296.13,1882.12 1296.13,1925.07 1330.26,1925.07
  pour cut-out: 1391.67,1785.89 1357.54,1785.89 1357.54,1828.85 1391.67,1828.85
  pour cut-out: 3637.67,2948.94 1702.57,2948.94 1702.57,2854.62 3637.67,2854.62
  pour cut-out: 3637.67,3210.08 1702.57,3210.08 1702.57,3306.53 3637.67,3306.53
  pour cut-out: 3633.69,3022.67 1698.59,3022.67 1698.59,3132.58 3633.69,3132.58
  pour cut-out: 2270.39,4045.22 2236.27,4045.22 2236.27,4088.17 2270.39,4088.17
  pour cut-out: 2589.77,3937.43 2529.23,3937.43 2529.23,3980.38 2589.77,3980.38
  pour cut-out: 2390.09,3959.12 2355.96,3959.12 2355.96,4002.07 2390.09,4002.07
  pour cut-out: 2575.19,3568.74 2541.06,3568.74 2541.06,3611.69 2575.19,3611.69
  pour cut-out: 2827.37,3996.49 2793.25,3996.49 2793.25,4039.44 2827.37,4039.44
  pour cut-out: 2198.88,4733.92 2164.75,4733.92 2164.75,4776.87 2198.88,4776.87
  pour cut-out: 1614.26,4766 1580.13,4766 1580.13,4808.95 1614.26,4808.95
  pour cut-out: 1612.57,4433.4 1578.45,4433.4 1578.45,4480.65 1612.57,4480.65
  pour cut-out: 955.26,3822.76 921.13,3822.76 921.13,3865.71 955.26,3865.71
  pour cut-out: 1028.88,3713.05 976.19,3713.05 976.19,3796.98 1028.88,3796.98
  pour cut-out: 2386.05,4167.67 2322.4,4167.67 2322.4,4210.63 2386.05,4210.63
  pour cut-out: 2340.34,4227.68 2279.5,4227.68 2279.5,4270.63 2340.34,4270.63
  pour cut-out: 2296.77,4285.52 2262.65,4285.52 2262.65,4328.47 2296.77,4328.47
  pour cut-out: 2822.2,4291.59 2788.07,4291.59 2788.07,4334.54 2822.2,4334.54
  pour cut-out: 2822.2,4229.61 2788.07,4229.61 2788.07,4272.57 2822.2,4272.57
  pour cut-out: 2822.2,4169.11 2788.07,4169.11 2788.07,4212.07 2822.2,4212.07
  pour cut-out: 1754.5,3280.78 1753.62,3279.9 1753.62,3082.54 1645.51,3082.54 1655.26,3092.28 1655.26,3280.78
  pour cut-out: 1750,3389 2001.43,3389 2009.59,3397.16 2009.59,3561.12 1922.3,3561.12 1890.5,3529.32
  pour cut-out: 1356,2460.06 1364.85,2451.21 1364.85,2376.63 1641.67,2376.63 2035.15,2770.11 1356,2770.11
  pour cut-out: 2128.66,1975.73 2128.12,1975.23 2128.12,1881.62 2128.52,1881.22 2132.81,1881.22 2135.57,1883.99 2135.57,1968.82
  pour cut-out: 2080.33,1880.75 2080.87,1881.25 2080.87,1974.87 2080.47,1975.26 2076.19,1975.26 2073.42,1972.5 2073.42,1887.66
  pour cut-out: 3213.44,1975.73 3212.9,1975.23 3212.9,1881.62 3213.3,1881.22 3217.59,1881.22 3220.35,1883.99 3220.35,1968.82
  pour cut-out: 3165.11,1880.75 3165.65,1881.25 3165.65,1974.87 3165.25,1975.26 3160.97,1975.26 3158.2,1972.5 3158.2,1887.66
  pour cut-out: 3306.76,2082 3310.72,2085.97 3311.16,2085.97 3323.72,2073.41 3323.72,1994.78 3322.32,1993.38 3322.43,1938.53 3310.86,1926.96 3306.76,1931.06
  pour cut-out: 3071.24,1930 3067.28,1926.03 3066.84,1926.03 3054.28,1938.59 3054.28,2017.22 3055.68,2018.62 3055.57,2073.47 3067.14,2085.04 3071.24,2080.94
  pour cut-out: 2223,2085.25 2226.96,2089.21 2227.4,2089.21 2239.96,2076.65 2239.96,1998.02 2238.56,1996.62 2238.67,1941.78 2227.1,1930.21 2223,1934.3
  pour cut-out: 1984,2088.73 1980.04,2092.7 1979.6,2092.7 1967.04,2080.14 1967.04,2001.51 1968.44,2000.11 1968.33,1945.26 1979.9,1933.69 1984,1937.79
  pour cut-out: 3073.89,886.49 3073.89,864.63 2868.09,658.83 2837.12,689.8 2837.12,1204.02 2855.67,1204.02 2965.13,1094.56 2965.13,995.25
  pour cut-out: 2035.3,1224.18 1944.37,1133.26 1944.37,334.38 2005.75,273 2172.29,273 2203.2,303.91 2183.8,323.31 2127.57,323.31 2116.76,312.5 2031.19,312.5 2031.19,315.81 1973.85,373.15 1973.85,1115.14 1982.21,1115.14 2040.08,1173
  pour cut-out: 3254.49,5467.47 3254.49,5489.32 3413.49,5489.32 3413.49,5467.47
  pour cut-out: 4071.3,6364.84 4017,6364.84 4017,6360.72 4071.3,6360.72
  pour cut-out: 3967,6284.12 3993,6284.12 3993,6291.72 3967,6291.72
  pour cut-out: 3924.3,6538.42 3935.68,6538.42 3935.68,6534.17 3924.3,6534.17
  pour cut-out: 3880.68,6538.42 3871,6538.42 3871,6526.95 3880.68,6526.95
  pour cut-out: 3979.3,6585.67 3988.76,6585.67 3988.76,6573.71 3979.3,6573.71
  pour cut-out: 3765.68,6538.42 3759.97,6538.42 3759.97,6522.51 3765.68,6522.51
  pour cut-out: 3702.57,6522.51 3697.11,6522.51 3697.11,6507.09 3702.57,6507.09
  pour cut-out: 3697.11,6463.14 3702.57,6463.14 3702.57,6478.55 3697.11,6478.55
  pour cut-out: 3453.79,6463.14 3446.19,6463.14 3446.19,6478.55 3453.79,6478.55
  pour cut-out: 3446.19,6507.09 3446.19,6522.51 3453.79,6522.51 3453.79,6507.09
  pour cut-out: 2759.81,6463.14 2759.81,6478.55 2746.19,6478.55 2746.19,6463.14
  pour cut-out: 2322,6284.61 2296.6,6284.61 2296.6,6274.42 2322,6274.42
  pour cut-out: 2051.14,6138.74 2051.14,6170.3 2024.93,6170.3 2024.93,6138.74
  pour cut-out: 1707.31,6055.5 1707.31,6040.09 1715.96,6040.09 1715.96,6055.5
  pour cut-out: 1649.91,6055.5 1641.19,6055.5 1641.19,6040.09 1649.91,6040.09
  pour cut-out: 1641.19,5933.14 1649.91,5933.14 1649.91,5948.55 1641.19,5948.55
  pour cut-out: 1715.96,5996.13 1707.31,5996.13 1707.31,6011.54 1715.96,6011.54
  pour cut-out: 2095.68,6035.62 2095.68,6026.72 2082,6026.72 2082,6035.62
  pour cut-out: 3452.49,5709.12 3429,5709.12 3429,5713.72 3452.49,5713.72
  pour cut-out: 3207.76,5733.88 3220.36,5733.88 3220.36,5718.47 3207.76,5718.47
  pour cut-out: 3020.36,5823.88 3007.76,5823.88 3007.76,5808.47 3020.36,5808.47
  pour cut-out: 3020.36,5779.92 3007.76,5779.92 3007.76,5764.51 3020.36,5764.51
  pour cut-out: 2730.25,5828.57 2741.72,5828.57 2741.72,5805.38 2730.25,5805.38
  pour cut-out: 2770.27,5828.57 2787.76,5828.57 2787.76,5805.38 2770.27,5805.38
  pour cut-out: 2860.23,5742.39 2875.36,5742.39 2875.36,5726.98 2860.23,5726.98
  pour cut-out: 3433.79,5343.14 3406.76,5343.14 3406.76,5360.04 3433.79,5360.04
  pour cut-out: 3525.68,5275.62 3525.68,5266.58 3514,5266.58 3514,5275.62
  pour cut-out: 3524.3,5200.4 3524.3,5209.18 3506.76,5209.18 3506.76,5200.4
  pour cut-out: 3506.76,5143 3506.76,5134.69 3527,5134.69 3527,5143
  pour cut-out: 3518.24,5090.72 3503,5090.72 3503,5080.72 3518.24,5080.72
  pour cut-out: 3518.24,5036.07 3518.24,5019.69 3506.25,5019.69
  pour cut-out: 2327.49,6154.12 2273,6154.12 2273,6158.72 2327.49,6158.72
  pour cut-out: 1583.79,6055.5 1540,6055.5 1540,6048.72 1583.79,6048.72
  pour cut-out: 1029.9,6194 1041,6194 1041,6184.72 1029.9,6184.72
  pour cut-out: 1097.1,6071.64 1097.1,6050.72 1087.43,6050.72 1087.43,6071.64
  pour cut-out: 3759.97,6522.51 3764,6522.51 3764,6512.72
  pour cut-out: 3759.97,6522.51 3759.97,6517.61 3761.99,6517.61 3761.99,6509.72 3756,6509.72 3756,6522.51
  pour cut-out: 3671.96,6426.6 3684.87,6426.6 3684.87,6429.05 3671.96,6429.05
  pour cut-out: 3571.19,6522.51 3579,6522.51 3579,6517.72 3571.19,6517.72
  pour cut-out: 3453.79,6585.5 3453.79,6617.72 3467.2,6617.72 3467.2,6585.5
  pour cut-out: 3203.9,6512.96 3190.74,6512.96 3190.74,6508.71 3203.9,6508.71
  pour cut-out: 2848.67,5318.02 3014.65,5318.02 3014.65,5305.51 2848.67,5305.51
  pour cut-out: 3390.68,4954.95 3351,4954.95 3351,4962.72 3390.68,4962.72
  pour cut-out: 3065.99,4059.36 3065.99,3928.72 3055,3928.72 3055,4059.36
  pour cut-out: 3295.99,4059.36 3295.99,3927.72 3306,3927.72 3306,4059.36
  pour cut-out: 3363.99,3530.36 3397.81,3530.36 3397.81,3540.02 3363.99,3540.02
  pour cut-out: 2817.6,3887.85 2817.6,3938.27 2803.39,3938.27 2803.39,3887.85
  pour cut-out: 2818.45,3827.72 2818.45,3867.54 2805.13,3867.54 2805.13,3827.72
  pour cut-out: 2818.7,3770.99 2818.7,3802.44 2806.79,3802.44 2806.79,3770.99
  pour cut-out: 2530.99,3662.71 2541.38,3662.71 2541.38,3645.47 2530.99,3645.47
  pour cut-out: 2473.59,3662.71 2461,3662.71 2461,3658.84 2473.59,3658.84 2473.59,3660.75
  pour cut-out: 2756.36,3594.77 2740,3594.77 2740,3604.72 2756.36,3604.72
  pour cut-out: 1688.88,4910.63 1688.88,4995.74 1670.72,4995.74 1670.72,4910.63
  pour cut-out: 1874.1,4926.32 1874.1,5002.72 1881,5002.72 1881,4926.32
  pour cut-out: 2258.79,4762.62 2224.57,4762.62 2224.57,4780.93 2228.45,4780.93
  pour cut-out: 1694.89,4802.12 1684.79,4802.12 1684.79,4527.59 1694.89,4527.59 1694.89,4780.52
  pour cut-out: 3481,6463.14 3481,6427.72 3486,6427.72 3486,6463.14
  pour cut-out: 3639.71,6585.5 3620.53,6585.5 3620.53,6574.19 3639.71,6574.19
  pour cut-out: 2516.31,5538.02 2516.31,5527.13 2506.19,5527.13 2506.19,5538.02
  pour cut-out: 2506.19,5481.64 2516.31,5481.64 2516.31,5495.04 2506.19,5495.04
  pour cut-out: 2638.67,5480.72 2655,5480.72 2655,5489.9 2638.67,5489.9
  pour cut-out: 2207.6,5565.5 2207.6,5588.57 2253.91,5588.57 2253.91,5565.5
  pour cut-out: 3464.93,4961.58 3464.93,4976.07 3478.22,4976.07 3478.22,4961.58
  pour cut-out: 3518.24,4976.07 3506.76,4976.07 3506.76,4961.58 3518.24,4961.58
  pour cut-out: 1771.71,4196.93 1744.9,4196.93 1744.9,4200.5 1771.71,4200.5
  pour cut-out: 1822.31,4122.89 1848.33,4122.89 1848.33,4108.62 1822.31,4108.62
  pour cut-out: 817.03,4917.62 780,4917.62 780,4923.72 817.03,4923.72 817.03,4917.62
  pour cut-out: 1506.06,4847.9 1516,4847.9 1516,4854.72 1506.06,4854.72
  pour cut-out: 2110.49,5182.47 2163,5182.47 2163,5188.72 2110.49,5188.72
  pour cut-out: 2553.94,2307.22 2581.49,2307.22 2581.49,2304.6 2553.94,2304.6
  pour cut-out: 2553.94,2247.85 2581.49,2247.85 2581.49,2253.13 2553.94,2253.13
  pour cut-out: 2220.85,1933.69 2283.9,1933.69 2301.35,1916.25 2301.35,1834.45 2298.15,1831.25 2276.26,1831.25 2256.33,1851.18 2228.8,1851.18 2203.86,1876.12 2203.86,1917.37 2214.73,1928.24
  pour cut-out: 2510.5,1812.13 2493.25,1812.13 2493.25,2252.13 2510.5,2252.13
  pour cut-out: 2308.15,1719.97 2308.15,1672.76 2259.02,1672.76 2259.02,1686.95 2278.83,1686.95 2278.83,1719.97
  pour cut-out: 2206.88,2169.94 2206.88,1872.25 2190.88,1872.25 2190.88,2169.94
  pour cut-out: 2832,2633.77 2832,2639.88 2786.35,2639.88 2786.35,2633.77
  pour cut-out: 2818.34,2301.02 2818.34,2286.11 2824.93,2286.11 2824.93,2301.02
  pour cut-out: 2667.34,2389.11 2598.86,2389.11 2598.86,2411.77 2667.34,2411.77 2667.34,2407.83
  pour cut-out: 2737.36,2789.54 2694.25,2789.54 2694.25,2784.13 2737.36,2784.13
  pour cut-out: 2760.93,2301.02 2760.93,2292.53 2737.96,2292.53 2737.96,2301.02 2737.96,2292.53 2737.96,2301.02
  pour cut-out: 2818.34,2257.57 2824.93,2257.57 2824.93,2242.16 2818.34,2242.16 2818.34,2241.65
  pour cut-out: 3305.63,1933.69 3368.68,1933.69 3386.13,1916.25 3386.13,1834.45 3382.93,1831.25 3361.04,1831.25 3341.11,1851.18 3313.58,1851.18 3288.64,1876.12 3288.64,1917.37 3299.51,1928.24
  pour cut-out: 3072.92,1933.69 3009.87,1933.69 2992.43,1916.25 2992.43,1834.45 2995.62,1831.25 3017.51,1831.25 3037.44,1851.18 3064.97,1851.18 3089.91,1876.12 3089.91,1917.37 3079.04,1928.24
  pour cut-out: 2790.3,2022.76 2790.3,1814.13 2780.25,1814.13 2780.25,2244.13 2817.27,2244.13
  pour cut-out: 3580.93,2197.63 3580.93,2246.13 3566.25,2246.13 3566.25,2197.63
  pour cut-out: 3580.93,2029.93 3580.93,1818.13 3574.25,1818.13 3574.25,2029.93
  pour cut-out: 2966.53,1713.15 2966.53,1666.04 3029.88,1666.04 3029.88,1678.42 3020.73,1678.42 3020.73,1713.15
  pour cut-out: 3392.08,1716.26 3392.08,1669.05 3343.87,1669.05 3343.87,1683.24 3362.76,1683.24 3362.76,1716.26
  pour cut-out: 2017.9,2175.34 2017.9,1872.25 2001.9,1872.25 2001.9,2175.34
  pour cut-out: 2015.4,2460.56 2015.4,2496.08 2021.4,2496.08 2021.4,2460.56
  pour cut-out: 1742.94,2305.22 1751.53,2305.22 1751.53,2289.81 1742.94,2289.81
  pour cut-out: 1988.14,1933.69 1925.09,1933.69 1907.64,1916.25 1907.64,1834.45 1910.84,1831.25 1932.73,1831.25 1952.66,1851.18 1980.19,1851.18 2005.13,1876.12 2005.13,1917.37 1994.26,1928.24
  pour cut-out: 1875.25,1719.08 1875.25,1671.98 1938.09,1671.98 1938.09,1684.36 1929.45,1684.36 1929.45,1719.08
  pour cut-out: 1695.65,2249.13 1705.25,2249.13 1705.25,1816.13 1695.65,1816.13
  pour cut-out: 2920.52,1381.79 2894.42,1381.79 2894.42,1386.81 2920.52,1386.81
  pour cut-out: 2066.56,2458.88 2066.56,2494.41 2072.56,2494.41 2072.56,2458.88
  pour cut-out: 2612.74,2759.66 2562.59,2759.66 2562.59,2756.13 2612.74,2756.13
  pour cut-out: 2511.98,2409.48 2350.94,2409.48 2350.94,2423.43 2511.98,2423.43
  pour cut-out: 3084.15,2434.32 3041.04,2434.32 3041.04,2456.97 3084.15,2456.97
  pour cut-out: 3102.68,2175.34 3102.68,1872.25 3086.68,1872.25 3086.68,2175.34
  pour cut-out: 3291.66,2169.94 3291.66,1872.25 3275.66,1872.25 3275.66,2169.94
  text ".Layer_Name" at 577,-858.49 h60
Layer 2 - GND:
  pour cut-out: 3088.31,2360.73 3088.31,1807.39 3291.18,1807.39 3291.18,2364.29 3279.04,2364.29 3279.04,1836.29 3100.64,1836.29 3100.64,2360.73
  pour cut-out: 2003,2310.9 2003,1807 2206.2,1807 2206.2,2310.9 2191.54,2310.9 2191.54,1835.9 2015.85,1835.9 2015.85,2310.9
Layer 3 - SIG:
  pour cut-out: 1770.94,4116.93 1736.82,4116.93 1736.82,4149.04 1770.94,4149.04
  pour cut-out: 2231.01,4054.43 2196.89,4054.43 2196.89,4086.54 2231.01,4086.54
  pour cut-out: 2357.77,3967.33 2323.64,3967.33 2323.64,3999.44 2357.77,3999.44
  pour cut-out: 1720.77,2465.41 1730.82,2455.36 1764.17,2491.15 1756.43,2498.88
  pour cut-out: 2612.94,424.99 2609.44,428.49 2339.94,428.49 2267.45,356 2289.22,334.24 2532.37,334.24 2623.79,242.82 2597.67,216.71 2597.67,115.44 2399.98,115.44 2339.69,55.15 1623.89,55.15 1320.66,358.37 1320.66,560.75 1294.43,586.98 1294.43,806.6 1466.62,634.42 1879.33,634.42 1960.33,553.42 2142.45,553.42 2206.52,617.49 2438.46,617.49 2627.56,428.39
  pour cut-out: 2656.73,90.61 2927.32,90.61 2929.4,88.53 2929.4,434.51 2964.75,434.51 2972,427.25 2972,372.01 3068.16,275.85 3099.33,275.85 3122.47,299 3015.01,406.46 3015.01,425.41 2977.32,463.1 2915.59,463.1 2892.95,485.74 2892.95,585.73 2868.09,610.59 2868.09,677.96 3048.16,858.03 2815.93,858.03 2684.55,726.66 2684.55,373.83 2676.1,365.38 2676.1,278.85 2660.03,262.78
  pour cut-out: 1822.56,1959.48 1822.56,2152.32 1768.03,2206.85 1768.03,2207.42 1187.19,2207.42 954,1974.23 954,1770 1006.63,1717.37 1006.63,933.37 1007.63,933.37 1070,871 1537.42,871 1552.91,886.49 1905.79,886.49 2041.81,750.47 2330.42,750.47 2392.95,813 2510.35,813 2554.35,857 2635,857 2684.55,906.55 2684.55,1209.58 2728.41,1253.44 2845.82,1136.03 2988.09,1136.03 3017.67,1106.46 3167.9,1106.46 3225.91,1048.45 3225.91,1011.69 3519.85,717.75 3667.29,865.19 3667.29,872.24 3548.77,990.77 3498.45,990.77 3432.05,1057.17 3432.05,1107.49 3428.85,1107.49 3224.57,1311.77 3118.2,1311.77 3110.63,1319.34 3110.63,1402.57 3188.55,1480.5 3282.45,1480.5 3497.35,1695.4 3497.35,1869.71 3421.74,1945.32 3389.15,1912.73 3346.68,1912.73 3326.49,1932.92 3305.7,1912.12 3269.95,1912.12 3252.14,1894.31 3252.14,1788.57 3182.81,1719.23 3065.78,1719.23 3016.05,1768.97 3016.05,1865.09 3063.21,1912.26 3063.37,1912.26 3063.37,1965.65 3053.91,1975.11 2907.67,1975.11 2771.66,1839.1 2373.66,1839.1 2299.77,1913 2299.77,1928.35 2246.18,1928.35 2198.61,1880.78 2198.61,1855.48 2179.97,1836.84 2179.97,1836.13 1999.31,1836.13 1978.75,1856.7 1978.75,1912.1 1931.37,1959.48
  pour cut-out: 2181.3,442.55 2226.55,442.55 2226.55,428.51 2181.3,428.51
  pour cut-out: 2816.2,804.47 2861.45,804.47 2861.45,790.43 2816.2,790.43
  pour cut-out: 2002.76,2311.13 2002.76,1807.23 2205.96,1807.23 2205.96,2311.13 2191.3,2311.13 2191.3,1836.13 2015.61,1836.13 2015.61,2311.13
  pour cut-out: 3088.14,2360.58 3088.14,1807.23 3291.01,1807.23 3291.01,2364.13 3278.87,2364.13 3278.87,1836.13 3100.47,1836.13 3100.47,2360.58
  pour cut-out: 2035.49,5315.32 2253,5315.32 2253,5227.72 2035.49,5227.72
  pour cut-out: 1590.3,5281.33 1590.3,5216.72 1565,5216.72 1565,5281.33
  pour cut-out: 1450.18,4818.72 1457,4818.72 1457,4903.72 1450.18,4903.72
  pour cut-out: 2834.43,3500.02 2822.49,3500.02 2822.49,3651.39 2834.43,3651.39
  pour cut-out: 1916.16,3997.97 1916.16,3965.45 1913.56,3965.45 1913.56,3997.97
  pour cut-out: 1859.97,3853.91 1859.97,3808.65 1845.93,3808.65 1845.93,3853.91
  pour cut-out: 1618.3,3635.46 1513,3635.46 1513,3646.72 1618.3,3646.72
  pour cut-out: 1856.92,3738.07 1856.92,3784.45 1852.52,3784.45 1852.52,3738.07
  pour cut-out: 1411.43,4088.84 1411.43,4049.72 1419,4049.72 1419,4088.84
  pour cut-out: 1490.36,3521.42 1490.36,3401.93 1483.26,3401.93 1483.26,3521.42
  pour cut-out: 1412,4715.72 1433.71,4715.72 1433.71,4720.52 1412,4720.52
  pour cut-out: 1833.2,4124.91 1878.46,4124.91 1878.46,4110.86 1833.2,4110.86
  pour cut-out: 3048.62,2374.62 3093.88,2374.62 3093.88,2360.58 3048.62,2360.58
  pour cut-out: 2952.6,2182.38 3072.53,2182.38 3072.53,2168.34 2952.6,2168.34
  pour cut-out: 1720.75,1647.56 1766,1647.56 1766,1633.52 1720.75,1633.52
  pour cut-out: 1695.26,1356.7 1740.52,1356.7 1740.52,1342.66 1695.26,1342.66
  pour cut-out: 1865.33,1302.87 1910.59,1302.87 1910.59,1288.82 1865.33,1288.82
  pour cut-out: 2148.75,1392.22 2194.01,1392.22 2194.01,1378.18 2148.75,1378.18
  pour cut-out: 3087.54,2311.13 3087.54,1807.23 3290.74,1807.23 3290.74,2311.13 3276.08,2311.13 3276.08,1836.13 3100.39,1836.13 3100.39,2311.13
Layer 4 - GND:
  pour cut-out: 3088.15,2360.57 3088.15,1807.23 3291.02,1807.23 3291.02,2364.13 3278.88,2364.13 3278.88,1836.13 3100.48,1836.13 3100.48,2360.57
  pour cut-out: 2003,2310.9 2003,1807 2206.2,1807 2206.2,2310.9 2191.54,2310.9 2191.54,1835.9 2015.85,1835.9 2015.85,2310.9
Layer 5 - SIG:
  rectangle net NetF1_2: 5743.49,6183.32 6154.49,6542.32
  pour cut-out: 3042.6,40.59 3008.48,40.59 3008.48,72.71 3042.6,72.71
  pour cut-out: 2903.41,624.08 2869.29,624.08 2869.29,656.2 2903.41,656.2
  pour cut-out: 3382.75,2161.06 3401.9,2180.21 3479.57,2180.21 3650.95,2351.58 3650.95,2956.94 3514.03,3093.86 3514.03,3160.73 2708.73,3160.73 2542.74,3326.73 1983.41,3326.73 1955.16,3354.97 1955.16,3382.84 1781.69,3556.3 1781.69,3572.67 1603.15,3751.22 1603.15,3809.26 1649.3,3855.42 1649.3,4026.33 1636.52,4039.12 1543.7,4039.12 1527.2,4022.62 1464.6,4022.62 1426.39,3984.41 1426.39,3787.6 1343.64,3704.85 1343.64,2616.93 1406.82,2553.75 1406.82,2352.24 1528.67,2230.39 1737.43,2230.39 1866.35,2101.47 2010.01,2101.47 2025.76,2085.72 2183.24,2085.72 2197.75,2100.23 2197.75,2163.23 2214.73,2180.21 2277.72,2180.21 2288.57,2169.36 2391.84,2169.36 2541.07,2318.59 2603.7,2318.59 2701.57,2220.71 2701.57,2121.69 2787.26,2036 2944.38,2036 2978.71,2070.33 3189.63,2070.33 3205.02,2085.72 3236.52,2085.72 3268.02,2054.23 3283.89,2070.1 3330.78,2070.1 3376.05,2115.37 3382.75,2115.37
  pour cut-out: 3249.08,80.53 3076.42,80.53 3050.15,106.79 3050.15,127.15 3078,155 3078,377.63 3088.9,388.54 3088.9,429.16 3065.78,452.28 3065.78,527.53 3097.7,559.45 3289.46,559.45 3309.08,539.82 3309.08,236.14 3249.08,176.14
  pour cut-out: 1822.56,1959.48 1789.07,1925.99 1684.9,1925.99 1643,1884.09 1643,1683.69 1621.25,1661.94 1621.25,1279.63 1717.54,1183.35 1717.54,1129.5 1907.04,940 2244.65,940 2258.22,926.43 2527.76,926.43 2755.15,1153.82 2755.15,1182.48 2999.38,1426.7 3408.88,1426.7 3496,1513.82 3496,1871.06 3421.74,1945.32 3311.91,1945.32 3299.51,1932.92 3299.51,1906.5 3197.51,1804.5 3104.92,1804.5 3074.18,1835.23 3074.18,1901.44 3063.37,1912.26 3063.37,1969.52 3057.78,1975.11 2953.03,1975.11 2810.68,1832.76 2810.68,1823.21 2577.56,1823.21 2384.9,1630.55 2356.61,1630.55 2356.61,1856.16 2346.34,1866.43 2346.34,1881.79 2299.77,1928.35 2246.18,1928.35 2198.61,1880.78 2198.61,1855.48 2166.35,1823.21 2041.44,1823.21 2041.44,1823.41 1998.75,1866.11 1998.75,1920.38 1974.01,1945.12 1974.01,1970.24 1969.13,1975.11 1904.88,1975.11 1889.25,1959.48
  pour cut-out: 2004.23,2314.13 2004.23,1807.18 2205.05,1807.18 2205.05,2314.13 2191.17,2314.13 2191.17,1836.08 2017,1836.08 2017,2314.13
  pour cut-out: 3089.01,2314.13 3089.01,1807.18 3289.83,1807.18 3289.83,2314.13 3275.95,2314.13 3275.95,1836.08 3101.78,1836.08 3101.78,2314.13
  pour cut-out: 1567.25,2304.13 1567.25,2256.01 1557.71,2256.01 1557.71,2304.13
  pour cut-out: 2262.55,975.98 2346.25,975.98 2346.25,982.13 2262.55,982.13
  pour cut-out: 3454.66,1878.26 3421.25,1878.26 3421.25,1876.13 3454.66,1876.13
  pour cut-out: 2261.9,1925.99 2224.25,1925.99 2224.25,1919.13 2261.9,1919.13
  pour cut-out: 2261.9,1925.99 2290.25,1925.99 2290.25,1919.13 2261.9,1919.13
  pour cut-out: 1588.25,2312.13 1597.25,2312.13 1597.25,2258.13 1588.25,2258.13
  pour cut-out: 2184.85,1676.83 2184.85,1685.13 2097.7,1685.13 2097.7,1676.83
Layer 6 - SIG:
  pour cut-out: 3088.09,2360.52 3088.09,1807.17 3290.97,1807.17 3290.97,2364.07 3278.83,2364.07 3278.83,1836.07 3100.42,1836.07 3100.42,2360.52
  pour cut-out: 2002.91,2311.17 2002.91,1807.27 2206.12,1807.27 2206.12,2311.17 2191.46,2311.17 2191.46,1836.17 2015.77,1836.17 2015.77,2311.17
  pour cut-out: 3534.54,1400.16 3610.44,1400.16 3610.44,1380.92 3534.54,1380.92
  pour cut-out: 3723,1206.45 3723,1181.64 3712.07,1181.64 3712.07,1206.45
  pour cut-out: 4003.4,1295.5 4003.4,1141.96 4049.64,1141.96 4185.76,1005.83 4313.69,1133.77 4313.69,1145.31 4163.5,1295.5
  pour cut-out: 1508.22,445.42 1694.03,631.23 1694.03,1179.37 1576.23,1297.17 1576.23,761.23 1506.29,691.29 1506.29,660.19
  pour cut-out: 2263.03,105.61 2197.56,171.08 1654.92,171.08 1256,570 1256,1079.29 1270.91,1079.29 1300.46,1108.85 1281.09,1128.22 1281.09,1281.23 1066.23,1066.37 1066.23,611.12 1629.12,48.23 1631.89,50.99 2226.43,50.99
Layer 7 - GND:
  pour cut-out: 3088.14,2360.56 3088.14,1807.22 3291.01,1807.22 3291.01,2364.12 3278.87,2364.12 3278.87,1836.12 3100.47,1836.12 3100.47,2360.56
  pour cut-out: 2002.91,2310.9 2002.91,1807 2206.12,1807 2206.12,2310.9 2191.45,2310.9 2191.45,1835.9 2015.76,1835.9 2015.76,2310.9
Layer 8 - HV PWR:
  pour cut-out: 3161.72,1928.59 3161.72,1903.91 3174.74,1890.88 3210.84,1890.88 3221.14,1901.18 3221.14,1928.48
  pour cut-out: 2078.35,1921.13 2078.35,1891.33 2086.25,1883.43 2122.35,1883.43 2132.65,1893.73 2132.65,1921.03
Layer 9 - LV PWR:
  pour cut-out: 3130.85,2275.55 3135.33,2280.03 3142.03,2273.34 3142.03,2036.29 3162.78,2015.54 3169.49,2015.54 3173.53,2010.62 3137.02,2010.62 3130.85,2016.79
  pour cut-out: 3631.28,1307.16 3224.05,1307.16 3224.05,1296.82 3631.28,1296.82
  pour cut-out: 2577.1,6479.32 2577.1,6672.32
Layer 10 - GND:
  pour cut-out: 3088.12,2360.45 3088.12,1807.1 3290.99,1807.1 3290.99,2364 3278.85,2364 3278.85,1836 3100.45,1836 3100.45,2360.45
  pour cut-out: 2002.84,2311.22 2002.84,1807.32 2206.05,1807.32 2206.05,2311.22 2191.38,2311.22 2191.38,1836.22 2015.69,1836.22 2015.69,2311.22
Layer 11 - SIG:
  pour cut-out: 3088.19,2360.47 3088.19,1807.13 3291.07,1807.13 3291.07,2364.03 3278.92,2364.03 3278.92,1836.03 3100.52,1836.03 3100.52,2360.47
  pour cut-out: 2002.7,2311.19 2002.7,1807.29 2205.9,1807.29 2205.9,2311.19 2191.24,2311.19 2191.24,1836.19 2015.55,1836.19 2015.55,2311.19
  pour cut-out: 2047.95,1576.01 2047.64,1576.32 2047.64,1615.48 2243.05,1615.48 2243.05,1573.55
  pour cut-out: 3005.09,1842.64 3004.78,1842.95 3004.78,1882.11 3056.59,1882.11 3056.59,1841.99
  pour cut-out: 2440,1881.44 2439.7,1881.74 2439.7,1920.9 2698.07,1920.9 2698.07,1878.18
  pour cut-out: 2836.07,1592.1 2835.77,1592.4 2835.77,1631.56 2887.58,1631.56 2887.58,1591.45
  pour cut-out: 3015.35,1581.64 3015.05,1581.95 3015.05,1621.11 3066.86,1621.11 3066.86,1580.99
  pour cut-out: 3369.39,1548.03 3369.69,1548.34 3408.85,1548.34 3408.85,1496.53 3368.74,1496.53
  pour cut-out: 3532,1638 3532.3,1638.3 3571.46,1638.3 3571.46,1586.49 3531.35,1586.49
  pour cut-out: 3489,648 3489,641.03 3434.71,586.74 3472.52,548.92 3472.52,572.79 3518.34,618.61
  pour cut-out: 2538.07,681.76 2546.1,673.73 2546.1,527.18 2494.86,527.18 2496.77,529.09 2496.77,640.47
  pour cut-out: 2057.76,1301.41 2057.76,1147.86 1938.9,1029 1930.44,1029 1857.9,1101.54
Layer 12 - SIG:
  pour cut-out: 3088.14,2360.63 3088.14,1807.29 3291.02,1807.29 3291.02,2364.19 3278.87,2364.19 3278.87,1836.19 3100.47,1836.19 3100.47,2360.63
  pour cut-out: 2002.91,2310.9 2002.91,1807 2206.12,1807 2206.12,2310.9 2191.45,2310.9 2191.45,1835.9 2015.76,1835.9 2015.76,2310.9
  pour cut-out: 2945.26,744.2 2945.26,755.13 3048.16,858.03 2971.94,858.03 2945.26,884.71 2950.15,889.59 2950.15,1222.97 2930.75,1222.97 2887.21,1179.42 2887.21,802.26
  pour cut-out: 2540.81,1251.63 2540.5,1251.93 2540.5,1291.09 2592.31,1291.09 2592.31,1250.98
Layer 13 - GND:
  pour cut-out: 3088.16,2360.61 3088.16,1807.26 3291.03,1807.26 3291.03,2364.16 3278.89,2364.16 3278.89,1836.16 3100.49,1836.16 3100.49,2360.61
  pour cut-out: 2002.81,2311.2 2002.81,1807.3 2206.01,1807.3 2206.01,2311.2 2191.35,2311.2 2191.35,1836.2 2015.66,1836.2 2015.66,2311.2
Layer 14 - SIG:
  pour cut-out: 1294.43,770 1294.43,623.59 1673,1002.15 1673,1021.19 1644,1050.19 1644,1070.06 1619.25,1094.82
  pour cut-out: 2357.07,229.72 2336.85,209.49 2336.85,90.84 2292.15,90.84 2291.93,90.61 2291.93,217.5 2279.71,229.72 2063.33,229.72 2056.33,222.72 2056.33,274.04 1899,431.38 1899,772.12 2031.01,904.13 2087.85,904.13 2087.85,839.54 2087.85,766.33 2090.17,766.33 2115.49,741.01 2227.29,852.82 2461.08,852.82 2473.72,840.18 2479.22,840.18 2479.22,824.5 2306.53,651.81 2306.53,603.2 2415.49,494.24 2473.86,494.24 2516.32,451.77 2516.32,416.26 2584.38,348.21 2658.26,348.21 2676.41,330.05 2676.41,261.9 2643.55,229.04 2599.99,229.04 2597.67,226.72 2594.67,229.72
  pour cut-out: 3421.74,1983.94 3442.1,2004.3 3478.96,2004.3 3523.47,2048.81 4112.12,2048.81 4283.47,1877.47 4532,1628.94 4532,1265.38 4113.12,846.49 3822.63,846.49 3677.39,701.25 3513.02,701.25 3493.97,720.3 3017.24,720.3 2990.7,693.76 2916.48,693.76 2602.42,1007.82 2516.34,1007.82 2498.93,990.41 2360.54,1128.81 2259.41,1128.81 2102.32,1285.91 2051.34,1285.91 2040.97,1296.27 1984.75,1296.27 1841.55,1439.47 1846.45,1444.36 1846.45,1520.86 1821.97,1545.34 1708.44,1545.34 1644,1609.78 1644,1900.89 1671.93,1928.82 1757.86,1928.82 1788.53,1959.48 1822.56,1959.48 1854.32,1991.23 1962.76,1991.23 1978.14,1975.86 1978.14,1953.97 2004.96,1927.15 2004.96,1827.05 2024.77,1807.23 2170.97,1807.23 2195.92,1832.19 2195.92,1878.1 2230.24,1912.42 2261.58,1912.42 2277.52,1928.35 2299.77,1928.35 2346.34,1881.79 2346.34,1866.43 2510.44,1702.33 2672.12,1702.33 2691.68,1721.9 2691.68,1867.13 2718.95,1894.4 2718.95,1979.59 2742.1,2002.73 2978.53,2002.73 3006.15,1975.11 3057.78,1975.11 3063.37,1969.52 3063.37,1912.26 3093.08,1882.55 3093.08,1832.91 3112.12,1813.87 3234.29,1813.87 3252.64,1832.22 3252.64,1903.11 3261.65,1912.12 3278.26,1912.12 3299.06,1932.92 3326.49,1932.92 3338.89,1945.32 3421.74,1945.32
  pour cut-out: 2002.76,2311.13 2002.76,1807.23 2205.96,1807.23 2205.96,2311.13 2191.3,2311.13 2191.3,1836.13 2015.61,1836.13 2015.61,2311.13
  pour cut-out: 3087.54,2311.13 3087.54,1807.23 3290.74,1807.23 3290.74,2311.13 3276.08,2311.13 3276.08,1836.13 3100.39,1836.13 3100.39,2311.13
Layer 15 - GND:
  pour cut-out: 3088.25,2360.49 3088.25,1807.15 3291.12,1807.15 3291.12,2364.05 3278.98,2364.05 3278.98,1836.05 3100.58,1836.05 3100.58,2360.49
  pour cut-out: 2002.78,2311.16 2002.78,1807.26 2205.98,1807.26 2205.98,2311.16 2191.32,2311.16 2191.32,1836.16 2015.63,1836.16 2015.63,2311.16
Bottom Layer:
  pour cut-out: 2002.79,2311.07 2002.79,1807.17 2206,1807.17 2206,2311.07 2191.33,2311.07 2191.33,1836.07 2015.64,1836.07 2015.64,2311.07
  pour cut-out: 3027.79,206.52 3050.43,206.52 3050.43,217.29 3047.74,219.99 3015.55,219.99 3011.06,215.49 3011.06,206.52
  pour cut-out: 3519.85,715.4 3522.2,715.4 3553.26,684.34 3553.26,557.26 3305.86,309.86 3221.14,309.86 3210.86,320.14 3210.86,353.67 3248.8,391.61 3288.36,391.61 3495.28,598.53 3495.28,690.82 3470.71,666.25 3448.93,688.03 3448.93,747.82 3603.2,902.09 3637.44,902.09 3667.29,872.24 3519.85,724.8
  pour cut-out: 3073.89,886.49 2970.99,783.59 2970.99,749.08 3052.14,667.93 2928.82,544.6 2928.82,527.18 2892.95,491.31 2892.95,430.13 2659.26,430.13 2657.76,428.63 2657.76,444.66 2657.98,444.66 2671.49,458.18 2671.49,658.07 2899.91,886.49
  pour cut-out: 2088.49,840.18 2088.49,840.17 2088.49,583.95 1974.12,583.95 1883.73,674.34 1883.73,1338.28 1958.88,1413.43 2053.39,1413.43 2120.55,1346.26 2175.65,1346.26 2196.08,1325.83 2196.08,1273.52 2187.29,1264.73 2129.62,1264.73 2112.97,1248.07 2112.97,1171.52 2119.48,1171.52 2134,1157 2122.49,1157 2071.09,1105.6 2088.49,1088.2
  pour cut-out: 1565.01,394.21 1697.22,526.42 1768.58,526.42 1925.07,369.93 1977.07,369.93 2026.16,320.84 2195.68,320.84 2203.97,312.55 2143.92,252.5 1993.69,252.5 1938.64,307.55 1563.05,307.55
  pour cut-out: 1294.43,586.98 1294.43,806.6 1354.88,806.6 1556,1007.72 1556,1111.28 1657.83,1111.28 1662.55,1106.56 1662.55,955.1
  pour cut-out: 1798.86,3864.13 1829.6,3864.13 1829.6,3859.25 1798.86,3859.25
  pour cut-out: 1783,3804.38 1783,3820.51 1796,3820.51 1796,3804.38
  pour cut-out: 1663.68,3771.95 1663.68,3758.72
  pour cut-out: 1663.68,3761.72 1714.22,3761.72 1714.22,3774.82 1663.68,3774.82
  pour cut-out: 1893.42,4232.26 1925,4232.26 1925,4238.72 1893.42,4238.72
  pour cut-out: 1738.39,4163.87 1738.39,4132.61 1726.14,4132.61 1726.14,4163.87
  pour cut-out: 1737.45,4188.16 1719,4188.16 1719,4223.72 1737.45,4223.72
  pour cut-out: 2266.24,3927.72 2256,3927.72 2256,3957.72 2266.24,3957.72
  pour cut-out: 3264.31,4547.42 3264.31,4539.72 3276,4539.72 3276,4547.42
  pour cut-out: 2235.49,2573.75 2221.25,2573.75 2221.25,2566.13 2235.49,2566.13
  pour cut-out: 2177.31,2541.05 2177.31,2472.03 2182.62,2472.03 2182.62,2566.91 2178.24,2566.91
  pour cut-out: 2150.54,2491.05 2150.54,2472.03 2145.23,2472.03 2145.23,2491.05
  pour cut-out: 2094.63,2491.05 2094.63,2454.13 2100.25,2454.13 2100.25,2491.05
  pour cut-out: 2245.17,2388.53 2232.82,2388.53 2232.82,2399.13 2245.17,2399.13
  pour cut-out: 1140.3,2348.45 1140.3,2368.74 1132.98,2368.74 1132.98,2348.45
  pour cut-out: 1140.3,2304.82 1140.3,2260.13 1135.25,2260.13 1135.25,2304.82
  pour cut-out: 2229.25,1925.47 2288.25,1925.47 2288.25,1919.13 2229.25,1919.13
  pour cut-out: 5712.69,5610.16 5755.62,5610.16 5755.62,5603.54 5712.69,5603.54
  pour cut-out: 2418.03,4023.3 2399.44,4023.3 2399.44,3983.58 2407,3983.58 2407,4013.32 2419.1,4013.32 2419.1,4023.51
  pour cut-out: 2399.44,4023.3 2478.7,4023.3 2478.7,4029.22 2399.44,4029.22
  pour cut-out: 2002.76,2311.13 2002.76,1807.23 2205.96,1807.23 2205.96,2311.13 2191.3,2311.13 2191.3,1836.13 2015.61,1836.13 2015.61,2311.13
  pour cut-out: 3087.54,2311.13 3087.54,1807.23 3290.74,1807.23 3290.74,2311.13 3276.08,2311.13 3276.08,1836.13 3100.39,1836.13 3100.39,2311.13
  text ".Layer_Name" at 577,-858.49 h60

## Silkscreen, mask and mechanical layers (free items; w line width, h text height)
Top Overlay:
  lines w20: 1240,1044 1240,1395
  text "12V" at 4206.8,6468.52 h30
  text "-5V" at 1621.42,6463.1 h30
  text "-5V5" at 2096.73,6442.6 h30
  text "TDO" at 38.61,6437.05 h30
  text "TDI" at 46.69,6301.88 h30
  text "+12V" at 5889,6276 h30 r90
  text "TMS" at 39.33,6187.27 h30
  text "TCK" at 44.48,6050.62 h30
  text "GND" at 5883,6006.22 h30 r90
  text "5V5" at 3102.55,5973.52 h30
  text "5V" at 2606.37,5931.8 h30
  text "3V3" at 2990.63,5452.62 h30
  text "PGOOD" at 2824.71,5448.8 h30
  text "1V8" at 2314.62,5346.78 h30
  text "0V85" at 1756.35,4972.12 h30
  text "-50V" at 5916,4921 h30 r90
  text "+50V" at 5916,4731 h30 r90
  text "RESETSTAT" at 1329.87,4449.63 h40
  text "MCU_PORz" at 1084.87,4433.26 h40
  text "PORz_OUT" at 1342.46,4398.06 h40
  text "SOC__SYNC_OUT" at 1400,4226.86 h40
  text "GND" at 3718,4074.41 h30
  text "3V3" at 908.02,4032.63 h40
  text "-100V" at 5916,4006.97 h30 r90
  text "GND" at 908.26,3934.22 h40
  text "GND" at 3718,3906.07 h30
  text "+100V" at 5916,3817.64 h30 r90
  text "GND" at 3718,3737.74 h30
  text "GND" at 3718,3569.41 h30
  text "For Demo Purposes Only.  Not for Diagnostic or Therapeutic Use" at 3494.69,2623.31 h100
  text "U26 CRC_ERR" at 3473.9,2460.47 h40
  text "U25 CRC_ERR" at 2151.74,2403.63 h40
  text "U26 TSHUT" at 3704.65,2260.53 h40
  text "U25 TX_RXZ" at 1497,2229.14 h40
  text "U25 TSHUT" at 2646.89,2193.53 h40 r90
  text "U26 TX_RXZ" at 2675.41,2141.53 h40 r90
  text "U29 S0" at 998,1876 h30
  text "U30 S31" at 4078.07,1729.39 h30
  text "U29 THERM" at 990.26,1594.09 h40
  text "U29 S2" at 601,1573 h30 r90
  text "U28 THERM" at 1739.26,1551.09 h40
  text "U27 THERM" at 2651.31,1540.19 h40
  text "U30 THERM" at 3435.22,1540.19 h40
  text "U29 CLR" at 417,1452 h30
  text "U30 CLR" at 4454.6,1448.36 h30
  text "U28 CLR" at 421,1310.1 h30
  text "U27 CLR" at 4454.6,1300.13 h30
  text "U30 S0" at 3433.14,1020.85 h30 r90
  text "U29 D0" at 1166.83,850 h30
  text "U30 D0" at 3911.15,744.2 h30 r90
  text "U30 D31" at 4400,555 h30 r90
  text "U29 D2" at 1690.54,379.3 h30
  text ".Layer_Name" at 577,-858.49 h60
Bottom Overlay:
  text ".Layer_Name" at 577,-858.49 h60
Top Paste:
  text ".Layer_Name" at 577,-858.49 h60
Bottom Paste:
  text ".Layer_Name" at 577,-858.49 h60
Top Solder:
  text ".Layer_Name" at 577,-858.49 h60
  text ".Layer_Name" at 577,-858.49 h60
Bottom Solder:
  text ".Layer_Name" at 577,-858.49 h60
Drill Guide:
  text ".Layer_Name" at 577,-858.49 h60
M1 Board Outline:
  the board outline again, w20
  text ".Layer_Name" at 577,-858.49 h60
M2 Board Dimensions:
  rectangle: 0,-275 125,-150
  rectangle: 125,-400 500,-275
  lines w7: 0,-275 1000,-275 ; 125,-400 125,-150 ; 250,-400 250,-150 ; 500,-400 500,-150 ; 750,-400 750,-150 ; 0,-400 1000,-400 1000,-150 0,-150 0,-400
  text ".Layer_Name" at 577,-858.49 h60
M3 3D STEP Top:
  text ".Layer_Name" at 577,-858.49 h60
M4 3D STEP Bottom:
  text ".Layer_Name" at 577,-858.49 h60
M5 Assembly Top:
  lines w10: -292,-930.17 6308,-930.17 ; -292,-726.83 6310,-726.83 ; -292,-523.5 -292,-1133.5 3713,-1133.5 6310,-1133.5 6310,-523.5 -291.5,-523.5 -291.5,-1133.5 1284,-1133.5 ; 2173,-1133.5 2173,-523.5 ; 3440,-726.83 3440,-523.5 ; 4280,-726.83 4280,-523.5 ; 4902,-1140 4902,-937.17
  text "COMPONENTS MARKED 'DNP' SHOULD NOT BE POPULATED." at 1153.5,-318.5 h60
  text "ASSEMBLY VARIANT:" at 1153,-434 h60
  text ".VariantName" at 2189,-434 h60
  text "PCB VIEWED FROM TOP SIDE" at -228.5,-655.67 h60
  text "BOARD #:" at 2248,-655.67 h60
  text ".PRJ_Number" at 2793.5,-655.67 h60
  text "REV:" at 3638,-655.67 h60
  text ".PCB_Rev" at 3929.5,-655.67 h60
  text "SVN REV:" at 4476,-655.67 h60
  text ".VersionControl_RevNumber" at 4982,-655.67 h60
  text "TID #:" at 2248,-859 h60
  text ".TID" at 2793.5,-859 h60
  text "PLOT NAME =" at -228.5,-1064.34 h60
  text ".plot_File_Name" at 577,-1064.34 h60
  text "GENERATED    :" at 2250,-1064.34 h60
  text ".Print_Date" at 3119.5,-1064.34 h60
  text ".Print_Time" at 3848.5,-1064.34 h60
  text "TEXAS INSTRUMENTS" at 5113,-1064.34 h60
M6 Assembly Bottom:
  lines w10: -292.5,-727.33 6309.5,-727.33 ; -290.5,-930.67 6309.5,-930.67 ; 1115.5,-1140.5 1115.5,-937.67 ; 1737.5,-727.33 1737.5,-524 ; 2577.5,-727.33 2577.5,-524 ; 3844.5,-1134 3844.5,-524 ; 4733.5,-1134 6309,-1134 6309,-524 -292.5,-524 -292.5,-1134 2304.5,-1134 6309.5,-1134 6309.5,-524
  text "COMPONENTS MARKED 'DNP' SHOULD NOT BE POPULATED." at 6102,-318 h60
  text ".VariantName" at 5058,-434 h60
  text "ASSEMBLY VARIANT:" at 6097,-434 h60
  text ".VersionControl_RevNumber" at 1035.5,-656.17 h60
  text "SVN REV:" at 1541.5,-656.17 h60
  text ".PCB_Rev" at 2088,-656.17 h60
  text "REV:" at 2379.5,-656.17 h60
  text ".PRJ_Number" at 3224,-656.17 h60
  text "BOARD #:" at 3769.5,-656.17 h60
  text "PCB VIEWED FROM BOTTOM SIDE" at 6246,-656.17 h60
  text ".TID" at 3224,-859.5 h60
  text "TID #:" at 3769.5,-859.5 h60
  text "TEXAS INSTRUMENTS" at 904.5,-1064.84 h60
  text ".Print_Time" at 2169,-1064.84 h60
  text ".Print_Date" at 2898,-1064.84 h60
  text "GENERATED    :" at 3767.5,-1064.84 h60
  text ".plot_File_Name" at 5440.5,-1064.84 h60
  text "PLOT NAME =" at 6246,-1064.84 h60
M9 Title Sheet:
  drawing of 57 lines, arcs and shapes, not listed
  text "1" at 739.84,8036.5 h70
  text "2" at 3235.5,8036.5 h70
  text "3" at 5724.84,8036.5 h70
  text "4" at 8231.51,8036.5 h70
  text "5" at 10730.5,8036.5 h70
  text "6" at 13235.5,8036.5 h70
  text "A" at -416.5,6893.5 h70
  text "A" at 14383.5,6893.5 h70
  text "B" at -416.5,4513.5 h70
  text "B" at 14383.5,4513.5 h70
  text "C" at -416.5,2138.5 h70
  text "C" at 14383.5,2138.5 h70
  text "PROJECT TITLE:" at 11343.5,277.5 h45
  text ".PRJ_Title" at 11393.5,144.17 h70
  text "DESIGNED FOR:" at 11343.5,-23.5 h45
  text ".PRJ_Customer" at 11393.5,-163.5 h70
  text "D" at -416.5,-231.5 h70
  text "D" at 14383.5,-231.5 h70
  text "FILE NAME:" at 11343.5,-323.5 h45
  text ".PCB_File_Name_No_Path" at 11393.5,-443.5 h70
  text "Texas Instruments (TI) and/or its licensors do not warrant the accuracy or completeness of this specification" at 6374,-605.34 h45
  text "ENGINEER:" at 11343.5,-613.5 h45
  text "LAYOUT BY:" at 12848.5,-613.5 h45
  text "or any information contained therein. TI and/or its licensors do not warrant that this design will meet" at 6329.01,-718 h45
  text ".PRJ_Engineer" at 11393.5,-768.49 h70
  text ".PCB_Layout" at 12899,-768.49 h70
  text "the specifications, will be suitable for your application or fit for any particular purpose, or will operate in" at 6329.01,-830.67 h45
  text ".Layer_Name" at 577,-858.49 h60
  text "ALTIUM DESIGNER VERSION:" at 12848.5,-923.5 h45
  text "an implementation. TI and/or its licensors do not warrant that the design is production worthy. You should" at 6329.01,-943.33 h45
  text "completely validate and test your design implementation to confirm the system functionality for your application." at 6374,-1056 h45
  text ".print_Scale" at 11393.5,-1056.83 h70
  text ".Application_BuildNumber" at 12899,-1056.83 h70
  text "1" at 739.84,-1263.5 h70
  text "2" at 3235.5,-1263.5 h70
  text "3" at 5724.84,-1263.5 h70
  text "4" at 8231.51,-1263.5 h70
  text "5" at 10730.5,-1263.5 h70
  text "6" at 13235.5,-1263.5 h70
M10 Fab Notes:
  drawing of 189 lines, arcs and shapes, not listed
  text "DESIGN INFORMATION" at 12382.02,6356.17 h60
  text "NOTES" at 14891.55,6346.68 h100
  text "1. ALL FABRICATION ITEMS MUST MEET OR EXCEED BEST INDUSTRY PRACTICE.\"" at 14891.55,6239.83 h100
  text "MIN. TRACK WIDTH:" at 11737.46,6224.05 h60
  text "4" at 12833.7,6224.05 h60
  text "MIL" at 12988.46,6224.05 h60
  text "IPC-A-600C (Commercial Std.)\"" at 14891.55,6135.93 h100
  text "MIN. CLEARANCE:" at 11737.46,6099.92 h60
  text "0.2" at 12773.7,6099.93 h60
  text "mm" at 12988.46,6099.92 h60
  text "2. LAMINATE MATERIAL: FR-4 HIGH TG" at 14891.55,6028.23 h100
  text "MIN. VIA PAD SIZE:" at 11737.46,5975.8 h60
  text "24" at 12803.71,5975.8 h60
  text "MIL" at 12988.46,5975.8 h60
  text "3. COPPER WEIGHT: 1/2 OZ ON EXTERNAL LAYERS  AND 1 OZ ON ALL INNER LAYERS" at 14891.55,5918.73 h100
  text "0.05mm (2MIL)" at 12432.46,5845.9 h60
  text "MINIMUM ANNULAR RING" at 11408.23,5837.67 h60
  text "EXTERNAL" at 13140.46,5837.67 h60
  text "4. FINISHED BOARD THICKNESS: 100mil BEFORE PLATING +/- 10%" at 14891.55,5809.93 h100
  text "PER" at 11608.23,5727.55 h60
  text "IPC-D-275 CLASS 2 LEVEL C" at 11828.23,5727.54 h60
  text "5. MAXIMUM WARP AND TWIST TO BE .005 INCH PER INCH" at 14891.55,5697.43 h100
  text "MIL, HOLES" at 13316.46,5627.07 h60
  text "+/-" at 12924,5618.48 h60
  text "+/-" at 13778,5618.48 h60
  text "REGISTRATION TOLERANCES:" at 11408.23,5617.42 h60
  text "METAL" at 12608,5617.42 h60
  text "5" at 13184.2,5617.42 h60
  text "3" at 14017.2,5617.42 h60
  text "MIL" at 14133.46,5617.42 h60
  text "6. MINIMUM COPPER WALL THICKNESS OF PLATED-THRU HOLES TO BE .001 INCH" at 14891.55,5589.23 h100
  text "HOLE SIZE TOLERANCE (UNLESS OTHERWISE SPECIFIED):" at 11408.23,5519.1 h60
  text "+/-" at 13778,5516.23 h60
  text "3" at 14017.2,5515.17 h60
  text "MIL" at 14133.46,5515.17 h60
  text "7. MINIMUM ANNULAR RING OF PLATED-THRU HOLES TO BE .002 INCH" at 14891.55,5477.33 h100
  text "MATERIAL:" at 11333.46,5377.52 h60
  text "8. MAXIMUM ALLOWABLE LINE REDUCTION TO BE 20% OR .002 INCH WHICHEVER IS GREATEST" at 14891.55,5362.03 h100
  text "FR-4 High Tg" at 12319.9,5249 h60
  text "X" at 12175.46,5241.01 h60
  text "FR-408" at 11754.46,5236.49 h60
  text "OTHER" at 13242.46,5236.49 h60
  text "9. ALL VIA'S ARE TENTED OTHER THAN THERMAL VIAS AND ON PAD VIAS AND VIA FILLING REQUIRED /     FOR BGA AREA AND ALL ON PAD VIAS WITH  NON CONDUCTIVE ." at 14891.55,5141 h100
  text "X" at 13246,5100 h60
  text "62 MIL (1.6mm) +/-10%" at 12074.56,5093.46 h60
  text "THICKNESS:" at 11408.23,5085.24 h60
  text "OTHER" at 13359.46,5085.24 h60
  text "100 MIL (2.5mm) +/-10%" at 13635,5064 h60
  text "10.THIS IS A IMPEDANCE CONTROL BOARD" at 14891.55,5047.68 h100
  text "TOLERANCE:" at 11408.23,4946.92 h60
  text "X" at 12256.46,4946.92 h60
  text "ANSI IPC-6012 TYPE 3 CLASS 2" at 12434.48,4946.92 h60
  text "11.BOARD DIMENSIONS ARE IN MILS." at 14891.55,4929.68 h100
  text "OTHER +/-" at 12434.46,4802.73 h60
  text "BOW & TWIST:" at 11408.23,4657.54 h60
  text "X" at 12256.46,4657.54 h60
  text "ANSI IPC-6012 TYPE 3 CLASS 2" at 12434.48,4657.54 h60
  text "TRACES WITH 6 MIL IN TOP LAYER ARE TO BE 50 OHMS +/- 10% IMPEDANCE CONTROLLED" at 14891.55,4642.9 h100
  text "TRACES WITH 6 MIL IN BOTTOM LAYER ARE TO BE 50 OHMS +/- 10% IMPEDANCE CONTROLLED" at 14891.55,4527.72 h100
  text "OTHER +/-" at 12434.46,4510.85 h60
  text "TRACES WITH 5 MIL ON INNER LAYERS  IS  TO BE 50 OHMS +/- 10% IMPEDANCE CONTROLLED" at 14891.55,4412.54 h100
  text "DRILLING:" at 11333.46,4380.23 h60
  text "TRACES WITH 4.5 MIL ON INNER LAYERS  IS  TO BE 50 OHMS +/- 10% IMPEDANCE CONTROLLED" at 14891.55,4297.36 h100
  text "NC_DRILL FILES" at 13094.46,4275.04 h60
  text "REFERENCE:" at 11408.23,4271.1 h60
  text "X" at 12065.46,4271.01 h60
  text "AS SHOWN" at 12243.46,4271.1 h60
  text "X" at 12966.46,4271.1 h60
  text "TRACES WITH 6.1 WITH 9.9 SPACING MIL IN LAYERS TOP AND BOTTOM ARE TO BE 100 OHMS +/- 10% IMPEDANCE CONTROLLED" at 14891.55,4182.18 h100
  text "OTHER" at 13392.46,4128.85 h60
  text "PTH COPPER THICKNESS:" at 11407.91,4125.32 h60
  text "X" at 12547.14,4125.32 h60
  text "20-30 um" at 12675.14,4125.32 h60
  text "TRACES WITH 6.5 AND 5.5 MIL SPACING  IN TOP  LAYER  IS TO BE 90 OHMS +/- 10% IMPEDANCE CONTROLLED" at 14891.55,4067 h100
  text "BOARD FINISH:" at 11333.46,3977.73 h60
  text "SILKSCREEN:" at 11488.68,3867.6 h60
  text "X" at 12446.46,3867.6 h60
  text "TOP" at 12563.46,3867.6 h60
  text "X" at 12956.46,3867.6 h60
  text "BOTTOM" at 13074.46,3867.6 h60
  text "SILKSCREEN COLOR:" at 11488.68,3712.41 h60
  text "X" at 12445.46,3712.41 h60
  text "WHITE" at 12563.46,3712.41 h60
  text "OTHER" at 13074.46,3712.41 h60
  text "X" at 12576.46,3568.96 h60
  text "GREEN" at 12694.46,3568.96 h60
  text "OTHER" at 13312.46,3568.96 h60
  text "SOLDER RESIST COLOR:" at 11488.68,3562.1 h60
  text "X" at 12576.46,3414.71 h60
  text "MATTE" at 12694.46,3414.71 h60
  text "SEMI-GLOSS" at 13312,3414.07 h60
  text "IMMERSION GOLD (ENIG)" at 12394.46,3241.94 h60
  text "ENEPIG" at 13732,3234.72 h60
  text "SURFACE FINISH:" at 11333.46,3233.72 h60
  text "X" at 12216.46,3233.72 h60
  text "IMM. TIN/SILVER OR EQUIV" at 11663,3096.4 h60
  text "OTHER" at 13094.46,3092.47 h60
  text "ARRAY/PANEL:" at 11333.46,2937.09 h60
  text "CUT AND TRIM PER M1 BOARD OUTLINE" at 12394.46,2928.87 h60
  text "N.C. ROUTE" at 12394.46,2792.9 h60
  text "X" at 13082.46,2792.9 h60
  text "V. SCORE" at 13260.46,2792.9 h60
  text "CERTIFICATION:" at 11333.46,2663.77 h60
  text "MATERIALS AND WORKMANSHIP FOR ALL PCBS" at 12058.46,2663.77 h60
  text "TO MEET OR EXCEED THE REQUIREMENTS OF:" at 12058.46,2569.71 h60
  text "X" at 11695.97,2441.08 h60
  text "ANSI IPC-A-600F CLASS ->" at 11823.96,2441.08 h60
  text "X" at 13471.97,2441.08 h60
  text "2" at 13581.96,2441.08 h60
  text "1" at 13266.96,2439.58 h60
  text "3" at 13935.96,2439.58 h60
  text "X" at 12507.97,2293.39 h60
  text "RoHS" at 12635.96,2293.39 h60
  text "OTHER" at 13280.36,2293.39 h60
  text "PER ORDER" at 13677.42,2293.39 h60
  text "ALL BOARDS MUST MEET OR EXCEED UL94-V0 REQUIREMENTS." at 11361,2139.57 h60
  text "PCB MUST BEAR THE UL94V-0 UL REGISTERED MATERIAL ID NUMBER" at 11361,2023.5 h60
  text "ADDITIONAL REQUIREMENTS:" at 11333.46,1854.08 h60
  text "MICROSECTION:" at 11408.23,1746.95 h60
  text "YES" at 12313.96,1746.95 h60
  text "REQUIRED" at 13175.46,1602.62 h60
  text "BARE BOARD ELEC. TEST:" at 11408.23,1599.76 h60
  text "NONE" at 12713.96,1599.76 h60
  text "X" at 13057.46,1599.76 h60
  text "PER ORDER" at 13767.46,1599.76 h60
  text "XX MIL VIAS REQUIRE NON-CONDUCTIVE FILL AND PLANARIZE" at 11576.38,1394.82 h59
  text "XX MIL VIAS REQUIRE CONDUCTIVE FILL AND PLANARIZE" at 11584.38,1290.84 h60
  text "OUTER XX MIL TRACES REQUIRE 50 OHM SINGLE-ENDED IMPEDANCE" at 11583.39,1127.46 h58
  text "LAYER 2 & 3 (INNER LAYERS) XX MIL WIDE, XX MIL SPACE / TRACES REQUIRE 100 OHM DIFFERENTIAL IMPEDANCE" at 11575.39,891.74 h60
  text ".Layer_Name" at 577,-858.49 h60
M11 Gerber Information:
  lines w10: -292,-930.17 6308,-930.17 ; -292,-726.83 6310,-726.83 ; -292,-523.5 -292,-1133.5 3713,-1133.5 6310,-1133.5 6310,-523.5 -291.5,-523.5 -291.5,-1133.5 1284,-1133.5 ; 2173,-1133.5 2173,-523.5 ; 3440,-726.83 3440,-523.5 ; 4280,-726.83 4280,-523.5 ; 4902,-1140 4902,-937.17
  text "ALL ARTWORK VIEWED FROM TOP SIDE" at -228.5,-655.67 h60
  text "BOARD #:" at 2248,-655.67 h60
  text ".PRJ_Number" at 2793.5,-655.67 h60
  text "REV:" at 3638,-655.67 h60
  text ".PCB_Rev" at 3929.5,-655.67 h60
  text "SVN REV:" at 4476,-655.67 h60
  text ".VersionControl_RevNumber" at 4982,-655.67 h60
  text "LAYER NAME =" at -228.5,-858.49 h60
  text "TID #:" at 2248,-859 h60
  text ".TID" at 2793.5,-859 h60
  text "PLOT NAME =" at -228.5,-1064.34 h60
  text ".plot_File_Name" at 577,-1064.34 h60
  text "GENERATED    :" at 2250,-1064.34 h60
  text ".Print_Date" at 3119.5,-1064.34 h60
  text ".Print_Time" at 3848.5,-1064.34 h60
  text "TEXAS INSTRUMENTS" at 5113,-1064.34 h60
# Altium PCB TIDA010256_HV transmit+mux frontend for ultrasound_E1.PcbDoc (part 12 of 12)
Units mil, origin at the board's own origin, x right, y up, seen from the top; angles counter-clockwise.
Board outline 6192.49 x 6712.23 mil, 16 copper layers (Top Layer, Layer 2 - GND, Layer 3 - SIG, Layer 4 - GND, Layer 5 - SIG, Layer 6 - SIG, Layer 7 - GND, Layer 8 - HV PWR, Layer 9 - LV PWR, Layer 10 - GND, Layer 11 - SIG, Layer 12 - SIG, Layer 13 - GND, Layer 14 - SIG, Layer 15 - GND, Bottom Layer), stack 95.905 mil thick; 806 components, 539 nets, 3343 pads, 1848 vias.

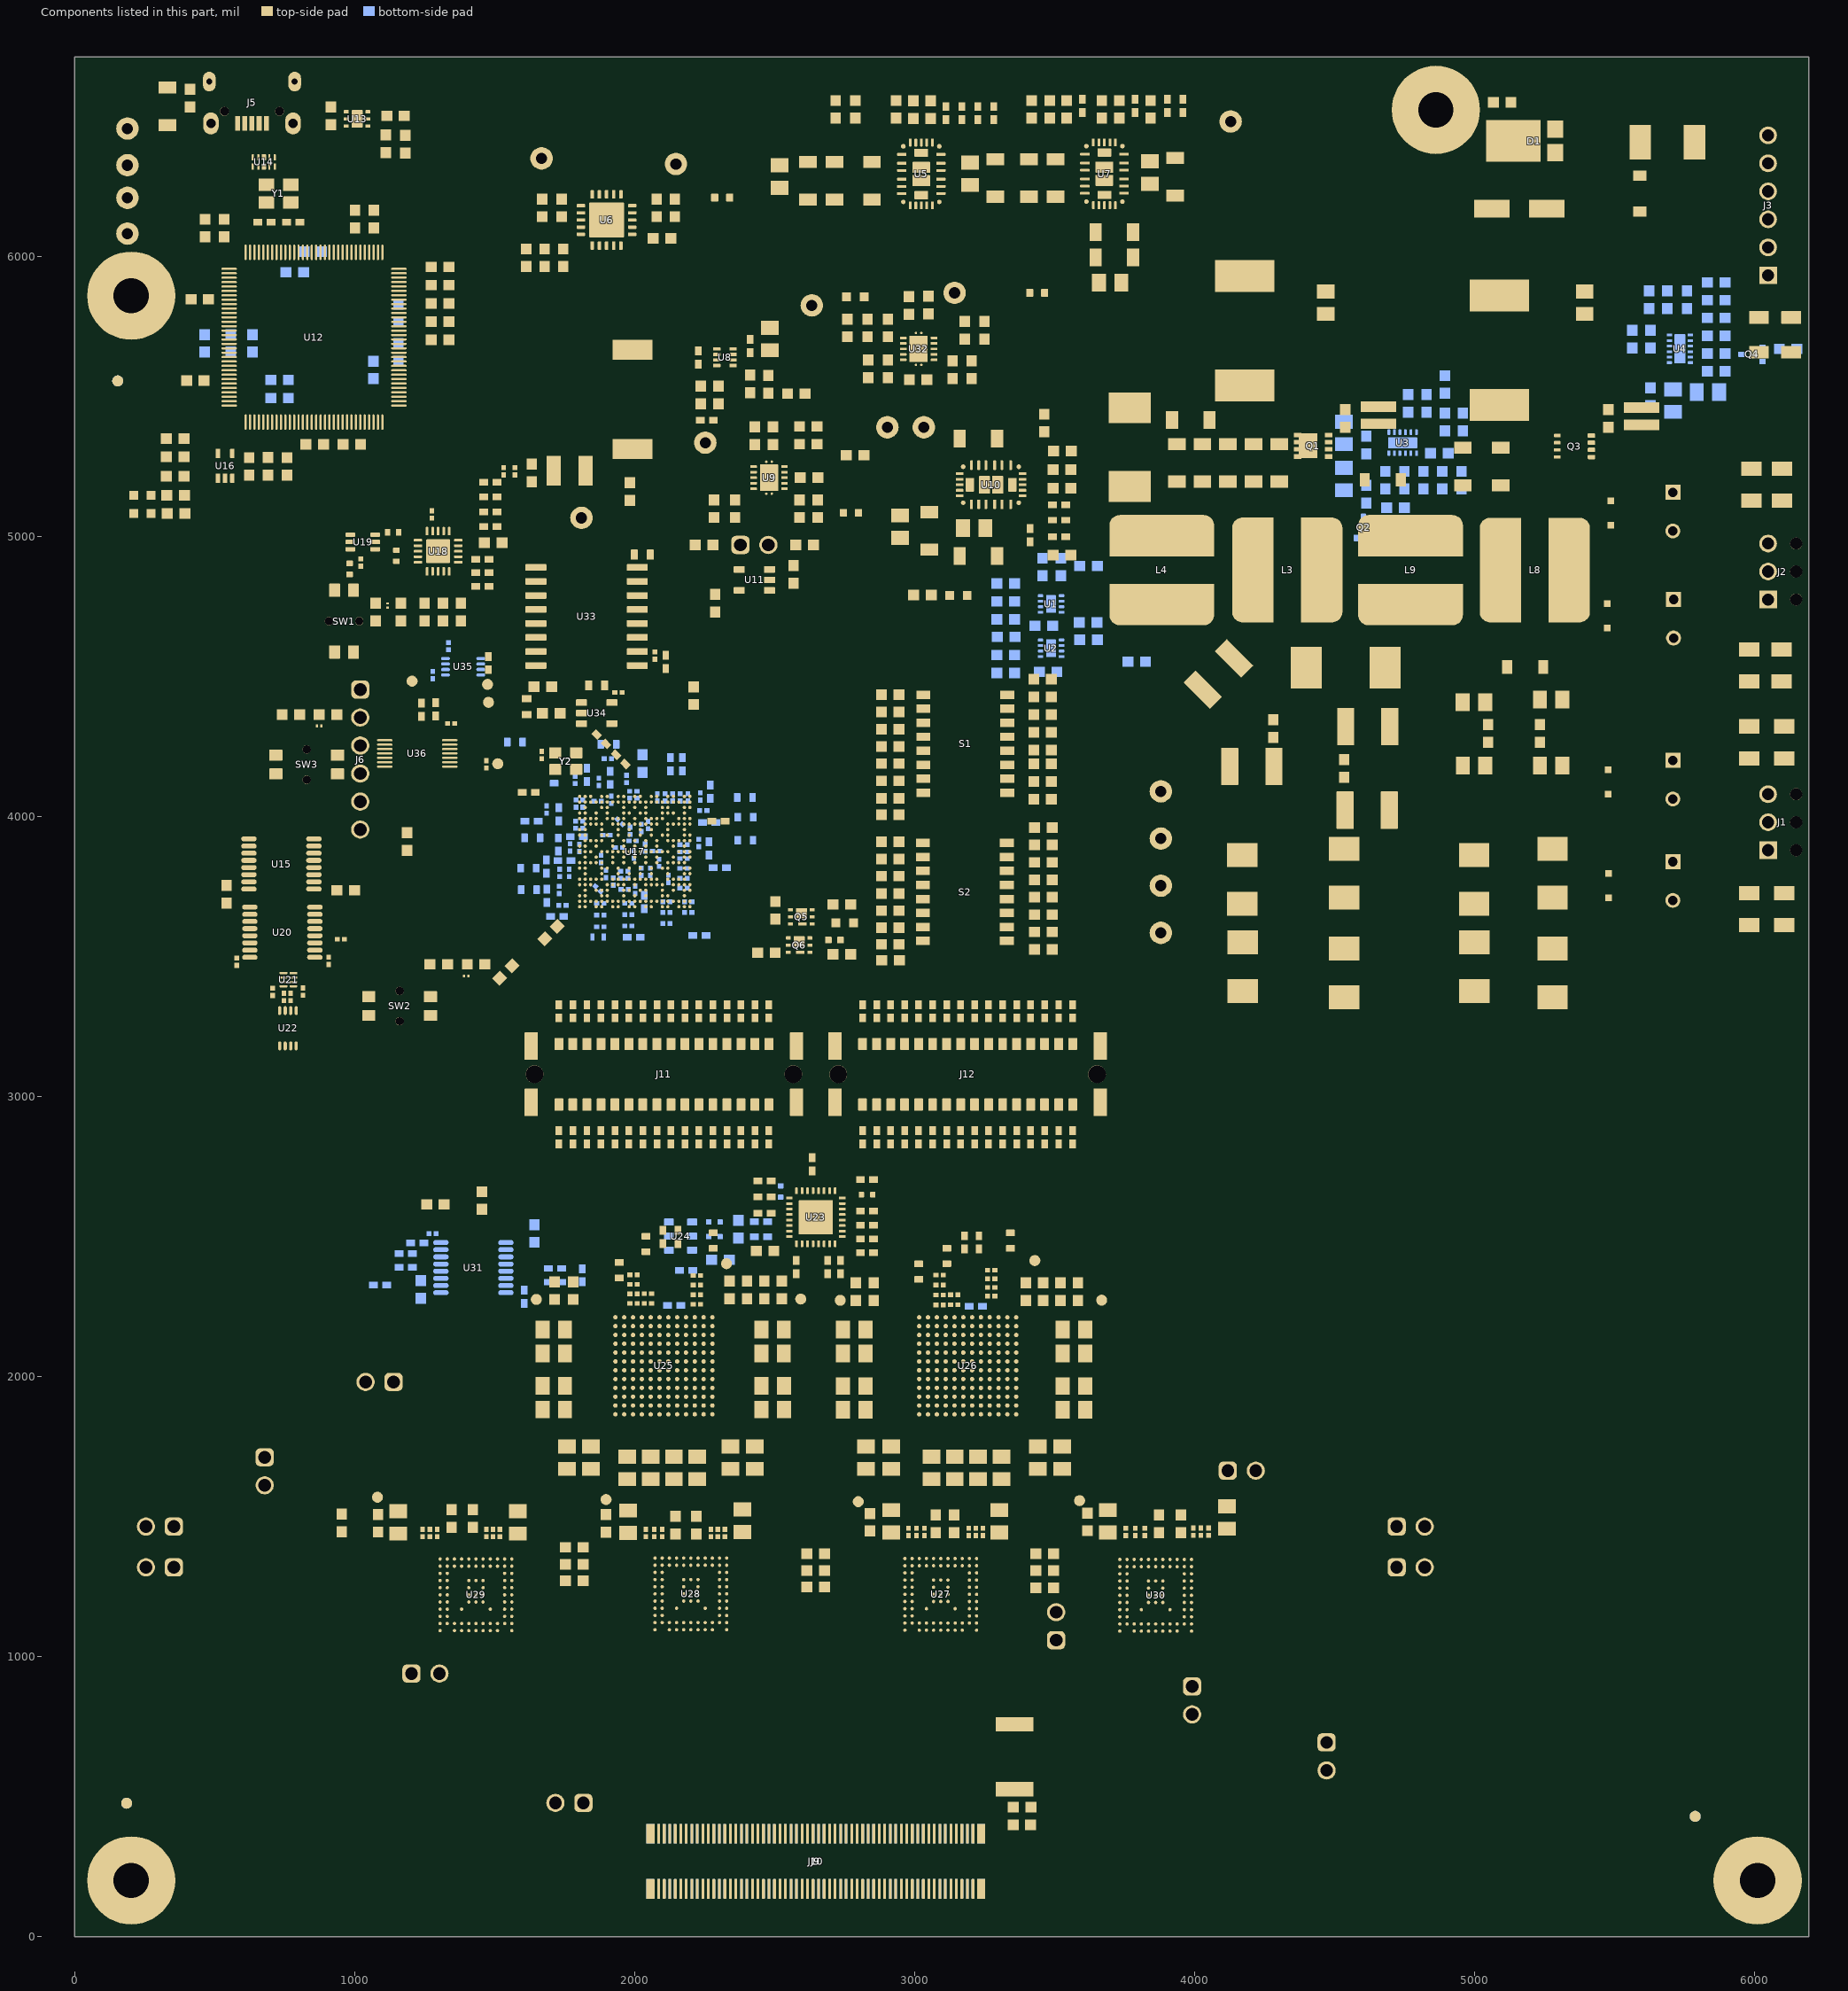
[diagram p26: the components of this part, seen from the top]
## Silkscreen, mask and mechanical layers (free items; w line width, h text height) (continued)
M12 Stackup:
  drawing of 919 lines, arcs and shapes, not listed
  text "Layer" at 6472.39,7698 h60
  text "Name" at 6882.3,7698 h60
  text "Material" at 7962,7698 h60
  text "Thickness" at 8821.77,7698 h60
  text "Constant" at 9471.6,7698 h60
  text "Board Layer Stack" at 10041.46,7698 h60
  text "Top Overlay" at 6882.3,7578 h60
  text "Top Solder" at 6882.3,7458 h60
  text "Solder Resist" at 7962,7458 h60
  text "0.40mil" at 8821.77,7458 h60
  text "3.5" at 9471.6,7458 h60
  text "1" at 6472.39,7338 h60
  text "Top Layer" at 6882.3,7338 h60
  text "1.38mil" at 8821.77,7338 h60
  text "Dielectric 1" at 6882.3,7218 h60
  text "FR-4 HIGH TG" at 7962,7218 h60
  text "3.50mil" at 8821.77,7218 h60
  text "4.1" at 9471.6,7218 h60
  text "2" at 6472.39,7098 h60
  text "Layer 2 - GND" at 6882.3,7098 h60
  text "1.18mil" at 8821.77,7098 h60
  text "Dielectric 2" at 6882.3,6978 h60
  text "FR-4 HIGH TG" at 7962,6978 h60
  text "3.94mil" at 8821.77,6978 h60
  text "4.1" at 9471.6,6978 h60
  text "3" at 6472.39,6858 h60
  text "Layer 3 - SIG" at 6882.3,6858 h60
  text "1.18mil" at 8821.77,6858 h60
  text "Dielectric 3" at 6882.3,6738 h60
  text "FR-4 HIGH TG" at 7962,6738 h60
  text "7.01mil" at 8821.77,6738 h60
  text "4.1" at 9471.6,6738 h60
  text "4" at 6472.39,6618 h60
  text "Layer 4 - GND" at 6882.3,6618 h60
  text "1.18mil" at 8821.77,6618 h60
  text "Dielectric 4" at 6882.3,6498 h60
  text "FR-4 HIGH TG" at 7962,6498 h60
  text "3.94mil" at 8821.77,6498 h60
  text "4.1" at 9471.6,6498 h60
  text "5" at 6472.39,6378 h60
  text "Layer 5 - SIG" at 6882.3,6378 h60
  text "1.18mil" at 8821.77,6378 h60
  text "Dielectric 5" at 6882.3,6258 h60
  text "FR-4 HIGH TG" at 7962,6258 h60
  text "7.01mil" at 8821.77,6258 h60
  text "4.1" at 9471.6,6258 h60
  text "6" at 6472.39,6138 h60
  text "Layer 6 - SIG" at 6882.3,6138 h60
  text "1.18mil" at 8821.77,6138 h60
  text "Dielectric 6" at 6882.3,6018 h60
  text "FR-4 HIGH TG" at 7962,6018 h60
  text "3.94mil" at 8821.77,6018 h60
  text "4.1" at 9471.6,6018 h60
  text "7" at 6472.39,5898 h60
  text "Layer 7 - GND" at 6882.3,5898 h60
  text "1.18mil" at 8821.77,5898 h60
  text "Dielectric 7" at 6882.3,5778 h60
  text "FR-4 HIGH TG" at 7962,5778 h60
  text "7.01mil" at 8821.77,5778 h60
  text "4.1" at 9471.6,5778 h60
  text "8" at 6472.39,5658 h60
  text "Layer 8 - HV PWR" at 6882.3,5658 h60
  text "1.18mil" at 8821.77,5658 h60
  text "Dielectric 8" at 6882.3,5538 h60
  text "FR-4 HIGH TG" at 7962,5538 h60
  text "3.94mil" at 8821.77,5538 h60
  text "4.1" at 9471.6,5538 h60
  text "9" at 6472.39,5418 h60
  text "Layer 9 - LV PWR" at 6882.3,5418 h60
  text "1.18mil" at 8821.77,5418 h60
  text "Dielectric 9" at 6882.3,5298 h60
  text "FR-4 HIGH TG" at 7962,5298 h60
  text "7.01mil" at 8821.77,5298 h60
  text "4.1" at 9471.6,5298 h60
  text "10" at 6472.39,5178 h60
  text "Layer 10 - GND" at 6882.3,5178 h60
  text "1.18mil" at 8821.77,5178 h60
  text "Dielectric 10" at 6882.3,5058 h60
  text "FR-4 HIGH TG" at 7962,5058 h60
  text "3.94mil" at 8821.77,5058 h60
  text "4.1" at 9471.6,5058 h60
  text "11" at 6472.39,4938 h60
  text "Layer 11 - SIG" at 6882.3,4938 h60
  text "1.18mil" at 8821.77,4938 h60
  text "Dielectric 11" at 6882.3,4818 h60
  text "FR-4 HIGH TG" at 7962,4818 h60
  text "7.01mil" at 8821.77,4818 h60
  text "4.1" at 9471.6,4818 h60
  text "12" at 6472.39,4698 h60
  text "Layer 12 - SIG" at 6882.3,4698 h60
  text "1.18mil" at 8821.77,4698 h60
  text "Dielectric 12" at 6882.3,4578 h60
  text "FR-4 HIGH TG" at 7962,4578 h60
  text "3.94mil" at 8821.77,4578 h60
  text "4.1" at 9471.6,4578 h60
  text "13" at 6472.39,4458 h60
  text "Layer 13 - GND" at 6882.3,4458 h60
  text "1.18mil" at 8821.77,4458 h60
  text "Dielectric 13" at 6882.3,4338 h60
  text "FR-4 HIGH TG" at 7962,4338 h60
  text "7.01mil" at 8821.77,4338 h60
  text "4.1" at 9471.6,4338 h60
  text "14" at 6472.39,4218 h60
  text "Layer 14 - SIG" at 6882.3,4218 h60
  text "1.18mil" at 8821.77,4218 h60
  text "Dielectric 14" at 6882.3,4098 h60
  text "FR-4 HIGH TG" at 7962,4098 h60
  text "3.94mil" at 8821.77,4098 h60
  text "4.1" at 9471.6,4098 h60
  text "15" at 6472.39,3978 h60
  text "Layer 15 - GND" at 6882.3,3978 h60
  text "1.18mil" at 8821.77,3978 h60
  text "Dielectric 15" at 6882.3,3858 h60
  text "FR-4 HIGH TG" at 7962,3858 h60
  text "3.50mil" at 8821.77,3858 h60
  text "4.1" at 9471.6,3858 h60
  text "16" at 6472.39,3738 h60
  text "Bottom Layer" at 6882.3,3738 h60
  text "1.38mil" at 8821.77,3738 h60
  text "Bottom Solder" at 6882.3,3618 h60
  text "Solder Resist" at 7962,3618 h60
  text "0.40mil" at 8821.77,3618 h60
  text "3.5" at 9471.6,3618 h60
  text "Bottom Overlay" at 6882.3,3498 h60
  text ".Layer_Name" at 577,-858.49 h60
M13 Component Bodies Top:
  text ".Layer_Name" at 577,-858.49 h60
M14 Component Bodies Bottom:
  text ".Layer_Name" at 577,-858.49 h60
M15 Courtyards Top:
  text ".Layer_Name" at 577,-858.49 h60
M16 Courtyards Bottom:
  text ".Layer_Name" at 577,-858.49 h60
Drill Drawing:
  drawing of 184 lines, arcs and shapes, not listed
  text "Symbol" at 6894.7,2737.66 h72
  text "Quantity" at 7195.27,2737.66 h72
  text "Finished Hole Size" at 7527.27,2737.66 h72
  text "Plated" at 8163.83,2737.66 h72
  text "Hole Type" at 8422.97,2737.66 h72
  text "Drill Layer Pair" at 8798.13,2737.66 h72
  text "Hole Tolerance" at 9522.46,2737.66 h72
  text "6" at 7195.27,2613.34 h60
  text "29.53mil (0.750mm)" at 7527.27,2613.34 h60
  text "NPTH" at 8163.83,2613.34 h60
  text "Round" at 8422.97,2613.34 h60
  text "Top Layer - Bottom Layer" at 8798.13,2613.34 h60
  text "2" at 7195.27,2489.02 h60
  text "31.50mil (0.800mm)" at 7527.27,2489.02 h60
  text "NPTH" at 8163.83,2489.02 h60
  text "Round" at 8422.97,2489.02 h60
  text "Top Layer - Bottom Layer" at 8798.13,2489.02 h60
  text "6" at 7195.27,2364.7 h60
  text "43.31mil (1.100mm)" at 7527.27,2364.7 h60
  text "NPTH" at 8163.83,2364.7 h60
  text "Round" at 8422.97,2364.7 h60
  text "Top Layer - Bottom Layer" at 8798.13,2364.7 h60
  text "4" at 7195.27,2240.38 h60
  text "62.99mil (1.600mm)" at 7527.27,2240.38 h60
  text "NPTH" at 8163.83,2240.38 h60
  text "Round" at 8422.97,2240.38 h60
  text "Top Layer - Bottom Layer" at 8798.13,2240.38 h60
  text "59" at 7195.27,2116.06 h60
  text "7.87mil (0.200mm)" at 7527.27,2116.06 h60
  text "PTH" at 8163.83,2116.06 h60
  text "Round" at 8422.97,2116.06 h60
  text "Top Layer - Bottom Layer" at 8798.13,2116.06 h60
  text "1510" at 7195.27,1991.74 h60
  text "8.00mil (0.203mm)" at 7527.27,1991.74 h60
  text "PTH" at 8163.83,1991.74 h60
  text "Round" at 8422.97,1991.74 h60
  text "Top Layer - Bottom Layer" at 8798.13,1991.74 h60
  text "B" at 6869.42,1981.75 h55.25
  text "129" at 7195.27,1867.42 h60
  text "10.00mil (0.254mm)" at 7527.27,1867.42 h60
  text "PTH" at 8163.83,1867.42 h60
  text "Round" at 8422.97,1867.42 h60
  text "Top Layer - Bottom Layer" at 8798.13,1867.42 h60
  text "47" at 7195.27,1743.1 h60
  text "15.00mil (0.381mm)" at 7527.27,1743.1 h60
  text "PTH" at 8163.83,1743.1 h60
  text "Round" at 8422.97,1743.1 h60
  text "Top Layer - Bottom Layer" at 8798.13,1743.1 h60
  text "A" at 6869.42,1733.11 h55.25
  text "7" at 7195.27,1618.78 h60
  text "20.00mil (0.508mm)" at 7527.27,1618.78 h60
  text "PTH" at 8163.83,1618.78 h60
  text "Round" at 8422.97,1618.78 h60
  text "Top Layer - Bottom Layer" at 8798.13,1618.78 h60
  text "96" at 7195.27,1494.46 h60
  text "30.00mil (0.762mm)" at 7527.27,1494.46 h60
  text "PTH" at 8163.83,1494.46 h60
  text "Round" at 8422.97,1494.46 h60
  text "Top Layer - Bottom Layer" at 8798.13,1494.46 h60
  text "8" at 7195.27,1370.14 h60
  text "33.47mil (0.850mm)" at 7527.27,1370.14 h60
  text "PTH" at 8163.83,1370.14 h60
  text "Round" at 8422.97,1370.14 h60
  text "Top Layer - Bottom Layer" at 8798.13,1370.14 h60
  text "17" at 7195.27,1245.82 h60
  text "40.00mil (1.016mm)" at 7527.27,1245.82 h60
  text "PTH" at 8163.83,1245.82 h60
  text "Round" at 8422.97,1245.82 h60
  text "Top Layer - Bottom Layer" at 8798.13,1245.82 h60
  text "12" at 7195.27,1121.5 h60
  text "43.31mil (1.100mm)" at 7527.27,1121.5 h60
  text "PTH" at 8163.83,1121.5 h60
  text "Round" at 8422.97,1121.5 h60
  text "Top Layer - Bottom Layer" at 8798.13,1121.5 h60
  text "32" at 7195.27,997.18 h60
  text "45.28mil (1.150mm)" at 7527.27,997.18 h60
  text "PTH" at 8163.83,997.18 h60
  text "Round" at 8422.97,997.18 h60
  text "Top Layer - Bottom Layer" at 8798.13,997.18 h60
  text "4" at 7195.27,872.86 h60
  text "125.98mil (3.200mm)" at 7527.27,872.86 h60
  text "PTH" at 8163.83,872.86 h60
  text "Round" at 8422.97,872.86 h60
  text "Top Layer - Bottom Layer" at 8798.13,872.86 h60
  text "2" at 7195.27,748.54 h60
  text "21.65mil (0.550mm)" at 7527.27,748.54 h60
  text "PTH" at 8163.83,748.54 h60
  text "Slot" at 8422.97,748.54 h60
  text "Top Layer - Bottom Layer" at 8798.13,748.54 h60
  text "2" at 7195.27,624.22 h60
  text "33.47mil (0.850mm)" at 7527.27,624.22 h60
  text "PTH" at 8163.83,624.22 h60
  text "Slot" at 8422.97,624.22 h60
  text "Top Layer - Bottom Layer" at 8798.13,624.22 h60
  text "1943 Total" at 7195.27,499.9 h60
  text "Slot definitions :" at 6894.7,412.88 h60
  text "Routed Path Length" at 7345.42,412.88 h60
  text "= Calculated from tool start centre position to tool end centre position." at 7885.16,412.88 h60
  text "Hole Length" at 7345.42,363.15 h60
  text "= Routed Path Length + Tool Size = Slot length as defined in the PCB layout" at 7685.36,363.15 h60
  text ".Layer_Name" at 577,-858.49 h60
M17 Embedded Cavity:
  text ".Layer_Name" at 577,-858.49 h60
M18 Embedded Assembly:
  text ".Layer_Name" at 577,-858.49 h60
M19 Embedded Keepout:
  text ".Layer_Name" at 577,-858.49 h60

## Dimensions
0,0 to 0,6712.23 on M2 Board Dimensions
0,0 to 6192.49,0 on M2 Board Dimensions
0,-400 to 1000,-400 on M2 Board Dimensions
